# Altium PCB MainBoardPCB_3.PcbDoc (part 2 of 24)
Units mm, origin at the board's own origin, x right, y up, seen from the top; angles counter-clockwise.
Board outline 258.95 x 308.86 mm, 16 copper layers (L1, L2 (GND), L3 (Sign), L4 (GND), L5 (Sign), L6 (PWR/GND), L7(PWR/GND), L8 (Plane_GND), L9 (PWR/GND), L10 (PWR/GND), L11 (PWR/GND), L12 (Sign), L13 (GND), L14 (Sign), L15 (GND), L16), stack 2.502 mm thick; 2402 components, 1749 nets, 8407 pads, 3409 vias.
Unrouted connection lines stored in the file: 4352.

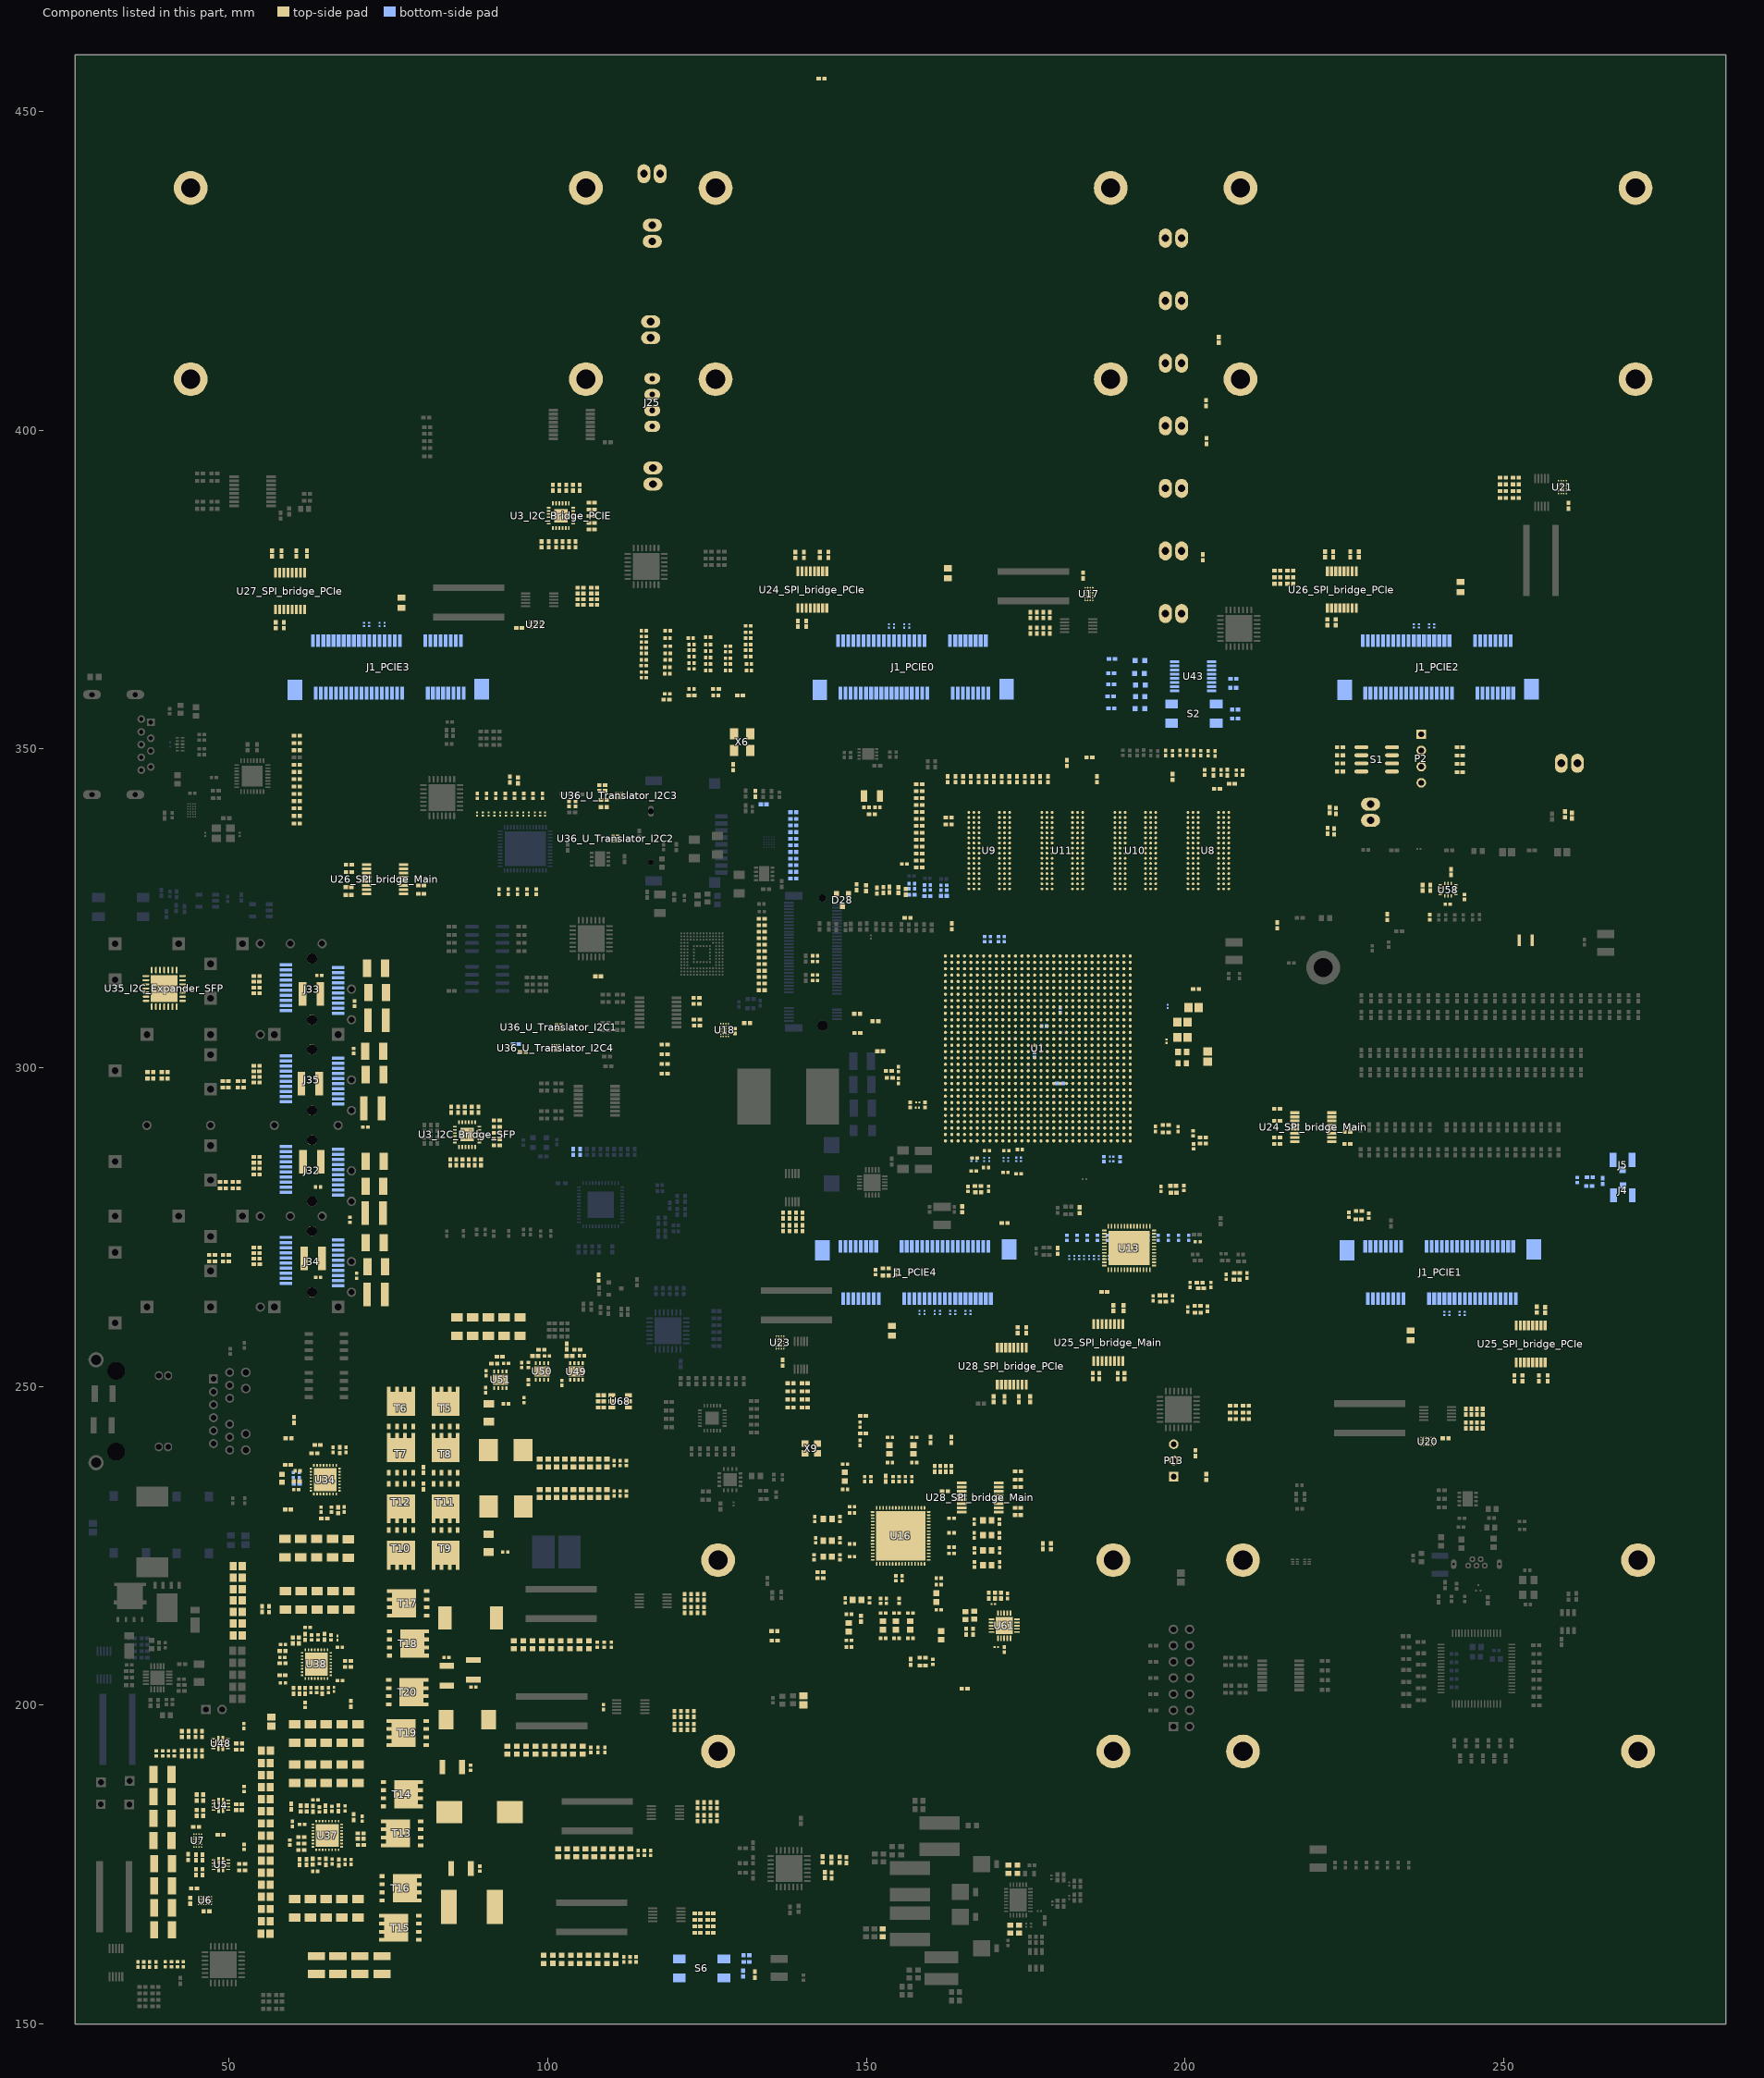
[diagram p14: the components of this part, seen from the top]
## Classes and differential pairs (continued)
net class Single_50: Bank505_MGTRREF0_C_N Bank505_MGTRREF0_C_P Bank505_MGTRREF2_C_N Bank505_MGTRREF2_C_P Bank505_MGTRREF3_C_N Bank505_MGTRREF3_C_P CLK_M_OSC_In CLK_SMA0_C_N CLK_SMA0_C_P LTC6952_0_MATCH_Out0_N LTC6952_0_MATCH_Out0_P LTC6952_0_MATCH_Out1_N LTC6952_0_MATCH_Out1_P LTC6952_0_MATCH_Out2_N LTC6952_0_MATCH_Out2_P LTC6952_0_MATCH_Out3_N LTC6952_0_MATCH_Out3_P LTC6952_0_MATCH_Out4_N LTC6952_0_MATCH_Out4_P LTC6952_0_MATCH_Out5_N LTC6952_0_MATCH_Out5_P LTC6952_0_MATCH_Out6_N LTC6952_0_MATCH_Out6_P LTC6952_0_MATCH_Out7_N LTC6952_0_MATCH_Out7_P LTC6952_0_MATCH_Out8_N LTC6952_0_MATCH_Out8_P LTC6952_0_MATCH_Out9_N LTC6952_0_MATCH_Out9_P LTC6952_0_Out0_N LTC6952_0_Out0_P LTC6952_0_Out1_N LTC6952_0_Out1_P LTC6952_0_Out2_N LTC6952_0_Out2_P LTC6952_0_Out6_N LTC6952_0_Out6_P LTC6952_0_Out7_N LTC6952_0_Out7_P LTC6952_0_Out8_N LTC6952_0_Out8_P LTC6952_0_Out9_N LTC6952_0_Out9_P LTC6952_0_Out10_N LTC6952_0_Out10_P LTC6952_0_REF_N LTC6952_0_REF_P LTC6952_1_C_N LTC6952_1_C_Out10_N LTC6952_1_C_Out10_P LTC6952_1_C_P LTC6952_1_MATCH_Out0_N LTC6952_1_MATCH_Out0_P LTC6952_1_MATCH_Out1_N LTC6952_1_MATCH_Out1_P LTC6952_1_MATCH_Out2_N LTC6952_1_MATCH_Out2_P LTC6952_1_MATCH_Out3_N LTC6952_1_MATCH_Out3_P LTC6952_1_MATCH_Out4_N LTC6952_1_MATCH_Out4_P LTC6952_1_MATCH_Out5_N LTC6952_1_MATCH_Out5_P LTC6952_1_MATCH_Out6_N LTC6952_1_MATCH_Out6_P LTC6952_1_MATCH_Out7_N LTC6952_1_MATCH_Out7_P LTC6952_1_MATCH_Out8_N LTC6952_1_MATCH_Out8_P LTC6952_1_MATCH_Out9_N LTC6952_1_MATCH_Out9_P LTC6952_1_Out0_N LTC6952_1_Out0_P LTC6952_1_Out1_N LTC6952_1_Out1_P LTC6952_1_Out2_N LTC6952_1_Out2_P LTC6952_1_Out4_N LTC6952_1_Out4_P LTC6952_1_Out5_N LTC6952_1_Out5_P LTC6952_1_Out6_N LTC6952_1_Out6_P LTC6952_1_Out7_N LTC6952_1_Out7_P LTC6952_1_Out8_N LTC6952_1_Out8_P LTC6952_1_Out9_N LTC6952_1_Out9_P LTC6952_1_Out10_N LTC6952_1_Out10_P LTC6952_1_REF_MATCH_N LTC6952_1_REF_MATCH_P LTC6952_1_VCO_N LTC6952_1_VCO_P NetC333_1 NetC334_1 NetC335_2 NetC341_1 NetC588_1 NetC588_2 NetR543_1 NVME_C_RX_1_N NVME_C_RX_1_P NVME_C_RX_O_N NVME_C_RX_O_P NVME_C_TX_1_N NVME_C_TX_1_P NVME_C_TX_O_N NVME_C_TX_O_P NVMe_Rx_0_N NVMe_Rx_0_P NVMe_Rx_1_N NVMe_Rx_1_P NVMe_Tx_0_N NVMe_Tx_0_P NVMe_Tx_1_N NVMe_Tx_1_P OSC_500Out Osc_in_Si53323_2_P OSC_Out_DIV_N OSC_Out_DIV_P RefClk_Si53323_P SGMI_C_Rx_N SGMI_C_Rx_P SGMI_C_Tx_N SGMI_C_Tx_P SGMI_CLK_Out_N SGMI_CLK_Out_P SGMI_Rx_N SGMI_Rx_P SGMI_Tx_N SGMI_Tx_P Si53323_1_Q1_N Si53323_1_Q2_LVDS_N Si53323_1_Q2_LVDS_P Si53323_1_Q2_N Si53323_1_Q2_P Si53323_2_CLK1_N Si53323_2_CLK1_P Si53323_2_Q1_N Si53323_2_Q1_P Si53323_2_Q2_LVDS_N Si53323_2_Q2_LVDS_P Si53323_2_Q2_N Si53323_2_Q2_P TD_A_N TD_A_P TD_B_N TD_B_P TD_C_N TD_C_P TD_D_N TD_D_P WR_LMK_CLK_HF1_N WR_LMK_CLK_HF1_P WR_LMK_CLK_HF2_N WR_LMK_CLK_HF2_P WR_LMK_CLK_IN_N WR_LMK_CLK_IN_P WR_LMK_CLK_RC_HF1_N WR_LMK_CLK_RC_HF1_P WR_LMK_CLK_RC_HF2_N WR_LMK_CLK_RC_HF2_P XO_LMK05028_P
net class Bank505_MGTRREFx_C: Bank505_MGTRREF0_C_N Bank505_MGTRREF0_C_P Bank505_MGTRREF2_C_N Bank505_MGTRREF2_C_P Bank505_MGTRREF3_C_N Bank505_MGTRREF3_C_P NetU2_L25 NetU2_L26
net class Bank225_MGTREFx_C: Bank225_MGTREF0_C_N Bank225_MGTREF0_C_P Bank225_MGTREF1_C_N Bank225_MGTREF1_C_P
net class Bank224_MGTREFx_C: Bank224_MGTREF0_C_N Bank224_MGTREF0_C_P Bank224_MGTREF1_C_N Bank224_MGTREF1_C_P
net class Bank223_MGTREFx_C: Bank223_MGTREF0_C_N Bank223_MGTREF0_C_P Bank223_MGTREF1_C_N Bank223_MGTREF1_C_P
component class U_Translator_I2C4: TP60_U_Translator_I2C4 TP61_U_Translator_I2C4 U36_U_Translator_I2C4
differential pair class Diff_100: B223_Rx0 B223_Rx1 B223_Rx2 B223_Rx3 B223_Tx0_to_C B223_Tx0C_to_B B223_Tx1_to_C B223_Tx1C_to_B B223_Tx2_to_C B223_Tx2C_to_B B223_Tx3_to_C B223_Tx3C_to_B B224_Rx0 B224_Rx1 B224_Rx2 B224_Rx3 B224_Tx0_to_C B224_Tx0C_to_B B224_Tx1_to_C B224_Tx1C_to_B B224_Tx2_to_C B224_Tx2C_to_B B224_Tx3_to_C B224_Tx3C_to_B B225_Rx0 B225_Rx1 B225_Rx2 B225_Rx3 B225_Tx0_to_C B225_Tx0C_to_B B225_Tx1_to_C B225_Tx1C_to_B B225_Tx2_to_C B225_Tx2C_to_B B225_Tx3_to_C B225_Tx3C_to_B Bank223_MGTREF0 Bank223_MGTREF0_C Bank223_MGTREF1 Bank223_MGTREF1_C Bank224_MGTREF0 Bank224_MGTREF0_C Bank224_MGTREF1 Bank224_MGTREF1_C Bank225_MGTREF0 Bank225_MGTREF0_C Bank225_MGTREF1 Bank225_MGTREF1_C Bank505_MGTRREF0_C Bank505_MGTRREF2_C Bank505_MGTRREF3_C CLK_100 CLK_Fanout_In CLK_GTR_T1 CLK_GTR_T2 CLK_GTR_T3 CLK_Hi_Rail1 CLK_Hi_Rail1_SysRef CLK_Hi_Rail2 CLK_Hi_Rail2_SysRef CLK_M_OSC_In CLK_NVME_Conn CLK_Q223_T1 CLK_Q224_T1 CLK_Q225_T1 CLK_Q226_T1 CLK_SMA0 CLK_SMA0_C CLK_SMA1 CLK_SMA1_C CLK_SMA2 CLK_SMA2_C Data_2_RX_PCIE0 Data_2_RX_PCIE1 Data_2_RX_PCIE2 Data_2_RX_PCIE3 Data_2_TX_PCIE0 Data_2_TX_PCIE1 Data_2_TX_PCIE2 Data_2_TX_PCIE3 Data_3_RX_PCIE0 Data_3_RX_PCIE1 Data_3_RX_PCIE2 Data_3_RX_PCIE3 Data_3_TX_PCIE0 Data_3_TX_PCIE1 Data_3_TX_PCIE2 Data_3_TX_PCIE3 LTC6952_0_MATCH_Out0 LTC6952_0_MATCH_Out1 LTC6952_0_MATCH_Out2 LTC6952_0_MATCH_Out3 LTC6952_0_MATCH_Out4 LTC6952_0_MATCH_Out5 LTC6952_0_MATCH_Out6 LTC6952_0_MATCH_Out7 LTC6952_0_MATCH_Out8 LTC6952_0_MATCH_Out9 LTC6952_0_Out0 LTC6952_0_Out1 LTC6952_0_Out2 LTC6952_0_Out3 LTC6952_0_Out4 LTC6952_0_Out5 LTC6952_0_Out6 LTC6952_0_Out7 LTC6952_0_Out8 LTC6952_0_Out9 LTC6952_0_Out10 LTC6952_0_REF LTC6952_0_REF_MATCH LTC6952_1_C LTC6952_1_C_Out10 LTC6952_1_MATCH_Out0 LTC6952_1_MATCH_Out1 LTC6952_1_MATCH_Out2 LTC6952_1_MATCH_Out3 LTC6952_1_MATCH_Out4 LTC6952_1_MATCH_Out5 LTC6952_1_MATCH_Out6 LTC6952_1_MATCH_Out7 LTC6952_1_MATCH_Out8 LTC6952_1_MATCH_Out9 LTC6952_1_Out0 LTC6952_1_Out1 LTC6952_1_Out2 LTC6952_1_Out3 LTC6952_1_Out4 LTC6952_1_Out5 LTC6952_1_Out6 LTC6952_1_Out7 LTC6952_1_Out8 LTC6952_1_Out9 LTC6952_1_Out10 LTC6952_1_REF LTC6952_1_REF_MATCH LTC6952_1_VCO LTC6952_2_REF LTC6952_2_REF_SMA LTC6952_3_REF LTC6952_3_REF_SMA NVME_C_RX_1 NVME_C_RX_O NVME_C_TX_1 NVME_C_TX_O NVMe_CLK NVMe_Rx_0 NVMe_Rx_1 NVMe_Tx_0 NVMe_Tx_1 Osc_in_Si53323_2 OSC_Out_DIV PCIE0_CLK PCIE0_Sync PCIE0_SysRef PCIE0_SysRef_FPGA PCIE1_CLK PCIE1_Sync PCIE1_SysRef PCIE1_SysRef_FPGA PCIE2_CLK PCIE2_Sync PCIE2_SysRef PCIE2_SysRef_FPGA PCIE3_CLK PCIE3_Sync PCIE3_SysRef PCIE3_SysRef_FPGA PCIE4_CLK PCIE4_Sync PCIE4_SysRef PCIE4_SysRef_FPGA RefClk_Si53323 SFP0_Rx SFP0_Tx SFP1_Rx SFP1_Tx SFP2_Rx SFP2_Tx SFP3_Rx SFP3_Tx SGMI_C_Rx SGMI_C_Tx SGMI_CLK_C_Out SGMI_CLK_Out SGMI_Rx SGMI_Tx Si53323_1_Q1 Si53323_1_Q2 Si53323_1_Q2_LVDS Si53323_2_CLK1 Si53323_2_Q1 Si53323_2_Q2 Si53323_2_Q2_LVDS SYNC_PCIE0 SYNC_PCIE1 SYNC_PCIE2 SYNC_PCIE3 SYNC_PCIE4 SYSREF_PCIE0 SYSREF_PCIE1 SYSREF_PCIE2 SYSREF_PCIE3 SYSREF_PCIE4 TD_A TD_B TD_C TD_D WR_LMK_CLK_HF1 WR_LMK_CLK_HF2 WR_LMK_CLK_IN WR_LMK_CLK_RC_HF1 WR_LMK_CLK_RC_HF2 WR_LMK_CLK_RC_IN WR_Source_CLK
channel class Translator_I2C: U_Translator_I2C1 U_Translator_I2C2 U_Translator_I2C3
channel class 5V_to_3V3: 5V_to_3V3_for_FTDI U_5V_to_3V32 U_5V_to_3V33
net class SFP_diff: SFP0_Rx_N SFP0_Rx_P SFP0_Tx_N SFP0_Tx_P SFP1_Rx_N SFP1_Rx_P SFP1_Tx_N SFP1_Tx_P SFP2_Rx_N SFP2_Rx_P SFP2_Tx_N SFP2_Tx_P SFP3_Rx_N SFP3_Rx_P SFP3_Tx_N SFP3_Tx_P
net class C_to_Bank225: B225_Rx0_N B225_Rx0_P B225_Rx1_N B225_Rx1_P B225_Rx2_N B225_Rx2_P B225_Rx3_N B225_Rx3_P B225_Tx0C_to_B_N B225_Tx0C_to_B_P B225_Tx1C_to_B_N B225_Tx1C_to_B_P B225_Tx2C_to_B_N B225_Tx2C_to_B_P B225_Tx3C_to_B_N B225_Tx3C_to_B_P
net class C_to_Bank224: B224_Tx0C_to_B_N B224_Tx0C_to_B_P B224_Tx1C_to_B_N B224_Tx1C_to_B_P B224_Tx2C_to_B_N B224_Tx2C_to_B_P B224_Tx3C_to_B_N B224_Tx3C_to_B_P
net class C_to_Bank223: B223_Rx0_N B223_Rx0_P B223_Rx1_N B223_Rx1_P B223_Rx2_N B223_Rx2_P B223_Rx3_N B223_Rx3_P B223_Tx0C_to_B_N B223_Tx0C_to_B_P B223_Tx1C_to_B_N B223_Tx1C_to_B_P B223_Tx2C_to_B_N B223_Tx2C_to_B_P B223_Tx3C_to_B_N B223_Tx3C_to_B_P
component class U_Translator_I2C3: TP60_U_Translator_I2C3 TP61_U_Translator_I2C3 U36_U_Translator_I2C3
component class U_Translator_I2C2: TP60_U_Translator_I2C2 TP61_U_Translator_I2C2 U36_U_Translator_I2C2
component class U_Translator_I2C1: TP60_U_Translator_I2C1 TP61_U_Translator_I2C1 U36_U_Translator_I2C1
component class U_TPS7A88_5V_Dual_3: C572 C573 C574 C575 C576 C577 C578 C579 R436 R437 R438 R439 R440 R441 U61
component class U_LT3042_12V_5V_LNLDO: C580 C581 C582 C583 C584 FB34 R442 R443 R444 R445 U62
component class U_ADP1741_3: C568 C569 C570 C571 FB33 R433 R434 U60
component class U_5V_to_3V33: C563_U_5V_to_3V33 C564_U_5V_to_3V33 C565_U_5V_to_3V33 C566_U_5V_to_3V33 C567_U_5V_to_3V33 R430_U_5V_to_3V33 R431_U_5V_to_3V33 R432_U_5V_to_3V33 U59_U_5V_to_3V33
component class U_5V_to_3V32: C563_U_5V_to_3V32 C564_U_5V_to_3V32 C565_U_5V_to_3V32 C566_U_5V_to_3V32 C567_U_5V_to_3V32 R430_U_5V_to_3V32 R431_U_5V_to_3V32 R432_U_5V_to_3V32 U59_U_5V_to_3V32
component class Ram_Power: C219 C220 C221 C222 C223 C224 C225 C226 C227 C228 C229 C230 C231 C232 C233 C234 C235 C236 C237 C238 C239 C240 C241 C242 C243 C244 C245 C246 C247 C248 C249 C250 C251 C252 C253 C254 C255 C256 C257 C258 C259 C260 C261 C262 C263 C264 C265 C266 C782 C783 C784 C785 C786 C787 C788 C789 R165 R166 R167 R168 R169 R170 R171 R172
component class PS_Config: C531 C532 C533 C534 C535 C536 D5 D6 D7 D8 D9 D10 D11 D12 P2 P3 P4 P5 R346 R347 R348 R349 R350 R351 R352 R353 R354 R355 R356 R357 R358 R359 R360 R361 R367 R368 R369 R370 R371 R372 R373 R374 R375 R716 R717 R718 R719 R720 S1 S2 S3 S4 U43 U44 X5 X6
component class IMU: C561 C562 R429 R600 R601 U58
component class GTR: C525 C526 C527 C528 C529 C530 C649 C651 C653 C677 C715 C716 C717 C718 R69 R70 R126
component class "Bank 225": C291 C292 C293 C294 C295 C296 C297 C298 C299 C300 C301 C302 C819 C820 C821 C822
component class "Bank 224": C279 C280 C281 C282 C283 C284 C285 C286 C287 C288 C289 C290 C686 C687 C688 C689
component class "Bank 223": C49 C50 C267 C268 C269 C270 C271 C272 C273 C274 C275 C276 C277 C278 C477 C557
component class U_Power_Ethernet: C550 C551 C552 C553 C554 C555 C654 C655 C656 C657 R391 R392 R393 R394 R396 R397 R399 R632 R633 R634 U49 U50 U51 U68
component class U_Power_ADP1850_Dual_2: C430 C431 C432 C433 C434 C435 C436 C437 C438 C439 C440 C441 C442 C443 C444 C445 C446 C447 C448 C449 C450 C451 C452 C453 C454 C455 C456 C457 C458 C459 C460 C461 C462 C463 C464 C465 C466 C467 C468 C469 C470 C548 C549 C645 C646 C647 C648 C650 C652 L19 L20 R302 R303 R306 R307 R310 R312 R313 R314 R315 R316 R317 R318 R625 R626 R627 R628 R629 R631 R686 R687 T17 T18 T19 T20 U38
component class U_HI_Curr_ADP1850_3: C389 C390 C391 C392 C393 C394 C395 C396 C397 C398 C399 C400 C401 C402 C403 C404 C405 C406 C407 C408 C409 C410 C411 C412 C413 C414 C415 C416 C417 C418 C419 C420 C421 C422 C423 C424 C425 C426 C427 C428 C429 C637 C638 C639 C640 C641 C642 C643 C644 L11 L12 R285 R287 R288 R289 R290 R292 R293 R294 R295 R296 R297 R298 R299 R300 R619 R620 R621 R622 R623 R624 T13 T14 T15 T16 U37
component class "Zasilanie CLK": C55 C56 C57 C58 C59 C60 C61 C62 C63 C64 C65 C66 C67 C68 C69 C70 C71 C72 C73 C74 C75 C76 C77 C78 C79 C80 C81 C82 C83 C84 C85 C86 C87 C88 C89 C90 C91 C92 C93 C94 C95 C96 C97 C98 C99 C100 C101 C102 C103 C104 C105 C106 C107 C108 C109 C110 C124 C125 C126 C127 C141 C142 C143 C144 C145 C146 C147 C148 C149 C150 C151 C152 C153 C154 C155 C156 C157 C158 C159 C160 C161 C162 C163 C164 C165 C166 C167 C168 C169 C170 C171 C172 C173 C174 C175 C176 C177 C178 C179 C180 C181 C182 C183 C184 C185 C186 C187 C188 C189 C190 C191 C192 C193 C194 C195 C196 C197 C198 C199 C200 C201 C202 C203 C204 C205 C206 FB2 FB3 FB4 FB5 FB6 FB7 FB8 FB9 FB10 FB11 FB12 FB13 FB14 FB15 FB16 FB17 FB18 FB19 FB20 FB21 FB22 FB35 FB36 R738 R739 R740 R741 R742 R743 U16
component class PowerSelector: C4 C5 C6 C7 C8 C9 C10 C11 C12 C13 C14 C15 C16 C17 C18 C19 C20 C21 C22 C23 C24 C25 C26 C27 C28 C29 C30 C31 C32 C33 C34 C35 C312 C313 C314 C766 C767 C768 C769 C770 C771 C772 C773 C774 C775 C776 C777 C778 C779 C780 C781 R11 R12 R13 R15 R17 R18 R19 R20 R21 R23 R25 R26 R27 R28 R29 R30 R630 R677 R678 R679 R680 R681 R682 R683 R684 R685 R1052 R1053 U4 U5 U6 U7 U48
channel class SPI_Muxes: SPI_bridge_Main SPI_bridge_PCIe
channel class I2C_Expander: I2C_Expander4 I2C_Expander5
component class XilinxPower: B1 C627 C628 C629 C630 C631 C632 D28 FB38 FB39 FB40 FB41 FB42 J29 J30 R173 R276 R279 R282 R283 R286 R693 R694 R695 R696
component class "Xilinx Linux": J12 J13 J14 J15 J16 J17 J18 J19 J20 J21 J22 J23 J24 J25 P1 P13 R83 R84 R85 R86 R87 R88 R89 R90 R91 R92 R93 R94 R95 R96 R97 R98 R99 R101 R102 R103 R104 R105 R106 R107 R108 R109 R110 R111 R112 R115 R116 R117 R118 R119 R120 R121 R122 R123 R362 R675 R737 R768 R769 R770 R771 R772 R773 R774 R775 R776 R777 R778 R779 R780 R781 R782 R783 R784 R785 R786 R787 R788 R789 R790 R791 R792 R793 R794 R795 R796 R797 R798 R799 R800 R801 R802 R803 R804 R805 R806 R807 R808 R809 R810 R811 R812 R813 R814 R815 R816 TP21 TP22 TP23 TP24 TP25 TP26 TP27 TP28 TP29 TP30 TP31 TP32 TP33 TP34 TP35 TP36 TP37 TP38 TP39 TP40 TP41 TP42
component class "WR CLK": C588 C589 C590 C591 C592 C690 C728 C729 C730 C793 FB37 R1 R2 R127 R128 R129 R130 R131 R132 R133 R134 R139 R311 R366 R498 R499 R540 R543 R544 R545 R692 R912 R1083 R1084 R1085 R1086 R1087 R1088 S6 X9
component class U_HI_Curr_ADP1850_1: C345 C346 C347 C348 C349 C350 C351 C352 C353 C356 C357 C358 C359 C360 C361 C362 C363 C364 C365 C366 C367 C368 C369 C370 C371 C372 C373 C374 C375 C376 C377 C378 C379 C380 C381 C382 C383 C384 C385 C386 C387 C388 C633 C634 C635 C636 L9 L10 R268 R271 R272 R273 R275 R277 R278 R280 R610 R611 R612 R613 R614 R615 R616 T5 T6 T7 T8 T9 T10 T11 T12 U34
component class SPI_bridge_Main: R231_SPI_bridge_Main R232_SPI_bridge_Main R233_SPI_bridge_Main R234_SPI_bridge_Main R235_SPI_bridge_Main R236_SPI_bridge_Main R237_SPI_bridge_Main R238_SPI_bridge_Main R239_SPI_bridge_Main R240_SPI_bridge_Main R425_SPI_bridge_Main R426_SPI_bridge_Main R602_SPI_bridge_Main R603_SPI_bridge_Main R604_SPI_bridge_Main R605_SPI_bridge_Main R606_SPI_bridge_Main R887_SPI_bridge_Main R888_SPI_bridge_Main R889_SPI_bridge_Main R890_SPI_bridge_Main R891_SPI_bridge_Main R892_SPI_bridge_Main R893_SPI_bridge_Main R894_SPI_bridge_Main R895_SPI_bridge_Main R896_SPI_bridge_Main R897_SPI_bridge_Main R898_SPI_bridge_Main R899_SPI_bridge_Main TP50_SPI_bridge_Main TP51_SPI_bridge_Main TP52_SPI_bridge_Main TP53_SPI_bridge_Main TP54_SPI_bridge_Main TP55_SPI_bridge_Main TP56_SPI_bridge_Main TP57_SPI_bridge_Main TP58_SPI_bridge_Main TP59_SPI_bridge_Main U24_SPI_bridge_Main U25_SPI_bridge_Main U26_SPI_bridge_Main U27_SPI_bridge_Main U28_SPI_bridge_Main
component class SPI_bridge_PCIe: R231_SPI_bridge_PCIe R232_SPI_bridge_PCIe R233_SPI_bridge_PCIe R234_SPI_bridge_PCIe R235_SPI_bridge_PCIe R236_SPI_bridge_PCIe R237_SPI_bridge_PCIe R238_SPI_bridge_PCIe R239_SPI_bridge_PCIe R240_SPI_bridge_PCIe R425_SPI_bridge_PCIe R426_SPI_bridge_PCIe R602_SPI_bridge_PCIe R603_SPI_bridge_PCIe R604_SPI_bridge_PCIe R605_SPI_bridge_PCIe R606_SPI_bridge_PCIe R887_SPI_bridge_PCIe R888_SPI_bridge_PCIe R889_SPI_bridge_PCIe R890_SPI_bridge_PCIe R891_SPI_bridge_PCIe R892_SPI_bridge_PCIe R893_SPI_bridge_PCIe R894_SPI_bridge_PCIe R895_SPI_bridge_PCIe R896_SPI_bridge_PCIe R897_SPI_bridge_PCIe R898_SPI_bridge_PCIe R899_SPI_bridge_PCIe TP50_SPI_bridge_PCIe TP51_SPI_bridge_PCIe TP52_SPI_bridge_PCIe TP53_SPI_bridge_PCIe TP54_SPI_bridge_PCIe TP55_SPI_bridge_PCIe TP56_SPI_bridge_PCIe TP57_SPI_bridge_PCIe TP58_SPI_bridge_PCIe TP59_SPI_bridge_PCIe U24_SPI_bridge_PCIe U25_SPI_bridge_PCIe U26_SPI_bridge_PCIe U27_SPI_bridge_PCIe U28_SPI_bridge_PCIe
component class SFP3: C215 C216 C217 C218 J35 L7 L8 R155 R156 R157 R158 R161 R162 R163 R164
component class SFP2: C211 C212 C213 C214 J34 L5 L6 R145 R146 R147 R148 R151 R152 R153 R154
component class SFP1: C207 C208 C209 C210 J33 L3 L4 R135 R136 R137 R138 R141 R142 R143 R144
component class Ram: C36 R31 R32 R33 R34 R35 R36 R37 R38 R39 R40 R41 R42 R43 R44 R45 R46 R47 R48 R49 R50 R51 R52 R53 R54 R55 R56 R57 R58 R59 R60 R61 R62 R63 R64 R920 U8 U9 U10 U11
component class Power4HighSpeed: R174 R175 R176 R177 R178 R179 R180 R181 R182 R183 R184 R185 R186 R187 R188 R189 R190 R191 R192 R193 R194 R195 R196 R197 R198 R199 R200 R201 R202 R203 R204 R205 R206 R207 R208 R209 R210 R211 R213 R215 R217 R219 R221 R222 R228 U17 U20 U21 U22 U23
component class I2C_Expander_SFP: C311_I2C_Expander_SFP U35_I2C_Expander_SFP
component class Ext_GPIO_Bank1: R516 R517 R518 R519 R520 R521 R524 R525 R526 R527 R528 R529 R697 R698 R699 R700 R701 R702
component class HiCurrent: C331 C332 R14 R16 R22 R24 R266 R267 R269 R304 R388 R389 R390 R561 R562 R563 R564 R565 R566 R567 R568 R569 R570 R571 R572 R573 R574 R575 R576 R577 R578 R579 R580 R581 R582 R583 R584 R585 R586 R587 R588 R589 R590 R591 R592 S5 U18
component class PCIE4: D1_PCIE4 F1_PCIE4 J1_PCIE4 MP1_PCIE4 MP2_PCIE4 MP3_PCIE4 MP4_PCIE4
component class PCIE3: D1_PCIE3 F1_PCIE3 J1_PCIE3 MP1_PCIE3 MP2_PCIE3 MP3_PCIE3 MP4_PCIE3
component class PCIE2: D1_PCIE2 F1_PCIE2 J1_PCIE2 MP1_PCIE2 MP2_PCIE2 MP3_PCIE2 MP4_PCIE2
component class PCIE1: D1_PCIE1 F1_PCIE1 J1_PCIE1 MP1_PCIE1 MP2_PCIE1 MP3_PCIE1 MP4_PCIE1
component class PCIE0: D1_PCIE0 F1_PCIE0 J1_PCIE0 MP1_PCIE0 MP2_PCIE0 MP3_PCIE0 MP4_PCIE0
component class LTC6952_1: C51 C52 C796 C797 C798 C799 C800 C801 C802 C805 C806 C807 C808 C811 C812 C813 C814 C815 C816 C817 C818 J4 J5 J6 J7 R270 R534 R535 R536 R1077 R1080 R1089 R1090 R1091 R1092 R1093 R1094 R1097 R1098 R1100 R1101 R1103 R1104 R1105 R1106 R1107 R1108 R1109 R1110 U13
channel class PCIe: PCIE0 PCIE1 PCIE2 PCIE3 PCIE4
channel class I2C_Bridge: I2C_Bridge_PCIE I2C_Bridge_SFP
component class "Bank 226": U1
component class SFP0: C37 C38 C39 C40 J32 L1 L2 R65 R66 R67 R68 R71 R72 R73 R74
component class I2C_Bridge_SFP: C303_I2C_Bridge_SFP R3_I2C_Bridge_SFP R4_I2C_Bridge_SFP R5_I2C_Bridge_SFP R6_I2C_Bridge_SFP R7_I2C_Bridge_SFP R8_I2C_Bridge_SFP R9_I2C_Bridge_SFP R10_I2C_Bridge_SFP R223_I2C_Bridge_SFP R224_I2C_Bridge_SFP R225_I2C_Bridge_SFP R226_I2C_Bridge_SFP R227_I2C_Bridge_SFP R558_I2C_Bridge_SFP R559_I2C_Bridge_SFP R560_I2C_Bridge_SFP TP1_I2C_Bridge_SFP TP2_I2C_Bridge_SFP TP3_I2C_Bridge_SFP TP4_I2C_Bridge_SFP TP5_I2C_Bridge_SFP TP6_I2C_Bridge_SFP TP7_I2C_Bridge_SFP TP8_I2C_Bridge_SFP TP9_I2C_Bridge_SFP TP10_I2C_Bridge_SFP TP11_I2C_Bridge_SFP TP12_I2C_Bridge_SFP TP13_I2C_Bridge_SFP TP14_I2C_Bridge_SFP TP15_I2C_Bridge_SFP TP16_I2C_Bridge_SFP TP17_I2C_Bridge_SFP TP18_I2C_Bridge_SFP U3_I2C_Bridge_SFP
component class I2C_Bridge_PCIE: C303_I2C_Bridge_PCIE R3_I2C_Bridge_PCIE R4_I2C_Bridge_PCIE R5_I2C_Bridge_PCIE R6_I2C_Bridge_PCIE R7_I2C_Bridge_PCIE R8_I2C_Bridge_PCIE R9_I2C_Bridge_PCIE R10_I2C_Bridge_PCIE R223_I2C_Bridge_PCIE R224_I2C_Bridge_PCIE R225_I2C_Bridge_PCIE R226_I2C_Bridge_PCIE R227_I2C_Bridge_PCIE R558_I2C_Bridge_PCIE R559_I2C_Bridge_PCIE R560_I2C_Bridge_PCIE TP1_I2C_Bridge_PCIE TP2_I2C_Bridge_PCIE TP3_I2C_Bridge_PCIE TP4_I2C_Bridge_PCIE TP5_I2C_Bridge_PCIE TP6_I2C_Bridge_PCIE TP7_I2C_Bridge_PCIE TP8_I2C_Bridge_PCIE TP9_I2C_Bridge_PCIE TP10_I2C_Bridge_PCIE TP11_I2C_Bridge_PCIE TP12_I2C_Bridge_PCIE TP13_I2C_Bridge_PCIE TP14_I2C_Bridge_PCIE TP15_I2C_Bridge_PCIE TP16_I2C_Bridge_PCIE TP17_I2C_Bridge_PCIE TP18_I2C_Bridge_PCIE U3_I2C_Bridge_PCIE
differential pair WR_LMK_CLK_RC_HF2: +WR_LMK_CLK_RC_HF2_P -WR_LMK_CLK_RC_HF2_N
differential pair Bank223_MGTREF0: +Bank223_MGTREF0_P -Bank223_MGTREF0_N
differential pair WR_LMK_CLK_RC_HF1: +WR_LMK_CLK_RC_HF1_P -WR_LMK_CLK_RC_HF1_N
differential pair LTC6952_1_MATCH_Out6: +LTC6952_1_MATCH_Out6_P -LTC6952_1_MATCH_Out6_N
differential pair SGMI_CLK_Out: +SGMI_CLK_Out_P -SGMI_CLK_Out_N
differential pair LTC6952_1_REF_MATCH: +LTC6952_1_REF_MATCH_P -LTC6952_1_REF_MATCH_N
differential pair LTC6952_1_MATCH_Out9: +LTC6952_1_MATCH_Out9_P -LTC6952_1_MATCH_Out9_N
differential pair LTC6952_1_MATCH_Out8: +LTC6952_1_MATCH_Out8_P -LTC6952_1_MATCH_Out8_N
differential pair LTC6952_1_MATCH_Out7: +LTC6952_1_MATCH_Out7_P -LTC6952_1_MATCH_Out7_N
differential pair LTC6952_1_MATCH_Out5: +LTC6952_1_MATCH_Out5_P -LTC6952_1_MATCH_Out5_N
differential pair LTC6952_1_MATCH_Out4: +LTC6952_1_MATCH_Out4_P -LTC6952_1_MATCH_Out4_N
differential pair LTC6952_1_MATCH_Out3: +LTC6952_1_MATCH_Out3_P -LTC6952_1_MATCH_Out3_N
differential pair LTC6952_1_MATCH_Out2: +LTC6952_1_MATCH_Out2_P -LTC6952_1_MATCH_Out2_N
differential pair LTC6952_1_MATCH_Out1: +LTC6952_1_MATCH_Out1_P -LTC6952_1_MATCH_Out1_N
differential pair LTC6952_1_MATCH_Out0: +LTC6952_1_MATCH_Out0_P -LTC6952_1_MATCH_Out0_N
differential pair LTC6952_0_MATCH_Out9: +LTC6952_0_MATCH_Out9_P -LTC6952_0_MATCH_Out9_N
differential pair LTC6952_0_MATCH_Out8: +LTC6952_0_MATCH_Out8_P -LTC6952_0_MATCH_Out8_N
differential pair LTC6952_0_MATCH_Out7: +LTC6952_0_MATCH_Out7_P -LTC6952_0_MATCH_Out7_N
differential pair LTC6952_0_MATCH_Out6: +LTC6952_0_MATCH_Out6_P -LTC6952_0_MATCH_Out6_N
differential pair LTC6952_0_MATCH_Out5: +LTC6952_0_MATCH_Out5_P -LTC6952_0_MATCH_Out5_N
differential pair LTC6952_0_MATCH_Out4: +LTC6952_0_MATCH_Out4_P -LTC6952_0_MATCH_Out4_N
differential pair LTC6952_0_MATCH_Out3: +LTC6952_0_MATCH_Out3_P -LTC6952_0_MATCH_Out3_N
differential pair LTC6952_0_MATCH_Out2: +LTC6952_0_MATCH_Out2_P -LTC6952_0_MATCH_Out2_N
differential pair LTC6952_0_MATCH_Out1: +LTC6952_0_MATCH_Out1_P -LTC6952_0_MATCH_Out1_N
differential pair LTC6952_0_MATCH_Out0: +LTC6952_0_MATCH_Out0_P -LTC6952_0_MATCH_Out0_N
differential pair Bank225_MGTREF1: +Bank225_MGTREF1_P -Bank225_MGTREF1_N
differential pair Bank225_MGTREF0: +Bank225_MGTREF0_P -Bank225_MGTREF0_N
differential pair Bank224_MGTREF1: +Bank224_MGTREF1_P -Bank224_MGTREF1_N
differential pair Bank224_MGTREF0: +Bank224_MGTREF0_P -Bank224_MGTREF0_N
differential pair Bank223_MGTREF1: +Bank223_MGTREF1_P -Bank223_MGTREF1_N
differential pair B225_Tx3_to_C: +B225_Tx3_to_C_P -B225_Tx3_to_C_N
differential pair B225_Tx2_to_C: +B225_Tx2_to_C_P -B225_Tx2_to_C_N
differential pair B225_Tx1_to_C: +B225_Tx1_to_C_P -B225_Tx1_to_C_N
differential pair B225_Tx0_to_C: +B225_Tx0_to_C_P -B225_Tx0_to_C_N
differential pair B225_Rx3: +B225_Rx3_P -B225_Rx3_N
differential pair B225_Rx2: +B225_Rx2_P -B225_Rx2_N
differential pair B225_Rx1: +B225_Rx1_P -B225_Rx1_N
differential pair B225_Rx0: +B225_Rx0_P -B225_Rx0_N
differential pair B224_Tx3_to_C: +B224_Tx3_to_C_P -B224_Tx3_to_C_N
differential pair B224_Tx2_to_C: +B224_Tx2_to_C_P -B224_Tx2_to_C_N
differential pair B224_Tx1_to_C: +B224_Tx1_to_C_P -B224_Tx1_to_C_N
differential pair B224_Tx0_to_C: +B224_Tx0_to_C_P -B224_Tx0_to_C_N
differential pair B224_Rx3: +B224_Rx3_P -B224_Rx3_N
differential pair B224_Rx2: +B224_Rx2_P -B224_Rx2_N
differential pair B224_Rx1: +B224_Rx1_P -B224_Rx1_N
differential pair B224_Rx0: +B224_Rx0_P -B224_Rx0_N
differential pair B223_Tx3_to_C: +B223_Tx3_to_C_P -B223_Tx3_to_C_N
differential pair B223_Tx2_to_C: +B223_Tx2_to_C_P -B223_Tx2_to_C_N
differential pair B223_Tx1_to_C: +B223_Tx1_to_C_P -B223_Tx1_to_C_N
differential pair B223_Tx0_to_C: +B223_Tx0_to_C_P -B223_Tx0_to_C_N
differential pair B223_Rx3: +B223_Rx3_P -B223_Rx3_N
differential pair B223_Rx2: +B223_Rx2_P -B223_Rx2_N
differential pair B223_Rx1: +B223_Rx1_P -B223_Rx1_N
differential pair B223_Rx0: +B223_Rx0_P -B223_Rx0_N
differential pair NVME_C_RX_1: +NVME_C_RX_1_P -NVME_C_RX_1_N
differential pair LTC6952_1_VCO: +LTC6952_1_VCO_P -LTC6952_1_VCO_N
differential pair LTC6952_1_Out10: +LTC6952_1_Out10_P -LTC6952_1_Out10_N
differential pair LTC6952_1_Out9: +LTC6952_1_Out9_P -LTC6952_1_Out9_N
differential pair LTC6952_1_Out8: +LTC6952_1_Out8_P -LTC6952_1_Out8_N
differential pair LTC6952_1_Out7: +LTC6952_1_Out7_P -LTC6952_1_Out7_N
differential pair LTC6952_1_Out6: +LTC6952_1_Out6_P -LTC6952_1_Out6_N
differential pair LTC6952_1_Out5: +LTC6952_1_Out5_P -LTC6952_1_Out5_N
differential pair LTC6952_1_Out4: +LTC6952_1_Out4_P -LTC6952_1_Out4_N
differential pair LTC6952_1_Out2: +LTC6952_1_Out2_P -LTC6952_1_Out2_N
differential pair LTC6952_1_Out1: +LTC6952_1_Out1_P -LTC6952_1_Out1_N
differential pair LTC6952_1_Out0: +LTC6952_1_Out0_P -LTC6952_1_Out0_N
differential pair LTC6952_1_C: +LTC6952_1_C_P -LTC6952_1_C_N
differential pair LTC6952_1_C_Out10: +LTC6952_1_C_Out10_P -LTC6952_1_C_Out10_N
differential pair LTC6952_0_REF: +LTC6952_0_REF_P -LTC6952_0_REF_N
differential pair LTC6952_0_Out10: +LTC6952_0_Out10_P -LTC6952_0_Out10_N
differential pair LTC6952_0_Out9: +LTC6952_0_Out9_P -LTC6952_0_Out9_N
differential pair LTC6952_0_Out8: +LTC6952_0_Out8_P -LTC6952_0_Out8_N
differential pair LTC6952_0_Out7: +LTC6952_0_Out7_P -LTC6952_0_Out7_N
differential pair LTC6952_0_Out6: +LTC6952_0_Out6_P -LTC6952_0_Out6_N
differential pair LTC6952_0_Out2: +LTC6952_0_Out2_P -LTC6952_0_Out2_N
differential pair LTC6952_0_Out1: +LTC6952_0_Out1_P -LTC6952_0_Out1_N
differential pair LTC6952_0_Out0: +LTC6952_0_Out0_P -LTC6952_0_Out0_N
differential pair USB_TX: +USB_TX_P -USB_TX_N
differential pair USB_TX_C: +USB_TX_C_P -USB_TX_C_N
differential pair USB_RX: +USB_RX_P -USB_RX_N
differential pair USB_RX_C: +USB_RX_C_P -USB_RX_C_N
differential pair USB_D: +USB_D_P -USB_D_N
differential pair TD_D: +TD_D_P -TD_D_N
differential pair TD_C: +TD_C_P -TD_C_N
differential pair TD_B: +TD_B_P -TD_B_N
differential pair TD_A: +TD_A_P -TD_A_N
differential pair SGMI_Tx: +SGMI_Tx_P -SGMI_Tx_N
differential pair SGMI_Rx: +SGMI_Rx_P -SGMI_Rx_N
differential pair SGMI_C_Tx: +SGMI_C_Tx_P -SGMI_C_Tx_N
differential pair SGMI_C_Rx: +SGMI_C_Rx_P -SGMI_C_Rx_N
differential pair NVMe_Tx_1: +NVMe_Tx_1_P -NVMe_Tx_1_N
differential pair NVMe_Tx_0: +NVMe_Tx_0_P -NVMe_Tx_0_N
differential pair NVMe_Rx_1: +NVMe_Rx_1_P -NVMe_Rx_1_N
differential pair NVMe_Rx_0: +NVMe_Rx_0_P -NVMe_Rx_0_N
differential pair DDR4_DQS_8: +DDR4_DQS_8_P -DDR4_DQS_8_N
differential pair DDR4_DQS_4: +DDR4_DQS_4_P -DDR4_DQS_4_N
differential pair NVME_C_TX_O: +NVME_C_TX_O_P -NVME_C_TX_O_N
differential pair NVME_C_TX_1: +NVME_C_TX_1_P -NVME_C_TX_1_N
differential pair NVME_C_RX_O: +NVME_C_RX_O_P -NVME_C_RX_O_N
differential pair WR_LMK_CLK_IN: +WR_LMK_CLK_IN_P -WR_LMK_CLK_IN_N
differential pair WR_LMK_CLK_HF2: +WR_LMK_CLK_HF2_P -WR_LMK_CLK_HF2_N
differential pair WR_LMK_CLK_HF1: +WR_LMK_CLK_HF1_P -WR_LMK_CLK_HF1_N
differential pair Si53323_2_Q2_LVDS: +Si53323_2_Q2_LVDS_P -Si53323_2_Q2_LVDS_N
differential pair Si53323_1_Q2_LVDS: +Si53323_1_Q2_LVDS_P -Si53323_1_Q2_LVDS_N
differential pair Si53323_2_CLK1: +Si53323_2_CLK1_P -Si53323_2_CLK1_N
differential pair OSC_Out_DIV: +OSC_Out_DIV_P -OSC_Out_DIV_N
differential pair Osc_in_Si53323_2: +Osc_in_Si53323_2_P -Osc_in_Si53323_2_N
differential pair CLK_SMA0_C: +CLK_SMA0_C_P -CLK_SMA0_C_N
differential pair DDR4_DQS_7: +DDR4_DQS_7_P -DDR4_DQS_7_N
differential pair DDR4_DQS_6: +DDR4_DQS_6_P -DDR4_DQS_6_N
differential pair DDR4_DQS_5: +DDR4_DQS_5_P -DDR4_DQS_5_N
differential pair DDR4_DQS_3: +DDR4_DQS_3_P -DDR4_DQS_3_N
differential pair DDR4_DQS_2: +DDR4_DQS_2_P -DDR4_DQS_2_N
differential pair DDR4_DQS_1: +DDR4_DQS_1_P -DDR4_DQS_1_N
differential pair DDR4_DQS_0: +DDR4_DQS_0_P -DDR4_DQS_0_N
differential pair DDR4_CK: +DDR4_CK_P -DDR4_CK_N
differential pair Si53323_2_Q2: +Si53323_2_Q2_P -Si53323_2_Q2_N
differential pair Si53323_2_Q1: +Si53323_2_Q1_P -Si53323_2_Q1_N
differential pair Si53323_1_Q2: +Si53323_1_Q2_P -Si53323_1_Q2_N
differential pair Si53323_1_Q1: +Si53323_1_Q1_P -Si53323_1_Q1_N
differential pair RefClk_Si53323: +RefClk_Si53323_P -RefClk_Si53323_N
differential pair Bank505_MGTRREF3_C: +Bank505_MGTRREF3_C_P -Bank505_MGTRREF3_C_N
differential pair Bank505_MGTRREF2_C: +Bank505_MGTRREF2_C_P -Bank505_MGTRREF2_C_N
differential pair Bank505_MGTRREF0_C: +Bank505_MGTRREF0_C_P -Bank505_MGTRREF0_C_N
differential pair Bank225_MGTREF1_C: +Bank225_MGTREF1_C_P -Bank225_MGTREF1_C_N
differential pair Bank225_MGTREF0_C: +Bank225_MGTREF0_C_P -Bank225_MGTREF0_C_N
differential pair Bank224_MGTREF1_C: +Bank224_MGTREF1_C_P -Bank224_MGTREF1_C_N
differential pair Bank224_MGTREF0_C: +Bank224_MGTREF0_C_P -Bank224_MGTREF0_C_N
differential pair Bank223_MGTREF1_C: +Bank223_MGTREF1_C_P -Bank223_MGTREF1_C_N
differential pair Bank223_MGTREF0_C: +Bank223_MGTREF0_C_P -Bank223_MGTREF0_C_N
differential pair SFP3_Tx: +SFP3_Tx_P -SFP3_Tx_N
differential pair SFP3_Rx: +SFP3_Rx_P -SFP3_Rx_N
differential pair SFP2_Tx: +SFP2_Tx_P -SFP2_Tx_N
differential pair SFP2_Rx: +SFP2_Rx_P -SFP2_Rx_N
differential pair SFP1_Tx: +SFP1_Tx_P -SFP1_Tx_N
differential pair SFP1_Rx: +SFP1_Rx_P -SFP1_Rx_N
differential pair SFP0_Tx: +SFP0_Tx_P -SFP0_Tx_N
differential pair SFP0_Rx: +SFP0_Rx_P -SFP0_Rx_N
differential pair B225_Tx3C_to_B: +B225_Tx3C_to_B_P -B225_Tx3C_to_B_N
differential pair B225_Tx2C_to_B: +B225_Tx2C_to_B_P -B225_Tx2C_to_B_N
differential pair B225_Tx1C_to_B: +B225_Tx1C_to_B_P -B225_Tx1C_to_B_N
differential pair B225_Tx0C_to_B: +B225_Tx0C_to_B_P -B225_Tx0C_to_B_N
differential pair B224_Tx3C_to_B: +B224_Tx3C_to_B_P -B224_Tx3C_to_B_N
differential pair B224_Tx2C_to_B: +B224_Tx2C_to_B_P -B224_Tx2C_to_B_N
differential pair B224_Tx1C_to_B: +B224_Tx1C_to_B_P -B224_Tx1C_to_B_N
differential pair B224_Tx0C_to_B: +B224_Tx0C_to_B_P -B224_Tx0C_to_B_N
differential pair B223_Tx3C_to_B: +B223_Tx3C_to_B_P -B223_Tx3C_to_B_N
differential pair B223_Tx2C_to_B: +B223_Tx2C_to_B_P -B223_Tx2C_to_B_N
differential pair B223_Tx1C_to_B: +B223_Tx1C_to_B_P -B223_Tx1C_to_B_N
differential pair B223_Tx0C_to_B: +B223_Tx0C_to_B_P -B223_Tx0C_to_B_N

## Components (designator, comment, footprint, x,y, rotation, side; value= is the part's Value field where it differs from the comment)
B1 "TS920E-FL27E" Battery 253.457,320.027 r0 top
BT1 "79523141" 79523141 178.727,122.707 r0 top
C1 "100nF" "CAP 0402/1005 RF" 95.898,253.357 r90 top
C2 "100nF" "CAP 0402/1005 RF" 238.392,323.631 r90 top
C3 "100nF" "CAP 0402/1005 RF" 108.763,199.72 r270 top
C4 "22uF" "CAP 1210/3225 - 1MM" 39.648,164.772 r180 top
C5 "22uF" "CAP 1210/3225 - 1MM" 39.648,168.226 r180 top
C6 "22uF" "CAP 1210/3225 - 1MM" 39.648,175.135 r180 top
C7 "22uF" "CAP 1210/3225 - 1MM" 39.648,171.68 r180 top
C8 "100nF" "CAP 0402/1005 RF" 39.985,159.376 r270 top
C9 "100nF" "CAP 0402/1005 RF" 42.83,159.376 r270 top
C10 "100nF" "CAP 0402/1005 RF" 41.901,159.376 r270 top
C11 "100nF" "CAP 0402/1005 RF" 40.965,159.376 r270 top
C12 "22uF" "CAP 1210/3225 - 1MM" 39.567,178.794 r180 top
C13 "22uF" "CAP 1210/3225 - 1MM" 39.567,185.684 r180 top
C14 "22uF" "CAP 1210/3225 - 1MM" 39.567,189.129 r180 top
C15 "22uF" "CAP 1210/3225 - 1MM" 39.567,182.239 r180 top
C16 "100nF" "CAP 0402/1005 RF" 41.415,192.449 r90 top
C17 "100nF" "CAP 0402/1005 RF" 38.581,192.45 r90 top
C18 "100nF" "CAP 0402/1005 RF" 39.58,192.45 r90 top
C19 "100nF" "CAP 0402/1005 RF" 40.485,192.45 r90 top
C20 "10uF" "CAP 0805/2012 RF" 55.719,164.138 r180 top
C21 "10uF" "CAP 0805/2012 RF" 55.746,169.941 r180 top
C22 "10uF" "CAP 0805/2012 RF" 55.746,168.043 r180 top
C23 "10uF" "CAP 0805/2012 RF" 55.746,175.635 r180 top
C24 "4.7uF" "CAP 0805/2012 RF" 55.746,171.839 r180 top
C25 "4.7uF" "CAP 0805/2012 RF" 55.746,173.737 r180 top
C26 "4.7uF" "CAP 0805/2012 RF" 55.746,177.532 r180 top
C27 "4.7uF" "CAP 0805/2012 RF" 55.746,166.145 r180 top
C28 "10uF" "CAP 0805/2012 RF" 55.758,187.161 r180 top
C29 "10uF" "CAP 0805/2012 RF" 55.758,185.263 r180 top
C30 "10uF" "CAP 0805/2012 RF" 55.758,181.467 r180 top
C31 "10uF" "CAP 0805/2012 RF" 55.758,179.569 r180 top
C32 "4.7uF" "CAP 0805/2012 RF" 55.758,183.365 r180 top
C33 "4.7uF" "CAP 0805/2012 RF" 55.758,189.059 r180 top
C34 "4.7uF" "CAP 0805/2012 RF" 55.758,190.956 r180 top
C35 "4.7uF" "CAP 0805/2012 RF" 55.784,192.899 r180 top
C36 "10nF" "CAP 0402/1005 RF" 155.956,331.965 r180 top
C37 "100nF" "CAP 0402/1005 RF" 63.955,281.318 r0 top
C38 "22uF" "CAP 1210/3225 - 1MM" 72.834,285.318 r0 top
C39 "100nF" "CAP 0402/1005 RF" 68.948,276.161 r90 top
C40 "22uF" "CAP 1210/3225 - 1MM" 72.796,281.422 r0 top
C43 "1uF" "CAP 0402/1005 RF" 103.337,341.393 r90 top
C44 "1uF" "CAP 0402/1005 RF" 104.344,341.386 r90 top
C45 "5.6nF" "CAP 0402/1005 RF" 61.486,539.447 r270 top
C46 "200pF" "CAP 0402/1005 RF" 60.586,539.447 r270 top
C47 "1uF" "CAP 0402/1005 RF" 75.151,493.181 r0 top
C48 "1uF" "CAP 0402/1005 RF" 73.471,493.181 r180 top
C49 "100nF" "CAP 0402/1005 RF" 187.274,285.674 r90 bottom
C50 "100nF" "CAP 0402/1005 RF" 189.814,285.648 r90 bottom
C51 "1uF" "CAP 0402/1005 RF" 74.536,481.457 r270 top
C52 "1uF" "CAP 0402/1005 RF" 73.508,481.47 r90 top
C53 "100nF" "CAP 0402/1005 RF" 54.072,515.607 r0 top
C54 "100nF" "CAP 0402/1005 RF" 201.987,272.694 r0 top
C55 "0.1µF" "CAP 0201/0603 RF" 91.986,580.271 r90 top
C56 "0.1µF" "CAP 0201/0603 RF" 90.081,580.271 r90 top
C57 "0.1µF" "CAP 0201/0603 RF" 88.938,578.62 r270 top
C58 "10µF" "CAP 0402/1005 RF" 90.081,578.626 r270 top
C59 "0.1µF" "CAP 0201/0603 RF" 74.571,559.501 r90 top
C60 "0.1µF" "CAP 0201/0603 RF" 73.682,559.501 r90 top
C61 "0.1µF" "CAP 0201/0603 RF" 70.241,562.818 r90 top
C62 "10µF" "CAP 0402/1005 RF" 68.968,562.688 r90 top
C63 "100nF" "CAP 0402/1005 RF" 152.232,216.378 r270 top
C64 "100nF" "CAP 0402/1005 RF" 161.359,219.934 r0 top
C65 "0.1µF" "CAP 0201/0603 RF" 92.875,580.277 r90 top
C66 "0.1µF" "CAP 0201/0603 RF" 89.192,580.277 r90 top
C67 "100nF" "CAP 0402/1005 RF" 155.622,219.934 r270 top
C68 "10nF" "CAP 0201/0603 RF" 93.383,578.626 r270 top
C69 "10µF" "CAP 0402/1005 RF" 91.986,578.626 r270 top
C70 "100nF" "CAP 0402/1005 RF" 153.122,216.378 r270 top
C71 "0.1µF" "CAP 0201/0603 RF" 70.634,559.513 r0 top
C72 "0.1µF" "CAP 0201/0603 RF" 70.501,560.402 r0 top
C73 "0.1µF" "CAP 0201/0603 RF" 69.228,559.513 r180 top
C74 "10µF" "CAP 0402/1005 RF" 69.618,558.116 r180 top
C75 "100nF" "CAP 0402/1005 RF" 163.373,224.818 r0 top
C76 "100nF" "CAP 0402/1005 RF" 163.373,227.046 r0 top
C77 "100nF" "CAP 0402/1005 RF" 147.752,225.318 r180 top
C78 "10uF" "CAP 0402/1005 RF" 154.622,219.934 r90 top
C79 "10uF" "CAP 0402/1005 RF" 156.122,235.477 r270 top
C80 "10uF" "CAP 0402/1005 RF" 149.717,235.477 r270 top
C81 "100nF" "CAP 0402/1005 RF" 147.752,223.318 r180 top
C82 "100nF" "CAP 0402/1005 RF" 163.373,229.318 r0 top
C83 "100nF" "CAP 0402/1005 RF" 147.752,230.165 r180 top
C84 "0.1µF" "CAP 0201/0603 RF" 68.221,554.814 r90 top
C85 "0.1µF" "CAP 0201/0603 RF" 75.333,559.501 r90 top
C86 "10nF" "CAP 0201/0603 RF" 69.237,554.82 r90 top
C87 "10µF" "CAP 0402/1005 RF" 70.38,554.82 r90 top
C88 "100nF" "CAP 0402/1005 RF" 147.752,231.165 r180 top
C89 "100nF" "CAP 0402/1005 RF" 157.122,235.477 r90 top
C90 "100nF" "CAP 0402/1005 RF" 154.182,235.477 r90 top
C91 "100nF" "CAP 0402/1005 RF" 155.122,235.477 r90 top
C92 "100nF" "CAP 0402/1005 RF" 163.373,223.818 r0 top
C93 "100nF" "CAP 0402/1005 RF" 155.118,216.378 r270 top
C94 "0.1µF" "CAP 0201/0603 RF" 76.095,559.507 r90 top
C95 "0.1µF" "CAP 0201/0603 RF" 72.793,559.507 r90 top
C96 "100nF" "CAP 0402/1005 RF" 150.717,235.477 r90 top
C97 "10nF" "CAP 0201/0603 RF" 71.396,561.663 r90 top
C98 "10µF" "CAP 0402/1005 RF" 72.285,561.663 r90 top
C99 "100nF" "CAP 0402/1005 RF" 146.669,216.447 r90 top
C100 "100nF" "CAP 0402/1005 RF" 170.866,228.801 r90 top
C101 "10uF" "CAP 0402/1005 RF" 150.479,216.456 r90 top
C102 "10uF" "CAP 0402/1005 RF" 166.92,228.801 r90 top
C103 "100nF" "CAP 0402/1005 RF" 161.359,214.983 r180 top
C104 "100nF" "CAP 0402/1005 RF" 141.901,229.208 r90 top
C105 "10uF" "CAP 0402/1005 RF" 161.359,218.929 r180 top
C106 "10uF" "CAP 0402/1005 RF" 145.847,229.208 r90 top
C107 "100nF" "CAP 0402/1005 RF" 156.901,210.527 r180 top
C108 "100nF" "CAP 0402/1005 RF" 146.66,237.81 r0 top
C109 "10uF" "CAP 0402/1005 RF" 156.901,214.473 r180 top
C110 "10uF" "CAP 0402/1005 RF" 146.66,233.864 r0 top
C124 "100nF" "CAP 0402/1005 RF" 152.622,210.527 r180 top
C125 "100nF" "CAP 0402/1005 RF" 157.512,242.032 r180 top
C126 "10uF" "CAP 0402/1005 RF" 152.622,214.473 r180 top
C127 "10uF" "CAP 0402/1005 RF" 157.512,238.086 r180 top
C141 "100nF" "CAP 0402/1005 RF" 170.906,224.281 r270 top
C142 "100nF" "CAP 0402/1005 RF" 153.692,242.032 r0 top
C143 "10uF" "CAP 0402/1005 RF" 166.96,224.281 r270 top
C144 "10uF" "CAP 0402/1005 RF" 153.692,238.086 r0 top
C145 "100nF" "CAP 0402/1005 RF" 170.866,226.656 r90 top
C146 "100nF" "CAP 0402/1005 RF" 170.906,222.084 r270 top
C147 "10uF" "CAP 0402/1005 RF" 166.92,226.656 r90 top
C148 "10uF" "CAP 0402/1005 RF" 166.96,222.084 r270 top
C149 "10nF" "CAP 0201/0603 RF" 92.532,339.814 r90 top
C150 "10nF" "CAP 0201/0603 RF" 96.15,339.814 r90 top
C151 "10nF" "CAP 0201/0603 RF" 91.627,339.814 r90 top
C152 "10nF" "CAP 0201/0603 RF" 94.341,339.814 r90 top
C153 "10nF" "CAP 0201/0603 RF" 89.818,339.814 r90 top
C154 "10nF" "CAP 0201/0603 RF" 95.245,339.814 r90 top
C155 "10nF" "CAP 0201/0603 RF" 90.722,339.814 r90 top
C156 "10nF" "CAP 0201/0603 RF" 93.436,339.814 r90 top
C157 "10nF" "CAP 0201/0603 RF" 88.913,339.814 r90 top
C158 "10nF" "CAP 0201/0603 RF" 98.801,339.826 r90 top
C159 "10nF" "CAP 0201/0603 RF" 97.959,339.814 r90 top
C160 "10nF" "CAP 0201/0603 RF" 99.563,339.826 r90 top
C161 "10nF" "CAP 0201/0603 RF" 97.055,339.814 r90 top
C162 "100nF" "CAP 0402/1005 RF" 142.037,225.876 r270 top
C163 "100nF" "CAP 0402/1005 RF" 154.728,210.527 r180 top
C164 "10uF" "CAP 0402/1005 RF" 145.847,225.876 r90 top
C165 "10uF" "CAP 0402/1005 RF" 154.728,214.473 r180 top
C166 "10nF" "CAP 0201/0603 RF" 181.84,270.266 r90 bottom
C167 "10nF" "CAP 0201/0603 RF" 185.703,270.266 r90 bottom
C168 "10nF" "CAP 0201/0603 RF" 189.565,270.266 r90 bottom
C169 "10nF" "CAP 0201/0603 RF" 182.612,270.266 r90 bottom
C170 "10nF" "CAP 0201/0603 RF" 186.475,270.266 r90 bottom
C171 "10nF" "CAP 0201/0603 RF" 183.385,270.266 r90 bottom
C172 "10nF" "CAP 0201/0603 RF" 187.248,270.266 r90 bottom
C173 "10nF" "CAP 0201/0603 RF" 191.111,270.266 r90 bottom
C174 "10nF" "CAP 0201/0603 RF" 184.93,270.266 r90 bottom
C175 "10nF" "CAP 0201/0603 RF" 188.02,270.266 r90 bottom
C176 "10nF" "CAP 0201/0603 RF" 190.338,270.266 r90 bottom
C177 "10nF" "CAP 0201/0603 RF" 184.157,270.266 r90 bottom
C178 "10nF" "CAP 0201/0603 RF" 188.793,270.266 r90 bottom
C179 "100nF" "CAP 0402/1005 RF" 141.801,223.227 r90 top
C180 "10uF" "CAP 0402/1005 RF" 145.847,223.227 r90 top
C181 "1uF" "CAP 0402/1005 RF" 98.194,327.615 r90 top
C182 "1uF" "CAP 0402/1005 RF" 88.938,342.652 r90 top
C183 "1uF" "CAP 0402/1005 RF" 97.701,342.652 r90 top
C184 "1uF" "CAP 0402/1005 RF" 90.399,342.652 r90 top
C185 "1uF" "CAP 0402/1005 RF" 99.162,342.652 r90 top
C186 "1uF" "CAP 0402/1005 RF" 96.241,342.652 r90 top
C187 "1uF" "CAP 0402/1005 RF" 96.733,327.615 r90 top
C188 "1uF" "CAP 0402/1005 RF" 91.859,342.652 r90 top
C189 "1uF" "CAP 0402/1005 RF" 92.352,327.615 r90 top
C190 "1uF" "CAP 0402/1005 RF" 94.78,342.652 r90 top
C191 "1uF" "CAP 0402/1005 RF" 95.273,327.615 r90 top
C192 "1uF" "CAP 0402/1005 RF" 93.32,342.652 r90 top
C193 "1uF" "CAP 0402/1005 RF" 93.812,327.615 r90 top
C194 "1uF" "CAP 0402/1005 RF" 189.432,273.326 r90 bottom
C195 "1uF" "CAP 0402/1005 RF" 198.986,273.326 r90 bottom
C196 "1uF" "CAP 0402/1005 RF" 195.802,273.326 r90 bottom
C197 "1uF" "CAP 0402/1005 RF" 187.84,273.326 r90 bottom
C198 "1uF" "CAP 0402/1005 RF" 200.579,273.326 r90 bottom
C199 "1uF" "CAP 0402/1005 RF" 194.209,273.326 r90 bottom
C200 "1uF" "CAP 0402/1005 RF" 192.617,273.326 r90 bottom
C201 "1uF" "CAP 0402/1005 RF" 197.394,273.326 r90 bottom
C202 "1uF" "CAP 0402/1005 RF" 191.025,273.326 r90 bottom
C203 "1uF" "CAP 0402/1005 RF" 181.471,273.326 r90 bottom
C204 "1uF" "CAP 0402/1005 RF" 184.655,273.326 r90 bottom
C205 "1uF" "CAP 0402/1005 RF" 183.063,273.326 r90 bottom
C206 "1uF" "CAP 0402/1005 RF" 186.248,273.326 r90 bottom
C207 "100nF" "CAP 0402/1005 RF" 64.16,314.503 r0 top
C208 "22uF" "CAP 1210/3225 - 1MM" 73.063,315.608 r0 top
C209 "100nF" "CAP 0402/1005 RF" 69.679,310.07 r270 top
C210 "22uF" "CAP 1210/3225 - 1MM" 73.254,311.802 r0 top
C211 "100nF" "CAP 0402/1005 RF" 63.983,267.144 r0 top
C212 "22uF" "CAP 1210/3225 - 1MM" 72.863,272.58 r0 top
C213 "100nF" "CAP 0402/1005 RF" 70.015,267.386 r90 top
C214 "22uF" "CAP 1210/3225 - 1MM" 73.101,268.821 r0 top
C215 "100nF" "CAP 0402/1005 RF" 69.532,302.645 r270 top
C216 "22uF" "CAP 1210/3225 - 1MM" 72.771,302.577 r0 top
C217 "100nF" "CAP 0402/1005 RF" 71.387,290.69 r180 top
C218 "22uF" "CAP 1210/3225 - 1MM" 72.822,298.931 r0 top
C219 "100nF" "CAP 0402/1005 RF" 205.639,346.325 r90 top
C220 "100nF" "CAP 0402/1005 RF" 209.035,346.309 r90 top
C221 "100nF" "CAP 0402/1005 RF" 203.083,346.325 r90 top
C222 "100nF" "CAP 0402/1005 RF" 208.036,346.309 r90 top
C223 "4.7uF" "CAP 0402/1005 RF" 118.82,368.554 r0 top
C224 "470nF" "CAP 0402/1005 RF" 122.568,366.395 r0 top
C225 "470nF" "CAP 0402/1005 RF" 115.084,362.077 r0 top
C226 "68nF" "CAP 0402/1005 RF" 125.166,367.538 r0 top
C227 "68nF" "CAP 0402/1005 RF" 115.075,363.982 r0 top
C228 "4.7uF" "CAP 0402/1005 RF" 122.441,367.411 r0 top
C229 "470nF" "CAP 0402/1005 RF" 125.157,366.395 r0 top
C230 "470nF" "CAP 0402/1005 RF" 115.066,363.093 r0 top
C231 "68nF" "CAP 0402/1005 RF" 115.075,368.554 r0 top
C232 "68nF" "CAP 0402/1005 RF" 118.82,366.141 r0 top
C233 "4.7uF" "CAP 0402/1005 RF" 125.166,364.363 r0 top
C234 "470nF" "CAP 0402/1005 RF" 115.075,367.665 r0 top
C235 "470nF" "CAP 0402/1005 RF" 118.82,364.998 r0 top
C236 "68nF" "CAP 0402/1005 RF" 118.811,367.411 r0 top
C237 "68nF" "CAP 0402/1005 RF" 122.559,365.506 r0 top
C238 "4.7uF" "CAP 0402/1005 RF" 125.157,363.347 r0 top
C239 "470nF" "CAP 0402/1005 RF" 115.075,366.776 r0 top
C240 "470nF" "CAP 0402/1005 RF" 118.82,363.982 r0 top
C241 "68nF" "CAP 0402/1005 RF" 122.568,362.585 r0 top
C242 "68nF" "CAP 0402/1005 RF" 122.568,363.474 r0 top
C243 "100nF" "CAP 0402/1005 RF" 122.568,359.418 r0 top
C244 "100nF" "CAP 0402/1005 RF" 125.175,365.379 r180 top
C245 "100nF" "CAP 0402/1005 RF" 118.758,358.656 r0 top
C246 "100nF" "CAP 0402/1005 RF" 122.568,364.49 r180 top
C247 "4.7uF" "CAP 0402/1005 RF" 115.084,361.188 r0 top
C248 "470nF" "CAP 0402/1005 RF" 126.378,358.402 r0 top
C249 "470nF" "CAP 0402/1005 RF" 125.166,362.331 r0 top
C250 "68nF" "CAP 0402/1005 RF" 115.084,365.887 r0 top
C251 "68nF" "CAP 0402/1005 RF" 118.749,362.839 r0 top
C252 "4.7uF" "CAP 0402/1005 RF" 128.274,363.347 r0 top
C253 "470nF" "CAP 0402/1005 RF" 128.274,365.252 r0 top
C254 "470nF" "CAP 0402/1005 RF" 128.283,366.141 r0 top
C255 "68nF" "CAP 0402/1005 RF" 115.075,364.998 r0 top
C256 "68nF" "CAP 0402/1005 RF" 118.758,361.823 r0 top
C257 "4.7uF" "CAP 0402/1005 RF" 128.274,364.236 r0 top
C258 "470nF" "CAP 0402/1005 RF" 131.449,365.506 r0 top
C259 "470nF" "CAP 0402/1005 RF" 131.576,363.347 r0 top
C260 "68nF" "CAP 0402/1005 RF" 131.449,367.411 r0 top
C261 "68nF" "CAP 0402/1005 RF" 131.449,369.316 r0 top
C262 "4.7uF" "CAP 0402/1005 RF" 131.449,364.49 r0 top
C263 "470nF" "CAP 0402/1005 RF" 131.576,362.331 r0 top
C264 "470nF" "CAP 0402/1005 RF" 131.449,366.395 r0 top
C265 "68nF" "CAP 0402/1005 RF" 131.449,368.3 r0 top
C266 "68nF" "CAP 0402/1005 RF" 128.274,362.331 r0 top
C267 "100nF" "CAP 0201/0603 RF" 156.737,369.297 r90 bottom
C268 "100nF" "CAP 0201/0603 RF" 155.937,369.297 r90 bottom
C269 "100nF" "CAP 0201/0603 RF" 154.337,369.297 r90 bottom
C270 "100nF" "CAP 0201/0603 RF" 153.537,369.297 r90 bottom
C271 "100nF" "CAP 0201/0603 RF" 240.69,261.449 r270 bottom
C272 "100nF" "CAP 0201/0603 RF" 241.49,261.449 r270 bottom
C273 "10nF" "CAP 0201/0603 RF" 188.493,286.066 r0 bottom
C274 "100nF" "CAP 0201/0603 RF" 243.09,261.449 r270 bottom
C275 "100nF" "CAP 0201/0603 RF" 243.89,261.449 r270 bottom
C276 "10nF" "CAP 0201/0603 RF" 188.493,285.318 r0 bottom
C277 "10nF" "CAP 0201/0603 RF" 173.533,285.655 r270 bottom
C278 "10nF" "CAP 0201/0603 RF" 174.231,285.655 r270 bottom
C279 "100nF" "CAP 0201/0603 RF" 239.09,369.335 r90 bottom
C280 "100nF" "CAP 0201/0603 RF" 238.29,369.335 r90 bottom
C281 "100nF" "CAP 0201/0603 RF" 236.69,369.335 r90 bottom
C282 "100nF" "CAP 0201/0603 RF" 235.89,369.335 r90 bottom
C283 "100nF" "CAP 0201/0603 RF" 74.385,369.563 r90 bottom
C284 "100nF" "CAP 0201/0603 RF" 73.585,369.563 r90 bottom
C285 "10nF" "CAP 0201/0603 RF" 171.526,285.612 r270 bottom
C286 "100nF" "CAP 0201/0603 RF" 71.985,369.563 r90 bottom
C287 "100nF" "CAP 0201/0603 RF" 71.185,369.563 r90 bottom
C288 "10nF" "CAP 0201/0603 RF" 172.263,285.626 r270 bottom
C289 "10nF" "CAP 0201/0603 RF" 168.491,285.63 r270 bottom
C290 "10nF" "CAP 0201/0603 RF" 169.278,285.63 r270 bottom
C291 "100nF" "CAP 0201/0603 RF" 158.337,261.601 r270 bottom
C292 "100nF" "CAP 0201/0603 RF" 159.137,261.601 r270 bottom
C293 "100nF" "CAP 0201/0603 RF" 160.737,261.601 r270 bottom
C294 "100nF" "CAP 0201/0603 RF" 161.537,261.601 r270 bottom
C295 "100nF" "CAP 0201/0603 RF" 163.137,261.601 r270 bottom
C296 "100nF" "CAP 0201/0603 RF" 163.937,261.601 r270 bottom
C297 "10nF" "CAP 0201/0603 RF" 166.472,285.63 r270 bottom
C298 "100nF" "CAP 0201/0603 RF" 165.537,261.601 r270 bottom
C299 "100nF" "CAP 0201/0603 RF" 166.337,261.601 r270 bottom
C300 "10nF" "CAP 0201/0603 RF" 167.297,285.63 r270 bottom
C301 "10nF" "CAP 0201/0603 RF" 157.981,293.738 r0 top
C302 "10nF" "CAP 0201/0603 RF" 158.075,294.576 r0 top
C303_I2C_Bridge_GPIO "100nF" "CAP 0402/1005 RF" 604.952,286.398 r90 top (schematic designator C303)
C303_I2C_Bridge_PCIE "100nF" "CAP 0402/1005 RF" 363.017,71.514 r90 top (schematic designator C303)
C303_I2C_Bridge_SFP "100nF" "CAP 0402/1005 RF" 360.832,81.026 r90 top (schematic designator C303)
C304 "4.7µF" "CAP 0603/1608 RF" 172.578,164.915 r270 top
C305 "4.7µF" "CAP 0603/1608 RF" 173.703,174.283 r90 top
C306 "4.7µF" "CAP 0603/1608 RF" 173.953,164.914 r270 top
C307 "4.7µF" "CAP 0603/1608 RF" 172.278,174.282 r90 top
C308 "4.7 µF" "CAP 0603/1608 RF" 152.563,164.29 r270 top
C309_U_Pomiar_pradu_napiecia_1 "100nF" "CAP 0402/1005 RF" 360.832,136.677 r90 top (schematic designator C309)
C309_U_Pomiar_pradu_napiecia_2 "100nF" "CAP 0402/1005 RF" 359.74,144.301 r90 top (schematic designator C309)
C309_U_Pomiar_pradu_napiecia_3 "100nF" "CAP 0402/1005 RF" 360.832,149.631 r90 top (schematic designator C309)
C309_U_Pomiar_pradu_napiecia_4 "100nF" "CAP 0402/1005 RF" 362.14,149.441 r90 top (schematic designator C309)
C309_U_Pomiar_pradu_napiecia_5 "100nF" "CAP 0402/1005 RF" 353.047,170.824 r90 top (schematic designator C309)
C309_U_Pomiar_pradu_napiecia_6 "100nF" "CAP 0402/1005 RF" 349.072,150 r270 top (schematic designator C309)
C309_U_Pomiar_pradu_napiecia_PCIe0 "100nF" "CAP 0402/1005 RF" 362.306,177.245 r90 top (schematic designator C309)
C309_U_Pomiar_pradu_napiecia_PCIe1 "100nF" "CAP 0402/1005 RF" 360.832,182.016 r90 top (schematic designator C309)
C309_U_Pomiar_pradu_napiecia_PCIe2 "100nF" "CAP 0402/1005 RF" 361.887,181.94 r90 top (schematic designator C309)
C309_U_Pomiar_pradu_napiecia_PCIe3 "100nF" "CAP 0402/1005 RF" 363.101,196.189 r90 top (schematic designator C309)
C309_U_Pomiar_pradu_napiecia_PCIe4 "100nF" "CAP 0402/1005 RF" 362.915,202.053 r90 top (schematic designator C309)
C310 "100nF" "CAP 0402/1005 RF" 360.832,47.447 r90 top
C311_I2C_Expander_00 "1uF" "CAP 0402/1005 RF" 360.832,91.338 r90 top (schematic designator C311)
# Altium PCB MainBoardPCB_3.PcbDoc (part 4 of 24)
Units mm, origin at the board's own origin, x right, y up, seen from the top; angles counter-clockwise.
Board outline 258.95 x 308.86 mm, 16 copper layers (L1, L2 (GND), L3 (Sign), L4 (GND), L5 (Sign), L6 (PWR/GND), L7(PWR/GND), L8 (Plane_GND), L9 (PWR/GND), L10 (PWR/GND), L11 (PWR/GND), L12 (Sign), L13 (GND), L14 (Sign), L15 (GND), L16), stack 2.502 mm thick; 2402 components, 1749 nets, 8407 pads, 3409 vias.
Unrouted connection lines stored in the file: 4352.

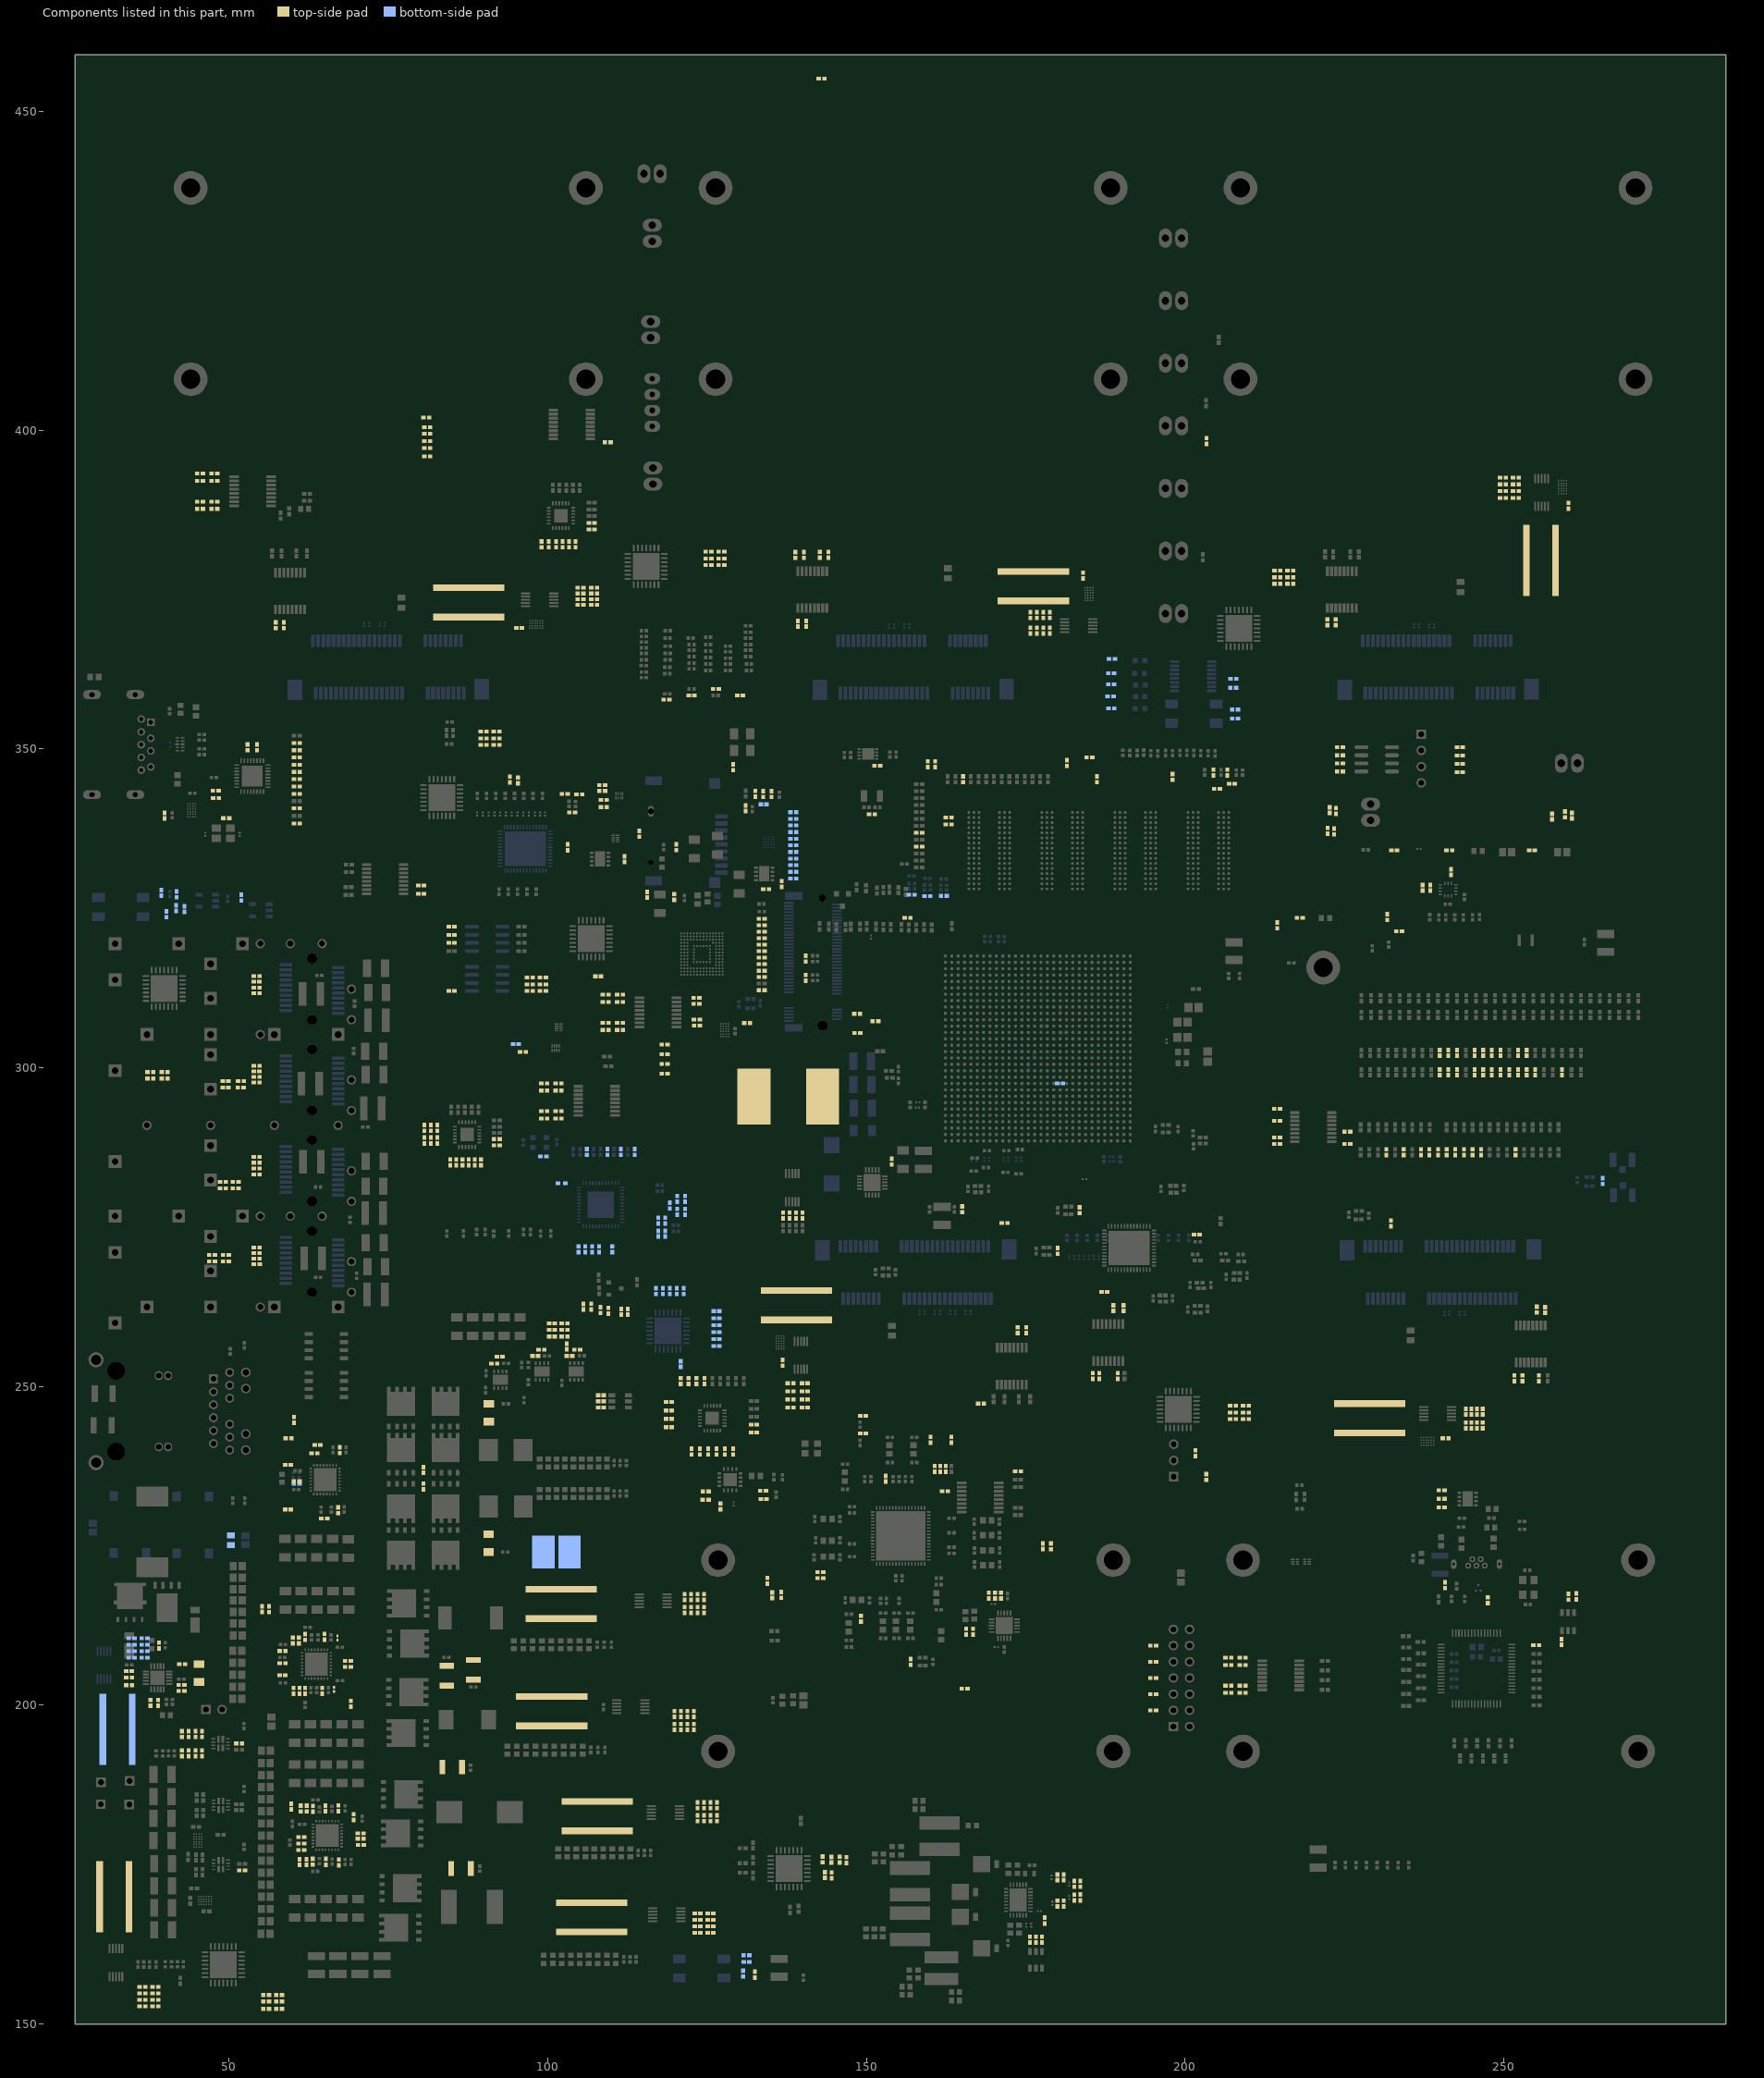
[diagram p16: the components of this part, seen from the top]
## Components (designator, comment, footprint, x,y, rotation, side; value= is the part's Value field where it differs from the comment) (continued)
R55 "39.2R" "RES 0402/1005 RF" 165.186,345.25 r90 top
R56 "499R" "RES 0402/1005 RF" 162.91,338.184 r180 top
R57 "39.2R" "RES 0402/1005 RF" 158.287,336.878 r180 top
R58 "4.7kR" "RES 0402/1005 RF" 162.91,339.242 r180 top
R59 "39.2R" "RES 0402/1005 RF" 158.287,334.7 r180 top
R60 "1kR" "RES 0402/1005 RF" 184.994,348.704 r180 top
R61 "240R" "RES 0402/1005 RF" 198.031,345.611 r90 top
R62 "240R" "RES 0402/1005 RF" 186.195,345.262 r90 top
R63 "240R" "RES 0402/1005 RF" 156.464,323.541 r180 top
R64 "240R" "RES 0402/1005 RF" 181.458,347.789 r90 top
R65 "4.7kR" "RES 0402/1005 RF" 54.329,285.118 r180 top
R66 "4.7kR" "RES 0402/1005 RF" 54.329,286.047 r180 top
R67 "4.7kR" "RES 0402/1005 RF" 54.329,283.247 r180 top
R68 "4.7kR" "RES 0402/1005 RF" 54.329,284.205 r180 top
R69 "100R" "RES 0402/1005 RF" 162.149,326.956 r0 bottom
R70 "100R" "RES 0402/1005 RF" 157.119,327.139 r0 bottom
R71 "0R" "RES 0402/1005 RF" 47.333,270.662 r180 top
R72 "0R" "RES 0402/1005 RF" 47.333,269.646 r180 top
R73 "0R" "RES 0402/1005 RF" 49.495,270.662 r180 top
R74 "0R" "RES 0402/1005 RF" 49.495,269.646 r180 top
R75 "0mR" "RES 0402/1005 RF" 109.41,398.12 r180 top
R76 "150R" "RES 0402/1005 RF" 102.669,342.942 r180 top
R77 "7.5kR" "RES 0402/1005 RF" 61.036,538.05 r180 top
R78 "100R" "RES 0402/1005 RF" 103.826,340.035 r180 top
R79 "150R" "RES 0402/1005 RF" 104.959,342.908 r180 top
R80 "160R" "RES 0402/1005 RF" 65.216,540.131 r0 top
R81 "100R" "RES 0402/1005 RF" 103.124,334.582 r90 top
R82 "100R" "RES 0402/1005 RF" 82.347,512.059 r90 top
R83 "4.7kR" "RES 0402/1005 RF" 108.547,344.313 r0 top
R84 "4.7kR" "RES 0402/1005 RF" 108.801,340.893 r0 top
R85 "4.7kR" "RES 0402/1005 RF" 108.547,343.433 r0 top
R86 "4.7kR" "RES 0402/1005 RF" 108.801,342.036 r0 top
R87 "30R" "RES 0402/1005 RF" 138.537,332.814 r180 bottom
R88 "30R" "RES 0402/1005 RF" 138.537,330.731 r180 bottom
R89 "30R" "RES 0402/1005 RF" 138.537,338.021 r180 bottom
R90 "30R" "RES 0402/1005 RF" 138.537,335.938 r180 bottom
R91 "0R" "RES 0402/1005 RF" 138.537,336.979 r180 bottom
R92 "0R" "RES 0402/1005 RF" 138.537,339.062 r180 bottom
R93 "0R" "RES 0402/1005 RF" 138.537,340.103 r180 bottom
R94 "0R" "RES 0402/1005 RF" 138.537,329.689 r180 bottom
R95 "30R" "RES 0402/1005 RF" 138.537,331.772 r180 bottom
R96 "30R" "RES 0402/1005 RF" 138.537,334.896 r180 bottom
R97 "4.7kR" "RES 0402/1005 RF" 138.537,333.855 r180 bottom
R98 "4.7kR" "RES 0402/1005 RF" 95.009,303.695 r180 bottom
R99 "4.7kR" "RES 0402/1005 RF" 133.579,312.179 r0 top
R101 "30R" "RES 0402/1005 RF" 133.566,322.351 r180 top
R102 "30R" "RES 0402/1005 RF" 133.566,320.319 r180 top
R103 "30R" "RES 0402/1005 RF" 133.566,318.287 r180 top
R104 "30R" "RES 0402/1005 RF" 133.566,316.255 r180 top
R105 "30R" "RES 0402/1005 RF" 133.566,321.335 r180 top
R106 "1kR" "RES 0402/1005 RF" 196.875,72.517 r180 top
R107 "30R" "RES 0402/1005 RF" 133.566,319.303 r180 top
R108 "30R" "RES 0402/1005 RF" 133.566,317.271 r180 top
R109 "1kR" "RES 0402/1005 RF" 142.964,455.193 r0 top
R110 "30R" "RES 0402/1005 RF" 133.566,323.367 r180 top
R111 "30R" "RES 0402/1005 RF" 133.566,315.214 r180 top
R112 "30R" "RES 0402/1005 RF" 133.566,314.223 r180 top
R113 "34.8kR" "RES 0402/1005 RF" 182.642,169.852 r270 top
R114 "10kR" "RES 0402/1005 RF" 183.592,169.86 r90 top
R115 "30R" "RES 0402/1005 RF" 60.642,345.255 r180 top
R116 "30R" "RES 0402/1005 RF" 60.642,342.973 r180 top
R117 "30R" "RES 0402/1005 RF" 60.642,344.114 r180 top
R118 "30R" "RES 0402/1005 RF" 60.642,338.332 r180 top
R119 "30R" "RES 0402/1005 RF" 60.642,346.396 r180 top
R120 "30R" "RES 0402/1005 RF" 60.642,347.538 r180 top
R121 "30R" "RES 0402/1005 RF" 60.642,349.82 r180 top
R122 "30R" "RES 0402/1005 RF" 60.642,350.961 r180 top
R123 "4.7kR" "RES 0402/1005 RF" 107.912,314.35 r0 top
R124 "1kR" "RES 0402/1005 RF" 168.003,247.317 r180 top
R126 "100R" "RES 0402/1005 RF" 159.572,326.943 r180 bottom
R127 "10kR" "RES 0402/1005 RF" 177.707,224.947 r90 top
R128 "10kR" "RES 0402/1005 RF" 142.777,219.934 r180 top
R129 "10kR" "RES 0402/1005 RF" 142.777,220.873 r180 top
R130 "0R" "RES 0402/1005 RF" 160.071,241.651 r270 top
R131 "0R" "RES 0402/1005 RF" 163.313,241.651 r270 top
R132 "0R" "RES 0402/1005 RF" 160.724,237.089 r270 top
R133 "0R" "RES 0402/1005 RF" 161.591,237.089 r270 top
R134 "0R" "RES 0402/1005 RF" 162.474,237.089 r270 top
R135 "4.7kR" "RES 0402/1005 RF" 54.317,313.497 r180 top
R136 "4.7kR" "RES 0402/1005 RF" 54.326,314.403 r180 top
R137 "4.7kR" "RES 0402/1005 RF" 54.329,311.684 r180 top
R138 "4.7kR" "RES 0402/1005 RF" 54.329,312.59 r180 top
R139 "0R" "RES 0402/1005 RF" 178.964,224.917 r270 top
R140 "2.2R" "RES 0402/1005 RF" 34.297,205.384 r180 top
R141 "0R" "RES 0402/1005 RF" 51.019,281.072 r0 top
R142 "0R" "RES 0402/1005 RF" 51.019,282.106 r0 top
R143 "0R" "RES 0402/1005 RF" 49.045,281.09 r0 top
R144 "0R" "RES 0402/1005 RF" 49.045,282.106 r0 top
R145 "4.7kR" "RES 0402/1005 RF" 54.344,270.912 r180 top
R146 "4.7kR" "RES 0402/1005 RF" 54.344,271.797 r180 top
R147 "4.7kR" "RES 0402/1005 RF" 54.348,269.173 r180 top
R148 "4.7kR" "RES 0402/1005 RF" 54.344,270.046 r180 top
R149 "196kR" "RES 0402/1005 RF" 34.323,204.343 r0 top
R150 "22k" "RES 0402/1005 RF" 42.652,206.468 r0 top
R151 "0R" "RES 0402/1005 RF" 51.863,297.915 r0 top
R152 "0R" "RES 0402/1005 RF" 51.816,296.899 r0 top
R153 "0R" "RES 0402/1005 RF" 49.45,297.915 r0 top
R154 "0R" "RES 0402/1005 RF" 49.45,296.899 r0 top
R155 "4.7kR" "RES 0402/1005 RF" 54.317,299.431 r180 top
R156 "4.7kR" "RES 0402/1005 RF" 54.326,300.308 r180 top
R157 "4.7kR" "RES 0402/1005 RF" 54.329,297.677 r180 top
R158 "4.7kR" "RES 0402/1005 RF" 54.329,298.554 r180 top
R159 "10kR" "RES 0402/1005 RF" 34.323,203.149 r0 top
R160 "910R" "RES 0402/1005 RF" 42.528,203.203 r180 top
R161 "0R" "RES 0402/1005 RF" 39.891,299.331 r0 top
R162 "0R" "RES 0402/1005 RF" 39.891,298.315 r0 top
R163 "0R" "RES 0402/1005 RF" 37.652,299.331 r0 top
R164 "0R" "RES 0402/1005 RF" 37.652,298.315 r0 top
R165 "100R" "RES 0402/1005 RF" 207.348,344.531 r0 top
R166 "100R" "RES 0402/1005 RF" 205.004,343.769 r0 top
R167 "100R" "RES 0402/1005 RF" 206.639,346.325 r90 top
R168 "100R" "RES 0402/1005 RF" 204.48,346.325 r90 top
R169 "100R" "RES 0402/1005 RF" 126.378,359.418 r0 top
R170 "100R" "RES 0402/1005 RF" 122.568,358.402 r0 top
R171 "100R" "RES 0402/1005 RF" 130.174,358.402 r0 top
R172 "100R" "RES 0402/1005 RF" 118.631,357.767 r0 top
R173 "500R" "RES 0402/1005 RF" 171.691,275.641 r180 top
R174 "1kR" "RES 0402/1005 RF" 178.788,368.585 r270 top
R175 "1kR" "RES 0402/1005 RF" 177.772,368.585 r270 top
R176 "1kR" "RES 0402/1005 RF" 176.756,368.585 r270 top
R177 "1kR" "RES 0402/1005 RF" 175.74,368.585 r270 top
R178 "1kR" "RES 0402/1005 RF" 178.788,370.998 r90 top
R179 "1kR" "RES 0402/1005 RF" 177.772,370.998 r90 top
R180 "1kR" "RES 0402/1005 RF" 176.756,370.998 r90 top
R181 "1kR" "RES 0402/1005 RF" 175.74,370.998 r90 top
R182 "1.02kR" "RES 0402/1005 RF" 183.978,377.216 r90 top
R183 "1kR" "RES 0402/1005 RF" 244.036,246.049 r90 top
R184 "1kR" "RES 0402/1005 RF" 244.925,246.049 r90 top
R185 "1kR" "RES 0402/1005 RF" 245.814,246.049 r90 top
R186 "1kR" "RES 0402/1005 RF" 246.703,246.049 r90 top
R187 "1kR" "RES 0402/1005 RF" 244.036,243.89 r270 top
R188 "1kR" "RES 0402/1005 RF" 244.925,243.89 r270 top
R189 "1kR" "RES 0402/1005 RF" 245.814,243.89 r270 top
R190 "1kR" "RES 0402/1005 RF" 246.703,243.89 r270 top
R191 "1.02kR" "RES 0402/1005 RF" 240.879,241.88 r0 top
R192 "1kR" "RES 0402/1005 RF" 249.876,389.398 r180 top
R193 "1kR" "RES 0402/1005 RF" 249.876,390.457 r180 top
R194 "1kR" "RES 0402/1005 RF" 249.876,391.515 r180 top
R195 "1kR" "RES 0402/1005 RF" 249.876,392.573 r180 top
R196 "1kR" "RES 0402/1005 RF" 251.908,389.398 r0 top
R197 "1kR" "RES 0402/1005 RF" 251.908,390.457 r0 top
R198 "1kR" "RES 0402/1005 RF" 251.908,391.515 r0 top
R199 "1kR" "RES 0402/1005 RF" 251.908,392.573 r0 top
R200 "1.02kR" "RES 0402/1005 RF" 260.159,388.159 r270 top
R201 "1kR" "RES 0402/1005 RF" 105.131,372.631 r180 top
R202 "1kR" "RES 0402/1005 RF" 105.131,373.52 r180 top
R203 "1kR" "RES 0402/1005 RF" 105.131,374.409 r180 top
R204 "1kR" "RES 0402/1005 RF" 105.131,375.298 r180 top
R205 "1kR" "RES 0402/1005 RF" 107.29,372.631 r0 top
R206 "1kR" "RES 0402/1005 RF" 107.29,373.52 r0 top
R207 "1kR" "RES 0402/1005 RF" 107.29,374.409 r0 top
R208 "1kR" "RES 0402/1005 RF" 107.29,375.298 r0 top
R209 "1.02kR" "RES 0402/1005 RF" 95.503,369.005 r180 top
R210 "1kR" "RES 0402/1005 RF" 140.337,246.697 r0 top
R211 "1kR" "RES 0402/1005 RF" 140.337,247.968 r0 top
R212 "12.5k" "RES 0402/1005 RF" 182.642,171.965 r90 top
R213 "1kR" "RES 0402/1005 RF" 140.337,249.237 r0 top
R214 "10kR" "RES 0402/1005 RF" 183.592,171.965 r270 top
R215 "1kR" "RES 0402/1005 RF" 140.337,250.507 r0 top
R216 "31.2kR" "RES 0402/1005 RF" 179.984,173.015 r270 top
R217 "1kR" "RES 0402/1005 RF" 138.121,246.697 r180 top
R218 "10kR" "RES 0402/1005 RF" 180.95,173.015 r270 top
R219 "1kR" "RES 0402/1005 RF" 138.121,247.968 r180 top
R220 "4.99kR" "RES 0402/1005 RF" 179.984,168.89 r270 top
R221 "1kR" "RES 0402/1005 RF" 138.121,249.237 r180 top
R222 "1kR" "RES 0402/1005 RF" 138.121,250.507 r180 top
R223_I2C_Bridge_GPIO "1kR" "RES 0402/1005 RF" 132.354,244.026 r0 top (schematic designator R223)
R223_I2C_Bridge_PCIE "1kR" "RES 0402/1005 RF" 106.896,385.48 r0 top (schematic designator R223)
R223_I2C_Bridge_SFP "1kR" "RES 0402/1005 RF" 92.004,288.807 r0 top (schematic designator R223)
R224_I2C_Bridge_GPIO "1kR" "RES 0402/1005 RF" 132.354,242.791 r0 top (schematic designator R224)
R224_I2C_Bridge_PCIE "1kR" "RES 0402/1005 RF" 106.896,384.424 r0 top (schematic designator R224)
R224_I2C_Bridge_SFP "1kR" "RES 0402/1005 RF" 92.004,287.833 r0 top (schematic designator R224)
R225_I2C_Bridge_GPIO "1kR" "RES 0402/1005 RF" 129.09,239.794 r270 top (schematic designator R225)
R225_I2C_Bridge_PCIE "1kR" "RES 0402/1005 RF" 104.356,382.099 r270 top (schematic designator R225)
R225_I2C_Bridge_SFP "1kR" "RES 0402/1005 RF" 89.523,285.166 r270 top (schematic designator R225)
R226_I2C_Bridge_GPIO "1kR" "RES 0402/1005 RF" 127.784,239.794 r270 top (schematic designator R226)
R226_I2C_Bridge_PCIE "1kR" "RES 0402/1005 RF" 103.32,382.099 r270 top (schematic designator R226)
R226_I2C_Bridge_SFP "1kR" "RES 0402/1005 RF" 88.558,285.166 r270 top (schematic designator R226)
R227_I2C_Bridge_GPIO "1kR" "RES 0402/1005 RF" 126.479,239.794 r270 top (schematic designator R227)
R227_I2C_Bridge_PCIE "1kR" "RES 0402/1005 RF" 102.32,382.099 r270 top (schematic designator R227)
R227_I2C_Bridge_SFP "1kR" "RES 0402/1005 RF" 87.592,285.166 r270 top (schematic designator R227)
R228 "1.02kR" "RES 0402/1005 RF" 136.881,253.734 r270 top
R229 "1kR" "RES 0402/1005 RF" 36.424,154.826 r180 top
R230 "1kR" "RES 0402/1005 RF" 36.424,155.842 r180 top
R231_SPI_bridge_Main "1kR" "RES 0402/1005 RF" 225.457,289.983 r0 top (schematic designator R231)
R231_SPI_bridge_PCIe "1kR" "RES 0402/1005 RF" 140.532,369.66 r270 top (schematic designator R231)
R232_SPI_bridge_Main "1kR" "RES 0402/1005 RF" 225.457,288.068 r180 top (schematic designator R232)
R232_SPI_bridge_PCIe "1kR" "RES 0402/1005 RF" 139.232,369.66 r90 top (schematic designator R232)
R233_SPI_bridge_Main "1kR" "RES 0402/1005 RF" 188.754,262.311 r90 top (schematic designator R233)
R233_SPI_bridge_PCIe "1kR" "RES 0402/1005 RF" 255.191,262.064 r90 top (schematic designator R233)
R234_SPI_bridge_Main "1kR" "RES 0402/1005 RF" 190.348,262.311 r270 top (schematic designator R234)
R234_SPI_bridge_PCIe "1kR" "RES 0402/1005 RF" 256.491,262.014 r270 top (schematic designator R234)
R235_SPI_bridge_Main "1kR" "RES 0402/1005 RF" 80.13,327.29 r0 top (schematic designator R235)
R235_SPI_bridge_PCIe "1kR" "RES 0402/1005 RF" 222.34,369.89 r270 top (schematic designator R235)
R236_SPI_bridge_Main "1kR" "RES 0402/1005 RF" 80.13,328.59 r0 top (schematic designator R236)
R236_SPI_bridge_PCIe "1kR" "RES 0402/1005 RF" 223.64,369.89 r270 top (schematic designator R236)
R237_SPI_bridge_Main "1kR" "RES 0402/1005 RF" 52.705,494.881 r0 top (schematic designator R237)
R237_SPI_bridge_PCIe "1kR" "RES 0402/1005 RF" 57.328,369.413 r270 top (schematic designator R237)
R238_SPI_bridge_Main "1kR" "RES 0402/1005 RF" 52.712,496.024 r0 top (schematic designator R238)
R238_SPI_bridge_PCIe "1kR" "RES 0402/1005 RF" 58.613,369.413 r270 top (schematic designator R238)
R239_SPI_bridge_Main "1kR" "RES 0402/1005 RF" 173.803,236.703 r180 top (schematic designator R239)
R239_SPI_bridge_PCIe "1kR" "RES 0402/1005 RF" 175.098,258.849 r270 top (schematic designator R239)
R240_SPI_bridge_Main "1kR" "RES 0402/1005 RF" 162.324,233.604 r180 top (schematic designator R240)
R240_SPI_bridge_PCIe "1kR" "RES 0402/1005 RF" 173.746,258.849 r90 top (schematic designator R240)
R241 "1kR" "RES 0402/1005 RF" 119.006,247.554 r180 top
R242 "0mR" "RES 0402/1005 RF" 119.006,246.246 r180 top
R243 "1kR" "RES 0402/1005 RF" 119.006,244.938 r180 top
R244 "0mR" "RES 0402/1005 RF" 119.006,243.63 r180 top
R245 "100R" "RES 0402/1005 RF" 41.478,560.591 r180 top
R246 "120R" "RES 0402/1005 RF" 42.463,566.56 r180 top
R247 "127R" "RES 0402/1005 RF" 42.463,562.75 r180 top
R248 "127R" "RES 0402/1005 RF" 40.362,562.75 r0 top
R249 "120R" "RES 0402/1005 RF" 40.362,566.56 r180 top
R250 "82.5R" "RES 0402/1005 RF" 42.463,563.766 r180 top
R251 "82.5R" "RES 0402/1005 RF" 40.362,563.766 r0 top
R252 "1kR" "RES 0402/1005 RF" 37.795,571.582 r90 top
R253 "1kR" "RES 0402/1005 RF" 37.795,569.578 r270 top
R254 "1kR" "RES 0402/1005 RF" 38.811,571.582 r270 top
R255 "1kR" "RES 0402/1005 RF" 38.811,569.578 r90 top
R256 "120R" "RES 0402/1005 RF" 57.547,525.731 r180 top
R257 "49.9R" "RES 0402/1005 RF" 56.854,517.857 r180 top
R258 "120R" "RES 0402/1005 RF" 55.61,525.731 r180 top
R259 "82.5R" "RES 0402/1005 RF" 55.61,529.541 r0 top
R260 "82.5R" "RES 0402/1005 RF" 57.547,529.541 r180 top
R261 "127R" "RES 0402/1005 RF" 55.61,528.525 r0 top
R262 "127R" "RES 0402/1005 RF" 57.547,528.525 r180 top
R263 "60.4kR" "RES 0402/1005 RF" 53.033,519.508 r0 top
R264 "0mR" "RES 0402/1005 RF" 53.033,522.018 r0 top
R265 "0mR" "RES 0402/1005 RF" 53.033,520.793 r0 top
R266 "84.5kR" "RES 0402/1005 RF" 60.181,244.78 r90 top
R267 "4.7kR" "RES 0402/1005 RF" 11.786,218.63 r0 top
R268 "2R" "RES 0402/1005 RF" 59.242,237.714 r0 top
R269 "1.02kR" "RES 0402/1005 RF" 131.293,307.022 r0 top
R270 "100R" "RES 0402/1005 RF" 265.511,282.219 r270 bottom
R271 "5kR" "RES 0402/1005 RF" 180.397,297.539 r180 bottom
R272 "2R" "RES 0402/1005 RF" 60.606,235.139 r180 top
R273 "12kR" "RES 0402/1005 RF" 63.389,239.52 r180 top
R274 "10kR" "RES 0402/1005 RF" 180.95,168.894 r90 top
R275 "47kR" "RES 0402/1005 RF" 80.488,236.914 r90 top
R276 "4.7kR" "RES 0402/1005 RF" 214.452,322.344 r270 top
R277 "12kR" "RES 0402/1005 RF" 64.94,229.317 r0 top
R278 "12kR" "RES 0402/1005 RF" 63.889,240.855 r0 top
R279 "0mR" "RES 0402/1005 RF" 222.377,337.185 r270 top
R280 "47kR" "RES 0402/1005 RF" 80.488,234.339 r270 top
R281 "1kR" "RES 0402/1005 RF" 124.57,250.869 r90 top
R282 "0mR" "RES 0402/1005 RF" 222.707,340.416 r270 top
R283 "0mR" "RES 0402/1005 RF" 223.698,340.296 r270 top
R284 "18.2k (1MHz)" "RES 0402/1005 RF" 177.98,166.233 r90 top
R285 "2R" "RES 0402/1005 RF" 59.753,184.12 r270 top
R286 "0mR" "RES 0402/1005 RF" 223.368,337.058 r270 top
R287 "49.9kR" "RES 0402/1005 RF" 61.241,183.809 r90 top
R288 "Resistor_1210" RES_1210 85.014,190.309 r180 top value=3.6R
R289 "2R" "RES 0402/1005 RF" 61.331,179.317 r180 top
R290 "10kR" "RES 0402/1005 RF" 62.191,183.809 r270 top
R291 "150R" "RES 0402/1005 RF" 48.828,565.607 r0 top
R292 "Resistance" "RES 0402/1005 RF" 70.661,179.917 r180 top
R293 "0mR" "RES 0402/1005 RF" 61.331,178.317 r0 top
R294 "0mR" "RES 0402/1005 RF" 61.331,177.317 r0 top
R295 "12kR" "RES 0402/1005 RF" 67.169,183.85 r270 top
R296 "12kR" "RES 0402/1005 RF" 67.204,175.367 r90 top
R297 "10kR" "RES 0402/1005 RF" 62.14,175.401 r270 top
R298 "Resistor_1210" RES_1210 86.39,174.414 r180 top value=3.6R
R299 "47kR" "RES 0402/1005 RF" 70.661,179.067 r180 top
R300 "10kR" "RES 0402/1005 RF" 61.068,175.401 r90 top
R301 "150R" "RES 0402/1005 RF" 48.171,570.598 r0 top
R302 "1.4kR" "RES 0201/0603" 66.453,202.488 r90 top
R303 "2R" "RES 0402/1005 RF" 55.203,215.087 r270 top
R304 "1kR" "RES 0402/1005 RF" 136.906,276.829 r90 top
R305 "100R" "RES 0402/1005 RF" 175.639,163.255 r270 top
R306 "Resistor_1210" RES_1210 88.316,205.562 r90 top value=3.6R
R307 "2R" "RES 0402/1005 RF" 58.395,206.596 r0 top
R308 "100R" "RES 0402/1005 RF" 176.589,163.255 r270 top
R309 "100R" "RES 0402/1005 RF" 177.539,163.255 r270 top
R310 "0mR" "RES 0402/1005 RF" 58.395,208.526 r180 top
R311 "100R" "RES 0402/1005 RF" 156.972,206.781 r270 top
R312 "0mR" "RES 0402/1005 RF" 58.376,204.716 r0 top
R313 "12kR" "RES 0402/1005 RF" 64.953,210.754 r270 top
R314 "12kR" "RES 0402/1005 RF" 64.623,202.273 r90 top
R315 "196kR" "RES 0402/1005 RF" 61.041,202.273 r270 top
R316 "Resistor_1210" RES_1210 84.163,204.643 r270 top value=3.6R
R317 "47kR" "RES 0402/1005 RF" 68.656,206.039 r180 top
R318 "27kR" "RES 0402/1005 RF" 60.114,202.273 r90 top
R319 "10kR" "RES 0402/1005 RF" 120.332,279.437 r90 bottom
R320 "10kR" "RES 0402/1005 RF" 120.332,277.401 r270 bottom
R321 "100R" "RES 0402/1005 RF" 119.139,278.384 r90 bottom
R322 "5.76kR" "RES 0402/1005 RF" 117.334,276.022 r90 bottom
R323 "5.76kR" "RES 0402/1005 RF" 117.334,273.977 r270 bottom
R324 "100kR" "RES 0805/2012 RF" 50.292,225.882 r90 bottom
R325 "2.49kR" "RES 0402/1005 RF" 121.539,279.437 r270 bottom
R326 "2.49kR" "RES 0402/1005 RF" 121.539,277.401 r90 bottom
R327 "2.49kR" "RES 0402/1005 RF" 118.427,276.022 r270 bottom
R328 "2.49kR" "RES 0402/1005 RF" 118.427,273.977 r90 bottom
R329 "100R" "RES 0402/1005 RF" 104.826,271.544 r270 bottom
R330 "100R" "RES 0402/1005 RF" 105.908,271.544 r270 bottom
R331 "100R" "RES 0402/1005 RF" 106.991,271.544 r270 bottom
R332 "100R" "RES 0402/1005 RF" 110.122,271.544 r90 bottom
R333 "2.2kR" "RES 0402/1005 RF" 106.145,286.787 r270 bottom
R334 "11kR" "RES 0402/1005" 102.197,281.889 r180 bottom
R335 "1MR" "RES 0402/1005 RF" 99.32,286.117 r180 bottom
R336 "2.2kR" "RES 0402/1005 RF" 113.633,286.787 r270 bottom
R337 "2.2kR" "RES 0402/1005 RF" 109.354,286.787 r270 bottom
R338 "2.2kR" "RES 0402/1005 RF" 111.494,286.787 r270 bottom
R339 "105kR" "RES 0402/1005 RF" 120.155,334.607 r90 top
R340 "10kR" "RES 0402/1005 RF" 112.037,332.737 r90 top
R341 "15kR" "RES 0402/1005 RF" 114.38,336.692 r90 top
R342 "105kR" "RES 0402/1005 RF" 115.595,327.144 r90 top
R343 "10kR" "RES 0402/1005 RF" 134.277,328.019 r180 top
R344 "15kR" "RES 0402/1005 RF" 119.837,326.801 r90 top
R345 "0R" "RES 0402/1005 RF" 136.729,328.835 r90 top
R346 "4.7kR" "RES 0402/1005 RF" 151.4,307.315 r0 top
R347 "4.7kR" "RES 0402/1005 RF" 148.59,305.473 r0 top
R348 "4.7kR" "RES 0402/1005 RF" 148.559,308.47 r0 top
R349 "4.7kR" "RES 0402/1005 RF" 243.109,346.354 r0 top
R350 "4.7kR" "RES 0402/1005 RF" 243.109,347.667 r0 top
R351 "4.7kR" "RES 0402/1005 RF" 243.109,348.979 r0 top
R352 "4.7kR" "RES 0402/1005 RF" 243.109,350.291 r0 top
R353 "4.7kR" "RES 0402/1005 RF" 207.594,360.998 r0 bottom
R354 "4.7kR" "RES 0402/1005 RF" 330.975,290.665 r180 top
R355 "4.7kR" "RES 0402/1005 RF" 327.292,290.779 r0 top
R356 "4.7kR" "RES 0402/1005 RF" 207.841,356.197 r180 bottom
R357 "4.7kR" "RES 0402/1005 RF" 207.543,359.613 r180 bottom
R358 "499R" "RES 0402/1005 RF" 224.315,346.481 r180 top
R359 "499R" "RES 0402/1005 RF" 224.315,347.751 r180 top
R360 "499R" "RES 0402/1005 RF" 224.315,349.021 r180 top
R361 "499R" "RES 0402/1005 RF" 224.315,350.291 r180 top
R362 "30R" "RES 0402/1005 RF" 60.642,340.69 r180 top
R363 "4.7kR" "RES 0402/1005 RF" 134.455,219.537 r90 top
R364 "4.7kR" "RES 0402/1005 RF" 135.232,217.251 r90 top
R365 "4.7kR" "RES 0402/1005 RF" 136.614,217.309 r90 top
R366 "10kR" "RES 0402/1005 RF" 132.499,157.748 r90 top
R367 "4.7kR" "RES 0402/1005 RF" 207.854,354.8 r0 bottom
R368 "261R" "RES 0402/1005 RF" 324.599,282.047 r90 top
R369 "10kR" "RES 0402/1005 RF" 320.523,271.932 r270 top
R370 "10kR" "RES 0402/1005 RF" 321.755,271.958 r270 top
R371 "10kR" "RES 0402/1005 RF" 323.393,282.047 r90 top
R372 "8.06kR" "RES 0402/1005 RF" 316.717,275.45 r180 top
R373 "10kR" "RES 0402/1005 RF" 316.717,276.847 r0 top
R374 "4.7MR" "RES 0402/1005 RF" 150.876,339.763 r0 top
R375 "40.2R" "RES 0402/1005 RF" 129.107,347.154 r270 top
R376 "0R" "RES 0402/1005 RF" 60.643,348.67 r0 top
R377 "0R" "RES 0402/1005 RF" 54.39,350.272 r90 top
R378 "0R" "RES 0402/1005 RF" 52.89,350.272 r90 top
R379 "8.06kR" "RES 0402/1005 RF" 47.962,342.29 r0 top
R380 "4.22kR" "RES 0402/1005 RF" 39.883,339.552 r90 top
R381 "4.7kR" "RES 0402/1005 RF" 135.115,342.94 r90 top
R382 "4.7kR" "RES 0402/1005 RF" 133.833,342.946 r90 top
R383 "10kR" "RES 0402/1005 RF" 131.051,340.703 r90 top
R384 "71.5R" "RES 0402/1005 RF" 48.074,563.918 r0 top
R385 "71.5R" "RES 0402/1005 RF" 52.273,571.128 r0 top
R386 "8.87kR" "RES 0402/1005 RF" 52.273,570.112 r0 top
R387 "5.1kR" "RES 0402/1005 RF" 52.202,568.223 r0 top
R388 "1kR" "RES 0402/1005 RF" 139.979,276.829 r90 top
R389 "1kR" "RES 0402/1005 RF" 138.955,276.829 r90 top
R390 "1kR" "RES 0402/1005 RF" 137.93,276.829 r90 top
R391 "75kR" "RES 0402/1005 RF" 103.42,254.796 r180 top
R392 "100kR" "RES 0402/1005 RF" 102.991,256.279 r270 top
R393 "15kR" "RES 0402/1005 RF" 104.62,255.77 r180 top
R394 "51.1kR" "RES 0402/1005 RF" 98.051,254.796 r180 top
R395 "0mR" "RES 0402/1005 RF" 97.16,549.161 r0 top
R396 "15kR" "RES 0402/1005 RF" 99.012,255.77 r180 top
R397 "21.5kR" "RES 0402/1005 RF" 91.606,253.618 r180 top
R398 "0mR" "RES 0402/1005 RF" 97.356,547.954 r0 top
R399 "15kR" "RES 0402/1005 RF" 92.461,254.68 r180 top
R400 "0mR" "RES 0402/1005 RF" 123.333,250.869 r90 top
R401 "10k" "RES 0402/1005 RF" 84.925,312.045 r180 top
R402 "0R" "RES 0402/1005 RF" 206.789,207.472 r0 top
R403 "0R" "RES 0402/1005 RF" 209.049,207.472 r180 top
R404 "0R" "RES 0402/1005 RF" 206.789,206.333 r0 top
R405 "0R" "RES 0402/1005 RF" 209.049,206.333 r180 top
R406 "0R" "RES 0402/1005 RF" 206.789,203.083 r0 top
R407 "0R" "RES 0402/1005 RF" 209.049,203.083 r180 top
R408 "0R" "RES 0402/1005 RF" 206.789,201.944 r0 top
R409 "0R" "RES 0402/1005 RF" 209.049,201.944 r180 top
R410 "10k" "RES 0402/1005 RF" 84.925,319.589 r180 top
R411 "0R" "RES 0402/1005 RF" 99.448,296.43 r0 top
R412 "0R" "RES 0402/1005 RF" 101.709,296.43 r180 top
R413 "0R" "RES 0402/1005 RF" 99.448,297.569 r0 top
R414 "0R" "RES 0402/1005 RF" 101.709,297.569 r180 top
R415 "0R" "RES 0402/1005 RF" 99.448,293.18 r0 top
R416 "0R" "RES 0402/1005 RF" 101.709,293.18 r180 top
R417 "10k" "RES 0402/1005 RF" 261.417,217.076 r270 top
R418 "0R" "RES 0402/1005 RF" 99.448,292.041 r0 top
R419 "2kR" "RES 0402/1005 RF" 255.115,209.431 r0 top
R420 "10k" "RES 0402/1005 RF" 260.159,217.013 r270 top
R421 "0R" "RES 0402/1005 RF" 101.709,292.041 r180 top
R422 "10k" "RES 0402/1005 RF" 259.093,209.926 r270 top
R423 "12kR" "RES 0402/1005 RF" 247.51,216.472 r270 top
R424 "1kR" "RES 0402/1005 RF" 240.805,218.84 r270 top
R425_SPI_bridge_Main "0mR" "RES 0402/1005 RF" 214.452,293.539 r180 top (schematic designator R425)
R425_SPI_bridge_PCIe "0mR" "RES 0402/1005 RF" 144.057,380.477 r90 top (schematic designator R425)
R426_SPI_bridge_Main "0mR" "RES 0402/1005 RF" 214.452,289.052 r0 top (schematic designator R426)
R426_SPI_bridge_PCIe "0mR" "RES 0402/1005 RF" 140.183,380.427 r270 top (schematic designator R426)
R428 "1kR" "RES 0402/1005 RF" 120.86,250.869 r90 top
R429 "0mR" "RES 0402/1005 RF" 241.757,330.701 r90 top
R430_5V_to_3V3_for_FTDI "105kR" "RES 0402/1005 RF" 240.271,231.026 r180 top (schematic designator R430)
R430_U_5V_to_3V31 "105kR" "RES 0402/1005 RF" 360.267,345.625 r270 top (schematic designator R430)
R430_U_5V_to_3V32 "105kR" "RES 0402/1005 RF" 326.428,325.332 r270 top (schematic designator R430)
R430_U_5V_to_3V33 "105kR" "RES 0402/1005 RF" 332.073,365.531 r0 top (schematic designator R430)
R431_5V_to_3V3_for_FTDI "100kR" "RES 0402/1005 RF" 240.271,233.729 r180 top (schematic designator R431)
R431_U_5V_to_3V31 "100kR" "RES 0402/1005 RF" 357.194,345.625 r90 top (schematic designator R431)
R431_U_5V_to_3V32 "100kR" "RES 0402/1005 RF" 324.904,327.558 r90 top (schematic designator R431)
R431_U_5V_to_3V33 "100kR" "RES 0402/1005 RF" 332.073,363.182 r0 top (schematic designator R431)
R432_5V_to_3V3_for_FTDI "15kR" "RES 0402/1005 RF" 240.271,232.378 r0 top (schematic designator R432)
R432_U_5V_to_3V31 "15kR" "RES 0402/1005 RF" 358.667,345.65 r90 top (schematic designator R432)
R432_U_5V_to_3V32 "15kR" "RES 0402/1005 RF" 330.086,323.042 r180 top (schematic designator R432)
R432_U_5V_to_3V33 "15kR" "RES 0402/1005 RF" 332.073,364.299 r180 top (schematic designator R432)
R433 "56kR" "RES 0402/1005 RF" 345.444,359.939 r0 top
R434 "10kR" "RES 0402/1005 RF" 344.834,358.707 r0 top
R435 "10kR" "RES 0402/1005 RF" 124.785,233.54 r180 top
R436 "3.57kR" "RES 0402/1005 RF" 165.659,211.548 r90 top
R437 "1.15kR" "RES 0402/1005 RF" 165.417,202.603 r0 top
R438 "3.57kR" "RES 0402/1005 RF" 170.181,217.2 r90 top
R439 "1.15kR" "RES 0402/1005 RF" 169.215,217.2 r270 top
R440 "20kR" "RES 0402/1005 RF" 166.736,211.548 r90 top
R441 "20kR" "RES 0402/1005 RF" 171.128,217.2 r90 top
R442 "100kR" "RES 0402/1005 RF" 39.725,505.754 r90 top
R443 "698kR" "RES 0805/2012 RF" 46.507,506.323 r90 top
R444 "49.9kR" "RES 0402/1005 RF" 43.075,503.93 r0 top
R445 "49.9kR" "RES 0402/1005 RF" 45.021,506.096 r270 top
R446 "120R" "RES 0402/1005 RF" 20.436,533.946 r90 top
R447 "120R" "RES 0402/1005 RF" 21.667,533.844 r90 top
R448_U_Pomiar_pradu_napiecia_1 "FCSL110R005FER" FCSL110R005FERCT-ND 31.979,169.964 r0 top (schematic designator R448)
R448_U_Pomiar_pradu_napiecia_2 "FCSL110R005FER" FCSL110R005FERCT-ND 32.487,196.24 r0 bottom (schematic designator R448)
R448_U_Pomiar_pradu_napiecia_3 "FCSL110R005FER" FCSL110R005FERCT-ND 107.759,182.601 r90 top (schematic designator R448)
R448_U_Pomiar_pradu_napiecia_4 "FCSL110R005FER" FCSL110R005FERCT-ND 106.904,166.738 r90 top (schematic designator R448)
R448_U_Pomiar_pradu_napiecia_5 "FCSL110R005FER" FCSL110R005FERCT-ND 102.092,215.887 r90 top (schematic designator R448)
R448_U_Pomiar_pradu_napiecia_6 "FCSL110R005FER" FCSL110R005FERCT-ND 100.635,199.06 r90 top (schematic designator R448)
R448_U_Pomiar_pradu_napiecia_PCIe0 "FCSL110R005FER" FCSL110R005FERCT-ND 176.213,375.539 r90 top (schematic designator R448)
R448_U_Pomiar_pradu_napiecia_PCIe1 "FCSL110R005FER" FCSL110R005FERCT-ND 228.968,245.017 r90 top (schematic designator R448)
R448_U_Pomiar_pradu_napiecia_PCIe2 "FCSL110R005FER" FCSL110R005FERCT-ND 255.841,379.581 r180 top (schematic designator R448)
R448_U_Pomiar_pradu_napiecia_PCIe3 "FCSL110R005FER" FCSL110R005FERCT-ND 87.605,373.012 r270 top (schematic designator R448)
R448_U_Pomiar_pradu_napiecia_PCIe4 "FCSL110R005FER" FCSL110R005FERCT-ND 139.04,262.745 r90 top (schematic designator R448)
R449 "1kR" "RES 0402/1005 RF" 81.09,400.473 r0 top
R450 "0mR" "RES 0402/1005 RF" 81.09,399.457 r0 top
R451 "1kR" "RES 0402/1005 RF" 81.09,395.901 r0 top
R452 "0mR" "RES 0402/1005 RF" 80.963,401.997 r0 top
R453 "1kR" "RES 0402/1005 RF" 81.09,397.229 r0 top
R454 "0mR" "RES 0402/1005 RF" 81.09,398.314 r0 top
R455 "1kR" "RES 0402/1005 RF" 57.848,154.546 r0 top
R456 "0mR" "RES 0402/1005 RF" 55.816,154.546 r180 top
R457 "1kR" "RES 0402/1005 RF" 36.424,153.81 r180 top
R458 "1kR" "RES 0402/1005 RF" 57.848,153.53 r0 top
R459 "1kR" "RES 0402/1005 RF" 36.424,152.794 r180 top
R460 "0mR" "RES 0402/1005 RF" 55.816,153.53 r180 top
R461 "1kR" "RES 0402/1005 RF" 38.456,154.826 r0 top
R462 "1kR" "RES 0402/1005 RF" 57.848,152.387 r0 top
R463 "1kR" "RES 0402/1005 RF" 38.456,155.842 r0 top
R464 "0mR" "RES 0402/1005 RF" 55.816,152.387 r180 top
R465 "1kR" "RES 0402/1005 RF" 38.456,153.81 r0 top
R466 "1kR" "RES 0402/1005 RF" 38.456,152.794 r0 top
R467 "1kR" "RES 0402/1005 RF" 34.716,209.499 r0 bottom
R468 "1kR" "RES 0402/1005 RF" 34.716,210.515 r0 bottom
R469 "1kR" "RES 0402/1005 RF" 80.623,290.569 r90 top
R470 "0mR" "RES 0402/1005 RF" 80.623,288.595 r270 top
R471 "1kR" "RES 0402/1005 RF" 81.639,290.569 r90 top
R472 "0mR" "RES 0402/1005 RF" 81.639,288.595 r270 top
R473 "1kR" "RES 0402/1005 RF" 82.655,290.569 r90 top
R474 "0mR" "RES 0402/1005 RF" 82.655,288.595 r270 top
R475 "1kR" "RES 0402/1005 RF" 102.629,259.923 r0 top
R476 "0mR" "RES 0402/1005 RF" 100.655,259.923 r180 top
R477 "1kR" "RES 0402/1005 RF" 102.629,258.907 r0 top
R478 "0mR" "RES 0402/1005 RF" 100.655,258.907 r180 top
R479 "1kR" "RES 0402/1005 RF" 102.629,257.845 r0 top
R480 "0mR" "RES 0402/1005 RF" 100.655,257.845 r180 top
R481 "0R" "RES 0402/1005 RF" 51.212,497.916 r180 top
R482 "150R" "RES 0402/1005 RF" 46.165,552.036 r180 top
R483 "150R" "RES 0402/1005 RF" 46.165,551.036 r180 top
R484 "71.5R" "RES 0402/1005 RF" 45.715,553.486 r270 top
R485 "71.5R" "RES 0402/1005 RF" 45.715,549.586 r90 top
R486 "8.87kR" "RES 0402/1005 RF" 26.365,581.955 r90 top
R487 "5.1kR" "RES 0402/1005 RF" 33.123,582.03 r180 top
R488 "1kR" "RES 0402/1005 RF" 33.123,583.046 r180 top
R489 "100R" "RES 0402/1005 RF" 32.673,580.558 r90 top
R490 "10kR" "RES 0402/1005 RF" 47.91,343.471 r180 top
R491 "1MR" "RES 0402/1005 RF" 49.561,339.152 r180 top
R492 "1kR" "RES 0402/1005 RF" 97.213,314.142 r180 top
R493 "0mR" "RES 0402/1005 RF" 99.245,314.142 r0 top
R494 "1kR" "RES 0402/1005 RF" 97.213,313.068 r180 top
R495 "0mR" "RES 0402/1005 RF" 99.245,313.068 r0 top
R496 "1kR" "RES 0402/1005 RF" 97.213,312.052 r180 top
R497 "0mR" "RES 0402/1005 RF" 99.245,312.052 r0 top
R498 "0R" "RES 0402/1005 RF" 131.178,160.795 r0 bottom
R499 "1kR" "RES 0402/1005 RF" 131.2,159.719 r180 bottom
R500 "1kR" "RES 0402/1005 RF" 89.947,352.762 r180 top
R501 "0mR" "RES 0402/1005 RF" 91.979,352.762 r0 top
R502 "1kR" "RES 0402/1005 RF" 89.947,350.672 r180 top
R503 "0mR" "RES 0402/1005 RF" 91.979,350.672 r0 top
R504 "1kR" "RES 0402/1005 RF" 89.947,351.688 r180 top
R505 "0mR" "RES 0402/1005 RF" 91.979,351.688 r0 top
R506 "0mR" "RES 0402/1005 RF" 99.645,550.388 r180 top
R507 "0mR" "RES 0402/1005 RF" 257.585,339.404 r90 top
R508 "1kR" "RES 0402/1005 RF" 125.216,380.956 r180 top
R509 "0mR" "RES 0402/1005 RF" 127.248,380.956 r0 top
R510 "1kR" "RES 0402/1005 RF" 125.216,379.882 r180 top
R511 "0mR" "RES 0402/1005 RF" 127.248,379.882 r0 top
R512 "1kR" "RES 0402/1005 RF" 125.216,378.866 r180 top
R513 "0mR" "RES 0402/1005 RF" 127.248,378.866 r0 top
R514 "0mR" "RES 0402/1005 RF" 232.321,275.596 r270 top
R515 "10kR" "RES 0402/1005 RF" 242.686,299.297 r90 top
R516 "0mR" "RES 0402/1005 RF" 214.478,378.015 r180 top
R517 "0mR" "RES 0402/1005 RF" 216.51,378.015 r0 top
R518 "0mR" "RES 0402/1005 RF" 214.478,376.942 r180 top
R519 "0mR" "RES 0402/1005 RF" 216.51,376.942 r0 top
R520 "0mR" "RES 0402/1005 RF" 214.478,375.926 r180 top
R521 "0mR" "RES 0402/1005 RF" 216.51,375.926 r0 top
R522 "10kR" "RES 0402/1005 RF" 245.413,299.297 r90 top
R523 "10kR" "RES 0402/1005 RF" 231.607,286.757 r270 top
R524 "0mR" "RES 0402/1005 RF" 207.525,246.984 r180 top
R525 "0mR" "RES 0402/1005 RF" 209.557,246.984 r0 top
R526 "0mR" "RES 0402/1005 RF" 207.525,245.91 r180 top
R527 "0mR" "RES 0402/1005 RF" 209.557,245.91 r0 top
R528 "0mR" "RES 0402/1005 RF" 207.525,244.894 r180 top
R529 "0mR" "RES 0402/1005 RF" 209.557,244.894 r0 top
R530 "0mR" "RES 0402/1005 RF" 242.686,302.335 r90 top
R531 "10kR" "RES 0402/1005 RF" 239.96,299.297 r90 top
R532 "75R" "RES 0402/1005 RF" 64.503,542.087 r270 top
R533 "30R" "RES 0402/1005 RF" 65.482,542.112 r90 top
R534 "160R" "RES 0402/1005 RF" 183.451,277.647 r90 top
R535 "100R" "RES 0402/1005 RF" 180.01,271.272 r90 top
R536 "100R" "RES 0402/1005 RF" 187.33,264.859 r180 top
R537 "0mR" "RES 0402/1005 RF" 54.021,516.611 r180 top
R539 "0mR" "RES 0402/1005 RF" 201.84,273.837 r0 top
R540 "0R" "RES 0402/1005 RF" 153.012,235.537 r270 top
R541 "100R" "RES 0402/1005 RF" 140.462,314.124 r90 top
R542 "100R" "RES 0402/1005 RF" 140.462,317.125 r90 top
R543 "100R" "RES 0402/1005 RF" 149.472,245.417 r180 top
R544 "1kR" "RES 0402/1005 RF" 149.149,213.584 r90 top
R545 "49.9R" "RES 0402/1005 RF" 149.472,242.623 r180 top
R546 "10kR" "RES 0402/1005 RF" 237.005,286.757 r270 top
R547 "0mR" "RES 0402/1005 RF" 245.413,302.335 r90 top
R548 "10kR" "RES 0402/1005 RF" 241.323,299.297 r90 top
R549 "10kR" "RES 0402/1005 RF" 234.306,286.757 r270 top
R550 "0mR" "RES 0402/1005 RF" 239.96,302.335 r90 top
R551 "10kR" "RES 0402/1005 RF" 246.776,299.297 r90 top
R552 "10kR" "RES 0402/1005 RF" 251.85,286.757 r270 top
R553 "0mR" "RES 0402/1005 RF" 241.323,302.335 r90 top
R554 "10kR" "RES 0402/1005 RF" 248.14,299.297 r90 top
R555 "10kR" "RES 0402/1005 RF" 243.753,286.757 r270 top
R556 "0mR" "RES 0402/1005 RF" 246.776,302.335 r90 top
R557 "10kR" "RES 0402/1005 RF" 249.503,299.297 r90 top
R558_I2C_Bridge_GPIO "1kR" "RES 0402/1005 RF" 125.173,239.794 r270 top (schematic designator R558)
R558_I2C_Bridge_PCIE "1kR" "RES 0402/1005 RF" 101.32,382.099 r270 top (schematic designator R558)
R558_I2C_Bridge_SFP "1kR" "RES 0402/1005 RF" 86.627,285.166 r270 top (schematic designator R558)
R559_I2C_Bridge_GPIO "1kR" "RES 0402/1005 RF" 123.867,239.794 r270 top (schematic designator R559)
R559_I2C_Bridge_PCIE "1kR" "RES 0402/1005 RF" 100.135,382.099 r270 top (schematic designator R559)
R559_I2C_Bridge_SFP "1kR" "RES 0402/1005 RF" 85.662,285.166 r270 top (schematic designator R559)
R560_I2C_Bridge_GPIO "1kR" "RES 0402/1005 RF" 122.562,239.794 r270 top (schematic designator R560)
R560_I2C_Bridge_PCIE "1kR" "RES 0402/1005 RF" 99.022,382.099 r270 top (schematic designator R560)
R560_I2C_Bridge_SFP "1kR" "RES 0402/1005 RF" 84.696,285.166 r270 top (schematic designator R560)
R561 "1kR" "RES 0402/1005 RF" 124.498,184.31 r90 top
R562 "1kR" "RES 0402/1005 RF" 123.482,184.31 r90 top
R563 "1kR" "RES 0402/1005 RF" 125.514,184.31 r90 top
R564 "1kR" "RES 0402/1005 RF" 126.53,184.31 r90 top
R565 "1kR" "RES 0402/1005 RF" 124.498,182.278 r270 top
R566 "1kR" "RES 0402/1005 RF" 123.482,182.278 r270 top
R567 "1kR" "RES 0402/1005 RF" 125.514,182.278 r270 top
R568 "1kR" "RES 0402/1005 RF" 126.53,182.278 r270 top
R569 "1kR" "RES 0402/1005 RF" 125.539,165.349 r0 top
R570 "1kR" "RES 0402/1005 RF" 125.539,164.333 r0 top
R571 "1kR" "RES 0402/1005 RF" 125.539,166.365 r0 top
R572 "1kR" "RES 0402/1005 RF" 125.54,167.381 r0 top
R573 "1kR" "RES 0402/1005 RF" 123.507,165.349 r180 top
R574 "1kR" "RES 0402/1005 RF" 123.508,164.333 r180 top
R575 "1kR" "RES 0402/1005 RF" 123.508,166.365 r180 top
R576 "1kR" "RES 0402/1005 RF" 123.508,167.381 r180 top
R577 "1kR" "RES 0402/1005 RF" 122.504,216.987 r90 top
R578 "1kR" "RES 0402/1005 RF" 121.488,216.987 r90 top
R579 "1kR" "RES 0402/1005 RF" 123.52,216.987 r90 top
R580 "1kR" "RES 0402/1005 RF" 124.536,216.987 r90 top
R581 "1kR" "RES 0402/1005 RF" 122.504,214.955 r270 top
R582 "1kR" "RES 0402/1005 RF" 121.488,214.955 r270 top
R583 "1kR" "RES 0402/1005 RF" 123.52,214.955 r270 top
R584 "1kR" "RES 0402/1005 RF" 124.536,214.955 r270 top
R585 "1kR" "RES 0402/1005 RF" 120.872,196.601 r270 top
R586 "1kR" "RES 0402/1005 RF" 119.856,196.601 r270 top
R587 "1kR" "RES 0402/1005 RF" 121.888,196.601 r270 top
R588 "1kR" "RES 0402/1005 RF" 122.904,196.601 r270 top
R589 "1kR" "RES 0402/1005 RF" 120.872,198.633 r90 top
R590 "1kR" "RES 0402/1005 RF" 119.856,198.633 r90 top
R591 "1kR" "RES 0402/1005 RF" 121.888,198.633 r90 top
R592 "1kR" "RES 0402/1005 RF" 122.904,198.633 r90 top
R593 "1kR" "RES 0402/1005 RF" 34.716,208.483 r0 bottom
R594 "1kR" "RES 0402/1005 RF" 34.716,207.467 r0 bottom
R595 "1kR" "RES 0402/1005 RF" 36.748,209.499 r180 bottom
R596 "1kR" "RES 0402/1005 RF" 36.748,210.515 r180 bottom
R597 "1kR" "RES 0402/1005 RF" 36.748,208.483 r180 bottom
R598 "1kR" "RES 0402/1005 RF" 36.748,207.467 r180 bottom
R599 "1kR" "RES 0402/1005 RF" 122.097,250.869 r90 top
R600 "0mR" "RES 0402/1005 RF" 237.279,328.24 r270 top
R601 "0mR" "RES 0402/1005 RF" 238.465,328.24 r90 top
R602_SPI_bridge_Main "0mR" "RES 0402/1005 RF" 214.452,291.652 r180 top (schematic designator R602)
R602_SPI_bridge_PCIe "0mR" "RES 0402/1005 RF" 142.687,380.477 r90 top (schematic designator R602)
R603_SPI_bridge_Main "0mR" "RES 0402/1005 RF" 214.452,288.068 r0 top (schematic designator R603)
R603_SPI_bridge_PCIe "0mR" "RES 0402/1005 RF" 138.857,380.427 r270 top (schematic designator R603)
R604_SPI_bridge_Main "0mR" "RES 0402/1005 RF" 185.538,251.673 r270 top (schematic designator R604)
R604_SPI_bridge_PCIe "0mR" "RES 0402/1005 RF" 251.666,251.289 r270 top (schematic designator R604)
R605_SPI_bridge_Main "0mR" "RES 0402/1005 RF" 189.416,251.673 r90 top (schematic designator R605)
R605_SPI_bridge_PCIe "0mR" "RES 0402/1005 RF" 255.537,251.289 r90 top (schematic designator R605)
R606_SPI_bridge_Main "0mR" "RES 0402/1005 RF" 186.548,251.673 r270 top (schematic designator R606)
R606_SPI_bridge_PCIe "0mR" "RES 0402/1005 RF" 252.94,251.289 r270 top (schematic designator R606)
R607 "10kR" "RES 0402/1005 RF" 238.355,286.758 r270 top
R608 "10kR" "RES 0402/1005 RF" 60.9,495.624 r90 top
R609 "10kR" "RES 0402/1005 RF" 59.909,495.632 r270 top
R610 "1.33kR" "RES 0402/1005 RF" 67.378,240.02 r90 top
R611 "1.33kR" "RES 0402/1005 RF" 67.113,230.597 r270 top
R612 "270R" "RES 0402/1005 RF" 59.342,241.891 r180 top
R613 "2.4R" "RES 1206/3216" 90.765,245.884 r270 top
R614 "270R" "RES 0402/1005 RF" 59.242,230.712 r180 top
R615 "10kR" "RES 0402/1005 RF" 60.606,234.739 r0 bottom
R616 "2.4R" "RES 1206/3216" 90.717,225.431 r90 top
R617 "PU5931FKMP70R004L" PU5931 137.735,295.465 r0 top
R618 "0mR" "RES 0402/1005 RF" 248.14,302.335 r90 top
R619 "1.91kR" "RES 0402/1005 RF" 69.532,182.474 r90 top
R620 "2kR" "RES 0402/1005 RF" 70.68,178.1 r180 top
R621 "147kR" "RES 0402/1005 RF" 65.137,183.819 r90 top
R622 "340kR" "RES 0402/1005 RF" 65.175,175.443 r270 top
R623 "1.43kR" "RES 0402/1005 RF" 63.12,175.457 r90 top
R624 "15kR" "RES 0402/1005 RF" 63.175,183.76 r270 top
R625 "1.4kR" "RES 0201/0603" 67.001,210.554 r270 top
R626 "200kR" "RES 0402/1005 RF" 59.997,210.161 r90 top
R627 "10.5kR" "RES 0402/1005 RF" 60.944,210.183 r270 top
R628 "750kR" "RES 0402/1005 RF" 69.132,200.233 r270 top
R629 "Resistance" "RES 0402/1005 RF" 68.656,206.964 r180 top
R630 "10kR" "RES 0402/1005 RF" 52.05,174.091 r180 top
R631 "5.9kR" "RES 0402/1005 RF" 61.938,202.273 r90 top
R632 "100kR" "RES 0402/1005 RF" 108.341,246.733 r180 top
R633 "100kR" "RES 0402/1005 RF" 108.341,247.684 r180 top
R634 "100kR" "RES 0402/1005 RF" 108.341,248.634 r180 top
R635 "10k" "RES 0402/1005 RF" 84.925,320.859 r180 top
R636 "0R" "RES 0402/1005 RF" 109.087,311.463 r0 top
R637 "0R" "RES 0402/1005 RF" 111.348,311.463 r180 top
R638 "0R" "RES 0402/1005 RF" 109.087,310.324 r0 top
R639 "0R" "RES 0402/1005 RF" 111.348,310.324 r180 top
R640 "0R" "RES 0402/1005 RF" 109.087,307.074 r0 top
R641 "0R" "RES 0402/1005 RF" 111.348,307.074 r180 top
R642 "0R" "RES 0402/1005 RF" 109.087,305.935 r0 top
R643 "0R" "RES 0402/1005 RF" 111.348,305.935 r180 top
R644 "9.1kR" "RES 0402/1005 RF" 133.797,233.642 r0 top
R645 "13kR" "RES 0402/1005 RF" 133.876,232.346 r180 top
R646 "100kR" "RES 0402/1005 RF" 127.102,231.203 r90 top
R647 "100kR" "RES 0402/1005 RF" 175.374,107.429 r0 top
R648 "2R" "RES 0402/1005 RF" 188.011,108.636 r0 top
R649 "10kR" "RES 0402/1005 RF" 196.266,103.429 r180 top
R650 "100MR" "RES 0402/1005 RF" 162.598,102.248 r0 top
R651 "10kR" "RES 0402/1005 RF" 159.711,90.907 r270 top
R652 "1MR" "RES 0402/1005 RF" 190.551,103.086 r90 top
R653 "20R" "RES 0402/1005 RF" 162.471,85.273 r270 top
R654 "100R" "RES 0402/1005 RF" 197.04,99.06 r180 top
R655 "10kR" "RES 0402/1005 RF" 190.475,99.251 r270 top
R656 "10kR" "RES 0402/1005 RF" 157.594,84.455 r270 top
R657 "100R" "RES 0402/1005 RF" 170.155,82.258 r270 top
R658 "10kR" "RES 0402/1005 RF" 163.957,81.597 r270 top
R659 "10kR" "RES 0402/1005 RF" 253.593,299.297 r90 top
R660 "10kR" "RES 0402/1005 RF" 239.704,286.758 r270 top
R661 "10kR" "RES 0402/1005 RF" 252.23,299.297 r90 top
R662 "10kR" "RES 0402/1005 RF" 245.102,286.758 r270 top
R663 "10kR" "RES 0402/1005 RF" 259.161,299.297 r90 top
R664 "10kR" "RES 0402/1005 RF" 241.054,286.758 r270 top
R665 "0mR" "RES 0402/1005 RF" 39.014,209.378 r270 top
R666 "12mR" "RES 1206/3216" 45.266,205.057 r90 top
R667 "24.9kR" "RES 0402/1005 RF" 42.528,202.265 r180 top
R668 "20kR" "RES 0402/1005 RF" 124.777,232.245 r0 top
R669 "0mR" "RES 0402/1005 RF" 38.887,200.381 r270 top
R670 "0mR" "RES 0402/1005 RF" 37.668,200.388 r270 top
R671 "1.87kR" "RES 0402/1005 RF" 218.007,323.545 r0 top
R672 "1.5kR" "RES 0402/1005 RF" 254.433,334.124 r0 top
R673 "1.87kR" "RES 0402/1005 RF" 241.467,334.124 r0 top
R674 "15kR" "RES 0402/1005 RF" 232.818,334.124 r0 top
R675 "0mR" "RES 0402/1005 RF" 203.34,235.819 r90 top
R676 "20kR" "RES 0402/1005 RF" 233.582,321.424 r0 top
R677 "95.3kR" "RES 0402/1005 RF" 44.716,192.483 r270 top
R678 "95.3kR" "RES 0402/1005 RF" 43.658,192.483 r270 top
R679 "95.3kR" "RES 0402/1005 RF" 45.775,195.483 r90 top
R680 "95.3kR" "RES 0402/1005 RF" 43.658,195.483 r90 top
R681 "24.9kR" "RES 0402/1005 RF" 51.568,194.019 r180 top
R682 "7.5kR" "RES 0402/1005 RF" 45.775,192.483 r90 top
R683 "4.87kR" "RES 0402/1005 RF" 42.6,192.483 r90 top
R684 "7.15kR" "RES 0402/1005 RF" 44.716,195.483 r270 top
R685 "5.9kR" "RES 0402/1005 RF" 42.6,195.483 r270 top
R686 "412kR" "RES 0402/1005 RF" 56.27,215.062 r90 top
R687 "57.6kR" "RES 0402/1005 RF" 61.953,210.719 r270 top
R688 "0mR" "RES 0402/1005 RF" 249.503,302.335 r90 top
R689 "20kR" "RES 0402/1005 RF" 160.795,347.612 r90 top
R690 "100kR" "RES 0402/1005 RF" 159.652,347.612 r90 top
R691 "20kR" "RES 0402/1005 RF" 151.692,347.358 r0 top
R692 "0R" "RES 0402/1005 RF" 130.658,157.905 r90 bottom
R693 "0mR" "RES 0402/1005 RF" 12.006,532.943 r90 top
R694 "1kR" "RES 0402/1005 RF" 231.723,323.635 r90 top
R695 "100R" "RES 0402/1005 RF" 165.024,277.812 r90 top
R696 "0mR" "RES 0402/1005 RF" 132.563,342.99 r90 top
R697 "0mR" "RES 0402/1005 RF" 144.564,173.32 r90 top
R698 "0mR" "RES 0402/1005 RF" 143.497,173.371 r90 top
R699 "0mR" "RES 0402/1005 RF" 146.888,175.727 r90 top
R700 "0mR" "RES 0402/1005 RF" 145.821,175.803 r90 top
R701 "0mR" "RES 0402/1005 RF" 144.513,175.777 r90 top
R702 "0mR" "RES 0402/1005 RF" 143.129,175.828 r90 top
R709 "2.2kR" "RES 0402/1005 RF" 108.074,271.544 r90 bottom
R710 "10kR" "RES 0402/1005 RF" 41.77,327.208 r90 bottom
R711 "0mR" "RES 0402/1005 RF" 43.015,324.904 r270 bottom
R712 "0mR" "RES 0402/1005 RF" 41.681,325.044 r90 bottom
R713 "0mR" "RES 0402/1005 RF" 40.157,324.071 r90 bottom
R714 "2.2kR" "RES 0402/1005 RF" 39.383,327.431 r270 bottom
R715 "10kR" "RES 0402/1005 RF" 51.918,326.699 r90 bottom
R716 "261R" "RES 0402/1005 RF" 188.534,364.122 r180 bottom
R717 "261R" "RES 0402/1005 RF" 188.4,361.874 r180 bottom
R718 "261R" "RES 0402/1005 RF" 188.402,360.134 r180 bottom
R719 "261R" "RES 0402/1005 RF" 188.445,356.362 r180 bottom
R720 "261R" "RES 0402/1005 RF" 188.318,358.254 r180 bottom
R721 "10k" "RES 0402/1005 RF" 84.925,322.129 r180 top
R722 "0R" "RES 0402/1005 RF" 45.441,393.213 r0 top
R723 "0R" "RES 0402/1005 RF" 47.701,393.213 r180 top
R724 "0R" "RES 0402/1005 RF" 45.441,392.074 r0 top
R725 "0R" "RES 0402/1005 RF" 47.701,392.074 r180 top
R726 "0R" "RES 0402/1005 RF" 45.441,388.824 r0 top
R727 "0R" "RES 0402/1005 RF" 47.701,388.824 r180 top
R728 "0R" "RES 0402/1005 RF" 45.441,387.686 r0 top
R729 "0R" "RES 0402/1005 RF" 47.701,387.686 r180 top
R730 "4.7kR" "RES 0402/1005 RF" 195.016,209.369 r180 top
R731 "4.7kR" "RES 0402/1005 RF" 195.016,199.209 r180 top
R732 "4.7kR" "RES 0402/1005 RF" 195.016,201.749 r180 top
R733 "4.7kR" "RES 0402/1005 RF" 195.016,204.289 r180 top
R734 "4.7kR" "RES 0402/1005 RF" 195.016,206.829 r180 top
R735 "10kR" "RES 0402/1005 RF" 254.956,299.297 r90 top
R736 "10kR" "RES 0402/1005 RF" 246.452,286.758 r270 top
R737 "10kR" "RES 0402/1005 RF" 201.651,239.547 r90 top
R738 "1kR" "RES 0402/1005 RF" 340.627,352.9 r90 top
R739 "1kR" "RES 0402/1005 RF" 338.995,352.931 r90 top
R740 "1kR" "RES 0402/1005 RF" 339.014,357.079 r90 top
R741 "1kR" "RES 0402/1005 RF" 340.563,357.244 r90 top
R742 "1kR" "RES 0402/1005 RF" 338.847,349.662 r90 top
R743 "1kR" "RES 0402/1005 RF" 337.4,349.535 r90 top
R744 "0mR" "RES 0402/1005 RF" 253.593,302.335 r90 top
R745 "20kR" "RES 0402/1005 RF" 153.962,285.28 r90 top
R746 "10kR" "RES 0402/1005 RF" 116.954,264.955 r90 bottom
R747 "10kR" "RES 0402/1005 RF" 118.053,264.955 r90 bottom
R748 "10kR" "RES 0402/1005 RF" 119.151,264.955 r90 bottom
R749 "10kR" "RES 0402/1005 RF" 120.25,264.955 r90 bottom
R750 "10kR" "RES 0402/1005 RF" 121.349,264.955 r90 bottom
R751 "10kR" "RES 0402/1005 RF" 126.486,261.823 r0 bottom
R752 "10kR" "RES 0402/1005 RF" 126.486,260.731 r0 bottom
R753 "10kR" "RES 0402/1005 RF" 126.486,259.639 r0 bottom
R754 "10kR" "RES 0402/1005 RF" 126.486,258.547 r0 bottom
R755 "10kR" "RES 0402/1005 RF" 126.486,257.454 r0 bottom
R756 "10kR" "RES 0402/1005 RF" 126.487,256.362 r0 bottom
R757 "10kR" "RES 0402/1005 RF" 120.853,253.53 r270 bottom
R758 "1kR" "RES 0402/1005 RF" 111.531,261.714 r90 top
R759 "0mR" "RES 0402/1005 RF" 112.573,261.722 r90 top
R760 "1kR" "RES 0402/1005 RF" 106.832,262.537 r90 top
R761 "0mR" "RES 0402/1005 RF" 105.57,262.522 r90 top
R762 "1kR" "RES 0402/1005 RF" 109.523,261.878 r90 top
R763 "0mR" "RES 0402/1005 RF" 108.284,261.989 r90 top
R764 "WSHP28184L000FEA" WSHP2818 101.381,224.041 r0 bottom
R765 "10kR" "RES 0402/1005 RF" 250.866,299.297 r90 top
R766 "10kR" "RES 0402/1005 RF" 242.403,286.758 r270 top
R767 "0mR" "RES 0402/1005 RF" 252.23,302.335 r90 top
R768 "0mR" "RES 0402/1005 RF" 118.333,299.102 r0 top
R769 "0mR" "RES 0402/1005 RF" 118.333,300.612 r0 top
R770 "0mR" "RES 0402/1005 RF" 118.333,302.122 r0 top
R771 "0mR" "RES 0402/1005 RF" 118.333,303.632 r0 top
R772 "0mR" "RES 0402/1005 RF" 95.331,345.084 r90 top
R773 "0mR" "RES 0402/1005 RF" 94.055,345.231 r90 top
R774 "0mR" "RES 0402/1005 RF" 260.697,339.555 r90 top
R775 "0mR" "RES 0402/1005 RF" 259.613,339.758 r90 top
R776 "0mR" "RES 0402/1005 RF" 123.35,310.032 r180 top
R777 "0mR" "RES 0402/1005 RF" 123.348,310.985 r0 top
R778 "0mR" "RES 0402/1005 RF" 123.402,306.612 r180 top
R779 "0mR" "RES 0402/1005 RF" 123.399,307.539 r0 top
R780 "0mR" "RES 0402/1005 RF" 203.378,398.335 r90 top
R781 "0mR" "RES 0402/1005 RF" 96.114,302.489 r0 top
R782 "0mR" "RES 0402/1005 RF" 133.883,341.325 r0 bottom
R783 "0mR" "RES 0402/1005 RF" 196.911,75.59 r90 top
R784 "0mR" "RES 0402/1005 RF" 4.957,291.694 r270 top
R785 "0mR" "RES 0402/1005 RF" 6.537,291.694 r270 top
R786 "0mR" "RES 0402/1005 RF" 8.117,291.694 r270 top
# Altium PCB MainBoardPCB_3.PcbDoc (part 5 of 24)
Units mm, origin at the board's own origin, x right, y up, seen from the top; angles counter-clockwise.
Board outline 258.95 x 308.86 mm, 16 copper layers (L1, L2 (GND), L3 (Sign), L4 (GND), L5 (Sign), L6 (PWR/GND), L7(PWR/GND), L8 (Plane_GND), L9 (PWR/GND), L10 (PWR/GND), L11 (PWR/GND), L12 (Sign), L13 (GND), L14 (Sign), L15 (GND), L16), stack 2.502 mm thick; 2402 components, 1749 nets, 8407 pads, 3409 vias.
Unrouted connection lines stored in the file: 4352.

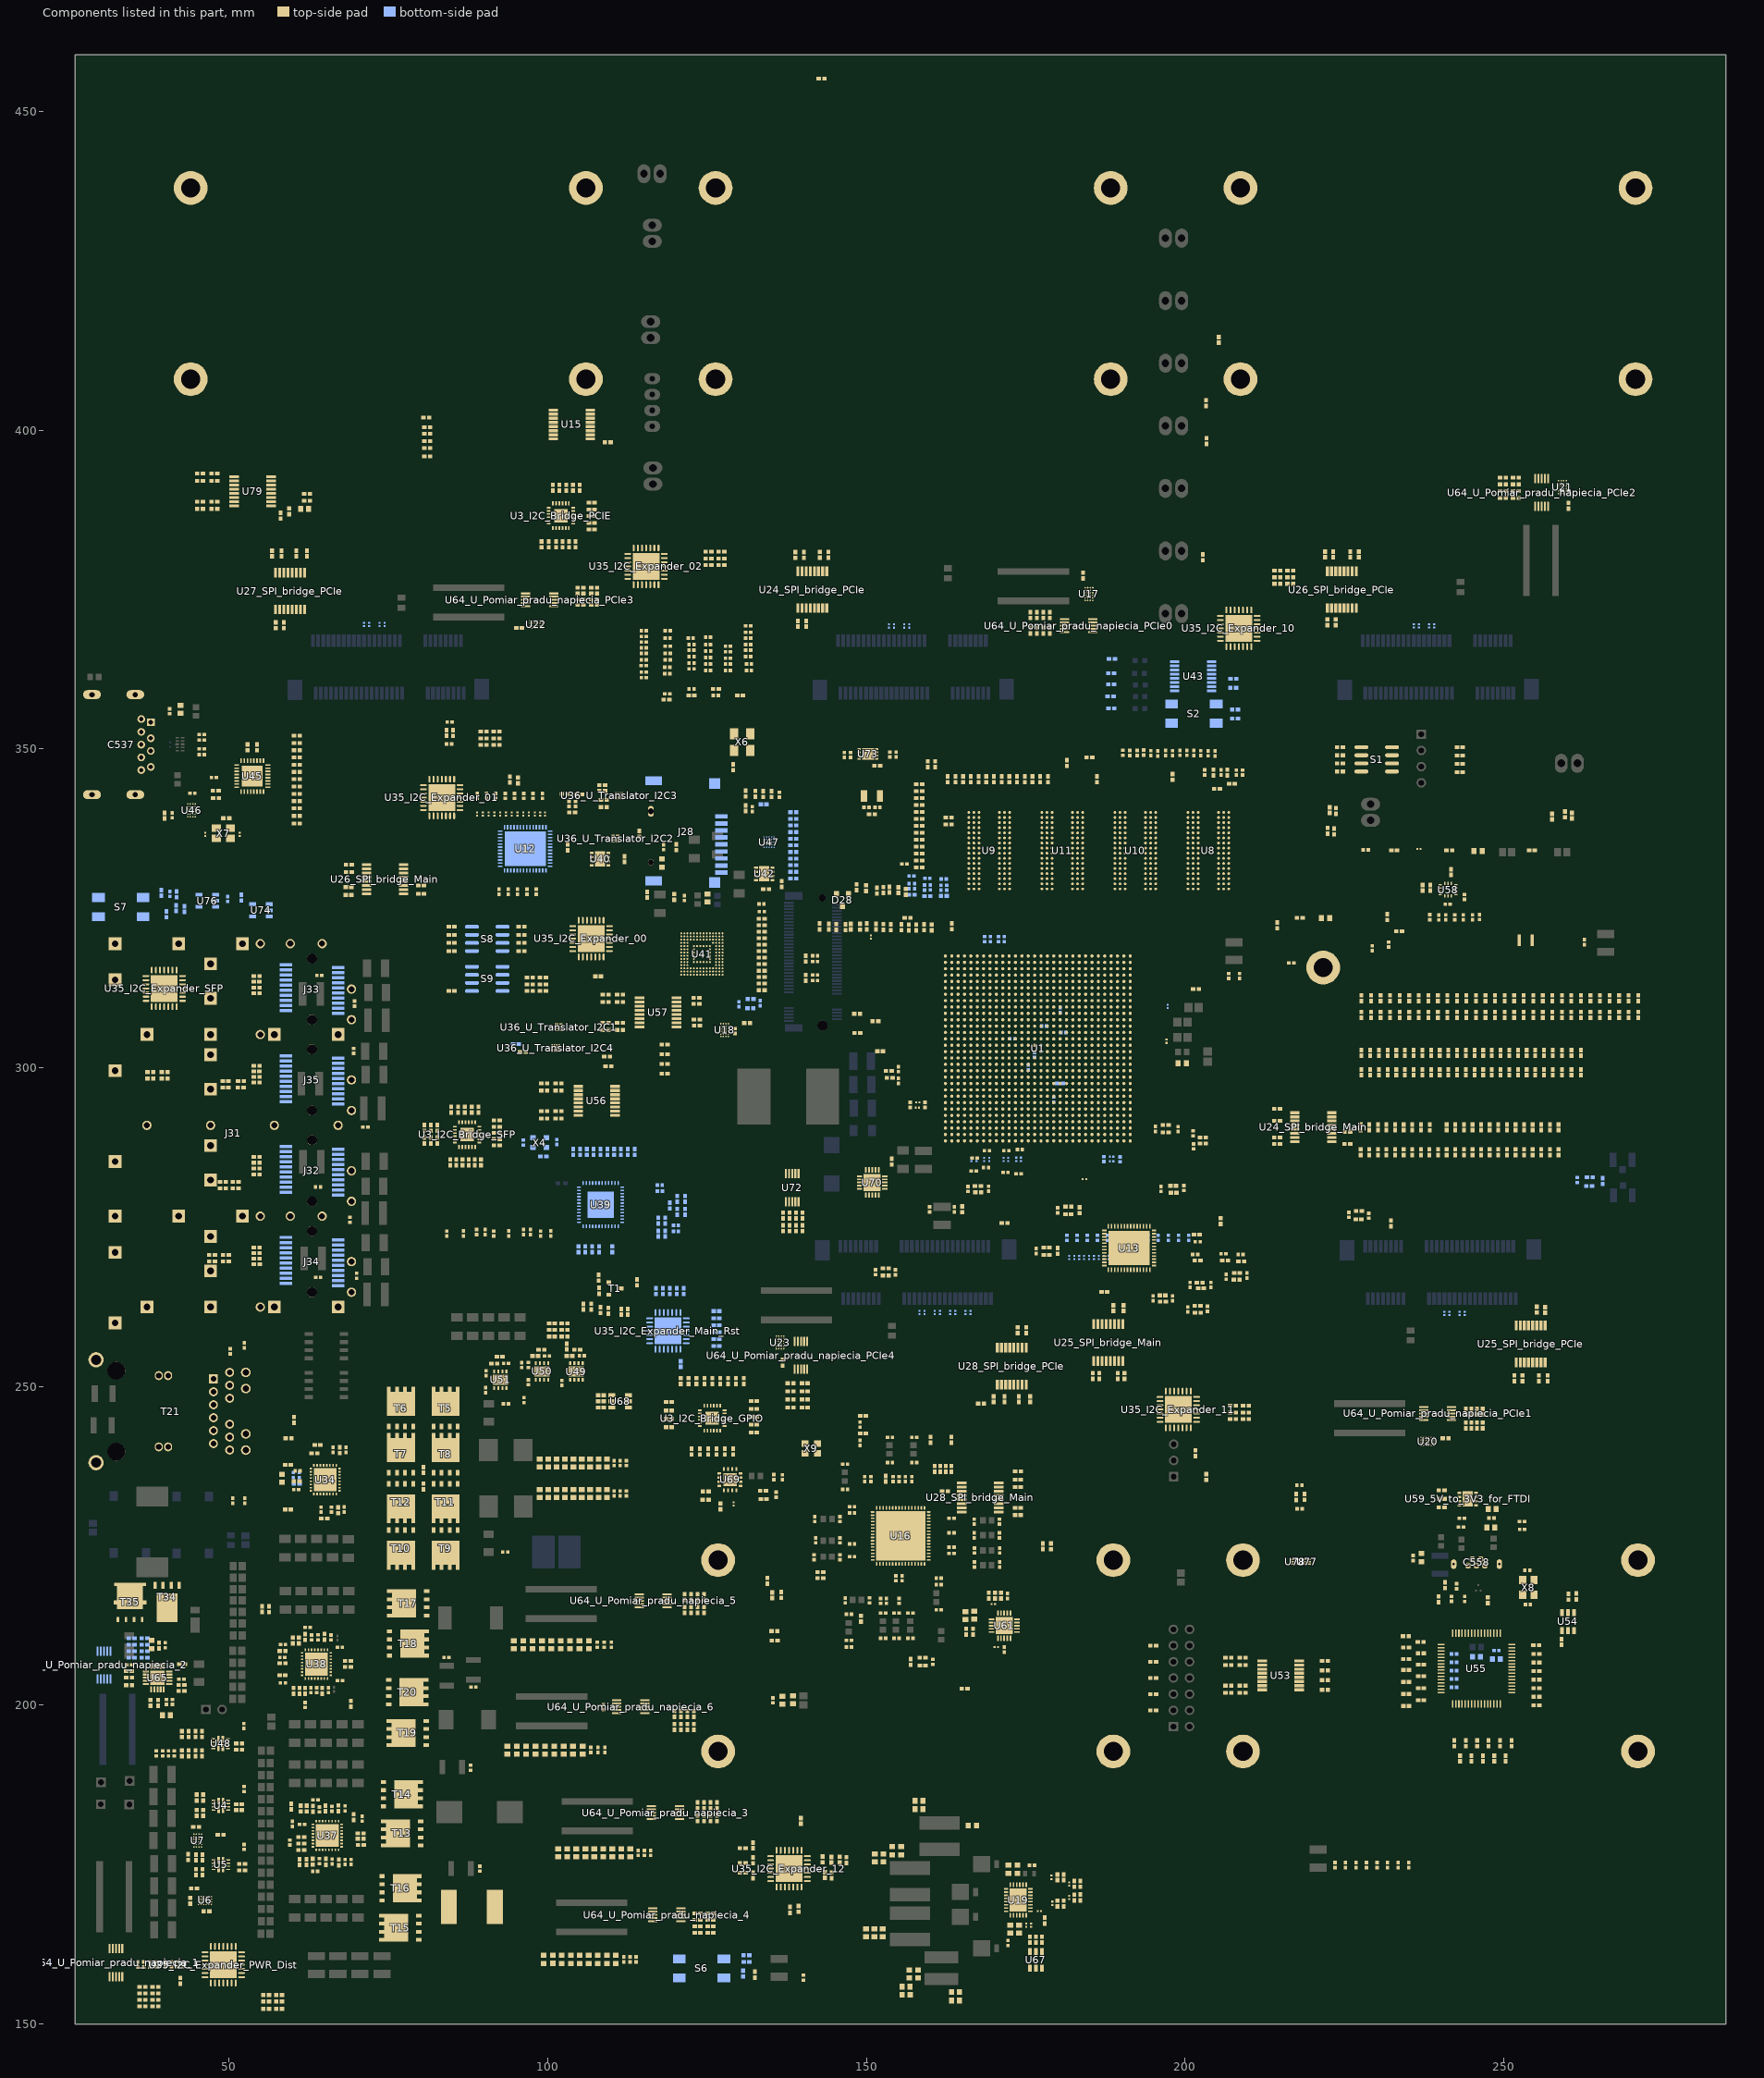
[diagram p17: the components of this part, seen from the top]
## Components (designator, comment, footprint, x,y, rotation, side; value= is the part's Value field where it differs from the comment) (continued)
R787 "0mR" "RES 0402/1005 RF" 9.697,291.694 r270 top
R788 "0mR" "RES 0402/1005 RF" 11.277,291.694 r270 top
R789 "0mR" "RES 0402/1005 RF" 12.856,291.694 r270 top
R790 "0mR" "RES 0402/1005 RF" 17.993,312.153 r90 top
R791 "0mR" "RES 0402/1005 RF" 15.44,311.943 r90 top
R792 "0mR" "RES 0402/1005 RF" 13.129,312.019 r90 top
R793 "0mR" "RES 0402/1005 RF" 10.525,311.79 r90 top
R794 "0mR" "RES 0402/1005 RF" 8.201,312.044 r90 top
R795 "0mR" "RES 0402/1005 RF" 5.559,312.108 r90 top
R796 "0mR" "RES 0402/1005 RF" 203.302,404.261 r270 top
R797 "0mR" "RES 0402/1005 RF" 133.566,313.233 r0 top
R798 "0mR" "RES 0402/1005 RF" 15.537,532.313 r90 top
R799 "0mR" "RES 0402/1005 RF" 17.137,532.359 r90 top
R800 "0mR" "RES 0402/1005 RF" 60.642,339.522 r0 top
R801 "0mR" "RES 0402/1005 RF" 60.643,341.831 r0 top
R802 "0mR" "RES 0402/1005 RF" 60.643,352.103 r0 top
R803 "0mR" "RES 0402/1005 RF" 163.41,322.187 r270 top
R804 "0mR" "RES 0402/1005 RF" 152.166,302.603 r0 top
R805 "0mR" "RES 0402/1005 RF" 205.296,414.185 r270 top
R806 "0mR" "RES 0402/1005 RF" 155.033,327.873 r270 top
R807 "0mR" "RES 0402/1005 RF" 156.189,327.594 r270 top
R808 "0mR" "RES 0402/1005 RF" 152.659,327.889 r90 top
R809 "0mR" "RES 0402/1005 RF" 153.599,327.939 r90 top
R810 "0mR" "RES 0402/1005 RF" 151.63,327.787 r90 top
R811 "0mR" "RES 0402/1005 RF" 108.006,267.081 r90 top
R812 "0mR" "RES 0402/1005 RF" 202.781,380.078 r270 top
R813 "0mR" "RES 0402/1005 RF" 149.953,328.173 r90 top
R814 "0mR" "RES 0402/1005 RF" 148.442,328.339 r90 top
R815 "0mR" "RES 0402/1005 RF" 104.005,286.787 r90 bottom
R816 "0mR" "RES 0402/1005 RF" 105.075,286.787 r90 bottom
R817 "10kR" "RES 0402/1005 RF" 256.32,299.297 r90 top
R818 "10kR" "RES 0402/1005 RF" 247.801,286.758 r270 top
R819 "0mR" "RES 0402/1005 RF" 259.161,302.335 r90 top
R820 "10kR" "RES 0402/1005 RF" 257.683,299.297 r90 top
R821 "10kR" "RES 0402/1005 RF" 249.151,286.758 r270 top
R822 "0mR" "RES 0402/1005 RF" 254.956,302.335 r90 top
R823 "10kR" "RES 0402/1005 RF" 228.908,286.758 r90 top
R824 "10kR" "RES 0402/1005 RF" 255.898,286.758 r270 top
R825 "100kR" "RES 0402/1005 RF" 138.027,167.899 r90 top
R826 "10kR" "RES 0402/1005 RF" 139.36,168.061 r90 top
R827 "10kR" "RES 0402/1005 RF" 139.713,181.871 r270 top
R828 "100kR" "RES 0402/1005 RF" 42.342,156.794 r90 top
R835 "10kR" "RES 0402/1005 RF" 130.607,173.721 r0 top
R836 "10kR" "RES 0402/1005 RF" 130.607,175.221 r0 top
R837 "20kR" "RES 0402/1005 RF" 132.195,173.321 r270 top
R838 "10kR" "RES 0402/1005 RF" 130.607,177.571 r0 top
R839 "20kR" "RES 0402/1005 RF" 132.195,175.671 r90 top
R840 "20kR" "RES 0402/1005 RF" 132.195,178.021 r90 top
R847 "10kR" "RES 0402/1005 RF" 262.116,299.297 r90 top
R848 "10kR" "RES 0402/1005 RF" 253.199,286.758 r270 top
R849 "10kR" "RES 0402/1005 RF" 227.559,286.758 r90 top
R850 "10kR" "RES 0402/1005 RF" 254.549,286.758 r270 top
R851 "0mR" "RES 0402/1005 RF" 250.866,302.335 r90 top
R852 "10kR" "RES 0402/1005 RF" 260.639,299.297 r90 top
R853 "10kR" "RES 0402/1005 RF" 250.5,286.758 r270 top
R854 "0mR" "RES 0402/1005 RF" 256.32,302.335 r90 top
R855 "10kR" "RES 0402/1005 RF" 230.258,286.758 r90 top
R856 "10kR" "RES 0402/1005 RF" 257.248,286.758 r270 top
R857 "0mR" "RES 0402/1005 RF" 257.683,302.335 r90 top
R858 "10kR" "RES 0402/1005 RF" 232.957,286.758 r90 top
R859 "10kR" "RES 0402/1005 RF" 258.597,286.758 r270 top
R860 "0mR" "RES 0402/1005 RF" 228.908,290.66 r90 top
R861 "10kR" "RES 0402/1005 RF" 235.656,286.758 r270 top
R862 "0mR" "RES 0402/1005 RF" 262.116,302.335 r90 top
R863 "0mR" "RES 0402/1005 RF" 227.559,290.66 r90 top
R864 "0mR" "RES 0402/1005 RF" 260.639,302.335 r90 top
R865 "0mR" "RES 0402/1005 RF" 230.258,290.66 r90 top
R866 "0mR" "RES 0402/1005 RF" 232.957,290.66 r90 top
R867 "0mR" "RES 0402/1005 RF" 235.656,290.66 r90 top
R868 "0mR" "RES 0402/1005 RF" 231.607,290.66 r90 top
R869 "0mR" "RES 0402/1005 RF" 237.005,290.66 r90 top
R870 "0mR" "RES 0402/1005 RF" 234.306,290.66 r90 top
R871 "0mR" "RES 0402/1005 RF" 251.85,290.66 r90 top
R872 "0mR" "RES 0402/1005 RF" 243.753,290.66 r90 top
R873 "0mR" "RES 0402/1005 RF" 238.379,290.652 r90 top
R874 "0mR" "RES 0402/1005 RF" 205.575,275.966 r90 top
R875 "0mR" "RES 0402/1005 RF" 245.102,290.66 r90 top
R876 "0mR" "RES 0402/1005 RF" 241.054,290.66 r90 top
R877 "0mR" "RES 0402/1005 RF" 246.452,290.66 r90 top
R878 "0mR" "RES 0402/1005 RF" 242.403,290.66 r90 top
R879 "0mR" "RES 0402/1005 RF" 247.801,290.66 r90 top
R880 "0mR" "RES 0402/1005 RF" 249.151,290.66 r90 top
R881 "0mR" "RES 0402/1005 RF" 255.898,290.66 r90 top
R882 "0mR" "RES 0402/1005 RF" 253.199,290.66 r90 top
R883 "0mR" "RES 0402/1005 RF" 254.549,290.66 r90 top
R884 "0mR" "RES 0402/1005 RF" 250.5,290.66 r90 top
R885 "0mR" "RES 0402/1005 RF" 257.248,290.66 r90 top
R886 "0mR" "RES 0402/1005 RF" 258.597,290.66 r90 top
R887_SPI_bridge_Main "0mR" "RES 0402/1005 RF" 190.488,251.673 r90 top (schematic designator R887)
R887_SPI_bridge_PCIe "0mR" "RES 0402/1005 RF" 256.891,251.289 r90 top (schematic designator R887)
R888_SPI_bridge_Main "0mR" "RES 0402/1005 RF" 68.804,331.84 r180 top (schematic designator R888)
R888_SPI_bridge_PCIe "0mR" "RES 0402/1005 RF" 227.265,380.53 r90 top (schematic designator R888)
R889_SPI_bridge_Main "0mR" "RES 0402/1005 RF" 68.754,328.34 r0 top (schematic designator R889)
R889_SPI_bridge_PCIe "0mR" "RES 0402/1005 RF" 223.24,380.53 r270 top (schematic designator R889)
R890_SPI_bridge_Main "0mR" "RES 0402/1005 RF" 68.804,330.703 r180 top (schematic designator R890)
R890_SPI_bridge_PCIe "0mR" "RES 0402/1005 RF" 225.92,380.53 r90 top (schematic designator R890)
R891_SPI_bridge_Main "0mR" "RES 0402/1005 RF" 68.754,327.115 r0 top (schematic designator R891)
R891_SPI_bridge_PCIe "0mR" "RES 0402/1005 RF" 221.965,380.53 r270 top (schematic designator R891)
R892_SPI_bridge_Main "0mR" "RES 0402/1005 RF" 48.146,483.979 r270 top (schematic designator R892)
R892_SPI_bridge_PCIe "0mR" "RES 0402/1005 RF" 62.238,380.682 r90 top (schematic designator R892)
R893_SPI_bridge_Main "0mR" "RES 0402/1005 RF" 52.534,483.929 r90 top (schematic designator R893)
R893_SPI_bridge_PCIe "0mR" "RES 0402/1005 RF" 58.229,380.683 r270 top (schematic designator R893)
R894_SPI_bridge_Main "0mR" "RES 0402/1005 RF" 49.284,483.979 r270 top (schematic designator R894)
R894_SPI_bridge_PCIe "0mR" "RES 0402/1005 RF" 60.563,380.683 r90 top (schematic designator R894)
R895_SPI_bridge_Main "0mR" "RES 0402/1005 RF" 53.673,483.979 r90 top (schematic designator R895)
R895_SPI_bridge_PCIe "0mR" "RES 0402/1005 RF" 56.733,380.682 r270 top (schematic designator R895)
R896_SPI_bridge_Main "0mR" "RES 0402/1005 RF" 173.78,229.85 r0 top (schematic designator R896)
R896_SPI_bridge_PCIe "0mR" "RES 0402/1005 RF" 169.964,248.006 r270 top (schematic designator R896)
R897_SPI_bridge_Main "0mR" "RES 0402/1005 RF" 173.78,234.238 r180 top (schematic designator R897)
R897_SPI_bridge_PCIe "0mR" "RES 0402/1005 RF" 173.938,248.006 r90 top (schematic designator R897)
R898_SPI_bridge_Main "0mR" "RES 0402/1005 RF" 173.78,230.988 r0 top (schematic designator R898)
R898_SPI_bridge_PCIe "0mR" "RES 0402/1005 RF" 171.673,248.006 r270 top (schematic designator R898)
R899_SPI_bridge_Main "0mR" "RES 0402/1005 RF" 173.78,235.377 r180 top (schematic designator R899)
R899_SPI_bridge_PCIe "0mR" "RES 0402/1005 RF" 175.706,248.006 r90 top (schematic designator R899)
R900 "0mR" "RES 0402/1005 RF" 64.41,534.619 r180 top
R901 "0mR" "RES 0402/1005 RF" 147.558,322.143 r270 top
R902 "0mR" "RES 0402/1005 RF" 142.681,322.181 r270 top
R903 "0mR" "RES 0402/1005 RF" 150.047,322.181 r270 top
R904 "0mR" "RES 0402/1005 RF" 145.274,322.087 r270 top
R905 "0mR" "RES 0402/1005 RF" 152.652,322.087 r270 top
R906 "0mR" "RES 0402/1005 RF" 148.995,322.11 r270 top
R907 "0mR" "RES 0402/1005 RF" 144.118,322.148 r270 top
R908 "0mR" "RES 0402/1005 RF" 151.484,322.148 r270 top
R909 "0mR" "RES 0402/1005 RF" 146.71,322.054 r270 top
R910 "0mR" "RES 0402/1005 RF" 153.822,322.054 r270 top
R911 "0mR" "RES 0402/1005 RF" 131.039,343.002 r270 top
R912 "0R" "RES 0402/1005 RF" 163.356,237.089 r270 top
R913 "0mR" "RES 0402/1005 RF" 155.51,322.041 r270 top
R914 "0mR" "RES 0402/1005 RF" 159.053,322.054 r270 top
R915 "0mR" "RES 0402/1005 RF" 156.666,322.028 r270 top
R916 "0mR" "RES 0402/1005 RF" 157.834,322.028 r270 top
R917 "0mR" "RES 0402/1005 RF" 160.249,322.016 r270 top
R918 "0mR" "RES 0402/1005 RF" 109.537,300.253 r180 top
R919 "0mR" "RES 0402/1005 RF" 109.306,301.777 r180 top
R920 "240R" "RES 0402/1005 RF" 201.71,312.356 r0 top
R921 "10kR" "RES 0402/1005 RF" 229.053,299.297 r90 top
R922 "10kR" "RES 0402/1005 RF" 256.128,308.301 r270 top
R923 "10kR" "RES 0402/1005 RF" 238.596,299.297 r90 top
R924 "10kR" "RES 0402/1005 RF" 257.625,308.301 r270 top
R925 "10kR" "RES 0402/1005 RF" 263.613,308.301 r90 top
R926 "10kR" "RES 0402/1005 RF" 253.134,308.301 r270 top
R927 "10kR" "RES 0402/1005 RF" 237.233,299.297 r90 top
R928 "10kR" "RES 0402/1005 RF" 254.631,308.301 r270 top
R929 "10kR" "RES 0402/1005 RF" 266.607,308.301 r90 top
R930 "10kR" "RES 0402/1005 RF" 251.637,308.301 r270 top
R931 "10kR" "RES 0402/1005 RF" 265.11,308.301 r90 top
R932 "10kR" "RES 0402/1005 RF" 250.14,308.301 r270 top
R933 "10kR" "RES 0402/1005 RF" 271.098,308.301 r90 top
R934 "10kR" "RES 0402/1005 RF" 227.686,308.301 r270 top
R935 "10kR" "RES 0402/1005 RF" 268.104,308.301 r90 top
R936 "10kR" "RES 0402/1005 RF" 229.183,308.301 r270 top
R937 "10kR" "RES 0402/1005 RF" 269.601,308.301 r90 top
R938 "10kR" "RES 0402/1005 RF" 227.69,299.297 r270 top
R939 "10kR" "RES 0402/1005 RF" 262.116,308.301 r90 top
R940 "10kR" "RES 0402/1005 RF" 241.159,308.301 r270 top
R941 "10kR" "RES 0402/1005 RF" 260.619,308.301 r90 top
R942 "10kR" "RES 0402/1005 RF" 245.649,308.301 r270 top
R943 "10kR" "RES 0402/1005 RF" 259.122,308.301 r90 top
R944 "10kR" "RES 0402/1005 RF" 238.165,308.301 r270 top
R945 "10kR" "RES 0402/1005 RF" 234.506,299.297 r90 top
R946 "10kR" "RES 0402/1005 RF" 235.171,308.301 r270 top
R947 "10kR" "RES 0402/1005 RF" 235.87,299.297 r90 top
R948 "10kR" "RES 0402/1005 RF" 236.668,308.301 r270 top
R949 "10kR" "RES 0402/1005 RF" 233.143,299.297 r90 top
R950 "10kR" "RES 0402/1005 RF" 239.662,308.301 r270 top
R951 "10kR" "RES 0402/1005 RF" 244.05,299.297 r90 top
R952 "10kR" "RES 0402/1005 RF" 233.674,308.301 r270 top
R953 "10kR" "RES 0402/1005 RF" 230.416,299.297 r90 top
R954 "10kR" "RES 0402/1005 RF" 230.68,308.301 r270 top
R955 "10kR" "RES 0402/1005 RF" 231.78,299.297 r90 top
R956 "10kR" "RES 0402/1005 RF" 232.177,308.301 r270 top
R957 "10kR" "RES 0402/1005 RF" 244.153,308.301 r90 top
R958 "10kR" "RES 0402/1005 RF" 247.146,308.301 r270 top
R959 "10kR" "RES 0402/1005 RF" 242.656,308.301 r90 top
R960 "10kR" "RES 0402/1005 RF" 248.643,308.301 r270 top
R961 "0mR" "RES 0402/1005 RF" 229.053,302.335 r90 top
R962 "0mR" "RES 0402/1005 RF" 238.596,302.335 r90 top
R963 "0mR" "RES 0402/1005 RF" 263.613,310.913 r90 top
R964 "0mR" "RES 0402/1005 RF" 237.233,302.335 r90 top
R965 "0mR" "RES 0402/1005 RF" 266.607,310.913 r90 top
R966 "0mR" "RES 0402/1005 RF" 265.11,310.913 r90 top
R967 "0mR" "RES 0402/1005 RF" 271.098,310.913 r90 top
R968 "0mR" "RES 0402/1005 RF" 268.104,310.913 r90 top
R969 "0mR" "RES 0402/1005 RF" 269.601,310.913 r90 top
R970 "0mR" "RES 0402/1005 RF" 262.116,310.913 r90 top
R971 "0mR" "RES 0402/1005 RF" 260.619,310.913 r90 top
R972 "0mR" "RES 0402/1005 RF" 259.122,310.913 r90 top
R973 "0mR" "RES 0402/1005 RF" 234.506,302.335 r90 top
R974 "0mR" "RES 0402/1005 RF" 235.87,302.335 r90 top
R975 "0mR" "RES 0402/1005 RF" 233.143,302.335 r90 top
R976 "0mR" "RES 0402/1005 RF" 244.05,302.335 r90 top
R977 "0mR" "RES 0402/1005 RF" 230.416,302.335 r90 top
R978 "0mR" "RES 0402/1005 RF" 231.78,302.335 r90 top
R979 "0mR" "RES 0402/1005 RF" 244.152,310.913 r90 top
R980 "0mR" "RES 0402/1005 RF" 242.655,310.913 r90 top
R981 "0mR" "RES 0402/1005 RF" 256.128,310.913 r90 top
R982 "0mR" "RES 0402/1005 RF" 257.625,310.913 r90 top
R983 "0mR" "RES 0402/1005 RF" 253.134,310.913 r90 top
R984 "0mR" "RES 0402/1005 RF" 254.631,310.913 r90 top
R985 "0mR" "RES 0402/1005 RF" 251.637,310.913 r90 top
R986 "0mR" "RES 0402/1005 RF" 250.14,310.913 r90 top
R987 "0mR" "RES 0402/1005 RF" 227.686,310.913 r90 top
R988 "0mR" "RES 0402/1005 RF" 229.183,310.913 r90 top
R989 "0mR" "RES 0402/1005 RF" 227.69,302.335 r90 top
R990 "0mR" "RES 0402/1005 RF" 241.158,310.913 r90 top
R991 "0mR" "RES 0402/1005 RF" 245.649,310.913 r90 top
R992 "0mR" "RES 0402/1005 RF" 238.164,310.913 r90 top
R993 "0mR" "RES 0402/1005 RF" 235.17,310.913 r90 top
R994 "0mR" "RES 0402/1005 RF" 236.667,310.913 r90 top
R995 "0mR" "RES 0402/1005 RF" 239.661,310.913 r90 top
R996 "0mR" "RES 0402/1005 RF" 233.674,310.913 r90 top
R997 "0mR" "RES 0402/1005 RF" 230.68,310.913 r90 top
R998 "0mR" "RES 0402/1005 RF" 232.177,310.913 r90 top
R999 "0mR" "RES 0402/1005 RF" 247.146,310.913 r90 top
R1000 "0mR" "RES 0402/1005 RF" 248.643,310.913 r90 top
R1001 "0R" "RES 0402/1005 RF" 84.925,318.319 r0 top
R1002 "10kR" "RES 0402/1005 RF" 113.987,266.344 r90 top
R1003 "10kR" "RES 0402/1005 RF" 108.056,265.024 r90 top
R1004 "0R" "RES 0402/1005 RF" 237.021,202.666 r180 top
R1005 "0R" "RES 0402/1005 RF" 234.71,201.769 r180 top
R1006 "0R" "RES 0402/1005 RF" 237.021,200.787 r180 top
R1007 "0R" "RES 0402/1005 RF" 234.71,199.885 r180 top
R1008 "0R" "RES 0402/1005 RF" 242.252,194.037 r270 top
R1009 "0R" "RES 0402/1005 RF" 243.154,191.651 r270 top
R1010 "0R" "RES 0402/1005 RF" 245.839,194.037 r270 top
R1011 "0R" "RES 0402/1005 RF" 246.729,191.651 r270 top
R1012 "0R" "RES 0402/1005 RF" 247.632,194.037 r270 top
R1013 "0R" "RES 0402/1005 RF" 248.517,191.651 r270 top
R1014 "0R" "RES 0402/1005 RF" 249.425,194.037 r270 top
R1015 "0R" "RES 0402/1005 RF" 250.304,191.651 r270 top
R1016 "0R" "RES 0402/1005 RF" 255.143,201.329 r0 top
R1017 "0R" "RES 0402/1005 RF" 255.143,202.671 r0 top
R1018 "0R" "RES 0402/1005 RF" 255.143,204.013 r0 top
R1019 "0R" "RES 0402/1005 RF" 255.143,205.355 r0 top
R1020 "0R" "RES 0402/1005 RF" 255.143,206.697 r0 top
R1021 "0R" "RES 0402/1005 RF" 255.143,208.039 r0 top
R1022 "0R" "RES 0402/1005 RF" 59.416,387.29 r270 top
R1023 "0R" "RES 0402/1005 RF" 62.236,390.03 r0 top
R1024 "0R" "RES 0402/1005 RF" 58.095,386.605 r270 top
R1025 "0R" "RES 0402/1005 RF" 62.248,388.963 r0 top
R1026 "0R" "RES 0402/1005 RF" 221.963,206.983 r0 top
R1027 "0R" "RES 0402/1005 RF" 221.963,205.466 r0 top
R1028 "0R" "RES 0402/1005 RF" 221.963,203.95 r0 top
R1029 "0R" "RES 0402/1005 RF" 221.963,202.433 r0 top
R1030 "0R" "RES 0402/1005 RF" 239.789,216.631 r90 top
R1031 "0R" "RES 0402/1005 RF" 234.647,210.844 r180 top
R1032 "0R" "RES 0402/1005 RF" 236.983,209.955 r180 top
R1033 "0R" "RES 0402/1005 RF" 234.672,209.066 r180 top
R1034 "0R" "RES 0402/1005 RF" 237.009,208.152 r180 top
R1035 "0R" "RES 0402/1005 RF" 234.685,207.263 r180 top
R1036 "0R" "RES 0402/1005 RF" 237.021,206.387 r180 top
R1037 "0R" "RES 0402/1005 RF" 234.71,205.536 r180 top
R1038 "0R" "RES 0402/1005 RF" 237.021,204.545 r180 top
R1039 "0R" "RES 0402/1005 RF" 234.71,203.652 r180 top
R1040 "0R" "RES 0402/1005 RF" 112.563,286.787 r270 bottom
R1041 "0R" "RES 0402/1005 RF" 110.424,286.787 r270 bottom
R1042 "0R" "RES 0402/1005 RF" 107.214,286.787 r270 bottom
R1043 "0R" "RES 0402/1005 RF" 108.284,286.787 r270 bottom
R1044 "0R" "RES 0402/1005 RF" 244.046,194.037 r270 top
R1045 "0R" "RES 0402/1005 RF" 244.942,191.651 r270 top
R1046 "0R" "RES 0402/1005 RF" 251.219,194.037 r270 top
R1047 "0R" "RES 0402/1005 RF" 255.143,199.987 r0 top
R1048 "1kR" "RES 0402/1005 RF" 95.891,318.319 r180 top
R1049 "1kR" "RES 0402/1005 RF" 95.89,319.589 r180 top
R1050 "1kR" "RES 0402/1005 RF" 95.891,320.859 r180 top
R1051 "1kR" "RES 0402/1005 RF" 95.891,322.129 r180 top
R1052 "1kR" "RES 0402/1005 RF" 44.495,171.26 r180 top
R1053 "1kR" "RES 0402/1005 RF" 48.666,179.68 r0 top
R1054 "0mR" "RES 0402/1005 RF" 208.826,269.653 r0 top
R1055 "0mR" "RES 0402/1005 RF" 206.299,269.78 r0 top
R1056 "0mR" "RES 0402/1005 RF" 201.968,269.78 r0 top
R1057 "0mR" "RES 0402/1005 RF" 85.119,352.51 r270 top
R1058 "0mR" "RES 0402/1005 RF" 84.125,352.539 r270 top
R1067 "0mR" "RES 0402/1005 RF" 131.818,310.782 r0 bottom
R1068 "0mR" "RES 0402/1005 RF" 131.798,309.334 r0 bottom
R1069 "0mR" "RES 0402/1005 RF" 218.719,232.684 r90 top
R1070 "0mR" "RES 0402/1005 RF" 217.437,232.671 r90 top
R1071 "0mR" "RES 0402/1005 RF" 181.699,278.232 r180 top
R1072 "0mR" "RES 0402/1005 RF" 181.678,277.038 r180 top
R1073 "0mR" "RES 0402/1005 RF" 178.27,271.831 r180 top
R1074 "0mR" "RES 0402/1005 RF" 178.27,270.65 r180 top
R1077 "0mR" "RES 0402/1005 RF" 263.409,281.432 r180 bottom
R1080 "0mR" "RES 0402/1005 RF" 263.512,282.842 r180 bottom
R1083 "0mR" "RES 0402/1005 RF" 158.826,206.235 r180 top
R1084 "0mR" "RES 0402/1005 RF" 158.819,207.467 r180 top
R1085 "0mR" "RES 0402/1005 RF" 202.802,288.148 r0 top
R1086 "0mR" "RES 0402/1005 RF" 202.802,289.069 r0 top
R1087 "0mR" "RES 0402/1005 RF" 153.525,299.515 r180 top
R1088 "0mR" "RES 0402/1005 RF" 153.658,298.448 r180 top
R1089 "0mR" "RES 0402/1005 RF" 198.222,280.391 r180 top
R1090 "0mR" "RES 0402/1005 RF" 198.145,281.495 r180 top
R1091 "0mR" "RES 0402/1005 RF" 153.052,267.424 r0 top
R1092 "0mR" "RES 0402/1005 RF" 153.052,268.554 r0 top
R1093 "0mR" "RES 0402/1005 RF" 227.292,277.52 r180 top
R1094 "0mR" "RES 0402/1005 RF" 227.236,276.225 r180 top
R1097 "0mR" "RES 0402/1005 RF" 167.564,280.477 r0 top
R1098 "0mR" "RES 0402/1005 RF" 167.5,281.432 r0 top
R1100 "0mR" "RES 0402/1005 RF" 196.956,289.852 r0 top
R1101 "0mR" "RES 0402/1005 RF" 196.956,291.046 r0 top
R1103 "0mR" "RES 0402/1005 RF" 208.152,267.841 r180 top
R1104 "0mR" "RES 0402/1005 RF" 208.095,266.763 r180 top
R1105 "0mR" "RES 0402/1005 RF" 202.311,266.315 r180 top
R1106 "0mR" "RES 0402/1005 RF" 202.494,265.401 r180 top
R1107 "0mR" "RES 0402/1005 RF" 196.481,264.292 r180 top
R1108 "0mR" "RES 0402/1005 RF" 196.519,263.332 r180 top
R1109 "0mR" "RES 0402/1005 RF" 201.972,262.654 r180 top
R1110 "0mR" "RES 0402/1005 RF" 202.022,261.599 r180 top
S1 "SWITCH SLIDE DIP SPST 25MA 24V" SO8_N 230.073,348.386 r180 top
S2 "430181038816" 430181038816 201.397,355.562 r0 bottom
S3 "430181038816" 430181038816 335.205,272.134 r180 bottom
S4 "430181038816" 430181038816 335.205,277.912 r180 bottom
S5 "SWITCH SLIDE DIP SPST 25MA 24V" SO8_N 13.818,222.39 r0 top
S6 "430181038816" 430181038816 124.142,158.737 r180 bottom
S7 "430181038816" 430181038816 33.02,325.209 r0 bottom
S8 "SWITCH SLIDE DIP SPST 25MA 24V" SO8_N 90.513,320.224 r0 bottom
S9 "SWITCH SLIDE DIP SPST 25MA 24V" SO8_N 90.513,313.95 r0 bottom
T1 "SI2342DS-T1-GE3" SI2342DS-T1-GE3 110.546,265.379 r0 top
T5 "BSC080N03LSG" BSC080N03LS 83.977,246.623 r90 top
T6 "BSC080N03LSG" BSC080N03LS 76.977,246.623 r90 top locked
T7 "BSC030N03LS-G" BSC030N03LS 76.977,239.389 r90 top
T8 "BSC030N03LS-G" BSC030N03LS 83.977,239.389 r90 top
T9 "BSC080N03LSG" BSC080N03LS 83.977,224.601 r270 top
T10 "BSC080N03LSG" BSC080N03LS 76.983,224.601 r270 top
T11 "BSC030N03LS-G" BSC030N03LS 83.977,231.864 r270 top
T12 "BSC030N03LS-G" BSC030N03LS 76.977,231.864 r270 top
T13 "BSC080N03LSG" BSC080N03LS 77.142,179.908 r180 top
T14 "BSC030N03LS-G" BSC030N03LS 77.114,186.055 r0 top
T15 "BSC080N03LSG" BSC080N03LS 76.889,165.106 r180 top
T16 "BSC030N03LS-G" BSC030N03LS 76.91,171.285 r0 top
T17 "BSC080N03LSG" BSC080N03LS 78.098,215.984 r180 top
T18 "BSC030N03LS-G" BSC030N03LS 78.073,209.702 r0 top
T19 "BSC080N03LSG" BSC080N03LS 78.029,195.651 r180 top
T20 "BSC030N03LS-G" BSC030N03LS 77.974,202.057 r0 top
T21 "7499511440" 7499511440 37.922,246.126 r90 bottom
T22 "IRLML6401TRPBF" IRLML6401PbF 162.357,99.555 r0 top
T23 "IRLML6401TRPBF" IRLML6401PbF 166.433,99.632 r0 top
T24 "SI2342DS-T1-GE3" SI2342DS-T1-GE3 166.624,95.402 r0 top
T25 "SI2342DS-T1-GE3" SI2342DS-T1-GE3 193.269,107.886 r0 top
T26 "SI2342DS-T1-GE3" SI2342DS-T1-GE3 193.18,103.657 r0 top
T27 "IRLML6401TRPBF" IRLML6401PbF 162.243,90.64 r0 top
T28 "SI2342DS-T1-GE3" SI2342DS-T1-GE3 166.319,91.034 r0 top
T29 "SI2342DS-T1-GE3" SI2342DS-T1-GE3 193.269,99.022 r0 top
T30 "IRLML6401TRPBF" IRLML6401PbF 159.982,84.353 r0 top
T31 "SI2342DS-T1-GE3" SI2342DS-T1-GE3 166.814,81.623 r0 top
T34 "RJK0651DPB-00#J5" RJK0651DPB 40.282,216.141 r270 top
T35 "SIJ482DP-T1-GE3" SiJ482DP 34.455,216.175 r90 top
T36 "SI2342DS-T1-GE3" SI2342DS-T1-GE3 64.933,532.114 r0 top
TP1_I2C_Bridge_GPIO "TestPoint" TestPoint 875.03,180.556 r90 top (schematic designator TP1)
TP1_I2C_Bridge_PCIE "TestPoint" TestPoint 875.03,190.792 r90 top (schematic designator TP1)
TP1_I2C_Bridge_SFP "TestPoint" TestPoint 853.44,201.028 r90 top (schematic designator TP1)
TP2_I2C_Bridge_GPIO "TestPoint" TestPoint 845.566,180.556 r90 top (schematic designator TP2)
TP2_I2C_Bridge_PCIE "TestPoint" TestPoint 845.566,190.792 r90 top (schematic designator TP2)
TP2_I2C_Bridge_SFP "TestPoint" TestPoint 825.259,201.028 r90 top (schematic designator TP2)
TP3_I2C_Bridge_GPIO "TestPoint" TestPoint 816.115,180.556 r90 top (schematic designator TP3)
TP3_I2C_Bridge_PCIE "TestPoint" TestPoint 816.115,190.792 r90 top (schematic designator TP3)
TP3_I2C_Bridge_SFP "TestPoint" TestPoint 797.065,201.028 r90 top (schematic designator TP3)
TP4_I2C_Bridge_GPIO "TestPoint" TestPoint 786.651,180.556 r90 top (schematic designator TP4)
TP4_I2C_Bridge_PCIE "TestPoint" TestPoint 786.651,190.792 r90 top (schematic designator TP4)
TP4_I2C_Bridge_SFP "TestPoint" TestPoint 768.883,201.028 r90 top (schematic designator TP4)
TP5_I2C_Bridge_GPIO "TestPoint" TestPoint 757.199,180.556 r90 top (schematic designator TP5)
TP5_I2C_Bridge_PCIE "TestPoint" TestPoint 757.199,190.792 r90 top (schematic designator TP5)
TP5_I2C_Bridge_SFP "TestPoint" TestPoint 740.689,201.028 r90 top (schematic designator TP5)
TP6_I2C_Bridge_GPIO "TestPoint" TestPoint 727.748,180.556 r90 top (schematic designator TP6)
TP6_I2C_Bridge_PCIE "TestPoint" TestPoint 727.748,190.792 r90 top (schematic designator TP6)
TP6_I2C_Bridge_SFP "TestPoint" TestPoint 712.508,201.028 r90 top (schematic designator TP6)
TP7_I2C_Bridge_GPIO "TestPoint" TestPoint 516.725,180.556 r90 top (schematic designator TP7)
TP7_I2C_Bridge_PCIE "TestPoint" TestPoint 516.725,190.792 r90 top (schematic designator TP7)
TP7_I2C_Bridge_SFP "TestPoint" TestPoint 510.375,201.028 r90 top (schematic designator TP7)
TP8_I2C_Bridge_GPIO "TestPoint" TestPoint 698.284,180.556 r90 top (schematic designator TP8)
TP8_I2C_Bridge_PCIE "TestPoint" TestPoint 698.284,190.792 r90 top (schematic designator TP8)
TP8_I2C_Bridge_SFP "TestPoint" TestPoint 684.327,201.028 r90 top (schematic designator TP8)
TP9_I2C_Bridge_GPIO "TestPoint" TestPoint 668.833,180.556 r90 top (schematic designator TP9)
TP9_I2C_Bridge_PCIE "TestPoint" TestPoint 668.833,190.792 r90 top (schematic designator TP9)
TP9_I2C_Bridge_SFP "TestPoint" TestPoint 656.133,201.028 r90 top (schematic designator TP9)
TP10_I2C_Bridge_GPIO "TestPoint" TestPoint 638.111,180.556 r90 top (schematic designator TP10)
TP10_I2C_Bridge_PCIE "TestPoint" TestPoint 638.111,190.792 r90 top (schematic designator TP10)
TP10_I2C_Bridge_SFP "TestPoint" TestPoint 626.682,201.028 r90 top (schematic designator TP10)
TP11_I2C_Bridge_GPIO "TestPoint" TestPoint 607.631,180.556 r90 top (schematic designator TP11)
TP11_I2C_Bridge_PCIE "TestPoint" TestPoint 607.631,190.792 r90 top (schematic designator TP11)
TP11_I2C_Bridge_SFP "TestPoint" TestPoint 597.484,201.028 r90 top (schematic designator TP11)
TP12_I2C_Bridge_GPIO "TestPoint" TestPoint 576.91,180.556 r90 top (schematic designator TP12)
TP12_I2C_Bridge_PCIE "TestPoint" TestPoint 576.91,190.792 r90 top (schematic designator TP12)
TP12_I2C_Bridge_SFP "TestPoint" TestPoint 568.02,201.028 r90 top (schematic designator TP12)
TP13_I2C_Bridge_GPIO "TestPoint" TestPoint 546.189,180.556 r90 top (schematic designator TP13)
TP13_I2C_Bridge_PCIE "TestPoint" TestPoint 546.189,190.792 r90 top (schematic designator TP13)
TP13_I2C_Bridge_SFP "TestPoint" TestPoint 538.569,201.028 r90 top (schematic designator TP13)
TP14_I2C_Bridge_GPIO "TestPoint" TestPoint 486.004,180.556 r90 top (schematic designator TP14)
TP14_I2C_Bridge_PCIE "TestPoint" TestPoint 486.004,190.792 r90 top (schematic designator TP14)
TP14_I2C_Bridge_SFP "TestPoint" TestPoint 480.924,201.028 r90 top (schematic designator TP14)
TP15_I2C_Bridge_GPIO "TestPoint" TestPoint 458.445,183.172 r90 top (schematic designator TP15)
TP15_I2C_Bridge_PCIE "TestPoint" TestPoint 455.282,190.792 r90 top (schematic designator TP15)
TP15_I2C_Bridge_SFP "TestPoint" TestPoint 471.614,197.193 r90 top (schematic designator TP15)
TP16_I2C_Bridge_GPIO "TestPoint" TestPoint 424.548,180.556 r90 top (schematic designator TP16)
TP16_I2C_Bridge_PCIE "TestPoint" TestPoint 424.548,190.792 r90 top (schematic designator TP16)
TP16_I2C_Bridge_SFP "TestPoint" TestPoint 422.008,201.028 r90 top (schematic designator TP16)
TP17_I2C_Bridge_GPIO "TestPoint" TestPoint 396.837,182.689 r90 top (schematic designator TP17)
TP17_I2C_Bridge_PCIE "TestPoint" TestPoint 393.827,190.792 r90 top (schematic designator TP17)
TP17_I2C_Bridge_SFP "TestPoint" TestPoint 392.557,201.028 r90 top (schematic designator TP17)
TP18_I2C_Bridge_GPIO "TestPoint" TestPoint 412.026,189.916 r90 top (schematic designator TP18)
TP18_I2C_Bridge_PCIE "TestPoint" TestPoint 363.106,190.792 r90 top (schematic designator TP18)
TP18_I2C_Bridge_SFP "TestPoint" TestPoint 372.58,198.709 r90 top (schematic designator TP18)
TP19 "TestPoint" TestPoint 419.456,150.368 r0 top
TP20 "TestPoint" TestPoint 425.945,150.05 r0 top
TP21 "TestPoint" TestPoint 517.385,171.336 r0 top
TP22 "TestPoint" TestPoint 510.019,171.336 r0 top
TP23 "TestPoint" TestPoint 502.653,171.336 r0 top
TP24 "TestPoint" TestPoint 495.287,171.336 r0 top
TP25 "TestPoint" TestPoint 487.921,171.336 r0 top
TP26 "TestPoint" TestPoint 480.555,171.336 r0 top
TP27 "TestPoint" TestPoint 458.47,171.336 r0 top
TP28 "TestPoint" TestPoint 473.202,171.336 r0 top
TP29 "TestPoint" TestPoint 451.104,171.336 r0 top
TP30 "TestPoint" TestPoint 465.836,171.336 r0 top
TP31 "TestPoint" TestPoint 436.816,171.336 r0 top
TP32 "TestPoint" TestPoint 443.738,171.336 r0 top
TP33 "TestPoint" TestPoint 429.45,171.336 r0 top
TP34 "TestPoint" TestPoint 422.084,171.336 r0 top
TP35 "TestPoint" TestPoint 414.719,171.336 r0 top
TP36 "TestPoint" TestPoint 407.352,171.336 r0 top
TP37 "TestPoint" TestPoint 399.986,171.336 r0 top
TP38 "TestPoint" TestPoint 392.633,171.336 r0 top
TP39 "TestPoint" TestPoint 385.267,171.336 r0 top
TP40 "TestPoint" TestPoint 377.901,171.336 r0 top
TP41 "TestPoint" TestPoint 370.967,171.336 r0 top
TP42 "TestPoint" TestPoint 363.601,171.336 r0 top
TP43 "TestPoint" TestPoint 408.8,144.805 r0 top
TP44 "TestPoint" TestPoint 432.41,144.308 r0 top
TP45 "TestPoint" TestPoint 436.27,149.708 r0 top
TP46 "TestPoint" TestPoint 426.39,144.335 r0 top
TP47 "TestPoint" TestPoint 406.07,150.482 r0 top
TP48 "TestPoint" TestPoint 420.332,144.31 r0 top
TP49 "TestPoint" TestPoint 412.902,150.025 r0 top
TP50_SPI_bridge_Main "TestPoint" TestPoint 291.122,487.426 r0 top (schematic designator TP50)
TP50_SPI_bridge_PCIe "TestPoint" TestPoint 641.668,211.264 r90 top (schematic designator TP50)
TP51_SPI_bridge_Main "TestPoint" TestPoint 286.55,477.545 r0 top (schematic designator TP51)
TP51_SPI_bridge_PCIe "TestPoint" TestPoint 610.933,211.264 r90 top (schematic designator TP51)
TP52_SPI_bridge_Main "TestPoint" TestPoint 292.138,481.889 r0 top (schematic designator TP52)
TP52_SPI_bridge_PCIe "TestPoint" TestPoint 579.958,211.264 r90 top (schematic designator TP52)
TP53_SPI_bridge_Main "TestPoint" TestPoint 282.651,489.623 r0 top (schematic designator TP53)
TP53_SPI_bridge_PCIe "TestPoint" TestPoint 548.983,211.264 r90 top (schematic designator TP53)
TP54_SPI_bridge_Main "TestPoint" TestPoint 290.271,494.982 r0 top (schematic designator TP54)
TP54_SPI_bridge_PCIe "TestPoint" TestPoint 517.995,211.264 r90 top (schematic designator TP54)
TP55_SPI_bridge_Main "TestPoint" TestPoint 301.447,496.564 r0 top (schematic designator TP55)
TP55_SPI_bridge_PCIe "TestPoint" TestPoint 487.02,211.264 r90 top (schematic designator TP55)
TP56_SPI_bridge_Main "TestPoint" TestPoint 299.022,490.918 r0 top (schematic designator TP56)
TP56_SPI_bridge_PCIe "TestPoint" TestPoint 456.044,211.264 r90 top (schematic designator TP56)
TP57_SPI_bridge_Main "TestPoint" TestPoint 307.416,496.786 r0 top (schematic designator TP57)
TP57_SPI_bridge_PCIe "TestPoint" TestPoint 425.056,211.264 r90 top (schematic designator TP57)
TP58_SPI_bridge_Main "TestPoint" TestPoint 183.111,230.588 r0 top (schematic designator TP58)
TP58_SPI_bridge_PCIe "TestPoint" TestPoint 394.081,211.264 r90 top (schematic designator TP58)
TP59_SPI_bridge_Main "TestPoint" TestPoint 183.121,235.319 r0 top (schematic designator TP59)
TP59_SPI_bridge_PCIe "TestPoint" TestPoint 415.887,238.595 r90 top (schematic designator TP59)
TP60_U_Translator_I2C1 "TestPoint" TestPoint 304.775,485.33 r0 top (schematic designator TP60)
TP60_U_Translator_I2C2 "TestPoint" TestPoint 396.875,221.501 r90 top (schematic designator TP60)
TP60_U_Translator_I2C3 "TestPoint" TestPoint 313.512,496.341 r0 top (schematic designator TP60)
TP60_U_Translator_I2C4 "TestPoint" TestPoint 310.299,484.721 r0 top (schematic designator TP60)
TP61_U_Translator_I2C1 "TestPoint" TestPoint 282.88,494.703 r0 top (schematic designator TP61)
TP61_U_Translator_I2C2 "TestPoint" TestPoint 414.325,225.006 r90 top (schematic designator TP61)
TP61_U_Translator_I2C3 "TestPoint" TestPoint 291.516,475.577 r0 top (schematic designator TP61)
TP61_U_Translator_I2C4 "TestPoint" TestPoint 282.943,484.886 r0 top (schematic designator TP61)
U1 "FBVB900" "FBVB900 XX" 176.897,303.039 r90 top locked
U3_I2C_Bridge_GPIO "TCA9548" TCA9548 125.813,245.039 r90 top (schematic designator U3)
U3_I2C_Bridge_PCIE "TCA9548" TCA9548 102.07,386.613 r90 top (schematic designator U3)
U3_I2C_Bridge_SFP "TCA9548" TCA9548 87.351,289.514 r90 top (schematic designator U3)
U4 "TPS2121RUXT" TPS212x 48.71,184.321 r270 top
U5 "TPS2121RUXT" TPS212x 48.71,175 r270 top
U6 "FPF2895CUCX" FPF2895C-D 46.21,169.389 r90 top
U7 "FPF2895CUCX" FPF2895C-D 45.075,178.775 r0 top
U8 "MT40A512M16JY" MT40A512M16JY 203.657,334.06 r180 top locked
U9 "MT40A512M16JY" MT40A512M16JY 169.276,334.06 r180 top locked
U10 "MT40A512M16JY" MT40A512M16JY 192.197,334.06 r180 top locked
U11 "MT40A512M16JY" MT40A512M16JY 180.736,334.06 r180 top locked
U12 "LTC6952" LTC6952 96.456,334.353 r270 bottom
U13 "LTC6952" LTC6952 191.223,271.731 r90 top
U15 "SN74AXC4T774PWR" SN74AXC4T774PWR 103.772,400.914 r0 top
U16 "LMK05028" LMK05028 155.372,226.568 r90 top
U17 "FPF2895CUCX" FPF2895C-D 184.921,374.31 r0 top
U18 "FPF2895CUCX" FPF2895C-D 127.753,305.908 r180 top
U19 "LT3504EUFD#PBF" LT3504 173.828,169.45 r0 top
U20 "FPF2895CUCX" FPF2895C-D 238.039,241.407 r270 top
U21 "FPF2895CUCX" FPF2895C-D 259.217,391.084 r180 top
U22 "FPF2895CUCX" FPF2895C-D 98.185,369.548 r90 top
U23 "FPF2895CUCX" FPF2895C-D 136.446,256.924 r180 top
U24_SPI_bridge_Main "SN74AXC4T774PWR" SN74AXC4T774PWR 220.132,290.677 r0 top (schematic designator U24)
U24_SPI_bridge_PCIe "SN74AXC4T774PWR" SN74AXC4T774PWR 141.507,375.007 r270 top (schematic designator U24)
U25_SPI_bridge_Main "SN74AXC4T774PWR" SN74AXC4T774PWR 187.973,256.921 r90 top (schematic designator U25)
U25_SPI_bridge_PCIe "SN74AXC4T774PWR" SN74AXC4T774PWR 254.216,256.667 r90 top (schematic designator U25)
U26_SPI_bridge_Main "SN74AXC4T774PWR" SN74AXC4T774PWR 74.47,329.565 r0 top (schematic designator U26)
U26_SPI_bridge_PCIe "SN74AXC4T774PWR" SN74AXC4T774PWR 224.615,375.007 r270 top (schematic designator U26)
U27_SPI_bridge_Main "SN74AXC4T774PWR" SN74AXC4T774PWR 50.909,489.953 r90 top (schematic designator U27)
U27_SPI_bridge_PCIe "SN74AXC4T774PWR" SN74AXC4T774PWR 59.588,374.79 r270 top (schematic designator U27)
U28_SPI_bridge_Main "SN74AXC4T774PWR" SN74AXC4T774PWR 167.869,232.613 r180 top (schematic designator U28)
U28_SPI_bridge_PCIe "SN74AXC4T774PWR" SN74AXC4T774PWR 172.823,253.178 r90 top (schematic designator U28)
U30 "DAC1220" DAC1220 60.722,490.044 r90 top
U31 "SI53323-B-GM" SI53323-B-GM 41.835,570.628 r270 top
U32 "SI53323-B-GM" SI53323-B-GM 56.404,533.692 r0 top
U33 "CDCM1802RGTT" CDCM1802RGTT 56.535,520.908 r90 top
U34 "ADP1850ACPZ-R7" ADP1850 65.072,235.389 r0 top
U35_I2C_Expander_00 "MCP23017-E/ML" QFN-ML28_N 106.802,320.263 r90 top (schematic designator U35)
U35_I2C_Expander_01 "MCP23017-E/ML" QFN-ML28_N 83.369,342.397 r90 top (schematic designator U35)
U35_I2C_Expander_02 "MCP23017-E/ML" QFN-ML28_N 115.43,378.657 r90 top (schematic designator U35)
U35_I2C_Expander_10 "MCP23017-E/ML" QFN-ML28_N 208.43,368.94 r90 top (schematic designator U35)
U35_I2C_Expander_11 "MCP23017-E/ML" QFN-ML28_N 198.939,246.41 r90 top (schematic designator U35)
U35_I2C_Expander_12 "MCP23017-E/ML" QFN-ML28_N 137.858,174.371 r90 top (schematic designator U35)
U35_I2C_Expander_Main_Rst "MCP23017-E/ML" QFN-ML28_N 118.865,258.742 r90 bottom (schematic designator U35)
U35_I2C_Expander_PWR_CLK "MCP23017-E/ML" QFN-ML28_N 328.528,343.956 r90 top (schematic designator U35)
U35_I2C_Expander_PWR_Dist "MCP23017-E/ML" QFN-ML28_N 49.093,159.303 r0 top (schematic designator U35)
U35_I2C_Expander_SFP "MCP23017-E/ML" QFN-ML28_N 39.827,312.453 r90 top (schematic designator U35)
U36_U_Translator_I2C1 "PCA9306" PCA9306 101.719,306.347 r0 top (schematic designator U36)
U36_U_Translator_I2C2 "PCA9306" PCA9306 110.627,335.941 r0 top (schematic designator U36)
U36_U_Translator_I2C3 "PCA9306" PCA9306 111.214,342.671 r90 top (schematic designator U36)
U36_U_Translator_I2C4 "PCA9306" PCA9306 101.236,303.098 r90 top (schematic designator U36)
U37 "ADP1850ACPZ-R7" ADP1850 65.425,179.567 r0 top
U38 "ADP1850ACPZ-R7" ADP1850 63.703,206.464 r0 top
U39 "DP83867ERGZT" DP83867E 108.299,278.525 r0 bottom
U40 "MCP1727T-ADJE/MF" MCP1727T-ADJE/MF 108.212,332.746 r0 top
U41 "MTFC8GAKAJCN-4MITTR" "MTFC8GAKAJCN-4M IT TR" 124.188,317.841 r270 top locked
U42 "MCP1727T-ADJE/MF" MCP1727T-ADJE/MF 133.976,330.435 r0 top
U43 "SN74AXC4T774PWR" SN74AXC4T774PWR 201.27,361.404 r180 bottom
U44 "MAX16025TE+T" MAX16025TE+T 321.428,277.285 r0 top
U45 "USB3320C-EZK-TR" USB3320 53.64,345.752 r180 top
U46 "FPF2895CUCX" FPF2895C-D 44.117,340.382 r0 top
U47 "IP4856CX25/CZ" IP4856CX25/C 134.729,335.404 r180 bottom locked
U48 "TPS2121RUXT" TPS212x 48.677,193.983 r270 top
U49 "MCP1727T-ADJE/MF" MCP1727T-ADJE/MF 104.495,252.348 r90 top
U50 "MCP1727T-ADJE/MF" MCP1727T-ADJE/MF 99.101,252.371 r90 top
U51 "MCP1727T-ADJE/MF" MCP1727T-ADJE/MF 92.569,251.063 r90 top
U53 "SN74AXC4T774PWR" SN74AXC4T774PWR 215.024,204.708 r0 top
U54 "93LC56BT-I/OT" 93LC56BT 260.071,213.139 r90 top
U55 "FT4232HL-REEL" FT4232HL 245.72,205.766 r270 top
U56 "SN74AXC4T774PWR" SN74AXC4T774PWR 107.683,294.805 r0 top
U57 "SN74AXC4T774PWR" SN74AXC4T774PWR 117.323,308.699 r0 top
U58 "ISM330DHCXTR" ISM330DHCXL 241.257,327.94 r0 top
U59_5V_to_3V3_for_FTDI "MCP1727T-ADJE/MF" MCP1727T-ADJE/MF 244.361,232.359 r180 top (schematic designator U59)
U59_U_5V_to_3V31 "MCP1727T-ADJE/MF" MCP1727T-ADJE/MF 353.828,345.992 r0 top (schematic designator U59)
U59_U_5V_to_3V32 "MCP1727T-ADJE/MF" MCP1727T-ADJE/MF 329.908,326.23 r180 top (schematic designator U59)
U59_U_5V_to_3V33 "MCP1727T-ADJE/MF" MCP1727T-ADJE/MF 328.739,364.249 r0 top (schematic designator U59)
U60 "ADP1741ACPZ-R7" ADP1752_1753/ADP1740_1741 340.769,361.999 r0 top
U61 "TPS7A8801RTJT" TPS7A88 171.628,212.498 r180 top
U62 "LT3042EDD#PBF" LT3042 42.38,506.176 r0 top
U63 "MAX3051EKA+T" "MAX3051EKA+T SOT23" 19.766,528.676 r0 top
U64_U_Pomiar_pradu_napiecia_1 "INA226AIDGSR" INA226 32.245,159.614 r90 top (schematic designator U64)
U64_U_Pomiar_pradu_napiecia_2 "INA226AIDGSR" INA226 30.366,206.311 r270 bottom (schematic designator U64)
U64_U_Pomiar_pradu_napiecia_3 "INA226AIDGSR" INA226 118.478,183.159 r180 top (schematic designator U64)
U64_U_Pomiar_pradu_napiecia_4 "INA226AIDGSR" INA226 118.681,167.127 r180 top (schematic designator U64)
U64_U_Pomiar_pradu_napiecia_5 "INA226AIDGSR" INA226 116.548,216.393 r180 top (schematic designator U64)
U64_U_Pomiar_pradu_napiecia_6 "INA226AIDGSR" INA226 113.005,199.771 r180 top (schematic designator U64)
U64_U_Pomiar_pradu_napiecia_PCIe0 "INA226AIDGSR" INA226 183.319,369.361 r0 top (schematic designator U64)
U64_U_Pomiar_pradu_napiecia_PCIe1 "INA226AIDGSR" INA226 239.636,245.779 r180 top (schematic designator U64)
U64_U_Pomiar_pradu_napiecia_PCIe2 "INA226AIDGSR" INA226 255.968,390.249 r270 top (schematic designator U64)
U64_U_Pomiar_pradu_napiecia_PCIe3 "INA226AIDGSR" INA226 98.74,373.401 r180 top (schematic designator U64)
U64_U_Pomiar_pradu_napiecia_PCIe4 "INA226AIDGSR" INA226 139.725,254.894 r90 top (schematic designator U64)
U65 "MAX17557ATP+" MAX17557 38.76,204.318 r90 top
U67 "LM3880MFE-1AF/NOPB" LM3880-Q1 176.589,160.085 r90 top
U68 "LM3880MFE-1AF/NOPB" LM3880-Q1 111.364,247.684 r180 top
U69 "ADP1741ACPZ-R7" ADP1752_1753/ADP1740_1741 128.605,235.393 r0 top
U70 "TPS7A8801RTJT" TPS7A88 150.914,282.003 r0 top
U71 "UA78M08CDCYR" UA78M 60.935,563.275 r0 top
U72 "INA226AIDGSR" INA226 138.353,281.203 r90 top
U73 "ST1L08SPUR" ST1L08 150.244,349.234 r0 top
U74 "SN74LVC1G08DBVR" SN74LVC1G08DBVR 55.004,324.701 r180 bottom
U75 "ESDCAN02-2BWY" ESDCAN02-2BWY 25.287,528.904 r0 top
U76 "SN74LVC1G08DBVR" SN74LVC1G08DBVR 46.609,326.2 r180 bottom
U77 "NC7WZ07FHX" NC7WZ07FHX 219.126,222.529 r180 top
U78 "NC7WZ07FHX" NC7WZ07FHX 217.246,222.529 r0 top
U79 "SN74AXC4T774PWR" SN74AXC4T774PWR 53.676,390.449 r0 top
X1 "OSC CRO 2000-2000 MHZ SMD .5X.5" CVCO55CW 47.514,542.241 r0 top
X2 "OSC VCO 490-540MHZ SMD .5X.5\"" CVCO55CW 61.992,500.458 r90 top
X3 "2.4576MHz" Crystal 62.046,481.281 r180 top
X4 "FA-23825.0000MB-C3" FA-23825.0000MB-C3 98.72,288.26 r270 bottom
X5 "32.768kHz" FC-135R/FC-135 150.876,342.646 r0 top
X6 "510CCA50M0000BAG" Si510 130.504,351.091 r270 top
X7 "TSX-322524.0000MF15X-AC6" "TSX-3225 24.0000MF15X-AC6" 49.111,336.779 r180 top
X8 "ECS-120-8-33-RWY-TR" ECS-120-8-33-RWY-TR 253.877,218.491 r90 top
X9 "SIT1602BI-12-33E-48.000000G" SiT1602B 141.351,240.297 r0 top

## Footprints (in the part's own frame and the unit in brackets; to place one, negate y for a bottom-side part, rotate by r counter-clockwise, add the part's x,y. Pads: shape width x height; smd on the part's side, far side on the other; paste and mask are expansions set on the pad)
93LC56BT [mm] "SOT-23-6, 6-Leads, Body 2,90x1,55mm, Pitch 0,95mm, IPC High Density"
  rect 1.1x0.6 smd: 1(-1.4,0.95) 2(-1.4,0) 3(-1.4,-0.95) 4(1.4,-0.95) 5(1.4,0) 6(1.4,0.95)
  silkscreen extent -1.52,-1.55 0.5,1.92, body extent -1.35,-1.55 1.35,1.55, height 1.45
2007132 [mm] "SFP Connector"
  rect 2x2 hole 1.05: SH1(-2.5,-5) SH1(0,0) SH2(8.575,-5) SH3(14.25,-5) SH4(0,10) SH5(5.675,10) SH6(11.075,10) SH7(14.25,15) SH8(0,20) SH9(0,30) SH10(14.25,5) SH13(19.925,10) SH14(25.325,10) SH17(22.825,-5) SH20(34.175,10) SH21(39.575,10) SH22(42.75,10) SH23(42.75,0) SH24(37.075,-5) SH25(42.75,20) SH26(42.75,30) SH29(57,15) SH30(57,5) SH31(57,-5) SH32(48.425,10) SH33(53.825,10) SH34(51.325,-5)
  round 1.458 hole 0.95: SH11(14.25,22.5) SH12(14.25,27.5) SH15(28.5,10) SH16(28.5,0) SH18(28.5,20) SH19(28.5,30) SH27(57,27.5) SH28(57,22.5) SH35(0,17.8) SH36(2.325,32.1) SH37(7.125,32.1) SH38(14.25,17.8) SH39(16.575,32.1) SH40(21.375,32.1) SH41(30.825,32.1) SH42(35.625,32.1) SH43(45.075,32.1) SH44(49.875,32.1) SH45(42.75,17.8) SH46(57,17.8)
  silkscreen extent 0,-9.5 57.25,32.57, body extent -0.97,-16.49 58.08,32.49, height 10.62
79523141 [mm] "Battery Holder, Battery Type: 2016,2020,2025,2032"
  rect 5.2x5.2 smd: 1(-12.95,0) 1(12.95,0)
  rect 4x4 smd: 2(0,0)
  silkscreen extent -10.55,-10.5 10.55,9.3, body extent -15.25,-10.5 15.25,9.3, height 4
1703820001 [mm] "20 Position zSFP+ Receptacle Connector Solder Surface Mount, Right Angle"
  rect 0.5x2 smd: 1(1.4,-4.1) 2(2.2,-4.1) 3(3,-4.1) 4(3.8,-4.1) 5(4.6,-4.1) 6(5.4,-4.1) 7(6.2,-4.1) 8(7,-4.1) 9(7.8,-4.1) 10(8.6,-4.1) 11(8.2,4.1) 12(7.4,4.1) 13(6.6,4.1) 14(5.8,4.1) 15(5,4.1) 16(4.2,4.1) 17(3.4,4.1) 18(2.6,4.1) 19(1.8,4.1) 20(1,4.1)
  round 1.55 hole 1.55: ""(0,0)
  round 1.55 hole 1.55 unplated: ""(9.6,0)
  silkscreen extent -1.33,-8.3 10.92,6.2, body extent -0.69,-4.41 10.31,4.26, height 5.17
7499511440 [mm] "LAN Transformer, body 33.02x17mm"
  rect 1.4x1.4 hole 0.89: 1(5.075,9.63)
  round 1.4 hole 0.89: 2(3.045,9.63) 3(1.015,9.63) 4(-1.015,9.63) 5(-3.045,9.63) 6(-5.075,9.63) 7(6.09,12.17) 8(4.06,12.17) 9(2.03,12.17) 10(-2.03,12.17) 11(-4.06,12.17) 12(-6.09,12.17)
  oval 1.4x1.25 hole 0.89: 13(5.59,2.51) 14(-5.59,2.51) 15(5.59,1.05) 16(-5.59,1.05)
  round 1.52 hole 1.02: 17(6.095,14.71) 18(3.555,14.71) 19(-3.555,14.71) 20(-6.095,14.71)
  round 2.8 hole 2.8 unplated: MH1(-6.35,-5.61) MH2(6.35,-5.61)
  round 2.4 hole 1.57: S1(-8.065,-8.79) S2(8.065,-8.79)
  silkscreen extent -10.72,-16.51 10.72,16.51, body extent -10.8,-16.51 10.8,16.51, height 16.21
9774025243 [mm] "SMT Steel Spacer with internal Thread M2, height 2.5mm"
  round 5.3 / inner round 0 / far side round 0 hole 3 unplated: 1(0,0)
  body extent -2.17,-2.17 2.18,2.17, height 2.5
9774045243 [mm] "SMT Steel Spacer with internal Thread M2, height 4.5mm"
  round 5.3 / inner round 0 / far side round 0 hole 3 unplated: 1(0,0)
  body extent -2.17,-2.17 2.18,2.17, height 4.5
430181038816 [mm] "Tact Switch, SMD, body 4.5x4.5mm"
  rect 2x1.4 smd: 1(-3.5,1.5) 2(3.5,1.5) 3(-3.5,-1.5) 4(3.5,-1.5)
  silkscreen extent -2.25,-2.25 2.25,2.25, body extent -3.75,-2.25 3.75,2.25, height 3.8
614105150721 [mm] "WR-COM_USB_Micro Type B_Vertical_THT Micro Type B Vertical THT"
  round 0.94 hole 0.44: 1(-1.3,0) 2(-0.65,-1) 3(0,0) 4(0.65,-1) 5(1.3,0)
  oval 0.85x1.5 hole 0.35 slot 1 at 90 deg: Z1(-3.575,-0.22) Z2(3.575,-0.22)
  silkscreen extent -3.7,-1.3 3.7,1.05, body extent -3.99,-1.57 4.01,1.33, height 5.62
692121130100 [mm] "Receptacle TH Reverse Offset 0.14mm"
  rect 1.2x1.2 hole 0.7: 1(-4.35,2.43)
  round 1.2 hole 0.7: 2(-6.85,2.43) 3(-8.85,2.43) 4(-11.35,2.43) 5(-11.85,0.93) 6(-9.85,0.93) 7(-7.85,0.93) 8(-5.85,0.93) 9(-3.85,0.93)
  oval 1.4x2.8 hole 0.8 slot 2.3 at 90 deg: Z1(-15.7,-6.8) Z1(-15.7,0) Z1(0,-6.8) Z1(0,0)
  Keep-Out Layer board cut-out: -14.6,-0.2 -1.1,-0.2 -1.1,-12.15 -14.6,-12.15
  Mechanical 1 keep-out lines w0.127: -14.6,-12.15 -14.6,-0.2 -1.1,-0.2 -1.1,-12.15 -14.6,-12.15
  silkscreen extent -15.16,-12.15 -0.53,3.72, body extent -15.85,-12.15 0.15,3.72, height 3.71
693071020811 [mm] "Micro SD Card Connector Push & Push - with Card Detection - 8 Pins"
  rect 0.7x1.9 smd: 1(2.25,7.75) 2(1.15,7.75) 3(0.05,7.75) 4(-1.05,7.75) 5(-2.15,7.75) 6(-3.25,7.75) 7(-4.35,7.75) 8(-5.45,7.75) 9(-6.55,7.75)
  rect 1.7x1.8 smd: 10(-8.1,6.7) 11(7.4,6.7)
  rect 1.4x2.6 smd: 12(-7.85,-2.9) 13(7.85,-2.9)
  round 0.9 hole 0.9 unplated: MH1(-4.95,-3.3)
  oval 1.7x0.9 hole 0.9 slot 1.7 at 0 deg unplated: MH2(3.05,-3.3)
  silkscreen extent -7.35,-7.25 7.35,7.25, body extent -8.2,-7.3 8.2,7.73, height 1.85
744373560068 [mm] "Precision Wire Wound Inductor, 2-Leads, Body 9,70x8,50mm, IPC High Density"
  rect 2.52x5.33 smd: 1(-3.62,0) 2(3.62,0)
  silkscreen extent -5.1,-4.25 5.1,4.25, body extent -4.95,-4.25 4.95,4.25, height 3.1
ADP1752_1753/ADP1740_1741 [mm] "16-Lead Lead Frame Chip Scale Package [LFCSP_WQ]  4 mm × 4 mm Body, Very Very Thin Quad  (CP-16-23)"
  rect 0.6x0.3 smd: 1(-1.675,0.975) 2(-1.675,0.325) 3(-1.675,-0.325) 4(-1.675,-0.975) 9(1.675,-0.975) 10(1.675,-0.325) 11(1.675,0.325) 12(1.675,0.975)
  rect 0.3x0.6 smd: 5(-0.975,-1.675) 6(-0.325,-1.675) 7(0.325,-1.675) 8(0.975,-1.675) 13(0.975,1.675) 14(0.325,1.675) 15(-0.325,1.675) 16(-0.975,1.675)
  rect 2.1x2.1 smd: 17(0,0)
  silkscreen extent -2.82,-2.05 2.05,2.05, body extent -2.05,-2.05 2.05,2.05, height 0.8
ADP1850 [mm] "32-Lead Lead Frame Chip Scale Package [LFCSP] 5 mm × 5 mm Body and 0.75 mm Package Height (CP-32-12)"
  rect 0.4x0.25 smd: 1(-2.25,1.75) 2(-2.25,1.25) 3(-2.25,0.75) 4(-2.25,0.25) 5(-2.25,-0.25) 6(-2.25,-0.75) 7(-2.25,-1.25) 8(-2.25,-1.75) 17(2.25,-1.75) 18(2.25,-1.25) 19(2.25,-0.75) 20(2.25,-0.25) 21(2.25,0.25) 22(2.25,0.75) 23(2.25,1.25) 24(2.25,1.75)
  rect 0.25x0.4 smd: 9(-1.75,-2.25) 10(-1.25,-2.25) 11(-0.75,-2.25) 12(-0.25,-2.25) 13(0.25,-2.25) 14(0.75,-2.25) 15(1.25,-2.25) 16(1.75,-2.25) 25(1.75,2.25) 26(1.25,2.25) 27(0.75,2.25) 28(0.25,2.25) 29(-0.25,2.25) 30(-0.75,2.25) 31(-1.25,2.25) 32(-1.75,2.25)
  rect 3.6x3.6 smd paste-3: 33(0,0)
  silkscreen extent -3.27,-2.5 2.5,2.5, body extent -2.5,-2.5 2.5,2.5, height 0.8
BAS40-04-TP [mm] "SOT23, 3-Leads, Body 2,92x2,37mm, Pitch 0,90mm, IPC High Density"
  rect 0.9x0.8 smd: 1(-1,0.95) 2(-1,-0.95) 3(1,0)
  silkscreen extent -1.12,-1.5 0.7,1.98, body extent -1.32,-1.52 1.32,1.52, height 1.12
BAT54T1G [mm] "SOD-123  CASE 425-04"
  rect 0.91x1.22 smd: 1(-1.635,0) 2(1.635,0)
  silkscreen extent -2.04,0.86 -1.94,0.96, body extent -1.86,-0.9 1.86,0.9, height 1.35
Battery [mm]
  rect 0.5x1.8 smd: 1(1,0) 2(-1,0)
  Keep-Out Layer circle w0.254: c0,6.858 r4.906
  silkscreen extent -4.86,-2.5 4.91,11.73
BSC030N03LS [mm] "PG-TDSON-8-1"
  rect 0.85x0.6 smd: 1(-2.9,1.905) 2(-2.9,0.635) 3(-2.9,-0.635) 4(-2.9,-1.905)
  rect 0.8x0.6 smd: 5(2.925,-1.905) 6(2.925,-0.635) 7(2.925,0.635) 8(2.925,1.905)
  rect 3.762x4.41 smd paste-2: 8(0.662,0)
  silkscreen extent -3.77,-2.9 3.32,2.94, body extent -3.32,-2.75 3.32,2.75, height 1.1
BSC080N03LS [mm] "PG-TDSON-8-5"
  rect 0.85x0.6 smd: 1(-2.9,1.905) 2(-2.9,0.635) 3(-2.9,-0.635) 4(-2.9,-1.905)
  rect 0.8x0.6 smd: 5(2.925,-1.905) 6(2.925,-0.635) 7(2.925,0.635) 8(2.925,1.905)
  rect 3.762x4.41 smd paste-2: 8(0.662,0)
  silkscreen extent -3.77,-2.9 3.32,2.94, body extent -3.32,-2.75 3.32,2.75, height 1.1
"CAP 0201/0603 RF" [mm] "Chip Capacitor, 2-Leads, Body 0.60x0.30mm, IPC High Density"
  rect 0.3x0.32 smd: 1(-0.26,0) 2(0.26,0)
  silkscreen extent -0.57,-0.33 0.58,0.33, body extent -0.3,-0.15 0.3,0.15, height 0.3
"CAP 0402/1005 RF" [mm] "Chip Capacitor, 2-Leads, Body 1.02x0.51mm, IPC High Density"
  rect 0.55x0.54 smd: 1(-0.39,0) 2(0.39,0)
  silkscreen extent -0.88,-0.45 0.88,0.45, body extent -0.5,-0.26 0.5,0.26, height 0.52
"CAP 0603/1608 RF" [mm] "Chip Capacitor, 2-Leads, Body 1.60x0.80mm, IPC High Density"
  rect 0.8x0.9 smd: 1(-0.625,0) 2(0.625,0)
  silkscreen extent -1.2,-0.62 1.2,0.62, body extent -0.8,-0.41 0.8,0.41, height 0.82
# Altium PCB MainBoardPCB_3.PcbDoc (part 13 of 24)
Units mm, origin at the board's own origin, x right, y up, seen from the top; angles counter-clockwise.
Board outline 258.95 x 308.86 mm, 16 copper layers (L1, L2 (GND), L3 (Sign), L4 (GND), L5 (Sign), L6 (PWR/GND), L7(PWR/GND), L8 (Plane_GND), L9 (PWR/GND), L10 (PWR/GND), L11 (PWR/GND), L12 (Sign), L13 (GND), L14 (Sign), L15 (GND), L16), stack 2.502 mm thick; 2402 components, 1749 nets, 8407 pads, 3409 vias.
Unrouted connection lines stored in the file: 4352.

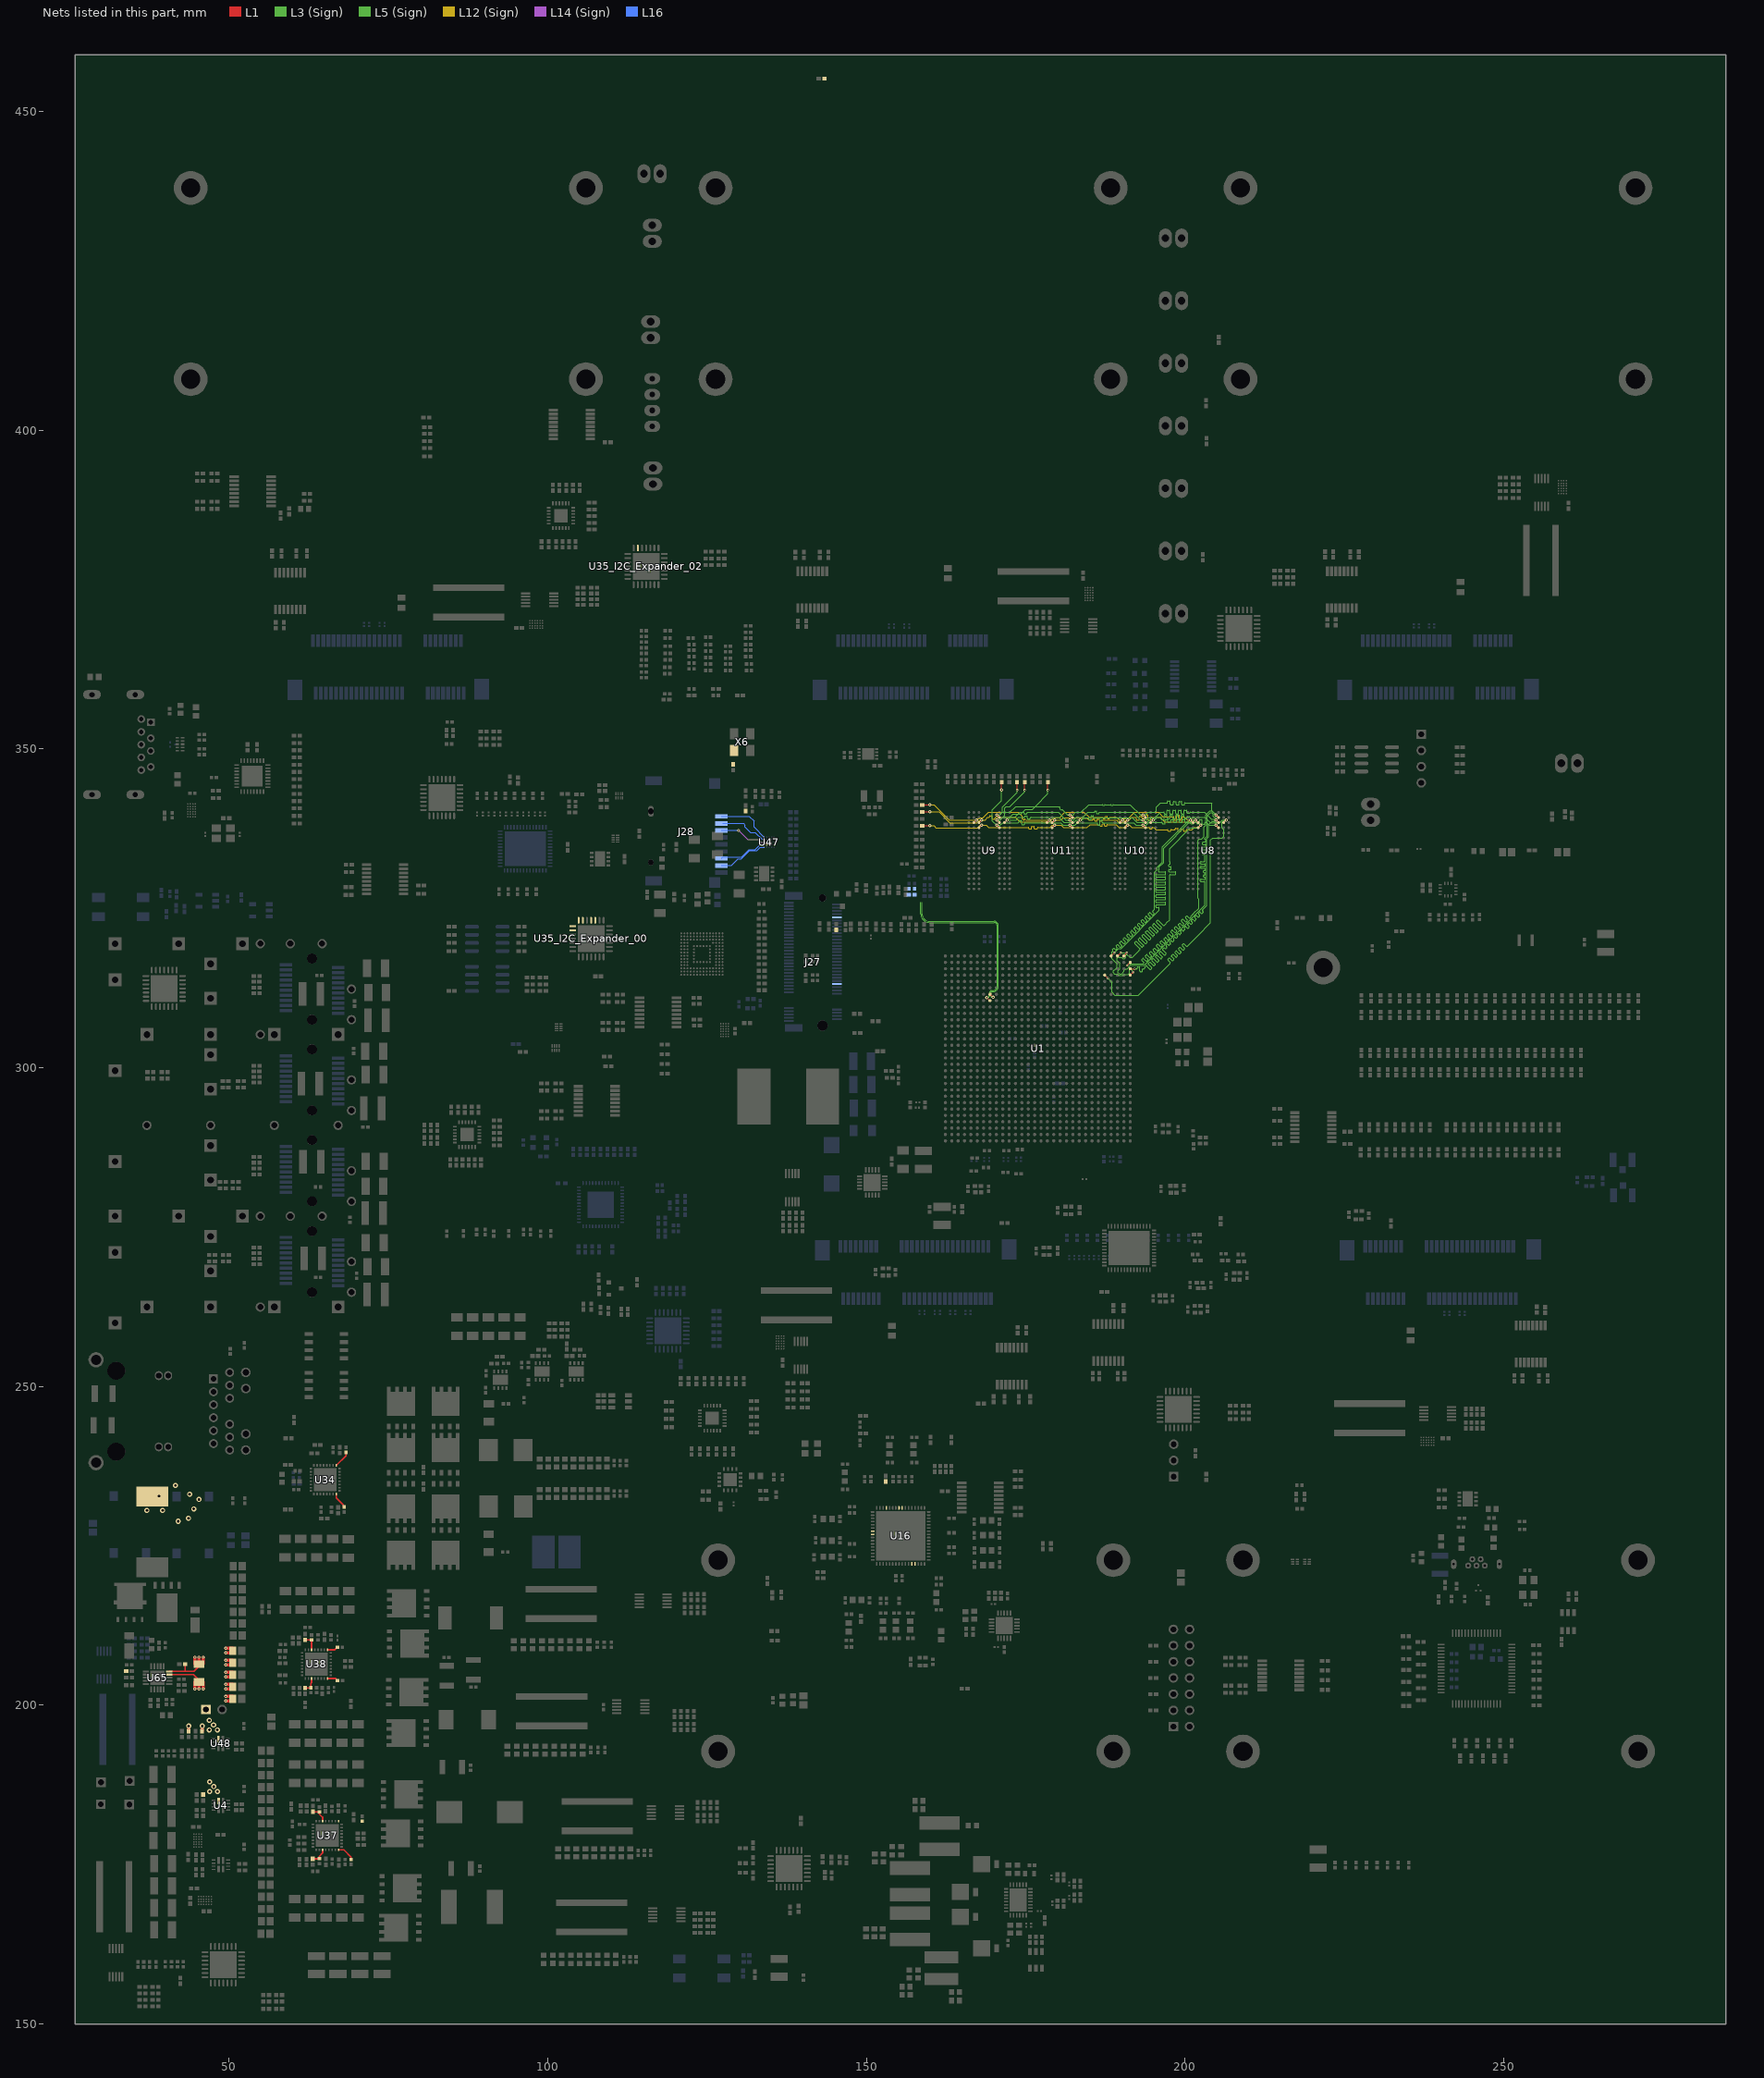
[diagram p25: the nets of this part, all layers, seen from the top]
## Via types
v1: diameter 0.5, hole 0.2, L1 to L16, tented both sides, 1267 vias
v2: diameter 0.5/0.35/0.35/0.35/0.35/0.35/0.35/0.35/0.35/0.35/0.35/0.35/0.35/0.35/0.35/0.5 (per signal layer), hole 0.15, L1 to L16, tented both sides, 463 vias
v3: diameter 0.5, hole 0.2, L1 to L16, 446 vias
v4: diameter 0.35/0/0.35 (per signal layer), hole 0.127, L1 to L3 (Sign), tented both sides, 347 vias
v5: diameter 0.5/0.35/0.35/0.35/0.35/0.35/0.35/0.35/0.35/0.35/0.35/0.35/0.35/0.35/0.35/0.5 (per signal layer), hole 0.2, L1 to L16, tented both sides, 244 vias
v6: diameter 0.8, hole 0.4, L1 to L16, tented both sides, 168 vias
v7: diameter 2.54, hole 1.02, L1 to L16, 113 vias
v8: diameter 1.4, hole 0.5, L1 to L16, tented both sides, 80 vias
v9: diameter 0.5/0/0.5 (per signal layer), hole 0.2, L14 (Sign) to L16, tented both sides, 62 vias
v10: diameter 0.35/0/0.35 (per signal layer), hole 0.127, L1 to L3 (Sign), 38 vias
v11: diameter 0.35, hole 0.127, L1 to L2 (GND), tented both sides, 36 vias
v12: diameter 0.4, hole 0.2, L1 to L16, 16 vias
v13: diameter 0.25, hole 0.2, L1 to L16, 16 vias
v14: diameter 0.35, hole 0.127, L1 to L16, tented both sides, 16 vias
v15: diameter 0.3, hole 0.2, L1 to L16, 15 vias
v16: diameter 0.45, hole 0.15, L1 to L16, 12 vias
v17: diameter 0.5/0.35/0.35/0.35/0.35/0.35/0.35/0.35/0.35/0.35/0.35/0.35/0.35/0.35/0.35/0.45 (per signal layer), hole 0.15, L1 to L16, tented both sides, 10 vias
v18: diameter 0.2/0/0.2 (per signal layer), hole 0.1, L1 to L3 (Sign), tented both sides, 9 vias
v19: diameter 0.4, hole 0.1, L1 to L16, 7 vias
v20: diameter 0.5, hole 0.2, L3 (Sign) to L6 (PWR/GND), tented both sides, 6 vias
v21: diameter 1.15, hole 1.15, L1 to L16, 5 vias
v22: diameter 1.65, hole 1.65, L1 to L16, 5 vias
v23: diameter 0.35/0/0.35 (per signal layer), hole 0.127, L14 (Sign) to L16, tented both sides, 5 vias
v24: diameter 0.5, hole 0.2, L11 (PWR/GND) to L14 (Sign), tented both sides, 4 vias
v25: diameter 0.2, hole 0.1, L1 to L16, 4 vias
v26: diameter 0.35, hole 0.127, L1 to L2 (GND), 2 vias
v27: diameter 0.4, hole 0.15, L1 to L16, 2 vias
v28: diameter 0.4, hole 0.2, L1 to L16, tented both sides, 2 vias
v29: diameter 0.5/0.35/0.35/0.35/0.35/0.35/0.35/0.35/0.35/0.35/0.35/0.35/0.35/0.35/0.35/0.5 (per signal layer), hole 0.15, L1 to L16, 2 vias
v30: diameter 0.35, hole 0.127, L3 (Sign) to L6 (PWR/GND), tented both sides, 2 vias
v31: diameter 0.5/0.35/0.35/0.35/0.35/0.35/0.35/0.35/0.35/0.35/0.35/0.35/0.35/0.35/0.35/0.5 (per signal layer), hole 0.2, L1 to L16, 1 vias
v32: diameter 0.35/0.35/0.35 (per signal layer), hole 0.127, L1 to L3 (Sign), tented both sides, 1 vias
v33: diameter 0.45/0/0.45 (per signal layer), hole 0.15, L1 to L3 (Sign), tented both sides, 1 vias
v34: diameter 0.45/0/0.45 (per signal layer), hole 0.2, L14 (Sign) to L16, tented both sides, 1 vias
v35: diameter 0.35, hole 0.127, L2 (GND) to L3 (Sign), 1 vias

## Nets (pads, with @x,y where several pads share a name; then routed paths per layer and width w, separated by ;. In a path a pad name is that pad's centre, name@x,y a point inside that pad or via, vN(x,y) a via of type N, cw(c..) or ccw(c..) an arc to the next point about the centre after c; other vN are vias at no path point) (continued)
Bank505_MGTRREF3_C_N: C530.2 R70.2 U1.H24 | length 27.8
  L1 w0.116: U1.H24@169.397,311.539 v5(169.884,311.052)
  L5 (Sign) w0.073: 158.737,325.971 158.737,324.142 ccw(c159.897,324.142) 159.897,322.983 170.02,322.983 cw(c170.02,322.293) 170.71,322.293 170.71,318.539 170.71,312.788 cw(c169.847,312.788) 169.847,311.925 169.736,311.925 ccw(c169.736,311.686) 169.497,311.686 169.497,311.328 ccw(c169.773,311.328) 169.773,311.052 v5(169.884,311.052)
Bank505_MGTRREF3_C_P: C529.2 R70.1 U1.H23 | length 27.8
  L1 w0.116: v5(168.909,311.027) U1.H23@169.397,310.539
  L5 (Sign) w0.073: 158.538,325.971 158.538,324.142 ccw(c159.897,324.142) 159.897,322.783 170.02,322.783 cw(c170.02,322.293) 170.51,322.293 170.51,318.539 170.51,312.788 cw(c169.847,312.788) 169.847,312.125 169.736,312.125 ccw(c169.736,311.686) 169.297,311.686 169.297,311.328 cw(c168.996,311.328) 168.996,311.027 v5(168.909,311.027)
Battery_PWR: P11.1 R679.2 R680.2 U48.2 | length 1.6
  L1 w0.5: R680.2@43.658,195.933 v6(43.658,196.747) ; R679.2@45.775,195.933 v6(45.775,196.747)
  other v6: 46.906,196.145 48.155,196.145 47.566,196.91 46.907,197.647
  other v12: 48.327,194.383
BST1: C346.1 U34.25 | length 2.7
  L1 w0.254: U34.25@66.822,237.639 66.822,237.71 66.824,237.712 66.895,237.712 68.336,239.154 C346.1@68.336,239.69
BST1_1: C390.1 U37.25
BST1_2: C431.1 U38.25 | length 1.7
  L1 w0.254: U38.25@65.453,208.714 66.596,208.714 66.996,209.114 C431.1@67.001,209.114
BST2: C350.1 U34.16 | length 2.6
  L1 w0.254: U34.16@66.822,233.139 66.822,232.556 67.929,231.449 67.929,231.245 C350.1@68.072,231.102
BST2_1: C394.1 U37.16 | length 2.8
  L1 w0.254: U37.16@67.175,177.317 68.028,177.317 69.151,176.194 C394.1@69.151,175.817
BST2_2: C435.1 U38.16 | length 1.7
  L1 w0.254: U38.16@65.453,204.214 66.661,204.214 67.011,203.864 C435.1@67.016,203.864
CAN0_H: P6.2 R446.2 R447.2 U63.7 U75.2
CAN0_L: P6.1 R446.1 R447.1 U63.6 U75.1
CAN1_RxD: R798.1 U63.1
CAN1_TxD: R799.1 U63.4
Charge_CAP: R658.2 U35_I2C_Expander_02.20
CLK_M_OSC_In: C53.2 R257.2 R537.1 U33.2
CLK_SMA0_C_N: C48.2 J2.1
CLK_SMA0_C_P: C47.2 J3.1
CLKREF_R: R375.1 X6.3
CLKREQ: J27.52
CMD_SD: J28.3 U47.D4 | length 8
  L14 (Sign) w0.098: v34(129.927,337.233) 131.355,335.804 133.045,335.804 133.445,335.404 133.929,335.404 v23(134.329,335.004)
  L16 w0.098: J28.3@127.237,337.232 v34(129.927,337.233)
COMP1_1: C642.2 R624.2 U37.30 | length 2.7
  L1 w0.254: R624.2@63.175,183.31 63.195,183.29 64.155,183.29 C642.2@64.175,183.27 64.175,182.936 64.675,182.436 U37.30@64.675,181.817
COMP1_2: C548.2 R687.2 U38.30 | length 2.5
  L1 w0.254: R687.2@61.953,210.269 61.963,210.259 62.943,210.259 C548.2@62.953,210.249 U38.30@62.953,208.714
COMP2_1: C641.2 R623.2 U37.11 | length 2.6
  L1 w0.254: R623.2@63.12,175.907 63.14,175.927 64.155,175.927 C641.2@64.175,175.947 64.175,176.323 64.675,176.823 U37.11@64.675,177.317
COMP2_2: C650.2 R631.2 U38.11 | length 2.4
  L1 w0.254: R631.2@61.938,202.723 62.788,202.723 C650.2@62.828,202.764 62.828,203.439 62.953,203.564 U38.11@62.953,204.214
CSN: C694.2 C695.2 C696.2 C697.2 C698.2 C699.2 C700.2 R17.2 R140.2 R150.2 R666.2 U4.2 U65.10 | length 20.6
  L1 w0.254: U65.10@40.6,205.318 43.104,205.318 ; R150.2@43.102,206.468 43.102,205.319 43.104,205.318 ; R666.2@45.266,206.456 45.266,206.112 44.472,205.318 43.104,205.318
  L1 w0.5: R666.2@44.621,206.456 v1(44.621,207.543) ; R666.2@45.266,206.456 v1(45.266,207.543) ; R666.2@45.904,206.456 v1(45.904,207.543) ; v1(49.507,200.659) C699.2@50.594,200.659 ; v1(49.507,201.383) C699.2@50.593,201.383 ; v1(49.507,202.549) C696.2@50.594,202.549 ; v1(49.507,203.273) C696.2@50.593,203.273 ; v1(49.507,204.44) C697.2@50.594,204.44 ; v1(49.507,205.164) C697.2@50.594,205.164 ; v1(49.507,206.33) C695.2@50.594,206.33 ; v1(49.507,207.054) C695.2@50.593,207.054 ; v1(49.507,208.221) C698.2@50.594,208.221 ; v1(49.507,208.944) C698.2@50.594,208.944
  other v6: 46.939,186.483 48.188,186.483 47.599,187.248 46.94,187.985
  other v12: 48.36,184.721
CSP: L22.2 R666.1 U65.9 | length 8.6
  L1 w0.254: U65.9@40.6,204.818 44.43,204.818 45.266,203.981 R666.1@45.266,203.657
  L1 w0.5: v1(44.629,202.57) R666.1@44.629,203.657 ; v1(45.266,202.57) R666.1@45.266,203.657 ; v1(45.912,202.57) R666.1@45.912,203.657
  other v6: 42.02,228.866 43.644,229.333 37.109,230.581 39.58,230.581 44.463,230.811 45.281,232.29 39.025,232.804 43.802,233.108 41.58,234.493
CSU: P1.2 R649.1 R783.1
CSU_Neg: P1.3 R109.2
CSU_Pos: P1.1 R106.2
D_05028_G0: R540.2 R904.2 U16.45
D_05028_G3: U16.40 U35_I2C_Expander_00.20
D_05028_G4: U16.41 U35_I2C_Expander_00.21
D_05028_G5: U16.12 U35_I2C_Expander_00.22
D_05028_G6: U16.13 U35_I2C_Expander_00.23
D_05028_S0: U16.55 U35_I2C_Expander_00.18
D_05028_S1: U16.56 U35_I2C_Expander_00.17
DAC1220_Vref: C320.2 R608.1 R609.2 U30.12
DAC_OUT: C321.2 U30.11 X2.2
DAC_SPI_CLK: U27_SPI_bridge_Main.14 U30.16
DAC_SPI_MOSI: R481.1 U27_SPI_bridge_Main.12 U30.15
DAS/DSS#: J27.10
DATA0_SD: J28.7 U47.D5 | length 7.6
  L16 w0.098: J28.7@127.237,332.832 127.468,333.064 130.429,333.064 131.61,334.244 132.563,334.244 133.324,335.004 U47.D5@133.927,335.004
DATA1_SD: J28.8 U47.E5 | length 7.9
  L16 w0.098: J28.8@127.237,331.732 128.871,331.732 129.876,332.737 130.384,332.737 131.692,334.046 132.797,334.046 133.356,334.604 U47.E5@133.927,334.604
DATA2_SD: J28.1 U47.A5 | length 8.6
  L16 w0.098: J28.1@127.237,339.432 131.629,339.432 132.374,338.687 132.374,337.757 U47.A5@133.927,336.204
DATA3_SD: J28.2 R383.1 U47.B5 | length 7.7
  L16 w0.098: J28.2@127.452,338.336 130.729,338.336 130.975,338.09 130.975,337.798 131.844,336.928 132.556,336.928 133.68,335.804 U47.B5@133.927,335.804
DDR4_A0: R31.1 U1.AH30 U8.P3 U9.P3 U10.P3 U11.P3 | length 101.4
  L1 w0.116: v2(170.472,338.864) U9.P3@170.876,338.46 ; v2(181.933,338.864) U11.P3@182.336,338.46 ; U1.AH30@189.397,317.539 v4(189.884,318.027) ; v2(193.393,338.864) U10.P3@193.797,338.46 ; v17(204.853,338.864) U8.P3@205.257,338.46
  L1 w0.155: v4(174.855,343.555) R31.1@174.855,344.8
  L5 (Sign) w0.092: v2(170.472,338.864) 171.003,338.864 171.42,339.28 173.296,339.28 174.076,340.06 174.498,340.06 174.632,340.06 cw(c174.632,339.971) 174.722,339.971 174.722,339.917 ccw(c174.811,339.917) 174.811,339.828 175.08,339.828 ccw(c175.08,339.917) 175.17,339.917 175.17,339.971 cw(c175.259,339.971) 175.259,340.06 176.111,340.06 180.091,340.06 181.287,338.864 v2(181.933,338.864) 182.528,338.864 182.944,339.28 183.962,339.28 184.742,340.06 185.649,340.06 185.752,340.06 ccw(c185.752,340.13) 185.822,340.13 185.822,340.205 cw(c185.891,340.205) 185.891,340.274 186.099,340.274 cw(c186.099,340.205) 186.168,340.205 186.168,340.06 186.168,339.916 ccw(c186.237,339.916) 186.237,339.847 186.445,339.847 ccw(c186.445,339.916) 186.514,339.916 186.514,339.991 cw(c186.583,339.991) 186.583,340.06 186.944,340.06 191.829,340.06 193.025,338.864 v2(193.393,338.864) 193.902,338.864 194.281,339.242 195.294,339.242 196.17,340.119 196.647,340.119 cw(c196.647,340.029) 196.736,340.029 196.736,339.923 ccw(c196.826,339.923) 196.826,339.833 197.094,339.833 ccw(c197.094,339.923) 197.184,339.923 197.184,340.119 197.184,340.314 cw(c197.273,340.314) 197.273,340.404 197.542,340.404 cw(c197.542,340.314) 197.632,340.314 197.632,340.119 197.632,339.923 ccw(c197.721,339.923) 197.721,339.833 197.99,339.833 ccw(c197.99,339.923) 198.08,339.923 198.08,340.119 198.08,340.314 cw(c198.169,340.314) 198.169,340.404 198.438,340.404 cw(c198.438,340.314) 198.527,340.314 198.527,340.119 198.527,339.923 ccw(c198.617,339.923) 198.617,339.833 198.886,339.833 ccw(c198.886,339.923) 198.975,339.923 198.975,340.119 198.975,340.314 cw(c199.065,340.314) 199.065,340.404 199.333,340.404 cw(c199.333,340.314) 199.423,340.314 199.423,340.119 199.423,339.923 ccw(c199.512,339.923) 199.512,339.833 199.781,339.833 ccw(c199.781,339.923) 199.871,339.923 199.871,340.119 199.871,340.314 cw(c199.96,340.314) 199.96,340.404 200.229,340.404 cw(c200.229,340.314) 200.319,340.314 200.319,340.119 200.319,340.034 ccw(c200.408,340.034) 200.408,339.945 200.677,339.945 ccw(c200.677,340.034) 200.766,340.034 cw(c200.851,340.034) 200.851,340.119 200.99,340.119 203.022,340.119 204.102,339.039 204.678,339.039 v17(204.853,338.864)
  L3 (Sign) w0.092: v2(170.472,338.864) 171.003,338.864 171.739,339.6 171.739,340.77 171.922,340.953 172.538,340.953 172.671,341.085 ; v4(189.884,318.027) 190.395,318.027 190.64,317.782 190.64,317.763 190.692,317.71 ; 190.692,317.709 190.74,317.661 190.74,317.349 190.517,317.125 190.303,317.125 190.081,317.348 189.55,317.348 189.36,317.158 189.36,316.828 189.738,316.449 189.738,315.504 189.479,315.245 189.479,314.952 189.674,314.757 189.7,314.757 189.751,314.706 190.024,314.706 190.452,315.134 190.452,315.263 190.728,315.539 190.896,315.539 191.437,316.081 193.641,316.081 203.086,325.526 203.086,328.902 203.086,329.13 ccw(c202.999,329.13) 202.999,329.217 202.511,329.217 cw(c202.511,329.303) 202.424,329.303 202.424,329.476 cw(c202.511,329.476) 202.511,329.563 203.086,329.563 203.093,329.563 ccw(c203.093,329.649) 203.179,329.649 203.179,329.822 ccw(c203.093,329.822) 203.093,329.909 203.086,329.909 202.981,329.909 cw(c202.981,329.996) 202.894,329.996 202.894,330.169 cw(c202.981,330.169) 202.981,330.255 203.086,330.255 203.093,330.255 ccw(c203.093,330.342) 203.179,330.342 203.179,330.515 ccw(c203.093,330.515) 203.093,330.601 203.086,330.601 202.994,330.601 cw(c202.994,330.688) 202.907,330.688 202.907,330.861 cw(c202.994,330.861) 202.994,330.948 203.086,330.948 203.093,330.948 ccw(c203.093,331.034) 203.179,331.034 203.179,331.207 ccw(c203.093,331.207) 203.093,331.294 203.086,331.294 202.511,331.294 cw(c202.511,331.38) 202.424,331.38 202.424,331.553 cw(c202.511,331.553) 202.511,331.64 203.086,331.64 203.093,331.64 ccw(c203.093,331.727) 203.179,331.727 203.179,331.9 ccw(c203.093,331.9) 203.093,331.986 203.086,331.986 202.511,331.986 cw(c202.511,332.073) 202.424,332.073 202.424,332.246 cw(c202.511,332.246) 202.511,332.332 202.999,332.332 ccw(c202.999,332.419) 203.086,332.419 203.086,332.506 203.128,332.548 203.128,332.856 203.122,332.862 203.122,333.257 203.122,333.337 ccw(c203.023,333.337) 203.023,333.436 202.839,333.436 cw(c202.839,333.536) 202.74,333.536 202.74,333.734 cw(c202.839,333.734) 202.839,333.833 203.122,333.833 203.143,333.833 ccw(c203.143,333.933) 203.242,333.933 203.242,334.131 ccw(c203.143,334.131) 203.143,334.23 203.122,334.23 202.844,334.23 cw(c202.844,334.33) 202.744,334.33 202.744,334.528 cw(c202.844,334.528) 202.844,334.627 203.122,334.627 203.143,334.627 ccw(c203.143,334.727) 203.242,334.727 203.242,334.925 ccw(c203.143,334.925) 203.143,335.024 203.122,335.024 202.844,335.024 cw(c202.844,335.124) 202.745,335.124 202.745,335.322 cw(c202.844,335.322) 202.844,335.421 203.122,335.421 203.143,335.421 ccw(c203.143,335.521) 203.242,335.521 203.242,335.719 ccw(c203.143,335.719) 203.143,335.818 cw(c203.143,335.839) 203.122,335.839 203.122,336.017 203.456,336.351 203.456,339.499 203.949,339.992 204.174,339.992 204.432,339.734 204.432,339.407 204.559,339.28 204.768,339.28 204.853,339.195 v17(204.853,338.864)
  L3 (Sign) w0.151: 172.671,341.085 174.855,343.27 v4(174.855,343.555)
DDR4_A1: R33.1 U1.AG30 U8.P4 U9.P4 U10.P4 U11.P4 | length 100.3
  L1 w0.116: U9.P4@167.676,338.46 168.072,338.857 v2(168.075,338.857) ; U11.P4@179.136,338.46 179.533,338.857 v2(179.535,338.857) ; U1.AG30@188.397,317.539 v4(188.884,318.027) ; U10.P4@190.597,338.46 190.993,338.857 v2(190.995,338.857) v2@190.954,338.815 ; v17(201.646,338.856) U8.P4@202.049,338.453
  L1 w0.155: R33.1@158.737,340.144 v1(159.982,340.144)
  L12 (Sign) w0.092: 165.251,338.46 166.723,338.46 167.356,338.46 167.711,338.815 168.033,338.815 v2(168.075,338.857) ; v2@168.072,338.857 v2(168.075,338.857) ; v2@179.533,338.857 v2(179.535,338.857) ; v17(201.646,338.856) 201.379,338.856 201.058,338.536 196.832,338.536 196.108,339.26 194.843,339.26 194.709,339.26 ccw(c194.709,339.171) 194.62,339.171 194.62,338.947 cw(c194.53,338.947) 194.53,338.858 194.261,338.858 cw(c194.261,338.947) 194.172,338.947 194.172,339.26 194.172,339.573 ccw(c194.082,339.573) 194.082,339.663 193.813,339.663 ccw(c193.813,339.573) 193.724,339.573 193.724,339.26 193.724,339.241 cw(c193.634,339.241) 193.634,339.152 193.366,339.152 cw(c193.366,339.241) 193.276,339.241 193.276,339.26 193.276,339.349 ccw(c193.187,339.349) 193.187,339.439 192.918,339.439 ccw(c192.918,339.349) 192.828,339.349 192.828,339.26 192.828,338.947 cw(c192.739,338.947) 192.739,338.858 192.47,338.858 cw(c192.47,338.947) 192.381,338.947 192.381,339.171 ccw(c192.291,339.171) 192.291,339.26 191.795,339.26 191.636,339.26 191.232,338.857 v2(190.995,338.857) 190.954,338.815 190.632,338.815 190.335,338.518 189.586,338.518 189.24,338.864 187.088,338.864 186.984,338.864 ccw(c186.984,338.795) 186.914,338.795 186.914,338.77 cw(c186.845,338.77) 186.845,338.701 186.637,338.701 cw(c186.637,338.77) 186.568,338.77 186.568,338.864 186.568,338.97 ccw(c186.499,338.97) 186.499,339.04 186.291,339.04 ccw(c186.291,338.97) 186.222,338.97 186.222,338.864 186.222,338.77 cw(c186.153,338.77) 186.153,338.701 185.945,338.701 cw(c185.945,338.77) 185.876,338.77 185.876,338.864 185.876,338.97 ccw(c185.807,338.97) 185.807,339.04 185.599,339.04 ccw(c185.599,338.97) 185.53,338.97 185.53,338.933 cw(c185.46,338.933) 185.46,338.864 185.204,338.864 184.935,338.864 184.633,339.166 183.804,339.166 183.715,339.255 180.886,339.255 180.488,338.857 v2(179.535,338.857) ; v2(168.075,338.857) 168.651,338.857 169.055,339.26 169.189,339.26 ccw(c169.189,339.35) 169.279,339.35 169.279,339.404 cw(c169.368,339.404) 169.368,339.493 169.637,339.493 cw(c169.637,339.404) 169.727,339.404 169.727,339.26 169.727,339.117 ccw(c169.816,339.117) 169.816,339.027 170.085,339.027 ccw(c170.085,339.117) 170.175,339.117 170.175,339.171 cw(c170.264,339.171) 170.264,339.26 170.472,339.26 173.402,339.26 174.126,338.536 179.214,338.536 v2(179.535,338.857)
  L12 (Sign) w0.151: v1(159.982,340.144) 161.387,340.144 163.071,338.46 165.251,338.46
  L3 (Sign) w0.092: v4(188.884,318.027) 189.551,318.694 189.968,318.694 195.968,324.694 195.968,324.965 195.968,325.064 ccw(c195.869,325.064) 195.869,325.164 195.517,325.164 cw(c195.517,325.263) 195.418,325.263 195.418,325.461 cw(c195.517,325.461) 195.517,325.561 195.968,325.561 196.862,325.561 ccw(c196.862,325.66) 196.961,325.66 196.961,325.858 ccw(c196.862,325.858) 196.862,325.958 195.968,325.958 195.517,325.958 cw(c195.517,326.057) 195.418,326.057 195.418,326.255 cw(c195.517,326.255) 195.517,326.355 195.968,326.355 196.874,326.355 ccw(c196.874,326.454) 196.974,326.454 196.974,326.652 ccw(c196.874,326.652) 196.874,326.752 195.968,326.752 195.517,326.752 cw(c195.517,326.851) 195.418,326.851 195.418,327.049 cw(c195.517,327.049) 195.517,327.149 195.968,327.149 196.874,327.149 ccw(c196.874,327.248) 196.974,327.248 196.974,327.446 ccw(c196.874,327.446) 196.874,327.546 195.968,327.546 195.517,327.546 cw(c195.517,327.645) 195.418,327.645 195.418,327.843 cw(c195.517,327.843) 195.517,327.943 195.968,327.943 196.874,327.943 ccw(c196.874,328.042) 196.974,328.042 196.974,328.24 ccw(c196.874,328.24) 196.874,328.34 195.968,328.34 195.517,328.34 cw(c195.517,328.439) 195.418,328.439 195.418,328.637 cw(c195.517,328.637) 195.517,328.737 195.968,328.737 196.874,328.737 ccw(c196.874,328.836) 196.974,328.836 196.974,329.034 ccw(c196.874,329.034) 196.874,329.134 195.968,329.134 195.517,329.134 cw(c195.517,329.233) 195.418,329.233 195.418,329.431 cw(c195.517,329.431) 195.517,329.531 195.968,329.531 196.874,329.531 ccw(c196.874,329.63) 196.974,329.63 196.974,329.828 ccw(c196.874,329.828) 196.874,329.928 195.968,329.928 195.517,329.928 cw(c195.517,330.027) 195.418,330.027 195.418,330.225 cw(c195.517,330.225) 195.517,330.325 195.968,330.325 196.874,330.325 ccw(c196.874,330.424) 196.974,330.424 196.974,330.622 ccw(c196.874,330.622) 196.874,330.722 195.968,330.722 195.933,330.722 cw(c195.933,330.821) 195.833,330.821 195.833,331.019 cw(c195.933,331.019) 195.933,331.119 195.918,331.119 ccw(c195.918,331.169) 195.968,331.169 195.968,331.241 195.968,331.549 196.63,332.21 196.63,334.457 200.602,338.43 200.947,338.43 201.088,338.571 201.093,338.571 201.379,338.856 v17(201.646,338.856)
DDR4_A2: R35.1 U1.AK29 U8.R3 U9.R3 U10.R3 U11.R3 | length 99
  L1 w0.116: v2(170.472,339.664) U9.R3@170.876,339.26 ; v2(181.933,339.664) U11.R3@182.336,339.26 ; v4(190.909,316.052) U1.AK29@191.397,316.539 ; v2(193.393,339.664) U10.R3@193.797,339.26 ; v17(204.853,339.664) U8.R3@205.257,339.26
  L1 w0.155: v4(173.646,343.555) R35.1@173.646,344.8
  L5 (Sign) w0.092: v2(170.472,339.664) 170.901,339.664 171.305,340.068 172.536,340.068 173.449,340.981 180.235,340.981 180.335,340.881 cw(c180.276,340.822) 180.335,340.764 ccw(c180.398,340.701) 180.335,340.637 180.525,340.447 ccw(c180.588,340.511) 180.651,340.447 cw(c180.71,340.389) 180.768,340.447 181.326,339.89 181.552,339.664 v2(181.933,339.664) 182.433,339.664 182.837,340.068 183.672,340.068 184.891,341.287 186.792,341.287 186.987,341.287 cw(c186.987,341.218) 187.056,341.218 187.056,341.216 ccw(c187.125,341.216) 187.125,341.147 187.333,341.147 ccw(c187.333,341.216) 187.402,341.216 187.402,341.218 cw(c187.471,341.218) 187.471,341.287 187.748,341.287 187.922,341.287 188.299,341.287 cw(c188.299,341.218) 188.368,341.218 188.368,341.216 ccw(c188.437,341.216) 188.437,341.147 188.645,341.147 ccw(c188.645,341.216) 188.714,341.216 188.714,341.218 cw(c188.783,341.218) 188.783,341.287 188.887,341.287 191.389,341.287 193.012,339.664 v2(193.393,339.664) 193.822,339.664 194.226,340.068 195.277,340.068 195.516,340.307 195.516,340.906 196.164,341.554 196.913,341.554 197.164,341.554 ccw(c197.164,341.643) 197.254,341.643 197.254,341.758 cw(c197.344,341.758) 197.344,341.848 197.612,341.848 cw(c197.612,341.758) 197.702,341.758 197.702,341.554 197.702,341.349 ccw(c197.791,341.349) 197.791,341.26 198.06,341.26 ccw(c198.06,341.349) 198.15,341.349 198.15,341.554 198.15,341.658 cw(c198.239,341.658) 198.239,341.748 198.508,341.748 cw(c198.508,341.658) 198.597,341.658 198.597,341.554 198.597,341.349 ccw(c198.687,341.349) 198.687,341.26 198.956,341.26 ccw(c198.956,341.349) 199.045,341.349 199.045,341.554 199.045,341.658 cw(c199.135,341.658) 199.135,341.748 199.403,341.748 cw(c199.403,341.658) 199.493,341.658 199.493,341.554 199.493,341.349 ccw(c199.583,341.349) 199.583,341.26 199.851,341.26 ccw(c199.851,341.349) 199.941,341.349 199.941,341.464 cw(c200.03,341.464) 200.03,341.554 200.165,341.554 204.127,341.554 204.23,341.451 204.23,340.289 204.853,339.666 v17(204.853,339.664)
  L3 (Sign) w0.092: v2(170.472,339.664) 170.901,339.664 171.317,340.079 171.317,340.881 171.456,341.02 171.471,341.02 171.536,341.085 ; v4(190.909,316.052) 191.179,316.322 193.462,316.322 193.533,316.392 ccw(c193.462,316.462) 193.533,316.532 193.212,316.853 cw(c193.282,316.924) 193.212,316.994 193.352,317.134 cw(c193.422,317.064) 193.492,317.134 193.884,316.743 ccw(c193.954,316.813) 194.024,316.743 194.164,316.883 ccw(c194.094,316.953) 194.164,317.024 193.773,317.415 cw(c193.843,317.485) 193.773,317.555 193.913,317.696 cw(c193.984,317.625) 194.054,317.696 194.445,317.304 ccw(c194.515,317.374) 194.585,317.304 194.726,317.445 ccw(c194.656,317.515) 194.726,317.585 194.416,317.895 cw(c194.486,317.965) 194.416,318.035 194.556,318.175 cw(c194.627,318.105) 194.697,318.175 195.006,317.866 ccw(c195.077,317.936) 195.147,317.866 195.287,318.006 ccw(c195.217,318.076) 195.287,318.146 195.021,318.412 cw(c195.092,318.482) 195.021,318.553 195.162,318.693 cw(c195.232,318.623) 195.302,318.693 195.568,318.427 ccw(c195.638,318.497) 195.708,318.427 195.849,318.568 ccw(c195.778,318.638) 195.849,318.708 195.508,319.048 cw(c195.579,319.118) 195.508,319.188 195.649,319.329 cw(c195.719,319.259) 195.789,319.329 196.129,318.989 ccw(c196.199,319.059) 196.27,318.989 196.41,319.129 ccw(c196.34,319.199) 196.41,319.269 196.093,319.586 cw(c196.163,319.657) 196.093,319.727 196.233,319.867 cw(c196.304,319.797) 196.374,319.867 196.691,319.55 ccw(c196.761,319.62) 196.831,319.55 196.971,319.69 ccw(c196.901,319.761) 196.971,319.831 196.707,320.095 cw(c196.778,320.165) 196.707,320.235 196.848,320.376 cw(c196.918,320.305) 196.988,320.376 197.252,320.112 ccw(c197.322,320.182) 197.393,320.112 197.533,320.252 ccw(c197.463,320.322) 197.533,320.392 197.269,320.656 cw(c197.34,320.726) 197.269,320.796 197.41,320.936 cw(c197.48,320.866) 197.55,320.936 197.814,320.673 ccw(c197.884,320.743) 197.954,320.673 198.094,320.813 ccw(c198.024,320.884) 198.094,320.954 197.769,321.279 cw(c197.839,321.349) 197.769,321.419 197.909,321.56 cw(c197.98,321.489) 198.05,321.56 198.375,321.234 ccw(c198.445,321.305) 198.515,321.234 198.656,321.375 ccw(c198.586,321.445) 198.656,321.515 198.358,321.813 cw(c198.428,321.883) 198.358,321.953 198.499,322.093 cw(c198.569,322.023) 198.639,322.093 198.937,321.796 ccw(c199.007,321.866) 199.077,321.796 199.217,321.936 ccw(c199.147,322.006) 199.217,322.077 198.955,322.338 cw(c199.026,322.409) 198.955,322.479 199.096,322.619 cw(c199.166,322.549) 199.236,322.619 199.498,322.357 ccw(c199.568,322.427) 199.638,322.357 199.779,322.498 ccw(c199.708,322.568) 199.779,322.638 199.444,322.973 cw(c199.514,323.043) 199.444,323.113 199.584,323.253 cw(c199.654,323.183) 199.725,323.253 200.059,322.919 ccw(c200.13,322.989) 200.2,322.919 200.34,323.059 ccw(c200.27,323.129) 200.34,323.199 200.079,323.46 cw(c200.15,323.53) 200.079,323.6 200.22,323.741 cw(c200.29,323.671) 200.36,323.741 200.621,323.48 ccw(c200.691,323.55) 200.761,323.48 200.902,323.621 ccw(c200.831,323.691) 200.902,323.761 201.068,323.928 201.077,323.928 201.147,323.998 201.154,323.991 201.215,324.052 201.215,324.074 201.247,324.106 201.269,324.106 201.33,324.167 201.323,324.174 201.393,324.244 201.393,324.253 202.135,324.994 202.135,326.499 202.057,326.576 202.057,335.669 202.253,335.864 202.578,335.864 202.969,336.255 202.969,337.779 203.249,338.06 203.249,339.66 203.898,340.309 204.208,340.309 v17(204.853,339.664)
  L3 (Sign) w0.151: 171.536,341.085 173.63,343.18 173.63,343.539 v4(173.646,343.555)
DDR4_A3: R37.1 U1.AJ30 U8.N4 U9.N4 U10.N4 U11.N4 | length 99.3
  L1 w0.116: U9.N4@167.676,337.66 168.072,338.057 v2(168.075,338.057) ; U11.N4@179.136,337.66 179.533,338.057 v2(179.535,338.057) ; U1.AJ30@190.397,317.539 v4(190.884,318.027) ; U10.N4@190.597,337.66 190.993,338.057 v2(190.995,338.057) ; U8.N4@202.057,337.66 202.453,338.057 v2(202.456,338.057)
  L1 w0.155: R37.1@158.737,337.967 v1(159.982,337.967)
  L12 (Sign) w0.092: 165.251,337.661 166.76,337.661 167.508,337.661 167.896,338.049 v2(168.075,338.057) ; v2@168.075,338.049 168.821,338.049 169.171,337.698 173.927,337.698 175.389,337.698 cw(c175.389,337.609) 175.479,337.609 175.479,337.545 ccw(c175.568,337.545) 175.568,337.456 175.837,337.456 ccw(c175.837,337.545) 175.927,337.545 175.927,337.698 175.927,337.773 cw(c176.016,337.773) 176.016,337.863 176.285,337.863 cw(c176.285,337.773) 176.374,337.773 176.374,337.698 176.374,337.545 ccw(c176.464,337.545) 176.464,337.456 176.733,337.456 ccw(c176.733,337.545) 176.822,337.545 176.822,337.609 cw(c176.912,337.609) 176.912,337.698 177.046,337.698 177.931,337.698 177.934,337.695 178.053,337.695 178.053,337.698 178.201,337.698 178.201,337.695 178.32,337.695 178.323,337.698 178.831,337.698 179.189,338.057 v2@179.533,338.057 ; v2(179.535,338.057) 180.56,338.057 180.95,337.668 184.651,337.668 185.134,338.15 186.39,338.15 186.616,338.15 cw(c186.616,338.081) 186.685,338.081 186.685,337.958 ccw(c186.754,337.958) 186.754,337.889 186.962,337.889 ccw(c186.962,337.958) 187.031,337.958 187.031,338.15 187.031,338.183 cw(c187.1,338.183) 187.1,338.252 187.308,338.252 cw(c187.308,338.183) 187.377,338.183 187.377,338.15 187.377,337.958 ccw(c187.446,337.958) 187.446,337.889 187.654,337.889 ccw(c187.654,337.958) 187.723,337.958 187.723,338.081 cw(c187.793,338.081) 187.793,338.15 187.897,338.15 189.219,338.15 189.633,337.736 190.504,337.736 190.817,338.049 191.312,338.049 191.662,337.698 193.827,337.698 194.311,337.698 cw(c194.311,337.609) 194.4,337.609 ; 194.4,337.608 ccw(c194.49,337.608) 194.49,337.519 194.759,337.519 ccw(c194.759,337.608) 194.848,337.608 ; 194.848,337.609 cw(c194.938,337.609) 194.938,337.698 195.072,337.698 195.123,337.698 195.458,337.363 196.532,337.363 197.232,337.363 cw(c197.232,337.273) 197.321,337.273 197.321,337.214 ccw(c197.411,337.214) 197.411,337.125 197.68,337.125 ccw(c197.68,337.214) 197.769,337.214 197.769,337.273 cw(c197.859,337.273) 197.859,337.363 197.993,337.363 198.352,337.363 ccw(c198.352,337.452) 198.442,337.452 198.442,337.5 cw(c198.531,337.5) 198.531,337.59 198.8,337.59 cw(c198.8,337.5) 198.89,337.5 198.89,337.363 198.89,337.214 ccw(c198.979,337.214) 198.979,337.125 199.248,337.125 ccw(c199.248,337.214) 199.337,337.214 199.337,337.363 cw(c199.427,337.363) 199.427,337.452 199.696,337.452 cw(c199.696,337.363) 199.785,337.363 199.785,337.214 ccw(c199.875,337.214) 199.875,337.125 200.143,337.125 ccw(c200.143,337.214) 200.233,337.214 200.233,337.273 cw(c200.322,337.273) 200.322,337.363 200.457,337.363 201.112,337.363 201.447,337.698 202.097,337.698 v2(202.456,338.057)
  L12 (Sign) w0.151: v1(159.982,337.967) 160.623,337.967 160.928,337.661 165.251,337.661
  L3 (Sign) w0.092: v4(190.884,318.027) 190.884,317.789 191.329,317.344 191.726,317.344 191.867,317.484 192.147,317.765 192.428,318.046 192.709,318.327 192.919,318.537 ccw(c192.849,318.607) 192.919,318.677 192.123,319.474 cw(c192.193,319.544) 192.123,319.614 192.263,319.755 cw(c192.333,319.684) 192.403,319.755 193.2,318.958 ccw(c193.27,319.028) 193.34,318.958 193.481,319.099 ccw(c193.411,319.169) 193.481,319.239 192.684,320.035 cw(c192.754,320.106) 192.684,320.176 192.825,320.316 cw(c192.895,320.246) 192.965,320.316 193.761,319.52 ccw(c193.832,319.59) 193.902,319.52 194.042,319.66 ccw(c193.972,319.73) 194.042,319.8 193.246,320.597 cw(c193.316,320.667) 193.246,320.737 193.386,320.878 cw(c193.456,320.807) 193.526,320.878 194.323,320.081 ccw(c194.393,320.151) 194.463,320.081 194.604,320.221 ccw(c194.533,320.292) 194.604,320.362 193.807,321.158 cw(c193.877,321.228) 193.807,321.299 193.947,321.439 cw(c194.018,321.369) 194.088,321.439 194.884,320.642 ccw(c194.954,320.713) 195.025,320.642 195.165,320.783 ccw(c195.095,320.853) 195.165,320.923 194.368,321.72 cw(c194.439,321.79) 194.368,321.86 194.509,322 cw(c194.579,321.93) 194.649,322 195.446,321.204 ccw(c195.516,321.274) 195.586,321.204 195.726,321.344 ccw(c195.656,321.414) 195.726,321.485 194.93,322.281 cw(c195,322.351) 194.93,322.422 195.07,322.562 cw(c195.14,322.492) 195.211,322.562 196.007,321.765 ccw(c196.077,321.836) 196.148,321.765 196.288,321.906 ccw(c196.218,321.976) 196.288,322.046 195.491,322.843 cw(c195.562,322.913) 195.491,322.983 195.632,323.123 cw(c195.702,323.053) 195.772,323.123 196.569,322.327 ccw(c196.639,322.397) 196.709,322.327 196.92,322.537 197.2,322.818 197.574,323.192 197.574,329.171 197.574,330.229 cw(c197.673,330.229) 197.673,330.328 198.456,330.328 ccw(c198.456,330.427) 198.555,330.427 198.555,330.626 ccw(c198.456,330.626) 198.456,330.725 197.574,330.725 cw(c197.574,330.824) 197.475,330.824 197.475,331.023 cw(c197.574,331.023) 197.574,331.122 197.75,331.122 ccw(c197.75,331.221) 197.849,331.221 197.849,331.42 ccw(c197.75,331.42) 197.75,331.519 197.574,331.519 cw(c197.574,331.618) 197.475,331.618 197.475,331.817 cw(c197.574,331.817) 197.574,331.916 ccw(c197.574,332.015) 197.673,332.015 197.673,332.214 ccw(c197.574,332.214) 197.574,332.313 197.574,332.511 197.574,334.379 200.822,337.627 202.026,337.627 v2(202.456,338.057)
DDR4_A4: R39.1 U1.AK28 U8.N3 U9.N3 U10.N3 U11.N3 | length 98.4
  L1 w0.116: v2(170.472,338.064) U9.N3@170.876,337.66 ; v31(181.933,338.064) U11.N3@182.336,337.66 ; U1.AK28@191.397,315.539 v4(192.086,315.539) ; v2(193.393,338.064) U10.N3@193.797,337.66 ; v17(204.853,338.064) U8.N3@205.257,337.66
  L1 w0.155: v1(171.229,343.555) R39.1@171.229,344.8
  L5 (Sign) w0.092: 170.437,341.085 169.784,340.433 169.784,338.752 v2(170.472,338.064) 171.003,338.064 171.4,338.46 173.698,338.46 173.832,338.46 ccw(c173.832,338.55) 173.922,338.55 173.922,338.672 cw(c174.011,338.672) 174.011,338.762 174.28,338.762 cw(c174.28,338.672) 174.37,338.672 174.37,338.46 174.37,338.249 ccw(c174.459,338.249) 174.459,338.159 174.728,338.159 ccw(c174.728,338.249) 174.817,338.249 174.817,338.371 cw(c174.907,338.371) 174.907,338.46 175.997,338.46 180.482,338.46 180.878,338.064 v31(181.933,338.064) 182.713,338.064 183.109,338.46 185.801,338.46 185.974,338.46 186.251,338.46 cw(c186.251,338.391) 186.32,338.391 186.32,338.15 ccw(c186.39,338.15) 186.39,338.081 186.597,338.081 ccw(c186.597,338.15) 186.666,338.15 186.666,338.46 186.666,338.77 cw(c186.736,338.77) 186.736,338.84 186.943,338.84 cw(c186.943,338.77) 187.013,338.77 187.013,338.53 ccw(c187.082,338.53) 187.082,338.46 187.82,338.46 191.942,338.46 192.339,338.064 v2(193.393,338.064) 193.924,338.064 194.366,338.506 194.564,338.506 196.327,338.506 cw(c196.327,338.416) 196.417,338.416 196.417,338.348 ccw(c196.506,338.348) 196.506,338.258 196.775,338.258 ccw(c196.775,338.348) 196.864,338.348 196.864,338.506 196.864,338.82 cw(c196.954,338.82) 196.954,338.91 197.223,338.91 cw(c197.223,338.82) 197.312,338.82 197.312,338.595 ccw(c197.402,338.595) 197.402,338.506 197.67,338.506 ccw(c197.67,338.595) 197.76,338.595 197.76,338.82 cw(c197.849,338.82) 197.849,338.91 198.118,338.91 cw(c198.118,338.82) 198.208,338.82 198.208,338.595 ccw(c198.297,338.595) 198.297,338.506 198.566,338.506 ccw(c198.566,338.595) 198.656,338.595 198.656,338.82 cw(c198.745,338.82) 198.745,338.91 199.014,338.91 cw(c199.014,338.82) 199.103,338.82 199.103,338.595 ccw(c199.193,338.595) 199.193,338.506 199.462,338.506 ccw(c199.462,338.595) 199.551,338.595 199.551,338.82 cw(c199.641,338.82) 199.641,338.91 199.909,338.91 cw(c199.909,338.82) 199.999,338.82 199.999,338.595 ccw(c200.088,338.595) 200.088,338.506 200.447,338.506 200.805,338.506 cw(c200.805,338.416) 200.895,338.416 200.895,338.348 ccw(c200.984,338.348) 200.984,338.258 201.253,338.258 ccw(c201.253,338.348) 201.342,338.348 201.342,338.416 cw(c201.432,338.416) 201.432,338.506 201.701,338.506 cw(c201.701,338.416) 201.79,338.416 201.79,338.403 ccw(c201.88,338.403) 201.88,338.314 202.148,338.314 ccw(c202.148,338.403) 202.238,338.403 202.238,338.506 202.238,338.82 cw(c202.327,338.82) 202.327,338.91 202.596,338.91 cw(c202.596,338.82) 202.686,338.82 202.686,338.506 202.686,338.317 ccw(c202.775,338.317) 202.775,338.227 203.044,338.227 ccw(c203.044,338.317) 203.134,338.317 203.134,338.416 cw(c203.223,338.416) 203.223,338.506 203.357,338.506 203.799,338.064 v17(204.853,338.064)
  L5 (Sign) w0.151: 170.437,341.085 171.229,341.878 v1(171.229,343.555)
  L3 (Sign) w0.092: v4(192.086,315.539) 192.317,315.539 192.416,315.539 ccw(c192.416,315.639) 192.515,315.639 192.515,315.688 cw(c192.615,315.688) 192.615,315.787 192.813,315.787 cw(c192.813,315.688) 192.912,315.688 192.912,315.539 192.912,315.189 ccw(c193.012,315.189) 193.012,315.089 193.21,315.089 ccw(c193.21,315.189) 193.309,315.189 193.309,315.44 cw(c193.409,315.44) 193.409,315.539 193.543,315.539 193.684,315.68 ; 193.683,315.68 cw(c193.753,315.75) 193.683,315.821 193.823,315.961 cw(c193.894,315.891) 193.964,315.961 ; 193.964,315.961 194.466,315.459 ccw(c194.536,315.529) 194.606,315.459 194.746,315.6 ccw(c194.676,315.67) 194.746,315.74 194.245,316.241 cw(c194.312,316.309) 194.245,316.376 194.391,316.522 cw(c194.458,316.454) 194.526,316.522 195.027,316.021 ccw(c195.097,316.091) 195.167,316.021 195.308,316.161 ccw(c195.238,316.231) 195.308,316.301 194.806,316.803 cw(c194.874,316.87) 194.806,316.938 194.952,317.083 cw(c195.02,317.016) 195.087,317.083 195.588,316.582 ccw(c195.659,316.652) 195.729,316.582 195.869,316.722 ccw(c195.799,316.793) 195.869,316.863 195.368,317.364 cw(c195.435,317.432) 195.368,317.499 195.514,317.645 cw(c195.581,317.577) 195.649,317.645 196.15,317.144 ccw(c196.22,317.214) 196.29,317.144 196.431,317.284 ccw(c196.36,317.354) 196.431,317.424 195.929,317.926 cw(c195.997,317.993) 195.929,318.06 196.075,318.206 cw(c196.143,318.139) 196.21,318.206 196.711,317.705 ccw(c196.782,317.775) 196.852,317.705 196.992,317.845 ccw(c196.922,317.916) 196.992,317.986 196.491,318.487 cw(c196.558,318.554) 196.491,318.622 196.637,318.768 cw(c196.704,318.7) 196.772,318.768 196.848,318.691 ccw(c196.919,318.761) 196.989,318.691 197.129,318.831 ccw(c197.059,318.901) 197.129,318.971 197.052,319.048 cw(c197.12,319.116) 197.052,319.183 197.198,319.329 cw(c197.265,319.262) 197.333,319.329 197.41,319.252 ccw(c197.48,319.322) 197.55,319.252 197.691,319.393 ccw(c197.62,319.463) 197.691,319.533 197.614,319.61 cw(c197.681,319.677) 197.614,319.745 197.759,319.891 cw(c197.827,319.823) 197.894,319.891 197.971,319.814 ccw(c198.042,319.884) 198.112,319.814 198.252,319.954 ccw(c198.182,320.024) 198.252,320.094 198.175,320.171 cw(c198.243,320.239) 198.175,320.306 198.321,320.452 cw(c198.388,320.385) 198.456,320.452 198.533,320.375 ccw(c198.603,320.445) 198.673,320.375 198.814,320.515 ccw(c198.743,320.586) 198.814,320.656 198.737,320.733 cw(c198.804,320.8) 198.737,320.868 198.882,321.013 cw(c198.95,320.946) 199.017,321.013 199.094,320.937 ccw(c199.164,321.007) 199.235,320.937 199.375,321.077 ccw(c199.305,321.147) 199.375,321.217 199.298,321.294 cw(c199.365,321.362) 199.298,321.429 199.444,321.575 cw(c199.511,321.507) 199.579,321.575 199.656,321.498 ccw(c199.726,321.568) 199.796,321.498 199.936,321.638 ccw(c199.866,321.709) 199.936,321.779 199.859,321.856 cw(c199.927,321.923) 199.859,321.991 200.005,322.136 cw(c200.073,322.069) 200.14,322.136 200.354,321.923 ccw(c200.424,321.993) 200.494,321.923 200.635,322.063 ccw(c200.564,322.133) 200.635,322.203 200.421,322.417 cw(c200.488,322.485) 200.421,322.552 200.567,322.698 cw(c200.634,322.63) 200.702,322.698 200.867,322.532 ccw(c200.938,322.602) 201.008,322.532 201.148,322.672 ccw(c201.078,322.743) 201.148,322.813 200.982,322.979 cw(c201.05,323.046) 200.982,323.113 201.128,323.259 cw(c201.196,323.192) 201.263,323.259 201.429,323.094 ccw(c201.499,323.164) 201.569,323.094 201.71,323.234 ccw(c201.639,323.304) 201.71,323.374 201.544,323.54 cw(c201.611,323.607) 201.544,323.675 201.69,323.821 cw(c201.757,323.753) 201.824,323.821 201.99,323.655 ccw(c202.06,323.725) 202.131,323.655 202.271,323.795 ccw(c202.201,323.865) 202.271,323.936 202.105,324.101 cw(c202.173,324.169) 202.105,324.236 202.251,324.382 cw(c202.318,324.315) 202.386,324.382 202.552,324.216 ccw(c202.622,324.287) 202.692,324.216 202.832,324.357 ccw(c202.762,324.427) 202.832,324.497 202.737,324.593 cw(c202.807,324.663) 202.737,324.733 202.927,324.923 203.434,325.43 203.434,335.975 203.707,336.248 203.707,338.149 203.987,338.43 204.642,338.43 204.853,338.218 v17(204.853,338.064)
DDR4_A5: R41.1 U1.AK27 U8.P5 U9.P5 U10.P5 U11.P5 | length 98
  L1 w0.116: U9.P5@166.876,338.46 167.272,338.857 v2(167.275,338.857) ; U11.P5@178.336,338.46 178.733,338.857 v2(178.735,338.857) ; U10.P5@189.797,338.46 190.193,338.857 v2(190.196,338.857) ; U1.AK27@191.397,314.539 v4(191.884,315.027) ; v2(200.853,338.864) U8.P5@201.257,338.46
  L1 w0.155: R41.1@158.737,341.233 v1(159.982,341.233)
  L12 (Sign) w0.092: 165.251,338.857 166.751,338.857 v2(167.275,338.857) 167.465,339.047 167.688,339.047 167.842,339.201 168.3,339.201 169.159,340.06 173.807,340.06 174.282,339.585 174.472,339.395 cw(c174.409,339.332) 174.472,339.269 174.437,339.233 ccw(c174.5,339.17) 174.437,339.106 174.627,338.916 ccw(c174.69,338.98) 174.753,338.916 174.789,338.952 cw(c174.852,338.889) 174.915,338.952 175.01,338.857 v2(178.735,338.857) 179.053,338.857 179.451,339.255 180.302,339.255 181.127,340.081 184.125,340.081 184.945,339.26 186.576,339.26 187.06,339.26 cw(c187.06,339.191) 187.129,339.191 187.129,339.18 ccw(c187.199,339.18) 187.199,339.111 187.406,339.111 ccw(c187.406,339.18) 187.476,339.18 187.476,339.26 187.476,339.337 cw(c187.545,339.337) 187.545,339.407 187.752,339.407 cw(c187.752,339.337) 187.822,339.337 187.822,339.26 187.822,339.18 ccw(c187.891,339.18) 187.891,339.111 188.099,339.111 ccw(c188.099,339.18) 188.168,339.18 188.168,339.191 cw(c188.237,339.191) 188.237,339.26 188.341,339.26 189.268,339.26 189.672,338.857 v2(190.196,338.857) 190.385,339.047 190.609,339.047 190.763,339.201 191.22,339.201 192.08,340.06 195.846,340.06 196.524,339.382 197.193,339.382 198.16,339.382 cw(c198.16,339.293) 198.25,339.293 198.25,338.968 ccw(c198.339,338.968) 198.339,338.878 198.608,338.878 ccw(c198.608,338.968) 198.697,338.968 198.697,339.382 198.697,339.496 cw(c198.787,339.496) 198.787,339.586 199.056,339.586 cw(c199.056,339.496) 199.145,339.496 199.145,339.382 199.145,338.968 ccw(c199.235,338.968) 199.235,338.878 199.504,338.878 ccw(c199.504,338.968) 199.593,338.968 199.593,339.293 cw(c199.683,339.293) 199.683,339.382 199.817,339.382 200.342,338.857 v2@200.861,338.857
  L12 (Sign) w0.151: v1(159.982,341.233) 160.607,341.233 161.446,340.395 161.491,340.395 163.029,338.857 165.251,338.857
  L3 (Sign) w0.092: 189.328,315.928 189.328,316.31 188.563,317.074 188.563,318.187 188.633,318.257 ccw(c188.563,318.327) 188.633,318.398 188.63,318.401 cw(c188.701,318.471) 188.63,318.541 188.771,318.681 cw(c188.841,318.611) 188.911,318.681 188.984,318.608 189.016,318.576 ccw(c189.087,318.646) 189.157,318.576 189.297,318.717 ccw(c189.227,318.787) 189.297,318.857 189.265,318.889 189.192,318.962 cw(c189.262,319.032) 189.192,319.103 189.332,319.243 cw(c189.402,319.173) 189.473,319.243 189.546,319.17 189.786,318.929 ccw(c189.856,319) 189.926,318.929 190.067,319.07 ccw(c189.997,319.14) 190.067,319.21 189.827,319.45 189.753,319.524 cw(c189.823,319.594) 189.753,319.664 189.894,319.804 cw(c189.964,319.734) 190.034,319.804 190.107,319.731 190.347,319.491 ccw(c190.418,319.561) 190.488,319.491 190.628,319.631 ccw(c190.558,319.701) 190.628,319.772 190.388,320.012 190.315,320.085 cw(c190.385,320.155) 190.315,320.225 190.455,320.366 cw(c190.525,320.296) 190.595,320.366 190.669,320.293 190.909,320.052 ccw(c190.979,320.123) 191.049,320.052 191.19,320.193 ccw(c191.119,320.263) 191.19,320.333 190.949,320.573 190.876,320.647 cw(c190.946,320.717) 190.876,320.787 191.016,320.927 cw(c191.087,320.857) 191.157,320.927 191.23,320.854 191.47,320.614 ccw(c191.54,320.684) 191.611,320.614 191.751,320.754 ccw(c191.681,320.824) 191.751,320.895 191.511,321.135 191.438,321.208 cw(c191.508,321.278) 191.438,321.348 191.578,321.489 cw(c191.648,321.419) 191.718,321.489 191.792,321.415 192.032,321.175 ccw(c192.102,321.245) 192.172,321.175 192.312,321.316 ccw(c192.242,321.386) 192.312,321.456 192.072,321.696 191.999,321.769 cw(c192.069,321.84) 191.999,321.91 192.139,322.05 cw(c192.21,321.98) 192.28,322.05 192.353,321.977 192.593,321.737 ccw(c192.663,321.807) 192.734,321.737 192.874,321.877 ccw(c192.804,321.947) 192.874,322.017 192.634,322.258 192.56,322.331 cw(c192.631,322.401) 192.56,322.471 192.701,322.612 cw(c192.771,322.541) 192.841,322.612 192.914,322.538 193.155,322.298 ccw(c193.225,322.368) 193.295,322.298 193.435,322.439 ccw(c193.365,322.509) 193.435,322.579 193.195,322.819 193.122,322.892 cw(c193.192,322.962) 193.122,323.033 193.262,323.173 cw(c193.332,323.103) 193.403,323.173 193.476,323.1 193.716,322.86 ccw(c193.786,322.93) 193.856,322.86 193.997,323 ccw(c193.927,323.07) 193.997,323.14 193.757,323.38 193.683,323.454 cw(c193.754,323.524) 193.683,323.594 193.824,323.734 cw(c193.894,323.664) 193.964,323.734 194.037,323.661 194.278,323.421 ccw(c194.348,323.491) 194.418,323.421 194.558,323.561 ccw(c194.488,323.632) 194.558,323.702 194.318,323.942 194.245,324.015 cw(c194.315,324.085) 194.245,324.156 194.385,324.296 cw(c194.455,324.226) 194.526,324.296 194.599,324.223 194.839,323.982 ccw(c194.909,324.053) 194.979,323.982 195.12,324.123 ccw(c195.049,324.193) 195.12,324.263 194.95,324.433 cw(c195.02,324.503) 194.95,324.574 195.212,324.836 195.212,330.648 195.631,331.067 195.631,331.483 196.438,332.29 196.438,334.652 200.643,338.857 200.861,338.857 v2(200.853,338.864) ; 189.332,315.928 189.332,315.746 188.956,315.37 188.907,315.37 188.718,315.182 188.718,314.916 188.907,314.728 189.391,314.728 189.605,314.514 190.167,314.514 190.322,314.668 191.091,314.668 191.271,314.847 191.271,315.413 191.419,315.562 191.671,315.562 191.711,315.522 191.711,315.2 v4(191.884,315.027)
DDR4_A6: R43.1 U1.AF27 U8.P2 U9.P2 U10.P2 U11.P2 | length 102.8
  L1 w0.116: U9.P2@171.676,338.46 v2(172.079,338.864) ; U11.P2@183.136,338.46 v2(183.54,338.864) ; U1.AF27@187.397,314.539 v4(187.884,314.052) ; U10.P2@194.597,338.46 v2(195,338.864) ; U8.P2@206.057,338.46 v2(206.461,338.864)
  L1 w0.155: v4(178.481,343.555) R43.1@178.481,344.799
  L5 (Sign) w0.092: v2(172.079,338.864) 173.515,338.864 173.911,339.26 174.6,339.26 174.734,339.26 ccw(c174.734,339.35) 174.823,339.35 174.823,339.393 cw(c174.913,339.393) 174.913,339.482 175.182,339.482 cw(c175.182,339.393) 175.271,339.393 175.271,339.26 175.271,339.128 ccw(c175.361,339.128) 175.361,339.039 175.63,339.039 ccw(c175.63,339.128) 175.719,339.128 175.719,339.171 cw(c175.809,339.171) 175.809,339.26 176.187,339.26 180.228,339.26 181.008,338.48 182.583,338.48 182.966,338.864 v2(183.54,338.864) 183.839,338.864 184.217,339.242 184.404,339.242 184.577,339.242 184.854,339.242 cw(c184.854,339.173) 184.923,339.173 184.923,339.008 ccw(c184.993,339.008) 184.993,338.939 185.2,338.939 ccw(c185.2,339.008) 185.269,339.008 185.269,339.242 185.269,339.477 cw(c185.339,339.477) 185.339,339.546 185.546,339.546 cw(c185.546,339.477) 185.616,339.477 185.616,339.312 ccw(c185.685,339.312) 185.685,339.242 186.195,339.242 191.707,339.242 192.469,338.48 194.043,338.48 194.427,338.864 v2(195,338.864) 195.227,338.864 195.623,339.26 195.77,339.26 196.189,339.26 cw(c196.189,339.171) 196.279,339.171 196.279,339.017 ccw(c196.369,339.017) 196.369,338.927 196.637,338.927 ccw(c196.637,339.017) 196.727,339.017 196.727,339.26 196.727,339.523 cw(c196.816,339.523) 196.816,339.613 197.085,339.613 cw(c197.085,339.523) 197.175,339.523 197.175,339.26 197.175,339.192 ccw(c197.264,339.192) 197.264,339.103 197.533,339.103 ccw(c197.533,339.192) 197.622,339.192 197.622,339.26 197.622,339.523 cw(c197.712,339.523) 197.712,339.613 197.981,339.613 cw(c197.981,339.523) 198.07,339.523 198.07,339.26 198.07,339.192 ccw(c198.16,339.192) 198.16,339.103 198.428,339.103 ccw(c198.428,339.192) 198.518,339.192 198.518,339.26 198.518,339.523 cw(c198.608,339.523) 198.608,339.613 198.876,339.613 cw(c198.876,339.523) 198.966,339.523 198.966,339.26 198.966,339.192 ccw(c199.055,339.192) 199.055,339.103 199.324,339.103 ccw(c199.324,339.192) 199.414,339.192 199.414,339.26 199.414,339.523 cw(c199.503,339.523) 199.503,339.613 199.772,339.613 cw(c199.772,339.523) 199.861,339.523 199.861,339.26 199.861,339.192 ccw(c199.951,339.192) 199.951,339.103 200.22,339.103 ccw(c200.22,339.192) 200.309,339.192 200.309,339.26 200.309,339.295 cw(c200.399,339.295) 200.399,339.385 200.667,339.385 cw(c200.667,339.295) 200.757,339.295 200.757,339.26 ccw(c200.833,339.26) 200.833,339.185 201.129,339.185 ccw(c201.129,339.26) 201.205,339.26 201.429,339.26 203.149,339.26 203.944,338.465 204.078,338.465 ccw(c204.078,338.555) 204.168,338.555 204.168,338.578 cw(c204.257,338.578) 204.257,338.668 204.526,338.668 cw(c204.526,338.578) 204.616,338.578 204.616,338.555 ccw(c204.705,338.555) 204.705,338.465 204.98,338.465 205.489,338.465 205.887,338.864 v2(206.461,338.864)
  L3 (Sign) w0.092: v2(172.079,338.864) 173.022,339.807 174.25,339.807 174.969,340.525 176.05,340.525 176.611,341.085 ; v4(187.884,314.052) 187.884,314.03 188.511,313.403 188.511,311.882 188.986,311.406 192.691,311.406 197.601,316.317 197.671,316.387 ccw(c197.601,316.457) 197.671,316.527 197.317,316.882 cw(c197.387,316.953) 197.317,317.023 197.457,317.163 cw(c197.527,317.093) 197.597,317.163 197.952,316.808 ccw(c198.022,316.878) 198.093,316.808 198.233,316.949 ccw(c198.163,317.019) 198.233,317.089 197.878,317.444 cw(c197.948,317.514) 197.878,317.584 198.018,317.725 cw(c198.088,317.654) 198.159,317.725 198.514,317.37 ccw(c198.584,317.44) 198.654,317.37 198.794,317.51 ccw(c198.724,317.58) 198.794,317.65 198.439,318.005 cw(c198.51,318.076) 198.439,318.146 198.58,318.286 cw(c198.65,318.216) 198.72,318.286 199.075,317.931 ccw(c199.145,318.001) 199.215,317.931 199.356,318.071 ccw(c199.286,318.142) 199.356,318.212 199.001,318.567 cw(c199.071,318.637) 199.001,318.707 199.141,318.847 cw(c199.211,318.777) 199.282,318.847 199.636,318.493 ccw(c199.707,318.563) 199.777,318.493 199.917,318.633 ccw(c199.847,318.703) 199.917,318.773 199.562,319.129 cw(c199.632,319.199) 199.562,319.269 199.702,319.409 cw(c199.772,319.339) 199.843,319.409 200.198,319.054 ccw(c200.268,319.124) 200.338,319.054 200.549,319.265 202.023,320.738 204.01,322.725 204.01,335.707 204.363,336.06 205.816,336.06 206.088,336.332 206.088,337.358 205.791,337.655 205.791,338.496 206.148,338.853 206.449,338.853 v2(206.461,338.864)
  L3 (Sign) w0.151: 176.611,341.085 178.486,342.961 178.486,343.55 v4(178.481,343.555)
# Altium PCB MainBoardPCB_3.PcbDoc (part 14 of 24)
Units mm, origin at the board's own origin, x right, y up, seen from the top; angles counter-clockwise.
Board outline 258.95 x 308.86 mm, 16 copper layers (L1, L2 (GND), L3 (Sign), L4 (GND), L5 (Sign), L6 (PWR/GND), L7(PWR/GND), L8 (Plane_GND), L9 (PWR/GND), L10 (PWR/GND), L11 (PWR/GND), L12 (Sign), L13 (GND), L14 (Sign), L15 (GND), L16), stack 2.502 mm thick; 2402 components, 1749 nets, 8407 pads, 3409 vias.
Unrouted connection lines stored in the file: 4352.

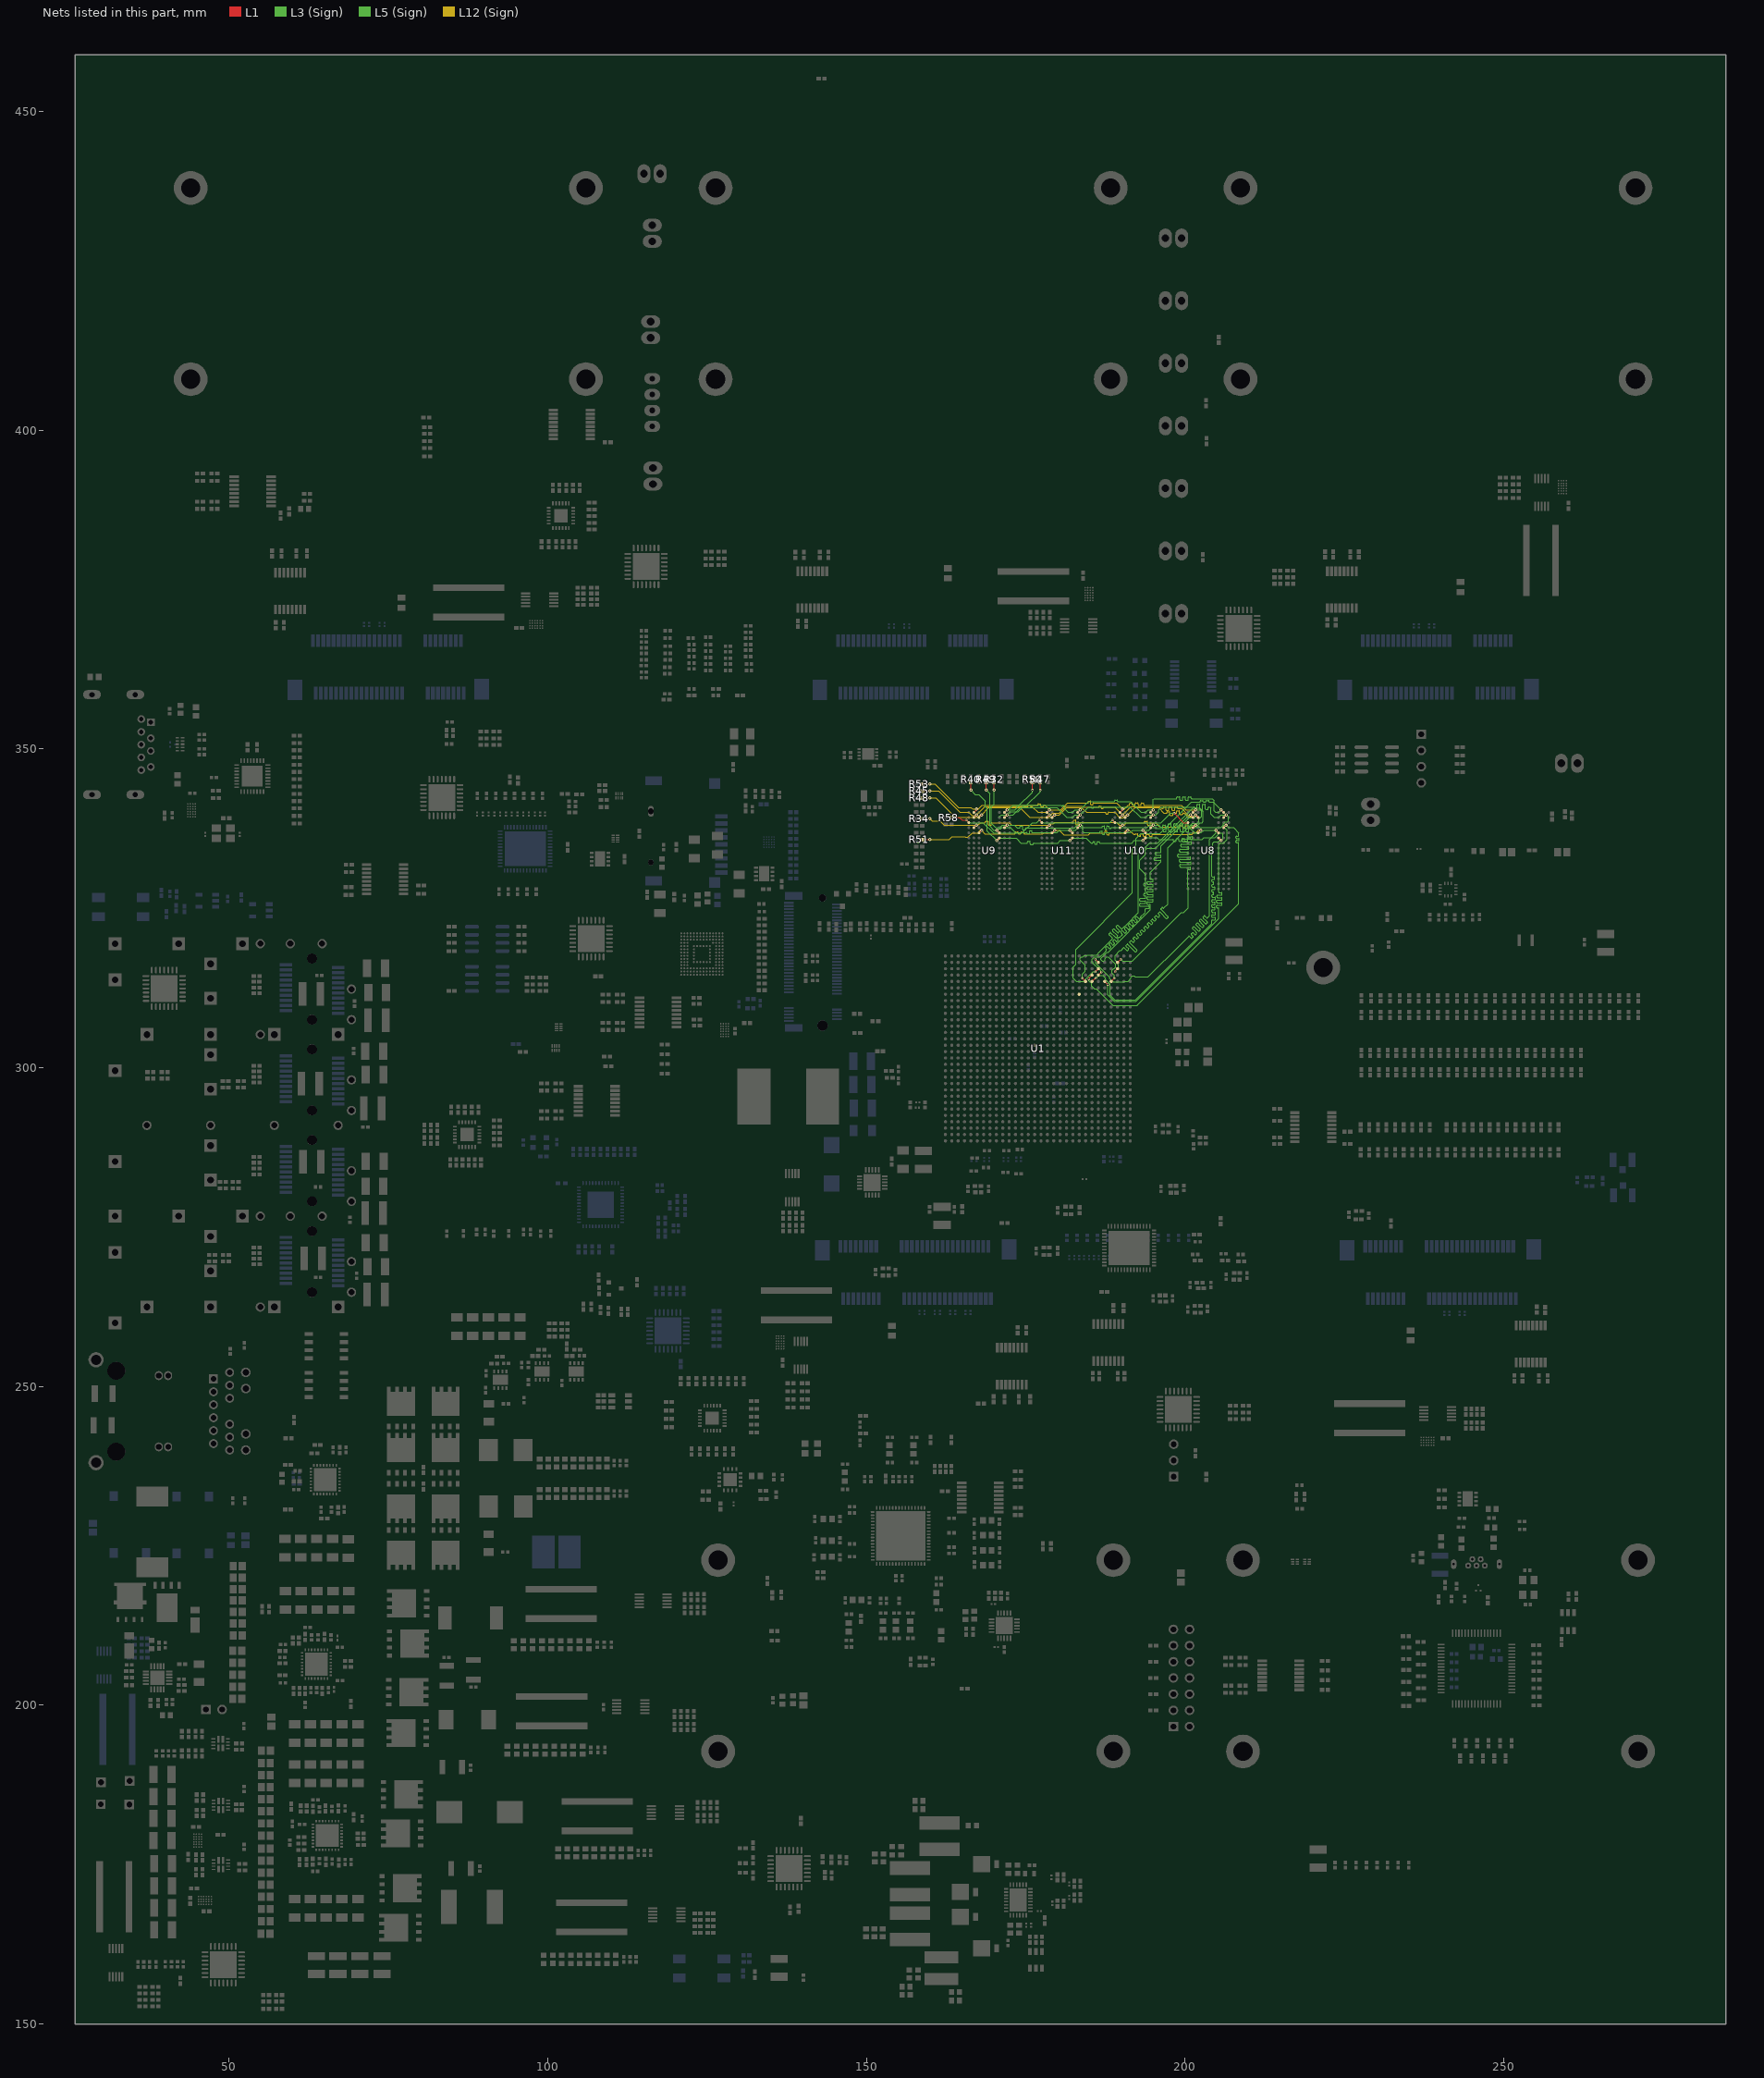
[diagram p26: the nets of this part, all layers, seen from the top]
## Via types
v1: diameter 0.5, hole 0.2, L1 to L16, tented both sides, 1267 vias
v2: diameter 0.5/0.35/0.35/0.35/0.35/0.35/0.35/0.35/0.35/0.35/0.35/0.35/0.35/0.35/0.35/0.5 (per signal layer), hole 0.15, L1 to L16, tented both sides, 463 vias
v3: diameter 0.5, hole 0.2, L1 to L16, 446 vias
v4: diameter 0.35/0/0.35 (per signal layer), hole 0.127, L1 to L3 (Sign), tented both sides, 347 vias
v5: diameter 0.5/0.35/0.35/0.35/0.35/0.35/0.35/0.35/0.35/0.35/0.35/0.35/0.35/0.35/0.35/0.5 (per signal layer), hole 0.2, L1 to L16, tented both sides, 244 vias
v6: diameter 0.8, hole 0.4, L1 to L16, tented both sides, 168 vias
v7: diameter 2.54, hole 1.02, L1 to L16, 113 vias
v8: diameter 1.4, hole 0.5, L1 to L16, tented both sides, 80 vias
v9: diameter 0.5/0/0.5 (per signal layer), hole 0.2, L14 (Sign) to L16, tented both sides, 62 vias
v10: diameter 0.35/0/0.35 (per signal layer), hole 0.127, L1 to L3 (Sign), 38 vias
v11: diameter 0.35, hole 0.127, L1 to L2 (GND), tented both sides, 36 vias
v12: diameter 0.4, hole 0.2, L1 to L16, 16 vias
v13: diameter 0.25, hole 0.2, L1 to L16, 16 vias
v14: diameter 0.35, hole 0.127, L1 to L16, tented both sides, 16 vias
v15: diameter 0.3, hole 0.2, L1 to L16, 15 vias
v16: diameter 0.45, hole 0.15, L1 to L16, 12 vias
v17: diameter 0.5/0.35/0.35/0.35/0.35/0.35/0.35/0.35/0.35/0.35/0.35/0.35/0.35/0.35/0.35/0.45 (per signal layer), hole 0.15, L1 to L16, tented both sides, 10 vias
v18: diameter 0.2/0/0.2 (per signal layer), hole 0.1, L1 to L3 (Sign), tented both sides, 9 vias
v19: diameter 0.4, hole 0.1, L1 to L16, 7 vias
v20: diameter 0.5, hole 0.2, L3 (Sign) to L6 (PWR/GND), tented both sides, 6 vias
v21: diameter 1.15, hole 1.15, L1 to L16, 5 vias
v22: diameter 1.65, hole 1.65, L1 to L16, 5 vias
v23: diameter 0.35/0/0.35 (per signal layer), hole 0.127, L14 (Sign) to L16, tented both sides, 5 vias
v24: diameter 0.5, hole 0.2, L11 (PWR/GND) to L14 (Sign), tented both sides, 4 vias
v25: diameter 0.2, hole 0.1, L1 to L16, 4 vias
v26: diameter 0.35, hole 0.127, L1 to L2 (GND), 2 vias
v27: diameter 0.4, hole 0.15, L1 to L16, 2 vias
v28: diameter 0.4, hole 0.2, L1 to L16, tented both sides, 2 vias
v29: diameter 0.5/0.35/0.35/0.35/0.35/0.35/0.35/0.35/0.35/0.35/0.35/0.35/0.35/0.35/0.35/0.5 (per signal layer), hole 0.15, L1 to L16, 2 vias
v30: diameter 0.35, hole 0.127, L3 (Sign) to L6 (PWR/GND), tented both sides, 2 vias
v31: diameter 0.5/0.35/0.35/0.35/0.35/0.35/0.35/0.35/0.35/0.35/0.35/0.35/0.35/0.35/0.35/0.5 (per signal layer), hole 0.2, L1 to L16, 1 vias
v32: diameter 0.35/0.35/0.35 (per signal layer), hole 0.127, L1 to L3 (Sign), tented both sides, 1 vias
v33: diameter 0.45/0/0.45 (per signal layer), hole 0.15, L1 to L3 (Sign), tented both sides, 1 vias
v34: diameter 0.45/0/0.45 (per signal layer), hole 0.2, L14 (Sign) to L16, tented both sides, 1 vias
v35: diameter 0.35, hole 0.127, L2 (GND) to L3 (Sign), 1 vias

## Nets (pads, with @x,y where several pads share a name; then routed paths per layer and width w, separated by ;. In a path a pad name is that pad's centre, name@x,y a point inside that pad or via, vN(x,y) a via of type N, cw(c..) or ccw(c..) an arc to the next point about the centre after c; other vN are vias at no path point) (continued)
DDR4_A7: R45.1 U1.AE27 U8.R5 U9.R5 U10.R5 U11.R5 | length 100.7
  L1 w0.116: U9.R5@166.876,339.26 v2(167.279,339.664) ; U11.R5@178.336,339.26 178.733,339.657 v2(178.735,339.657) ; U1.AE27@186.397,314.539 v4(186.884,315.027) v4@186.884,315.052 ; U10.R5@189.797,339.26 190.193,339.657 v2(190.195,339.657) ; v2(200.853,339.664) U8.R5@201.257,339.26
  L1 w0.155: R45.1@158.737,343.411 v1(159.982,343.411)
  L12 (Sign) w0.092: 165.251,340.06 166.076,340.06 166.576,339.56 167.178,339.56 168.598,340.981 174.981,340.981 175.248,340.981 cw(c175.248,340.891) 175.338,340.891 ccw(c175.427,340.891) 175.427,340.802 175.696,340.802 ccw(c175.696,340.891) 175.785,340.891 cw(c175.875,340.891) 175.875,340.981 176.009,340.981 176.93,340.06 178.332,340.06 v2(178.735,339.657) 178.926,339.657 179.248,339.979 180.276,339.979 181.331,341.033 183.851,341.033 184.027,340.858 186.118,340.858 186.416,340.858 ccw(c186.416,340.927) 186.485,340.927 186.485,340.965 cw(c186.554,340.965) 186.554,341.034 186.762,341.034 cw(c186.762,340.965) 186.831,340.965 186.831,340.858 186.831,340.751 ccw(c186.9,340.751) 186.9,340.682 187.108,340.682 ccw(c187.108,340.751) 187.177,340.751 187.177,340.789 cw(c187.247,340.789) 187.247,340.858 187.35,340.858 188.995,340.858 v2(190.195,339.657) ; v2@190.098,339.56 v2(190.195,339.657) ; v2@200.853,339.657 200.449,339.657 199.466,340.639 199.314,340.639 198.92,340.639 cw(c198.92,340.729) 198.83,340.729 198.83,340.798 ccw(c198.741,340.798) 198.741,340.887 198.472,340.887 ccw(c198.472,340.798) 198.382,340.798 198.382,340.639 198.382,340.481 cw(c198.293,340.481) 198.293,340.392 198.024,340.392 cw(c198.024,340.481) 197.935,340.481 197.935,340.639 197.935,340.798 ccw(c197.845,340.798) 197.845,340.887 197.576,340.887 ccw(c197.576,340.798) 197.487,340.798 197.487,340.639 197.487,340.481 cw(c197.397,340.481) 197.397,340.392 197.129,340.392 cw(c197.129,340.481) 197.039,340.481 197.039,340.639 197.039,340.798 ccw(c196.95,340.798) 196.95,340.887 196.681,340.887 ccw(c196.681,340.798) 196.591,340.798 196.591,340.729 cw(c196.502,340.729) 196.502,340.639 196.367,340.639 196.026,340.981 191.519,340.981 v2(190.195,339.657)
  L12 (Sign) w0.151: v1(159.982,343.411) 161.325,343.411 164.676,340.06 165.251,340.06
  L3 (Sign) w0.092: v4(186.884,315.027) 186.884,315.074 186.615,315.344 185.419,316.539 185.419,317.004 185.788,317.373 186.627,317.373 187.413,318.148 187.554,318.287 187.598,318.331 187.669,318.4 ccw(c187.599,318.471) 187.67,318.541 187.526,318.687 cw(c187.596,318.757) 187.527,318.828 187.668,318.967 cw(c187.738,318.896) 187.808,318.966 188.023,318.749 188.068,318.703 ccw(c188.139,318.772) 188.208,318.702 188.35,318.841 ccw(c188.28,318.912) 188.351,318.981 188.305,319.028 188.083,319.253 cw(c188.154,319.323) 188.084,319.394 188.225,319.533 cw(c188.295,319.462) 188.366,319.532 188.588,319.306 188.629,319.264 ccw(c188.7,319.334) 188.77,319.263 188.911,319.403 ccw(c188.841,319.473) 188.912,319.543 188.871,319.585 188.676,319.782 cw(c188.747,319.852) 188.677,319.922 188.819,320.062 cw(c188.888,319.991) 188.959,320.061 189.153,319.864 189.191,319.826 ccw(c189.262,319.895) 189.331,319.825 189.473,319.964 ccw(c189.403,320.035) 189.474,320.104 189.436,320.142 189.428,320.15 cw(c189.499,320.22) 189.429,320.291 189.571,320.43 cw(c189.64,320.359) 189.711,320.429 ; 189.711,320.429 189.695,320.445 ccw(c189.719,320.469) 189.743,320.445 190.002,320.7 190.066,320.764 190.137,320.834 ccw(c190.067,320.904) 190.138,320.974 189.949,321.166 cw(c190.02,321.235) 189.95,321.306 190.092,321.445 cw(c190.161,321.375) 190.232,321.444 190.491,321.182 190.519,321.153 ccw(c190.589,321.223) 190.659,321.152 190.8,321.292 ccw(c190.731,321.362) 190.801,321.432 190.773,321.461 190.506,321.731 cw(c190.577,321.801) 190.507,321.872 190.649,322.011 cw(c190.718,321.94) 190.789,322.01 191.056,321.739 191.08,321.715 ccw(c191.151,321.785) 191.22,321.714 191.362,321.853 ccw(c191.292,321.924) 191.363,321.994 191.339,322.018 191.072,322.289 cw(c191.142,322.359) 191.073,322.429 191.214,322.569 cw(c191.284,322.498) 191.354,322.568 191.621,322.297 191.642,322.276 ccw(c191.712,322.346) 191.782,322.275 191.923,322.415 ccw(c191.854,322.485) 191.924,322.555 191.904,322.575 191.633,322.85 cw(c191.704,322.92) 191.634,322.991 191.775,323.13 cw(c191.845,323.059) 191.916,323.129 192.187,322.854 192.203,322.838 ccw(c192.274,322.907) 192.343,322.837 192.485,322.976 ccw(c192.415,323.047) 192.486,323.117 192.47,323.133 192.195,323.412 cw(c192.265,323.481) 192.196,323.552 192.337,323.692 cw(c192.407,323.621) 192.477,323.691 192.752,323.412 192.764,323.399 ccw(c192.835,323.469) 192.905,323.398 193.046,323.538 ccw(c192.976,323.608) 193.047,323.678 ; 193.047,323.678 193.063,323.662 cw(c193.092,323.69) 193.064,323.718 193.661,324.307 193.764,324.409 ; 193.764,324.508 193.764,324.409 ; v2(200.853,339.664) 200.804,339.615 200.541,339.615 195.387,334.46 194.068,334.46 193.764,334.156 193.764,333.439 192.865,332.54 192.865,331.238 193.764,330.34 193.764,330.141 cw(c193.764,330.083) 193.822,330.083 193.822,329.802 cw(c193.764,329.802) 193.764,329.744 193.764,329.347 cw(c193.764,329.291) 193.82,329.291 193.82,329.006 cw(c193.764,329.006) 193.764,328.95 193.63,328.95 ccw(c193.63,328.851) 193.531,328.851 193.531,328.652 ccw(c193.63,328.652) 193.63,328.553 193.764,328.553 cw(c193.764,328.497) 193.82,328.497 193.82,328.212 cw(c193.764,328.212) 193.764,328.156 193.764,327.759 cw(c193.764,327.703) 193.82,327.703 193.82,327.418 cw(c193.764,327.418) 193.764,327.362 193.65,327.362 ccw(c193.65,327.263) 193.55,327.263 193.55,327.064 ccw(c193.65,327.064) 193.65,326.965 193.764,326.965 cw(c193.764,326.909) 193.82,326.909 193.82,326.624 cw(c193.764,326.624) 193.764,326.568 192.965,326.568 ccw(c192.965,326.469) 192.865,326.469 192.865,326.27 ccw(c192.965,326.27) 192.965,326.171 193.764,326.171 cw(c193.764,326.115) 193.82,326.115 193.82,325.83 cw(c193.764,325.83) 193.764,325.774 192.965,325.774 ccw(c192.965,325.675) 192.865,325.675 192.865,325.476 ccw(c192.965,325.476) 192.965,325.377 193.764,325.377 194.28,325.377 cw(c194.28,325.278) 194.379,325.278 194.379,325.079 cw(c194.28,325.079) 194.28,324.98 193.863,324.98 ccw(c193.863,324.881) 193.764,324.881 193.764,324.583 193.764,324.409
DDR4_A8: R47.1 U1.AF26 U8.R2 U9.R2 U10.R2 U11.R2 | length 102.5
  L1 w0.116: U9.R2@171.676,339.26 v2(172.079,339.664) ; U11.R2@183.136,339.26 v2(183.54,339.664) ; U1.AF26@187.397,313.539 v4(187.884,313.052) ; U10.R2@194.597,339.26 v2(195,339.664) ; U8.R2@206.057,339.26 v2(206.461,339.664)
  L1 w0.155: v4(177.272,343.555) R47.1@177.272,344.8
  L5 (Sign) w0.092: 170.852,339.343 171.173,339.664 v2(172.079,339.664) 173.045,339.664 174.17,340.789 179.911,340.789 180.239,340.462 181.44,339.26 182.336,339.26 182.74,339.664 v2(183.54,339.664) 184.803,340.927 184.976,340.927 185.253,340.927 cw(c185.253,340.858) 185.322,340.858 185.322,340.794 ccw(c185.391,340.794) 185.391,340.725 185.599,340.725 ccw(c185.599,340.794) 185.668,340.794 185.668,340.858 cw(c185.737,340.858) 185.737,340.927 186.118,340.927 191.377,340.927 193.044,339.26 193.797,339.26 194.2,339.664 v2(195,339.664) 195.408,339.664 195.846,340.102 195.846,340.481 196.292,340.927 200.774,340.927 200.965,340.927 201.355,340.927 cw(c201.355,340.867) 201.415,340.867 201.415,340.875 ; 201.415,340.875 ccw(c201.504,340.875) 201.504,340.786 201.773,340.786 ccw(c201.773,340.875) 201.862,340.875 201.862,340.927 201.862,341.236 cw(c201.952,341.236) 201.952,341.326 202.221,341.326 cw(c202.221,341.236) 202.31,341.236 202.31,340.927 202.31,340.618 ccw(c202.4,340.618) 202.4,340.528 202.669,340.528 ccw(c202.669,340.618) 202.758,340.618 202.758,340.927 202.758,341.236 cw(c202.848,341.236) 202.848,341.326 203.116,341.326 cw(c203.116,341.236) 203.206,341.236 203.206,340.927 203.206,340.618 ccw(c203.295,340.618) 203.295,340.528 203.564,340.528 ccw(c203.564,340.618) 203.654,340.618 203.654,340.837 cw(c203.743,340.837) 203.743,340.927 203.878,340.927 204.038,340.766 204.038,339.801 204.579,339.26 205.257,339.26 205.661,339.664 v2(206.461,339.664)
  L3 (Sign) w0.092: v2(172.079,339.664) 172.613,340.198 173.831,340.198 174.719,341.085 ; v4(187.884,313.052) 187.884,311.416 188.879,310.422 192.299,310.422 205.282,323.405 205.282,324.904 205.282,325.003 ccw(c205.183,325.003) 205.183,325.103 205.032,325.103 cw(c205.032,325.202) 204.932,325.202 204.932,325.4 cw(c205.032,325.4) 205.032,325.5 205.282,325.5 205.732,325.5 ccw(c205.732,325.599) 205.832,325.599 205.832,325.797 ccw(c205.732,325.797) 205.732,325.897 205.282,325.897 205.032,325.897 cw(c205.032,325.996) 204.932,325.996 204.932,326.194 cw(c205.032,326.194) 205.032,326.294 205.282,326.294 205.732,326.294 ccw(c205.732,326.393) 205.832,326.393 205.832,326.591 ccw(c205.732,326.591) 205.732,326.691 205.282,326.691 205.106,326.691 cw(c205.106,326.79) 205.007,326.79 205.007,326.988 cw(c205.106,326.988) 205.106,327.088 205.282,327.088 205.732,327.088 ccw(c205.732,327.187) 205.832,327.187 205.832,327.385 ccw(c205.732,327.385) 205.732,327.485 205.382,327.485 cw(c205.382,327.584) 205.282,327.584 205.282,328.324 205.282,334.975 205.524,335.216 206.013,335.216 206.628,335.831 206.628,337.288 206.042,337.873 206.042,338.3 206.286,338.544 206.327,338.544 206.328,338.543 206.593,338.543 206.594,338.544 206.604,338.544 206.781,338.722 206.781,338.731 206.782,338.997 206.781,339.343 v2(206.461,339.664)
  L3 (Sign) w0.151: 174.719,341.085 175.049,341.085 177.272,343.308 v4(177.272,343.555)
DDR4_A9: R48.1 U1.AG26 U8.R4 U9.R4 U10.R4 U11.R4 | length 100.8
  L1 w0.116: U9.R4@167.676,339.26 v2(168.079,339.664) ; U11.R4@179.136,339.26 179.533,339.657 v2(179.535,339.657) ; U1.AG26@188.397,313.539 v4(188.884,314.027) ; U10.R4@190.597,339.26 190.993,339.657 v3(190.995,339.657) ; v3(201.653,339.664) U8.R4@202.057,339.26
  L1 w0.155: R48.1@158.737,342.322 v1(159.982,342.322)
  L12 (Sign) w0.092: 165.251,339.26 167.443,339.26 167.847,339.664 v2(168.079,339.664) 169.204,340.789 174.119,340.789 175.648,339.26 179.139,339.26 v2(179.535,339.657) 180.231,339.657 181.416,340.841 183.771,340.841 184.551,340.06 186.099,340.06 187.511,340.06 cw(c187.511,339.991) 187.58,339.991 187.58,339.901 ccw(c187.65,339.901) 187.65,339.831 187.857,339.831 ccw(c187.857,339.901) 187.927,339.901 187.927,339.991 cw(c187.996,339.991) 187.996,340.06 188.1,340.06 188.981,340.06 189.802,339.239 190.306,339.239 190.724,339.657 v3(190.995,339.657) 192.127,340.789 195.824,340.789 196.685,339.928 196.736,339.928 197.089,339.928 ccw(c197.089,340.018) 197.178,340.018 197.178,340.099 cw(c197.268,340.099) 197.268,340.189 197.537,340.189 cw(c197.537,340.099) 197.626,340.099 197.626,339.928 197.626,339.674 ccw(c197.716,339.674) 197.716,339.585 197.984,339.585 ccw(c197.984,339.674) 198.074,339.674 198.074,339.839 cw(c198.163,339.839) 198.163,339.928 198.298,339.928 198.611,339.928 ccw(c198.611,340.018) 198.7,340.018 198.7,340.234 cw(c198.79,340.234) 198.79,340.324 199.059,340.324 cw(c199.059,340.234) 199.148,340.234 199.148,339.928 199.148,339.83 ccw(c199.238,339.83) 199.238,339.741 199.506,339.741 ccw(c199.506,339.83) 199.596,339.83 199.596,339.839 cw(c199.686,339.839) 199.686,339.928 199.82,339.928 200.412,339.336 201.325,339.336 v3(201.653,339.664)
  L12 (Sign) w0.151: v1(159.982,342.322) 160.864,342.322 163.926,339.26 165.251,339.26
  L3 (Sign) w0.092: v4(188.884,314.027) 188.884,314.479 188.527,314.836 188.527,315.261 188.827,315.562 188.876,315.562 189.128,315.814 189.128,315.952 189.132,315.955 189.132,316.221 188.944,316.409 188.939,316.409 188.266,317.082 188.266,317.118 188.034,317.35 187.998,317.35 187.973,317.375 187.657,317.375 187.413,317.13 187.413,316.905 187.22,316.713 186.991,316.713 186.76,316.944 186.76,317.167 187.715,318.122 187.935,318.122 194.571,324.759 194.571,325.552 ccw(c194.498,325.552) 194.498,325.625 194.15,325.625 cw(c194.15,325.724) 194.051,325.724 194.051,325.923 cw(c194.15,325.923) 194.15,326.022 194.571,326.022 194.882,326.022 ccw(c194.882,326.121) 194.981,326.121 194.981,326.32 ccw(c194.882,326.32) 194.882,326.419 194.571,326.419 194.15,326.419 cw(c194.15,326.518) 194.051,326.518 194.051,326.717 cw(c194.15,326.717) 194.15,326.816 194.571,326.816 194.882,326.816 ccw(c194.882,326.915) 194.981,326.915 194.981,327.114 ccw(c194.882,327.114) 194.882,327.213 194.571,327.213 194.15,327.213 cw(c194.15,327.312) 194.051,327.312 194.051,327.511 cw(c194.15,327.511) 194.15,327.61 194.571,327.61 194.882,327.61 ccw(c194.882,327.709) 194.981,327.709 194.981,327.908 ccw(c194.882,327.908) 194.882,328.007 194.571,328.007 194.15,328.007 cw(c194.15,328.106) 194.051,328.106 194.051,328.305 cw(c194.15,328.305) 194.15,328.404 194.571,328.404 194.882,328.404 ccw(c194.882,328.503) 194.981,328.503 194.981,328.702 ccw(c194.882,328.702) 194.882,328.801 194.571,328.801 194.15,328.801 cw(c194.15,328.9) 194.051,328.9 194.051,329.099 cw(c194.15,329.099) 194.15,329.198 194.571,329.198 194.882,329.198 ccw(c194.882,329.297) 194.981,329.297 194.981,329.496 ccw(c194.882,329.496) 194.882,329.595 194.67,329.595 cw(c194.67,329.694) 194.571,329.694 194.571,329.794 194.571,330.695 196.222,332.346 196.222,332.376 196.222,332.475 ccw(c196.122,332.475) 196.122,332.574 195.26,332.574 cw(c195.26,332.674) 195.161,332.674 195.161,332.872 cw(c195.26,332.872) 195.26,332.971 196.122,332.971 ccw(c196.122,333.071) 196.222,333.071 196.222,333.269 ccw(c196.122,333.269) 196.122,333.368 195.424,333.368 cw(c195.424,333.468) 195.325,333.468 195.325,333.666 cw(c195.424,333.666) 195.424,333.765 196.122,333.765 ccw(c196.122,333.865) 196.222,333.865 196.222,334.162 196.222,334.796 200.681,339.255 201.536,339.255 201.653,339.372 v3(201.653,339.664)
DDR4_A10: R49.1 U1.AE29 U8.M3 U9.M3 U10.M3 U11.M3 | length 101.4
  L1 w0.116: v2(170.472,337.264) U9.M3@170.876,336.86 ; v2(181.933,337.264) U11.M3@182.336,336.86 ; v4(185.91,317.027) U1.AE29@186.397,316.539 ; v2(193.393,337.264) U10.M3@193.797,336.86 ; v17(204.853,337.264) U8.M3@205.257,336.86
  L1 w0.155: v1(168.812,343.555) R49.1@168.812,344.799
  L5 (Sign) w0.092: 169.377,341.085 169.377,337.887 170.001,337.264 v2(170.472,337.264) 170.709,337.501 171.075,337.501 171.242,337.668 172.6,337.668 173.4,336.868 175.006,336.868 175.145,336.868 cw(c175.145,336.808) 175.204,336.808 ccw(c175.264,336.808) 175.264,336.748 175.542,336.748 ccw(c175.542,336.808) 175.601,336.808 175.601,336.868 175.601,337.113 cw(c175.661,337.113) 175.661,337.173 175.939,337.173 cw(c175.939,337.113) 175.998,337.113 175.998,336.927 ccw(c176.058,336.927) 176.058,336.868 176.479,336.868 179.929,336.868 180.325,337.264 v2(181.933,337.264) 182.776,337.264 183.18,337.668 183.711,337.668 183.937,337.442 183.937,337.051 184.121,336.868 185.89,336.868 186.606,336.868 ccw(c186.606,336.937) 186.675,336.937 186.675,337.037 cw(c186.745,337.037) 186.745,337.106 186.952,337.106 cw(c186.952,337.037) 187.022,337.037 187.022,336.868 187.022,336.698 ccw(c187.091,336.698) 187.091,336.629 187.299,336.629 ccw(c187.299,336.698) 187.368,336.698 187.368,336.798 cw(c187.437,336.798) 187.437,336.868 187.541,336.868 191.389,336.868 191.785,337.264 v2(193.393,337.264) 193.4,337.257 194.34,337.257 194.773,337.689 195.368,337.689 195.512,337.545 196.088,337.545 196.477,337.545 cw(c196.477,337.456) 196.566,337.456 196.566,337.105 ccw(c196.656,337.105) 196.656,337.016 196.925,337.016 ccw(c196.925,337.105) 197.014,337.105 197.014,337.456 cw(c197.104,337.456) 197.104,337.545 197.372,337.545 cw(c197.372,337.456) 197.462,337.456 197.462,337.105 ccw(c197.551,337.105) 197.551,337.016 197.82,337.016 ccw(c197.82,337.105) 197.91,337.105 197.91,337.456 cw(c197.999,337.456) 197.999,337.545 198.268,337.545 cw(c198.268,337.456) 198.357,337.456 198.357,337.105 ccw(c198.447,337.105) 198.447,337.016 198.716,337.016 ccw(c198.716,337.105) 198.805,337.105 198.805,337.456 cw(c198.895,337.456) 198.895,337.545 199.164,337.545 cw(c199.164,337.456) 199.253,337.456 199.253,337.119 ccw(c199.343,337.119) 199.343,337.03 199.611,337.03 ccw(c199.611,337.119) 199.701,337.119 199.701,337.456 cw(c199.79,337.456) 199.79,337.545 200.059,337.545 cw(c200.059,337.456) 200.149,337.456 200.149,337.105 ccw(c200.238,337.105) 200.238,337.016 200.507,337.016 ccw(c200.507,337.105) 200.596,337.105 200.596,337.456 cw(c200.686,337.456) 200.686,337.545 200.82,337.545 201.498,336.868 202.54,336.868 202.936,337.264 v17(204.853,337.264)
  L5 (Sign) w0.151: v1(168.812,343.555) 169.377,342.989 169.377,341.085
  L3 (Sign) w0.092: v4(185.91,317.027) 185.995,316.941 185.995,316.395 188.205,314.185 188.205,313.98 188.747,313.439 190.312,313.439 190.454,313.581 191.069,313.581 191.513,314.025 191.513,314.18 191.731,314.398 192.038,314.398 192.187,314.249 194.226,314.249 199.39,319.413 199.39,319.418 200.219,320.247 200.36,320.387 200.57,320.598 cw(c200.64,320.528) 200.711,320.598 200.966,320.342 ccw(c201.036,320.413) 201.106,320.342 201.247,320.483 ccw(c201.176,320.553) 201.247,320.623 200.991,320.879 cw(c201.061,320.949) 200.991,321.019 201.132,321.159 cw(c201.202,321.089) 201.272,321.159 201.527,320.904 ccw(c201.598,320.974) 201.668,320.904 201.808,321.044 ccw(c201.738,321.114) 201.808,321.185 201.482,321.51 201.157,321.836 cw(c201.227,321.906) 201.157,321.976 201.297,322.117 cw(c201.367,322.046) 201.438,322.117 201.763,321.791 202.089,321.465 ccw(c202.159,321.535) 202.229,321.465 202.37,321.606 ccw(c202.299,321.676) 202.37,321.746 202.044,322.072 201.718,322.397 cw(c201.789,322.467) 201.718,322.538 201.859,322.678 cw(c201.929,322.608) 201.999,322.678 202.325,322.352 202.65,322.027 ccw(c202.72,322.097) 202.791,322.027 202.931,322.167 ccw(c202.861,322.237) 202.931,322.307 202.605,322.633 202.28,322.959 cw(c202.35,323.029) 202.28,323.099 202.42,323.239 cw(c202.49,323.169) 202.56,323.239 202.886,322.914 203.212,322.588 ccw(c203.282,322.658) 203.352,322.588 203.492,322.729 ccw(c203.422,322.799) 203.492,322.869 203.167,323.195 202.841,323.52 cw(c202.911,323.59) 202.841,323.66 202.982,323.801 cw(c203.052,323.731) 203.122,323.801 203.377,323.545 ccw(c203.448,323.616) 203.518,323.545 203.818,323.846 203.818,335.786 204.853,336.822 v17(204.853,337.264)
DDR4_A11: R50.1 U1.AE28 U8.T2 U9.T2 U10.T2 U11.T2 | length 99.6
  L1 w0.116: U9.T2@171.676,340.06 v2(172.079,340.464) ; U11.T2@183.136,340.06 v2(183.54,340.464) ; v4(185.91,315.052) U1.AE28@186.397,315.539 ; U10.T2@194.597,340.06 v2(195,340.464) ; v2(205.653,340.464) U8.T2@206.057,340.06
  L1 w0.155: v4(176.063,343.555) R50.1@176.063,344.8
  L5 (Sign) w0.092: v2(172.079,340.464) 172.3,340.464 173.009,341.173 180.538,341.173 180.633,341.078 ccw(c180.696,341.141) 180.76,341.078 180.824,341.142 cw(c180.888,341.079) 180.951,341.142 181.141,340.952 cw(c181.078,340.889) 181.141,340.826 181.076,340.761 ccw(c181.14,340.698) 181.076,340.635 181.29,340.421 181.643,340.068 182.344,340.068 182.74,340.464 v2(183.54,340.464) 183.774,340.698 184.845,341.77 188.773,341.77 188.862,341.77 ccw(c188.862,341.859) 188.952,341.859 188.952,341.885 cw(c189.042,341.885) 189.042,341.975 189.31,341.975 cw(c189.31,341.885) 189.4,341.885 189.4,341.859 ccw(c189.489,341.859) 189.489,341.77 189.624,341.77 191.402,341.77 193.103,340.068 193.804,340.068 194.2,340.464 v2(195,340.464) 195,342.104 195.123,342.227 198.501,342.227 198.635,342.227 ccw(c198.635,342.316) 198.725,342.316 198.725,342.417 cw(c198.814,342.417) 198.814,342.507 199.083,342.507 cw(c199.083,342.417) 199.173,342.417 199.173,342.227 199.173,342.054 ccw(c199.262,342.054) 199.262,341.964 199.531,341.964 ccw(c199.531,342.054) 199.62,342.054 199.62,342.227 199.62,342.417 cw(c199.71,342.417) 199.71,342.507 199.979,342.507 cw(c199.979,342.417) 200.068,342.417 200.068,342.227 200.068,342.037 ccw(c200.158,342.037) 200.158,341.947 200.427,341.947 ccw(c200.427,342.037) 200.516,342.037 200.516,342.227 200.516,342.417 cw(c200.606,342.417) 200.606,342.507 200.874,342.507 cw(c200.874,342.417) 200.964,342.417 200.964,342.316 ccw(c201.053,342.316) 201.053,342.227 201.231,342.227 204.239,342.227 204.532,341.933 204.532,340.331 204.796,340.068 205.265,340.068 v2(205.653,340.464)
  L3 (Sign) w0.092: v2@172.162,340.547 v2(172.079,340.464) 173.284,340.464 173.905,341.085 ; v4@185.847,314.99 v4(185.91,315.052) 185.561,315.052 184.049,313.539 182.943,313.539 182.423,314.06 182.423,315.761 182.867,316.206 182.867,318.567 191.745,327.444 191.745,334.372 192.317,334.944 192.317,335.956 193.127,336.766 196.05,336.766 200.99,341.706 201.473,341.706 202.307,341.706 ccw(c202.307,341.796) 202.396,341.796 202.396,341.854 cw(c202.486,341.854) 202.486,341.944 202.754,341.944 cw(c202.754,341.854) 202.844,341.854 202.844,341.796 ccw(c202.933,341.796) 202.933,341.706 203.202,341.706 ccw(c203.202,341.796) 203.292,341.796 203.292,341.854 cw(c203.381,341.854) 203.381,341.944 203.65,341.944 cw(c203.65,341.854) 203.739,341.854 203.739,341.796 ccw(c203.829,341.796) 203.829,341.706 204.187,341.706 204.411,341.706 v2(205.653,340.464)
  L3 (Sign) w0.151: 173.905,341.085 176.054,343.234 176.054,343.546 v4(176.063,343.555)
DDR4_A12: R51.1 U1.AH29 U8.M4 U9.M4 U10.M4 U11.M4 | length 100.2
  L1 w0.116: U9.M4@167.676,336.86 168.072,337.257 v2(168.075,337.257) ; U11.M4@179.136,336.86 179.533,337.257 v2(179.535,337.257) ; U1.AH29@189.397,316.539 v4(189.884,317.027) ; U10.M4@190.597,336.86 190.993,337.257 v2(190.995,337.257) ; U8.M4@202.057,336.86 202.453,337.257 v2(202.456,337.257) v2@202.41,337.303
  L1 w0.155: R51.1@158.737,335.789 v1(159.982,335.789)
  L12 (Sign) w0.092: 165.251,336.237 165.445,336.237 165.539,336.143 165.892,336.143 166.604,336.855 167.465,336.855 167.867,337.257 v2(168.075,337.257) 168.075,337.251 168.611,336.715 173.117,336.715 173.251,336.715 ccw(c173.251,336.805) 173.34,336.805 173.34,336.915 cw(c173.43,336.915) 173.43,337.004 173.699,337.004 cw(c173.699,336.915) 173.788,336.915 173.788,336.805 ccw(c173.878,336.805) 173.878,336.715 174.146,336.715 ccw(c174.146,336.805) 174.236,336.805 174.236,336.915 cw(c174.326,336.915) 174.326,337.004 174.594,337.004 cw(c174.594,336.915) 174.684,336.915 174.684,336.805 ccw(c174.773,336.805) 174.773,336.715 175.743,336.715 177.622,336.715 177.768,336.86 179.109,336.86 179.505,337.257 v2(179.535,337.257) 180.267,337.257 180.961,336.563 184.861,336.563 185.159,336.86 186.83,336.86 187.355,336.86 ccw(c187.355,336.93) 187.425,336.93 187.425,337.109 cw(c187.494,337.109) 187.494,337.178 187.702,337.178 cw(c187.702,337.109) 187.771,337.109 187.771,336.86 187.771,336.612 ccw(c187.84,336.612) 187.84,336.543 188.048,336.543 ccw(c188.048,336.612) 188.117,336.612 188.117,336.791 cw(c188.186,336.791) 188.186,336.86 188.29,336.86 190.391,336.86 190.788,337.257 v2(190.995,337.257) 191.254,337.257 191.915,336.596 192.109,336.596 ccw(c192.109,336.626) 192.139,336.626 cw(c192.228,336.626) 192.228,336.715 192.497,336.715 cw(c192.497,336.626) 192.587,336.626 192.587,336.596 192.587,336.388 ccw(c192.676,336.388) 192.676,336.299 192.945,336.299 ccw(c192.945,336.388) 193.034,336.388 193.034,336.596 193.034,336.617 cw(c193.124,336.617) 193.124,336.707 193.393,336.707 cw(c193.393,336.617) 193.482,336.617 193.482,336.596 193.482,336.388 ccw(c193.572,336.388) 193.572,336.299 193.841,336.299 ccw(c193.841,336.388) 193.93,336.388 193.93,336.506 cw(c194.02,336.506) 194.02,336.596 194.288,336.596 cw(c194.288,336.506) 194.378,336.506 194.378,336.388 ccw(c194.467,336.388) 194.467,336.299 194.736,336.299 ccw(c194.736,336.388) 194.826,336.388 194.826,336.506 cw(c194.915,336.506) 194.915,336.596 195.123,336.596 201.075,336.596 201.394,336.915 201.768,336.915 202.155,337.303 202.41,337.303 v2(202.456,337.257)
  L12 (Sign) w0.151: v1(159.982,335.789) 163,335.789 163.448,336.237 165.251,336.237
  L3 (Sign) w0.092: v4(189.884,317.027) 190.205,316.706 191.727,316.706 199.386,324.364 199.765,324.364 200.51,325.11 200.51,328.276 200.406,328.38 200.406,330.432 200.406,331.001 cw(c200.505,331.001) 200.505,331.1 200.776,331.1 ccw(c200.776,331.199) 200.875,331.199 200.875,331.398 ccw(c200.776,331.398) 200.776,331.497 200.406,331.497 199.28,331.497 cw(c199.28,331.596) 199.181,331.596 199.181,331.795 cw(c199.28,331.795) 199.28,331.894 200.406,331.894 200.851,331.894 ccw(c200.851,331.993) 200.95,331.993 200.95,332.192 ccw(c200.851,332.192) 200.851,332.291 200.406,332.291 199.23,332.291 cw(c199.23,332.39) 199.13,332.39 199.13,332.589 cw(c199.23,332.589) 199.23,332.688 200.406,332.688 200.773,332.688 ccw(c200.773,332.787) 200.872,332.787 200.872,332.986 ccw(c200.773,332.986) 200.773,333.085 200.406,333.085 198.963,333.085 cw(c198.963,333.184) 198.864,333.184 198.864,333.383 cw(c198.963,333.383) 198.963,333.482 200.406,333.482 200.437,333.482 ccw(c200.437,333.581) 200.536,333.581 200.536,333.78 ccw(c200.437,333.78) 200.437,333.879 200.406,333.879 199.227,333.879 cw(c199.227,333.978) 199.128,333.978 199.128,334.177 cw(c199.227,334.177) 199.227,334.276 200.406,334.276 200.459,334.276 ccw(c200.459,334.375) 200.558,334.375 200.558,334.574 ccw(c200.459,334.574) 200.459,334.673 200.406,334.673 199.434,334.673 cw(c199.434,334.772) 199.334,334.772 199.334,334.971 cw(c199.434,334.971) 199.434,335.07 200.406,335.07 200.927,335.07 ccw(c200.927,335.169) 201.026,335.169 201.026,335.368 ccw(c200.927,335.368) 200.927,335.467 200.406,335.467 199.685,335.467 cw(c199.685,335.566) 199.586,335.566 199.586,335.765 cw(c199.685,335.765) 199.685,335.864 200.406,335.864 201.051,335.864 ccw(c201.051,335.963) 201.15,335.963 201.15,336.162 ccw(c201.051,336.162) 201.051,336.261 200.505,336.261 cw(c200.505,336.36) 200.406,336.36 200.406,336.459 200.807,336.86 202.059,336.86 v2(202.456,337.257)
DDR4_A13: R53.1 U1.AH28 U8.T5 U9.T5 U10.T5 U11.T5 | length 100.7
  L1 w0.116: U9.T5@166.876,340.06 167.274,340.459 v29(167.274,340.589) ; U11.T5@178.336,340.06 178.733,340.457 v2(178.735,340.457) ; v4(189.04,315.049) 189.04,315.182 U1.AH28@189.397,315.539 ; U10.T5@189.797,340.06 190.195,340.459 v2(190.195,340.589) ; U8.T5@201.257,340.06 201.653,340.457 v2(201.656,340.457)
  L1 w0.155: R53.1@158.737,344.5 v1(159.982,344.5)
  L12 (Sign) w0.092: 165.251,340.851 166.416,340.851 166.678,340.589 v29(167.274,340.589) 167.571,340.589 168.155,341.173 176.774,341.173 176.81,341.173 ccw(c176.81,341.262) 176.9,341.262 176.9,341.299 cw(c176.989,341.299) 176.989,341.389 177.258,341.389 cw(c177.258,341.299) 177.347,341.299 177.347,341.173 177.347,341.046 ccw(c177.437,341.046) 177.437,340.957 177.706,340.957 ccw(c177.706,341.046) 177.795,341.046 177.795,341.083 cw(c177.885,341.083) 177.885,341.173 178.019,341.173 v2(178.735,340.457) 180.475,340.457 181.559,341.541 184.15,341.541 184.793,341.541 ccw(c184.793,341.61) 184.862,341.61 184.862,341.755 cw(c184.931,341.755) 184.931,341.824 185.139,341.824 cw(c185.139,341.755) 185.208,341.755 185.208,341.541 185.208,341.327 ccw(c185.277,341.327) 185.277,341.258 185.485,341.258 ccw(c185.485,341.327) 185.554,341.327 185.554,341.472 cw(c185.624,341.472) 185.624,341.541 185.727,341.541 189.243,341.541 v2(190.195,340.589) 190.492,340.589 191.076,341.173 191.211,341.173 ccw(c191.211,341.262) 191.3,341.262 191.3,341.434 cw(c191.39,341.434) 191.39,341.523 191.658,341.523 cw(c191.658,341.434) 191.748,341.434 191.748,341.262 ccw(c191.838,341.262) 191.838,341.173 192.106,341.173 ccw(c192.106,341.262) 192.196,341.262 192.196,341.434 cw(c192.285,341.434) 192.285,341.523 192.554,341.523 cw(c192.554,341.434) 192.644,341.434 192.644,341.262 ccw(c192.733,341.262) 192.733,341.173 193.002,341.173 ccw(c193.002,341.262) 193.091,341.262 193.091,341.434 cw(c193.181,341.434) 193.181,341.523 193.45,341.523 cw(c193.45,341.434) 193.539,341.434 193.539,341.262 ccw(c193.629,341.262) 193.629,341.173 194.164,341.173 199.436,341.173 200.152,340.457 v2(201.656,340.457)
  L12 (Sign) w0.151: v1(159.982,344.5) 160.782,344.5 164.431,340.851 165.251,340.851
  L3 (Sign) w0.092: v4(189.04,315.049) 189.04,315.182 189.546,315.688 189.546,316.37 189.04,316.876 189.04,317.636 189.793,318.389 190.017,318.389 190.158,318.529 cw(c190.199,318.571) 190.158,318.612 190.355,318.81 cw(c190.397,318.769) 190.438,318.81 190.855,318.394 ccw(c190.925,318.464) 190.995,318.394 191.136,318.534 ccw(c191.065,318.604) 191.136,318.674 190.719,319.091 cw(c190.761,319.132) 190.719,319.174 190.917,319.372 cw(c190.958,319.33) 191,319.372 192.149,318.222 ccw(c192.22,318.292) 192.29,318.222 192.43,318.362 ccw(c192.36,318.433) 192.43,318.503 191.281,319.652 cw(c191.322,319.694) 191.281,319.735 191.478,319.933 cw(c191.52,319.891) 191.561,319.933 191.795,319.699 ccw(c191.866,319.769) 191.936,319.699 192.076,319.839 ccw(c192.006,319.909) 192.076,319.98 191.842,320.214 cw(c191.884,320.255) 191.842,320.297 192.04,320.494 cw(c192.081,320.453) 192.123,320.494 192.357,320.26 ccw(c192.427,320.33) 192.497,320.26 192.638,320.401 ccw(c192.567,320.471) 192.638,320.541 192.404,320.775 cw(c192.445,320.817) 192.404,320.858 192.601,321.056 cw(c192.643,321.014) 192.684,321.056 192.918,320.822 ccw(c192.989,320.892) 193.059,320.822 193.199,320.962 ccw(c193.129,321.032) 193.199,321.102 192.965,321.337 cw(c193.007,321.378) 192.965,321.42 193.163,321.617 cw(c193.204,321.576) 193.246,321.617 193.48,321.383 ccw(c193.55,321.453) 193.62,321.383 193.761,321.524 ccw(c193.69,321.594) 193.761,321.664 193.526,321.898 cw(c193.568,321.94) 193.526,321.981 193.724,322.179 cw(c193.766,322.137) 193.807,322.179 194.041,321.945 ccw(c194.111,322.015) 194.182,321.945 194.322,322.085 ccw(c194.252,322.155) 194.322,322.225 194.088,322.459 cw(c194.129,322.501) 194.088,322.543 194.285,322.74 cw(c194.327,322.699) 194.369,322.74 194.603,322.506 ccw(c194.673,322.576) 194.743,322.506 194.883,322.646 ccw(c194.813,322.717) 194.883,322.787 194.649,323.021 cw(c194.691,323.062) 194.649,323.104 194.847,323.302 cw(c194.888,323.26) 194.93,323.302 195.164,323.068 ccw(c195.234,323.138) 195.304,323.068 195.445,323.208 ccw(c195.375,323.278) 195.445,323.348 195.211,323.582 cw(c195.252,323.624) 195.211,323.665 195.408,323.863 cw(c195.45,323.821) 195.491,323.863 195.726,323.629 ccw(c195.796,323.699) 195.866,323.629 196.006,323.769 ccw(c195.936,323.84) 196.006,323.91 195.772,324.144 cw(c195.814,324.185) 195.772,324.227 195.97,324.424 cw(c196.011,324.383) 196.053,324.425 197.051,323.427 ccw(c197.121,323.497) 197.191,323.427 197.331,323.567 ccw(c197.261,323.637) 197.331,323.708 196.334,324.705 196.211,324.828 cw(c196.281,324.898) 196.211,324.968 196.351,325.109 cw(c196.421,325.039) 196.492,325.109 196.544,325.056 ccw(c196.614,325.126) 196.685,325.056 196.759,325.131 197.28,325.652 197.28,334.491 201.168,338.379 201.975,338.379 202.135,338.538 202.135,338.99 202.323,339.178 ; v2(201.656,340.457) 202.379,340.457 202.616,340.22 202.616,339.47 202.323,339.178
DDR4_ACT_N: R40.1 U1.AD26 U8.L3 U9.L3 U10.L3 U11.L3 | length 104
  L1 w0.116: v2(170.472,335.657) U9.L3@170.876,336.06 ; v2(181.933,335.657) U11.L3@182.336,336.06 ; U1.AD26@185.397,313.539 185.89,314.033 v4(186.017,314.033) ; v2(193.393,335.657) U10.L3@193.797,336.06 ; U8.L3@205.257,336.06 v17(205.661,335.657)
  L1 w0.155: v1(166.395,343.555) R40.1@166.395,344.799
  L5 (Sign) w0.092: 168.694,341.085 168.694,340.953 168.985,340.662 168.985,337.144 v2(170.472,335.657) 170.824,336.008 173.503,336.008 174.251,335.26 175.057,335.26 175.191,335.26 ccw(c175.191,335.35) 175.281,335.35 175.281,335.407 cw(c175.37,335.407) 175.37,335.497 175.639,335.497 cw(c175.639,335.407) 175.728,335.407 175.728,335.26 175.728,335.13 ccw(c175.818,335.13) 175.818,335.04 176.087,335.04 ccw(c176.087,335.13) 176.176,335.13 176.176,335.171 cw(c176.266,335.171) 176.266,335.26 176.657,335.26 180.028,335.26 180.425,335.657 v2(181.933,335.657) 182.336,336.06 184.472,336.06 185.265,335.267 185.356,335.267 185.46,335.267 ccw(c185.46,335.337) 185.53,335.337 185.53,335.406 cw(c185.599,335.406) 185.599,335.475 185.807,335.475 cw(c185.807,335.406) 185.876,335.406 185.876,335.267 185.876,335.129 ccw(c185.945,335.129) 185.945,335.059 186.153,335.059 ccw(c186.153,335.129) 186.222,335.129 186.222,335.267 186.222,335.406 cw(c186.291,335.406) 186.291,335.475 186.499,335.475 cw(c186.499,335.406) 186.568,335.406 186.568,335.337 ccw(c186.637,335.337) 186.637,335.267 186.715,335.267 191.656,335.267 192.045,335.657 v2(193.393,335.657) 193.816,336.08 195.631,336.08 195.885,335.826 197.417,335.826 198.076,335.826 cw(c198.076,335.737) 198.165,335.737 198.165,335.628 ccw(c198.255,335.628) 198.255,335.539 198.523,335.539 ccw(c198.523,335.628) 198.613,335.628 198.613,335.826 198.613,335.844 cw(c198.702,335.844) 198.702,335.933 198.971,335.933 cw(c198.971,335.844) 199.061,335.844 199.061,335.826 199.061,335.628 ccw(c199.15,335.628) 199.15,335.539 199.419,335.539 ccw(c199.419,335.628) 199.509,335.628 199.509,335.826 199.509,335.844 cw(c199.598,335.844) 199.598,335.933 199.867,335.933 cw(c199.867,335.844) 199.956,335.844 199.956,335.826 199.956,335.628 ccw(c200.046,335.628) 200.046,335.539 200.315,335.539 ccw(c200.315,335.628) 200.404,335.628 200.404,335.826 200.404,336.024 cw(c200.494,336.024) 200.494,336.113 200.762,336.113 cw(c200.762,336.024) 200.852,336.024 200.852,335.916 ccw(c200.941,335.916) 200.941,335.826 201.3,335.826 201.524,335.826 202.667,335.826 202.971,336.131 204.711,336.131 205.41,336.829 205.765,336.829 205.974,336.62 205.974,335.978 205.661,335.664 v17(205.661,335.657)
  L5 (Sign) w0.151: v1(166.395,343.555) 167.071,342.879 167.648,342.879 168.694,341.833 168.694,341.085
  L3 (Sign) w0.092: v4(186.017,314.033) 186.498,314.514 187.085,314.514 187.528,314.071 187.528,313.862 188.205,313.185 188.205,313.181 188.227,313.16 188.227,311.353 188.962,310.618 192.216,310.618 204.202,322.604 204.202,322.802 204.202,323.1 cw(c204.301,323.1) 204.301,323.199 204.674,323.199 ccw(c204.674,323.299) 204.774,323.299 204.774,323.497 ccw(c204.674,323.497) 204.674,323.596 204.301,323.596 cw(c204.301,323.696) 204.202,323.696 204.202,323.894 cw(c204.301,323.894) 204.301,323.993 204.674,323.993 ccw(c204.674,324.093) 204.774,324.093 204.774,324.291 ccw(c204.674,324.291) 204.674,324.39 204.301,324.39 cw(c204.301,324.49) 204.202,324.49 204.202,324.688 cw(c204.301,324.688) 204.301,324.787 204.6,324.787 ccw(c204.6,324.887) 204.699,324.887 204.699,325.085 ccw(c204.6,325.085) 204.6,325.184 204.301,325.184 cw(c204.301,325.284) 204.202,325.284 204.202,325.482 cw(c204.301,325.482) 204.301,325.581 204.6,325.581 ccw(c204.6,325.681) 204.699,325.681 204.699,325.879 ccw(c204.6,325.879) 204.6,325.978 204.301,325.978 cw(c204.301,326.078) 204.202,326.078 204.202,326.276 cw(c204.301,326.276) 204.301,326.375 204.674,326.375 ; 204.674,326.375 ccw(c204.674,326.475) 204.774,326.475 204.774,326.673 ccw(c204.674,326.673) 204.674,326.772 204.301,326.772 cw(c204.301,326.872) 204.202,326.872 204.202,327.07 cw(c204.301,327.07) 204.301,327.169 204.386,327.169 ccw(c204.386,327.269) 204.486,327.269 204.486,327.467 ccw(c204.386,327.467) 204.386,327.566 204.301,327.566 cw(c204.301,327.666) 204.202,327.666 204.202,327.864 cw(c204.301,327.864) 204.301,327.963 204.579,327.963 ccw(c204.579,328.063) 204.678,328.063 204.678,328.261 ccw(c204.579,328.261) 204.579,328.36 204.301,328.36 cw(c204.301,328.46) 204.202,328.46 204.202,328.658 cw(c204.301,328.658) 204.301,328.757 204.392,328.757 ccw(c204.392,328.857) 204.491,328.857 204.491,329.055 ccw(c204.392,329.055) 204.392,329.154 204.301,329.154 cw(c204.301,329.254) 204.202,329.254 204.202,329.452 cw(c204.301,329.452) 204.301,329.551 204.56,329.551 ccw(c204.56,329.651) 204.659,329.651 204.659,329.849 ccw(c204.56,329.849) 204.56,329.948 204.301,329.948 cw(c204.301,330.048) 204.202,330.048 204.202,332.168 204.202,334.623 204.349,334.771 204.349,335.21 204.584,335.445 205.207,335.445 205.418,335.657 v17(205.661,335.657)
DDR4_ALERT_N: R58.1 U1.AB24 U8.P6 U9.P6 U10.P6 U11.P6 | length 42.4
  L1 w0.112: 165.251,338.856 v4(165.665,338.856) ; U9.P6@166.061,338.46 U9.P6@166.076,338.46
  L1 w0.116: v4(165.665,338.856) U9.P6@166.061,338.46 ; v4@177.125,338.856 U11.P6@177.529,338.453 ; v4(188.586,338.856) U10.P6@188.989,338.453 ; v4(198.298,339.928) 199.766,338.46 U8.P6@200.457,338.46
  L1 w0.155: R58.1@163.36,339.242 164.63,339.242 165.016,338.856 165.251,338.856
  L3 (Sign) w0.092: v4(165.665,338.856) 166.061,338.46 168.322,338.46 169.953,336.829 174.409,336.829 176.04,338.46 176.721,338.46
  L3 (Sign) w0.116: 176.721,338.46 v4(177.117,338.857) 177.514,338.46 188.189,338.46 v4(188.586,338.856) 188.982,338.46 196.259,338.46 197.727,339.928 v4(198.298,339.928)
DDR4_BA0: R32.1 U1.AD27 U8.N2 U9.N2 U10.N2 U11.N2 | length 102.4
  L1 w0.116: U9.N2@171.676,337.66 v2(172.079,338.064) ; U11.N2@183.136,337.66 v2(183.54,338.064) ; v4(184.912,313.919) 184.912,314.054 U1.AD27@185.397,314.539 ; U10.N2@194.597,337.66 v2(195,338.064) ; U8.N2@206.057,337.66 v17(206.439,338.042)
  L1 w0.155: v1(170.02,343.555) R32.1@170.02,344.799
  L5 (Sign) w0.092: 169.765,341.085 169.569,340.89 169.569,338.367 170.243,337.693 170.626,337.693 170.996,337.693 171.367,338.064 v2(172.079,338.064) 173.24,338.064 173.687,337.617 173.876,337.617 174.01,337.617 ccw(c174.01,337.706) 174.1,337.706 174.1,337.818 cw(c174.189,337.818) 174.189,337.907 174.458,337.907 cw(c174.458,337.818) 174.547,337.818 174.547,337.617 174.547,337.416 ccw(c174.637,337.416) 174.637,337.326 174.906,337.326 ccw(c174.906,337.416) 174.995,337.416 174.995,337.527 cw(c175.085,337.527) 175.085,337.617 175.927,337.617 182.674,337.617 183.122,338.064 v2(183.54,338.064) 183.822,338.064 183.909,337.977 183.909,337.857 184.098,337.668 186.347,337.668 186.968,337.668 ccw(c186.968,337.737) 187.037,337.737 187.037,337.823 cw(c187.106,337.823) 187.106,337.892 187.314,337.892 cw(c187.314,337.823) 187.383,337.823 187.383,337.668 187.383,337.512 ccw(c187.453,337.512) 187.453,337.443 187.66,337.443 ccw(c187.66,337.512) 187.73,337.512 187.73,337.668 187.73,337.823 cw(c187.799,337.823) 187.799,337.892 188.006,337.892 cw(c188.006,337.823) 188.076,337.823 188.076,337.668 188.076,337.633 ccw(c188.145,337.633) 188.145,337.563 188.353,337.563 ccw(c188.353,337.633) 188.422,337.633 cw(c188.457,337.633) 188.457,337.668 188.595,337.668 194.056,337.668 194.452,338.064 v2(195,338.064) 195.313,338.064 195.952,338.064 cw(c195.952,337.974) 196.041,337.974 196.041,337.85 ccw(c196.131,337.85) 196.131,337.761 196.399,337.761 ccw(c196.399,337.85) 196.489,337.85 196.489,337.974 cw(c196.578,337.974) 196.578,338.064 196.847,338.064 cw(c196.847,337.974) 196.937,337.974 196.937,337.85 ccw(c197.026,337.85) 197.026,337.761 197.295,337.761 ccw(c197.295,337.85) 197.384,337.85 197.384,338.064 197.384,338.223 cw(c197.474,338.223) 197.474,338.312 197.743,338.312 cw(c197.743,338.223) 197.832,338.223 197.832,338.064 197.832,337.85 ccw(c197.922,337.85) 197.922,337.761 198.191,337.761 ccw(c198.191,337.85) 198.28,337.85 198.28,338.064 198.28,338.223 cw(c198.37,338.223) 198.37,338.312 198.638,338.312 cw(c198.638,338.223) 198.728,338.223 198.728,338.064 198.728,337.85 ccw(c198.817,337.85) 198.817,337.761 199.086,337.761 ccw(c199.086,337.85) 199.176,337.85 199.176,338.064 199.176,338.223 cw(c199.265,338.223) 199.265,338.312 199.534,338.312 cw(c199.534,338.223) 199.623,338.223 199.623,338.064 199.623,337.85 ccw(c199.713,337.85) 199.713,337.761 199.982,337.761 ccw(c199.982,337.85) 200.071,337.85 200.071,338.064 200.071,338.223 cw(c200.161,338.223) 200.161,338.312 200.43,338.312 cw(c200.43,338.223) 200.519,338.223 200.519,338.064 200.519,337.85 ccw(c200.609,337.85) 200.609,337.761 200.877,337.761 ccw(c200.877,337.85) 200.967,337.85 200.967,337.974 cw(c201.056,337.974) 201.056,338.064 201.191,338.064 201.587,337.668 201.752,337.668 ccw(c201.752,337.727) 201.811,337.727 cw(c201.9,337.727) 201.9,337.817 202.169,337.817 cw(c202.169,337.727) 202.258,337.727 ccw(c202.318,337.727) 202.318,337.668 202.654,337.668 205.646,337.668 206.02,338.042 v17(206.439,338.042)
  L5 (Sign) w0.151: 169.765,341.085 170.02,341.341 v1(170.02,343.555)
  L3 (Sign) w0.092: v4(184.912,313.919) 184.912,313.655 185.312,313.255 185.312,312.828 185.749,312.391 185.756,312.398 186.088,312.398 188.679,309.807 192.491,309.807 192.53,309.846 192.538,309.846 208.407,325.715 208.407,334.442 208.407,335.21 ccw(c208.32,335.21) 208.32,335.297 208.095,335.297 cw(c208.095,335.383) 208.008,335.383 208.008,335.557 cw(c208.095,335.557) 208.095,335.643 208.407,335.643 ccw(c208.407,335.708) 208.472,335.708 208.472,335.925 ccw(c208.407,335.925) 208.407,335.989 208.095,335.989 cw(c208.095,336.076) 208.008,336.076 208.008,336.249 cw(c208.095,336.249) 208.095,336.336 208.32,336.336 ccw(c208.32,336.422) 208.407,336.422 208.407,336.682 208.407,336.855 207.582,337.68 206.8,337.68 v17(206.439,338.042)
DDR4_BA1: R34.1 U1.AC26 U8.N5 U9.N5 U10.N5 U11.N5 | length 99
  L1 w0.116: U9.N5@166.876,337.66 167.272,338.057 v29(167.275,338.057) ; U11.N5@178.336,337.66 178.733,338.057 v2(178.735,338.057) ; v4(183.91,314.027) U1.AC26@184.397,313.539 ; U10.N5@189.797,337.66 190.193,338.057 v2(190.195,338.057) ; U8.N5@201.257,337.66 201.653,338.057 v2(201.656,338.057)
  L1 w0.155: R34.1@158.737,339.055 v1(159.982,339.056)
  L12 (Sign) w0.092: 165.251,338.057 166.745,338.057 v29(167.275,338.057) 167.511,338.057 167.915,338.46 168.465,338.46 168.6,338.46 ccw(c168.6,338.55) 168.689,338.55 168.689,338.564 cw(c168.779,338.564) 168.779,338.654 169.048,338.654 cw(c169.048,338.564) 169.137,338.564 169.137,338.46 169.137,338.144 ccw(c169.227,338.144) 169.227,338.054 169.495,338.054 ccw(c169.495,338.144) 169.585,338.144 169.585,338.371 cw(c169.675,338.371) 169.675,338.46 170.345,338.46 172.412,338.46 172.816,338.057 v2(178.735,338.057) 178.981,338.303 179.327,338.303 179.402,338.378 179.413,338.378 179.515,338.48 181.75,338.48 182.479,338.48 ccw(c182.479,338.55) 182.548,338.55 182.548,338.785 cw(c182.617,338.785) 182.617,338.854 182.825,338.854 cw(c182.825,338.785) 182.894,338.785 182.894,338.48 182.894,338.176 ccw(c182.963,338.176) 182.963,338.107 183.171,338.107 ccw(c183.171,338.176) 183.24,338.176 183.24,338.411 cw(c183.31,338.411) 183.31,338.48 183.413,338.48 189.243,338.48 189.666,338.057 v2(190.195,338.057) 190.458,338.057 190.805,338.404 191.783,338.404 193.558,338.404 ccw(c193.558,338.494) 193.648,338.494 193.648,338.57 cw(c193.737,338.57) 193.737,338.659 194.006,338.659 cw(c194.006,338.57) 194.096,338.57 194.096,338.404 194.096,338.145 ccw(c194.185,338.145) 194.185,338.055 194.454,338.055 ccw(c194.454,338.145) 194.543,338.145 194.543,338.315 cw(c194.633,338.315) 194.633,338.404 194.767,338.404 195.389,338.404 195.986,337.807 198.869,337.807 199.09,337.807 ccw(c199.09,337.87) 199.153,337.87 cw(c199.242,337.87) 199.242,337.96 199.511,337.96 cw(c199.511,337.87) 199.601,337.87 199.601,337.807 199.601,337.744 ccw(c199.69,337.744) 199.69,337.655 199.959,337.655 ccw(c199.959,337.744) 200.049,337.744 200.049,337.807 200.049,337.87 cw(c200.138,337.87) 200.138,337.96 200.407,337.96 cw(c200.407,337.87) 200.496,337.87 200.496,337.807 200.496,337.744 ccw(c200.586,337.744) 200.586,337.655 200.855,337.655 ccw(c200.855,337.744) 200.944,337.744 cw(c201.007,337.744) 201.007,337.807 201.168,337.807 201.418,338.057 v2(201.656,338.057)
  L12 (Sign) w0.151: v1(159.982,339.056) 160.336,338.702 161.577,338.702 162.221,338.057 165.251,338.057
  L3 (Sign) w0.092: v4(183.91,314.027) 183.91,314.68 184.362,315.132 184.362,316.073 183.563,316.872 183.563,317.185 183.751,317.373 183.934,317.373 184.164,317.603 184.62,317.603 184.723,317.707 185.751,317.707 ; 185.751,317.706 186.114,317.706 186.535,318.126 188.044,319.659 188.084,319.7 188.536,320.159 188.606,320.23 ccw(c188.535,320.299) 188.605,320.37 188.073,320.894 cw(c188.143,320.964) 188.072,321.034 188.211,321.175 cw(c188.282,321.106) 188.352,321.176 188.954,320.583 189.115,320.425 ccw(c189.185,320.496) 189.255,320.426 189.395,320.567 ccw(c189.324,320.637) 189.393,320.708 189.232,320.866 188.634,321.455 cw(c188.704,321.526) 188.633,321.595 188.773,321.737 cw(c188.843,321.667) 188.913,321.738 189.44,321.219 ccw(c189.51,321.29) 189.581,321.22 189.72,321.361 ccw(c189.649,321.431) 189.719,321.502 189.196,322.017 cw(c189.266,322.087) 189.195,322.157 189.334,322.298 cw(c189.405,322.229) 189.474,322.299 189.997,321.785 ccw(c190.067,321.855) 190.138,321.786 190.346,321.998 190.907,322.567 192.661,324.322 192.661,333.733 193.022,334.093 193.022,334.211 193.239,334.428 193.264,334.428 193.264,334.453 193.633,334.453 194.441,335.26 195.71,335.26 201.227,340.778 202.345,340.778 202.857,340.266 202.857,338.633 202.667,338.442 202.383,338.442 201.998,338.057 v2(201.656,338.057)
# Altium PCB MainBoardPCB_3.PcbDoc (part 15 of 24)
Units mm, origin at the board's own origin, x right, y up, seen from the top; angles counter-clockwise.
Board outline 258.95 x 308.86 mm, 16 copper layers (L1, L2 (GND), L3 (Sign), L4 (GND), L5 (Sign), L6 (PWR/GND), L7(PWR/GND), L8 (Plane_GND), L9 (PWR/GND), L10 (PWR/GND), L11 (PWR/GND), L12 (Sign), L13 (GND), L14 (Sign), L15 (GND), L16), stack 2.502 mm thick; 2402 components, 1749 nets, 8407 pads, 3409 vias.
Unrouted connection lines stored in the file: 4352.

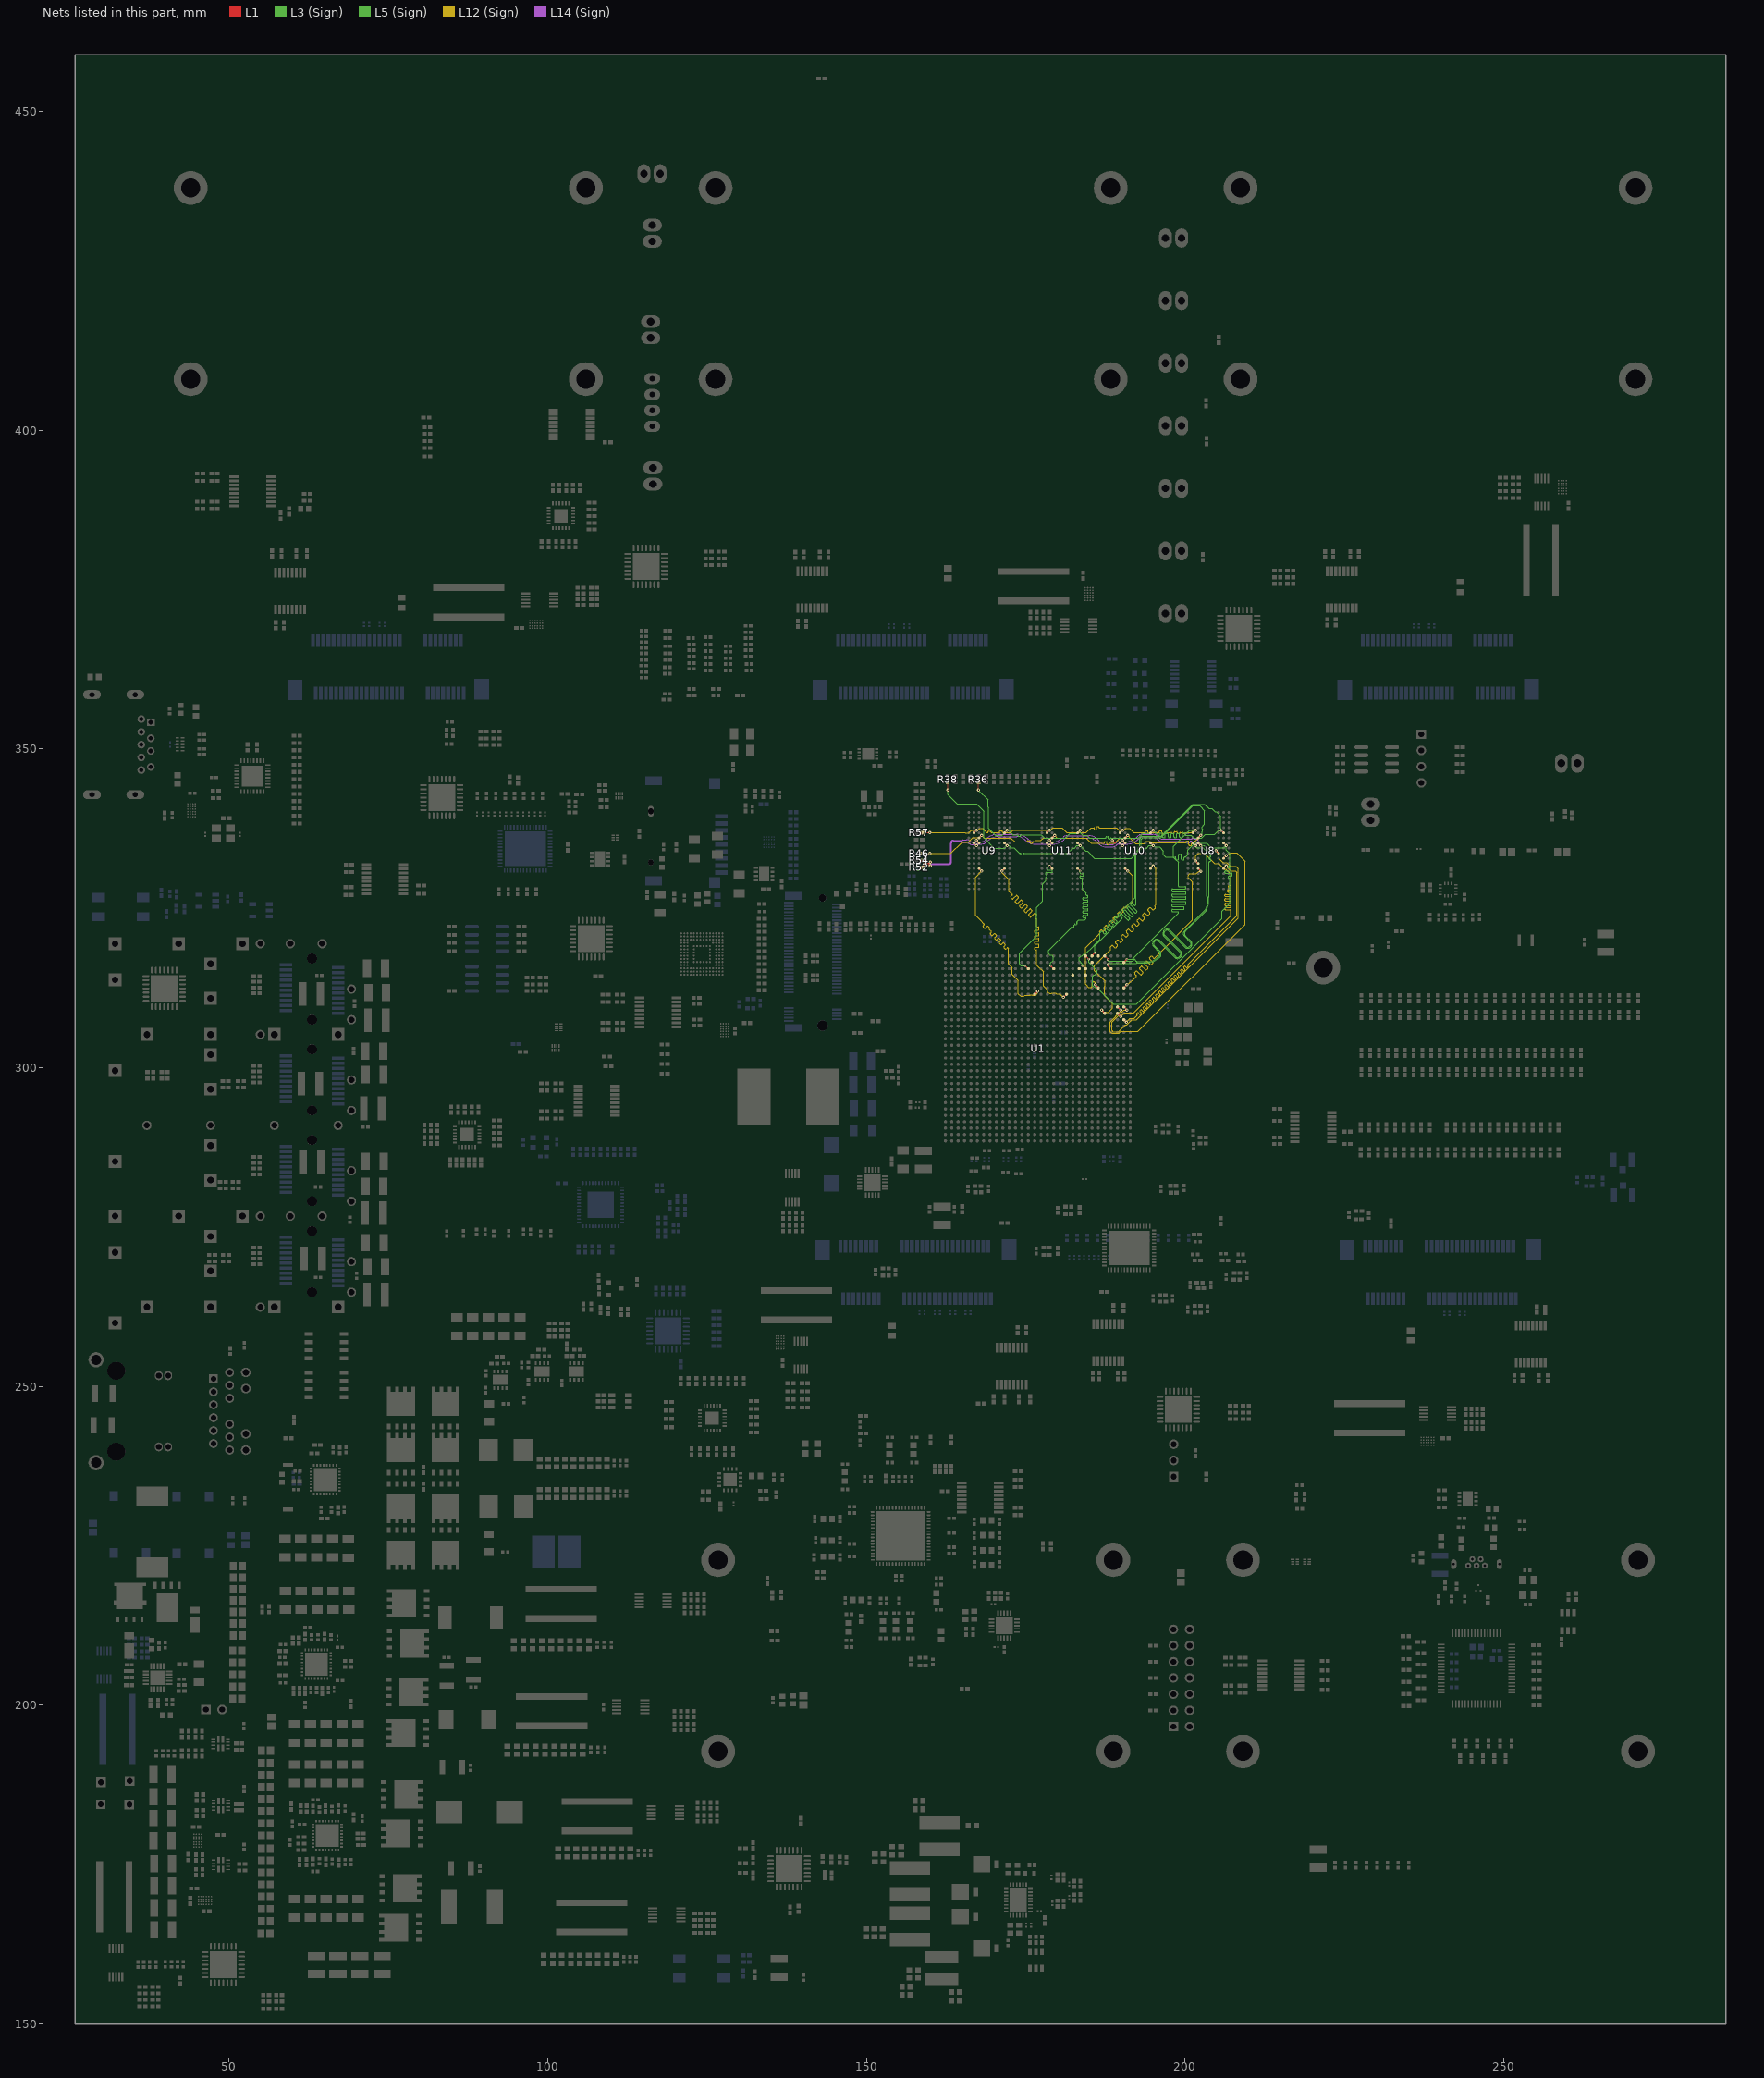
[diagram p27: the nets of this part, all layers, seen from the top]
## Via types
v1: diameter 0.5, hole 0.2, L1 to L16, tented both sides, 1267 vias
v2: diameter 0.5/0.35/0.35/0.35/0.35/0.35/0.35/0.35/0.35/0.35/0.35/0.35/0.35/0.35/0.35/0.5 (per signal layer), hole 0.15, L1 to L16, tented both sides, 463 vias
v3: diameter 0.5, hole 0.2, L1 to L16, 446 vias
v4: diameter 0.35/0/0.35 (per signal layer), hole 0.127, L1 to L3 (Sign), tented both sides, 347 vias
v5: diameter 0.5/0.35/0.35/0.35/0.35/0.35/0.35/0.35/0.35/0.35/0.35/0.35/0.35/0.35/0.35/0.5 (per signal layer), hole 0.2, L1 to L16, tented both sides, 244 vias
v6: diameter 0.8, hole 0.4, L1 to L16, tented both sides, 168 vias
v7: diameter 2.54, hole 1.02, L1 to L16, 113 vias
v8: diameter 1.4, hole 0.5, L1 to L16, tented both sides, 80 vias
v9: diameter 0.5/0/0.5 (per signal layer), hole 0.2, L14 (Sign) to L16, tented both sides, 62 vias
v10: diameter 0.35/0/0.35 (per signal layer), hole 0.127, L1 to L3 (Sign), 38 vias
v11: diameter 0.35, hole 0.127, L1 to L2 (GND), tented both sides, 36 vias
v12: diameter 0.4, hole 0.2, L1 to L16, 16 vias
v13: diameter 0.25, hole 0.2, L1 to L16, 16 vias
v14: diameter 0.35, hole 0.127, L1 to L16, tented both sides, 16 vias
v15: diameter 0.3, hole 0.2, L1 to L16, 15 vias
v16: diameter 0.45, hole 0.15, L1 to L16, 12 vias
v17: diameter 0.5/0.35/0.35/0.35/0.35/0.35/0.35/0.35/0.35/0.35/0.35/0.35/0.35/0.35/0.35/0.45 (per signal layer), hole 0.15, L1 to L16, tented both sides, 10 vias
v18: diameter 0.2/0/0.2 (per signal layer), hole 0.1, L1 to L3 (Sign), tented both sides, 9 vias
v19: diameter 0.4, hole 0.1, L1 to L16, 7 vias
v20: diameter 0.5, hole 0.2, L3 (Sign) to L6 (PWR/GND), tented both sides, 6 vias
v21: diameter 1.15, hole 1.15, L1 to L16, 5 vias
v22: diameter 1.65, hole 1.65, L1 to L16, 5 vias
v23: diameter 0.35/0/0.35 (per signal layer), hole 0.127, L14 (Sign) to L16, tented both sides, 5 vias
v24: diameter 0.5, hole 0.2, L11 (PWR/GND) to L14 (Sign), tented both sides, 4 vias
v25: diameter 0.2, hole 0.1, L1 to L16, 4 vias
v26: diameter 0.35, hole 0.127, L1 to L2 (GND), 2 vias
v27: diameter 0.4, hole 0.15, L1 to L16, 2 vias
v28: diameter 0.4, hole 0.2, L1 to L16, tented both sides, 2 vias
v29: diameter 0.5/0.35/0.35/0.35/0.35/0.35/0.35/0.35/0.35/0.35/0.35/0.35/0.35/0.35/0.35/0.5 (per signal layer), hole 0.15, L1 to L16, 2 vias
v30: diameter 0.35, hole 0.127, L3 (Sign) to L6 (PWR/GND), tented both sides, 2 vias
v31: diameter 0.5/0.35/0.35/0.35/0.35/0.35/0.35/0.35/0.35/0.35/0.35/0.35/0.35/0.35/0.35/0.5 (per signal layer), hole 0.2, L1 to L16, 1 vias
v32: diameter 0.35/0.35/0.35 (per signal layer), hole 0.127, L1 to L3 (Sign), tented both sides, 1 vias
v33: diameter 0.45/0/0.45 (per signal layer), hole 0.15, L1 to L3 (Sign), tented both sides, 1 vias
v34: diameter 0.45/0/0.45 (per signal layer), hole 0.2, L14 (Sign) to L16, tented both sides, 1 vias
v35: diameter 0.35, hole 0.127, L2 (GND) to L3 (Sign), 1 vias

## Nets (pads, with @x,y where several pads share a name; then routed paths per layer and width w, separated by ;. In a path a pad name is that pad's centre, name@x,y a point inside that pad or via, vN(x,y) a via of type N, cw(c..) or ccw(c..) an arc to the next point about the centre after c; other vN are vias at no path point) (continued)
DDR4_BG0: R36.1 U1.AC28 U8.M2 U9.M2 U10.M2 U11.M2 | length 104.5
  L1 w0.116: U9.M2@171.676,336.86 v2(172.079,337.264) ; U11.M2@183.136,336.86 v2(183.54,337.264) ; v4(183.909,316.027) U1.AC28@184.397,315.539 ; U10.M2@194.597,336.86 v2(195,337.264) ; v17(205.684,337.233) U8.M2@206.057,336.86 U8.M2@206.088,336.829
  L1 w0.155: v1(167.603,343.555) R36.1@167.603,344.8
  L5 (Sign) w0.092: 169.102,341.085 169.102,340.891 169.177,340.816 169.177,337.543 170.231,336.488 171.303,336.488 v2(172.079,337.264) 172.324,337.264 173.043,336.545 173.609,336.545 173.708,336.545 cw(c173.708,336.445) 173.807,336.445 173.807,336.406 ccw(c173.907,336.406) 173.907,336.307 174.105,336.307 ccw(c174.105,336.406) 174.204,336.406 174.204,336.445 cw(c174.304,336.445) 174.304,336.545 175.12,336.545 177.437,336.545 177.921,336.06 181.217,336.06 181.292,336.136 181.922,336.766 183.042,336.766 v2(183.54,337.264) 183.54,336.919 183.998,336.461 184.595,336.461 184.996,336.06 186.741,336.06 187.533,336.06 ccw(c187.533,336.13) 187.603,336.13 187.603,336.176 cw(c187.672,336.176) 187.672,336.245 187.879,336.245 cw(c187.879,336.176) 187.949,336.176 187.949,336.06 187.949,335.991 ccw(c188.018,335.991) 188.018,335.922 188.226,335.922 ccw(c188.226,335.991) 188.295,335.991 cw(c188.364,335.991) 188.364,336.06 188.468,336.06 192.677,336.06 193.383,336.766 194.502,336.766 v2(195,337.264) 195.79,336.474 195.925,336.474 ccw(c195.925,336.563) 196.014,336.563 196.014,336.726 cw(c196.104,336.726) 196.104,336.816 196.373,336.816 cw(c196.373,336.726) 196.462,336.726 196.462,336.474 196.462,336.221 ccw(c196.552,336.221) 196.552,336.131 196.82,336.131 ccw(c196.82,336.221) 196.91,336.221 196.91,336.474 196.91,336.65 cw(c197,336.65) 197,336.739 197.268,336.739 cw(c197.268,336.65) 197.358,336.65 197.358,336.474 197.358,336.221 ccw(c197.447,336.221) 197.447,336.131 197.716,336.131 ccw(c197.716,336.221) 197.806,336.221 197.806,336.474 197.806,336.65 cw(c197.895,336.65) 197.895,336.739 198.164,336.739 cw(c198.164,336.65) 198.253,336.65 198.253,336.474 198.253,336.221 ccw(c198.343,336.221) 198.343,336.131 198.612,336.131 ccw(c198.612,336.221) 198.701,336.221 198.701,336.474 198.701,336.65 cw(c198.791,336.65) 198.791,336.739 199.059,336.739 cw(c199.059,336.65) 199.149,336.65 199.149,336.474 199.149,336.221 ccw(c199.239,336.221) 199.239,336.131 199.507,336.131 ccw(c199.507,336.221) 199.597,336.221 199.597,336.474 199.597,336.726 cw(c199.686,336.726) 199.686,336.816 199.955,336.816 cw(c199.955,336.726) 200.045,336.726 200.045,336.563 ccw(c200.134,336.563) 200.134,336.474 200.952,336.474 200.965,336.474 201.378,336.061 202.045,336.061 202.619,336.061 203.161,336.602 204.649,336.602 205.28,337.233 v17(205.684,337.233)
  L5 (Sign) w0.151: v1(167.603,343.555) 167.603,343.534 169.102,342.035 169.102,341.085
  L3 (Sign) w0.092: v4(183.909,316.027) 183.909,316.254 183.371,316.792 183.371,317.264 183.672,317.565 183.854,317.565 184.084,317.795 184.327,317.795 185.692,319.16 185.692,319.238 186.638,320.183 186.638,321.172 186.846,321.38 cw(c186.916,321.309) 186.986,321.38 187.332,321.033 ccw(c187.403,321.103) 187.473,321.033 187.613,321.173 ccw(c187.543,321.244) 187.613,321.314 187.267,321.66 cw(c187.337,321.731) 187.267,321.801 187.407,321.941 cw(c187.477,321.871) 187.547,321.941 187.894,321.595 ccw(c187.964,321.665) 188.034,321.595 188.175,321.735 ccw(c188.104,321.805) 188.175,321.875 187.828,322.222 cw(c187.898,322.292) 187.828,322.362 ; 187.828,322.362 187.968,322.503 cw(c188.039,322.432) 188.109,322.503 188.455,322.156 ccw(c188.526,322.226) 188.596,322.156 188.736,322.296 ccw(c188.666,322.367) 188.736,322.437 188.389,322.783 cw(c188.46,322.853) 188.389,322.924 188.53,323.064 cw(c188.6,322.994) 188.67,323.064 189.017,322.717 ccw(c189.087,322.788) 189.157,322.717 189.298,322.858 ccw(c189.227,322.928) 189.298,322.998 188.951,323.345 cw(c189.021,323.415) 188.951,323.485 189.091,323.625 cw(c189.161,323.555) 189.232,323.625 189.277,323.58 ccw(c189.347,323.651) 189.417,323.58 189.557,323.721 ccw(c189.487,323.791) 189.557,323.861 189.512,323.906 cw(c189.583,323.976) 189.512,324.047 189.583,324.117 192.129,326.663 192.129,333.743 192.638,334.252 192.638,334.484 192.862,334.708 192.862,335.892 193.266,336.296 196.202,336.296 201.206,341.3 203.073,341.3 203.733,340.639 204.224,340.639 204.72,340.143 204.903,340.143 205.58,339.466 205.58,337.579 205.621,337.538 205.621,337.296 v17(205.684,337.233)
DDR4_BG1: U1.AC27
DDR4_CAS: R57.1 U1.AJ29 U8.M5 U9.M5 U10.M5 U11.M5 | length 98.2
  L1 w0.116: U9.M5@166.876,336.86 167.272,337.257 v2(167.275,337.257) ; U11.M5@178.336,336.86 178.733,337.257 v2(178.735,337.257) ; U10.M5@189.797,336.86 190.193,337.257 v2(190.195,337.257) ; U1.AJ29@190.397,316.539 v4(190.884,317.027) ; U8.M5@201.257,336.86 201.259,336.86 v2(201.656,337.257)
  L1 w0.155: R57.1@158.737,336.878 v1(159.982,336.878)
  L12 (Sign) w0.092: 165.251,336.878 165.496,336.878 165.519,336.855 166.07,336.855 166.472,337.257 166.72,337.257 v2(167.275,337.257) 167.486,337.257 167.807,337.578 168.208,337.578 168.878,336.907 169.013,336.907 ccw(c169.013,336.997) 169.102,336.997 169.102,337.062 cw(c169.192,337.062) 169.192,337.152 169.46,337.152 cw(c169.46,337.062) 169.55,337.062 169.55,336.997 ccw(c169.64,336.997) 169.64,336.907 169.672,336.907 170.688,336.907 170.822,336.907 ccw(c170.822,336.997) 170.912,336.997 170.912,337.1 cw(c171.001,337.1) 171.001,337.189 171.27,337.189 cw(c171.27,337.1) 171.36,337.1 171.36,336.997 ccw(c171.449,336.997) 171.449,336.907 171.952,336.907 172.661,336.907 173.01,337.257 v2(178.735,337.257) 178.911,337.257 179.248,337.593 180.711,337.593 181.424,336.88 184.497,336.88 185.277,337.66 185.45,337.66 185.727,337.66 cw(c185.727,337.591) 185.797,337.591 185.797,337.419 ccw(c185.866,337.419) 185.866,337.35 186.074,337.35 ccw(c186.074,337.419) 186.143,337.419 186.143,337.66 186.143,337.741 cw(c186.212,337.741) 186.212,337.81 186.42,337.81 cw(c186.42,337.741) 186.489,337.741 186.489,337.73 ccw(c186.558,337.73) 186.558,337.66 186.665,337.66 189.237,337.66 189.641,337.257 v2(190.195,337.257) 190.407,337.257 190.728,337.578 190.862,337.578 191.128,337.578 191.275,337.578 191.946,336.907 193.52,336.907 193.654,336.907 ccw(c193.654,336.997) 193.744,336.997 193.744,337.087 cw(c193.833,337.087) 193.833,337.177 194.102,337.177 cw(c194.102,337.087) 194.192,337.087 194.192,336.907 ccw(c194.281,336.907) 194.281,336.818 194.55,336.818 ccw(c194.55,336.907) 194.639,336.907 194.639,336.877 cw(c194.669,336.877) 194.669,336.907 195,336.907 195.047,336.907 195.631,336.907 195.844,336.907 ccw(c195.844,336.997) 195.934,336.997 195.934,337.081 cw(c196.023,337.081) 196.023,337.171 196.292,337.171 cw(c196.292,337.081) 196.382,337.081 196.382,336.907 196.382,336.877 ccw(c196.471,336.877) 196.471,336.787 196.74,336.787 ccw(c196.74,336.877) 196.829,336.877 cw(c196.859,336.877) 196.859,336.907 197.053,336.907 197.432,336.907 197.85,336.907 cw(c197.85,336.877) 197.88,336.877 ccw(c197.969,336.877) 197.969,336.787 198.238,336.787 ccw(c198.238,336.877) 198.327,336.877 198.327,336.907 198.327,336.987 cw(c198.417,336.987) 198.417,337.077 198.686,337.077 cw(c198.686,336.987) 198.775,336.987 198.775,336.907 198.775,336.877 ccw(c198.865,336.877) 198.865,336.787 199.133,336.787 ccw(c199.133,336.877) 199.223,336.877 cw(c199.253,336.877) 199.253,336.907 199.641,336.907 cw(c199.641,336.877) 199.671,336.877 ccw(c199.76,336.877) 199.76,336.787 200.029,336.787 ccw(c200.029,336.877) 200.119,336.877 cw(c200.149,336.877) 200.149,336.907 200.343,336.907 200.979,336.907 201.329,337.257 v2(201.656,337.257)
  L12 (Sign) w0.151: v1(159.982,336.878) 165.251,336.878
  L3 (Sign) w0.092: v4(190.884,317.027) 191.737,317.027 191.8,317.09 198.886,324.176 198.984,324.273 198.984,324.372 ccw(c198.884,324.372) 198.884,324.471 198.047,324.471 cw(c198.047,324.571) 197.947,324.571 197.947,324.769 cw(c198.047,324.769) 198.047,324.868 198.984,324.868 199.775,324.868 ccw(c199.775,324.968) 199.874,324.968 199.874,325.166 ccw(c199.775,325.166) 199.775,325.265 198.984,325.265 198.047,325.265 cw(c198.047,325.365) 197.947,325.365 197.947,325.563 cw(c198.047,325.563) 198.047,325.662 198.984,325.662 200.037,325.662 ccw(c200.037,325.762) 200.136,325.762 200.136,325.96 ccw(c200.037,325.96) 200.037,326.059 198.984,326.059 198.047,326.059 cw(c198.047,326.159) 197.947,326.159 197.947,326.357 cw(c198.047,326.357) 198.047,326.456 198.984,326.456 200.037,326.456 ccw(c200.037,326.556) 200.136,326.556 200.136,326.754 ccw(c200.037,326.754) 200.037,326.853 198.984,326.853 198.047,326.853 cw(c198.047,326.953) 197.947,326.953 197.947,327.151 cw(c198.047,327.151) 198.047,327.25 198.984,327.25 200.037,327.25 ccw(c200.037,327.35) 200.136,327.35 200.136,327.548 ccw(c200.037,327.548) 200.037,327.647 198.984,327.647 198.047,327.647 cw(c198.047,327.747) 197.947,327.747 197.947,327.945 cw(c198.047,327.945) 198.047,328.044 198.984,328.044 200.01,328.044 ccw(c200.01,328.144) 200.109,328.144 200.109,328.342 ccw(c200.01,328.342) 200.01,328.441 199.015,328.441 cw(c199.015,328.473) 198.984,328.473 198.947,328.509 198.947,332.226 198.477,332.696 198.477,332.709 198.216,332.97 198.207,332.97 198.207,334.741 200.724,337.257 v2(201.656,337.257)
DDR4_CK0: U1.AE30
DDR4_CK1: U1.AF28
DDR4_CK_N: R52.1 U1.AF30 U8.K5 U9.K5 U10.K5 U11.K5 | length 101.2
  L1 w0.1: R52.1@158.737,331.433 ccw(c158.617,331.554) 158.787,331.554 cw(c159.103,331.554) 159.103,331.87 159.828,331.87 cw(c159.828,331.677) v1(160.02,331.677) ; U1.AF30@187.397,317.539 187.87,317.066 v28(187.87,316.954) ; U8.K5@201.257,335.26 v2@201.653,334.864
  L1 w0.116: U9.K5@166.876,335.26 v2(167.279,334.857) ; U11.K5@178.336,335.26 v2(178.74,334.857) ; U10.K5@189.797,335.26 v2(190.2,334.857) ; v2(201.653,334.862) v2@201.653,334.864
  L5 (Sign) w0.1: v28(187.87,316.954) ccw(c188.076,316.954) 188.076,316.748 191.719,316.748 191.771,316.748 ccw(c191.771,316.842) 191.866,316.842 cw(c192.025,316.842) 192.025,317.002 192.06,317.002 cw(c192.06,316.842) 192.22,316.842 ccw(c192.314,316.842) 192.314,316.748 192.397,316.748 ccw(c192.491,316.748) 192.491,316.654 194.024,316.654 ccw(c194.024,319.194) 195.82,317.397 195.957,317.534 ccw(c195.656,317.835) 196.081,317.835 ccw(c195.656,317.835) 195.957,318.135 195.051,319.041 cw(c195.475,319.464) 195.051,319.888 195.132,319.968 cw(c195.555,319.545) 195.979,319.968 198.514,317.433 ccw(c198.815,317.733) 199.115,317.433 199.196,317.513 ccw(c198.895,317.814) 199.32,317.814 ccw(c198.895,317.814) 199.196,318.114 196.66,320.65 cw(c197.084,321.073) 196.66,321.497 196.741,321.577 cw(c197.164,321.154) 197.588,321.577 200.123,319.042 ccw(c200.424,319.343) 200.724,319.042 200.805,319.122 ccw(c200.504,319.423) 200.929,319.423 ccw(c200.504,319.423) 200.805,319.723 199.899,320.629 cw(c200.323,321.053) 199.899,321.476 202.984,324.561 ccw(c201.696,325.849) 203.517,325.849 203.517,326.785 cw(c203.517,326.88) 203.423,326.88 203.423,333.541 ccw(c202.526,333.541) 203.161,334.175 202.938,334.398 ccw(c202.755,334.215) 202.755,334.473 202.042,334.473 cw(c202.042,334.862) v2(201.653,334.862)
  L14 (Sign) w0.1: v1(160.02,331.677) 160.02,331.877 160.42,331.877 160.42,331.89 162.939,331.89 ccw(c162.939,332.325) 163.373,332.325 163.373,335.242 cw(c163.639,335.242) 163.639,335.508 165.001,335.508 ccw(c165.095,335.508) 165.095,335.414 165.705,335.414 cw(c165.705,334.89) 166.076,335.26 166.078,335.259 ccw(c166.599,335.78) 166.599,335.043 167.165,335.043 cw(c167.165,334.928) 167.279,334.928 v2(167.279,334.857) cw(c167.502,334.857) 167.502,335.079 167.918,335.079 ccw(c167.918,336.552) 168.959,335.511 169.026,335.578 cw(c170.687,333.917) 170.687,336.265 173.561,336.265 cw(c173.561,334.243) 174.991,335.673 ; 174.992,335.672 ccw(c176.424,337.105) 176.424,335.079 178.517,335.079 cw(c178.517,334.857) v2(178.74,334.857) cw(c178.966,334.857) 178.966,335.083 179.306,335.083 ccw(c179.306,337.44) 180.972,335.773 181.068,335.869 cw(c181.47,335.466) 181.47,336.035 184.593,336.035 184.594,336.037 184.767,336.037 cw(c184.767,334.213) 186.057,335.503 186.427,335.132 ccw(c187.589,336.294) 187.589,334.651 188.563,334.651 ccw(c188.563,335.494) 189.159,334.898 189.16,334.899 cw(c189.595,334.464) 189.595,335.079 189.978,335.079 cw(c189.978,334.857) v2(190.2,334.857) 190.2,334.92 cw(c190.36,334.92) 190.36,335.08 190.721,335.08 ccw(c190.721,337.822) 192.66,335.883 192.857,336.08 cw(c193.256,335.682) 193.256,336.245 194.894,336.245 cw(c194.894,335.261) 195.59,335.957 195.743,335.804 ccw(c196.487,336.547) 196.487,335.496 199.822,335.496 199.84,335.496 cw(c199.84,335.41) 199.926,335.41 ccw(c200.062,335.41) 200.062,335.274 200.092,335.274 ccw(c200.092,335.41) 200.229,335.41 cw(c200.314,335.41) 200.314,335.496 200.381,335.496 cw(c200.381,335.418) 200.459,335.418 200.459,335.41 ccw(c200.595,335.41) 200.595,335.274 200.626,335.274 ccw(c200.626,335.41) 200.762,335.41 cw(c200.848,335.41) 200.848,335.496 200.914,335.496 200.964,335.496 cw(c200.964,335.36) 201.1,335.36 ccw(c201.236,335.36) 201.236,335.223 201.267,335.223 ccw(c201.267,335.36) 201.403,335.36 cw(c201.539,335.36) 201.539,335.496 201.555,335.496 cw(c201.555,335.178) 201.872,335.178 201.872,335.08 cw(c201.653,335.08) v2(201.653,334.862)
DDR4_CK_P: R54.1 U1.AG28 U8.K4 U9.K4 U10.K4 U11.K4 | length 101.5
  L1 w0.1: R54.1@158.737,332.522 cw(c158.617,332.401) 158.787,332.401 ccw(c159.103,332.401) 159.103,332.085 159.828,332.085 ccw(c159.828,332.277) v1(160.02,332.277) ; v28(187.897,316.179) 187.897,316.04 U1.AG28@188.397,315.539 ; U8.K4@202.057,335.26 v2@202.453,334.864
  L1 w0.116: v2(167.272,335.664) U9.K4@167.676,335.26 ; v2(178.733,335.664) U11.K4@179.136,335.26 ; v2(190.193,335.664) U10.K4@190.597,335.26 ; v2(202.453,334.862) v2@202.453,334.864
  L5 (Sign) w0.1: v28(187.897,316.179) cw(c188.103,316.179) 188.103,316.385 192.397,316.385 cw(c192.491,316.385) 192.491,316.48 194.025,316.48 ccw(c194.025,319.192) 195.943,317.274 196.08,317.411 ccw(c195.656,317.835) 196.255,317.835 ccw(c195.656,317.835) 196.08,318.258 195.174,319.164 cw(c195.475,319.464) 195.174,319.765 195.255,319.845 cw(c195.555,319.545) 195.856,319.845 198.391,317.31 ccw(c198.815,317.733) 199.238,317.31 199.319,317.39 ccw(c198.895,317.814) 199.494,317.814 ccw(c198.895,317.814) 199.319,318.237 196.783,320.773 cw(c197.084,321.073) 196.783,321.374 196.864,321.454 cw(c197.164,321.154) 197.465,321.454 200,318.919 ccw(c200.424,319.343) 200.847,318.919 200.928,318.999 ccw(c200.504,319.423) 201.103,319.423 ccw(c200.504,319.423) 200.928,319.847 200.022,320.752 cw(c200.323,321.053) 200.022,321.353 203.108,324.439 ccw(c201.698,325.848) 203.691,325.848 203.691,326.785 ccw(c203.691,326.88) 203.786,326.88 203.786,332.194 203.786,332.266 cw(c203.88,332.266) 203.88,332.361 ccw(c203.88,332.52) 204.04,332.52 204.04,332.556 ccw(c203.88,332.556) 203.88,332.715 cw(c203.88,332.81) 203.786,332.81 203.786,332.892 203.786,332.917 cw(c203.88,332.917) 203.88,333.011 ccw(c203.88,333.171) 204.04,333.171 204.04,333.206 ccw(c203.88,333.206) 203.88,333.365 cw(c203.88,333.46) 203.786,333.46 203.786,333.542 ccw(c202.53,333.542) 203.418,334.43 203.193,334.655 ccw(c202.757,334.22) 202.757,334.835 202.48,334.835 cw(c202.48,334.862) v2(202.453,334.862)
  L14 (Sign) w0.1: v1(160.02,332.277) 160.02,332.077 160.42,332.077 160.42,332.064 162.939,332.064 ccw(c162.939,332.325) 163.199,332.325 163.199,335.242 cw(c163.639,335.242) 163.639,335.682 165.001,335.682 cw(c165.095,335.682) 165.095,335.776 165.708,335.776 cw(c165.708,334.898) 166.33,335.519 166.332,335.517 ccw(c166.601,335.786) 166.601,335.405 167.165,335.405 ccw(c167.165,335.512) 167.272,335.512 v2(167.272,335.664) ccw(c167.495,335.664) 167.495,335.441 167.917,335.441 ccw(c167.917,336.555) 168.704,335.768 168.771,335.835 cw(c170.686,333.92) 170.686,336.628 173.564,336.628 cw(c173.564,334.249) 175.245,335.931 175.247,335.929 ccw(c176.424,337.106) 176.424,335.441 178.51,335.441 ccw(c178.51,335.664) v2(178.733,335.664) ccw(c178.951,335.664) 178.951,335.445 179.302,335.445 ccw(c179.302,337.449) 180.719,336.032 180.813,336.126 cw(c181.468,335.472) 181.468,336.398 184.231,336.398 184.232,336.399 184.917,336.399 cw(c184.917,334.575) 186.207,335.865 186.681,335.39 ccw(c187.592,336.301) 187.592,335.013 188.561,335.013 ccw(c188.561,335.497) 188.904,335.155 188.905,335.156 cw(c189.594,334.467) 189.594,335.441 189.971,335.441 ccw(c189.971,335.664) v2(190.193,335.664) 190.193,335.609 ccw(c190.36,335.609) 190.36,335.442 190.655,335.442 ccw(c190.655,337.982) 192.451,336.186 192.602,336.337 cw(c193.254,335.685) 193.254,336.607 194.896,336.607 cw(c194.896,335.266) 195.845,336.214 195.999,336.06 ccw(c196.487,336.549) 196.487,335.858 200.952,335.858 201.014,335.858 ccw(c201.014,335.944) 201.1,335.944 cw(c201.236,335.944) 201.236,336.08 201.267,336.08 cw(c201.267,335.944) 201.403,335.944 ccw(c201.489,335.944) 201.489,335.858 201.555,335.858 cw(c201.555,335.178) 202.235,335.178 202.235,335.08 ; 202.235,335.028 202.235,335.08 ; v2(202.453,334.862) cw(c202.453,335.08) 202.235,335.08
DDR4_CKE0: R38.1 U1.AC30 U8.K2 U9.K2 U10.K2 U11.K2 | length 110.3
  L1 w0.116: U9.K2@171.676,335.26 v2(172.079,334.857) ; U11.K2@183.136,335.26 v2(183.54,334.857) ; U1.AC30@184.397,317.539 v4(184.884,317.052) ; U10.K2@194.597,335.26 v2(195,334.857) ; U8.K2@206.057,335.26 v17(206.461,334.857)
  L1 w0.155: v1(162.769,343.555) R38.1@162.769,344.8
  L5 (Sign) w0.092: 167.571,341.085 168.41,340.246 168.41,336.122 170.071,334.46 171.683,334.46 v2(172.079,334.857) 172.333,334.857 172.675,334.515 173.142,334.515 173.997,333.66 174.131,333.66 cw(c174.131,333.571) 174.221,333.571 174.221,333.511 ccw(c174.31,333.511) 174.31,333.422 174.579,333.422 ccw(c174.579,333.511) 174.668,333.511 174.668,333.571 cw(c174.758,333.571) 174.758,333.66 175.73,333.66 181.536,333.66 182.336,334.46 182.629,334.46 183.025,334.857 v2(183.54,334.857) 184.385,334.012 184.654,334.012 185.805,332.86 191.573,332.86 193.173,334.46 193.955,334.46 194.352,334.857 v2(195,334.857) 195.07,334.857 195.249,334.677 195.971,334.677 196.613,334.035 196.613,333.411 196.954,333.07 198.216,333.07 198.444,333.07 cw(c198.444,332.981) 198.534,332.981 198.534,332.734 ccw(c198.623,332.734) 198.623,332.644 198.892,332.644 ccw(c198.892,332.734) 198.982,332.734 198.982,333.07 198.982,333.407 cw(c199.071,333.407) 199.071,333.496 199.34,333.496 cw(c199.34,333.407) 199.43,333.407 199.43,333.07 199.43,332.734 ccw(c199.519,332.734) 199.519,332.644 199.788,332.644 ccw(c199.788,332.734) 199.877,332.734 199.877,332.981 cw(c199.967,332.981) 199.967,333.07 200.101,333.07 200.416,333.385 200.416,334.158 201.508,335.25 203.375,335.25 204.146,334.48 206.084,334.48 v17(206.461,334.857)
  L5 (Sign) w0.151: v1(162.769,343.555) 162.769,342.831 164.224,341.376 167.28,341.376 167.571,341.085
  L3 (Sign) w0.092: v4(184.884,317.052) 184.884,316.531 186.231,315.185 186.231,314.919 185.857,314.546 185.678,314.546 185.504,314.372 185.504,312.908 185.822,312.59 186.168,312.59 188.759,309.999 192.411,309.999 192.45,310.038 192.458,310.038 205.797,323.376 205.797,324.587 207.05,325.839 207.05,329.514 207.05,329.613 ccw(c206.95,329.613) 206.95,329.713 206.939,329.713 cw(c206.939,329.812) 206.84,329.812 206.84,330.01 cw(c206.939,330.01) 206.939,330.11 207.05,330.11 207.306,330.11 ccw(c207.306,330.209) 207.405,330.209 207.405,330.407 ccw(c207.306,330.407) 207.306,330.507 207.05,330.507 206.358,330.507 cw(c206.358,330.606) 206.259,330.606 206.259,330.804 cw(c206.358,330.804) 206.358,330.904 207.05,330.904 207.166,330.904 ccw(c207.166,331.003) 207.265,331.003 207.265,331.201 ccw(c207.166,331.201) 207.166,331.301 207.05,331.301 206.938,331.301 cw(c206.938,331.4) 206.839,331.4 206.839,331.598 cw(c206.938,331.598) 206.938,331.698 206.95,331.698 ccw(c206.95,331.797) 207.05,331.797 207.05,333.438 207.05,333.539 206.461,334.128 v17(206.461,334.857)
DDR4_CKE1: U1.AB28
DDR4_CS_B: R46.1 U1.AD30 U8.L4 U9.L4 U10.L4 U11.L4 | length 101.1
  L1 w0.116: U9.L4@167.676,336.06 168.072,336.457 v2(168.075,336.457) ; U11.L4@179.136,336.06 179.533,336.457 v2(179.535,336.457) ; U1.AD30@185.397,317.539 v4(185.884,318.027) ; U10.L4@190.597,336.06 190.993,336.457 v2(190.995,336.457) ; U8.L4@202.057,336.06 202.453,336.457 v3(202.456,336.457)
  L1 w0.155: R46.1@158.737,333.611 v1(159.982,333.611)
  L1 w0.25: v2(188.593,335.664) 188.997,335.26
  L12 (Sign) w0.092: 165.251,335.39 166.001,335.39 166.728,336.118 167.736,336.118 v2(168.075,336.457) 168.471,336.06 172.682,336.06 173.297,335.445 174.206,335.445 175.143,335.445 ccw(c175.143,335.535) 175.233,335.535 ; 175.233,335.524 cw(c175.322,335.524) 175.322,335.613 175.591,335.613 cw(c175.591,335.524) 175.681,335.524 175.681,335.445 175.681,335.356 ccw(c175.77,335.356) 175.77,335.266 176.039,335.266 ccw(c176.039,335.356) 176.128,335.356 cw(c176.218,335.356) 176.218,335.445 176.352,335.445 176.564,335.657 177.394,335.657 177.797,336.06 179.139,336.06 v2(179.535,336.457) 179.932,336.06 184.472,336.06 185.272,335.26 186.919,335.26 187.33,335.26 ccw(c187.33,335.33) 187.399,335.33 187.399,335.405 cw(c187.469,335.405) 187.469,335.474 187.676,335.474 cw(c187.676,335.405) 187.746,335.405 187.746,335.26 187.746,335.116 ccw(c187.815,335.116) 187.815,335.047 188.022,335.047 ccw(c188.022,335.116) 188.092,335.116 188.092,335.191 cw(c188.161,335.191) 188.161,335.26 188.265,335.26 188.997,335.26 189.797,336.06 190.599,336.06 v2(190.995,336.457) 191.461,335.991 192.261,335.191 193.599,335.191 193.904,335.496 194.475,335.496 194.691,335.28 198.999,335.28 199.014,335.28 199.238,335.28 200.048,335.28 ccw(c200.048,335.37) 200.138,335.37 200.138,335.467 cw(c200.227,335.467) 200.227,335.556 200.496,335.556 cw(c200.496,335.467) 200.585,335.467 200.585,335.28 200.585,334.989 ccw(c200.675,334.989) 200.675,334.9 200.944,334.9 ccw(c200.944,334.989) 201.033,334.989 201.033,335.19 cw(c201.123,335.19) 201.123,335.28 201.257,335.28 201.279,335.28 201.99,335.991 v3(202.456,336.457)
  L12 (Sign) w0.151: v1(159.982,333.611) 163.225,333.611 165.005,335.39 165.251,335.39
  L3 (Sign) w0.092: v4(185.884,318.027) 185.884,319.158 190.043,323.317 190.113,323.387 ccw(c190.043,323.457) 190.113,323.527 189.79,323.85 cw(c189.861,323.92) 189.79,323.99 189.931,324.13 cw(c190.001,324.06) 190.071,324.13 190.464,323.738 191.033,323.168 ccw(c191.103,323.239) 191.173,323.168 191.314,323.309 ccw(c191.244,323.379) 191.314,323.449 190.745,324.018 190.352,324.411 cw(c190.422,324.481) 190.352,324.551 190.492,324.692 cw(c190.562,324.622) 190.633,324.692 191.025,324.299 191.595,323.73 ccw(c191.665,323.8) 191.735,323.73 191.875,323.87 ccw(c191.805,323.94) 191.875,324.011 191.306,324.58 190.913,324.973 cw(c190.983,325.043) 190.913,325.113 191.054,325.253 cw(c191.124,325.183) 191.194,325.253 191.587,324.861 192.14,324.307 ccw(c192.21,324.377) 192.281,324.307 192.421,324.447 ccw(c192.351,324.518) 192.421,324.588 191.867,325.141 191.475,325.534 cw(c191.545,325.604) 191.475,325.674 191.615,325.815 cw(c191.685,325.745) 191.755,325.815 192.099,325.471 ccw(c192.148,325.52) 192.197,325.471 192.321,325.594 192.321,333.664 192.83,334.173 192.83,334.29 193.072,334.532 193.072,335.79 193.084,335.802 193.084,335.813 193.247,335.976 193.258,335.976 193.26,335.978 193.262,335.978 193.365,336.08 196.258,336.08 201.263,341.085 202.309,341.085 203.057,340.338 203.057,338.206 202.818,337.966 202.818,337.9 202.703,337.785 202.703,337.464 202.777,337.39 202.777,337.124 202.703,337.05 202.703,336.704 v3(202.456,336.457)
DDR4_CS_N1: U1.AD29
DDR4_DM0: U1.AJ20 U8.E2 | length 46.3
  L1 w0.116: U1.AJ20@190.397,307.539 v2(190.8,307.136) ; U8.E2@206.057,331.26 v2(206.461,331.664)
  L12 (Sign) w0.092: v2(190.8,307.136) 191.396,307.731 191.751,307.731 192.017,307.731 192.401,308.115 192.462,308.176 ccw(c192.401,308.237) 192.462,308.298 192.426,308.334 cw(c192.487,308.396) 192.426,308.457 192.549,308.579 cw(c192.61,308.518) 192.671,308.579 192.768,308.482 192.866,308.384 ccw(c192.928,308.445) 192.989,308.384 193.111,308.506 ccw(c193.05,308.567) 193.111,308.629 193.013,308.727 192.916,308.824 cw(c192.977,308.885) 192.916,308.946 193.038,309.069 cw(c193.099,309.008) 193.161,309.069 193.258,308.971 193.356,308.873 ccw(c193.417,308.935) 193.478,308.873 193.601,308.996 ccw(c193.54,309.057) 193.601,309.118 193.503,309.216 193.405,309.314 cw(c193.467,309.375) 193.405,309.436 193.528,309.558 cw(c193.589,309.497) 193.65,309.558 193.747,309.461 193.846,309.363 ccw(c193.907,309.424) 193.968,309.363 194.09,309.485 ccw(c194.029,309.547) 194.09,309.608 193.992,309.706 193.895,309.803 cw(c193.956,309.864) 193.895,309.926 194.017,310.048 cw(c194.079,309.987) 194.14,310.048 194.237,309.951 194.335,309.853 ccw(c194.396,309.914) 194.458,309.853 194.58,309.975 ccw(c194.519,310.036) 194.58,310.097 194.482,310.195 194.385,310.293 cw(c194.446,310.354) 194.385,310.415 194.507,310.538 cw(c194.568,310.476) 194.629,310.538 194.727,310.44 194.825,310.342 ccw(c194.886,310.403) 194.947,310.342 195.07,310.465 ccw(c195.008,310.526) 195.07,310.587 194.971,310.685 194.874,310.782 cw(c194.935,310.844) 194.874,310.905 194.997,311.027 cw(c195.058,310.966) 195.119,311.027 195.216,310.93 195.314,310.832 ccw(c195.376,310.893) 195.437,310.832 195.559,310.954 ccw(c195.498,311.015) 195.559,311.077 195.461,311.175 195.364,311.272 cw(c195.425,311.333) 195.364,311.394 195.486,311.517 cw(c195.547,311.456) 195.609,311.517 195.706,311.419 195.804,311.321 ccw(c195.865,311.383) 195.926,311.321 196.049,311.444 ccw(c195.988,311.505) 196.049,311.566 195.951,311.664 195.853,311.762 cw(c195.915,311.823) 195.853,311.884 195.976,312.006 cw(c196.037,311.945) 196.098,312.006 196.195,311.909 196.294,311.811 ccw(c196.355,311.872) 196.416,311.811 196.538,311.933 ccw(c196.477,311.995) 196.538,312.056 196.44,312.154 196.343,312.251 cw(c196.404,312.312) 196.343,312.374 196.465,312.496 cw(c196.527,312.435) 196.588,312.496 196.685,312.399 196.783,312.301 ccw(c196.844,312.362) 196.906,312.301 197.028,312.423 ccw(c196.967,312.484) 197.028,312.545 196.93,312.643 196.833,312.741 cw(c196.894,312.802) 196.833,312.863 196.955,312.986 cw(c197.016,312.924) 197.077,312.986 197.175,312.888 197.273,312.79 ccw(c197.334,312.851) 197.395,312.79 197.518,312.913 ccw(c197.456,312.974) 197.518,313.035 197.419,313.133 197.322,313.23 cw(c197.383,313.292) 197.322,313.353 197.445,313.475 cw(c197.506,313.414) 197.567,313.475 197.664,313.378 197.762,313.28 ccw(c197.824,313.341) 197.885,313.28 198.007,313.402 ccw(c197.946,313.463) 198.007,313.525 197.909,313.623 197.812,313.72 cw(c197.873,313.781) 197.812,313.842 197.934,313.965 cw(c197.995,313.904) 198.057,313.965 198.154,313.867 198.252,313.769 ccw(c198.313,313.831) 198.374,313.769 198.497,313.892 ccw(c198.436,313.953) 198.497,314.014 198.399,314.112 198.301,314.21 cw(c198.363,314.271) 198.301,314.332 198.424,314.454 cw(c198.485,314.393) 198.546,314.454 198.643,314.357 198.742,314.259 ccw(c198.803,314.32) 198.864,314.259 198.986,314.381 ccw(c198.925,314.443) 198.986,314.504 198.888,314.602 198.791,314.699 cw(c198.852,314.76) 198.791,314.822 198.913,314.944 cw(c198.975,314.883) 199.036,314.944 199.133,314.847 199.231,314.749 ccw(c199.292,314.81) 199.354,314.749 199.476,314.871 ccw(c199.415,314.932) 199.476,314.993 199.378,315.091 199.281,315.189 cw(c199.342,315.25) 199.281,315.311 199.403,315.434 cw(c199.464,315.372) 199.525,315.434 199.623,315.336 199.721,315.238 ccw(c199.782,315.299) 199.843,315.238 199.966,315.361 ccw(c199.904,315.422) 199.966,315.483 199.867,315.581 199.77,315.678 cw(c199.831,315.74) 199.77,315.801 199.893,315.923 cw(c199.954,315.862) 200.015,315.923 200.112,315.826 200.21,315.728 ccw(c200.272,315.789) 200.333,315.728 200.455,315.85 ccw(c200.394,315.911) 200.455,315.973 200.418,316.009 cw(c200.479,316.071) 200.418,316.132 204.906,320.62 208.152,323.865 208.152,330.633 207.912,330.873 207.191,330.873 206.461,331.604 v2(206.461,331.664)
DDR4_DM1: U1.AJ25 U8.E4 | length 31.4
  L1 w0.116: U1.AJ25@190.397,312.539 v5(190.884,313.027) ; U8.E4@202.07,331.241 v2(202.473,330.838)
  L12 (Sign) w0.092: v5(190.884,313.027) 191.031,313.027 192.22,314.216 192.336,314.333 ccw(c192.259,314.41) 192.336,314.488 192.089,314.735 cw(c192.167,314.813) 192.089,314.89 192.322,315.123 cw(c192.4,315.046) 192.478,315.123 192.803,314.799 192.999,314.603 ccw(c193.076,314.68) 193.154,314.603 193.387,314.836 ccw(c193.309,314.913) 193.387,314.991 193.191,315.187 192.866,315.512 cw(c192.944,315.59) 192.866,315.667 193.099,315.9 cw(c193.177,315.823) 193.255,315.9 193.579,315.576 193.776,315.38 ccw(c193.853,315.457) 193.931,315.38 194.164,315.613 ccw(c194.086,315.69) 194.164,315.768 193.968,315.964 193.643,316.289 cw(c193.721,316.367) 193.643,316.444 193.876,316.677 cw(c193.954,316.6) 194.032,316.677 194.356,316.353 194.553,316.156 ccw(c194.63,316.234) 194.708,316.156 194.941,316.39 ccw(c194.863,316.467) 194.941,316.545 194.745,316.741 194.42,317.066 cw(c194.498,317.143) 194.42,317.221 194.653,317.454 cw(c194.731,317.377) 194.809,317.454 195.056,317.207 ccw(c195.133,317.285) 195.211,317.207 196.361,318.357 201.178,323.174 201.178,329.123 200.5,329.802 200.5,330.193 200.738,330.432 201.757,330.432 202.16,330.835 202.471,330.835 v2(202.473,330.838)
DDR4_DM2: U1.AF21 U10.E2 | length 39.6
  L1 w0.116: v5(186.909,309.027) U1.AF21@187.397,308.539 ; U10.E2@194.597,331.26 v2(195,331.664)
  L12 (Sign) w0.092: v5(186.909,309.027) 187.261,308.675 187.96,308.675 188.016,308.731 188.017,308.731 188.205,308.919 188.205,308.921 188.62,309.335 188.62,310.067 188.122,310.565 188.092,310.565 187.357,311.3 187.357,312.749 187.422,312.814 187.422,313.589 185.814,315.198 185.814,316.001 187.966,318.154 188.281,318.468 ccw(c188.175,318.575) 188.281,318.681 188.256,318.706 cw(c188.362,318.812) 188.256,318.918 188.468,319.13 cw(c188.574,319.024) 188.68,319.13 188.811,318.999 188.942,318.868 ccw(c189.049,318.974) 189.155,318.868 189.367,319.08 ccw(c189.261,319.186) 189.367,319.292 189.236,319.423 189.104,319.555 cw(c189.21,319.661) 189.104,319.767 189.317,319.979 cw(c189.423,319.873) 189.529,319.979 189.66,319.848 189.791,319.716 ccw(c189.897,319.823) 190.003,319.716 190.216,319.929 ccw(c190.11,320.035) 190.216,320.141 190.084,320.272 189.953,320.403 cw(c190.059,320.509) 189.953,320.616 190.165,320.828 cw(c190.271,320.722) 190.378,320.828 190.509,320.697 190.64,320.565 ccw(c190.746,320.671) 190.852,320.565 191.064,320.777 ccw(c190.958,320.884) 191.064,320.99 190.933,321.121 190.802,321.252 cw(c190.908,321.358) 190.802,321.464 191.014,321.677 cw(c191.12,321.57) 191.226,321.677 191.358,321.545 191.489,321.414 ccw(c191.595,321.52) 191.701,321.414 191.913,321.626 ccw(c191.807,321.732) 191.913,321.839 191.782,321.97 191.651,322.101 cw(c191.757,322.207) 191.651,322.313 191.863,322.525 cw(c191.969,322.419) 192.075,322.525 192.206,322.394 192.338,322.263 ccw(c192.444,322.369) 192.55,322.263 192.762,322.475 ccw(c192.656,322.581) 192.762,322.687 192.631,322.819 192.5,322.95 cw(c192.606,323.056) 192.5,323.162 192.712,323.374 cw(c192.818,323.268) 192.924,323.374 193.055,323.243 193.187,323.112 ccw(c193.293,323.218) 193.399,323.112 193.611,323.324 ccw(c193.505,323.43) 193.611,323.536 193.48,323.667 193.348,323.799 cw(c193.455,323.905) 193.348,324.011 193.561,324.223 cw(c193.667,324.117) 193.773,324.223 193.904,324.092 194.035,323.961 ccw(c194.141,324.067) 194.248,323.961 194.46,324.173 ccw(c194.354,324.279) 194.46,324.385 194.328,324.516 194.197,324.647 cw(c194.303,324.754) 194.197,324.86 194.409,325.072 cw(c194.516,324.966) 194.622,325.072 194.753,324.941 194.884,324.809 ccw(c194.99,324.915) 195.096,324.809 195.309,325.022 ccw(c195.202,325.128) 195.309,325.234 195.283,325.259 cw(c195.39,325.365) 195.283,325.471 195.389,325.577 195.389,331.275 v2(195,331.664)
DDR4_DM3: U1.AE25 U10.E4 | length 29
  L1 w0.116: v5(185.909,313.027) U1.AE25@186.397,312.539 ; U10.E4@190.597,331.26 v2(191,330.857)
  L12 (Sign) w0.092: v5(185.909,313.027) 185.909,313.251 ccw(c185.712,313.251) 185.712,313.449 185.603,313.449 ccw(c185.603,313.278) 185.433,313.278 185.433,312.793 cw(c185.255,312.793) 185.255,312.615 184.868,312.615 184.396,313.086 184.396,318.867 186.505,320.975 186.611,321.081 ccw(c186.54,321.152) 186.611,321.222 186.608,321.225 cw(c186.678,321.295) 186.608,321.366 186.819,321.577 cw(c186.89,321.507) 186.96,321.577 187.034,321.504 187.107,321.431 ccw(c187.177,321.502) 187.248,321.431 187.459,321.643 ccw(c187.389,321.713) 187.459,321.784 187.386,321.857 187.313,321.93 cw(c187.384,322) 187.313,322.071 187.525,322.283 cw(c187.595,322.212) 187.666,322.283 187.739,322.209 187.812,322.136 ccw(c187.882,322.207) 187.953,322.136 188.165,322.348 ccw(c188.094,322.418) 188.165,322.489 188.091,322.562 188.018,322.635 cw(c188.089,322.706) 188.018,322.776 188.23,322.988 cw(c188.3,322.917) 188.371,322.988 188.444,322.914 188.517,322.841 ccw(c188.588,322.912) 188.658,322.841 188.87,323.053 ccw(c188.799,323.123) 188.87,323.194 188.796,323.267 188.723,323.34 cw(c188.794,323.411) 188.723,323.481 188.935,323.693 cw(c189.005,323.622) 189.076,323.693 189.149,323.62 189.222,323.546 ccw(c189.293,323.617) 189.363,323.546 189.575,323.758 ccw(c189.504,323.829) 189.575,323.899 189.502,323.972 189.428,324.045 cw(c189.499,324.116) 189.428,324.186 189.64,324.398 cw(c189.71,324.327) 189.781,324.398 189.854,324.325 189.927,324.252 ccw(c189.998,324.322) 190.068,324.252 190.28,324.463 ccw(c190.209,324.534) 190.28,324.604 190.207,324.677 190.134,324.75 cw(c190.204,324.821) 190.134,324.891 190.345,325.103 cw(c190.416,325.033) 190.486,325.103 190.489,325.1 ccw(c190.559,325.171) 190.63,325.1 191.253,325.723 191.358,325.829 191.476,325.829 191.771,326.125 ; v2(191,330.857) 191.771,330.085 191.771,326.125 ; 191.771,326.432 191.771,326.125
DDR4_DM4: U1.Y24 U9.E2 | length 39.1
  L1 w0.116: v2(171.272,330.857) U9.E2@171.676,331.26 ; v1(180.909,311.052) U1.Y24@181.397,311.539
  L12 (Sign) w0.092: v2(171.272,330.857) 171.272,330.591 172.37,329.493 172.37,327.634 172.547,327.458 cw(c172.586,327.419) 172.625,327.458 172.899,327.183 cw(c172.86,327.144) 172.899,327.105 172.646,326.852 ccw(c172.717,326.782) 172.646,326.711 172.858,326.5 ccw(c172.929,326.57) 172.999,326.5 173.252,326.752 173.489,326.99 cw(c173.56,326.919) 173.63,326.99 173.842,326.778 cw(c173.771,326.708) 173.842,326.637 173.604,326.4 173.352,326.147 ccw(c173.422,326.077) 173.352,326.006 173.563,325.794 ccw(c173.634,325.865) 173.704,325.794 173.957,326.047 174.21,326.3 cw(c174.28,326.23) 174.351,326.3 174.562,326.089 cw(c174.492,326.018) 174.562,325.947 174.309,325.695 174.057,325.442 ccw(c174.127,325.371) 174.057,325.301 174.268,325.089 ccw(c174.339,325.16) 174.409,325.089 174.662,325.342 174.915,325.595 cw(c174.985,325.524) 175.056,325.595 175.267,325.383 cw(c175.197,325.313) 175.267,325.242 175.015,324.99 174.762,324.737 ccw(c174.832,324.666) 174.762,324.596 174.973,324.384 ccw(c175.044,324.455) 175.114,324.384 175.367,324.637 175.62,324.89 cw(c175.69,324.819) 175.761,324.89 175.973,324.678 cw(c175.902,324.608) 175.973,324.537 175.72,324.284 175.467,324.032 ccw(c175.537,323.961) 175.467,323.891 175.678,323.679 ccw(c175.749,323.75) 175.82,323.679 176.072,323.932 176.325,324.185 cw(c176.396,324.114) 176.466,324.185 176.678,323.973 cw(c176.607,323.903) 176.678,323.832 176.495,323.65 ccw(c176.566,323.579) 176.495,323.509 176.662,323.342 176.746,323.258 176.746,322.999 176.746,322.165 ccw(c176.835,322.165) 176.835,322.075 176.998,322.075 cw(c176.998,321.986) 177.088,321.986 177.088,321.717 cw(c176.998,321.717) 176.998,321.627 176.746,321.627 176.492,321.627 ccw(c176.492,321.538) 176.402,321.538 176.402,321.269 ccw(c176.492,321.269) 176.492,321.18 176.746,321.18 176.998,321.18 cw(c176.998,321.09) 177.088,321.09 177.088,320.821 cw(c176.998,320.821) 176.998,320.732 176.746,320.732 176.492,320.732 ccw(c176.492,320.642) 176.402,320.642 176.402,320.373 ccw(c176.492,320.373) 176.492,320.284 176.746,320.284 176.998,320.284 cw(c176.998,320.194) 177.088,320.194 177.088,319.926 cw(c176.998,319.926) 176.998,319.836 176.746,319.836 176.492,319.836 ccw(c176.492,319.747) 176.402,319.747 176.402,319.478 ccw(c176.492,319.478) 176.492,319.388 176.746,319.388 176.998,319.388 cw(c176.998,319.299) 177.088,319.299 177.088,319.03 cw(c176.998,319.03) 176.998,318.941 176.746,318.941 176.492,318.941 ccw(c176.492,318.851) 176.402,318.851 176.402,318.582 ccw(c176.492,318.582) 176.492,318.493 176.656,318.493 cw(c176.656,318.403) 176.746,318.403 176.746,318.269 176.746,316.114 177.786,315.074 177.786,312.854 178.488,312.151 178.488,311.863 178.72,311.631 179.048,311.631 179.124,311.706 179.695,311.706 179.812,311.589 180.325,311.589 180.862,311.052 v1(180.909,311.052)
DDR4_DM5: U1.R24 U9.E4 | length 31.7
  L1 w0.116: U9.E4@167.676,331.26 v2(168.079,330.857) ; U1.R24@176.397,311.539 v1(176.884,312.027)
  L12 (Sign) w0.092: v2(168.079,330.857) 167.118,329.895 167.118,323.904 167.781,323.241 168.448,322.574 cw(c168.36,322.486) 168.448,322.397 168.317,322.266 ccw(c168.405,322.178) 168.317,322.089 168.493,321.913 ccw(c168.581,322.001) 168.669,321.913 168.889,322.133 168.916,322.16 cw(c169.004,322.072) 169.092,322.16 169.269,321.983 cw(c169.18,321.895) 169.269,321.807 ; 169.269,321.807 ccw(c169.295,321.78) 169.269,321.754 169.418,321.604 169.58,321.442 cw(c169.492,321.354) 169.58,321.266 169.448,321.134 ccw(c169.536,321.046) 169.448,320.958 169.624,320.782 ccw(c169.713,320.87) 169.801,320.782 170.021,321.002 cw(c170.093,320.929) 170.165,321.002 170.373,320.793 cw(c170.301,320.721) 170.373,320.649 170.153,320.429 ccw(c170.241,320.341) 170.153,320.253 170.33,320.077 ccw(c170.418,320.165) 170.506,320.077 170.726,320.296 cw(c170.798,320.224) 170.87,320.296 171.078,320.088 cw(c171.006,320.016) 171.078,319.944 170.858,319.724 ccw(c170.947,319.636) 170.858,319.548 171.035,319.372 ccw(c171.123,319.46) 171.211,319.372 171.431,319.591 cw(c171.503,319.519) 171.575,319.591 171.783,319.383 cw(c171.711,319.311) 171.783,319.239 171.564,319.019 ccw(c171.652,318.931) 171.564,318.843 171.74,318.666 ccw(c171.828,318.755) 171.916,318.666 172.048,318.798 cw(c172.136,318.71) 172.224,318.798 172.312,318.71 172.312,316.282 172.885,315.709 172.885,314.617 173.841,313.662 173.841,311.589 174.229,311.201 174.701,311.201 174.892,311.391 175.689,311.391 175.72,311.423 176.048,311.423 176.08,311.391 176.545,311.391 176.884,311.73 v1(176.884,312.027)
DDR4_DM6: U1.V28 U11.E2 | length 28.8
  L1 w0.116: v4(178.91,316.027) U1.V28@179.397,315.539 ; U11.E2@183.136,331.26 183.533,330.864 v4(183.533,330.862)
  L3 (Sign) w0.092: v4(178.91,316.027) 178.91,316.425 179.324,316.84 179.324,317.462 179.08,317.706 178.751,317.706 178.563,317.894 178.563,318.416 182.062,321.915 182.149,322.001 cw(c182.21,321.94) 182.271,322.001 182.303,321.97 ccw(c182.364,322.031) 182.425,321.97 182.548,322.092 ccw(c182.487,322.153) 182.548,322.215 182.516,322.246 cw(c182.577,322.307) 182.516,322.369 182.639,322.491 cw(c182.7,322.43) 182.761,322.491 182.793,322.459 ccw(c182.854,322.521) 182.915,322.459 183.037,322.582 ccw(c182.976,322.643) 183.037,322.704 183.006,322.736 cw(c183.067,322.797) 183.006,322.858 183.189,323.042 183.312,323.164 184.273,323.164 184.507,323.398 184.507,323.484 ccw(c184.42,323.484) 184.42,323.571 184.06,323.571 cw(c184.06,323.658) 183.973,323.658 183.973,323.831 cw(c184.06,323.831) 184.06,323.917 184.507,323.917 184.66,323.917 ccw(c184.66,324.004) 184.746,324.004 184.746,324.177 ccw(c184.66,324.177) 184.66,324.263 184.507,324.263 184.06,324.263 cw(c184.06,324.35) 183.973,324.35 183.973,324.523 cw(c184.06,324.523) 184.06,324.61 184.507,324.61 184.66,324.61 ccw(c184.66,324.696) 184.746,324.696 184.746,324.869 ccw(c184.66,324.869) 184.66,324.956 184.507,324.956 184.06,324.956 cw(c184.06,325.042) 183.973,325.042 183.973,325.215 cw(c184.06,325.215) 184.06,325.302 184.507,325.302 184.66,325.302 ccw(c184.66,325.389) 184.746,325.389 184.746,325.562 ccw(c184.66,325.562) 184.66,325.648 184.507,325.648 184.06,325.648 cw(c184.06,325.735) 183.973,325.735 183.973,325.908 cw(c184.06,325.908) 184.06,325.994 184.507,325.994 184.66,325.994 ccw(c184.66,326.081) 184.746,326.081 184.746,326.254 ccw(c184.66,326.254) 184.66,326.341 184.507,326.341 184.06,326.341 cw(c184.06,326.427) 183.973,326.427 183.973,326.6 cw(c184.06,326.6) 184.06,326.687 184.507,326.687 184.66,326.687 ccw(c184.66,326.773) 184.746,326.773 184.746,326.946 ccw(c184.66,326.946) 184.66,327.033 184.593,327.033 cw(c184.593,327.12) 184.507,327.12 184.507,327.381 184.507,327.411 183.909,328.009 183.909,329.603 ccw(c183.777,329.603) 183.777,329.735 183.642,329.735 cw(c183.642,329.862) 183.515,329.862 183.515,329.991 cw(c183.623,329.991) 183.623,330.098 183.972,330.098 ccw(c183.972,330.247) 184.121,330.247 184.121,330.276 ccw(c183.962,330.276) 183.962,330.436 183.693,330.436 cw(c183.693,330.596) 183.533,330.596 v4(183.533,330.862)
DDR4_DM7: U1.P28 U11.E4 | length 21.5
  L1 w0.116: v4(174.91,316.027) U1.P28@175.397,315.539 ; v4(178.74,331.659) 178.74,331.657 U11.E4@179.136,331.26
  L3 (Sign) w0.092: v4(174.91,316.027) 174.249,316.027 174.001,316.274 174.001,317.963 176.682,320.645 176.682,325.153 177.662,326.133 177.662,328.85 178.192,329.38 178.192,329.857 178.384,330.05 178.384,330.169 ccw(c178.305,330.169) 178.305,330.248 178.248,330.248 cw(c178.248,330.328) 178.169,330.328 178.169,330.566 cw(c178.248,330.566) 178.248,330.645 178.384,330.645 179.123,330.645 ccw(c179.123,330.725) 179.203,330.725 179.203,330.963 ccw(c179.123,330.963) 179.123,331.042 178.464,331.042 cw(c178.464,331.122) 178.384,331.122 178.384,331.304 v4(178.74,331.659)
DDR4_DM8: U1.AA27
DDR4_DQ0: U1.AH22 U8.G2 | length 47.3
  L1 w0.116: U1.AH22@189.397,309.539 v5(189.884,309.052) ; U8.G2@206.057,332.86 v2(206.461,333.264)
  L12 (Sign) w0.092: v5(189.884,309.052) 189.884,308.898 189.128,308.142 189.128,308.056 188.314,307.242 188.265,307.242 188.265,305.671 188.539,305.397 189.635,305.397 189.947,305.709 192.629,305.709 209.396,322.477 209.396,332.421 208.083,333.734 207.084,333.734 206.614,333.264 v2(206.461,333.264)
DDR4_DQ1: U1.AH21 U8.F4 | length 47.3
  L1 w0.116: U1.AH21@189.397,308.539 v5(189.884,308.052) ; v2(201.653,332.464) U8.F4@202.057,332.06
  L12 (Sign) w0.092: v5(189.884,308.052) 190.468,308.635 191.96,308.635 207.166,323.84 207.166,323.875 207.166,324.438 207.166,324.697 ccw(c207.079,324.697) 207.079,324.784 206.353,324.784 cw(c206.353,324.871) 206.266,324.871 206.266,325.044 cw(c206.353,325.044) 206.353,325.13 207.079,325.13 ccw(c207.079,325.217) 207.166,325.217 207.166,325.39 ccw(c207.079,325.39) 207.079,325.476 206.353,325.476 cw(c206.353,325.563) 206.266,325.563 206.266,325.736 cw(c206.353,325.736) 206.353,325.823 207.079,325.823 ccw(c207.079,325.909) 207.166,325.909 207.166,326.082 ccw(c207.079,326.082) 207.079,326.169 206.353,326.169 cw(c206.353,326.255) 206.266,326.255 206.266,326.428 cw(c206.353,326.428) 206.353,326.515 207.079,326.515 ccw(c207.079,326.602) 207.166,326.602 207.166,326.775 ccw(c207.079,326.775) 207.079,326.861 206.353,326.861 cw(c206.353,326.948) 206.266,326.948 206.266,327.121 cw(c206.353,327.121) 206.353,327.207 207.079,327.207 ccw(c207.079,327.294) 207.166,327.294 207.166,327.467 ccw(c207.079,327.467) 207.079,327.554 206.782,327.554 cw(c206.782,327.64) 206.696,327.64 206.696,327.813 cw(c206.782,327.813) 206.782,327.9 207.079,327.9 ccw(c207.079,327.986) 207.166,327.986 207.166,328.159 ccw(c207.079,328.159) 207.079,328.246 206.921,328.246 cw(c206.921,328.333) 206.835,328.333 206.835,328.506 cw(c206.921,328.506) 206.921,328.592 207.079,328.592 ccw(c207.079,328.679) 207.166,328.679 207.166,328.765 207.166,330.356 206.371,331.151 206.188,331.151 205.325,332.014 204.659,332.014 203.019,333.654 202.129,333.654 201.653,333.179 v2(201.653,332.464)
DDR4_DQ2: U1.AJ22 U8.H3 | length 45.9
  L1 w0.116: U1.AJ22@190.397,309.539 v5(190.884,309.052) ; v2(204.853,334.064) U8.H3@205.257,333.66
  L12 (Sign) w0.092: v5(190.884,309.052) 190.396,309.052 188.506,307.162 188.506,305.829 188.659,305.676 189.585,305.676 190.664,306.756 190.874,306.756 191.636,307.518 192.399,307.518 208.343,323.463 208.343,331.254 207.982,331.615 207.132,331.615 206.549,332.198 205.912,332.198 205.366,332.744 205.366,333.551 v2(204.853,334.064)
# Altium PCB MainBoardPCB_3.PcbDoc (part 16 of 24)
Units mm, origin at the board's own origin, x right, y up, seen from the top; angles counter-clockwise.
Board outline 258.95 x 308.86 mm, 16 copper layers (L1, L2 (GND), L3 (Sign), L4 (GND), L5 (Sign), L6 (PWR/GND), L7(PWR/GND), L8 (Plane_GND), L9 (PWR/GND), L10 (PWR/GND), L11 (PWR/GND), L12 (Sign), L13 (GND), L14 (Sign), L15 (GND), L16), stack 2.502 mm thick; 2402 components, 1749 nets, 8407 pads, 3409 vias.
Unrouted connection lines stored in the file: 4352.

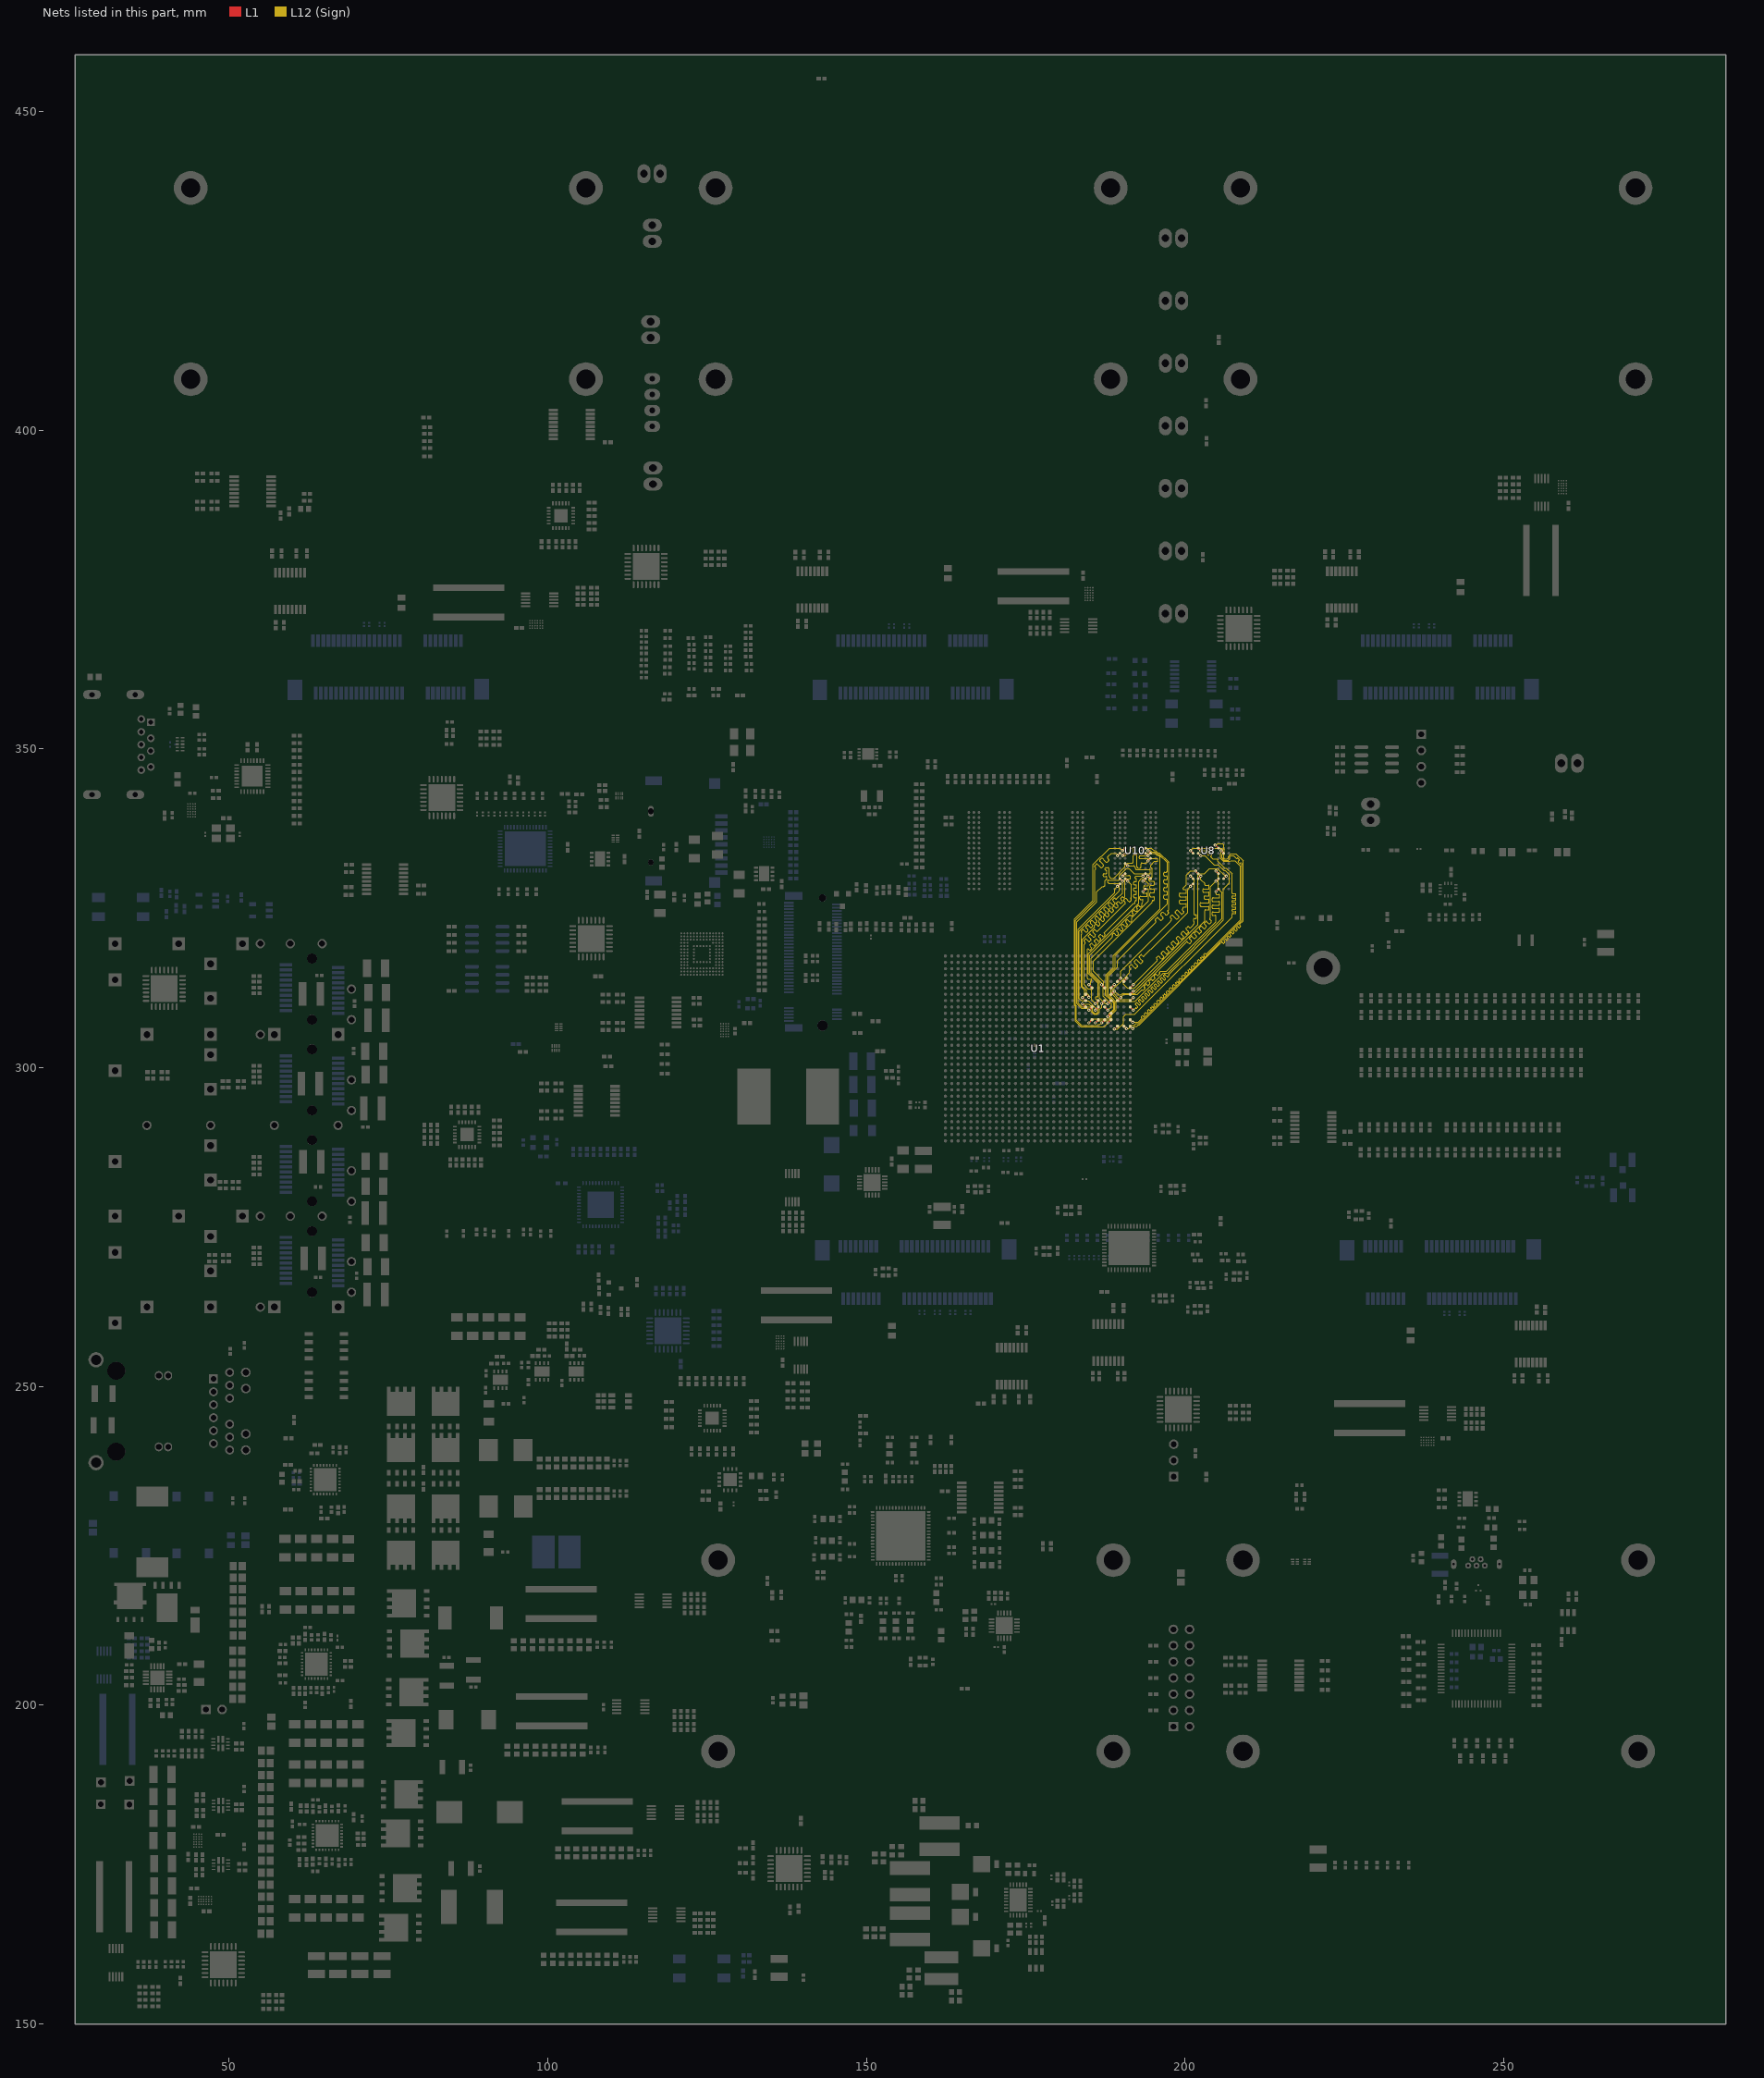
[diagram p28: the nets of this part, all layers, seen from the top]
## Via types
v1: diameter 0.5, hole 0.2, L1 to L16, tented both sides, 1267 vias
v2: diameter 0.5/0.35/0.35/0.35/0.35/0.35/0.35/0.35/0.35/0.35/0.35/0.35/0.35/0.35/0.35/0.5 (per signal layer), hole 0.15, L1 to L16, tented both sides, 463 vias
v3: diameter 0.5, hole 0.2, L1 to L16, 446 vias
v4: diameter 0.35/0/0.35 (per signal layer), hole 0.127, L1 to L3 (Sign), tented both sides, 347 vias
v5: diameter 0.5/0.35/0.35/0.35/0.35/0.35/0.35/0.35/0.35/0.35/0.35/0.35/0.35/0.35/0.35/0.5 (per signal layer), hole 0.2, L1 to L16, tented both sides, 244 vias
v6: diameter 0.8, hole 0.4, L1 to L16, tented both sides, 168 vias
v7: diameter 2.54, hole 1.02, L1 to L16, 113 vias
v8: diameter 1.4, hole 0.5, L1 to L16, tented both sides, 80 vias
v9: diameter 0.5/0/0.5 (per signal layer), hole 0.2, L14 (Sign) to L16, tented both sides, 62 vias
v10: diameter 0.35/0/0.35 (per signal layer), hole 0.127, L1 to L3 (Sign), 38 vias
v11: diameter 0.35, hole 0.127, L1 to L2 (GND), tented both sides, 36 vias
v12: diameter 0.4, hole 0.2, L1 to L16, 16 vias
v13: diameter 0.25, hole 0.2, L1 to L16, 16 vias
v14: diameter 0.35, hole 0.127, L1 to L16, tented both sides, 16 vias
v15: diameter 0.3, hole 0.2, L1 to L16, 15 vias
v16: diameter 0.45, hole 0.15, L1 to L16, 12 vias
v17: diameter 0.5/0.35/0.35/0.35/0.35/0.35/0.35/0.35/0.35/0.35/0.35/0.35/0.35/0.35/0.35/0.45 (per signal layer), hole 0.15, L1 to L16, tented both sides, 10 vias
v18: diameter 0.2/0/0.2 (per signal layer), hole 0.1, L1 to L3 (Sign), tented both sides, 9 vias
v19: diameter 0.4, hole 0.1, L1 to L16, 7 vias
v20: diameter 0.5, hole 0.2, L3 (Sign) to L6 (PWR/GND), tented both sides, 6 vias
v21: diameter 1.15, hole 1.15, L1 to L16, 5 vias
v22: diameter 1.65, hole 1.65, L1 to L16, 5 vias
v23: diameter 0.35/0/0.35 (per signal layer), hole 0.127, L14 (Sign) to L16, tented both sides, 5 vias
v24: diameter 0.5, hole 0.2, L11 (PWR/GND) to L14 (Sign), tented both sides, 4 vias
v25: diameter 0.2, hole 0.1, L1 to L16, 4 vias
v26: diameter 0.35, hole 0.127, L1 to L2 (GND), 2 vias
v27: diameter 0.4, hole 0.15, L1 to L16, 2 vias
v28: diameter 0.4, hole 0.2, L1 to L16, tented both sides, 2 vias
v29: diameter 0.5/0.35/0.35/0.35/0.35/0.35/0.35/0.35/0.35/0.35/0.35/0.35/0.35/0.35/0.35/0.5 (per signal layer), hole 0.15, L1 to L16, 2 vias
v30: diameter 0.35, hole 0.127, L3 (Sign) to L6 (PWR/GND), tented both sides, 2 vias
v31: diameter 0.5/0.35/0.35/0.35/0.35/0.35/0.35/0.35/0.35/0.35/0.35/0.35/0.35/0.35/0.35/0.5 (per signal layer), hole 0.2, L1 to L16, 1 vias
v32: diameter 0.35/0.35/0.35 (per signal layer), hole 0.127, L1 to L3 (Sign), tented both sides, 1 vias
v33: diameter 0.45/0/0.45 (per signal layer), hole 0.15, L1 to L3 (Sign), tented both sides, 1 vias
v34: diameter 0.45/0/0.45 (per signal layer), hole 0.2, L14 (Sign) to L16, tented both sides, 1 vias
v35: diameter 0.35, hole 0.127, L2 (GND) to L3 (Sign), 1 vias

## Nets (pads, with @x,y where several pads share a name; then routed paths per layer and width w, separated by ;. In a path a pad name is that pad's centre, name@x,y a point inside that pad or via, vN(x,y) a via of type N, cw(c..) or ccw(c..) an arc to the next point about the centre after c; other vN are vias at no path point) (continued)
DDR4_DQ3: U1.AK22 U8.H4 | length 45.5
  L1 w0.116: U1.AK22@191.397,309.539 v5(191.884,309.052) ; U8.H4@202.06,333.66 U8.H4@202.057,333.66 v2(202.461,333.257)
  L12 (Sign) w0.092: v5(191.884,309.052) 192.007,309.174 192.202,309.37 cw(c192.252,309.32) 192.301,309.37 ccw(c192.362,309.431) 192.423,309.37 192.546,309.492 ccw(c192.485,309.553) 192.546,309.615 192.496,309.664 192.22,309.94 cw(c192.282,310.001) 192.22,310.062 192.343,310.185 cw(c192.404,310.124) 192.465,310.185 192.741,309.909 192.778,309.872 ccw(c192.839,309.933) 192.9,309.872 193.023,309.994 ccw(c192.962,310.055) 193.023,310.117 192.986,310.154 192.71,310.43 cw(c192.771,310.491) 192.71,310.552 192.832,310.674 cw(c192.894,310.613) 192.955,310.674 193.231,310.398 193.268,310.361 ccw(c193.329,310.423) 193.39,310.361 193.512,310.484 ; 193.512,310.484 ccw(c193.451,310.545) 193.512,310.606 193.476,310.643 193.2,310.919 cw(c193.261,310.98) 193.2,311.042 193.322,311.164 cw(c193.383,311.103) 193.444,311.164 193.72,310.888 193.757,310.851 ccw(c193.818,310.912) 193.88,310.851 194.002,310.973 ccw(c193.941,311.035) 194.002,311.096 193.965,311.133 193.689,311.409 cw(c193.75,311.47) 193.689,311.531 193.812,311.654 cw(c193.873,311.592) 193.934,311.654 194.21,311.378 194.247,311.341 ccw(c194.308,311.402) 194.369,311.341 194.492,311.463 ccw(c194.43,311.524) 194.492,311.585 194.455,311.622 194.179,311.898 cw(c194.24,311.96) 194.179,312.021 194.301,312.143 cw(c194.362,312.082) 194.424,312.143 194.7,311.867 194.736,311.83 ccw(c194.798,311.891) 194.859,311.83 194.981,311.953 ccw(c194.92,312.014) 194.981,312.075 194.944,312.112 194.668,312.388 cw(c194.73,312.449) 194.668,312.51 194.791,312.633 cw(c194.852,312.572) 194.913,312.633 195.189,312.357 195.226,312.32 ccw(c195.287,312.381) 195.348,312.32 195.471,312.442 ccw(c195.41,312.503) 195.471,312.565 195.434,312.602 195.158,312.878 cw(c195.219,312.939) 195.158,313 195.28,313.122 cw(c195.342,313.061) 195.403,313.122 195.679,312.846 195.716,312.809 ccw(c195.777,312.871) 195.838,312.809 195.96,312.932 ccw(c195.899,312.993) 195.96,313.054 195.924,313.091 195.648,313.367 cw(c195.709,313.428) 195.648,313.49 195.77,313.612 cw(c195.831,313.551) 195.892,313.612 196.168,313.336 196.205,313.299 ccw(c196.266,313.36) 196.328,313.299 196.45,313.421 ccw(c196.389,313.483) 196.45,313.544 196.413,313.581 196.137,313.857 cw(c196.198,313.918) 196.137,313.979 196.26,314.102 cw(c196.321,314.04) 196.382,314.102 196.658,313.826 196.695,313.789 ccw(c196.756,313.85) 196.817,313.789 196.94,313.911 ccw(c196.878,313.972) 196.94,314.033 196.903,314.07 196.627,314.346 cw(c196.688,314.408) 196.627,314.469 196.749,314.591 cw(c196.81,314.53) 196.872,314.591 197.148,314.315 197.184,314.278 ccw(c197.246,314.339) 197.307,314.278 197.429,314.401 ccw(c197.368,314.462) 197.429,314.523 197.441,314.511 cw(c197.491,314.56) 197.442,314.609 200.84,318.007 206.029,323.196 206.029,328.039 206.974,328.984 206.974,330.276 206.291,330.959 206.109,330.959 205.245,331.822 204.579,331.822 203.145,333.257 v2(202.461,333.257)
DDR4_DQ4: U1.AK20 U8.H2 | length 45.7
  L1 w0.116: U1.AK20@191.397,307.539 v2(191.8,307.136) ; v2(205.653,334.064) U8.H2@206.057,333.66
  L12 (Sign) w0.092: v2(191.8,307.136) 192.653,307.136 192.776,307.258 193.02,307.503 193.204,307.687 ccw(c193.143,307.748) 193.204,307.809 193.147,307.866 cw(c193.208,307.927) 193.147,307.988 193.27,308.111 cw(c193.331,308.049) 193.392,308.111 193.449,308.054 ccw(c193.51,308.115) 193.571,308.054 193.694,308.176 ccw(c193.632,308.237) 193.694,308.299 193.637,308.355 cw(c193.698,308.417) 193.637,308.478 193.759,308.6 cw(c193.82,308.539) 193.882,308.6 193.938,308.543 ccw(c194,308.605) 194.061,308.543 194.183,308.666 ccw(c194.122,308.727) 194.183,308.788 194.126,308.845 cw(c194.188,308.906) 194.126,308.967 194.249,309.09 cw(c194.31,309.029) 194.371,309.09 194.428,309.033 ccw(c194.489,309.094) 194.55,309.033 194.673,309.155 ccw(c194.612,309.217) 194.673,309.278 194.616,309.335 cw(c194.677,309.396) 194.616,309.457 194.738,309.579 cw(c194.8,309.518) 194.861,309.579 194.918,309.523 ccw(c194.979,309.584) 195.04,309.523 195.162,309.645 ccw(c195.101,309.706) 195.162,309.767 195.106,309.824 cw(c195.167,309.885) 195.106,309.947 195.228,310.069 cw(c195.289,310.008) 195.35,310.069 195.407,310.012 ccw(c195.468,310.073) 195.53,310.012 195.652,310.135 ccw(c195.591,310.196) 195.652,310.257 195.595,310.314 cw(c195.656,310.375) 195.595,310.436 195.718,310.559 cw(c195.779,310.497) 195.84,310.559 195.897,310.502 ccw(c195.958,310.563) 196.019,310.502 196.142,310.624 ccw(c196.08,310.685) 196.142,310.747 196.085,310.803 cw(c196.146,310.865) 196.085,310.926 196.207,311.048 cw(c196.268,310.987) 196.33,311.048 196.386,310.991 ccw(c196.448,311.053) 196.509,310.991 196.631,311.114 ccw(c196.57,311.175) 196.631,311.236 196.574,311.293 cw(c196.636,311.354) 196.574,311.415 196.697,311.538 cw(c196.758,311.477) 196.819,311.538 196.876,311.481 ccw(c196.937,311.542) 196.998,311.481 197.121,311.603 ccw(c197.06,311.665) 197.121,311.726 197.064,311.783 cw(c197.125,311.844) 197.064,311.905 197.186,312.027 cw(c197.248,311.966) 197.309,312.027 197.366,311.971 ccw(c197.427,312.032) 197.488,311.971 197.61,312.093 ccw(c197.549,312.154) 197.61,312.215 197.554,312.272 cw(c197.615,312.333) 197.554,312.395 197.676,312.517 cw(c197.737,312.456) 197.798,312.517 197.855,312.46 ccw(c197.916,312.521) 197.978,312.46 198.1,312.583 ccw(c198.039,312.644) 198.1,312.705 198.043,312.762 cw(c198.104,312.823) 198.043,312.884 198.166,313.007 cw(c198.227,312.945) 198.288,313.007 198.345,312.95 ccw(c198.406,313.011) 198.467,312.95 198.59,313.072 ccw(c198.528,313.133) 198.59,313.195 198.533,313.251 cw(c198.594,313.313) 198.533,313.374 198.655,313.496 cw(c198.716,313.435) 198.778,313.496 198.834,313.439 ccw(c198.896,313.501) 198.957,313.439 199.079,313.562 ccw(c199.018,313.623) 199.079,313.684 199.022,313.741 cw(c199.084,313.802) 199.022,313.863 199.145,313.986 cw(c199.206,313.925) 199.267,313.986 199.324,313.929 ccw(c199.385,313.99) 199.446,313.929 199.569,314.051 ccw(c199.508,314.113) 199.569,314.174 199.512,314.231 cw(c199.573,314.292) 199.512,314.353 199.634,314.475 cw(c199.696,314.414) 199.757,314.475 199.814,314.419 ccw(c199.875,314.48) 199.936,314.419 200.058,314.541 ccw(c199.997,314.602) 200.058,314.663 200.002,314.72 cw(c200.063,314.781) 200.002,314.843 200.124,314.965 cw(c200.185,314.904) 200.246,314.965 200.303,314.908 ccw(c200.364,314.969) 200.426,314.908 200.548,315.031 ccw(c200.487,315.092) 200.548,315.153 200.491,315.21 cw(c200.552,315.271) 200.491,315.332 200.614,315.455 cw(c200.675,315.393) 200.736,315.455 200.793,315.398 ccw(c200.854,315.459) 200.915,315.398 201.038,315.52 ccw(c200.976,315.581) 201.038,315.643 200.981,315.699 cw(c201.042,315.761) 200.981,315.822 201.103,315.944 cw(c201.164,315.883) 201.226,315.944 201.282,315.887 ccw(c201.344,315.949) 201.405,315.887 201.527,316.01 ccw(c201.466,316.071) 201.527,316.132 201.47,316.189 cw(c201.532,316.25) 201.47,316.311 201.593,316.434 cw(c201.654,316.373) 201.715,316.434 201.772,316.377 ccw(c201.833,316.438) 201.894,316.377 202.017,316.499 ccw(c201.956,316.561) 202.017,316.622 201.96,316.679 cw(c202.021,316.74) 201.96,316.801 202.082,316.923 cw(c202.144,316.862) 202.205,316.923 202.262,316.867 ccw(c202.323,316.928) 202.384,316.867 202.506,316.989 ccw(c202.445,317.05) 202.506,317.111 202.45,317.168 cw(c202.511,317.229) 202.45,317.291 202.572,317.413 cw(c202.633,317.352) 202.694,317.413 202.751,317.356 ccw(c202.812,317.417) 202.874,317.356 202.996,317.479 ccw(c202.935,317.54) 202.996,317.601 202.939,317.658 cw(c203,317.719) 202.939,317.78 203.062,317.903 cw(c203.123,317.841) 203.184,317.903 203.241,317.846 ccw(c203.302,317.907) 203.363,317.846 206.44,320.923 208.715,323.198 208.715,331.594 207.797,332.511 207.141,332.511 207.019,332.39 205.992,332.39 205.558,332.823 205.558,333.572 205.653,333.667 v2(205.653,334.064)
DDR4_DQ5: U1.AJ19 U8.H5 | length 46.7
  L1 w0.116: U1.AJ19@190.397,306.539 v2(190.8,306.136) ; v2(200.853,334.064) U8.H5@201.257,333.66
  L12 (Sign) w0.092: v2(190.8,306.136) 191.125,306.136 191.618,306.629 192.016,306.629 192.331,306.944 192.733,306.944 208.907,323.118 208.907,332 208.812,332.095 ccw(c208.748,332.031) 208.685,332.095 cw(c208.622,332.158) 208.558,332.095 208.369,332.285 cw(c208.432,332.348) 208.369,332.411 208.432,332.474 208.501,332.543 ccw(c208.437,332.607) 208.501,332.67 208.311,332.86 ccw(c208.247,332.797) 208.184,332.86 208.179,332.854 cw(c208.115,332.918) 208.052,332.854 207.956,332.95 207.633,333.273 207.169,333.273 207.01,333.114 207.01,332.778 206.814,332.582 206.071,332.582 205.765,332.888 205.765,333.389 205.974,333.598 205.974,334.197 205.711,334.46 201.25,334.46 v2(200.853,334.064)
DDR4_DQ6: U1.AK19 U8.J3 | length 46
  L1 w0.116: U1.AK19@191.397,306.539 v2(191.8,306.136) ; v2(204.72,334.924) 204.793,334.924 U8.J3@205.257,334.46
  L12 (Sign) w0.092: v2(191.8,306.136) 192.001,306.337 192.19,306.526 192.431,306.526 192.657,306.752 192.812,306.752 205.603,319.542 205.733,319.672 cw(c205.794,319.611) 205.855,319.672 205.977,319.55 ccw(c206.038,319.612) 206.1,319.55 206.222,319.673 ccw(c206.161,319.734) 206.222,319.795 206.1,319.917 cw(c206.161,319.978) 206.1,320.04 206.222,320.162 cw(c206.284,320.101) 206.345,320.162 206.467,320.04 ccw(c206.528,320.101) 206.589,320.04 206.712,320.162 ccw(c206.65,320.224) 206.712,320.285 206.59,320.407 cw(c206.651,320.468) 206.59,320.529 206.712,320.652 cw(c206.773,320.59) 206.834,320.652 206.956,320.53 ccw(c207.018,320.591) 207.079,320.53 207.201,320.652 ccw(c207.14,320.713) 207.201,320.774 207.079,320.896 cw(c207.14,320.958) 207.079,321.019 207.202,321.141 cw(c207.263,321.08) 207.324,321.141 207.446,321.019 ccw(c207.507,321.08) 207.568,321.019 207.691,321.142 ccw(c207.63,321.203) 207.691,321.264 207.569,321.386 cw(c207.63,321.447) 207.569,321.508 207.691,321.631 cw(c207.752,321.57) 207.814,321.631 207.936,321.509 ccw(c207.997,321.57) 208.058,321.509 208.18,321.631 ccw(c208.119,321.692) 208.18,321.754 208.058,321.876 cw(c208.12,321.937) 208.058,321.998 208.181,322.12 cw(c208.242,322.059) 208.303,322.12 208.425,321.998 ccw(c208.486,322.06) 208.548,321.998 208.67,322.121 ccw(c208.609,322.182) 208.67,322.243 208.548,322.365 cw(c208.609,322.426) 208.548,322.488 208.732,322.671 208.976,322.916 209.099,323.038 209.099,332.447 208.004,333.542 207.166,333.542 206.785,333.161 206.785,332.947 206.612,332.774 206.151,332.774 206.057,332.868 206.057,333.409 206.166,333.518 206.166,334.276 206.084,334.359 206.084,334.949 205.863,335.17 205.159,335.17 204.85,334.861 204.787,334.924 v2(204.72,334.924)
DDR4_DQ7: U1.AH19 U8.J4 | length 47.5
  L1 w0.116: v5(188.909,306.052) U1.AH19@189.397,306.539 ; U8.J4@202.06,334.46 U8.J4@202.057,334.46 v2(202.461,334.057)
  L12 (Sign) w0.092: v5(188.909,306.052) 189.436,306.052 190.332,306.948 190.335,306.948 190.335,308.067 190.69,308.423 192.116,308.423 207.358,323.664 207.358,323.837 207.358,324.097 cw(c207.444,324.097) 207.444,324.183 207.873,324.183 ccw(c207.873,324.27) 207.96,324.27 207.96,324.443 ccw(c207.873,324.443) 207.873,324.53 207.444,324.53 cw(c207.444,324.616) 207.358,324.616 207.358,324.789 cw(c207.444,324.789) 207.444,324.876 207.873,324.876 ccw(c207.873,324.962) 207.96,324.962 207.96,325.135 ccw(c207.873,325.135) 207.873,325.222 207.444,325.222 cw(c207.444,325.309) 207.358,325.309 207.358,325.482 cw(c207.444,325.482) 207.444,325.568 207.873,325.568 ccw(c207.873,325.655) 207.96,325.655 207.96,325.828 ccw(c207.873,325.828) 207.873,325.914 207.444,325.914 cw(c207.444,326.001) 207.358,326.001 207.358,326.174 cw(c207.444,326.174) 207.444,326.261 207.873,326.261 ccw(c207.873,326.347) 207.96,326.347 207.96,326.52 ccw(c207.873,326.52) 207.873,326.607 207.444,326.607 cw(c207.444,326.693) 207.358,326.693 207.358,326.866 cw(c207.444,326.866) 207.444,326.953 207.873,326.953 ccw(c207.873,327.04) 207.96,327.04 207.96,327.213 ccw(c207.873,327.213) 207.873,327.299 207.444,327.299 cw(c207.444,327.386) 207.358,327.386 207.358,327.645 207.358,327.736 207.358,330.436 206.45,331.343 206.268,331.343 205.174,332.436 205.174,332.597 204.986,332.785 204.35,332.785 204.228,332.907 204.044,333.091 cw(c204.105,333.152) 204.044,333.213 204.211,333.38 ccw(c204.15,333.442) 204.211,333.503 204.089,333.625 ccw(c204.027,333.564) 203.966,333.625 203.738,333.397 cw(c203.677,333.458) 203.616,333.397 203.493,333.519 cw(c203.554,333.581) 203.493,333.642 203.643,333.791 ccw(c203.582,333.853) 203.643,333.914 203.52,334.036 ccw(c203.459,333.975) 203.398,334.036 203.275,333.913 cw(c203.248,333.939) 203.222,333.913 203.078,334.057 v2(202.461,334.057)
DDR4_DQ8: U1.AH23 U8.A3 | length 34
  L1 w0.116: U1.AH23@189.397,310.539 v5(189.884,311.027) ; v2(204.853,327.657) U8.A3@205.257,328.06
  L12 (Sign) w0.092: v5(189.884,311.027) 190.341,311.483 192.499,311.483 192.87,311.854 193.198,312.182 cw(c193.253,312.128) 193.307,312.182 ccw(c193.385,312.26) 193.462,312.182 193.696,312.415 ccw(c193.618,312.493) 193.696,312.571 193.641,312.625 193.589,312.677 cw(c193.667,312.755) 193.589,312.833 193.822,313.066 cw(c193.9,312.988) 193.978,313.066 194.03,313.014 194.084,312.959 ccw(c194.162,313.037) 194.239,312.959 194.473,313.192 ccw(c194.395,313.27) 194.473,313.348 194.418,313.402 194.366,313.454 cw(c194.444,313.532) 194.366,313.61 194.599,313.843 cw(c194.677,313.765) 194.755,313.843 194.806,313.791 194.861,313.736 ccw(c194.939,313.814) 195.016,313.736 195.25,313.969 ccw(c195.172,314.047) 195.249,314.125 195.195,314.179 195.143,314.231 cw(c195.221,314.309) 195.143,314.387 195.376,314.62 cw(c195.454,314.542) 195.531,314.62 195.583,314.568 195.638,314.513 ccw(c195.716,314.591) 195.793,314.513 196.026,314.746 ccw(c195.949,314.824) 196.026,314.902 cw(c196.081,314.956) 196.026,315.011 196.166,315.15 197.098,315.15 204.853,322.906 204.853,323.497 204.853,323.784 ccw(c204.744,323.784) 204.744,323.894 204.388,323.894 cw(c204.388,324.004) 204.278,324.004 204.278,324.334 cw(c204.388,324.334) 204.388,324.444 204.853,324.444 205.319,324.444 ccw(c205.319,324.554) 205.429,324.554 205.429,324.883 ccw(c205.319,324.883) 205.319,324.993 204.853,324.993 204.388,324.993 cw(c204.388,325.103) 204.278,325.103 204.278,325.433 cw(c204.388,325.433) 204.388,325.543 204.853,325.543 205.319,325.543 ccw(c205.319,325.652) 205.429,325.652 205.429,325.982 ccw(c205.319,325.982) 205.319,326.092 204.853,326.092 204.388,326.092 cw(c204.388,326.202) 204.278,326.202 204.278,326.531 cw(c204.388,326.531) 204.388,326.641 204.853,326.641 205.319,326.641 ccw(c205.319,326.751) 205.429,326.751 205.429,327.081 ccw(c205.319,327.081) 205.319,327.191 204.963,327.191 cw(c204.963,327.301) 204.853,327.301 204.853,327.465 v2(204.853,327.657)
DDR4_DQ9: U1.AK23 U8.B5 | length 31.1
  L1 w0.116: U1.AK23@191.397,310.539 v5(191.884,311.027) ; v2(200.853,328.457) U8.B5@201.257,328.86
  L12 (Sign) w0.092: v5(191.884,311.027) 191.55,310.693 189.73,310.693 188.579,311.844 188.579,312.172 188.767,312.36 188.767,312.363 190.563,314.16 191.318,314.914 191.318,315.295 191.434,315.412 ccw(c191.357,315.489) 191.434,315.567 191.251,315.751 cw(c191.328,315.829) 191.251,315.906 191.484,316.139 cw(c191.562,316.062) 191.639,316.139 191.901,315.878 192.162,315.617 ccw(c192.24,315.694) 192.317,315.617 192.55,315.85 ccw(c192.473,315.927) 192.55,316.005 192.289,316.266 192.028,316.528 cw(c192.105,316.605) 192.028,316.683 192.261,316.916 cw(c192.339,316.839) 192.416,316.916 192.678,316.655 192.939,316.394 ccw(c193.017,316.471) 193.094,316.394 193.327,316.627 ccw(c193.25,316.704) 193.327,316.782 193.066,317.043 192.805,317.305 cw(c192.882,317.382) 192.805,317.46 193.038,317.693 cw(c193.115,317.616) 193.193,317.693 193.377,317.51 ccw(c193.455,317.587) 193.532,317.51 195.682,319.659 200.408,324.385 200.408,328.011 v2(200.853,328.457)
DDR4_DQ10: U1.AG24 U8.C3 | length 33.1
  L1 w0.116: U1.AG24@188.397,311.539 188.4,311.539 v5(188.9,312.039) ; v2(204.853,329.257) U8.C3@205.257,329.66
  L12 (Sign) w0.092: v5(188.9,312.039) 189.522,311.417 189.942,311.417 190.201,311.675 192.16,311.675 198.535,318.05 200.232,319.747 cw(c200.31,319.669) 200.387,319.747 200.614,319.52 ccw(c200.692,319.597) 200.77,319.52 201.003,319.753 ccw(c200.925,319.83) 201.003,319.908 200.698,320.213 cw(c200.776,320.291) 200.698,320.368 200.931,320.602 cw(c201.009,320.524) 201.086,320.602 201.391,320.297 ccw(c201.469,320.374) 201.547,320.297 201.78,320.53 ccw(c201.702,320.607) 201.78,320.685 201.475,320.99 cw(c201.553,321.068) 201.475,321.145 201.708,321.379 cw(c201.786,321.301) 201.863,321.379 202.168,321.074 ccw(c202.246,321.151) 202.324,321.074 202.557,321.307 ccw(c202.479,321.384) 202.557,321.462 202.252,321.767 cw(c202.33,321.845) 202.252,321.922 202.485,322.155 cw(c202.563,322.078) 202.64,322.155 202.945,321.85 ccw(c203.023,321.928) 203.101,321.85 203.334,322.084 ccw(c203.256,322.161) 203.334,322.239 203.029,322.544 cw(c203.107,322.622) 203.029,322.699 203.262,322.932 cw(c203.34,322.855) 203.417,322.932 203.722,322.627 ccw(c203.8,322.705) 203.878,322.627 204.111,322.861 ccw(c204.033,322.938) 204.111,323.016 203.884,323.243 cw(c203.961,323.321) 203.884,323.399 204,323.515 204,328.404 v2(204.853,329.257)
DDR4_DQ11: U1.AK24 U8.C4 | length 31.4
  L1 w0.116: U1.AK24@191.397,311.539 v5(191.884,312.027) ; U8.C4@202.057,329.66 v2(202.461,330.064)
  L12 (Sign) w0.092: v5(191.884,312.027) 192.07,312.027 203.086,323.043 203.086,324.396 203.086,324.672 cw(c203.196,324.672) 203.196,324.782 203.687,324.782 ccw(c203.687,324.892) 203.797,324.892 203.797,325.221 ccw(c203.687,325.221) 203.687,325.331 203.086,325.331 202.484,325.331 cw(c202.484,325.441) 202.374,325.441 202.374,325.771 cw(c202.484,325.771) 202.484,325.88 203.086,325.88 203.687,325.88 ccw(c203.687,325.99) 203.797,325.99 203.797,326.32 ccw(c203.687,326.32) 203.687,326.43 203.086,326.43 cw(c203.086,326.501) 203.015,326.501 203.015,326.908 cw(c203.086,326.908) 203.086,326.979 203.687,326.979 ccw(c203.687,327.089) 203.797,327.089 203.797,327.419 ccw(c203.687,327.419) 203.687,327.529 203.086,327.529 202.897,327.529 cw(c202.897,327.639) 202.787,327.639 202.787,327.968 cw(c202.897,327.968) 202.897,328.078 203.086,328.078 203.687,328.078 ccw(c203.687,328.188) 203.797,328.188 203.797,328.518 ccw(c203.687,328.518) 203.687,328.627 203.196,328.627 cw(c203.196,328.737) 203.086,328.737 203.086,328.902 202.461,329.527 v2(202.461,330.064)
DDR4_DQ12: U1.AJ26 U8.C2 | length 31.5
  L1 w0.116: U1.AJ26@190.397,313.539 v5(190.884,314.027) ; U8.C2@206.057,329.66 v2(206.461,330.064)
  L12 (Sign) w0.092: v5(190.884,314.027) 190.375,313.517 190.375,313.082 190.943,312.514 192.097,312.514 202.026,322.443 202.026,330.171 202.283,330.429 203.035,330.429 203.867,331.26 205.081,331.26 206.277,330.064 v2(206.461,330.064)
DDR4_DQ13: U1.AK25 U8.C5 | length 31.5
  L1 w0.116: U1.AK25@191.397,312.539 v5(191.884,313.027) ; v2(200.853,330.064) U8.C5@201.257,329.66
  L12 (Sign) w0.092: v5(191.884,313.027) 195.527,316.67 195.644,316.787 ccw(c195.566,316.864) 195.644,316.942 195.508,317.078 cw(c195.586,317.155) 195.508,317.233 195.741,317.466 cw(c195.819,317.388) 195.897,317.466 196.11,317.253 196.259,317.103 ccw(c196.337,317.181) 196.415,317.103 196.648,317.336 ccw(c196.57,317.414) 196.648,317.492 196.499,317.641 196.285,317.855 cw(c196.363,317.932) 196.285,318.01 196.518,318.243 cw(c196.596,318.165) 196.674,318.243 196.887,318.03 197.036,317.88 ccw(c197.114,317.958) 197.192,317.88 197.425,318.113 ccw(c197.347,318.191) 197.425,318.269 197.276,318.418 197.062,318.632 cw(c197.14,318.709) 197.062,318.787 197.295,319.02 cw(c197.373,318.942) 197.451,319.02 197.664,318.807 197.813,318.657 ccw(c197.891,318.735) 197.969,318.657 198.202,318.89 ccw(c198.124,318.968) 198.202,319.046 198.053,319.195 197.839,319.409 cw(c197.917,319.486) 197.839,319.564 198.072,319.797 cw(c198.15,319.719) 198.228,319.797 198.441,319.584 198.59,319.434 ccw(c198.668,319.512) 198.746,319.434 198.979,319.667 ccw(c198.901,319.745) 198.979,319.823 198.83,319.972 198.616,320.185 cw(c198.694,320.263) 198.616,320.341 198.849,320.574 cw(c198.927,320.496) 199.005,320.574 199.218,320.361 199.367,320.211 ccw(c199.445,320.289) 199.523,320.211 199.756,320.444 ccw(c199.678,320.522) 199.756,320.6 199.607,320.749 199.393,320.962 cw(c199.471,321.04) 199.393,321.118 199.626,321.351 cw(c199.704,321.273) 199.782,321.351 199.995,321.138 200.144,320.988 ccw(c200.222,321.066) 200.3,320.988 200.533,321.221 ccw(c200.455,321.299) 200.533,321.377 200.384,321.526 200.17,321.739 cw(c200.248,321.817) 200.17,321.895 200.403,322.128 cw(c200.481,322.05) 200.559,322.128 200.694,321.992 ccw(c200.772,322.07) 200.85,321.992 201.136,322.278 201.46,322.603 201.46,322.877 cw(c201.46,322.967) 201.37,322.967 201.37,323.337 cw(c201.46,323.337) 201.46,323.427 201.692,323.427 ccw(c201.692,323.537) 201.802,323.537 201.802,323.866 ccw(c201.692,323.866) 201.692,323.976 201.57,323.976 cw(c201.57,324.086) 201.46,324.086 201.46,326.643 201.46,329.457 v2(200.853,330.064)
DDR4_DQ14: U1.AG25 U8.D3 | length 34.1
  L1 w0.116: U1.AG25@188.397,312.539 188.403,312.539 188.9,313.036 v5(188.9,313.068) ; v2(204.853,330.864) U8.D3@205.257,330.46
  L12 (Sign) w0.092: v5(188.9,313.068) 188.359,312.527 188.359,311.737 189.631,310.465 192.16,310.465 196.554,314.858 197.279,314.858 205.811,323.391 205.811,327.506 205.245,328.072 205.245,330.472 v2(204.853,330.864)
DDR4_DQ15: U1.AH26 U8.D4 | length 32
  L1 w0.116: U1.AH26@189.397,313.539 v5(189.884,314.027) ; v2(201.653,330.864) U8.D4@202.057,330.46
  L12 (Sign) w0.092: v5(189.884,314.027) 189.884,315.174 197.57,322.859 197.878,323.167 ccw(c197.8,323.245) 197.878,323.322 197.67,323.53 cw(c197.748,323.607) 197.67,323.685 197.903,323.918 cw(c197.981,323.841) 198.059,323.918 198.344,323.633 198.629,323.348 ccw(c198.707,323.426) 198.784,323.348 199.017,323.581 ccw(c198.94,323.659) 199.017,323.737 198.732,324.022 198.447,324.307 cw(c198.525,324.384) 198.447,324.462 198.68,324.695 cw(c198.758,324.618) 198.836,324.695 199.121,324.41 199.406,324.125 ccw(c199.484,324.203) 199.561,324.125 199.794,324.358 ccw(c199.717,324.436) 199.794,324.513 199.587,324.721 cw(c199.665,324.799) 199.587,324.876 199.704,324.993 199.704,325.166 cw(c199.736,325.166) 199.736,325.199 200.106,325.199 ccw(c200.106,325.309) 200.216,325.309 200.216,325.638 ccw(c200.106,325.638) 200.106,325.748 199.704,325.748 199.22,325.748 cw(c199.22,325.858) 199.11,325.858 199.11,326.188 cw(c199.22,326.188) 199.22,326.298 199.704,326.298 200.106,326.298 ccw(c200.106,326.408) 200.216,326.408 200.216,326.737 ccw(c200.106,326.737) 200.106,326.847 199.704,326.847 199.22,326.847 cw(c199.22,326.957) 199.11,326.957 199.11,327.287 cw(c199.22,327.287) 199.22,327.397 199.704,327.397 200.106,327.397 ccw(c200.106,327.506) 200.216,327.506 200.216,327.836 ccw(c200.106,327.836) 200.106,327.946 199.813,327.946 cw(c199.813,328.056) 199.704,328.056 199.704,328.221 200.207,328.724 200.207,330.233 200.838,330.864 v2(201.653,330.864)
DDR4_DQ16: U1.AD22 U10.G2 | length 41.3
  L1 w0.116: v5(184.909,309.052) U1.AD22@185.397,309.539 ; v2(194.193,332.457) U10.G2@194.597,332.86
  L12 (Sign) w0.092: v5(184.909,309.052) 184.617,309.344 183.735,309.344 183.013,310.066 183.013,322.87 186.169,326.026 186.169,327.624 186.993,328.447 187.173,328.447 ccw(c187.173,328.743) 187.469,328.743 187.469,329.334 cw(c187.618,329.334) 187.618,329.484 187.621,329.484 ccw(c187.621,329.633) 187.77,329.633 187.77,329.833 ccw(c187.621,329.833) 187.621,329.982 187.469,329.982 187.317,329.982 cw(c187.317,330.132) 187.167,330.132 187.167,330.331 cw(c187.317,330.331) 187.317,330.481 187.469,330.481 187.621,330.481 ccw(c187.621,330.63) 187.77,330.63 187.77,330.83 ccw(c187.621,330.83) 187.621,330.979 187.618,330.979 cw(c187.618,331.129) 187.469,331.129 187.469,331.229 cw(c187.621,331.229) 187.621,331.381 187.897,331.381 cw(c187.897,331.179) 188.098,331.179 188.098,330.098 ccw(c188.48,330.098) 188.48,329.717 188.789,329.717 190.597,331.525 190.597,331.767 190.966,332.136 191.186,332.136 191.27,332.136 191.69,332.136 ccw(c191.69,332.316) 191.87,332.316 191.87,333.26 cw(c192.05,333.26) 192.05,333.44 192.29,333.44 cw(c192.29,333.26) 192.47,333.26 192.47,332.136 192.47,331.511 ccw(c192.65,331.511) 192.65,331.331 192.89,331.331 ccw(c192.89,331.511) 193.07,331.511 193.07,331.956 cw(c193.25,331.956) 193.25,332.136 193.37,332.136 193.872,332.136 v2(194.193,332.457)
DDR4_DQ17: U1.AE22 U10.F4 | length 40.2
  L1 w0.116: v5(185.909,309.052) U1.AE22@186.397,309.539 ; U10.F4@190.597,332.06 v2(191,331.657)
  L12 (Sign) w0.092: v5(185.909,309.052) 186.095,309.238 184.856,310.477 183.789,310.477 183.397,310.869 183.397,321.424 189.714,327.741 189.714,328.59 189.714,328.879 ccw(c189.64,328.879) 189.64,328.953 188.047,328.953 cw(c188.047,329.103) 187.897,329.103 187.897,329.302 cw(c188.047,329.302) 188.047,329.452 189.564,329.452 ccw(c189.564,329.601) 189.714,329.601 189.714,329.701 189.714,330.125 190.805,331.216 191.249,331.216 192.024,330.441 194.404,330.441 ccw(c194.404,330.581) 194.543,330.581 194.543,330.955 ccw(c194.409,330.955) 194.409,331.089 192.497,331.089 cw(c192.497,331.457) 192.129,331.457 ccw(c191.929,331.457) 191.929,331.657 v2(191,331.657)
DDR4_DQ18: U1.AF22 U10.H3 | length 39.4
  L1 w0.116: U1.AF22@187.397,309.539 v5(187.884,309.052) ; U10.H3@193.797,333.66 v2(194.2,333.257)
  L12 (Sign) w0.092: v5(187.884,309.052) 187.906,309.052 188.428,309.573 188.428,309.987 188.042,310.373 188.013,310.373 187.165,311.221 187.165,312.828 187.23,312.894 187.23,313.51 185.622,315.118 185.622,316.741 194.831,325.95 194.831,326.1 cw(c194.981,326.1) 194.981,326.25 195.031,326.25 ccw(c195.031,326.4) 195.181,326.4 195.181,326.7 ccw(c195.031,326.7) 195.031,326.85 194.831,326.85 194.605,326.85 cw(c194.605,327) 194.455,327 194.455,327.3 cw(c194.605,327.3) 194.605,327.45 194.831,327.45 195.031,327.45 ccw(c195.031,327.601) 195.181,327.601 195.181,327.901 ccw(c195.031,327.901) 195.031,328.051 194.831,328.051 194.605,328.051 cw(c194.605,328.201) 194.455,328.201 194.455,328.501 cw(c194.605,328.501) 194.605,328.651 194.831,328.651 195.031,328.651 ccw(c195.031,328.801) 195.181,328.801 195.181,329.101 ccw(c195.031,329.101) 195.031,329.251 194.831,329.251 194.51,329.251 cw(c194.51,329.401) 194.36,329.401 194.36,329.701 cw(c194.51,329.701) 194.51,329.851 194.685,329.851 ccw(c194.685,329.997) 194.831,329.997 194.831,331.219 194.591,331.459 194.591,331.753 195.229,332.39 195.598,332.39 ccw(c195.598,332.524) 195.732,332.524 195.732,332.699 ccw(c195.616,332.699) 195.616,332.816 192.918,332.816 cw(c192.918,332.947) 192.788,332.947 192.788,333.081 cw(c192.955,333.081) 192.955,333.248 194.2,333.248 v2(194.2,333.257)
DDR4_DQ19: U1.AG21 U10.H4 | length 38.3
  L1 w0.116: v5(187.909,308.052) U1.AG21@188.397,308.539 ; v2(190.193,333.257) U10.H4@190.597,333.66
  L12 (Sign) w0.092: v5(187.909,308.052) 188.038,308.181 188.038,308.211 188.094,308.266 188.094,308.513 188.812,309.231 188.812,310.147 188.201,310.757 188.172,310.757 187.549,311.38 187.549,312.669 187.614,312.735 187.614,314.572 188.785,315.743 188.785,317.598 196.098,324.911 196.098,333.027 195.793,333.332 195.535,333.332 195.206,333.66 193.332,333.66 192.102,333.66 cw(c192.102,333.81) 191.952,333.81 191.952,334.282 ccw(c191.802,334.282) 191.802,334.432 191.502,334.432 ccw(c191.502,334.282) 191.352,334.282 191.352,333.81 cw(c191.202,333.81) 191.202,333.66 191.052,333.66 190.649,333.257 v2(190.193,333.257)
DDR4_DQ20: U1.AD20 U10.H2 | length 41.2
  L1 w0.116: v1(184.909,307.052) U1.AD20@185.397,307.539 ; v2(194.193,334.064) U10.H2@194.597,333.66
  L12 (Sign) w0.092: v1(184.909,307.052) 185.513,307.656 188.098,307.656 188.254,307.812 188.254,308.155 188.256,308.155 188.286,308.185 188.286,308.434 189.004,309.151 189.004,310.226 188.281,310.949 188.251,310.949 187.741,311.459 187.741,312.59 187.806,312.655 187.806,314.492 189.04,315.725 189.04,317.58 197.208,325.749 197.208,325.831 197.208,326.337 ccw(c197.058,326.337) 197.058,326.487 196.817,326.487 cw(c196.817,326.637) 196.667,326.637 196.667,326.937 cw(c196.817,326.937) 196.817,327.087 197.058,327.087 ccw(c197.058,327.237) 197.208,327.237 197.208,327.537 ccw(c197.058,327.537) 197.058,327.687 196.817,327.687 cw(c196.817,327.837) 196.667,327.837 196.667,328.137 cw(c196.817,328.137) 196.817,328.287 197.058,328.287 ccw(c197.058,328.437) 197.208,328.437 197.208,328.737 ccw(c197.058,328.737) 197.058,328.887 196.817,328.887 cw(c196.817,329.038) 196.667,329.038 196.667,329.338 cw(c196.817,329.338) 196.817,329.488 197.058,329.488 ccw(c197.058,329.638) 197.208,329.638 197.208,329.938 ccw(c197.058,329.938) 197.058,330.088 196.817,330.088 cw(c196.817,330.238) 196.667,330.238 196.667,330.538 cw(c196.817,330.538) 196.817,330.688 197.058,330.688 ccw(c197.058,330.838) 197.208,330.838 197.208,331.288 197.208,331.888 197.208,332.189 195.873,333.524 195.629,333.524 195.3,333.852 194.746,333.852 194.534,334.064 v2(194.193,334.064)
DDR4_DQ21: U1.AF20 U10.H5 | length 39.1
  L1 w0.116: v5(186.909,307.052) U1.AF20@187.397,307.539 ; v2(189.393,333.257) U10.H5@189.797,333.66
  L12 (Sign) w0.092: v5(186.909,307.052) 186.656,306.799 186.385,306.799 186.24,306.654 183.747,306.654 182.982,307.42 182.982,309.705 182.821,309.866 182.821,323.125 185.852,326.156 185.852,331.058 185.958,331.164 ccw(c185.852,331.27) 185.958,331.376 185.83,331.504 cw(c185.936,331.61) 185.83,331.716 186.042,331.928 cw(c186.148,331.822) 186.254,331.928 186.488,331.694 186.762,331.421 ccw(c186.868,331.527) 186.974,331.421 187.186,331.633 ccw(c187.08,331.739) 187.186,331.845 186.913,332.119 186.639,332.392 cw(c186.746,332.498) 186.639,332.604 186.852,332.816 cw(c186.958,332.71) 187.064,332.816 187.337,332.543 187.611,332.27 ccw(c187.717,332.376) 187.823,332.27 188.035,332.482 ccw(c187.929,332.588) 188.035,332.694 187.868,332.861 cw(c187.974,332.967) 187.868,333.073 188.058,333.264 188.455,333.66 189.195,333.66 189.393,333.462 v2(189.393,333.257)
DDR4_DQ22: U1.AE20 U10.J3 | length 41
  L1 w0.116: v5(185.909,307.052) U1.AE20@186.397,307.539 ; v2(193.393,334.057) U10.J3@193.797,334.46
  L12 (Sign) w0.092: v5(185.909,307.052) 186.261,307.404 188.117,307.404 188.478,307.765 188.478,308.354 189.196,309.072 189.196,310.306 188.361,311.141 188.331,311.141 187.933,311.539 187.933,312.51 187.998,312.576 187.998,314.412 189.397,315.811 189.397,316.791 193.735,321.129 195.406,322.799 ccw(c195.299,322.905) 195.406,323.011 195.343,323.074 cw(c195.449,323.18) 195.343,323.286 195.555,323.498 cw(c195.661,323.392) 195.767,323.498 195.936,323.33 196.105,323.161 ccw(c196.211,323.267) 196.317,323.161 196.529,323.373 ccw(c196.423,323.479) 196.529,323.586 196.36,323.754 196.192,323.923 cw(c196.298,324.029) 196.192,324.135 196.404,324.347 cw(c196.51,324.241) 196.616,324.347 196.785,324.179 196.954,324.01 ccw(c197.06,324.116) 197.166,324.01 197.378,324.222 ccw(c197.272,324.328) 197.378,324.434 197.315,324.497 cw(c197.422,324.603) 197.315,324.709 197.421,324.815 197.421,332.246 195.952,333.716 195.708,333.716 195.375,334.049 195.122,334.049 194.711,334.46 193.797,334.46 v2(193.393,334.057)
DDR4_DQ23: U1.AG20 U10.J4 | length 38.7
  L1 w0.116: v5(187.909,307.052) U1.AG20@188.397,307.539 ; v2(190.193,334.057) U10.J4@190.597,334.46
  L12 (Sign) w0.092: v5(187.909,307.052) 187.308,306.451 183.642,306.451 183.23,306.863 183.23,306.899 182.79,307.34 182.79,309.626 182.629,309.786 182.629,323.307 185.59,326.267 185.59,331.501 185.587,331.503 185.587,331.717 185.59,331.72 185.59,331.906 188.144,334.46 189.789,334.46 v2(190.193,334.057)
DDR4_DQ24: U1.AG23 U10.A3 | length 27.3
  L1 w0.116: v5(187.909,310.052) U1.AG23@188.397,310.539 ; v2(193.393,327.657) U10.A3@193.797,328.06
  L12 (Sign) w0.092: v5(187.909,310.052) 187.431,310.052 186.578,310.905 186.578,313.348 185.046,314.88 185.046,317.652 191.062,323.669 191.295,323.902 cw(c191.368,323.829) 191.44,323.902 ccw(c191.58,324.043) 191.721,323.902 191.792,323.973 ccw(c191.651,324.114) 191.792,324.255 191.72,324.326 cw(c191.817,324.423) 191.72,324.519 191.88,324.679 cw(c191.976,324.583) 192.073,324.679 192.145,324.607 ccw(c192.286,324.748) 192.427,324.607 192.497,324.678 ccw(c192.356,324.819) 192.497,324.96 192.425,325.032 cw(c192.522,325.128) 192.425,325.224 192.585,325.384 cw(c192.681,325.288) 192.778,325.384 192.85,325.312 ccw(c192.991,325.453) 193.132,325.312 193.203,325.382 ccw(c193.062,325.523) 193.203,325.664 cw(c193.275,325.737) 193.203,325.809 193.307,325.913 193.393,325.999 193.393,326.263 193.393,326.311 ccw(c193.293,326.311) 193.293,326.41 193.012,326.41 cw(c193.012,326.51) 192.912,326.51 192.912,326.809 cw(c193.012,326.809) 193.012,326.909 193.393,326.909 193.955,326.909 ccw(c193.955,327.009) 194.055,327.009 194.055,327.308 ccw(c193.955,327.308) 193.955,327.408 193.493,327.408 cw(c193.493,327.507) 193.393,327.507 v2(193.393,327.657)
DDR4_DQ25: U1.AF23 U10.B5 | length 28.1
  L1 w0.116: v5(186.909,310.052) U1.AF23@187.397,310.539 ; v2(189.393,328.457) U10.B5@189.797,328.86
  L12 (Sign) w0.092: v5(186.909,310.052) 186.909,309.481 186.588,309.16 186.588,308.731 186.233,308.375 185.675,308.375 185.242,308.808 185.242,309.33 185.033,309.539 183.837,309.539 183.205,310.171 183.205,321.724 188.981,327.5 188.981,328.045 v2(189.393,328.457)
DDR4_DQ26: U1.AF25 U10.C3 | length 27.7
  L1 w0.116: v5(186.909,313.027) U1.AF25@187.397,312.539 ; v2(193.393,329.257) U10.C3@193.797,329.66
  L12 (Sign) w0.092: v5(186.909,313.027) 186.909,313.287 185.238,314.959 185.238,317.146 188.243,320.151 188.606,320.514 ccw(c188.534,320.587) 188.606,320.659 188.609,320.656 ; 188.61,320.655 cw(c188.751,320.796) 188.61,320.937 188.68,321.008 cw(c188.821,320.867) 188.962,321.008 189.031,320.939 189.145,320.825 ccw(c189.286,320.966) 189.427,320.825 189.497,320.895 ccw(c189.356,321.036) 189.497,321.177 189.383,321.292 189.315,321.36 cw(c189.456,321.501) 189.315,321.642 189.385,321.713 cw(c189.526,321.572) 189.667,321.713 189.736,321.644 189.85,321.53 ccw(c189.991,321.671) 190.132,321.53 190.203,321.6 ccw(c190.062,321.742) 190.203,321.883 190.088,321.997 190.02,322.065 cw(c190.161,322.206) 190.02,322.347 190.09,322.418 cw(c190.231,322.277) 190.372,322.418 190.441,322.349 190.555,322.235 ccw(c190.696,322.376) 190.837,322.235 190.908,322.306 ccw(c190.767,322.447) 190.908,322.588 190.794,322.702 190.725,322.771 cw(c190.866,322.912) 190.725,323.053 190.795,323.123 cw(c190.936,322.982) 191.077,323.123 191.146,323.054 191.264,322.937 ccw(c191.405,323.078) 191.546,322.937 191.616,323.007 ccw(c191.475,323.148) 191.616,323.289 cw(c191.734,323.407) 191.616,323.525 191.675,323.583 194.246,326.155 194.246,327.8 194.246,327.949 ccw(c194.147,327.949) 194.147,328.049 193.612,328.049 cw(c193.612,328.149) 193.512,328.149 193.512,328.448 cw(c193.612,328.448) 193.612,328.548 194.147,328.548 ccw(c194.147,328.647) 194.246,328.647 194.246,328.879 193.84,329.286 193.422,329.286 v2(193.393,329.257)
DDR4_DQ27: U1.AE23 U10.C4 | length 29.6
  L1 w0.116: v5(185.909,310.052) U1.AE23@186.397,310.539 ; U10.C4@190.597,329.66 v2(191,329.257)
  L12 (Sign) w0.092: v5(185.909,310.052) 185.331,310.63 185.331,312.165 185.073,312.423 184.788,312.423 184.204,313.006 184.204,319.358 184.239,319.392 184.309,319.463 ccw(c184.204,319.569) 184.309,319.674 184.158,319.826 cw(c184.264,319.931) 184.158,320.037 184.299,320.178 cw(c184.405,320.072) 184.511,320.178 184.768,319.921 184.857,319.832 ccw(c184.963,319.938) 185.069,319.832 185.21,319.973 ccw(c185.104,320.079) 185.21,320.184 185.12,320.274 184.838,320.556 cw(c184.943,320.662) 184.838,320.768 184.979,320.909 cw(c185.084,320.803) 185.19,320.909 185.473,320.626 185.562,320.537 ccw(c185.668,320.643) 185.774,320.537 185.915,320.678 ccw(c185.809,320.784) 185.915,320.89 185.825,320.979 185.543,321.262 cw(c185.649,321.367) 185.543,321.473 185.684,321.614 cw(c185.79,321.508) 185.895,321.614 186.072,321.437 ccw(c186.178,321.543) 186.284,321.437 186.938,322.091 190.525,325.679 190.592,325.746 ccw(c190.487,325.851) 190.592,325.957 190.405,326.145 cw(c190.511,326.251) 190.405,326.356 190.546,326.497 cw(c190.652,326.392) 190.757,326.497 191.051,326.204 191.183,326.072 ccw(c191.289,326.177) 191.395,326.072 191.536,326.213 ccw(c191.43,326.318) 191.536,326.424 191.509,326.451 cw(c191.615,326.557) 191.509,326.662 191.579,326.733 191.579,328.677 v2(191,329.257)
DDR4_DQ28: U1.AC22 U10.C2 | length 31.5
  L1 w0.116: v1(183.909,310.027) U1.AC22@184.397,309.539 ; v2(194.193,330.064) U10.C2@194.597,329.66
  L12 (Sign) w0.092: v1(183.909,310.027) 184.909,310.027 185.481,309.455 185.481,308.84 185.754,308.567 186.127,308.567 186.386,308.826 186.386,310.236 186.386,310.578 ccw(c186.286,310.578) 186.286,310.678 186.128,310.678 cw(c186.128,310.778) 186.028,310.778 186.028,311.077 cw(c186.128,311.077) 186.128,311.177 186.286,311.177 ccw(c186.286,311.277) 186.386,311.277 186.386,311.675 186.386,311.925 186.386,313.268 184.854,314.8 184.854,317.924 192.72,325.791 192.72,329.25 193.16,329.69 193.819,329.69 v2(194.193,330.064)
DDR4_DQ29: U1.AC23 U10.C5 | length 31.3
  L1 w0.116: v1(183.909,311.027) U1.AC23@184.397,310.539 ; U10.C5@189.797,329.66 v2(190.2,329.257)
  L12 (Sign) w0.092: v1(183.909,311.027) 184.266,311.383 184.266,312.156 183.72,312.702 183.72,320.943 183.79,321.014 ccw(c183.684,321.119) 183.79,321.225 183.746,321.269 cw(c183.852,321.375) 183.746,321.481 183.887,321.622 cw(c183.993,321.516) 184.099,321.622 184.249,321.472 184.398,321.322 ccw(c184.504,321.428) 184.61,321.322 184.751,321.463 ccw(c184.645,321.569) 184.751,321.675 184.601,321.825 184.451,321.974 cw(c184.557,322.08) 184.451,322.186 184.592,322.327 cw(c184.698,322.221) 184.804,322.327 184.954,322.177 185.103,322.028 ccw(c185.209,322.133) 185.315,322.028 185.456,322.169 ccw(c185.35,322.274) 185.456,322.38 185.306,322.53 185.157,322.679 cw(c185.262,322.785) 185.157,322.891 185.298,323.032 cw(c185.403,322.926) 185.509,323.032 185.659,322.882 185.808,322.733 ccw(c185.914,322.838) 186.02,322.733 186.161,322.874 ccw(c186.055,322.979) 186.161,323.085 186.011,323.235 185.862,323.385 cw(c185.967,323.49) 185.862,323.596 186.003,323.737 cw(c186.108,323.631) 186.214,323.737 186.364,323.587 186.514,323.438 ccw(c186.619,323.544) 186.725,323.438 186.866,323.579 ccw(c186.76,323.685) 186.866,323.79 186.716,323.94 186.567,324.09 cw(c186.673,324.195) 186.567,324.301 186.708,324.442 cw(c186.814,324.336) 186.919,324.442 187.069,324.293 187.219,324.143 ccw(c187.324,324.249) 187.43,324.143 187.571,324.284 ccw(c187.465,324.39) 187.571,324.495 187.422,324.645 187.272,324.795 cw(c187.378,324.901) 187.272,325.006 187.413,325.147 cw(c187.519,325.042) 187.625,325.147 187.774,324.998 187.924,324.848 ccw(c188.03,324.954) 188.135,324.848 188.276,324.989 ccw(c188.171,325.095) 188.276,325.201 188.127,325.35 187.977,325.5 cw(c188.083,325.606) 187.977,325.711 188.118,325.852 cw(c188.224,325.747) 188.33,325.852 188.479,325.703 188.629,325.553 ccw(c188.735,325.659) 188.84,325.553 188.982,325.694 ccw(c188.876,325.8) 188.982,325.906 188.832,326.055 188.682,326.205 cw(c188.788,326.311) 188.682,326.417 188.823,326.558 cw(c188.929,326.452) 189.035,326.558 189.079,326.514 ccw(c189.184,326.619) 189.29,326.514 190.2,327.424 190.2,327.469 v2(190.2,329.257)
DDR4_DQ30: U1.AD25 U10.D3 | length 29.3
  L1 w0.116: v5(184.909,313.027) U1.AD25@185.397,312.539 ; v2(193.393,330.057) U10.D3@193.797,330.46
  L12 (Sign) w0.092: v5(184.909,313.027) 184.998,313.027 ccw(c184.998,313.195) 185.166,313.195 185.166,313.521 cw(c185.255,313.521) 185.255,313.61 ccw(c185.255,313.711) 185.356,313.711 185.356,313.826 ccw(c185.272,313.826) 185.272,313.911 184.831,313.911 cw(c184.831,314.084) 184.658,314.084 184.658,318.524 184.683,318.549 184.725,318.591 cw(c184.795,318.52) 184.866,318.591 184.976,318.48 ccw(c185.047,318.551) 185.117,318.48 185.329,318.692 ccw(c185.258,318.762) 185.329,318.833 185.148,319.014 185.052,319.11 cw(c185.122,319.18) 185.052,319.251 185.263,319.462 cw(c185.334,319.392) 185.404,319.462 185.5,319.366 185.681,319.185 ccw(c185.752,319.256) 185.822,319.185 186.034,319.397 ccw(c185.963,319.467) 186.034,319.538 185.853,319.719 185.757,319.815 cw(c185.827,319.885) 185.757,319.956 185.968,320.167 cw(c186.039,320.097) 186.109,320.167 186.205,320.071 186.386,319.89 ccw(c186.457,319.961) 186.527,319.89 186.739,320.102 ccw(c186.668,320.172) 186.739,320.243 186.558,320.424 186.462,320.52 cw(c186.532,320.59) 186.462,320.661 186.673,320.873 cw(c186.744,320.802) 186.814,320.873 186.91,320.776 187.091,320.596 ccw(c187.162,320.666) 187.232,320.596 187.444,320.807 ccw(c187.373,320.878) 187.444,320.948 187.334,321.059 cw(c187.404,321.129) 187.334,321.2 187.439,321.305 191.955,325.821 192.174,325.821 192.176,325.823 192.176,326.107 cw(c192.276,326.107) 192.276,326.206 192.279,326.206 ccw(c192.279,326.306) 192.379,326.306 192.379,326.605 ccw(c192.279,326.605) 192.279,326.705 192.176,326.705 192.072,326.705 cw(c192.072,326.805) 191.973,326.805 191.973,327.104 cw(c192.072,327.104) 192.072,327.204 192.176,327.204 192.279,327.204 ccw(c192.279,327.303) 192.379,327.303 192.379,327.602 ccw(c192.279,327.602) 192.279,327.702 192.176,327.702 192.072,327.702 cw(c192.072,327.802) 191.973,327.802 191.973,328.101 cw(c192.072,328.101) 192.072,328.201 192.176,328.201 192.279,328.201 ccw(c192.279,328.3) 192.379,328.3 192.379,328.6 ccw(c192.279,328.6) 192.279,328.699 192.176,328.699 192.072,328.699 cw(c192.072,328.799) 191.973,328.799 191.973,329.098 cw(c192.072,329.098) 192.072,329.198 192.176,329.198 192.279,329.198 ccw(c192.279,329.298) 192.379,329.298 192.379,329.597 ccw(c192.279,329.597) 192.279,329.697 192.276,329.697 cw(c192.276,329.796) 192.176,329.796 192.176,329.946 192.287,330.057 v2(193.393,330.057)
DDR4_DQ31: U1.AC24 U10.D4 | length 30.7
  L1 w0.116: U1.AC24@184.397,311.539 v1(184.884,311.052) ; v2(190.193,330.057) U10.D4@190.597,330.46
  L12 (Sign) w0.092: v1(184.884,311.052) 184.884,311.372 184.519,311.737 184.519,312.175 183.912,312.782 183.912,320.157 184.849,321.094 185.762,322.008 ccw(c185.712,322.059) 185.762,322.11 185.763,322.109 cw(c185.869,322.214) 185.763,322.32 185.905,322.461 cw(c186.01,322.355) 186.116,322.461 186.166,322.411 186.279,322.299 ccw(c186.384,322.405) 186.49,322.299 186.631,322.44 ccw(c186.525,322.546) 186.631,322.651 186.518,322.764 186.469,322.814 cw(c186.574,322.92) 186.469,323.025 186.61,323.166 cw(c186.715,323.061) 186.821,323.166 186.871,323.117 186.984,323.004 ccw(c187.089,323.11) 187.195,323.004 187.336,323.145 ccw(c187.23,323.251) 187.336,323.356 187.224,323.469 187.174,323.519 cw(c187.28,323.625) 187.174,323.73 187.315,323.872 cw(c187.421,323.766) 187.526,323.872 187.576,323.822 187.689,323.709 ccw(c187.795,323.815) 187.9,323.709 188.041,323.85 ccw(c187.936,323.956) 188.041,324.062 187.929,324.174 187.879,324.224 cw(c187.985,324.33) 187.879,324.436 188.02,324.577 cw(c188.126,324.471) 188.231,324.577 188.281,324.527 188.394,324.414 ccw(c188.5,324.52) 188.605,324.414 188.746,324.555 ccw(c188.641,324.661) 188.746,324.767 188.634,324.879 188.584,324.929 cw(c188.69,325.035) 188.584,325.141 188.725,325.282 cw(c188.831,325.176) 188.937,325.282 188.986,325.232 189.099,325.119 ccw(c189.205,325.225) 189.311,325.119 189.452,325.26 ccw(c189.346,325.366) 189.452,325.472 189.339,325.585 189.261,325.662 cw(c189.367,325.768) 189.261,325.874 189.402,326.015 cw(c189.508,325.909) 189.614,326.015 189.691,325.937 189.804,325.824 ccw(c189.91,325.93) 190.016,325.824 190.157,325.965 ccw(c190.051,326.071) 190.157,326.177 190.044,326.29 189.931,326.402 cw(c190.037,326.508) 189.931,326.614 190.072,326.755 cw(c190.178,326.649) 190.284,326.755 190.291,326.748 ccw(c190.397,326.854) 190.502,326.748 190.573,326.818 190.573,329.438 cw(c190.751,329.438) 190.751,329.616 191.3,329.616 ccw(c191.3,329.73) 191.414,329.73 191.414,329.933 ccw(c191.173,329.933) 191.173,330.175 190.311,330.175 ccw(c190.311,330.057) v2(190.193,330.057)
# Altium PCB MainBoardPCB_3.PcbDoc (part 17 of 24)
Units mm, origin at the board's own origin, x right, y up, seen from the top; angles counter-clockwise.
Board outline 258.95 x 308.86 mm, 16 copper layers (L1, L2 (GND), L3 (Sign), L4 (GND), L5 (Sign), L6 (PWR/GND), L7(PWR/GND), L8 (Plane_GND), L9 (PWR/GND), L10 (PWR/GND), L11 (PWR/GND), L12 (Sign), L13 (GND), L14 (Sign), L15 (GND), L16), stack 2.502 mm thick; 2402 components, 1749 nets, 8407 pads, 3409 vias.
Unrouted connection lines stored in the file: 4352.

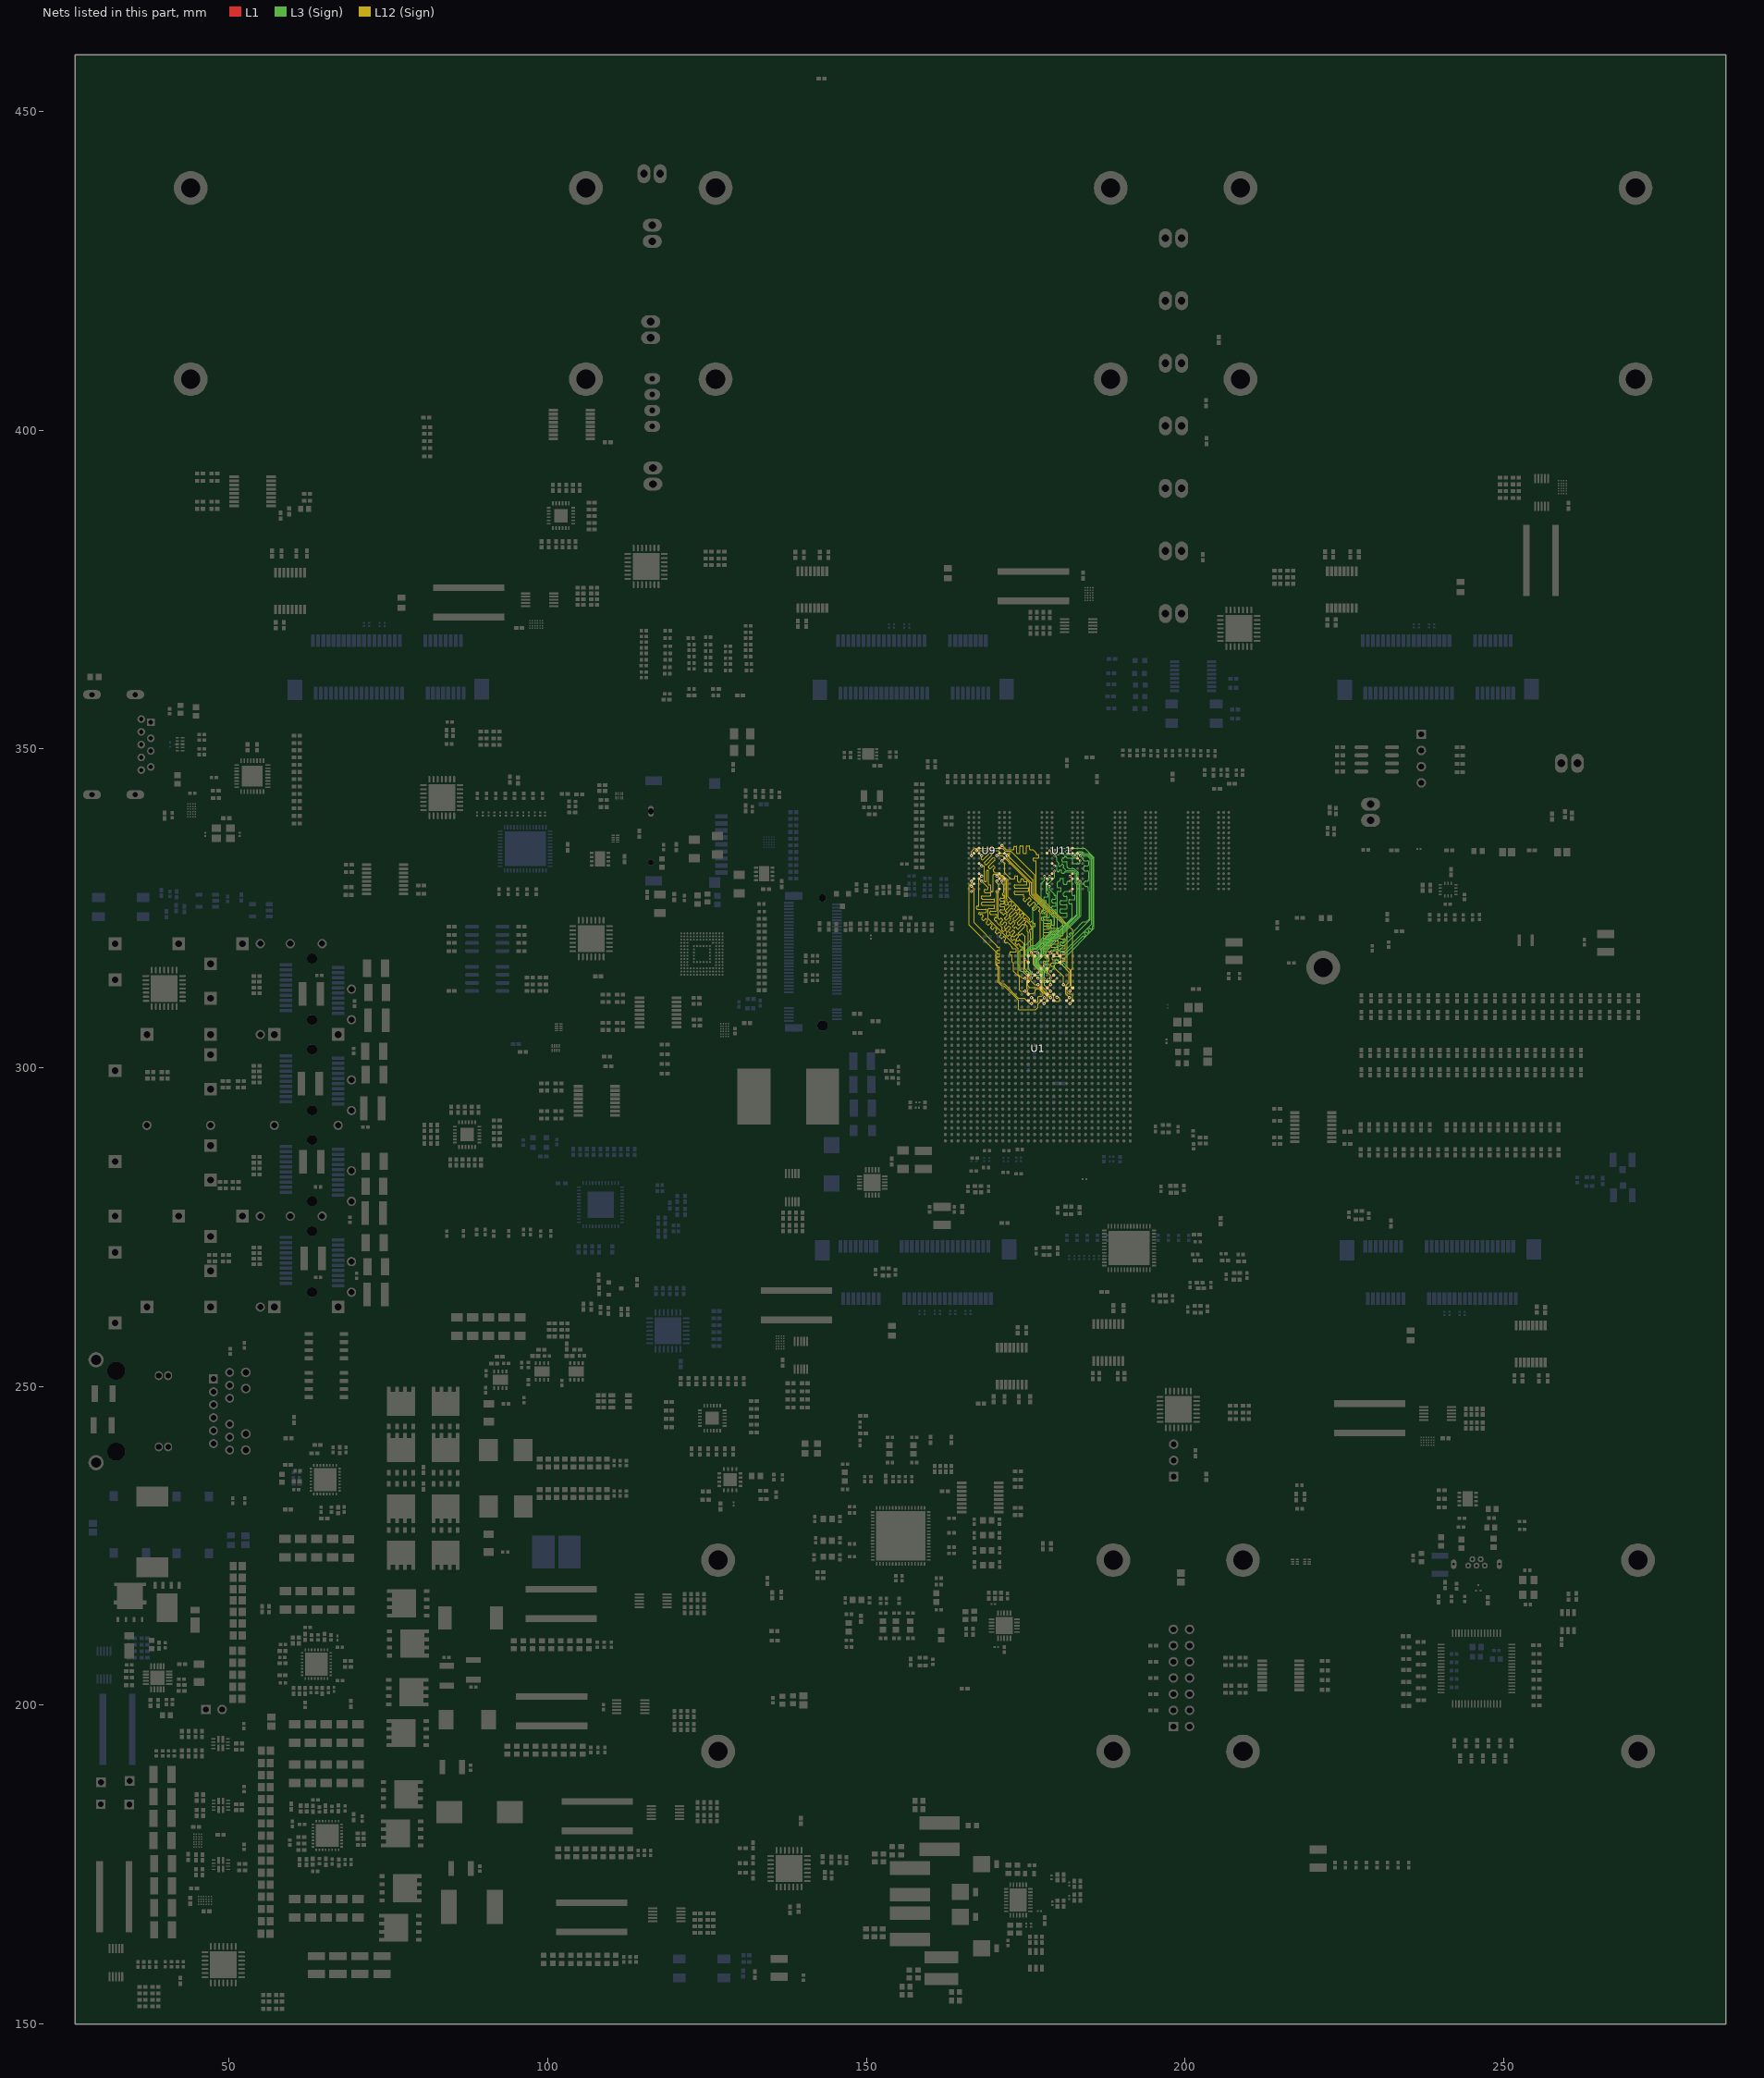
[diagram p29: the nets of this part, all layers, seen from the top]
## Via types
v1: diameter 0.5, hole 0.2, L1 to L16, tented both sides, 1267 vias
v2: diameter 0.5/0.35/0.35/0.35/0.35/0.35/0.35/0.35/0.35/0.35/0.35/0.35/0.35/0.35/0.35/0.5 (per signal layer), hole 0.15, L1 to L16, tented both sides, 463 vias
v3: diameter 0.5, hole 0.2, L1 to L16, 446 vias
v4: diameter 0.35/0/0.35 (per signal layer), hole 0.127, L1 to L3 (Sign), tented both sides, 347 vias
v5: diameter 0.5/0.35/0.35/0.35/0.35/0.35/0.35/0.35/0.35/0.35/0.35/0.35/0.35/0.35/0.35/0.5 (per signal layer), hole 0.2, L1 to L16, tented both sides, 244 vias
v6: diameter 0.8, hole 0.4, L1 to L16, tented both sides, 168 vias
v7: diameter 2.54, hole 1.02, L1 to L16, 113 vias
v8: diameter 1.4, hole 0.5, L1 to L16, tented both sides, 80 vias
v9: diameter 0.5/0/0.5 (per signal layer), hole 0.2, L14 (Sign) to L16, tented both sides, 62 vias
v10: diameter 0.35/0/0.35 (per signal layer), hole 0.127, L1 to L3 (Sign), 38 vias
v11: diameter 0.35, hole 0.127, L1 to L2 (GND), tented both sides, 36 vias
v12: diameter 0.4, hole 0.2, L1 to L16, 16 vias
v13: diameter 0.25, hole 0.2, L1 to L16, 16 vias
v14: diameter 0.35, hole 0.127, L1 to L16, tented both sides, 16 vias
v15: diameter 0.3, hole 0.2, L1 to L16, 15 vias
v16: diameter 0.45, hole 0.15, L1 to L16, 12 vias
v17: diameter 0.5/0.35/0.35/0.35/0.35/0.35/0.35/0.35/0.35/0.35/0.35/0.35/0.35/0.35/0.35/0.45 (per signal layer), hole 0.15, L1 to L16, tented both sides, 10 vias
v18: diameter 0.2/0/0.2 (per signal layer), hole 0.1, L1 to L3 (Sign), tented both sides, 9 vias
v19: diameter 0.4, hole 0.1, L1 to L16, 7 vias
v20: diameter 0.5, hole 0.2, L3 (Sign) to L6 (PWR/GND), tented both sides, 6 vias
v21: diameter 1.15, hole 1.15, L1 to L16, 5 vias
v22: diameter 1.65, hole 1.65, L1 to L16, 5 vias
v23: diameter 0.35/0/0.35 (per signal layer), hole 0.127, L14 (Sign) to L16, tented both sides, 5 vias
v24: diameter 0.5, hole 0.2, L11 (PWR/GND) to L14 (Sign), tented both sides, 4 vias
v25: diameter 0.2, hole 0.1, L1 to L16, 4 vias
v26: diameter 0.35, hole 0.127, L1 to L2 (GND), 2 vias
v27: diameter 0.4, hole 0.15, L1 to L16, 2 vias
v28: diameter 0.4, hole 0.2, L1 to L16, tented both sides, 2 vias
v29: diameter 0.5/0.35/0.35/0.35/0.35/0.35/0.35/0.35/0.35/0.35/0.35/0.35/0.35/0.35/0.35/0.5 (per signal layer), hole 0.15, L1 to L16, 2 vias
v30: diameter 0.35, hole 0.127, L3 (Sign) to L6 (PWR/GND), tented both sides, 2 vias
v31: diameter 0.5/0.35/0.35/0.35/0.35/0.35/0.35/0.35/0.35/0.35/0.35/0.35/0.35/0.35/0.35/0.5 (per signal layer), hole 0.2, L1 to L16, 1 vias
v32: diameter 0.35/0.35/0.35 (per signal layer), hole 0.127, L1 to L3 (Sign), tented both sides, 1 vias
v33: diameter 0.45/0/0.45 (per signal layer), hole 0.15, L1 to L3 (Sign), tented both sides, 1 vias
v34: diameter 0.45/0/0.45 (per signal layer), hole 0.2, L14 (Sign) to L16, tented both sides, 1 vias
v35: diameter 0.35, hole 0.127, L2 (GND) to L3 (Sign), 1 vias

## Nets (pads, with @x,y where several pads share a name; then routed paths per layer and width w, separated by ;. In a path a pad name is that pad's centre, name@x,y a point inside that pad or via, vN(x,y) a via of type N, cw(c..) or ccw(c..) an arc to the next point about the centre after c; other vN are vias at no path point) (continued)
DDR4_DQ32: U1.U24 U9.G2 | length 41.6
  L1 w0.116: v2(171.272,332.457) U9.G2@171.676,332.86 ; U1.U24@178.397,311.539 v1(178.884,312.027)
  L12 (Sign) w0.092: v2(171.272,332.457) 171.704,332.025 171.704,330.594 172.668,329.63 173.152,329.63 173.169,329.63 ccw(c173.169,329.73) 173.268,329.73 173.268,329.987 cw(c173.368,329.987) 173.368,330.087 173.667,330.087 cw(c173.667,329.987) 173.767,329.987 173.767,329.63 173.767,329.273 ccw(c173.867,329.273) 173.867,329.173 174.166,329.173 ccw(c174.166,329.273) 174.266,329.273 174.266,329.53 cw(c174.365,329.53) 174.365,329.63 174.515,329.63 174.69,329.455 174.69,329.305 ccw(c174.79,329.305) 174.79,329.206 175.101,329.206 cw(c175.101,329.106) 175.201,329.106 175.201,328.807 cw(c175.101,328.807) 175.101,328.707 174.69,328.707 173.3,328.707 ccw(c173.3,328.607) 173.2,328.607 173.2,328.308 ccw(c173.3,328.308) 173.3,328.208 174.69,328.208 175.362,328.208 cw(c175.362,328.109) 175.462,328.109 175.462,327.809 cw(c175.362,327.809) 175.362,327.71 174.69,327.71 173.297,327.71 ccw(c173.297,327.61) 173.198,327.61 173.198,327.311 ccw(c173.297,327.311) 173.297,327.211 174.618,327.211 cw(c174.618,327.139) 174.69,327.139 174.69,326.904 174.796,326.798 cw(c174.725,326.728) 174.796,326.657 174.613,326.475 ccw(c174.684,326.405) 174.613,326.334 174.825,326.123 ccw(c174.896,326.193) 174.966,326.123 175.219,326.375 175.472,326.628 cw(c175.542,326.558) 175.613,326.628 175.824,326.417 cw(c175.754,326.346) 175.824,326.276 175.571,326.023 175.319,325.77 ccw(c175.389,325.699) 175.319,325.629 175.53,325.417 ccw(c175.601,325.488) 175.671,325.417 175.924,325.67 176.177,325.923 cw(c176.247,325.852) 176.318,325.923 176.529,325.711 cw(c176.459,325.641) 176.529,325.57 176.276,325.318 176.024,325.065 ccw(c176.094,324.994) 176.024,324.924 176.235,324.712 ccw(c176.306,324.783) 176.376,324.712 176.629,324.965 176.882,325.218 cw(c176.952,325.147) 177.023,325.218 177.234,325.006 cw(c177.164,324.936) 177.234,324.865 177.052,324.683 ccw(c177.123,324.613) 177.052,324.542 177.283,324.311 177.292,324.302 177.292,319.214 177.292,318.541 ccw(c177.392,318.541) 177.392,318.442 177.445,318.442 cw(c177.445,318.342) 177.545,318.342 177.545,318.043 cw(c177.445,318.043) 177.445,317.943 177.292,317.943 177.099,317.943 ccw(c177.099,317.843) 176.999,317.843 176.999,317.544 ccw(c177.099,317.544) 177.099,317.444 177.192,317.444 cw(c177.192,317.345) 177.292,317.345 177.292,317.195 177,316.903 177,316.132 177.978,315.154 177.978,312.933 v1(178.884,312.027)
DDR4_DQ33: U1.V23 U9.F4 | length 40.2
  L1 w0.116: U9.F4@167.676,332.06 v2(168.079,331.657) ; v1(178.909,311.027) U1.V23@179.397,310.539
  L12 (Sign) w0.092: v2(168.079,331.657) 168.415,331.657 cw(c168.415,331.568) 168.504,331.568 168.504,329.324 ccw(c168.618,329.324) 168.618,329.209 168.732,329.209 ccw(c168.732,329.349) 168.872,329.349 168.872,330.848 cw(c168.974,330.848) 168.974,330.949 169.086,330.949 cw(c169.086,330.848) 169.188,330.848 169.188,328.792 ccw(c169.304,328.792) 169.304,328.676 169.398,328.676 cw(c169.398,328.542) 169.532,328.542 169.532,327.79 ccw(c169.675,327.79) 169.675,327.647 169.783,327.647 ccw(c169.783,327.762) 169.897,327.762 169.897,330.26 cw(c170.028,330.26) 170.028,330.39 170.713,330.39 171.032,330.072 171.249,330.072 171.986,329.334 171.986,326.539 172.05,326.476 cw(c171.955,326.381) 172.05,326.286 172.026,326.262 ccw(c172.121,326.167) 172.026,326.072 172.152,325.945 ccw(c172.247,326.04) 172.342,325.945 172.461,326.064 172.472,326.075 cw(c172.567,325.98) 172.662,326.075 172.789,325.948 cw(c172.694,325.853) 172.789,325.758 172.778,325.748 172.653,325.623 ccw(c172.748,325.528) 172.653,325.433 172.78,325.306 ccw(c172.875,325.401) 172.97,325.306 173.095,325.431 173.105,325.442 cw(c173.2,325.347) 173.295,325.442 173.422,325.315 cw(c173.327,325.22) 173.422,325.125 173.411,325.115 173.287,324.99 ccw(c173.382,324.895) 173.287,324.8 173.413,324.673 ccw(c173.508,324.768) 173.603,324.673 173.728,324.798 173.738,324.808 cw(c173.833,324.713) 173.928,324.808 174.055,324.682 cw(c173.96,324.587) 174.055,324.492 174.045,324.481 173.92,324.356 ccw(c174.015,324.261) 173.92,324.167 174.046,324.04 ccw(c174.141,324.135) 174.236,324.04 174.361,324.165 174.372,324.175 cw(c174.467,324.08) 174.562,324.175 174.688,324.049 cw(c174.593,323.954) 174.688,323.859 174.678,323.848 174.553,323.723 ccw(c174.648,323.628) 174.553,323.533 174.68,323.407 ccw(c174.775,323.502) 174.87,323.407 174.9,323.436 cw(c174.994,323.341) 175.089,323.436 175.244,323.281 175.244,322.923 175.778,322.389 175.778,322.233 ccw(c175.845,322.233) 175.845,322.166 cw(c175.845,322.054) 175.957,322.054 175.957,321.83 cw(c175.845,321.83) 175.845,321.718 175.778,321.718 175.711,321.718 ccw(c175.711,321.606) 175.599,321.606 175.599,321.382 ccw(c175.711,321.382) 175.711,321.27 ; 175.691,321.27 cw(c175.691,321.183) 175.778,321.183 175.778,317.947 176.211,317.514 176.211,316.273 176.251,316.233 176.251,316.067 177.402,314.915 177.402,312.612 177.664,312.35 177.664,312.272 178.104,311.832 178.104,311.704 178.561,311.247 178.581,311.247 178.801,311.027 v1(178.909,311.027)
DDR4_DQ34: U1.U25 U9.H3 | length 40.7
  L1 w0.116: v2(170.472,333.257) U9.H3@170.876,333.66 ; U1.U25@178.397,312.539 v1(178.884,313.027)
  L12 (Sign) w0.092: v2(170.472,333.257) 171.363,333.257 175.654,328.966 175.654,327.147 176.623,326.178 177.528,325.272 177.81,324.99 cw(c177.74,324.92) 177.81,324.849 177.632,324.671 ccw(c177.703,324.601) 177.632,324.53 177.844,324.319 ccw(c177.914,324.389) 177.985,324.319 178.163,324.497 cw(c178.233,324.426) 178.304,324.497 178.41,324.391 178.41,324.155 178.41,323.819 cw(c178.31,323.819) 178.31,323.719 177.9,323.719 ccw(c177.9,323.619) 177.8,323.619 177.8,323.32 ccw(c177.9,323.32) 177.9,323.221 178.41,323.221 178.919,323.221 cw(c178.919,323.121) 179.019,323.121 179.019,322.822 cw(c178.919,322.822) 178.919,322.722 178.41,322.722 177.9,322.722 ccw(c177.9,322.622) 177.8,322.622 177.8,322.323 ccw(c177.9,322.323) 177.9,322.223 178.41,322.223 178.671,322.223 cw(c178.671,322.124) 178.771,322.124 178.771,321.825 cw(c178.671,321.825) 178.671,321.725 178.41,321.725 177.9,321.725 ccw(c177.9,321.625) 177.8,321.625 177.8,321.326 ccw(c177.9,321.326) 177.9,321.226 178.41,321.226 178.671,321.226 cw(c178.671,321.126) 178.771,321.126 178.771,320.827 cw(c178.671,320.827) 178.671,320.728 178.41,320.728 177.9,320.728 ccw(c177.9,320.628) 177.8,320.628 177.8,320.329 ccw(c177.9,320.329) 177.9,320.229 178.41,320.229 178.671,320.229 cw(c178.671,320.129) 178.771,320.129 178.771,319.83 cw(c178.671,319.83) 178.671,319.73 178.41,319.73 177.9,319.73 ccw(c177.9,319.631) 177.8,319.631 177.8,319.332 ccw(c177.9,319.332) 177.9,319.232 178.41,319.232 178.671,319.232 cw(c178.671,319.132) 178.771,319.132 178.771,318.833 cw(c178.671,318.833) 178.671,318.733 178.41,318.733 177.9,318.733 ccw(c177.9,318.633) 177.8,318.633 177.8,318.334 ccw(c177.9,318.334) 177.9,318.235 178.41,318.235 178.671,318.235 cw(c178.671,318.135) 178.771,318.135 178.771,317.836 cw(c178.671,317.836) 178.671,317.736 178.41,317.736 178.089,317.736 ccw(c178.089,317.636) 177.989,317.636 177.989,317.337 ccw(c178.089,317.337) 178.089,317.237 178.41,317.237 178.551,317.237 cw(c178.551,317.138) 178.651,317.138 178.651,316.839 cw(c178.551,316.839) 178.551,316.739 178.41,316.739 177.9,316.739 ccw(c177.9,316.639) 177.8,316.639 177.8,316.34 ccw(c177.9,316.34) 177.9,316.24 178.41,316.24 178.671,316.24 cw(c178.671,316.14) 178.771,316.14 178.771,315.841 cw(c178.671,315.841) 178.671,315.742 178.41,315.742 178.2,315.742 ccw(c178.2,315.642) 178.1,315.642 178.1,315.343 ccw(c178.2,315.343) 178.2,315.243 178.31,315.243 cw(c178.31,315.143) 178.41,315.143 178.41,314.994 178.884,314.519 v1(178.884,313.027)
DDR4_DQ35: U1.V24 U9.H4 | length 39.9
  L1 w0.116: U9.H4@167.676,333.66 v2(168.079,333.257) ; U1.V24@179.397,311.539 v1(179.884,311.052)
  L12 (Sign) w0.092: v2(168.079,333.257) 168.079,332.72 168.143,332.657 ccw(c168.238,332.751) 168.333,332.657 169.354,333.678 cw(c169.449,333.583) 169.544,333.678 169.671,333.551 cw(c169.576,333.456) 169.671,333.361 168.554,332.245 168.519,332.21 ccw(c168.614,332.115) 168.519,332.02 168.646,331.893 ccw(c168.741,331.988) 168.836,331.893 168.871,331.928 169.829,332.887 cw(c169.924,332.792) 170.019,332.887 170.146,332.76 cw(c170.051,332.665) 170.146,332.57 169.188,331.612 169.165,331.589 ccw(c169.26,331.494) 169.165,331.399 169.291,331.272 ccw(c169.386,331.367) 169.481,331.272 169.504,331.295 169.819,331.61 cw(c169.914,331.515) 170.009,331.61 170.136,331.483 cw(c170.041,331.388) 170.136,331.293 169.916,331.073 ccw(c170.011,330.978) 169.916,330.883 169.989,330.81 170.217,330.582 170.793,330.582 171.112,330.263 171.328,330.263 172.178,329.413 172.178,326.83 175.565,323.444 175.611,323.398 cw(c175.547,323.334) 175.611,323.271 175.486,323.146 ccw(c175.549,323.083) 175.486,323.02 175.676,322.83 ccw(c175.739,322.893) 175.803,322.83 175.927,322.954 cw(c175.991,322.891) 176.054,322.954 176.149,322.859 176.149,322.725 ccw(c176.239,322.725) 176.239,322.636 176.415,322.636 cw(c176.415,322.546) 176.505,322.546 176.505,322.277 cw(c176.415,322.277) 176.415,322.188 176.239,322.188 ccw(c176.239,322.098) 176.149,322.098 176.149,322.047 176.149,317.848 176.403,317.594 176.403,316.352 176.451,316.304 176.451,316.138 177.594,314.995 177.594,312.715 178.296,312.013 178.296,311.783 178.65,311.429 179.197,311.429 cw(c179.197,311.233) 179.393,311.233 179.393,310.801 ccw(c179.743,310.801) 179.743,310.452 180.111,310.452 ccw(c180.111,310.718) 180.378,310.718 ccw(c180.044,310.718) 180.044,311.052 v1(179.884,311.052)
DDR4_DQ36: U1.Y25 U9.H2 | length 38.8
  L1 w0.116: U9.H2@171.676,333.66 v2(172.079,333.257) ; v1(180.909,313.027) U1.Y25@181.397,312.539
  L12 (Sign) w0.092: v2(172.079,333.257) 172.079,332.822 175.91,328.992 175.91,327.163 178.602,324.47 178.602,324.445 179.553,323.494 179.553,322.847 179.553,322.514 cw(c179.453,322.514) 179.453,322.414 179.063,322.414 ccw(c179.063,322.315) 178.963,322.315 178.963,322.016 ccw(c179.063,322.016) 179.063,321.916 179.553,321.916 180.042,321.916 cw(c180.042,321.816) 180.142,321.816 180.142,321.517 cw(c180.042,321.517) 180.042,321.417 179.553,321.417 179.063,321.417 ccw(c179.063,321.318) 178.963,321.318 178.963,321.018 ccw(c179.063,321.018) 179.063,320.919 179.553,320.919 180.042,320.919 cw(c180.042,320.819) 180.142,320.819 180.142,320.52 cw(c180.042,320.52) 180.042,320.42 179.553,320.42 179.063,320.42 ccw(c179.063,320.32) 178.963,320.32 178.963,320.021 ccw(c179.063,320.021) 179.063,319.921 179.553,319.921 180.042,319.921 cw(c180.042,319.822) 180.142,319.822 180.142,319.523 cw(c180.042,319.523) 180.042,319.423 179.553,319.423 179.063,319.423 ccw(c179.063,319.323) 178.963,319.323 178.963,319.024 ccw(c179.063,319.024) 179.063,318.924 179.553,318.924 180.042,318.924 cw(c180.042,318.825) 180.142,318.825 180.142,318.525 cw(c180.042,318.525) 180.042,318.426 179.553,318.426 179.063,318.426 ccw(c179.063,318.326) 178.963,318.326 178.963,318.027 ccw(c179.063,318.027) 179.063,317.927 179.553,317.927 180.042,317.927 cw(c180.042,317.827) 180.142,317.827 180.142,317.528 cw(c180.042,317.528) 180.042,317.428 179.553,317.428 179.288,317.428 ccw(c179.288,317.329) 179.188,317.329 179.188,317.03 ccw(c179.288,317.03) 179.288,316.93 179.553,316.93 180.042,316.93 cw(c180.042,316.83) 180.142,316.83 180.142,316.531 cw(c180.042,316.531) 180.042,316.431 179.553,316.431 179.063,316.431 ccw(c179.063,316.332) 178.963,316.332 178.963,316.032 ccw(c179.063,316.032) 179.063,315.933 179.453,315.933 cw(c179.453,315.833) 179.553,315.833 179.553,315.683 180.909,314.326 v1(180.909,313.027)
DDR4_DQ37: U1.AA23 U9.H5 | length 37.4
  L1 w0.116: v2(166.472,333.257) U9.H5@166.876,333.66 ; v1(181.909,310.052) U1.AA23@182.397,310.539
  L12 (Sign) w0.092: v2@166.472,333.257 166.472,333.934 166.998,334.46 171.343,334.46 171.78,334.023 172.683,334.023 176.451,330.255 176.451,327.244 181.47,322.224 181.47,315.824 181.985,315.309 181.985,312.941 181.508,312.464 181.508,311.839 181.781,311.566 182.172,311.566 182.397,311.341 182.397,310.539 v1(181.909,310.052)
DDR4_DQ38: U1.AA25 U9.J3 | length 38.2
  L1 w0.116: U9.J3@170.876,334.46 v2(171.279,334.864) ; v1(181.909,312.052) U1.AA25@182.397,312.539
  L12 (Sign) w0.092: v2(171.279,334.864) 171.929,334.215 172.872,334.215 173.022,334.215 ccw(c173.022,334.314) 173.122,334.314 173.122,334.619 cw(c173.221,334.619) 173.221,334.719 173.521,334.719 cw(c173.521,334.619) 173.62,334.619 173.62,334.215 173.62,333.705 ccw(c173.72,333.705) 173.72,333.605 174.019,333.605 ccw(c174.019,333.705) 174.119,333.705 174.119,334.215 174.119,334.725 cw(c174.219,334.725) 174.219,334.824 174.518,334.824 cw(c174.518,334.725) 174.617,334.725 174.617,334.215 174.617,333.705 ccw(c174.717,333.705) 174.717,333.605 175.016,333.605 ccw(c175.016,333.705) 175.116,333.705 175.116,334.215 175.116,334.725 cw(c175.216,334.725) 175.216,334.824 175.515,334.824 cw(c175.515,334.725) 175.615,334.725 175.615,334.314 ccw(c175.714,334.314) 175.714,334.215 175.844,334.215 176.122,334.215 176.643,333.694 176.643,333.544 ccw(c176.743,333.544) 176.743,333.445 176.98,333.445 cw(c176.98,333.345) 177.08,333.345 177.08,333.046 cw(c176.98,333.046) 176.98,332.946 176.643,332.946 176.306,332.946 ccw(c176.306,332.846) 176.206,332.846 176.206,332.547 ccw(c176.306,332.547) 176.306,332.448 176.543,332.448 cw(c176.543,332.348) 176.643,332.348 176.643,331.483 176.643,327.352 179.36,324.634 179.36,324.617 182.372,321.605 182.372,315.584 182.177,315.389 182.177,312.319 v1(181.909,312.052)
DDR4_DQ39: U1.Y23 U9.J4 | length 39.7
  L1 w0.116: v2(167.272,334.057) U9.J4@167.676,334.46 ; U1.Y23@181.397,310.539 v1(181.884,311.027)
  L12 (Sign) w0.092: 170.679,334.057 171.12,333.616 172.273,333.616 172.466,333.424 172.466,333.054 176.102,329.418 176.102,327.262 180.81,322.554 180.81,321.462 180.81,320.825 cw(c180.71,320.825) 180.71,320.725 180.513,320.725 ccw(c180.513,320.626) 180.414,320.626 180.414,320.327 ccw(c180.513,320.327) 180.513,320.227 180.81,320.227 181.106,320.227 cw(c181.106,320.127) 181.206,320.127 181.206,319.828 cw(c181.106,319.828) 181.106,319.728 180.81,319.728 180.513,319.728 ccw(c180.513,319.628) 180.414,319.628 180.414,319.329 ccw(c180.513,319.329) 180.513,319.23 180.81,319.23 181.106,319.23 cw(c181.106,319.13) 181.206,319.13 181.206,318.831 cw(c181.106,318.831) 181.106,318.731 180.81,318.731 180.513,318.731 ccw(c180.513,318.631) 180.414,318.631 180.414,318.332 ccw(c180.513,318.332) 180.513,318.232 180.81,318.232 181.106,318.232 cw(c181.106,318.133) 181.206,318.133 181.206,317.834 cw(c181.106,317.834) 181.106,317.734 180.81,317.734 180.513,317.734 ccw(c180.513,317.634) 180.414,317.634 180.414,317.335 ccw(c180.513,317.335) 180.513,317.235 180.81,317.235 181.106,317.235 cw(c181.106,317.135) 181.206,317.135 181.206,316.836 cw(c181.106,316.836) 181.106,316.737 180.81,316.737 180.513,316.737 ccw(c180.513,316.637) 180.414,316.637 180.414,316.338 ccw(c180.513,316.338) 180.513,316.238 180.71,316.238 cw(c180.71,316.138) 180.81,316.138 180.81,315.989 181.793,315.006 181.793,313.375 181.316,312.899 181.316,311.595 v1(181.884,311.027)
  L12 (Sign) w0.1: v2(167.272,334.057) 170.679,334.057
DDR4_DQ40: U1.P23 U9.A3 | length 31.5
  L1 w0.116: v2(170.472,327.657) U9.A3@170.876,328.06 ; U1.P23@175.397,310.539 v1(175.884,311.027)
  L12 (Sign) w0.092: v2(170.472,327.657) 170.472,325.12 170.472,325.056 170.472,324.682 cw(c170.348,324.682) 170.348,324.558 169.524,324.558 ccw(c169.524,324.433) 169.399,324.433 169.399,324.184 ccw(c169.524,324.184) 169.524,324.059 170.348,324.059 cw(c170.348,323.934) 170.472,323.934 170.472,323.685 cw(c170.348,323.685) 170.348,323.56 170.226,323.56 ccw(c170.226,323.436) 170.101,323.436 170.101,323.186 ccw(c170.226,323.186) 170.226,323.062 170.348,323.062 cw(c170.348,322.937) 170.472,322.937 170.472,322.813 170.574,322.711 171.287,321.998 cw(c171.199,321.91) 171.287,321.821 171.245,321.779 ccw(c171.333,321.691) 171.245,321.603 171.421,321.427 ccw(c171.509,321.515) 171.597,321.427 171.728,321.557 cw(c171.788,321.497) 171.847,321.557 172.08,321.324 cw(c172.02,321.264) 172.08,321.204 171.95,321.074 ccw(c172.038,320.986) 171.95,320.898 172.126,320.722 ccw(c172.214,320.81) 172.303,320.722 172.433,320.852 cw(c172.48,320.805) 172.527,320.852 172.785,320.594 cw(c172.738,320.546) 172.785,320.499 172.655,320.369 ccw(c172.743,320.281) 172.655,320.193 172.831,320.016 ccw(c172.92,320.105) 173.008,320.016 173.138,320.147 cw(c173.185,320.1) 173.232,320.147 173.491,319.889 cw(c173.443,319.841) 173.491,319.794 173.36,319.664 ccw(c173.448,319.576) 173.36,319.488 173.537,319.311 ccw(c173.625,319.399) 173.713,319.311 173.755,319.353 cw(c173.843,319.265) 173.931,319.353 174.019,319.265 174.079,319.206 174.079,319.081 ccw(c174.204,319.081) 174.204,318.956 174.401,318.956 cw(c174.401,318.832) 174.526,318.832 174.526,318.583 cw(c174.401,318.583) 174.401,318.458 174.204,318.458 ccw(c174.204,318.333) 174.079,318.333 174.079,318.072 174.079,317.675 174.076,317.672 174.076,317.406 174.079,317.403 174.079,316.675 174.076,316.672 174.076,316.406 174.079,316.403 174.079,315.675 174.076,315.672 174.076,315.406 174.079,315.403 174.079,315.303 174.23,315.152 174.484,315.152 175.362,314.274 175.362,313.919 175.158,313.716 175.158,312.338 175.305,312.191 175.305,311.875 175.524,311.656 176.073,311.656 176.076,311.658 176.234,311.658 176.488,311.912 176.488,312.191 176.72,312.423 177.048,312.423 177.28,312.191 177.28,312.113 177.718,311.675 177.718,311.406 177.508,311.196 177.032,311.196 ccw(c177.032,311.114) 176.949,311.114 176.949,310.483 cw(c176.771,310.483) 176.771,310.306 176.371,310.306 cw(c176.371,310.452) 176.225,310.452 176.225,310.686 ccw(c175.884,310.686) v1(175.884,311.027)
DDR4_DQ41: U1.R23 U9.B5 | length 27.1
  L1 w0.116: v2(166.472,328.457) U9.B5@166.876,328.86 ; v1(175.909,310.052) U1.R23@176.397,310.539
  L1 w0.25: v2(166.472,327.657) 166.876,328.06
  L12 (Sign) w0.092: v2(166.472,328.457) 166.917,328.012 166.917,322.743 167.036,322.624 170.499,319.161 170.499,319.037 ccw(c170.624,319.037) 170.624,318.912 170.813,318.912 cw(c170.813,318.787) 170.937,318.787 170.937,318.538 cw(c170.813,318.538) 170.813,318.413 170.624,318.413 ccw(c170.624,318.289) 170.499,318.289 170.499,318.039 ccw(c170.624,318.039) 170.624,317.915 170.813,317.915 cw(c170.813,317.79) 170.937,317.79 170.937,317.541 cw(c170.813,317.541) 170.813,317.416 170.624,317.416 ccw(c170.624,317.292) 170.499,317.292 170.499,317.042 ccw(c170.624,317.042) 170.624,316.918 170.813,316.918 cw(c170.813,316.793) 170.937,316.793 170.937,316.544 cw(c170.813,316.544) 170.813,316.419 170.624,316.419 ccw(c170.624,316.294) 170.499,316.294 170.499,316.167 170.912,315.754 170.912,313.477 171.233,313.157 171.601,313.157 173.828,310.93 174.719,310.93 175.597,310.052 v1(175.909,310.052)
DDR4_DQ42: U1.T23 U9.C3 | length 30.8
  L1 w0.116: v2(170.472,329.257) U9.C3@170.876,329.66 ; U1.T23@177.397,310.539 v5(177.884,310.052)
  L12 (Sign) w0.092: v2(170.472,329.257) 170.472,328.975 170.793,328.654 170.793,327.465 170.709,327.381 170.709,323.429 170.788,323.35 ccw(c170.868,323.429) 170.947,323.35 171.032,323.436 cw(c171.112,323.357) 171.191,323.436 171.349,323.278 cw(c171.27,323.198) 171.349,323.119 171.184,322.954 171.019,322.79 ccw(c171.098,322.71) 171.019,322.631 171.178,322.473 ccw(c171.257,322.552) 171.336,322.473 171.501,322.638 171.666,322.803 cw(c171.745,322.723) 171.824,322.803 171.982,322.644 cw(c171.903,322.565) 171.982,322.486 171.817,322.321 171.653,322.156 ccw(c171.732,322.077) 171.653,321.998 171.811,321.84 ccw(c171.89,321.919) 171.969,321.84 172.134,322.004 172.299,322.169 cw(c172.378,322.09) 172.457,322.169 172.616,322.011 cw(c172.536,321.932) 172.616,321.853 172.451,321.688 172.286,321.523 ccw(c172.365,321.444) 172.286,321.365 172.444,321.206 ccw(c172.523,321.286) 172.603,321.206 172.767,321.371 172.932,321.536 cw(c173.011,321.457) 173.091,321.536 173.249,321.378 cw(c173.17,321.299) 173.249,321.219 173.084,321.055 172.919,320.89 ccw(c172.998,320.811) 172.919,320.731 173.077,320.573 ccw(c173.157,320.652) 173.236,320.573 173.401,320.738 173.541,320.878 cw(c173.62,320.799) 173.699,320.878 173.858,320.72 cw(c173.779,320.641) 173.858,320.562 173.717,320.421 173.552,320.256 ccw(c173.632,320.177) 173.552,320.098 173.711,319.94 ccw(c173.79,320.019) 173.869,319.94 173.955,320.025 cw(c174.034,319.946) 174.113,320.025 174.387,319.751 174.718,319.421 174.718,315.218 175.552,314.384 175.552,314.355 175.554,314.354 175.554,313.839 175.552,313.838 175.552,313.779 175.362,313.588 175.362,312.885 175.616,312.631 177.112,312.631 177.472,312.27 177.472,312.192 177.91,311.755 177.91,311.627 178.371,311.165 178.371,310.539 v5(177.884,310.052)
DDR4_DQ43: U1.P26 U9.C4 | length 29.3
  L1 w0.116: U9.C4@167.676,329.66 v2(168.079,329.257) ; v1(174.909,314.027) U1.P26@175.397,313.539
  L12 (Sign) w0.092: v2(168.079,329.257) 169.1,328.236 169.1,328.111 cw(c168.976,328.111) 168.976,327.986 168.612,327.986 ccw(c168.612,327.862) 168.487,327.862 168.487,327.612 ccw(c168.612,327.612) 168.612,327.488 169.1,327.488 169.418,327.488 cw(c169.418,327.363) 169.543,327.363 169.543,327.114 cw(c169.418,327.114) 169.418,326.989 169.1,326.989 168.188,326.989 ccw(c168.188,326.864) 168.064,326.864 168.064,326.615 ccw(c168.188,326.615) 168.188,326.491 169.1,326.491 170.013,326.491 cw(c170.013,326.366) 170.137,326.366 170.137,326.117 cw(c170.013,326.117) 170.013,325.992 169.1,325.992 168.188,325.992 ccw(c168.188,325.867) 168.064,325.867 168.064,325.618 ccw(c168.188,325.618) 168.188,325.493 169.1,325.493 170.013,325.493 cw(c170.013,325.369) 170.137,325.369 170.137,325.119 cw(c170.013,325.119) 170.013,324.995 169.204,324.995 ccw(c169.204,324.891) 169.1,324.891 169.1,323.418 173.838,318.681 173.838,314.645 174.456,314.027 v1(174.909,314.027)
DDR4_DQ44: U1.T25 U9.C2 | length 29.8
  L1 w0.116: v2(171.272,329.257) U9.C2@171.676,329.66 ; v1(176.909,313.027) U1.T25@177.397,312.539
  L12 (Sign) w0.092: v2(171.272,329.257) 171.272,328.944 171.593,328.623 171.593,327.524 171.352,327.283 171.352,327.171 ccw(c171.464,327.171) 171.464,327.059 171.49,327.059 cw(c171.49,326.947) 171.602,326.947 171.602,326.723 cw(c171.49,326.723) 171.49,326.612 171.352,326.612 171.097,326.612 ccw(c171.097,326.5) 170.985,326.5 170.985,326.276 ccw(c171.097,326.276) 171.097,326.164 171.352,326.164 171.49,326.164 cw(c171.49,326.052) 171.602,326.052 171.602,325.828 cw(c171.49,325.828) 171.49,325.716 171.352,325.716 171.097,325.716 ccw(c171.097,325.604) 170.985,325.604 170.985,325.38 ccw(c171.097,325.38) 171.097,325.268 171.352,325.268 171.627,325.268 cw(c171.627,325.156) 171.739,325.156 171.739,324.932 cw(c171.627,324.932) 171.627,324.82 171.352,324.82 171.097,324.82 ccw(c171.097,324.708) 170.985,324.708 170.985,324.484 ccw(c171.097,324.484) 171.097,324.373 171.241,324.373 cw(c171.241,324.261) 171.352,324.261 171.352,324.193 171.352,324.136 171.432,324.057 ccw(c171.511,324.136) 171.59,324.057 171.723,324.19 cw(c171.802,324.111) 171.882,324.19 172.04,324.032 cw(c171.961,323.953) 172.04,323.874 171.827,323.661 171.7,323.534 ccw(c171.779,323.454) 171.7,323.375 171.858,323.217 ccw(c171.937,323.296) 172.016,323.217 172.144,323.345 172.317,323.518 cw(c172.396,323.438) 172.475,323.518 172.634,323.359 cw(c172.554,323.28) 172.634,323.201 172.461,323.028 172.333,322.9 ccw(c172.412,322.821) 172.333,322.742 172.491,322.584 ccw(c172.57,322.663) 172.65,322.584 172.777,322.711 172.95,322.884 cw(c173.029,322.805) 173.109,322.884 173.267,322.726 cw(c173.188,322.647) 173.267,322.568 173.094,322.395 172.966,322.267 ccw(c173.045,322.188) 172.966,322.109 173.125,321.95 ccw(c173.204,322.029) 173.283,321.95 173.332,321.999 cw(c173.411,321.92) 173.49,321.999 173.493,321.996 173.609,321.88 173.688,321.801 ccw(c173.767,321.88) 173.846,321.801 174.493,322.448 cw(c174.573,322.368) 174.652,322.448 174.81,322.289 cw(c174.731,322.21) 174.81,322.131 174.084,321.405 173.855,321.176 ccw(c173.934,321.097) 173.855,321.018 174.013,320.859 ccw(c174.093,320.938) 174.172,320.859 174.321,321.009 cw(c174.401,320.93) 174.48,321.009 174.91,320.579 174.91,315.539 175.87,314.579 175.87,313.602 176.444,313.027 v1(176.909,313.027)
DDR4_DQ45: U1.U23 U9.C5 | length 30.5
  L1 w0.116: v2(166.472,329.257) U9.C5@166.876,329.66 ; v1(177.909,311.027) U1.U23@178.397,310.539
  L12 (Sign) w0.092: v2(166.472,329.257) 166.612,329.117 166.612,329.045 166.345,328.778 166.339,328.778 166.151,328.59 166.151,322.379 170.307,318.223 170.307,316.088 170.72,315.675 170.72,313.376 171.168,312.928 171.535,312.928 173.888,310.575 173.888,309.143 176.594,309.143 176.912,309.462 176.912,310.016 177.783,310.887 178.049,310.887 v1(177.909,311.027)
DDR4_DQ46: U1.T26 U9.D3 | length 29.1
  L1 w0.116: v2(170.472,330.057) U9.D3@170.876,330.46 ; v1(176.909,314.027) U1.T26@177.397,313.539
  L12 (Sign) w0.092: v2(170.472,330.057) 170.482,330.047 170.785,330.047 170.953,329.88 171.169,329.88 171.794,329.254 171.794,325.62 171.874,325.541 ccw(c171.953,325.62) 172.032,325.541 172.101,325.609 cw(c172.18,325.53) 172.259,325.609 172.417,325.451 cw(c172.338,325.372) 172.417,325.293 172.269,325.145 171.828,324.703 ccw(c171.907,324.624) 171.828,324.545 171.986,324.386 ccw(c172.065,324.465) 172.144,324.386 172.586,324.828 172.734,324.976 cw(c172.813,324.897) 172.892,324.976 173.051,324.818 cw(c172.971,324.739) 173.051,324.659 172.903,324.511 172.403,324.012 ccw(c172.482,323.933) 172.403,323.854 172.562,323.695 ccw(c172.641,323.775) 172.72,323.695 173.219,324.195 173.367,324.343 cw(c173.446,324.264) 173.526,324.343 173.684,324.184 cw(c173.605,324.105) 173.684,324.026 173.536,323.878 173.037,323.379 ccw(c173.116,323.3) 173.037,323.22 173.195,323.062 ccw(c173.274,323.141) 173.353,323.062 173.853,323.562 174.001,323.71 cw(c174.08,323.63) 174.159,323.71 174.317,323.551 cw(c174.238,323.472) 174.317,323.393 174.169,323.245 173.67,322.746 ccw(c173.749,322.666) 173.67,322.587 173.828,322.429 ccw(c173.907,322.508) 173.986,322.429 174.486,322.928 174.7,323.142 cw(c174.779,323.063) 174.858,323.142 175.016,322.984 cw(c174.937,322.905) 175.016,322.825 174.882,322.691 ccw(c174.961,322.612) 174.882,322.532 175.235,322.179 175.248,322.166 175.248,321.379 175.397,321.23 175.397,315.539 v1(176.909,314.027)
DDR4_DQ47: U1.P24 U9.D4 | length 32.2
  L1 w0.116: U9.D4@167.676,330.46 v2(168.079,330.057) ; v1(174.909,312.027) U1.P24@175.397,311.539
  L12 (Sign) w0.092: v2(168.079,330.057) 167.676,329.653 167.676,325.704 167.676,325.501 cw(c167.551,325.501) 167.551,325.376 167.434,325.376 ccw(c167.434,325.252) 167.31,325.252 167.31,325.003 ccw(c167.434,325.003) 167.434,324.878 167.676,324.878 168.725,324.878 cw(c168.725,324.753) 168.85,324.753 168.85,324.504 cw(c168.725,324.504) 168.725,324.379 167.8,324.379 ccw(c167.8,324.255) 167.676,324.255 167.676,324.13 167.764,324.042 ccw(c167.852,324.13) 167.94,324.042 167.948,324.049 cw(c168.036,323.961) 168.124,324.049 168.3,323.873 cw(c168.212,323.785) 168.3,323.697 168.205,323.601 168.109,323.505 ccw(c168.197,323.417) 168.109,323.329 168.285,323.153 ccw(c168.373,323.241) 168.461,323.153 168.557,323.249 168.653,323.344 cw(c168.741,323.256) 168.829,323.344 169.005,323.168 cw(c168.917,323.08) 169.005,322.992 168.91,322.896 168.814,322.8 ccw(c168.902,322.712) 168.814,322.624 168.99,322.448 ccw(c169.078,322.536) 169.167,322.448 169.262,322.543 169.358,322.639 cw(c169.446,322.551) 169.534,322.639 169.71,322.463 cw(c169.622,322.375) 169.71,322.287 169.615,322.191 169.519,322.095 ccw(c169.607,322.007) 169.519,321.919 169.695,321.743 ccw(c169.784,321.831) 169.872,321.743 169.967,321.838 170.063,321.934 cw(c170.151,321.846) 170.239,321.934 170.416,321.758 cw(c170.327,321.67) 170.416,321.581 170.32,321.486 170.224,321.39 ccw(c170.312,321.302) 170.224,321.214 170.401,321.037 ccw(c170.489,321.126) 170.577,321.037 170.672,321.133 170.768,321.229 cw(c170.856,321.141) 170.944,321.229 171.121,321.053 cw(c171.033,320.964) 171.121,320.876 171.025,320.781 170.929,320.685 ccw(c171.018,320.597) 170.929,320.509 171.106,320.332 ccw(c171.194,320.421) 171.282,320.332 171.378,320.428 171.473,320.524 cw(c171.561,320.436) 171.65,320.524 171.826,320.347 cw(c171.738,320.259) 171.826,320.171 171.73,320.075 171.635,319.98 ccw(c171.723,319.892) 171.635,319.804 171.811,319.627 ccw(c171.899,319.715) 171.987,319.627 171.995,319.635 cw(c172.083,319.547) 172.171,319.635 172.344,319.461 172.892,318.913 172.892,318.789 ccw(c173.017,318.789) 173.017,318.664 173.415,318.664 cw(c173.415,318.539) 173.539,318.539 173.539,318.29 cw(c173.415,318.29) 173.415,318.165 172.892,318.165 172.648,318.165 ccw(c172.648,318.041) 172.524,318.041 172.524,317.792 ccw(c172.648,317.792) 172.648,317.667 172.768,317.667 cw(c172.768,317.542) 172.892,317.542 172.892,316.903 172.892,316.59 173.077,316.405 173.077,315.134 174.033,314.178 174.033,312.2 174.205,312.027 v1(174.909,312.027)
DDR4_DQ48: U1.U26 U11.G2 | length 29.3
  L1 w0.116: v4(177.91,314.027) U1.U26@178.397,313.539 ; U11.G2@183.136,332.86 v4(183.54,332.457)
  L3 (Sign) w0.092: v4(177.91,314.027) 177.875,314.062 177.875,315.495 177.001,316.369 177.001,316.841 178.003,317.843 178.003,318.452 183.466,323.916 183.466,328.874 183.212,329.129 183.212,330.646 182.591,331.267 181.813,331.267 cw(c181.813,331.572) 181.508,331.572 181.508,332.13 ccw(c181.318,332.13) 181.318,332.321 180.823,332.321 cw(c180.823,332.475) 180.668,332.475 180.668,332.726 cw(c180.823,332.726) 180.823,332.88 180.835,332.88 180.915,332.88 ccw(c180.915,332.999) 181.034,332.999 181.034,333.006 cw(c181.153,333.006) 181.153,333.125 181.312,333.125 cw(c181.312,333.006) 181.431,333.006 181.431,332.999 ccw(c181.55,332.999) 181.55,332.88 181.839,332.88 182.155,332.88 cw(c182.155,332.688) 182.347,332.688 182.347,332.181 ccw(c182.474,332.181) 182.474,332.054 183.403,332.054 ccw(c183.403,332.192) 183.54,332.192 v4(183.54,332.457) ; v4(183.54,332.457) v4@183.54,332.464
DDR4_DQ49: U1.V26 U11.F4 | length 28.9
  L1 w0.116: U11.F4@179.136,332.06 179.533,331.664 v4(179.533,331.662) ; U1.V26@179.397,313.539 v4(179.884,314.027)
  L3 (Sign) w0.092: v4(179.533,331.662) 179.533,331.657 179.794,331.657 cw(c179.794,331.541) 179.909,331.541 179.909,330.924 ccw(c180.062,330.924) 180.062,330.772 180.141,330.772 ccw(c180.141,330.891) 180.26,330.891 180.26,330.923 cw(c180.379,330.923) 180.379,331.042 180.538,331.042 cw(c180.538,330.923) 180.657,330.923 180.657,330.772 180.657,330.62 ccw(c180.776,330.62) 180.776,330.501 180.935,330.501 ccw(c180.935,330.62) 181.054,330.62 181.054,330.652 cw(c181.173,330.652) 181.173,330.772 181.316,330.772 182.538,330.772 182.828,330.482 182.828,328.97 183.058,328.739 183.058,324.1 179.478,320.521 179.478,320.517 178.95,319.988 178.945,319.988 177.597,318.639 177.597,317.98 176.617,317 176.617,316.138 177.491,315.264 177.491,314.333 177.397,314.239 177.397,313.814 177.775,313.436 178.435,313.436 178.676,313.677 179.535,313.677 v4(179.884,314.027)
DDR4_DQ50: U1.U28 U11.H3 | length 28.8
  L1 w0.116: U1.U28@178.397,315.539 v4(178.884,315.052) ; U11.H3@182.336,333.66 v4(182.74,333.257)
  L3 (Sign) w0.092: v4(178.884,315.052) 179.397,315.565 179.397,316.049 179.531,316.183 179.755,316.407 ccw(c179.699,316.464) 179.755,316.52 179.58,316.695 cw(c179.637,316.751) 179.58,316.807 179.749,316.975 cw(c179.805,316.919) 179.861,316.975 180.092,316.744 181.101,315.736 ccw(c181.157,315.792) 181.213,315.736 181.382,315.904 ccw(c181.325,315.96) 181.382,316.016 180.429,316.969 cw(c180.485,317.025) 180.429,317.081 180.513,317.165 180.513,318.11 180.751,318.348 181.126,318.348 185.343,322.565 185.343,332.829 184.762,333.411 184.111,333.411 183.752,333.77 183.246,333.77 182.74,333.264 v4(182.74,333.257)
DDR4_DQ51: U1.V27 U11.H4 | length 28.5
  L1 w0.116: v4(178.91,314.052) U1.V27@179.397,314.539 ; U11.H4@179.136,333.66 v4(179.54,333.257)
  L3 (Sign) w0.092: v4(178.91,314.052) 178.884,314.026 178.529,314.026 178.208,313.706 177.777,313.706 177.589,313.894 177.589,314.16 177.683,314.254 177.683,315.344 176.809,316.218 176.809,316.92 177.789,317.9 177.789,318.56 179.025,319.796 179.029,319.796 179.67,320.437 179.67,320.442 183.274,324.045 183.274,328.795 183.02,329.049 183.02,330.561 182.617,330.963 181.316,330.963 181.064,331.216 180.895,331.384 cw(c180.98,331.469) 180.895,331.553 180.968,331.625 ccw(c180.884,331.71) 180.968,331.794 180.856,331.906 ccw(c180.771,331.822) 180.687,331.906 180.53,331.749 180.434,331.653 cw(c180.35,331.738) 180.266,331.653 180.154,331.766 cw(c180.238,331.85) 180.154,331.934 180.166,331.946 ccw(c180.081,332.03) 180.166,332.114 180.109,332.17 179.87,332.41 179.87,332.926 ccw(c179.54,332.926) v4(179.54,333.257) v4@179.54,333.261
DDR4_DQ52: U1.U30 U11.H2 | length 26
  L1 w0.116: U1.U30@178.397,317.539 v4(178.884,318.027) ; U11.H2@183.136,333.66 v4(183.54,333.257)
  L3 (Sign) w0.092: v4(178.884,318.027) 179.102,318.027 179.349,318.274 179.411,318.335 ccw(c179.349,318.396) 179.411,318.457 179.401,318.467 cw(c179.462,318.528) 179.401,318.59 179.523,318.712 cw(c179.585,318.651) 179.646,318.712 179.717,318.641 179.787,318.57 ccw(c179.849,318.631) 179.91,318.57 180.032,318.693 ccw(c179.971,318.754) 180.032,318.815 179.961,318.886 179.891,318.957 cw(c179.952,319.018) 179.891,319.079 180.013,319.202 cw(c180.074,319.14) 180.135,319.202 180.206,319.131 180.277,319.06 ccw(c180.338,319.121) 180.399,319.06 180.522,319.182 ccw(c180.461,319.243) 180.522,319.305 180.451,319.375 180.38,319.446 cw(c180.441,319.508) 180.38,319.569 180.503,319.691 cw(c180.564,319.63) 180.625,319.691 180.696,319.62 180.767,319.549 ccw(c180.828,319.611) 180.889,319.549 181.011,319.672 ccw(c180.95,319.733) 181.011,319.794 180.941,319.865 180.87,319.936 cw(c180.931,319.997) 180.87,320.058 180.992,320.181 cw(c181.053,320.12) 181.115,320.181 181.185,320.11 181.256,320.039 ccw(c181.317,320.1) 181.379,320.039 181.501,320.161 ccw(c181.44,320.223) 181.501,320.284 181.43,320.355 181.359,320.426 cw(c181.421,320.487) 181.359,320.548 181.482,320.67 cw(c181.543,320.609) 181.604,320.67 181.675,320.599 181.746,320.529 ccw(c181.807,320.59) 181.868,320.529 181.991,320.651 ccw(c181.929,320.712) 181.991,320.773 181.92,320.844 181.849,320.915 cw(c181.91,320.976) 181.849,321.038 181.971,321.16 cw(c182.033,321.099) 182.094,321.16 182.165,321.089 182.235,321.018 ccw(c182.297,321.079) 182.358,321.018 182.48,321.141 ccw(c182.419,321.202) 182.48,321.263 182.471,321.273 cw(c182.532,321.334) 182.471,321.395 182.563,321.487 183.968,322.892 184.478,322.892 184.959,323.373 184.959,327.605 184.841,327.724 184.841,328.142 ccw(c184.544,328.142) 184.544,328.439 184.526,328.439 cw(c184.526,328.828) 184.136,328.828 184.136,328.933 cw(c184.468,328.933) 184.468,329.264 184.586,329.264 ccw(c184.586,329.552) 184.874,329.552 184.874,330.67 ccw(c184.64,330.67) 184.64,330.904 184.256,330.904 cw(c184.256,331.047) 184.112,331.047 184.112,331.491 cw(c184.307,331.491) 184.307,331.686 184.709,331.686 ccw(c184.709,331.864) 184.887,331.864 184.887,332.29 ccw(c184.703,332.29) 184.703,332.473 184.188,332.473 cw(c184.188,332.626) 184.036,332.626 184.036,332.761 v4(183.54,333.257)
DDR4_DQ53: U1.V30 U11.H5 | length 26.1
  L1 w0.116: U11.H5@178.336,333.66 v4(178.74,334.064) ; U1.V30@179.397,317.539 v4(179.884,318.027)
  L3 (Sign) w0.092: v4(178.74,334.064) 179.143,333.66 179.66,333.66 179.933,333.388 179.943,333.388 180.139,333.388 ccw(c180.139,333.518) 180.269,333.518 180.269,333.574 cw(c180.399,333.574) 180.399,333.704 180.79,333.704 cw(c180.79,333.574) 180.92,333.574 180.92,333.518 ccw(c181.05,333.518) 181.05,333.388 181.458,333.388 182.155,333.388 182.607,332.936 182.873,332.936 183.061,333.124 183.061,333.269 183.37,333.578 183.673,333.578 184.031,333.219 184.682,333.219 185.151,332.75 185.151,323.294 v4(179.884,318.027)
DDR4_DQ54: U1.W30 U11.J3 | length 25.7
  L1 w0.116: U1.W30@180.397,317.539 v4(180.884,318.027) ; v4(181.933,334.057) U11.J3@182.336,334.46
  L3 (Sign) w0.092: v4(180.884,318.027) 180.913,318.056 181.34,318.056 183.159,319.875 183.935,320.651 cw(c183.991,320.595) 184.048,320.651 184.083,320.615 ccw(c184.139,320.671) 184.196,320.615 184.364,320.784 ccw(c184.308,320.84) 184.364,320.896 184.272,320.988 184.219,321.04 cw(c184.276,321.097) 184.219,321.153 184.388,321.321 cw(c184.444,321.265) 184.5,321.321 184.553,321.268 184.645,321.177 ccw(c184.701,321.233) 184.757,321.177 184.925,321.345 ccw(c184.869,321.401) 184.925,321.457 184.834,321.549 184.781,321.602 cw(c184.837,321.658) 184.781,321.714 184.949,321.883 cw(c185.005,321.826) 185.062,321.883 185.114,321.83 185.206,321.738 ccw(c185.262,321.794) 185.318,321.738 185.487,321.906 ccw(c185.431,321.963) 185.487,322.019 185.451,322.054 cw(c185.507,322.111) 185.451,322.167 185.535,322.251 185.535,332.909 184.841,333.604 184.19,333.604 183.832,333.962 183.166,333.962 182.833,333.629 181.445,333.629 181.241,333.833 181.241,334.027 181.391,334.177 181.813,334.177 v4(181.933,334.057)
DDR4_DQ55: U1.W29 U11.J4 | length 26.2
  L1 w0.116: U11.J4@179.136,334.46 v4(179.54,334.057) ; U1.W29@180.403,316.535 v4(180.891,317.022)
  L3 (Sign) w0.092: v4(179.54,334.057) 179.943,334.46 184.256,334.46 185.727,332.989 185.727,321.859 v4(180.891,317.022)
DDR4_DQ56: U1.R30 U11.A3 | length 19.4
  L1 w0.116: U1.R30@176.397,317.539 v4(176.397,318.229) ; v4(181.937,327.664) 181.94,327.664 U11.A3@182.336,328.06
  L3 (Sign) w0.092: v4(176.397,318.229) 176.446,318.278 176.692,318.278 178.786,320.372 178.791,320.372 179.094,320.676 179.094,320.68 180.95,322.535 180.95,322.643 180.95,322.839 ccw(c180.819,322.839) 180.819,322.969 180.529,322.969 cw(c180.529,323.099) 180.399,323.099 180.399,323.49 cw(c180.529,323.49) 180.529,323.62 180.95,323.62 181.37,323.62 ccw(c181.37,323.75) 181.5,323.75 181.5,324.141 ccw(c181.37,324.141) 181.37,324.271 180.95,324.271 180.529,324.271 cw(c180.529,324.401) 180.399,324.401 180.399,324.792 cw(c180.529,324.792) 180.529,324.922 180.95,324.922 181.37,324.922 ccw(c181.37,325.052) 181.5,325.052 181.5,325.443 ccw(c181.37,325.443) 181.37,325.573 180.95,325.573 180.529,325.573 cw(c180.529,325.703) 180.399,325.703 180.399,326.094 cw(c180.529,326.094) 180.529,326.224 180.95,326.224 181.37,326.224 ccw(c181.37,326.354) 181.5,326.354 181.5,326.745 ccw(c181.37,326.745) 181.37,326.875 181.08,326.875 cw(c181.08,327.005) 180.95,327.005 180.95,327.393 180.95,327.406 181.208,327.664 v4(181.937,327.664)
DDR4_DQ57: U1.T30 U11.B5 | length 18.9
  L1 w0.116: v4(176.91,318.027) U1.T30@177.397,317.539 ; U11.B5@178.336,328.86 v4(178.733,328.462)
  L3 (Sign) w0.092: v4(176.91,318.027) 176.446,317.563 175.874,317.563 175.514,317.924 175.514,318.275 176.023,318.783 176.655,318.783 179.464,321.592 179.464,322.351 179.464,323.598 ccw(c179.354,323.598) 179.354,323.708 179.239,323.708 cw(c179.239,323.818) 179.129,323.818 179.129,324.147 cw(c179.239,324.147) 179.239,324.257 179.464,324.257 179.637,324.257 ccw(c179.637,324.367) 179.746,324.367 179.746,324.697 ccw(c179.637,324.697) 179.637,324.807 179.464,324.807 179.239,324.807 cw(c179.239,324.916) 179.129,324.916 179.129,325.246 cw(c179.239,325.246) 179.239,325.356 179.464,325.356 179.637,325.356 ccw(c179.637,325.466) 179.746,325.466 179.746,325.796 ccw(c179.637,325.796) 179.637,325.905 179.464,325.905 179.239,325.905 cw(c179.239,326.015) 179.129,326.015 179.129,326.345 cw(c179.239,326.345) 179.239,326.455 179.464,326.455 179.637,326.455 ccw(c179.637,326.565) 179.746,326.565 179.746,326.894 ccw(c179.637,326.894) 179.637,327.004 179.574,327.004 cw(c179.574,327.114) 179.464,327.114 179.464,327.279 178.733,328.01 v4(178.733,328.462)
DDR4_DQ58: U1.P30 U11.C3 | length 19
  L1 w0.116: U1.P30@175.397,317.539 v4(175.884,318.027) ; v4(181.937,329.264) 181.94,329.264 U11.C3@182.336,329.66
  L3 (Sign) w0.092: v4(175.884,318.027) 175.884,318.339 176.136,318.591 176.734,318.591 178.707,320.564 178.711,320.564 178.902,320.755 178.902,320.76 179.959,321.816 179.959,327.139 179.959,327.577 cw(c180.069,327.577) 180.069,327.687 180.448,327.687 ccw(c180.448,327.797) 180.558,327.797 180.558,328.126 ccw(c180.448,328.126) 180.448,328.236 180.069,328.236 cw(c180.069,328.346) 179.959,328.346 179.959,328.511 179.959,329.105 180.118,329.264 180.283,329.264 ccw(c180.283,329.374) 180.393,329.374 180.393,329.611 cw(c180.503,329.611) 180.503,329.721 180.832,329.721 cw(c180.832,329.611) 180.942,329.611 180.942,329.264 180.942,328.917 ccw(c181.052,328.917) 181.052,328.807 181.382,328.807 ccw(c181.382,328.917) 181.492,328.917 181.492,329.154 cw(c181.602,329.154) 181.602,329.264 v4(181.937,329.264)
DDR4_DQ59: U1.P29 U11.C4 | length 19.6
  L1 w0.116: v4(174.91,317.027) U1.P29@175.397,316.539 ; v4@178.74,330.057 U11.C4@179.136,329.66
  L3 (Sign) w0.092: v4(174.91,317.027) 174.884,317.052 174.884,317.556 175.119,317.791 175.119,318.469 175.828,319.178 176.506,319.178 177.825,320.497 177.825,322.77 177.825,322.987 ccw(c177.716,322.987) 177.716,323.097 177.596,323.097 cw(c177.596,323.207) 177.486,323.207 177.486,323.537 cw(c177.596,323.537) 177.596,323.647 177.825,323.647 178.055,323.647 ccw(c178.055,323.757) 178.165,323.757 178.165,324.086 ccw(c178.055,324.086) 178.055,324.196 177.825,324.196 177.596,324.196 cw(c177.596,324.306) 177.486,324.306 177.486,324.636 cw(c177.596,324.636) 177.596,324.745 177.825,324.745 178.055,324.745 ccw(c178.055,324.855) 178.165,324.855 178.165,325.185 ccw(c178.055,325.185) 178.055,325.295 177.935,325.295 cw(c177.935,325.405) 177.825,325.405 177.825,325.57 178.219,325.963 178.219,326.128 ccw(c178.109,326.128) 178.109,326.238 177.964,326.238 cw(c177.964,326.348) 177.854,326.348 177.854,326.677 cw(c177.964,326.677) 177.964,326.787 178.219,326.787 178.413,326.787 ccw(c178.413,326.897) 178.522,326.897 178.522,327.227 ccw(c178.413,327.227) 178.413,327.337 178.329,327.337 cw(c178.329,327.447) 178.219,327.447 178.219,327.749 178.219,329.136 178.74,329.656 v4@178.74,330.057
  other v4: 178.74,330.059
DDR4_DQ60: U1.T28 U11.C2 | length 20.4
  L1 w0.116: U1.T28@177.397,315.539 v4(177.884,316.027) ; U11.C2@183.136,329.66 v4(183.533,329.262) v4(183.533,329.262)
  L3 (Sign) w0.092: v4(177.884,316.027) 177.884,315.772 178.118,315.539 178.118,315.024 ccw(c178.27,315.024) 178.27,314.871 178.397,314.871 ccw(c178.397,315.024) 178.549,315.024 178.549,315.633 178.41,315.773 178.41,316.116 178.41,316.202 ccw(c178.323,316.202) 178.323,316.289 178.072,316.289 cw(c178.072,316.375) 177.985,316.375 177.985,316.548 cw(c178.072,316.548) 178.072,316.635 178.323,316.635 ccw(c178.323,316.722) 178.41,316.722 178.41,316.916 178.41,317.498 178.206,317.701 178.206,318.352 183.709,323.855 183.709,329.085 v4(183.533,329.262)
DDR4_DQ61: U1.T27 U11.C5 | length 21
  L1 w0.116: v4(176.91,315.027) U1.T27@177.397,314.539 ; v4@177.94,330.057 U11.C5@178.336,329.66
  L3 (Sign) w0.092: v4(176.91,315.027) 176.589,314.706 175.777,314.706 175.33,315.152 174.224,315.152 174.001,315.375 174.001,315.381 173.988,315.394 173.988,316.016 173.809,316.195 173.809,318.081 176.109,320.381 176.109,324.852 177.47,326.213 177.47,328.93 177.94,329.399 v4@177.94,330.057
  other v4: 177.94,330.059
DDR4_DQ62: U1.P27 U11.D3 | length 22.8
  L1 w0.116: U1.P27@175.397,314.539 v4(175.884,314.052) ; v4(181.937,330.064) 181.94,330.064 U11.D3@182.336,330.46
  L3 (Sign) w0.092: v4(175.884,314.052) 176.346,314.514 176.668,314.514 176.706,314.552 177.138,314.552 177.299,314.713 177.299,315.182 176.403,316.078 176.403,317.036 176.425,317.058 176.425,317.079 177.405,318.059 177.405,318.719 178.866,320.18 178.87,320.18 179.286,320.596 179.286,320.601 182.266,323.58 182.266,323.875 182.266,324.663 182.266,325.61 ccw(c182.136,325.61) 182.136,325.74 181.908,325.74 cw(c181.908,325.871) 181.778,325.871 181.778,326.261 cw(c181.908,326.261) 181.908,326.391 182.266,326.391 182.624,326.391 ccw(c182.624,326.522) 182.754,326.522 182.754,326.912 ccw(c182.624,326.912) 182.624,327.042 182.396,327.042 cw(c182.396,327.173) 182.266,327.173 182.266,327.368 182.266,329.735 v4(181.937,330.064)
DDR4_DQ63: U1.R27 U11.D4 | length 22.1
  L1 w0.116: v4(175.91,315.027) U1.R27@176.397,314.539 ; U11.D4@179.136,330.46 179.533,330.857 v4(179.535,330.857)
  L3 (Sign) w0.092: 175.514,315.862 175.514,315.422 v4(175.91,315.027) ; 175.514,315.863 175.514,317.577 175.311,317.779 175.311,318.389 175.908,318.986 176.586,318.986 178.714,321.115 178.714,321.279 cw(c178.824,321.279) 178.824,321.389 178.914,321.389 ccw(c178.914,321.499) 179.024,321.499 179.024,321.829 ccw(c178.914,321.829) 178.914,321.939 178.714,321.939 178.447,321.939 cw(c178.447,322.049) 178.337,322.049 178.337,322.378 cw(c178.447,322.378) 178.447,322.488 178.714,322.488 178.982,322.488 ccw(c178.982,322.598) 179.092,322.598 179.092,322.928 ccw(c178.982,322.928) 178.982,323.038 178.714,323.038 178.447,323.038 cw(c178.447,323.147) 178.337,323.147 178.337,323.477 cw(c178.447,323.477) 178.447,323.587 178.605,323.587 ccw(c178.605,323.697) 178.714,323.697 178.714,325.374 178.714,326.123 178.714,327.532 178.412,327.835 178.412,328.729 179.535,329.852 v4(179.535,330.857)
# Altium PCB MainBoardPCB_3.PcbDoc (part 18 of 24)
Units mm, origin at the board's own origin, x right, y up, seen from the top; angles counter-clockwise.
Board outline 258.95 x 308.86 mm, 16 copper layers (L1, L2 (GND), L3 (Sign), L4 (GND), L5 (Sign), L6 (PWR/GND), L7(PWR/GND), L8 (Plane_GND), L9 (PWR/GND), L10 (PWR/GND), L11 (PWR/GND), L12 (Sign), L13 (GND), L14 (Sign), L15 (GND), L16), stack 2.502 mm thick; 2402 components, 1749 nets, 8407 pads, 3409 vias.
Unrouted connection lines stored in the file: 4352.

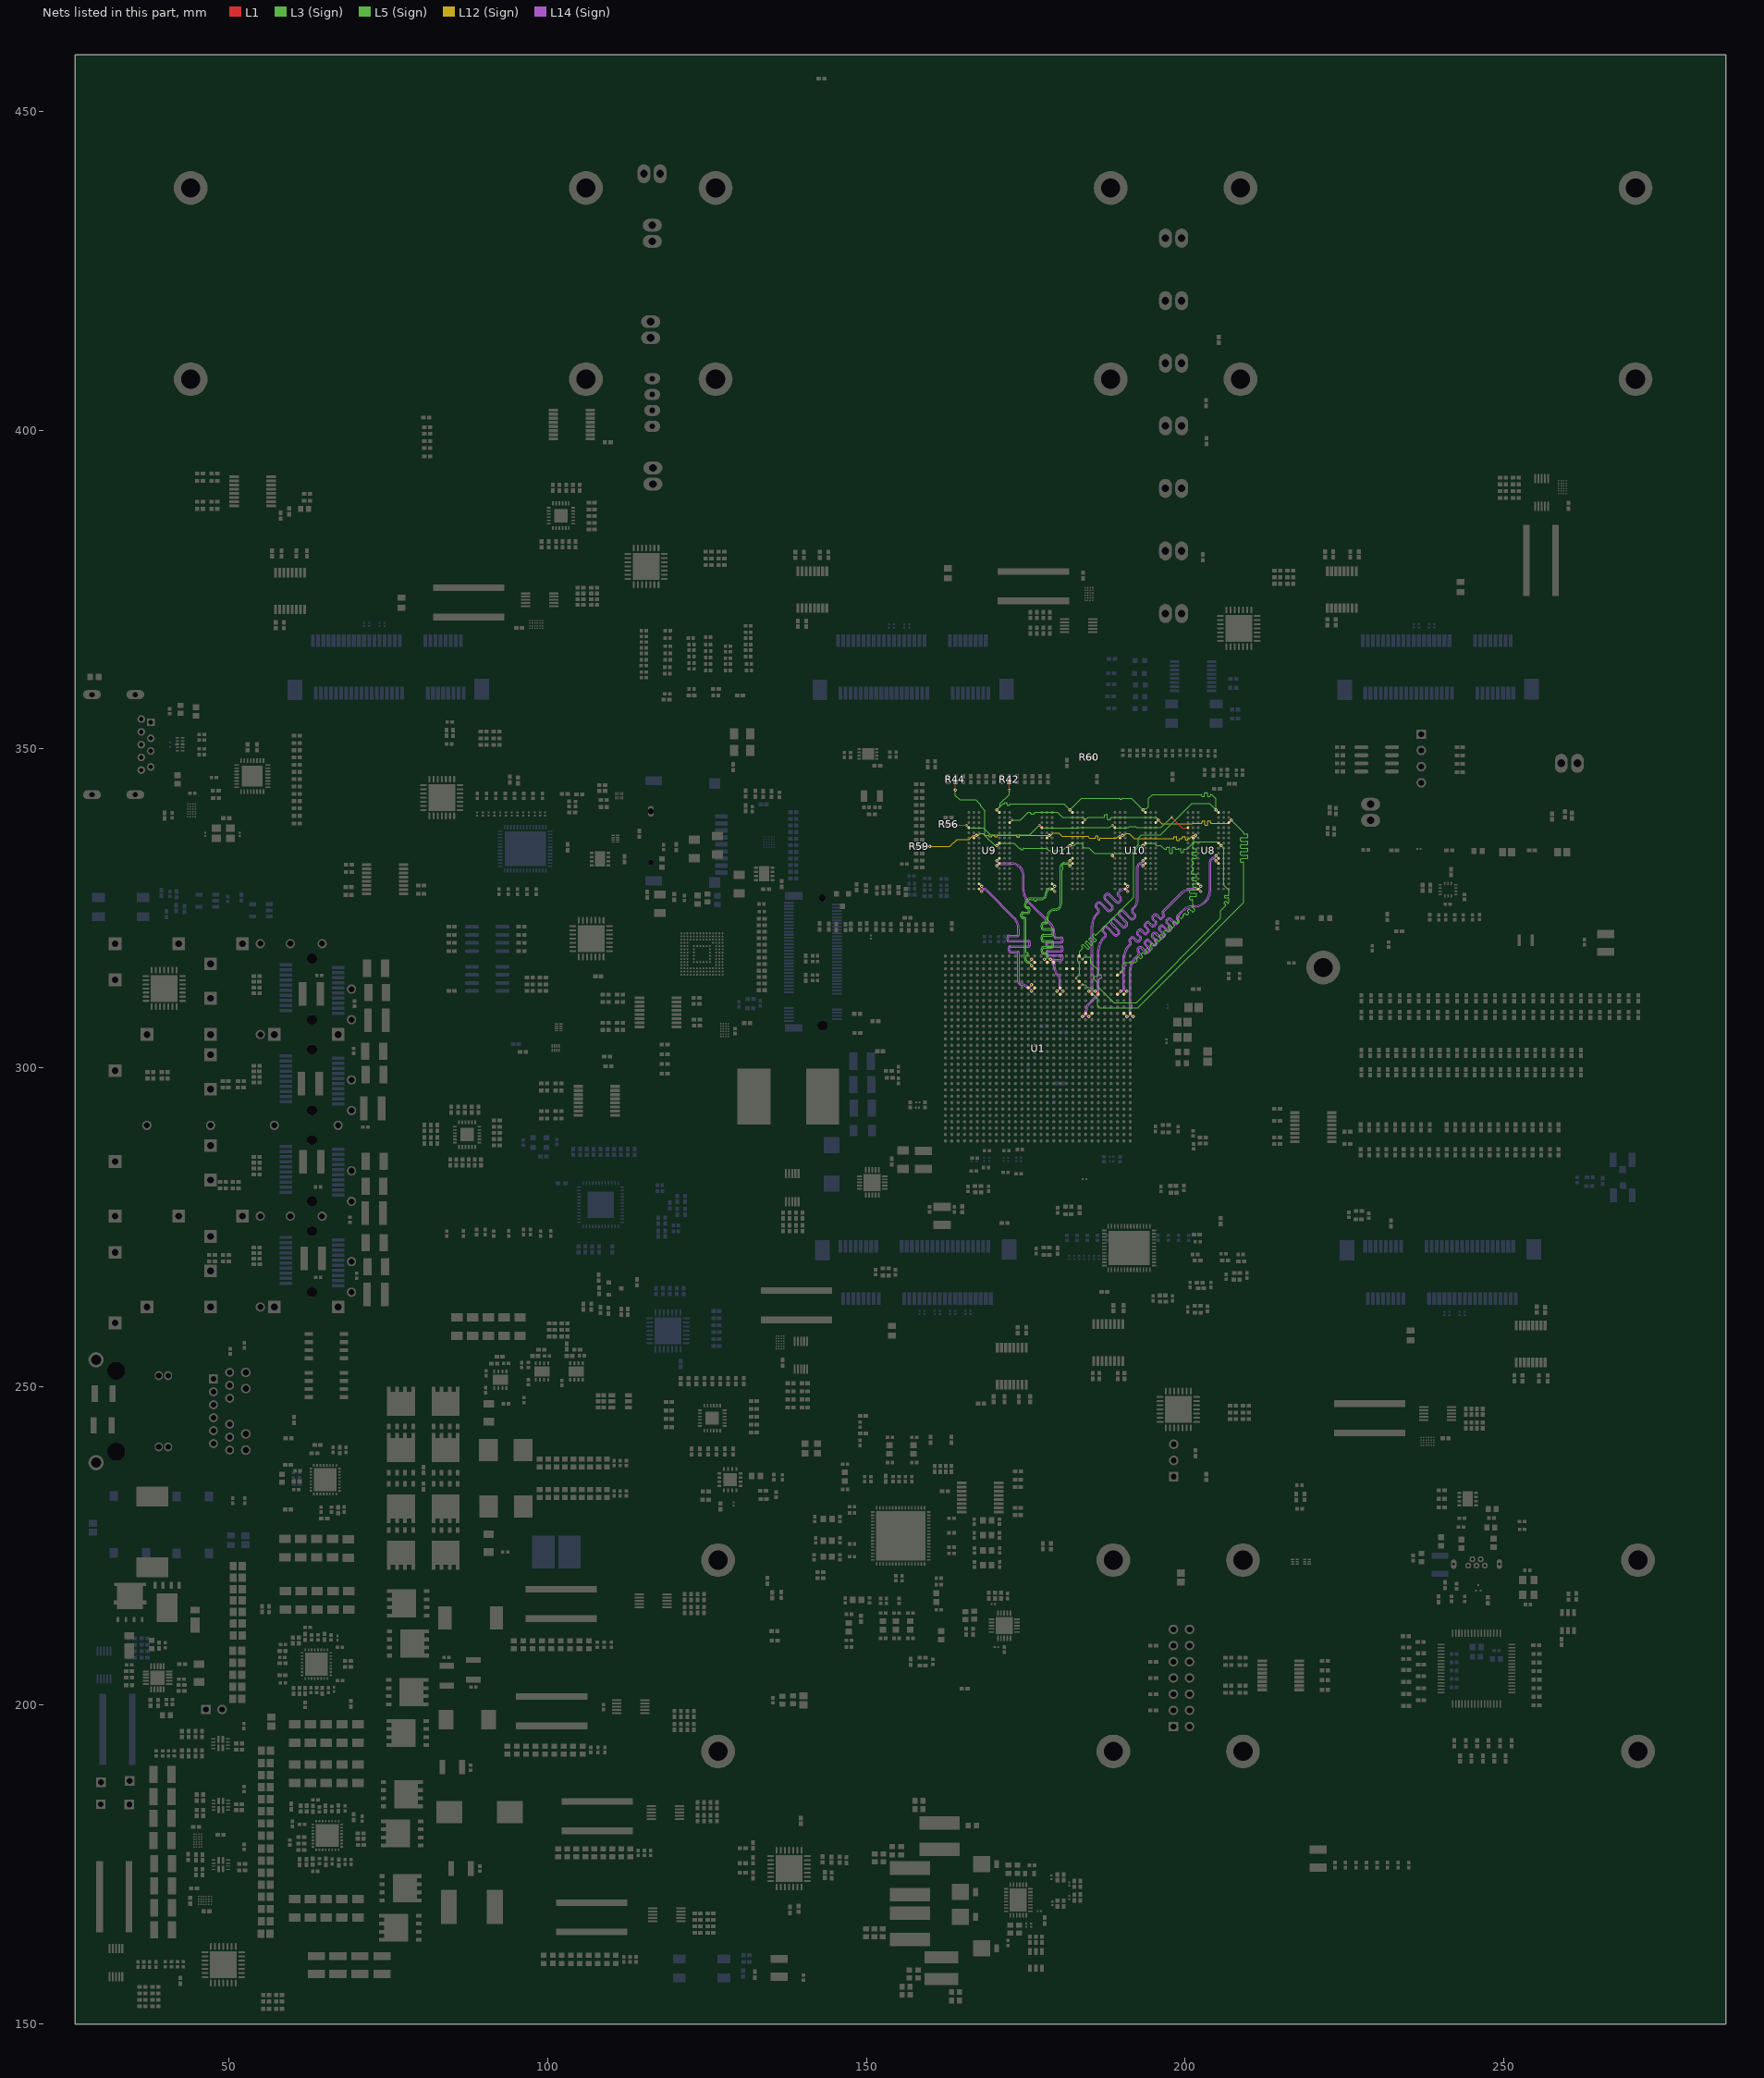
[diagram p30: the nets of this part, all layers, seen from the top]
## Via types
v1: diameter 0.5, hole 0.2, L1 to L16, tented both sides, 1267 vias
v2: diameter 0.5/0.35/0.35/0.35/0.35/0.35/0.35/0.35/0.35/0.35/0.35/0.35/0.35/0.35/0.35/0.5 (per signal layer), hole 0.15, L1 to L16, tented both sides, 463 vias
v3: diameter 0.5, hole 0.2, L1 to L16, 446 vias
v4: diameter 0.35/0/0.35 (per signal layer), hole 0.127, L1 to L3 (Sign), tented both sides, 347 vias
v5: diameter 0.5/0.35/0.35/0.35/0.35/0.35/0.35/0.35/0.35/0.35/0.35/0.35/0.35/0.35/0.35/0.5 (per signal layer), hole 0.2, L1 to L16, tented both sides, 244 vias
v6: diameter 0.8, hole 0.4, L1 to L16, tented both sides, 168 vias
v7: diameter 2.54, hole 1.02, L1 to L16, 113 vias
v8: diameter 1.4, hole 0.5, L1 to L16, tented both sides, 80 vias
v9: diameter 0.5/0/0.5 (per signal layer), hole 0.2, L14 (Sign) to L16, tented both sides, 62 vias
v10: diameter 0.35/0/0.35 (per signal layer), hole 0.127, L1 to L3 (Sign), 38 vias
v11: diameter 0.35, hole 0.127, L1 to L2 (GND), tented both sides, 36 vias
v12: diameter 0.4, hole 0.2, L1 to L16, 16 vias
v13: diameter 0.25, hole 0.2, L1 to L16, 16 vias
v14: diameter 0.35, hole 0.127, L1 to L16, tented both sides, 16 vias
v15: diameter 0.3, hole 0.2, L1 to L16, 15 vias
v16: diameter 0.45, hole 0.15, L1 to L16, 12 vias
v17: diameter 0.5/0.35/0.35/0.35/0.35/0.35/0.35/0.35/0.35/0.35/0.35/0.35/0.35/0.35/0.35/0.45 (per signal layer), hole 0.15, L1 to L16, tented both sides, 10 vias
v18: diameter 0.2/0/0.2 (per signal layer), hole 0.1, L1 to L3 (Sign), tented both sides, 9 vias
v19: diameter 0.4, hole 0.1, L1 to L16, 7 vias
v20: diameter 0.5, hole 0.2, L3 (Sign) to L6 (PWR/GND), tented both sides, 6 vias
v21: diameter 1.15, hole 1.15, L1 to L16, 5 vias
v22: diameter 1.65, hole 1.65, L1 to L16, 5 vias
v23: diameter 0.35/0/0.35 (per signal layer), hole 0.127, L14 (Sign) to L16, tented both sides, 5 vias
v24: diameter 0.5, hole 0.2, L11 (PWR/GND) to L14 (Sign), tented both sides, 4 vias
v25: diameter 0.2, hole 0.1, L1 to L16, 4 vias
v26: diameter 0.35, hole 0.127, L1 to L2 (GND), 2 vias
v27: diameter 0.4, hole 0.15, L1 to L16, 2 vias
v28: diameter 0.4, hole 0.2, L1 to L16, tented both sides, 2 vias
v29: diameter 0.5/0.35/0.35/0.35/0.35/0.35/0.35/0.35/0.35/0.35/0.35/0.35/0.35/0.35/0.35/0.5 (per signal layer), hole 0.15, L1 to L16, 2 vias
v30: diameter 0.35, hole 0.127, L3 (Sign) to L6 (PWR/GND), tented both sides, 2 vias
v31: diameter 0.5/0.35/0.35/0.35/0.35/0.35/0.35/0.35/0.35/0.35/0.35/0.35/0.35/0.35/0.35/0.5 (per signal layer), hole 0.2, L1 to L16, 1 vias
v32: diameter 0.35/0.35/0.35 (per signal layer), hole 0.127, L1 to L3 (Sign), tented both sides, 1 vias
v33: diameter 0.45/0/0.45 (per signal layer), hole 0.15, L1 to L3 (Sign), tented both sides, 1 vias
v34: diameter 0.45/0/0.45 (per signal layer), hole 0.2, L14 (Sign) to L16, tented both sides, 1 vias
v35: diameter 0.35, hole 0.127, L2 (GND) to L3 (Sign), 1 vias

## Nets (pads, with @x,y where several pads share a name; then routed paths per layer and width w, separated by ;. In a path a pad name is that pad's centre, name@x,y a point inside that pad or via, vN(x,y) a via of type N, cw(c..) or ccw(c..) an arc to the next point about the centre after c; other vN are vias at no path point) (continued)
DDR4_DQS_0_N: U1.AK21 U8.F3 | length 45.3
  L1 w0.116: U1.AK21@191.397,308.539 v5(191.884,308.052) ; v2(204.853,332.464) U8.F3@205.257,332.06
  L14 (Sign) w0.105: v5(191.884,308.052) 191.677,308.052 cw(c191.677,308.229) 191.5,308.229 191.5,309.207 191.5,309.33 cw(c191.582,309.33) 191.582,309.412 191.648,309.412 ccw(c191.648,309.494) 191.73,309.494 191.73,309.74 ccw(c191.648,309.74) 191.648,309.822 191.582,309.822 cw(c191.582,309.904) 191.5,309.904 191.5,310.363 191.5,315.274 cw(c194.04,315.274) 192.244,317.07 192.807,317.632 ccw(c192.5,317.939) 192.934,317.939 ccw(c192.5,317.939) 192.807,318.246 192.727,318.326 cw(c192.87,318.468) 192.727,318.611 192.84,318.723 cw(c192.982,318.581) 193.125,318.723 193.733,318.115 ccw(c194.04,318.422) 194.347,318.115 194.459,318.227 ccw(c194.153,318.534) 194.587,318.534 ccw(c194.153,318.534) 194.459,318.841 193.851,319.45 cw(c193.994,319.592) 193.851,319.735 193.964,319.847 cw(c194.106,319.705) 194.249,319.847 194.857,319.239 ccw(c195.164,319.546) 195.471,319.239 195.583,319.351 ccw(c195.277,319.658) 195.71,319.658 ccw(c195.277,319.658) 195.583,319.965 194.975,320.573 ; 194.975,320.859 195.088,320.971 cw(c195.23,320.828) 195.373,320.971 195.981,320.363 ccw(c196.288,320.67) 196.595,320.363 196.707,320.475 ccw(c196.4,320.782) 196.834,320.782 ccw(c196.4,320.782) 196.707,321.089 196.099,321.697 ; 194.975,320.573 cw(c195.118,320.716) 194.975,320.859 ; 196.099,321.982 196.211,322.095 cw(c196.354,321.952) 196.497,322.095 197.105,321.487 ccw(c197.412,321.793) 197.719,321.487 197.831,321.599 ccw(c197.524,321.906) 197.958,321.906 ccw(c197.524,321.906) 197.831,322.213 197.223,322.821 ; 196.099,321.697 cw(c196.242,321.84) 196.099,321.983 ; 197.223,323.106 197.335,323.219 cw(c197.478,323.076) 197.621,323.219 198.229,322.611 ccw(c198.536,322.917) 198.843,322.611 198.955,322.723 ccw(c198.648,323.03) 199.082,323.03 ccw(c198.648,323.03) 198.955,323.337 198.875,323.416 cw(c199.018,323.559) 198.876,323.701 199.652,324.478 cw(c201.448,322.682) 201.448,325.222 201.461,325.222 ccw(c201.461,327.711) 203.222,325.951 203.257,325.986 ccw(c201.301,327.942) 204.067,327.942 204.067,332.324 cw(c204.495,332.324) 204.495,332.753 204.565,332.753 cw(c204.565,332.464) v2(204.853,332.464) ; 197.223,322.821 cw(c197.366,322.964) 197.223,323.107
DDR4_DQS_0_P: U1.AJ21 U8.G3 | length 45.3
  L1 w0.116: U1.AJ21@190.397,308.539 v5(190.884,308.052) ; v2(204.853,333.264) U8.G3@205.257,332.86
  L14 (Sign) w0.105: v5(190.884,308.052) 191.091,308.052 ccw(c191.091,308.229) 191.268,308.229 191.268,315.275 cw(c194.039,315.275) 192.08,317.234 192.643,317.797 ccw(c192.5,317.939) 192.702,317.939 ccw(c192.5,317.939) 192.642,318.082 192.563,318.161 cw(c192.87,318.468) 192.563,318.775 192.675,318.887 cw(c192.982,318.581) 193.289,318.887 193.898,318.279 ccw(c194.04,318.422) 194.183,318.279 194.296,318.392 ; 194.295,318.391 ccw(c194.153,318.534) 194.354,318.534 ccw(c194.153,318.534) 194.295,318.677 ; 194.296,318.677 193.687,319.285 cw(c193.994,319.592) 193.687,319.899 193.799,320.011 cw(c194.106,319.705) 194.413,320.011 195.021,319.403 ccw(c195.164,319.546) 195.307,319.403 195.419,319.516 ; 195.419,319.515 ccw(c195.277,319.658) 195.478,319.658 ccw(c195.277,319.658) 195.419,319.801 ; 195.419,319.801 194.811,320.409 cw(c195.118,320.716) 194.811,321.023 194.923,321.135 cw(c195.23,320.828) 195.537,321.135 196.145,320.527 ccw(c196.288,320.67) 196.431,320.527 196.543,320.639 ccw(c196.4,320.782) 196.602,320.782 ccw(c196.4,320.782) 196.543,320.925 ; 196.543,320.924 195.935,321.533 cw(c196.242,321.84) 195.935,322.147 196.047,322.259 cw(c196.354,321.952) 196.661,322.259 197.269,321.651 ccw(c197.412,321.793) 197.555,321.651 197.667,321.763 ccw(c197.524,321.906) 197.726,321.906 ccw(c197.524,321.906) 197.667,322.049 197.059,322.657 cw(c197.366,322.964) 197.059,323.271 197.171,323.383 cw(c197.478,323.076) 197.785,323.383 198.393,322.775 ccw(c198.536,322.917) 198.679,322.775 198.791,322.887 ccw(c198.648,323.03) 198.85,323.03 ccw(c198.648,323.03) 198.791,323.172 198.712,323.252 cw(c199.018,323.559) 198.712,323.866 199.488,324.642 cw(c201.447,322.683) 201.447,325.454 201.46,325.454 ccw(c201.46,327.714) 203.058,326.116 203.091,326.149 ccw(c201.295,327.945) 203.835,327.945 203.835,332.324 cw(c204.495,332.324) 204.495,332.985 204.574,332.985 ccw(c204.574,333.264) v2(204.853,333.264)
DDR4_DQS_1_N: U1.AJ24 U8.A4 | length 31.6
  L1 w0.116: U1.AJ24@190.397,311.539 v5(190.884,312.027) ; U8.A4@202.057,328.06 v2(202.461,327.657)
  L14 (Sign) w0.105: v5(190.884,312.027) 190.649,312.027 cw(c190.649,312.175) 190.5,312.175 190.5,315.455 190.5,315.635 190.5,315.904 cw(c190.59,315.904) 190.59,315.994 190.676,315.994 ccw(c190.676,316.084) 190.766,316.084 190.766,316.264 ccw(c190.676,316.264) 190.676,316.354 190.59,316.354 cw(c190.59,316.444) 190.5,316.444 190.5,316.514 190.5,317.236 cw(c193.04,317.236) 191.244,319.032 191.483,319.27 ccw(c191.222,319.532) 191.591,319.532 ccw(c191.222,319.532) 191.483,319.793 191.422,319.854 cw(c191.519,319.951) 191.422,320.049 191.661,320.288 cw(c191.758,320.191) 191.856,320.288 192.336,319.807 ccw(c192.598,320.069) 192.859,319.807 193.098,320.046 ccw(c192.837,320.308) 193.207,320.308 ccw(c192.837,320.308) 193.098,320.569 192.618,321.05 cw(c192.715,321.147) 192.618,321.244 192.857,321.484 cw(c192.954,321.386) 193.052,321.484 193.532,321.003 ccw(c193.793,321.265) 194.055,321.003 194.294,321.242 ccw(c194.033,321.504) 194.402,321.504 ccw(c194.033,321.504) 194.294,321.765 193.814,322.246 cw(c193.911,322.343) 193.814,322.44 194.053,322.679 cw(c194.15,322.582) 194.247,322.679 194.728,322.199 ccw(c194.989,322.46) 195.251,322.199 195.49,322.438 ccw(c195.228,322.699) 195.598,322.699 ccw(c195.228,322.699) 195.49,322.961 195.009,323.441 cw(c195.107,323.539) 195.009,323.636 195.248,323.875 cw(c195.346,323.778) 195.443,323.875 195.923,323.395 ccw(c196.185,323.656) 196.446,323.395 196.686,323.634 ccw(c196.424,323.895) 196.794,323.895 ccw(c196.424,323.895) 196.686,324.157 196.625,324.217 cw(c196.722,324.315) 196.625,324.412 199.383,327.17 cw(c201.179,325.374) 201.179,327.914 202.203,327.914 cw(c202.203,327.657) v2(202.461,327.657)
DDR4_DQS_1_P: U1.AH24 U8.B4 | length 31.6
  L1 w0.116: U1.AH24@189.397,311.539 v5(189.884,312.027) ; U8.B4@202.057,328.86 v2(202.461,328.457)
  L14 (Sign) w0.105: v5(189.884,312.027) 190.12,312.027 ccw(c190.12,312.175) 190.268,312.175 190.268,316.514 190.268,317.236 cw(c193.039,317.236) 191.08,319.195 191.319,319.435 ccw(c191.222,319.532) 191.359,319.532 ccw(c191.222,319.532) 191.319,319.629 191.258,319.69 cw(c191.519,319.951) 191.258,320.213 191.497,320.452 cw(c191.758,320.191) 192.02,320.452 192.5,319.971 ccw(c192.598,320.069) 192.695,319.971 192.934,320.211 ccw(c192.837,320.308) 192.974,320.308 ccw(c192.837,320.308) 192.934,320.405 192.454,320.886 cw(c192.715,321.147) 192.454,321.409 192.693,321.648 cw(c192.954,321.386) 193.216,321.648 193.696,321.167 ccw(c193.793,321.265) 193.891,321.167 194.13,321.406 ccw(c194.033,321.504) 194.17,321.504 ccw(c194.033,321.504) 194.13,321.601 193.649,322.081 cw(c193.911,322.343) 193.649,322.604 193.889,322.843 cw(c194.15,322.582) 194.411,322.843 194.892,322.363 ccw(c194.989,322.46) 195.086,322.363 195.326,322.602 ccw(c195.228,322.699) 195.366,322.699 ccw(c195.228,322.699) 195.326,322.797 194.845,323.277 cw(c195.107,323.539) 194.845,323.8 195.084,324.039 cw(c195.346,323.778) 195.607,324.039 196.088,323.559 ccw(c196.185,323.656) 196.282,323.559 196.521,323.798 ccw(c196.424,323.895) 196.562,323.895 ccw(c196.424,323.895) 196.521,323.992 196.46,324.053 cw(c196.722,324.315) 196.46,324.576 199.218,327.334 ; 199.219,327.335 cw(c201.178,325.376) 201.178,328.146 202.15,328.146 ccw(c202.15,328.457) v2(202.461,328.457)
DDR4_DQS_2_N: U1.AD21 U10.F3 | length 41.3
  L1 w0.116: v1(184.909,308.052) U1.AD21@185.397,308.539 ; v2(193.393,331.657) U10.F3@193.797,332.06
  L14 (Sign) w0.105: v1(184.909,308.052) 184.784,308.052 cw(c184.784,308.242) 184.594,308.242 184.594,309.029 cw(c185.855,309.029) 184.964,309.921 186.211,311.168 ccw(c185.422,311.957) 186.538,311.957 186.538,313.271 186.538,313.527 186.538,313.882 cw(c186.694,313.882) 186.694,314.039 ccw(c186.694,314.294) 186.95,314.294 ccw(c186.694,314.294) 186.694,314.55 cw(c186.694,314.706) 186.538,314.706 186.538,315.811 186.538,318.431 cw(c189.078,318.431) 187.282,320.227 187.539,320.485 ccw(c187.204,320.82) 187.678,320.82 ccw(c187.204,320.82) 187.539,321.156 187.231,321.464 cw(c187.402,321.636) 187.231,321.807 187.357,321.934 cw(c187.529,321.762) 187.7,321.934 188.824,320.81 ccw(c189.16,321.146) 189.495,320.81 189.622,320.937 ccw(c189.287,321.272) 189.761,321.272 ccw(c189.287,321.272) 189.622,321.608 188.498,322.732 cw(c188.67,322.903) 188.498,323.075 188.625,323.201 cw(c188.797,323.03) 188.968,323.201 190.092,322.078 ccw(c190.427,322.413) 190.763,322.078 190.89,322.204 ccw(c190.554,322.54) 191.029,322.54 ccw(c190.554,322.54) 190.89,322.876 189.766,323.999 cw(c189.937,324.171) 189.766,324.342 189.893,324.469 cw(c190.064,324.298) 190.236,324.469 191.359,323.345 ccw(c191.695,323.681) 192.031,323.345 192.157,323.472 ccw(c191.822,323.808) 192.296,323.808 ccw(c191.822,323.808) 192.157,324.143 191.849,324.452 cw(c192.02,324.623) 191.849,324.794 192.032,324.977 ccw(c190.548,326.461) 192.646,326.461 192.646,331.457 cw(c193.142,331.457) 193.142,331.953 cw(c193.142,331.701) 193.393,331.701 v2(193.393,331.657)
DDR4_DQS_2_P: U1.AC21 U10.G3 | length 41.3
  L1 w0.116: v1(183.909,308.052) U1.AC21@184.397,308.539 ; v2(193.393,332.457) U10.G3@193.797,332.86
  L14 (Sign) w0.105: v1(183.909,308.052) 184.173,308.052 ccw(c184.173,308.242) 184.362,308.242 184.362,309.03 cw(c185.854,309.03) 184.799,310.084 185.978,311.264 ccw(c185.189,312.053) 186.305,312.053 186.305,318.431 cw(c189.077,318.431) 187.117,320.391 187.375,320.649 ccw(c187.204,320.82) 187.446,320.82 ccw(c187.204,320.82) 187.375,320.992 187.067,321.3 cw(c187.402,321.636) 187.067,321.971 187.193,322.098 cw(c187.529,321.762) 187.865,322.098 188.988,320.974 ccw(c189.16,321.146) 189.331,320.974 189.458,321.101 ccw(c189.287,321.272) 189.529,321.272 ccw(c189.287,321.272) 189.458,321.444 188.334,322.568 cw(c188.67,322.903) 188.334,323.239 188.461,323.366 cw(c188.797,323.03) 189.132,323.366 190.256,322.242 ccw(c190.427,322.413) 190.599,322.242 190.726,322.369 ccw(c190.554,322.54) 190.797,322.54 ccw(c190.554,322.54) 190.726,322.711 189.602,323.835 cw(c189.937,324.171) 189.602,324.506 189.728,324.633 cw(c190.064,324.298) 190.4,324.633 191.524,323.509 ccw(c191.695,323.681) 191.866,323.509 191.993,323.636 ccw(c191.822,323.808) 192.064,323.808 ccw(c191.822,323.808) 191.993,323.979 191.685,324.287 cw(c192.02,324.623) 191.685,324.959 191.867,325.141 ccw(c190.548,326.461) 192.414,326.461 192.414,331.457 cw(c193.142,331.457) 193.142,332.185 ccw(c193.142,332.436) 193.393,332.436 v2(193.393,332.457)
DDR4_DQS_3_N: U1.AE24 U10.A4 | length 28.2
  L1 w0.116: v5(185.909,312.027) U1.AE24@186.397,311.539 ; U10.A4@190.597,328.06 v2(191,327.657)
  L14 (Sign) w0.105: v5(185.909,312.027) 185.71,312.027 cw(c185.71,312.212) 185.526,312.212 185.526,313.271 185.526,313.527 185.526,313.987 cw(c185.577,313.987) 185.577,314.039 185.661,314.039 ccw(c185.661,314.09) 185.712,314.09 185.712,314.499 ccw(c185.661,314.499) 185.661,314.55 185.577,314.55 cw(c185.577,314.601) 185.526,314.601 185.526,315.519 185.526,322.262 cw(c188.066,322.262) 186.27,324.058 186.455,324.244 ccw(c186.106,324.594) 186.6,324.594 ccw(c186.106,324.594) 186.455,324.944 186.181,325.218 cw(c186.367,325.404) 186.181,325.59 186.315,325.724 cw(c186.501,325.538) 186.687,325.724 187.771,324.639 ccw(c188.121,324.989) 188.471,324.639 188.605,324.773 ccw(c188.255,325.123) 188.75,325.123 ccw(c188.255,325.123) 188.605,325.473 187.521,326.558 cw(c187.706,326.743) 187.521,326.929 187.655,327.063 cw(c187.84,326.877) 188.026,327.063 189.111,325.979 ccw(c189.46,326.329) 189.81,325.979 189.944,326.113 ccw(c189.594,326.463) 190.089,326.463 ccw(c189.594,326.463) 189.944,326.813 189.591,327.166 cw(c189.699,327.273) 189.591,327.38 189.71,327.499 cw(c190.805,326.404) 190.805,327.952 cw(c190.805,327.757) 191,327.757 v2(191,327.657)
DDR4_DQS_3_P: U1.AD24 U10.B4 | length 28.2
  L1 w0.116: v5(184.909,312.027) U1.AD24@185.397,311.539 ; U10.B4@190.597,328.86 v2(191,328.457)
  L14 (Sign) w0.105: v5(184.909,312.027) 185.109,312.027 ccw(c185.109,312.212) 185.293,312.212 185.293,322.263 cw(c188.064,322.263) 186.105,324.222 186.291,324.408 ccw(c186.106,324.594) 186.368,324.594 ccw(c186.106,324.594) 186.291,324.78 186.017,325.054 cw(c186.367,325.404) 186.017,325.754 186.151,325.888 cw(c186.501,325.538) 186.851,325.888 187.935,324.803 ccw(c188.121,324.989) 188.307,324.803 188.441,324.937 ccw(c188.255,325.123) 188.518,325.123 ccw(c188.255,325.123) 188.441,325.309 187.356,326.393 cw(c187.706,326.743) 187.356,327.093 187.49,327.227 cw(c187.84,326.877) 188.19,327.227 189.275,326.143 ccw(c189.46,326.329) 189.646,326.143 189.78,326.277 ccw(c189.594,326.463) 189.857,326.463 ccw(c189.594,326.463) 189.78,326.648 189.427,327.001 cw(c189.699,327.273) 189.427,327.544 189.547,327.664 cw(c190.804,326.407) 190.804,328.184 ; 190.805,328.184 ccw(c190.805,328.38) 191,328.38 v2(191,328.457)
DDR4_DQS_4_N: U1.W25 U9.F3 | length 39
  L1 w0.116: v2(170.472,331.657) U9.F3@170.876,332.06 ; v1(179.909,312.052) U1.W25@180.397,312.539
  L14 (Sign) w0.105: v2(170.472,331.657) cw(c170.743,331.657) 170.743,331.927 172.742,331.927 cw(c172.742,330.149) 174.52,330.149 174.52,327.92 ccw(c177.29,327.92) 175.331,325.962 177.799,323.494 178.05,323.243 cw(c177.936,323.129) 178.05,323.015 178.041,323.007 ccw(c178.155,322.893) 178.041,322.778 178.139,322.681 ccw(c178.253,322.795) 178.367,322.681 178.376,322.689 cw(c178.49,322.575) 178.604,322.689 178.653,322.64 cw(c176.857,320.844) 179.397,320.844 179.397,320.639 ccw(c179.755,320.639) 179.755,320.28 180.527,320.28 cw(c180.527,320.154) 180.654,320.154 180.654,319.946 cw(c180.527,319.946) 180.527,319.819 178.498,319.819 ccw(c178.498,319.46) 178.139,319.46 178.139,319.252 ccw(c178.498,319.252) 178.498,318.894 180.527,318.894 cw(c180.527,318.767) 180.654,318.767 180.654,318.559 cw(c180.527,318.559) 180.527,318.433 178.498,318.433 ccw(c178.498,318.074) 178.139,318.074 178.139,317.866 ccw(c178.498,317.866) 178.498,317.508 180.527,317.508 cw(c180.527,317.381) 180.654,317.381 180.654,317.173 cw(c180.527,317.173) 180.527,317.047 179.433,317.047 ccw(c179.433,316.688) 179.075,316.688 179.075,316.48 ccw(c179.433,316.48) 179.397,316.123 179.397,315.721 ccw(c181.057,315.721) 179.883,314.547 179.884,314.546 cw(c178.927,313.589) 180.281,313.589 180.281,312.423 cw(c179.909,312.423) v1(179.909,312.052)
DDR4_DQS_4_P: U1.W24 U9.G3 | length 39
  L1 w0.116: v2(170.472,332.457) U9.G3@170.876,332.86 ; U1.W24@180.397,311.539 v1(180.884,312.027)
  L14 (Sign) w0.105: v2(170.472,332.457) ccw(c170.77,332.457) 170.77,332.159 172.742,332.159 cw(c172.742,330.149) 174.752,330.149 174.752,327.921 ccw(c177.292,327.921) 175.496,326.125 178.817,322.804 cw(c176.859,320.845) 179.629,320.845 179.629,320.639 ccw(c179.755,320.639) 179.755,320.512 180.527,320.512 cw(c180.527,320.154) 180.886,320.154 180.886,319.946 cw(c180.527,319.946) 180.527,319.587 178.498,319.587 ccw(c178.498,319.46) 178.371,319.46 178.371,319.252 ccw(c178.498,319.252) 178.498,319.126 180.527,319.126 cw(c180.527,318.767) 180.886,318.767 180.886,318.559 cw(c180.527,318.559) 180.527,318.201 178.498,318.201 ccw(c178.498,318.074) 178.371,318.074 178.371,317.866 ccw(c178.498,317.866) 178.498,317.74 180.527,317.74 cw(c180.527,317.381) 180.886,317.381 180.886,317.173 cw(c180.527,317.173) 180.527,316.814 179.433,316.814 ccw(c179.433,316.688) 179.307,316.688 179.307,316.48 ccw(c179.433,316.48) 179.433,316.354 cw(c179.433,316.158) 179.629,316.158 179.629,315.723 ccw(c181.062,315.723) 180.048,314.71 180.05,314.708 cw(c178.934,313.591) 180.513,313.591 180.513,312.398 ccw(c180.884,312.398) v1(180.884,312.027)
DDR4_DQS_5_N: U1.R25 U9.A4 | length 30.4
  L1 w0.116: U9.A4@167.676,328.06 v2(168.079,327.657) ; v1(175.909,312.052) U1.R25@176.397,312.539
  L14 (Sign) w0.105: v2(168.079,327.657) cw(c168.324,327.657) 168.324,327.901 168.397,327.901 cw(c168.397,327.368) 168.774,327.745 173.027,323.493 cw(c171.231,321.697) 173.771,321.697 173.771,320.925 cw(c173.675,320.925) 173.675,320.829 172.368,320.829 ccw(c172.368,320.502) 172.041,320.502 172.041,320.079 ccw(c172.368,320.079) 172.368,319.752 175.405,319.752 cw(c175.405,319.656) 175.501,319.656 175.501,319.234 cw(c175.405,319.234) 175.405,319.138 172.592,319.138 ccw(c172.592,318.811) 172.264,318.811 172.264,318.388 ccw(c172.592,318.388) 172.592,318.061 173.675,318.061 cw(c173.675,317.965) 173.771,317.965 173.771,313.478 ccw(c174.32,313.478) 174.32,312.928 174.407,312.928 cw(c174.407,312.151) 174.956,312.7 174.958,312.699 ccw(c175.623,313.364) 175.623,312.423 175.641,312.423 cw(c175.641,312.155) 175.909,312.155 v1(175.909,312.052)
DDR4_DQS_5_P: U1.P25 U9.B4 | length 30.4
  L1 w0.116: U9.B4@167.676,328.86 v2(168.079,328.457) ; U1.P25@175.397,312.539 v1(175.884,313.027)
  L14 (Sign) w0.105: v2(168.079,328.457) 168.079,328.451 ccw(c168.397,328.451) 168.397,328.134 cw(c168.397,327.369) 168.938,327.91 173.191,323.656 cw(c171.233,321.697) 174.003,321.697 174.003,320.925 cw(c173.675,320.925) 173.675,320.597 172.368,320.597 ccw(c172.368,320.502) 172.273,320.502 172.273,320.079 ccw(c172.368,320.079) 172.368,319.984 175.405,319.984 cw(c175.405,319.656) 175.733,319.656 175.733,319.234 cw(c175.405,319.234) 175.405,318.906 172.592,318.906 ccw(c172.592,318.811) 172.496,318.811 172.496,318.388 ccw(c172.592,318.388) 172.592,318.293 173.675,318.293 cw(c173.675,317.965) 174.003,317.965 174.003,313.478 ccw(c174.32,313.478) 174.32,313.16 174.407,313.16 cw(c174.407,312.151) 175.12,312.865 ccw(c175.625,313.369) 175.625,312.655 175.641,312.655 ccw(c175.641,312.899) 175.884,312.899 v1(175.884,313.027)
DDR4_DQS_6_N: U1.V29 U11.F3 | length 26.5
  L1 w0.116: v3(178.91,317.027) U1.V29@179.397,316.539 ; v2(181.933,331.657) U11.F3@182.336,332.06
  L5 (Sign) w0.105: v3(178.91,317.027) 178.745,317.027 cw(c178.745,317.246) 178.526,317.246 178.526,317.677 ccw(c178.125,317.677) 178.125,318.077 177.815,318.077 cw(c177.815,318.245) 177.647,318.245 177.647,318.624 cw(c177.815,318.624) 177.815,318.792 179.004,318.792 ccw(c179.004,319.192) 179.404,319.192 179.404,319.571 ccw(c179.004,319.571) 179.004,319.971 177.815,319.971 cw(c177.815,320.139) 177.647,320.139 177.647,320.518 cw(c177.815,320.518) 177.815,320.686 179.004,320.686 ccw(c179.004,321.086) 179.404,321.086 179.404,321.465 ccw(c179.004,321.465) 179.004,321.865 177.815,321.865 cw(c177.815,322.033) 177.647,322.033 177.647,322.412 cw(c177.815,322.412) 177.815,322.58 178.125,322.58 ccw(c178.125,322.981) 178.526,322.981 178.526,323.632 cw(c179.565,323.632) 179.565,324.672 ccw(c179.565,325.777) 180.67,325.777 180.67,330.835 180.67,331.044 cw(c180.747,331.044) 180.747,331.121 ccw(c180.747,331.199) 180.824,331.199 180.824,331.353 ccw(c180.747,331.353) 180.747,331.43 cw(c180.747,331.507) 180.67,331.507 180.67,331.584 cw(c181.026,331.584) 181.026,331.94 181.65,331.94 cw(c181.65,331.657) v2(181.933,331.657)
DDR4_DQS_6_P: U1.U29 U11.G3 | length 26.6
  L1 w0.116: v4(177.91,317.027) U1.U29@178.397,316.539 ; v2(181.933,332.457) U11.G3@182.336,332.86
  L5 (Sign) w0.105: v4(177.91,317.027) 178.075,317.027 ccw(c178.075,317.245) 178.293,317.245 178.293,317.677 ccw(c178.125,317.677) 178.125,317.845 177.815,317.845 cw(c177.815,318.245) 177.415,318.245 177.415,318.624 cw(c177.815,318.624) 177.815,319.024 179.004,319.024 ccw(c179.004,319.192) 179.172,319.192 179.172,319.571 ccw(c179.004,319.571) 179.004,319.739 177.815,319.739 cw(c177.815,320.139) 177.415,320.139 177.415,320.518 cw(c177.815,320.518) 177.815,320.918 179.004,320.918 ccw(c179.004,321.086) 179.172,321.086 179.172,321.465 ccw(c179.004,321.465) 179.004,321.633 177.815,321.633 cw(c177.815,322.033) 177.415,322.033 177.415,322.412 cw(c177.815,322.412) 177.815,322.812 178.125,322.812 ccw(c178.125,322.981) 178.293,322.981 178.293,323.632 cw(c179.565,323.632) 179.565,324.904 ccw(c179.565,325.777) 180.438,325.777 180.438,331.584 cw(c181.026,331.584) 181.026,332.172 181.648,332.172 ccw(c181.648,332.457) v2@181.933,332.457
  other v3: 177.91,317.027
DDR4_DQS_7_N: U1.R29 U11.A4 | length 19.7
  L1 w0.116: v3(175.91,317.027) U1.R29@176.397,316.539 ; U11.A4@179.136,328.06 v2(179.54,327.657)
  L5 (Sign) w0.105: v3(175.91,317.027) 175.91,317.01 cw(c175.542,317.01) 175.542,316.643 cw(c175.542,317.128) 175.057,317.128 175.057,317.308 175.057,317.541 cw(c175.183,317.541) 175.183,317.667 175.283,317.667 ccw(c175.283,317.793) 175.409,317.793 175.409,317.901 ccw(c175.283,317.901) 175.283,318.026 175.183,318.026 cw(c175.183,318.152) 175.057,318.152 175.057,318.237 175.057,323.254 ccw(c174.663,323.254) 174.663,323.649 174.602,323.649 cw(c174.602,323.811) 174.44,323.811 174.44,324.049 cw(c174.602,324.049) 174.602,324.211 175.28,324.211 ccw(c175.28,324.605) 175.674,324.605 175.674,324.844 ccw(c175.28,324.844) 175.28,325.238 175.219,325.238 cw(c175.219,325.4) 175.057,325.4 175.057,325.688 cw(c175.781,325.688) 175.781,326.412 175.96,326.412 176.194,326.412 cw(c176.194,326.286) 176.32,326.286 ccw(c176.446,326.286) 176.446,326.16 176.553,326.16 ccw(c176.553,326.286) 176.679,326.286 cw(c176.805,326.286) 176.805,326.412 177.356,326.412 177.508,326.412 ccw(c177.508,327.225) 178.321,327.225 178.321,327.406 cw(c178.855,327.406) 178.855,327.941 179.286,327.941 cw(c179.286,327.687) 179.54,327.687 v2(179.54,327.657)
  other v4: 175.91,317.027
DDR4_DQS_7_P: U1.R28 U11.B4 | length 19.7
  L1 w0.116: v3(175.91,316.027) U1.R28@176.397,315.539 ; U11.B4@179.136,328.86 v2(179.54,328.457)
  L5 (Sign) w0.105: v3(175.91,316.027) 175.91,316.043 ccw(c175.542,316.043) 175.542,316.411 cw(c175.542,317.128) 174.825,317.128 174.825,323.254 ccw(c174.663,323.254) 174.663,323.416 174.602,323.416 cw(c174.602,323.811) 174.207,323.811 174.207,324.049 cw(c174.602,324.049) 174.602,324.443 175.28,324.443 ccw(c175.28,324.605) 175.442,324.605 175.442,324.844 ccw(c175.28,324.844) 175.28,325.006 175.219,325.006 cw(c175.219,325.4) 174.825,325.4 174.825,325.688 cw(c175.781,325.688) 175.781,326.644 177.508,326.644 ccw(c177.508,327.225) 178.089,327.225 178.089,327.406 cw(c178.855,327.406) 178.855,328.173 179.286,328.173 ccw(c179.286,328.427) 179.54,328.427 v2(179.54,328.457)
  other v4: 175.91,316.027
DDR4_DQS_8_N: U1.AA28
DDR4_DQS_8_P: U1.Y28
DDR4_DQS_ODT0: R44.1 U1.AB30 U8.K3 U9.K3 U10.K3 U11.K3 | length 107.6
  L1 w0.116: v2(170.472,334.857) U9.K3@170.876,335.26 ; v2(181.933,334.857) U11.K3@182.336,335.26 ; U1.AB30@183.397,317.539 v4(183.884,317.052) ; v2(193.393,334.857) U10.K3@193.797,335.26 ; U8.K3@205.257,335.26 v2(205.661,334.857)
  L1 w0.155: v1(163.977,343.555) R44.1@163.977,344.8
  L1 w0.25: v2(188.593,333.264) 188.997,332.86
  L5 (Sign) w0.092: 167.944,341.085 167.944,341.002 168.602,340.344 168.602,336.427 170.172,334.857 v2(170.472,334.857) 170.709,334.857 171.12,335.267 173.139,335.267 173.954,334.453 174.088,334.453 cw(c174.088,334.363) 174.178,334.363 174.178,334.334 ccw(c174.267,334.334) 174.267,334.245 174.536,334.245 ccw(c174.536,334.334) 174.626,334.334 174.626,334.363 cw(c174.715,334.363) 174.715,334.453 176.441,334.453 178.208,334.453 178.601,334.06 180.755,334.06 181.551,334.857 v2(181.933,334.857) 182.566,334.857 182.977,335.267 183.747,335.267 183.972,335.043 183.972,334.696 184.172,334.496 184.934,334.496 185.77,333.66 191.687,333.66 192.884,334.857 193.709,334.857 194.12,335.267 195.118,335.267 195.484,334.901 196.186,334.901 196.783,334.304 196.895,334.304 197.03,334.304 ccw(c197.03,334.393) 197.119,334.393 197.119,334.474 cw(c197.209,334.474) 197.209,334.564 197.477,334.564 cw(c197.477,334.474) 197.567,334.474 197.567,334.304 197.567,333.733 ccw(c197.657,333.733) 197.657,333.644 197.925,333.644 ccw(c197.925,333.733) 198.015,333.733 198.015,334.304 198.015,334.475 cw(c198.104,334.475) 198.104,334.565 198.373,334.565 cw(c198.373,334.475) 198.463,334.475 198.463,334.393 ccw(c198.552,334.393) 198.552,334.304 198.91,334.304 cw(c198.98,334.304) 198.98,334.373 199.289,334.373 cw(c199.289,334.304) 199.358,334.304 199.358,333.855 ccw(c199.448,333.855) 199.448,333.765 199.716,333.765 ccw(c199.716,333.855) 199.806,333.855 199.806,334.214 cw(c199.896,334.214) 199.896,334.304 200.29,334.304 201.429,335.442 205.075,335.442 v2(205.661,334.857)
  L5 (Sign) w0.151: v1(163.977,343.555) 163.977,342.74 164.655,342.062 167.145,342.062 167.944,341.263 167.944,341.085
  L3 (Sign) w0.092: v4(183.884,317.052) 184.243,317.411 184.979,317.411 185.205,317.185 185.205,316.482 186.422,315.264 186.422,314.708 186.421,314.706 186.418,314.706 186.066,314.354 185.884,314.354 185.696,314.166 185.696,313.9 186.28,313.315 186.28,312.749 188.799,310.23 192.379,310.23 205.605,323.456 205.605,324.666 206.306,325.367 206.366,325.428 ccw(c206.296,325.498) 206.366,325.568 206.14,325.794 cw(c206.21,325.865) 206.14,325.935 206.28,326.075 cw(c206.351,326.005) 206.421,326.075 206.647,325.849 ccw(c206.717,325.919) 206.787,325.849 206.858,325.919 206.858,326.275 206.858,326.573 ccw(c206.758,326.573) 206.758,326.672 206.306,326.672 cw(c206.306,326.771) 206.207,326.771 206.207,326.97 cw(c206.306,326.97) 206.306,327.069 206.758,327.069 ccw(c206.758,327.168) 206.858,327.168 206.858,327.466 206.858,327.665 206.858,327.863 206.055,328.665 206.055,334.462 v2(205.661,334.857)
DDR4_DQS_ODT1: U1.AC29
DDR4_PARITY: R42.1 U1.AB26 U8.T3 U9.T3 U10.T3 U11.T3 | length 98
  L1 w0.116: v2(170.472,340.464) U9.T3@170.876,340.06 ; v2(181.933,340.464) U11.T3@182.336,340.06 ; v4(182.909,314.027) U1.AB26@183.397,313.539 ; v2(193.393,340.464) U10.T3@193.797,340.06 ; v17(204.853,340.464) U8.T3@205.257,340.06
  L1 w0.155: v4(172.438,343.555) R42.1@172.438,344.799
  L5 (Sign) w0.092: v2(170.472,340.464) 171.401,341.393 171.535,341.393 ccw(c171.535,341.482) 171.625,341.482 171.625,341.494 cw(c171.714,341.494) 171.714,341.584 171.983,341.584 cw(c171.983,341.494) 172.073,341.494 172.073,341.393 172.073,341.291 ccw(c172.162,341.291) 172.162,341.202 172.431,341.202 ccw(c172.431,341.291) 172.52,341.291 172.52,341.303 cw(c172.61,341.303) 172.61,341.393 173.009,341.393 181.004,341.393 v2(181.933,340.464) 183.734,342.265 188.493,342.265 189.683,342.265 cw(c189.683,342.196) 189.752,342.196 189.752,342.188 ccw(c189.821,342.188) 189.821,342.118 190.029,342.118 ccw(c190.029,342.188) 190.098,342.188 190.098,342.196 cw(c190.168,342.196) 190.168,342.265 190.271,342.265 191.592,342.265 v2(193.393,340.464) 193.568,340.639 193.943,340.639 194.285,340.982 194.285,342.24 194.907,342.862 200.863,342.862 202.534,342.862 cw(c202.534,342.772) 202.623,342.772 202.623,342.659 ccw(c202.713,342.659) 202.713,342.57 202.982,342.57 ccw(c202.982,342.659) 203.071,342.659 203.071,342.862 203.071,343.065 cw(c203.161,343.065) 203.161,343.154 203.429,343.154 cw(c203.429,343.065) 203.519,343.065 203.519,342.862 203.519,342.659 ccw(c203.608,342.659) 203.608,342.57 203.877,342.57 ccw(c203.877,342.659) 203.967,342.659 203.967,342.772 cw(c204.056,342.772) 204.056,342.862 204.191,342.862 204.853,342.199 v17(204.853,340.464)
  L3 (Sign) w0.092: v2(170.472,340.464) 171.013,341.005 171.013,341.085 ; v4(182.909,314.027) 183.49,314.607 183.49,316.403 183.179,316.713 183.179,317.344 183.49,317.654 183.49,318.295 183.84,318.646 183.911,318.716 ccw(c183.84,318.786) 183.911,318.857 183.788,318.979 cw(c183.858,319.049) 183.788,319.119 183.929,319.26 cw(c183.999,319.189) 184.069,319.26 184.261,319.067 184.676,318.653 ccw(c184.746,318.723) 184.816,318.653 184.957,318.793 ccw(c184.886,318.863) 184.957,318.933 184.542,319.348 184.35,319.54 cw(c184.42,319.611) 184.35,319.681 184.49,319.821 cw(c184.56,319.751) 184.63,319.821 184.823,319.629 185.201,319.251 ccw(c185.271,319.321) 185.341,319.251 185.481,319.391 ccw(c185.411,319.461) 185.481,319.531 185.104,319.909 184.911,320.102 cw(c184.981,320.172) 184.911,320.242 185.051,320.383 cw(c185.122,320.312) 185.192,320.383 185.384,320.19 185.76,319.814 ccw(c185.83,319.884) 185.9,319.814 186.041,319.955 ccw(c185.971,320.025) 186.041,320.095 185.665,320.471 185.472,320.663 cw(c185.543,320.733) 185.472,320.804 185.613,320.944 cw(c185.683,320.874) 185.753,320.944 185.876,320.822 ccw(c185.946,320.892) 186.016,320.822 186.715,321.521 191.937,326.742 191.937,334.292 192.646,335.002 192.646,336.014 193.206,336.574 196.129,336.574 201.059,341.503 203.814,341.503 v17(204.853,340.464)
  L3 (Sign) w0.151: 171.013,341.085 171.013,341.464 172.428,342.879 172.428,343.545 v4(172.438,343.555)
DDR4_RAM_RST_N: R60.1 U1.AB25 U8.P1 U9.P1 U10.P1 U11.P1 | length 99.4
  L1 w0.116: U9.P1@172.476,338.46 v4(172.879,338.864) ; U1.AB25@183.397,312.539 v4(183.884,313.027) ; U11.P1@183.936,338.46 v4(184.34,338.864) ; U10.P1@195.397,338.46 v2(195.8,338.864) ; U8.P1@206.857,338.46 v2(207.261,338.864)
  L12 (Sign) w0.092: v2(195.8,338.864) 196.374,338.29 201.123,338.29 201.218,338.385 202.425,338.385 202.56,338.385 ccw(c202.56,338.475) 202.649,338.475 202.649,338.652 cw(c202.739,338.652) 202.739,338.742 203.007,338.742 cw(c203.007,338.652) 203.097,338.652 203.097,338.385 203.097,338.118 ccw(c203.187,338.118) 203.187,338.028 203.455,338.028 ccw(c203.455,338.118) 203.545,338.118 203.545,338.385 203.545,338.652 cw(c203.634,338.652) 203.634,338.742 203.903,338.742 cw(c203.903,338.652) 203.993,338.652 203.993,338.475 ccw(c204.082,338.475) 204.082,338.385 204.483,338.385 206.782,338.385 v2(207.261,338.864)
  L3 (Sign) w0.092: v4(172.879,338.864) 174.191,338.864 175.387,340.06 175.672,340.06 cw(c175.672,339.951) 175.782,339.951 175.782,339.92 ccw(c175.892,339.92) 175.892,339.81 176.222,339.81 ccw(c176.222,339.92) 176.332,339.92 176.332,339.951 cw(c176.441,339.951) 176.441,340.06 176.606,340.06 179.992,340.06 180.792,339.26 183.943,339.26 v4(184.34,338.864) 184.736,339.26 185.89,339.26 187.297,339.26 ccw(c187.297,339.35) 187.387,339.35 187.387,339.625 cw(c187.476,339.625) 187.476,339.715 187.745,339.715 cw(c187.745,339.625) 187.834,339.625 187.834,339.26 187.834,339.02 ccw(c187.924,339.02) 187.924,338.93 188.193,338.93 ccw(c188.193,339.02) 188.282,339.02 188.282,339.171 cw(c188.372,339.171) 188.372,339.26 188.506,339.26 195.404,339.26 v2(195.8,338.864) ; v4(183.884,313.027) 184.305,313.027 184.7,312.632 185.055,312.632 185.382,312.306 185.382,311.656 186.28,310.757 186.28,309.749 186.606,309.423 187.731,309.423 192.65,309.423 192.689,309.462 192.697,309.462 209.194,325.959 209.194,331.495 209.194,332.123 ccw(c209.057,332.123) 209.057,332.26 208.801,332.26 cw(c208.801,332.398) 208.663,332.398 208.663,332.672 cw(c208.801,332.672) 208.801,332.81 209.194,332.81 209.71,332.81 ccw(c209.71,332.947) 209.847,332.947 209.847,333.222 ccw(c209.71,333.222) 209.71,333.359 209.194,333.359 208.801,333.359 cw(c208.801,333.496) 208.663,333.496 208.663,333.771 cw(c208.801,333.771) 208.801,333.908 209.194,333.908 209.71,333.908 ccw(c209.71,334.046) 209.847,334.046 209.847,334.32 ccw(c209.71,334.32) 209.71,334.458 209.194,334.458 208.801,334.458 cw(c208.801,334.595) 208.663,334.595 208.663,334.87 cw(c208.801,334.87) 208.801,335.007 209.194,335.007 209.71,335.007 ccw(c209.71,335.145) 209.847,335.145 209.847,335.419 ccw(c209.71,335.419) 209.71,335.557 209.194,335.557 208.801,335.557 cw(c208.801,335.694) 208.663,335.694 208.663,335.969 cw(c208.801,335.969) 208.801,336.106 209.194,336.106 209.71,336.106 ccw(c209.71,336.243) 209.847,336.243 209.847,336.518 ccw(c209.71,336.518) 209.71,336.655 209.332,336.655 cw(c209.332,336.793) 209.194,336.793 209.194,336.93 v2(207.261,338.864)
DDR4_RAS: R59.1 U1.AH27 U8.L5 U9.L5 U10.L5 U11.L5 | length 99.3
  L1 w0.116: U9.L5@166.876,336.06 167.272,336.457 v2(167.275,336.457) ; U11.L5@178.336,336.06 178.733,336.457 v2(178.735,336.457) ; U1.AH27@189.397,314.539 v4(189.884,315.027) ; U10.L5@189.797,336.06 190.193,336.457 v2(190.195,336.457) ; U8.L5@201.257,336.06 201.653,336.457 v3(201.656,336.457)
  L1 w0.155: R59.1@158.737,334.7 v1(159.982,334.7)
  L12 (Sign) w0.092: 165.251,335.813 166.114,335.813 166.758,336.457 v2(167.275,336.457) 167.537,336.457 167.858,336.778 168.277,336.778 168.566,336.488 168.79,336.488 169.149,336.488 cw(c169.149,336.398) 169.238,336.398 169.238,336.342 ccw(c169.328,336.342) 169.328,336.252 169.596,336.252 ccw(c169.596,336.342) 169.686,336.342 169.686,336.398 cw(c169.775,336.398) 169.775,336.488 170.044,336.488 cw(c170.044,336.398) 170.134,336.398 170.134,336.342 ccw(c170.223,336.342) 170.223,336.252 170.492,336.252 ccw(c170.492,336.342) 170.582,336.342 170.582,336.398 cw(c170.671,336.398) 170.671,336.488 170.715,336.488 172.923,336.488 173.147,336.488 173.505,336.488 cw(c173.505,336.398) 173.595,336.398 173.595,336.3 ccw(c173.684,336.3) 173.684,336.211 173.953,336.211 ccw(c173.953,336.3) 174.043,336.3 174.043,336.398 cw(c174.132,336.398) 174.132,336.488 175.628,336.488 175.659,336.457 v2(178.735,336.457) 178.977,336.457 179.349,336.829 180.162,336.829 180.705,336.287 184.769,336.287 184.996,336.06 185.807,336.06 185.91,336.06 ccw(c185.91,336.13) 185.98,336.13 185.98,336.293 cw(c186.049,336.293) 186.049,336.362 186.257,336.362 cw(c186.257,336.293) 186.326,336.293 186.326,336.06 186.326,335.828 ccw(c186.395,335.828) 186.395,335.758 186.603,335.758 ccw(c186.603,335.828) 186.672,335.828 186.672,335.991 cw(c186.741,335.991) 186.741,336.06 186.868,336.06 189.282,336.06 189.679,336.457 v2(190.195,336.457) 190.458,336.457 190.779,336.778 191.197,336.778 191.487,336.488 192.022,335.953 197.764,335.953 198.156,335.953 ccw(c198.156,336.043) 198.245,336.043 198.245,336.152 cw(c198.335,336.152) 198.335,336.241 198.603,336.241 cw(c198.603,336.152) 198.693,336.152 198.693,335.953 198.693,335.754 ccw(c198.782,335.754) 198.782,335.665 199.051,335.665 ccw(c199.051,335.754) 199.141,335.754 199.141,335.864 cw(c199.23,335.864) 199.23,335.953 199.365,335.953 199.502,335.953 ccw(c199.502,336.043) 199.592,336.043 199.592,336.152 cw(c199.681,336.152) 199.681,336.241 199.95,336.241 cw(c199.95,336.152) 200.04,336.152 200.04,335.953 200.04,335.864 ccw(c200.129,335.864) 200.129,335.774 200.398,335.774 ccw(c200.398,335.864) 200.487,335.864 cw(c200.577,335.864) 200.577,335.953 200.711,335.953 201.215,336.457 v3(201.656,336.457)
  L12 (Sign) w0.151: v1(159.982,334.7) 163.09,334.7 164.203,335.813 165.251,335.813
  L3 (Sign) w0.092: v4(189.884,315.027) 190.232,315.374 190.232,316.074 190.672,316.514 190.938,316.514 192.232,316.514 192.381,316.663 192.469,316.751 ccw(c192.381,316.839) 192.469,316.928 192.438,316.959 cw(c192.526,317.047) 192.438,317.135 192.614,317.311 cw(c192.702,317.223) 192.79,317.311 192.91,317.192 192.931,317.17 ccw(c193.019,317.259) 193.107,317.17 193.284,317.347 ccw(c193.196,317.435) 193.284,317.523 193.262,317.544 193.143,317.664 cw(c193.231,317.752) 193.143,317.84 193.319,318.017 cw(c193.407,317.928) 193.495,318.017 193.615,317.897 193.639,317.873 ccw(c193.727,317.961) 193.815,317.873 193.992,318.049 ccw(c193.903,318.137) 193.992,318.225 193.967,318.25 193.848,318.369 cw(c193.936,318.457) 193.848,318.545 194.024,318.722 cw(c194.112,318.634) 194.2,318.722 194.32,318.602 194.473,318.449 ccw(c194.562,318.537) 194.65,318.449 194.826,318.625 ccw(c194.738,318.713) 194.826,318.801 194.673,318.955 194.553,319.074 cw(c194.641,319.162) 194.553,319.251 194.729,319.427 cw(c194.817,319.339) 194.906,319.427 195.025,319.307 195.098,319.235 ccw(c195.186,319.323) 195.274,319.235 195.45,319.411 ccw(c195.362,319.499) 195.45,319.587 195.378,319.66 195.258,319.779 cw(c195.346,319.868) 195.258,319.956 195.434,320.132 cw(c195.523,320.044) 195.611,320.132 195.73,320.012 195.826,319.917 ccw(c195.914,320.005) 196.002,319.917 196.179,320.093 ccw(c196.09,320.181) 196.179,320.269 196.083,320.365 195.963,320.485 cw(c196.051,320.573) 195.963,320.661 196.14,320.837 cw(c196.228,320.749) 196.316,320.837 196.435,320.718 196.589,320.564 ccw(c196.677,320.652) 196.765,320.564 196.941,320.74 ccw(c196.853,320.829) 196.941,320.917 196.788,321.07 196.668,321.19 cw(c196.757,321.278) 196.668,321.366 196.845,321.542 cw(c196.933,321.454) 197.021,321.542 197.14,321.423 197.232,321.331 ccw(c197.32,321.419) 197.408,321.331 197.585,321.508 ccw(c197.496,321.596) 197.585,321.684 197.493,321.775 197.373,321.895 cw(c197.462,321.983) 197.373,322.071 197.55,322.247 cw(c197.638,322.159) 197.726,322.247 197.846,322.128 197.961,322.013 ccw(c198.049,322.101) 198.137,322.013 198.313,322.189 ccw(c198.225,322.277) 198.313,322.365 198.198,322.48 198.079,322.6 cw(c198.167,322.688) 198.079,322.776 198.255,322.953 cw(c198.343,322.864) 198.431,322.953 198.551,322.833 198.702,322.682 ccw(c198.79,322.77) 198.878,322.682 199.054,322.858 ccw(c198.966,322.946) 199.054,323.035 198.903,323.186 198.784,323.305 cw(c198.872,323.393) 198.784,323.481 198.96,323.658 cw(c199.048,323.569) 199.136,323.658 199.256,323.538 199.341,323.453 ccw(c199.43,323.541) 199.518,323.453 199.694,323.629 ccw(c199.606,323.717) 199.694,323.805 199.697,323.802 cw(c199.785,323.891) 199.697,323.979 199.873,324.155 cw(c199.961,324.067) 200.049,324.155 200.201,324.003 ccw(c200.289,324.091) 200.377,324.003 200.554,324.179 ccw(c200.466,324.267) 200.554,324.356 200.402,324.508 cw(c200.49,324.596) 200.402,324.684 200.578,324.86 cw(c200.666,324.772) 200.754,324.86 201.149,324.465 ccw(c201.237,324.554) 201.325,324.465 201.502,324.642 ccw(c201.413,324.73) 201.502,324.818 201.107,325.213 cw(c201.195,325.301) 201.107,325.389 201.224,325.507 201.224,325.653 201.224,326.255 ccw(c201.1,326.255) 201.1,326.38 200.859,326.38 cw(c200.859,326.505) 200.734,326.505 200.734,326.754 cw(c200.859,326.754) 200.859,326.879 201.224,326.879 201.708,326.879 ccw(c201.708,327.003) 201.833,327.003 201.833,327.253 ccw(c201.708,327.253) 201.708,327.377 201.224,327.377 200.859,327.377 cw(c200.859,327.502) 200.734,327.502 200.734,327.751 cw(c200.859,327.751) 200.859,327.876 201.224,327.876 201.708,327.876 ccw(c201.708,328) 201.833,328 201.833,328.25 ccw(c201.708,328.25) 201.708,328.374 201.349,328.374 cw(c201.349,328.499) 201.224,328.499 201.224,328.748 cw(c201.349,328.748) 201.349,328.873 201.708,328.873 ccw(c201.708,328.998) 201.833,328.998 201.833,329.247 ccw(c201.708,329.247) 201.708,329.372 201.224,329.372 cw(c201.224,329.478) 201.118,329.478 201.118,329.764 cw(c201.224,329.764) 201.224,329.87 201.708,329.87 ccw(c201.708,329.995) 201.833,329.995 201.833,330.244 ccw(c201.708,330.244) 201.708,330.369 201.224,330.369 201.133,330.369 cw(c201.133,330.493) 201.009,330.493 201.009,330.743 cw(c201.133,330.743) 201.133,330.867 201.224,330.867 ccw(c201.224,330.931) 201.288,330.931 201.288,331.303 ccw(c201.224,331.303) 201.224,331.366 201.223,331.366 cw(c201.223,331.491) 201.098,331.491 201.098,331.74 cw(c201.223,331.74) 201.223,331.865 201.224,331.865 ccw(c201.224,331.969) 201.329,331.969 201.329,332.259 ccw(c201.224,332.259) 201.224,332.363 cw(c201.224,332.484) 201.103,332.484 201.103,332.741 cw(c201.224,332.741) 201.224,332.862 201.708,332.862 ccw(c201.708,332.986) 201.833,332.986 201.833,333.236 ccw(c201.708,333.236) 201.708,333.36 201.224,333.36 cw(c201.224,333.485) 201.1,333.485 201.1,333.734 cw(c201.224,333.734) 201.224,333.859 201.708,333.859 ccw(c201.708,333.984) 201.833,333.984 201.833,334.233 ccw(c201.708,334.233) 201.708,334.358 201.349,334.358 cw(c201.349,334.482) 201.224,334.482 201.224,334.607 201.224,335.03 201.371,335.177 201.371,335.877 201.656,336.162 v3(201.656,336.457)
DDR4_TEN: R56.1 U8.N6 U9.N6 U10.N6 U11.N6 | length 42.1
  L1 w0.112: 165.251,338.056 v4(165.665,338.056)
  L1 w0.116: v4(165.665,338.056) U9.N6@166.068,337.653 ; v4(177.125,338.056) U11.N6@177.529,337.653 ; v4(188.586,338.056) U10.N6@188.989,337.653 ; v4(197.878,339.319) 199.536,337.66 U8.N6@200.457,337.66
  L1 w0.155: R56.1@163.36,338.184 164.159,338.184 164.287,338.056 165.251,338.056
  L3 (Sign) w0.092: v4(165.665,338.056) 166.061,337.66 168.338,337.66 169.439,336.56 175.628,336.56 176.729,337.66
  L3 (Sign) w0.116: 176.729,337.66 v4(177.125,338.056) 177.521,337.66 183.136,337.66 183.143,337.668 188.197,337.668 v4(188.586,338.056) 188.982,337.66 190.855,337.66 190.869,337.674 191.154,337.674 191.313,337.833 192.222,337.833 192.387,337.668 196.227,337.668 v4(197.878,339.319)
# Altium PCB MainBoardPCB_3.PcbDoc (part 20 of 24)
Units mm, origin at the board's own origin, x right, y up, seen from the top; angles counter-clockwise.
Board outline 258.95 x 308.86 mm, 16 copper layers (L1, L2 (GND), L3 (Sign), L4 (GND), L5 (Sign), L6 (PWR/GND), L7(PWR/GND), L8 (Plane_GND), L9 (PWR/GND), L10 (PWR/GND), L11 (PWR/GND), L12 (Sign), L13 (GND), L14 (Sign), L15 (GND), L16), stack 2.502 mm thick; 2402 components, 1749 nets, 8407 pads, 3409 vias.
Unrouted connection lines stored in the file: 4352.

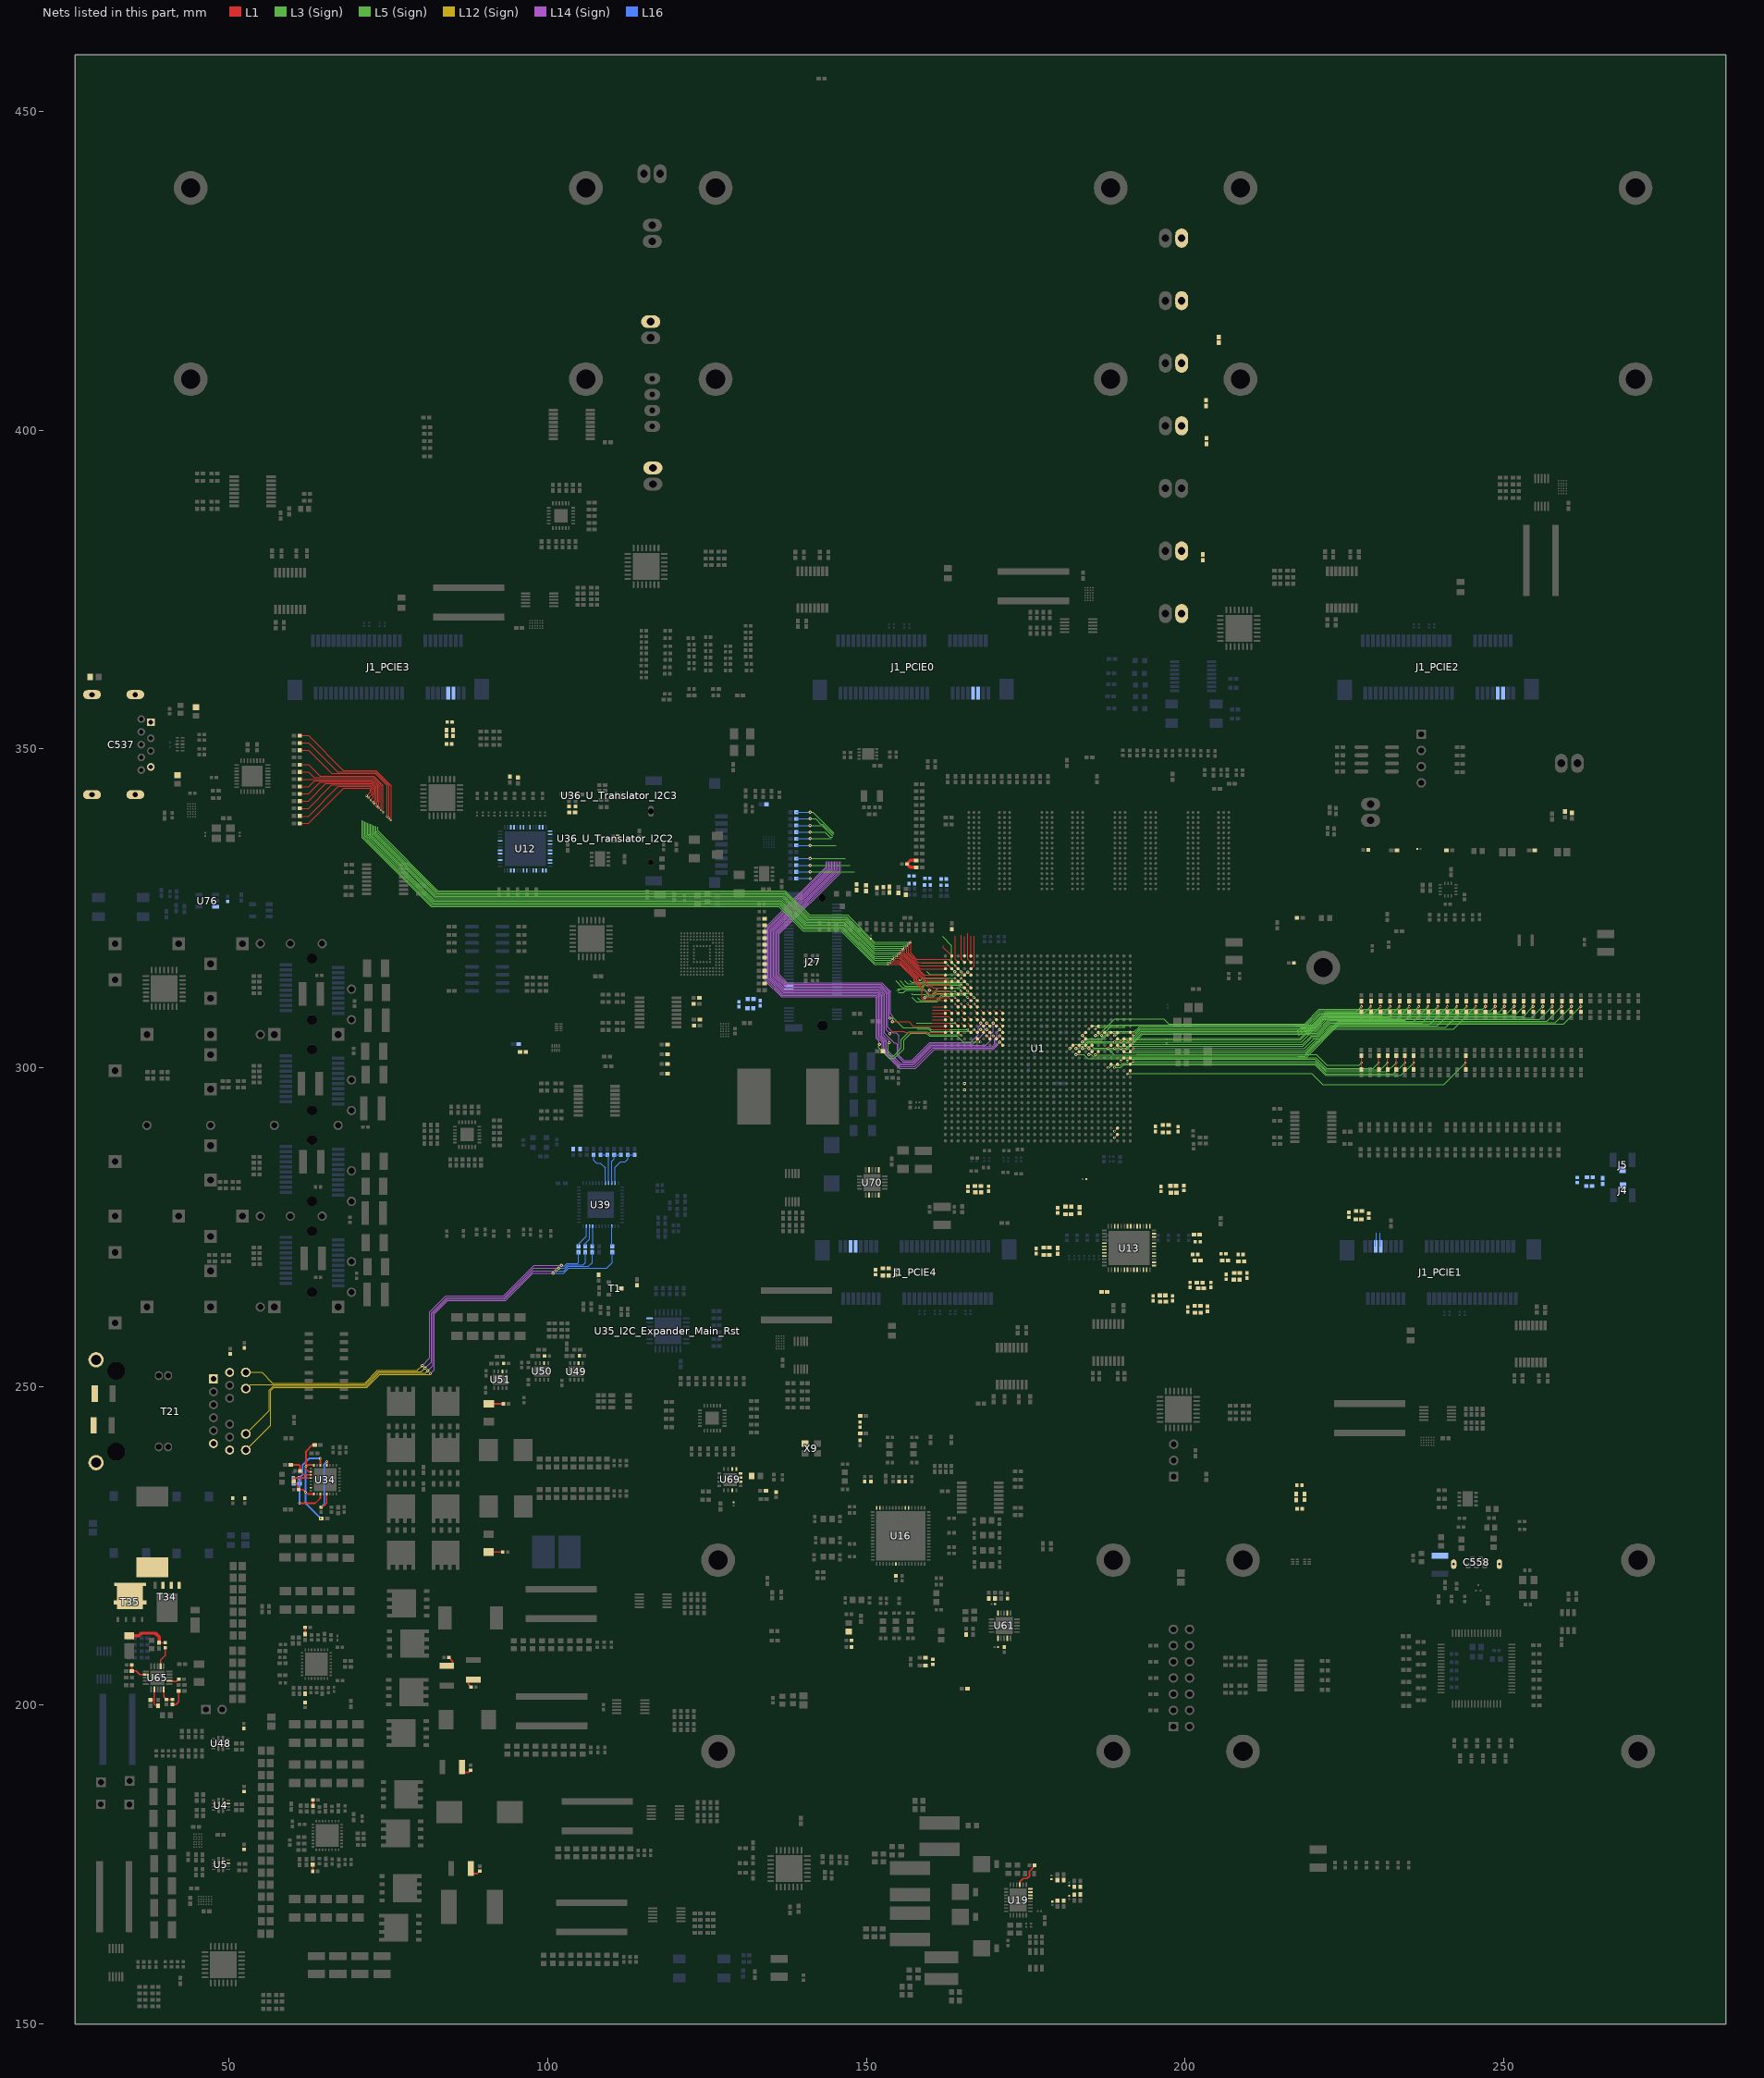
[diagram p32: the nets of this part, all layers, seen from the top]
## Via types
v1: diameter 0.5, hole 0.2, L1 to L16, tented both sides, 1267 vias
v2: diameter 0.5/0.35/0.35/0.35/0.35/0.35/0.35/0.35/0.35/0.35/0.35/0.35/0.35/0.35/0.35/0.5 (per signal layer), hole 0.15, L1 to L16, tented both sides, 463 vias
v3: diameter 0.5, hole 0.2, L1 to L16, 446 vias
v4: diameter 0.35/0/0.35 (per signal layer), hole 0.127, L1 to L3 (Sign), tented both sides, 347 vias
v5: diameter 0.5/0.35/0.35/0.35/0.35/0.35/0.35/0.35/0.35/0.35/0.35/0.35/0.35/0.35/0.35/0.5 (per signal layer), hole 0.2, L1 to L16, tented both sides, 244 vias
v6: diameter 0.8, hole 0.4, L1 to L16, tented both sides, 168 vias
v7: diameter 2.54, hole 1.02, L1 to L16, 113 vias
v8: diameter 1.4, hole 0.5, L1 to L16, tented both sides, 80 vias
v9: diameter 0.5/0/0.5 (per signal layer), hole 0.2, L14 (Sign) to L16, tented both sides, 62 vias
v10: diameter 0.35/0/0.35 (per signal layer), hole 0.127, L1 to L3 (Sign), 38 vias
v11: diameter 0.35, hole 0.127, L1 to L2 (GND), tented both sides, 36 vias
v12: diameter 0.4, hole 0.2, L1 to L16, 16 vias
v13: diameter 0.25, hole 0.2, L1 to L16, 16 vias
v14: diameter 0.35, hole 0.127, L1 to L16, tented both sides, 16 vias
v15: diameter 0.3, hole 0.2, L1 to L16, 15 vias
v16: diameter 0.45, hole 0.15, L1 to L16, 12 vias
v17: diameter 0.5/0.35/0.35/0.35/0.35/0.35/0.35/0.35/0.35/0.35/0.35/0.35/0.35/0.35/0.35/0.45 (per signal layer), hole 0.15, L1 to L16, tented both sides, 10 vias
v18: diameter 0.2/0/0.2 (per signal layer), hole 0.1, L1 to L3 (Sign), tented both sides, 9 vias
v19: diameter 0.4, hole 0.1, L1 to L16, 7 vias
v20: diameter 0.5, hole 0.2, L3 (Sign) to L6 (PWR/GND), tented both sides, 6 vias
v21: diameter 1.15, hole 1.15, L1 to L16, 5 vias
v22: diameter 1.65, hole 1.65, L1 to L16, 5 vias
v23: diameter 0.35/0/0.35 (per signal layer), hole 0.127, L14 (Sign) to L16, tented both sides, 5 vias
v24: diameter 0.5, hole 0.2, L11 (PWR/GND) to L14 (Sign), tented both sides, 4 vias
v25: diameter 0.2, hole 0.1, L1 to L16, 4 vias
v26: diameter 0.35, hole 0.127, L1 to L2 (GND), 2 vias
v27: diameter 0.4, hole 0.15, L1 to L16, 2 vias
v28: diameter 0.4, hole 0.2, L1 to L16, tented both sides, 2 vias
v29: diameter 0.5/0.35/0.35/0.35/0.35/0.35/0.35/0.35/0.35/0.35/0.35/0.35/0.35/0.35/0.35/0.5 (per signal layer), hole 0.15, L1 to L16, 2 vias
v30: diameter 0.35, hole 0.127, L3 (Sign) to L6 (PWR/GND), tented both sides, 2 vias
v31: diameter 0.5/0.35/0.35/0.35/0.35/0.35/0.35/0.35/0.35/0.35/0.35/0.35/0.35/0.35/0.35/0.5 (per signal layer), hole 0.2, L1 to L16, 1 vias
v32: diameter 0.35/0.35/0.35 (per signal layer), hole 0.127, L1 to L3 (Sign), tented both sides, 1 vias
v33: diameter 0.45/0/0.45 (per signal layer), hole 0.15, L1 to L3 (Sign), tented both sides, 1 vias
v34: diameter 0.45/0/0.45 (per signal layer), hole 0.2, L14 (Sign) to L16, tented both sides, 1 vias
v35: diameter 0.35, hole 0.127, L2 (GND) to L3 (Sign), 1 vias

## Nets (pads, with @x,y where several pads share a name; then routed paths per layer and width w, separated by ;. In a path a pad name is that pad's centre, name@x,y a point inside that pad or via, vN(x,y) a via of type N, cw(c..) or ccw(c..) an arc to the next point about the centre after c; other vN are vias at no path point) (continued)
Interrupt49: R939.2 R970.1 U1.AB15 | length 85.3
  L1 w0.116: v5@182.909,302.052 U1.AB15@183.397,302.539
  L1 w0.12: R939.2@262.116,308.751 v1(262.116,309.607) R970.1@262.116,310.463
  L5 (Sign) w0.12: v5(182.904,302.057) 184.124,302.057 184.76,301.422 217.692,301.422 217.877,301.607 218.968,301.607 224.225,306.864 259.373,306.864 v1(262.116,309.607)
Interrupt50: R941.2 R971.1 U1.AD15 | length 81.5
  L1 w0.116: v5@184.909,302.052 U1.AD15@185.397,302.539
  L1 w0.12: R941.2@260.619,308.751 v1(260.619,309.607) R971.1@260.619,310.463
  L5 (Sign) w0.12: v5(184.904,302.057) 185.267,302.057 185.623,301.701 217.576,301.701 217.702,301.827 218.877,301.827 224.134,307.084 258.096,307.084 v1(260.619,309.607)
Interrupt51: R943.2 R972.1 U1.AE15 | length 89.1
  L1 w0.116: v5(185.909,302.052) U1.AE15@186.397,302.539
  L1 w0.12: R943.2@259.122,308.751 v1(259.122,309.607) R972.1@259.122,310.463
  L5 (Sign) w0.12: v5(185.909,302.052) v5@185.915,302.047 ; 196.291,302.047 v5@185.915,302.047 ; v1(259.122,309.607) 256.819,307.304 224.043,307.304 218.785,302.047 v5@185.915,302.047
Interrupt52: R945.2 R973.1 U1.AG13 | length 51.1
  L1 w0.116: v4(187.909,300.052) U1.AG13@188.397,300.539
  L1 w0.12: R945.2@234.506,299.747 v4(234.506,300.816) R973.1@234.506,301.885
  L3 (Sign) w0.12: v4(187.909,300.052) 188.265,300.052 188.631,300.418 189.935,300.418 190.224,300.707 191.595,300.707 191.61,300.692 220.465,300.692 222.123,299.034 232.724,299.034 v4(234.506,300.816)
Interrupt53: R947.2 R974.1 U1.AH13 | length 51.5
  L1 w0.116: v4(188.909,300.052) U1.AH13@189.397,300.539
  L1 w0.12: R947.2@235.87,299.747 v4(235.87,300.816) R974.1@235.87,301.885
  L3 (Sign) w0.12: v4(188.909,300.052) 189.88,300.052 190.315,300.487 191.504,300.487 191.519,300.472 220.374,300.472 222.032,298.814 233.868,298.814 v4(235.87,300.816)
Interrupt54: R949.2 R975.1 U1.AK13 | length 45.4
  L1 w0.116: U1.AK13@191.397,300.539 v4@191.884,301.027
  L1 w0.12: R949.2@233.143,299.747 v4(233.143,300.816) R975.1@233.143,301.885
  L3 (Sign) w0.12: v4(191.878,301.027) 220.441,301.027 222.099,299.369 231.696,299.369 v4(233.143,300.816)
Interrupt55: R951.2 R976.1 U1.AK12 | length 58.1
  L1 w0.116: v4(190.909,299.052) U1.AK12@191.397,299.539
  L1 w0.12: R951.2@244.05,299.747 v4(244.05,300.816) R976.1@244.05,301.885
  L3 (Sign) w0.12: v4(190.909,299.052) 191.254,299.052 191.342,299.14 219.839,299.14 221.585,297.394 240.628,297.394 v4(244.05,300.816)
Interrupt56: R953.2 R977.1 U1.AJ14 | length 44.6
  L1 w0.116: v4(189.909,301.052) U1.AJ14@190.397,301.539
  L1 w0.12: R953.2@230.416,299.747 v4(230.416,300.816) R977.1@230.416,301.885
  L3 (Sign) w0.12: v4(189.909,301.052) 190.444,301.587 220.503,301.587 222.161,299.929 229.529,299.929 v4(230.416,300.816)
Interrupt57: R955.2 R978.1 U1.AK14 | length 45
  L1 w0.116: v4(190.909,301.052) U1.AK14@191.397,301.539
  L1 w0.12: R955.2@231.78,299.747 v4(231.78,300.816) R978.1@231.78,301.885
  L3 (Sign) w0.12: v4(190.909,301.052) 191.224,301.367 220.412,301.367 222.07,299.709 230.673,299.709 v4(231.78,300.816)
Interrupt58: R957.2 R979.1 U1.AJ15 | length 58.8
  L1 w0.116: U1.AJ15@190.397,302.539 v4(190.884,303.027)
  L1 w0.12: R957.2@244.153,308.751 v4(244.152,309.607) R979.1@244.152,310.463
  L3 (Sign) w0.12: v4(190.884,303.027) 191.169,303.027 191.529,302.666 ; 191.465,302.654 218.844,302.654 220.526,304.336 221.093,304.336 223.107,306.35 240.895,306.35 v4(244.152,309.607)
Interrupt59: R959.2 R980.1 U1.AK15 | length 55.9
  L1 w0.116: U1.AK15@191.397,302.539 v4@191.884,303.027
  L1 w0.12: R959.2@242.656,308.751 v4(242.655,309.607) R980.1@242.655,310.463
  L3 (Sign) w0.12: v4(191.878,303.027) 218.689,303.027 220.218,304.556 221.002,304.556 223.025,306.578 239.626,306.578 v4(242.655,309.607)
Interrupt60: R922.1 R981.1 U1.AC16 | length 77.6
  L1 w0.116: v5@183.909,303.052 U1.AC16@184.397,303.539
  L1 w0.12: R922.1@256.128,308.751 v1(256.128,309.607) R981.1@256.128,310.463
  L5 (Sign) w0.12: v5(183.904,303.057) 184.43,303.057 184.765,303.392 185.342,303.392 185.611,303.124 190.843,303.124 193.228,305.509 219.309,305.509 221.614,307.814 254.335,307.814 v1(256.128,309.607)
Interrupt61: R924.1 R982.1 U1.AD16 | length 78
  L1 w0.116: v5@184.909,303.052 U1.AD16@185.397,303.539
  L1 w0.12: R924.1@257.625,308.751 v1(257.625,309.607) R982.1@257.625,310.463
  L5 (Sign) w0.12: v5(184.904,303.057) 185.058,302.904 190.953,302.904 193.338,305.289 219.4,305.289 221.705,307.594 255.612,307.594 v1(257.625,309.607)
Interrupt62: R926.1 R983.1 U1.AA16 | length 76.3
  L1 w0.116: v5@181.909,303.052 U1.AA16@182.397,303.539
  L1 w0.12: R926.1@253.134,308.751 v1(253.134,309.607) R983.1@253.134,310.463
  L5 (Sign) w0.12: v5(181.904,303.057) 182.141,303.057 182.791,303.708 184.277,303.708 184.65,304.081 184.72,304.081 184.733,304.094 191.134,304.094 192.989,305.949 194.214,305.949 194.218,305.953 219.125,305.953 221.43,308.258 249.079,308.258 ; 249.079,308.254 251.781,308.254 v1(253.134,309.607)
Interrupt63: R928.1 R984.1 U1.AB16 | length 76.8
  L1 w0.116: v5@182.909,303.052 U1.AB16@183.397,303.539
  L1 w0.12: R928.1@254.631,308.751 v1(254.631,309.607) R984.1@254.631,310.463
  L5 (Sign) w0.12: v5(182.904,303.057) 183.345,303.057 183.68,303.392 184.343,303.392 184.825,303.874 191.225,303.874 193.08,305.729 219.218,305.729 221.523,308.034 253.058,308.034 v1(254.631,309.607)
Interrupt64: R930.1 R985.1 U1.AC17 | length 75.7
  L1 w0.116: v5@183.909,304.052 U1.AC17@184.397,304.539
  L1 w0.12: R930.1@251.637,308.751 v1(251.637,309.607) R985.1@251.637,310.463
  L5 (Sign) w0.12: v5(183.904,304.057) 183.92,304.057 184.163,304.301 184.629,304.301 184.642,304.314 186.947,304.314 188.118,305.486 192.215,305.486 192.898,306.169 192.948,306.169 192.964,306.184 219.029,306.184 221.334,308.49 250.508,308.49 ; 250.508,308.478 v1(251.637,309.607)
  L3 (Sign) w0.12: v5@183.909,304.052 187.18,304.052
Interrupt65: R932.1 R986.1 U1.AC18 | length 71
  L1 w0.116: v5@183.909,305.052 U1.AC18@184.397,305.539
  L1 w0.12: R932.1@250.14,308.751 v1(250.14,309.607) R986.1@250.14,310.463
  L5 (Sign) w0.12: v5(183.904,305.057) 184.441,304.521 184.537,304.521 184.551,304.534 186.856,304.534 188.027,305.706 192.123,305.706 192.806,306.389 192.825,306.389 192.85,306.413 218.934,306.413 221.239,308.718 249.251,308.718 v1(250.14,309.607)
Interrupt66: R934.1 R987.1 U1.AD19 | length 46.7
  L1 w0.116: v4(184.909,306.052) U1.AD19@185.397,306.539
  L1 w0.12: R934.1@227.686,308.751 v4(227.686,309.607) R987.1@227.686,310.463
  L3 (Sign) w0.12: v4(184.909,306.052) 184.983,306.052 185.522,306.591 186.563,306.591 186.639,306.667 189.586,306.667 189.674,306.756 220.091,306.756 222.141,308.805 226.884,308.805 v4(227.686,309.607)
Interrupt67: R936.1 R988.1 U1.AE19 | length 20.5
  L1 w0.116: v4(185.909,306.052) U1.AE19@186.397,306.539
  L1 w0.12: R936.1@229.183,308.751 v4(229.183,309.607) R988.1@229.183,310.463
  L3 (Sign) w0.12: v4(185.909,306.052) 186.156,306.299 186.682,306.299 186.771,306.387 187.048,306.387 190.578,306.387 190.662,306.471 ; 217.328,306.536 220.182,306.536 222.232,308.585 228.161,308.585 v4(229.183,309.607)
Interrupt68: R938.1 R989.1 U1.AG16 | length 40.3
  L1 w0.116: v4(187.909,303.052) U1.AG16@188.397,303.539
  L1 w0.12: R938.1@227.69,299.747 v4(227.69,300.816) R989.1@227.69,301.885
  L3 (Sign) w0.12: v4(187.909,303.052) 188.854,302.108 ; 192.397,302.108 220.605,302.108 222.263,300.45 227.323,300.45 v4(227.69,300.816)
Interrupt69: R940.1 R990.1 U1.AH16 | length 57.4
  L1 w0.116: v4(188.909,303.052) U1.AH16@189.397,303.539
  L1 w0.12: R940.1@241.159,308.751 v4(241.158,309.607) R990.1@241.158,310.463
  L3 (Sign) w0.12: v4(188.909,303.052) 189.319,303.052 189.695,303.428 218.523,303.428 219.87,304.776 220.911,304.776 222.955,306.82 238.371,306.82 v4(241.158,309.607)
Interrupt70: R942.1 R991.1 U1.AJ16 | length 61.4
  L1 w0.116: v4(189.909,303.052) U1.AJ16@190.397,303.539
  L1 w0.12: R942.1@245.649,308.751 v4(245.649,309.607) R991.1@245.649,310.463
  L3 (Sign) w0.12: v4(189.909,303.052) 190.562,302.4 218.949,302.4 220.665,304.116 221.185,304.116 223.164,306.096 242.138,306.096 v4(245.649,309.607)
Interrupt71: R944.1 R992.1 U1.AK16 | length 51
  L1 w0.116: U1.AK16@191.397,303.539 v4@191.884,304.027
  L1 w0.12: R944.1@238.165,308.751 v4(238.164,309.607) R992.1@238.164,310.463
  L3 (Sign) w0.12: v4(191.878,304.027) 218.275,304.027 219.464,305.216 220.729,305.216 222.778,307.265 235.822,307.265 v4(238.164,309.607)
Interrupt72: R946.1 R993.1 U1.AH17 | length 51
  L1 w0.116: v4(188.909,304.052) U1.AH17@189.397,304.539
  L1 w0.12: R946.1@235.171,308.751 v4(235.17,309.607) R993.1@235.17,310.463
  L3 (Sign) w0.12: v4(188.909,304.052) 189.276,304.419 190.06,304.419 190.263,304.622 218.028,304.622 219.062,305.656 220.547,305.656 222.596,307.705 233.268,307.705 v4(235.17,309.607)
Interrupt73: R948.1 R994.1 U1.AJ17 | length 51.5
  L1 w0.116: v4(189.909,304.052) U1.AJ17@190.397,304.539
  L1 w0.12: R948.1@236.668,308.751 v4(236.667,309.607) R994.1@236.667,310.463
  L3 (Sign) w0.12: v4(189.909,304.052) 190.235,304.052 190.564,304.381 190.765,304.381 190.771,304.387 218.126,304.387 219.175,305.436 220.638,305.436 222.687,307.485 234.545,307.485 v4(236.667,309.607)
Interrupt74: R950.1 R995.1 U1.AK17 | length 53.8
  L1 w0.116: v4(190.909,304.052) U1.AK17@191.397,304.539
  L1 w0.12: R950.1@239.662,308.751 v4(239.661,309.607) R995.1@239.661,310.463
  L3 (Sign) w0.12: v4(190.909,304.052) 191.209,304.052 191.604,303.657 218.428,303.657 219.767,304.996 220.82,304.996 222.87,307.045 237.099,307.045 v4(239.661,309.607)
Interrupt75: R952.1 R996.1 U1.AK18 | length 20.1
  L1 w0.116: U1.AK18@191.397,305.539 v4(191.884,305.052)
  L1 w0.12: R952.1@233.674,308.751 v4(233.674,309.607) R996.1@233.674,310.463
  L3 (Sign) w0.12: 217.85,305.052 218.674,305.876 220.456,305.876 222.505,307.925 231.991,307.925 v4(233.674,309.607)
Interrupt76: R954.1 R997.1 U1.AG18 | length 18.9
  L1 w0.116: v4(187.909,305.052) U1.AG18@188.397,305.539
  L1 w0.12: R954.1@230.68,308.751 v4(230.68,309.607) R997.1@230.68,310.463
  L3 (Sign) w0.12: v4(187.909,305.052) 188.292,305.435 189.126,305.435 189.393,305.702 ; 217.581,305.702 218.195,306.316 220.273,306.316 222.323,308.365 229.438,308.365 v4(230.68,309.607)
Interrupt77: R956.1 R998.1 U1.AH18 | length 19.4
  L1 w0.116: v4(188.909,305.052) U1.AH18@189.397,305.539
  L1 w0.12: R956.1@232.177,308.751 v4(232.177,309.607) R998.1@232.177,310.463
  L3 (Sign) w0.12: v4(188.909,305.052) 189.177,305.052 189.535,305.41 ; 217.702,305.41 218.388,306.096 220.364,306.096 222.414,308.145 230.714,308.145 v4(232.177,309.607)
Interrupt78: R958.1 R999.1 U1.AE18 | length 66.2
  L1 w0.116: v5@185.909,305.052 U1.AE18@186.397,305.539
  L1 w0.12: R958.1@247.146,308.751 v1(247.146,309.607) R999.1@247.146,310.463
  L5 (Sign) w0.12: v5(185.904,305.057) 186.389,305.057 187.244,305.913 188.989,307.657 196.672,307.657 197.46,306.87 218.745,306.87 221.05,309.175 246.714,309.175 v1(247.146,309.607)
Interrupt79: R960.1 R1000.1 U1.AF18 | length 66
  L1 w0.116: v5@186.909,305.052 U1.AF18@187.397,305.539
  L1 w0.12: R960.1@248.643,308.751 v1(248.643,309.607) R1000.1@248.643,310.463
  L5 (Sign) w0.12: v5(186.906,305.092) 186.941,305.057 188.525,306.642 218.839,306.642 221.145,308.947 247.983,308.947 v1(248.643,309.607)
JTAG_CLK: R1042.2 U39.20 | length 5.5
  L16 w0.12: R1042.2@107.214,286.337 107.214,285.495 107.632,285.077 108.269,285.077 109.049,284.297 U39.20@109.049,281.925
JTAG_TDI: R336.2 R1040.2 U39.23 | length 6.7
  L16 w0.12: U39.23@110.549,281.925 110.549,284.412 111.43,285.293 112.141,285.293 112.563,285.715 R1040.2@112.563,286.337 R336.2@113.633,286.337
JTAG_TDO: R337.2 R1043.2 U39.21 | length 5.6
  L16 w0.12: R1043.2@108.284,286.337 R337.2@109.354,286.337 109.549,286.141 U39.21@109.549,281.925
JTAG_TMS: R338.2 R1041.2 U39.22 | length 5.6
  L16 w0.12: U39.22@110.049,281.925 110.049,285.322 110.424,285.696 R1041.2@110.424,286.337 R338.2@111.494,286.337
LED_0: R329.1 U39.47 | length 3.6
  L16 w0.12: R329.1@104.826,271.994 104.826,272.339 106.049,273.562 U39.47@106.049,275.125
LED_0_RJ: R329.2 T21.17 | length 66.7
  L12 (Sign) w0.12: T21.17@52.632,252.221 55.119,252.221 56.794,250.546 71.285,250.546 73.279,252.54 79.553,252.54 v24(80.315,253.301)
  L14 (Sign) w0.12: v24(80.315,253.301) 81.496,254.483 81.496,261.659 84.035,264.198 93.063,264.198 97.889,269.024 v9(102.129,269.024)
  L16 w0.12: v9(102.129,269.024) 102.235,268.917 102.647,268.917 103.045,269.316 104.686,269.316 104.826,269.456 R329.2@104.826,271.094
LED_1: R330.1 U39.46 | length 3.4
  L16 w0.12: R330.1@105.908,271.994 105.908,272.507 106.549,273.148 U39.46@106.549,275.125
LED_1_RJ: R330.2 T21.18 | length 67.6
  L12 (Sign) w0.12: T21.18@52.632,249.681 52.672,249.681 53.317,250.326 71.406,250.326 73.4,252.32 80.181,252.32 v24(80.739,252.877)
  L14 (Sign) w0.12: v24(80.739,252.877) 81.737,253.875 81.737,261.559 84.135,263.957 93.163,263.957 97.806,268.6 v9(101.704,268.6)
  L16 w0.12: v9(101.704,268.6) 102.67,268.6 103.145,269.075 105.527,269.075 105.908,269.456 R330.2@105.908,271.094
LED_2: R331.1 U39.45 | length 3.2
  L16 w0.12: R331.1@106.991,271.994 107.049,272.052 U39.45@107.049,275.125
LED_2_RJ: R331.2 T21.19 | length 73.8
  L12 (Sign) w0.12: T21.19@52.632,242.571 56.295,246.234 56.295,249.446 56.955,250.106 71.51,250.106 73.504,252.1 80.81,252.1 v24(81.163,252.453)
  L14 (Sign) w0.12: v24(81.163,252.453) 81.966,253.255 81.966,261.465 84.229,263.728 93.258,263.728 97.705,268.176 v9(101.28,268.176)
  L16 w0.12: v9(101.28,268.176) 102.569,268.176 103.24,268.846 106.382,268.846 106.991,269.456 R331.2@106.991,271.094
LED_3: R332.2 U39.39 | length 3.2
  L16 w0.12: U39.39@110.049,275.125 110.049,272.066 R332.2@110.122,271.994
LED_3_RJ: R332.1 T21.20 | length 79.6
  L12 (Sign) w0.12: T21.20@52.632,240.031 56.515,243.914 56.515,249.354 57.046,249.886 71.631,249.886 73.625,251.88 81.438,251.88 v24(81.588,252.029)
  L14 (Sign) w0.12: v24(81.588,252.029) 82.207,252.648 82.207,261.365 84.329,263.487 93.358,263.487 97.622,267.751 v9(100.856,267.751)
  L16 w0.12: v9(100.856,267.751) 102.486,267.751 103.34,268.605 109.271,268.605 110.122,269.456 R332.1@110.122,271.094
LTC6952_0_MATCH_Out0_N: C315.1 J1_PCIE0.7 R1054.1
LTC6952_0_MATCH_Out0_P: C315.2 J1_PCIE0.5 R539.1
LTC6952_0_MATCH_Out1_N: C317.1 J1_PCIE2.7 R1056.1
LTC6952_0_MATCH_Out1_P: C317.2 J1_PCIE2.5 R1055.1
LTC6952_0_MATCH_Out2_N: C319.1 J1_PCIE3.7 R1058.1
LTC6952_0_MATCH_Out2_P: C319.2 J1_PCIE3.5 R1057.1
LTC6952_0_MATCH_Out3_N: C478.2 C530.1 U12.24
LTC6952_0_MATCH_Out3_P: C478.1 C529.1 U12.25
LTC6952_0_MATCH_Out4_N: C528.1 C594.1 U12.21
LTC6952_0_MATCH_Out4_P: C527.1 C594.2 U12.22
LTC6952_0_MATCH_Out5_N: C526.1 C599.2 U12.18
LTC6952_0_MATCH_Out5_P: C525.1 C599.1 U12.19
LTC6952_0_MATCH_Out6_N: C602.1 J27.53 R1068.1
LTC6952_0_MATCH_Out6_P: C602.2 J27.55 R1067.1
LTC6952_0_MATCH_Out7_N: C681.1 R1070.1
LTC6952_0_MATCH_Out7_P: C681.2 R1069.1
LTC6952_0_MATCH_Out8_N: R534.1 R1072.1 U13.38
LTC6952_0_MATCH_Out8_P: R534.2 R1071.1 U13.37
LTC6952_0_MATCH_Out9_N: R535.1 R1074.1 U13.48
LTC6952_0_MATCH_Out9_P: R535.2 R1073.1 U13.47
LTC6952_0_Out0_N: C54.2 R1054.2 U12.33
LTC6952_0_Out0_P: C54.1 R539.2 U12.34
LTC6952_0_Out1_N: C316.2 R1056.2 U12.30
LTC6952_0_Out1_P: C316.1 R1055.2 U12.31
LTC6952_0_Out2_N: C318.2 R1058.2 U12.27
LTC6952_0_Out2_P: C318.1 R1057.2 U12.28
LTC6952_0_Out6_N: C601.2 R1068.2 U12.15
LTC6952_0_Out6_P: C601.1 R1067.2 U12.16
LTC6952_0_Out7_N: C608.2 R1070.2 U12.12
LTC6952_0_Out7_P: C608.1 R1069.2 U12.13
LTC6952_0_Out8_N: C682.1 R1071.2 U12.9
LTC6952_0_Out8_P: C682.2 R1072.2
LTC6952_0_Out9_N: C684.1 R1073.2 U12.6
LTC6952_0_Out9_P: C684.2 R1074.2 U12.7
LTC6952_0_Out10_N: C48.1 R82.1 U12.3
LTC6952_0_Out10_P: C47.1 R82.2 U12.4
LTC6952_0_REF_N: C43.1 R78.2 U12.45
LTC6952_0_REF_P: C44.1 R78.1 U12.46
LTC6952_1_C_N: J5.2 R270.1 R1080.2
LTC6952_1_C_Out10_N: C52.2 J6.1
LTC6952_1_C_Out10_P: C51.2 J7.1
LTC6952_1_C_P: J4.2 R270.2 R1077.2
LTC6952_1_CP_Out: C46.2 R77.2 U12.43 X1.2
LTC6952_1_MATCH_Out0_N: C797.1 R1090.1
LTC6952_1_MATCH_Out0_P: C797.2 R1089.1
LTC6952_1_MATCH_Out1_N: C799.1 J1_PCIE4.7 R1092.1
LTC6952_1_MATCH_Out1_P: C799.2 J1_PCIE4.5 R1091.1
LTC6952_1_MATCH_Out2_N: C802.1 J1_PCIE1.7 R1094.1 | length 2.2
  L16 w0.081: 230.582,274.117 230.582,273.034 cw(c230.582,272.927) 230.69,272.927 J1_PCIE1.7@230.69,271.994
LTC6952_1_MATCH_Out2_P: C802.2 J1_PCIE1.5 R1093.1 | length 2.2
  L16 w0.081: J1_PCIE1.5@229.89,271.994 229.89,272.927 cw(c229.997,272.927) 229.997,273.034 229.997,274.117
LTC6952_1_MATCH_Out3_N: C690.2 R1084.1 U13.24
LTC6952_1_MATCH_Out3_P: C690.1 R1083.1 U13.25
LTC6952_1_MATCH_Out4_N: C806.1 R1098.1 U1.D9
  other v2: 165.397,296.539
LTC6952_1_MATCH_Out4_P: C806.2 R1097.1 U1.D10
  other v2: 165.397,297.539
LTC6952_1_MATCH_Out5_N: C808.1 R1101.1 U1.AH2 | length 0.7
  L1 w0.116: v4(188.909,289.052) U1.AH2@189.397,289.539
LTC6952_1_MATCH_Out5_P: C808.2 R1100.1 U1.AH3 | length 0.7
  L1 w0.116: v4(188.909,290.052) U1.AH3@189.397,290.539
LTC6952_1_MATCH_Out6_N: C812.1 R1104.1
LTC6952_1_MATCH_Out6_P: C812.2 R1103.1
LTC6952_1_MATCH_Out7_N: C814.1 R1106.1
LTC6952_1_MATCH_Out7_P: C814.2 R1105.1
LTC6952_1_MATCH_Out8_N: C816.1 R1108.1
LTC6952_1_MATCH_Out8_P: C816.2 R1107.1
LTC6952_1_MATCH_Out9_N: C818.1 R1110.1
LTC6952_1_MATCH_Out9_P: C818.2 R1109.1
LTC6952_1_Out0_N: C796.2 R1090.2 U13.33
LTC6952_1_Out0_P: C796.1 R1089.2 U13.34
LTC6952_1_Out1_N: C798.2 R1092.2 U13.30
LTC6952_1_Out1_P: C798.1 R1091.2 U13.31
LTC6952_1_Out2_N: C801.2 R1094.2 U13.27
LTC6952_1_Out2_P: C801.1 R1093.2 U13.28
LTC6952_1_Out4_N: C805.2 R1098.2 U13.21
LTC6952_1_Out4_P: C805.1 R1097.2 U13.22
LTC6952_1_Out5_N: C807.2 R1101.2 U13.18
LTC6952_1_Out5_P: C807.1 R1100.2 U13.19
LTC6952_1_Out6_N: C811.2 R1104.2 U13.15
LTC6952_1_Out6_P: C811.1 R1103.2 U13.16
LTC6952_1_Out7_N: C813.2 R1106.2 U13.12
LTC6952_1_Out7_P: C813.1 R1105.2 U13.13
LTC6952_1_Out8_N: C815.2 R1108.2 U13.9
LTC6952_1_Out8_P: C815.1 R1107.2 U13.10
LTC6952_1_Out9_N: C817.2 R1110.2 U13.6
LTC6952_1_Out9_P: C817.1 R1109.2 U13.7
LTC6952_1_Out10_N: C52.1 R536.1 U13.3
LTC6952_1_Out10_P: C51.1 R536.2 U13.4
LTC6952_1_REF_MATCH_N: C800.2 R1080.1 U13.46
LTC6952_1_REF_MATCH_P: C800.1 R1077.1 U13.45
LTC6952_1_Temp: R395.2 U12.49
LTC6952_1_VCO_N: C334.2 R80.1 R532.2 U12.38
LTC6952_1_VCO_P: R80.2 R533.1 U12.37
LTC6952_2_Temp: R398.2 U13.49
LTC6952_3_Temp: R506.2
MainExpReset: R1002.1 T1.3 U35_I2C_Expander_Main_Rst.14
MIO_0: R768.2 U1.H17 | length 0.7
  L1 w0.116: v5(168.909,305.027) U1.H17@169.397,304.539
MIO_1: R769.2 U1.A20 | length 2.1
  L1 w0.12: 160.333,307.539 U1.A20@162.397,307.539
MIO_2: R770.2 U1.B19 | length 3.3
  L1 w0.116: 162.909,307.027 U1.B19@163.397,306.539
  L1 w0.12: 160.333,307.027 162.909,307.027
MIO_3: R771.2 U1.D19 | length 0.7
  L1 w0.116: 164.909,307.027 U1.D19@165.397,306.539
MIO_4: R772.2 U1.J17 | length 0.7
  L1 w0.116: v5(169.909,305.027) U1.J17@170.397,304.539
MIO_5: R773.2 U1.C19 | length 6.8
  L1 w0.116: v4(163.909,307.027) U1.C19@164.397,306.539
  L3 (Sign) w0.12: 157.821,307.027 v4(163.909,307.027)
MIO_6: R774.2 U1.D20 | length 0.7
  L1 w0.116: 164.909,308.027 U1.D20@165.397,307.539
MIO_7: R775.2 U1.E19 | length 0.7
  L1 w0.116: 165.909,307.027 U1.E19@166.397,306.539
MIO_8: R776.2 U1.E20 | length 0.7
  L1 w0.116: 165.909,308.027 U1.E20@166.397,307.539
MIO_9: R777.2 U1.F20 | length 0.7
  L1 w0.116: 166.909,308.027 U1.F20@167.397,307.539
MIO_10: R778.2 U1.F18 | length 9.9
  L1 w0.116: v4(166.909,306.027) U1.F18@167.397,305.539
  L3 (Sign) w0.12: 158.001,306.095 159.728,306.095 160.134,305.689 166.572,305.689 v4(166.909,306.027)
MIO_11: R779.2 U1.G18 | length 0.7
  L1 w0.116: v5(167.909,306.027) U1.G18@168.397,305.539
MIO_12: R780.2 U1.H18 | length 0.7
  L1 w0.116: v5(168.909,306.027) U1.H18@169.397,305.539
MIO_13: R87.1 U1.G19 | length 76.1
  L1 w0.116: v5(167.909,307.027) U1.G19@168.397,306.539
  L5 (Sign) w0.12: v1(141.158,332.814) 146.662,332.814
  L14 (Sign) w0.12: 145.486,332.308 145.486,330.798 135.856,321.168 135.856,314.422 137.392,312.887 152.201,312.887 153.324,311.765 153.324,306.34 154.153,305.511 154.661,305.511 155.092,305.079 155.092,301.93 155.867,301.155 157.157,301.155 159.987,303.985 166.317,303.985 167.551,305.219 167.551,306.386 167.909,306.745 v5(167.909,307.027)
  L16 w0.12: R87.1@138.987,332.814 v1(141.158,332.814)
MIO_14: R88.1 U1.E18 | length 67.2
  L1 w0.116: v4(165.909,306.027) U1.E18@166.397,305.539
  L5 (Sign) w0.12: v1(141.158,330.731) 148.123,330.731
  L3 (Sign) w0.12: v1(153.733,307.784) 154.262,307.784 154.452,307.594 154.452,307.592 154.692,307.352 154.694,307.352 155.722,306.324 159.829,306.324 160.127,306.027 v4(165.909,306.027)
  L14 (Sign) w0.12: 145.706,332.308 145.706,330.707 136.076,321.077 136.076,314.513 137.483,313.107 152.293,313.107 153.544,311.856 153.544,307.974 v1(153.733,307.784)
  L16 w0.12: R88.1@138.987,330.731 v1(141.158,330.731)
MIO_15: R89.1 U1.J19 | length 78.4
  L1 w0.116: v5(169.909,307.027) U1.J19@170.397,306.539
  L5 (Sign) w0.12: v1(141.158,338.021) 143.043,338.021 144.685,336.378 144.711,336.378
  L14 (Sign) w0.12: 144.606,332.308 144.606,331.162 134.976,321.533 134.976,314.058 137.027,312.007 151.837,312.007 152.444,311.4 152.444,304.991 153.14,304.295 153.14,302.854 155.278,300.715 157.339,300.715 160.169,303.545 168.769,303.545 169.558,304.334 169.558,305.295 169.909,305.647 v5(169.909,307.027)
  L16 w0.12: R89.1@138.987,338.021 v1(141.158,338.021)
MIO_16: R90.1 U1.K17 | length 77.8
  L1 w0.116: v5(170.909,305.027) U1.K17@171.397,304.539
  L5 (Sign) w0.12: v1(141.158,335.938) 144.529,335.938
  L14 (Sign) w0.12: 144.166,332.308 144.166,331.345 134.536,321.715 134.536,313.875 136.845,311.567 151.655,311.567 152.004,311.218 152.004,304.809 152.7,304.113 152.7,302.659 155.171,300.188 157.558,300.188 160.465,303.095 169.808,303.095 170.349,303.636 170.349,304.455 170.909,305.015 v5(170.909,305.027)
  L16 w0.12: R90.1@138.987,335.938 v1(141.158,335.938)
MIO_17: R91.1 U1.C18 | length 71.3
  L1 w0.116: U1.C18@164.397,305.539 v4(164.884,305.052)
  L5 (Sign) w0.12: v1(141.158,336.979) 143.487,336.979 144.309,336.158 144.62,336.158
  L3 (Sign) w0.12: v1(153.556,303.936) 153.53,303.936 153.403,303.809 153.403,302.188 153.687,301.904 154.28,301.904 155.473,303.098 155.473,304.432 156.697,305.655 159.499,305.655 159.948,305.206 164.73,305.206 v4(164.884,305.052)
  L14 (Sign) w0.12: 144.826,332.308 144.826,331.071 135.196,321.442 135.196,314.149 137.118,312.227 151.928,312.227 152.664,311.491 152.664,305.133 153.556,304.241 v1(153.556,303.936)
  L16 w0.12: R91.1@138.987,336.979 v1(141.158,336.979)
MIO_18: R92.1 U1.K18 | length 79.4
  L1 w0.116: v5(170.909,306.027) U1.K18@171.397,305.539
  L5 (Sign) w0.12: v1(141.158,339.062) 142.027,339.062 142.848,338.241 143.134,338.241 144.777,336.598 144.802,336.598
  L14 (Sign) w0.12: 144.386,332.308 144.386,331.254 134.756,321.624 134.756,313.967 136.936,311.787 151.746,311.787 152.224,311.309 152.224,304.9 152.92,304.204 152.92,302.75 155.185,300.485 157.435,300.485 160.265,303.315 169.717,303.315 170.129,303.727 170.129,304.546 170.466,304.883 170.466,305.583 v5(170.909,306.027)
  L16 w0.12: R92.1@138.987,339.062 v1(141.158,339.062)
MIO_19: R93.1 U1.K16 | length 79.2
  L1 w0.116: v5(170.909,304.027) U1.K16@171.397,303.539
  L5 (Sign) w0.12: v1(141.158,340.103) 141.582,340.103 144.868,336.818 144.893,336.818
  L14 (Sign) w0.12: 143.946,332.308 143.946,331.436 134.316,321.806 134.316,313.784 136.754,311.347 151.564,311.347 151.784,311.127 151.784,304.718 152.48,304.022 152.48,302.568 155.144,299.903 157.676,299.903 160.647,302.875 169.899,302.875 170.569,303.545 170.569,303.687 v5(170.909,304.027)
  L16 w0.12: R93.1@138.987,340.103 v1(141.158,340.103)
MIO_20: R94.1 U1.A19 | length 56
  L1 w0.12: v1(154.064,307.226) 154.076,307.226 154.089,307.213 156.673,307.213 157.346,306.539 U1.A19@162.397,306.539
  L14 (Sign) w0.12: 145.926,332.308 145.926,330.616 136.296,320.986 136.296,314.604 137.574,313.327 152.384,313.327 153.763,311.947 153.763,308.466 154.178,308.051 154.178,307.492 154.064,307.378 v1(154.064,307.226)
  L16 w0.12: R94.1@138.987,329.689 v1(141.158,329.689) ; v1@154.064,307.175 v1(154.064,307.226)
MIO_21: R95.1 U1.H19 | length 78
  L1 w0.116: v5(168.909,307.027) U1.H19@169.397,306.539
  L5 (Sign) w0.12: v1(141.158,331.772) 147.392,331.772
  L14 (Sign) w0.12: 145.046,332.308 145.046,330.98 135.416,321.351 135.416,314.24 137.209,312.447 152.019,312.447 152.884,311.582 152.884,305.406 154.391,303.898 154.559,303.898 154.872,303.585 154.872,301.839 155.776,300.935 157.248,300.935 160.078,303.765 166.789,303.765 168.529,305.505 168.529,306.476 168.909,306.857 v5(168.909,307.027)
  L16 w0.12: R95.1@138.987,331.772 v1(141.158,331.772)
MIO_22: R96.1 U1.F17 | length 75.9
  L1 w0.116: U1.F17@167.397,304.539 v4(167.884,304.052)
  L5 (Sign) w0.12: v1(141.158,334.896) 145.202,334.896
  L3 (Sign) w0.12: v1(152.07,303.682) 151.879,303.492 151.879,303.2 153.568,301.511 154.394,301.511 155.867,302.984 155.867,304.33 156.972,305.435 159.408,305.435 159.86,304.983 164.256,304.983 165.188,304.052 v4(167.884,304.052)
  L14 (Sign) w0.12: 143.726,332.308 143.726,331.527 134.096,321.897 134.096,313.693 136.663,311.127 151.472,311.127 151.564,311.036 151.564,304.627 152.004,304.187 152.004,303.749 v1(152.07,303.682)
  L16 w0.12: R96.1@138.987,334.896 v1(141.158,334.896)
MIO_23: R781.2 U1.K19 | length 0.7
  L1 w0.116: 170.909,307.027 U1.K19@171.397,306.539
MIO_24: R782.2 U1.A18 | length 56
  L1 w0.12: v1(153.683,305.359) 154.032,305.708 155.905,305.708 156.074,305.539 U1.A18@162.397,305.539
  L14 (Sign) w0.12: 145.266,332.308 145.266,330.889 135.636,321.26 135.636,314.331 137.301,312.667 152.11,312.667 153.104,311.674 153.104,305.938 v1(153.683,305.359)
MIO_25: R783.2 U1.B18 | length 3.2
  L1 w0.116: 162.909,306.027 U1.B18@163.397,305.539
  L1 w0.12: 160.396,306.027 162.909,306.027
MIO_26: R784.2 U1.B20 | length 3.2
  L1 w0.116: 162.909,308.027 U1.B20@163.397,307.539
  L1 w0.12: 160.375,308.027 162.909,308.027
MIO_27: R785.2 U1.B21 | length 3.2
  L1 w0.116: 162.909,309.027 U1.B21@163.397,308.539
  L1 w0.12: 160.378,309.027 162.909,309.027
MIO_28: R786.2 U1.A21 | length 2.1
  L1 w0.12: 160.319,308.539 U1.A21@162.397,308.539
MIO_29: R787.2 U1.D21 | length 0.7
  L1 w0.116: 164.909,309.027 U1.D21@165.397,308.539
MIO_30: R788.2 U1.C21 | length 0.7
  L1 w0.116: 163.909,309.027 U1.C21@164.397,308.539
MIO_31: R789.2 U1.A22 | length 2
  L1 w0.12: 160.386,309.539 U1.A22@162.397,309.539
MIO_32: R790.2 U1.G20 | length 0.7
  L1 w0.116: 167.909,308.027 U1.G20@168.397,307.539
MIO_33: R791.2 U1.C22 | length 0.7
  L1 w0.116: v4(163.909,310.027) U1.C22@164.397,309.539
MIO_34: R792.2 U1.B24 | length 3.8
  L1 w0.116: 162.909,312.027 U1.B24@163.397,311.539
  L1 w0.12: v1(159.88,312.166) 160.146,312.166 160.286,312.027 162.909,312.027
MIO_35: R793.2 U1.B23 | length 4.5
  L1 w0.116: 162.909,311.027 U1.B23@163.397,310.539
  L1 w0.12: v1(159.135,311.027) 162.909,311.027
MIO_36: R794.2 U1.D22 | length 0.7
  L1 w0.116: v4(164.909,310.027) U1.D22@165.397,309.539
MIO_37: R795.2 U1.F21 | length 0.7
  L1 w0.116: 166.909,309.027 U1.F21@167.397,308.539
MIO_38: R796.2 U1.C23 | length 8.2
  L1 w0.116: v4(163.909,311.027) U1.C23@164.397,310.539
  L3 (Sign) w0.12: 157.112,311.099 157.836,310.375 161.087,310.375 161.955,311.243 163.631,311.243 163.847,311.027 v4(163.909,311.027)
MIO_39: R101.1 U1.E22 | length 0.7
  L1 w0.116: v4(165.909,310.027) U1.E22@166.397,309.539
MIO_40: R102.1 U1.C24 | length 10.4
  L1 w0.116: v4(163.909,312.027) U1.C24@164.397,311.539
  L3 (Sign) w0.12: 155.042,311.772 155.79,311.772 156.162,312.145 158.981,312.145 159.828,311.298 160.403,311.298 161.132,312.027 161.397,312.027 v4(163.909,312.027)
MIO_41: R103.1 U1.D24 | length 12.4
  L1 w0.116: v4(164.909,312.027) U1.D24@165.397,311.539
  L3 (Sign) w0.12: 154.711,312.204 155.173,312.204 154.961,312.416 159.021,312.416 159.919,311.518 160.312,311.518 161.291,312.497 161.397,312.497 164.44,312.497 v4(164.909,312.027)
MIO_42: R104.1 U1.E23 | length 9.3
  L1 w0.116: v4(165.909,311.027) U1.E23@166.397,310.539
  L3 (Sign) w0.12: 158.026,310.998 158.428,310.595 160.996,310.595 161.397,310.997 161.864,311.463 165.473,311.463 v4(165.909,311.027)
MIO_43: R797.2 U1.F22 | length 0.7
  L1 w0.116: v4(166.909,310.027) U1.F22@167.397,309.539
MIO_44: R798.2 U1.E24 | length 13
  L1 w0.116: v4(165.909,312.027) U1.E24@166.397,311.539
  L3 (Sign) w0.12: 154.584,313.677 155.625,312.636 158.884,312.636 159.216,312.969 161.397,312.969 164.501,312.969 164.574,312.895 164.574,312.888 164.771,312.692 164.777,312.692 164.871,312.598 165.338,312.598 v4(165.909,312.027)
MIO_45: R799.2 U1.F23 | length 11.3
  L1 w0.116: v4(166.909,311.027) U1.F23@167.397,310.539
  L3 (Sign) w0.12: 157.074,311.671 157.201,311.544 159.198,311.544 159.541,311.201 159.614,311.201 159.736,311.078 160.494,311.078 161.1,311.684 163.884,311.684 163.893,311.692 164.048,311.692 164.065,311.709 164.754,311.709 164.771,311.692 165.048,311.692 165.065,311.709 165.754,311.709 165.771,311.692 166.048,311.692 166.065,311.709 166.227,311.709 v4(166.909,311.027)
MIO_46: R105.1 U1.K20 | length 0.7
  L1 w0.116: 170.909,308.027 U1.K20@171.397,307.539
MIO_47: R107.1 U1.K21 | length 0.7
  L1 w0.116: 170.909,309.027 U1.K21@171.397,308.539
MIO_48: R108.1 U1.J21 | length 0.7
  L1 w0.116: 169.909,309.027 U1.J21@170.397,308.539
MIO_49: R110.1 U1.G21 | length 0.7
  L1 w0.116: 167.909,309.027 U1.G21@168.397,308.539
MIO_50: R111.1 U1.J20 | length 0.7
  L1 w0.116: 169.909,308.027 U1.J20@170.397,307.539
MIO_51: R112.1 U1.H21 | length 0.7
  L1 w0.116: 168.909,309.027 U1.H21@169.397,308.539
MIO_52: R362.1 U1.A24 | length 119.6
  L1 w0.12: R362.1@61.092,340.69 62.446,340.69 66.098,344.342 72.142,344.342 72.665,343.819 72.665,343.099 72.643,343.077 72.643,342.426 v4(72.226,342.01) ; v4(153.756,316.545) 153.773,316.528 155.201,316.528 157.675,314.054 157.675,313.616 158.338,312.952 158.359,312.952 159.772,311.539 U1.A24@162.397,311.539
  L3 (Sign) w0.12: 71.117,338.726 71.117,336.19 81.789,325.518 136.348,325.518 140.158,321.708 146.09,321.708 151.253,316.545 153.282,316.545 153.299,316.562 153.739,316.562 v4(153.756,316.545) ; v4(72.226,342.01) v4@72.243,342.026
MIO_53: R800.2 U1.B25 | length 118.5
  L1 w0.116: 162.909,313.027 U1.B25@163.397,312.539
  L1 w0.12: R800.2@61.092,339.474 62.45,339.474 67.098,344.122 72.051,344.122 72.445,343.728 72.445,343.19 72.423,343.168 72.423,342.842 v4(71.908,342.328) ; v4(154.711,317.499) 154.728,317.482 155.199,317.482 159.654,313.027 162.909,313.027
  L3 (Sign) w0.12: 71.777,338.382 71.777,336.534 71.798,336.513 71.798,336.506 71.86,336.445 71.86,336.432 71.921,336.37 71.921,336.364 71.982,336.303 71.982,336.296 72.037,336.241 72.037,336.235 72.101,336.171 72.101,336.164 72.166,336.1 72.166,336.093 82.068,326.191 136.627,326.191 140.437,322.381 146.369,322.381 151.251,317.499 154.237,317.499 154.254,317.516 154.694,317.516 v4(154.711,317.499) ; v4(71.908,342.328) v4@71.925,342.345
MIO_54: R115.1 U1.A23 | length 122.3
  L1 w0.12: R115.1@61.092,345.255 61.104,345.266 72.525,345.266 73.545,344.246 73.545,341.758 73.516,341.729 73.516,340.754 v4(73.499,340.737) ; v4(153.438,316.227) 153.455,316.21 155.208,316.21 157.455,313.963 157.455,313.525 158.712,312.268 158.712,310.858 159.03,310.539 U1.A23@162.397,310.539
  L3 (Sign) w0.12: 70.897,338.818 70.897,336.099 81.698,325.298 136.257,325.298 140.067,321.488 145.999,321.488 151.26,316.227 v4(153.438,316.227) ; v4(73.499,340.737) v4@73.516,340.754
MIO_55: R801.2 U1.B26 | length 118
  L1 w0.116: 162.503,314.027 162.99,313.539 U1.B26@163.397,313.539
  L1 w0.12: R801.2@61.093,341.831 62.45,341.831 65.18,344.562 72.233,344.562 72.885,343.91 72.885,342.032 v4(72.544,341.691) ; v4(155.347,318.136) 155.347,317.973 156.153,317.167 156.153,317.163 159.289,314.027 162.503,314.027
  L3 (Sign) w0.12: 72.217,338.199 72.217,336.717 72.257,336.677 72.257,336.67 72.321,336.605 72.321,336.592 72.386,336.528 72.386,336.521 72.45,336.457 72.45,336.45 72.477,336.424 72.477,336.417 82.254,326.64 136.813,326.64 140.623,322.83 146.555,322.83 151.25,318.136 154.873,318.136 154.89,318.153 155.33,318.153 v4(155.347,318.136) ; v4(72.544,341.691) v4@72.561,341.708
MIO_56: R116.1 U1.A25 | length 119.3
  L1 w0.12: R116.1@61.092,342.973 62.446,342.973 64.273,344.799 72.332,344.799 73.105,344.026 73.105,341.941 72.892,341.728 72.892,341.403 v4(72.863,341.373) ; v4(154.074,316.863) 154.091,316.846 155.194,316.846 157.895,314.145 157.895,313.707 158.394,313.207 159.004,313.207 159.487,312.725 160.309,312.725 160.494,312.539 U1.A25@162.397,312.539
  L3 (Sign) w0.12: 71.337,338.564 71.337,336.352 71.358,336.331 71.358,336.324 71.42,336.263 71.42,336.249 71.481,336.188 71.481,336.182 71.542,336.12 71.542,336.114 71.597,336.059 71.597,336.053 71.661,335.988 71.661,335.982 71.726,335.918 71.726,335.911 71.79,335.847 71.79,335.828 81.88,325.738 136.439,325.738 140.249,321.928 146.181,321.928 151.246,316.863 153.601,316.863 153.617,316.88 154.058,316.88 v4(154.074,316.863) ; v4(72.863,341.373) v4@72.879,341.39
MIO_57: R117.1 U1.A26 | length 117.8
  L1 w0.12: R117.1@61.092,344.114 62.45,344.114 63.382,345.046 72.434,345.046 73.325,344.155 73.325,341.85 73.198,341.722 73.198,341.072 v4(73.181,341.055) ; v4(155.029,317.817) 155.181,317.817 159.459,313.539 U1.A26@162.397,313.539
  L3 (Sign) w0.12: 71.997,338.291 71.997,336.626 72.037,336.586 72.037,336.579 72.101,336.514 72.101,336.501 72.166,336.436 72.166,336.43 72.23,336.366 72.23,336.359 72.257,336.333 72.257,336.326 72.321,336.262 72.321,336.255 82.161,326.416 136.72,326.416 140.53,322.606 146.462,322.606 151.251,317.817 154.555,317.817 154.572,317.834 155.012,317.834 v4(155.029,317.817) ; v4(73.181,341.055) v4@73.198,341.072
MIO_58: R118.1 U1.A28 | length 115
  L1 w0.12: R118.1@61.092,338.332 62.446,338.332 68.016,343.902 71.96,343.902 72.225,343.637 72.225,343.281 v4(71.59,342.646) ; v4(155.983,318.772) 156,318.755 156,317.951 158.412,315.539 U1.A28@162.397,315.539
  L3 (Sign) w0.12: v4(71.59,342.646) v4@71.607,342.663 ; 72.657,338.017 72.657,336.899 72.697,336.859 72.697,336.852 72.761,336.787 72.761,336.774 72.826,336.71 72.826,336.703 82.44,327.089 136.999,327.089 140.809,323.279 146.741,323.279 151.248,318.772 155.51,318.772 155.527,318.789 155.967,318.789 v4(155.983,318.772)
MIO_59: R119.1 U1.A27 | length 118.3
  L1 w0.12: R119.1@61.092,346.396 62.45,346.396 63.341,345.505 72.624,345.505 73.834,344.295 73.834,340.435 v4(73.817,340.419) ; v4(155.665,318.454) 155.682,318.437 155.682,317.952 159.094,314.539 U1.A27@162.397,314.539
  L3 (Sign) w0.12: 72.437,338.108 72.437,336.808 72.477,336.768 72.477,336.761 72.541,336.696 72.541,336.683 72.606,336.619 72.606,336.612 72.67,336.548 72.67,336.542 82.347,326.865 136.906,326.865 140.716,323.055 146.648,323.055 151.249,318.454 155.192,318.454 155.208,318.471 155.648,318.471 v4(155.665,318.454) ; v4(73.817,340.419) v4@73.834,340.435
MIO_60: R120.1 U1.C26 | length 123.4
  L1 w0.116: v4(163.909,314.027) U1.C26@164.397,313.539
  L1 w0.12: R120.1@61.092,347.538 62.446,347.538 64.259,345.725 72.715,345.725 74.152,344.288 74.152,340.117 v4(74.135,340.1) ; v4(154.393,317.181) 154.409,317.164 155.187,317.164 158.14,314.211 158.14,313.977 v4(158.389,313.728)
  L3 (Sign) w0.12: 71.557,338.473 71.557,336.443 71.578,336.422 71.578,336.415 71.64,336.354 71.64,336.341 71.701,336.279 71.701,336.273 71.762,336.212 71.762,336.205 71.817,336.15 71.817,336.144 71.881,336.08 71.881,336.073 71.946,336.009 71.946,336.002 72.01,335.938 72.01,335.919 81.971,325.958 136.53,325.958 140.34,322.148 146.273,322.148 151.239,317.181 153.919,317.181 153.936,317.198 154.376,317.198 v4(154.393,317.181) ; v4(158.389,313.728) 158.509,313.728 158.807,314.027 v4(163.909,314.027)
MIO_61: R121.1 U1.B29 | length 121.1
  L1 w0.116: 162.909,317.027 U1.B29@163.397,316.539
  L1 w0.12: R121.1@61.092,349.82 62.446,349.82 66.101,346.165 72.897,346.165 74.789,344.274 74.789,339.481 v4(74.772,339.464) ; v4(156.938,319.727) 156.955,319.71 156.955,317.957 157.885,317.027 162.909,317.027
  L3 (Sign) w0.12: 73.317,337.744 73.317,337.172 82.721,327.768 137.28,327.768 141.09,323.958 147.022,323.958 151.254,319.727 156.464,319.727 156.481,319.743 156.921,319.743 v4(156.938,319.727) ; v4(74.772,339.464) v4@74.789,339.481
MIO_62: R122.1 U1.B28 | length 123
  L1 w0.116: 162.909,316.027 U1.B28@163.397,315.539
  L1 w0.12: R122.1@61.092,350.961 62.45,350.961 67.026,346.385 72.988,346.385 75.107,344.267 75.107,339.163 v4(75.09,339.146) ; v4(156.302,319.09) 156.318,319.073 156.318,317.95 158.242,316.027 162.909,316.027
  L3 (Sign) w0.12: 72.877,337.926 72.877,336.99 72.917,336.95 72.917,336.943 72.981,336.879 72.981,336.865 82.533,327.314 137.092,327.314 140.902,323.504 146.834,323.504 151.248,319.09 155.828,319.09 155.845,319.107 156.285,319.107 v4(156.302,319.09) ; v4(75.09,339.146) v4@75.107,339.163
MIO_63: R802.2 U1.A29 | length 122.4
  L1 w0.12: R802.2@61.093,352.103 62.446,352.103 67.941,346.608 73.081,346.608 75.425,344.264 75.425,338.844 v4(75.408,338.828) ; v4(156.62,319.408) 156.637,319.392 156.637,317.956 158.054,316.539 U1.A29@162.397,316.539
  L3 (Sign) w0.12: 73.097,337.835 73.097,337.081 73.137,337.041 73.137,337.034 82.628,327.543 137.187,327.543 140.997,323.733 146.929,323.733 151.254,319.408 156.146,319.408 156.163,319.425 156.603,319.425 v4(156.62,319.408)
MIO_64: R803.2 U1.B30 | length 2.1
  L1 w0.116: 162.909,318.027 U1.B30@163.397,317.539
  L1 w0.12: 162.077,319.11 162.077,318.859 162.909,318.027
MIO_65: R804.2 U1.D25 | length 10.9
  L1 w0.116: v4(164.909,313.027) U1.D25@165.397,312.539
  L3 (Sign) w0.12: 155.232,313.67 156.046,312.856 158.793,312.856 159.125,313.189 164.685,313.189 164.847,313.027 v4(164.909,313.027)
MIO_66: R805.2 U1.C27 | length 6.5
  L1 w0.116: v5@163.884,315.074 v5(163.884,315.052) U1.C27@164.397,314.539
  L5 (Sign) w0.12: 158.725,316.446 162.49,316.446 v5(163.884,315.052)
MIO_67: R806.2 U1.C28 | length 6.1
  L1 w0.116: v4(163.909,316.027) U1.C28@164.397,315.539
  L3 (Sign) w0.12: 161.9,320.633 163.397,319.136 163.397,316.539 v4(163.909,316.027)
MIO_68: R807.2 U1.C29 | length 4.3
  L1 w0.116: 163.909,317.027 U1.C29@164.397,316.539
  L1 w0.12: 163.909,317.027 163.909,320.636
MIO_69: R808.2 U1.D27 | length 6.4
  L1 w0.12: v5(164.871,315.036) 164.9,315.036 U1.D27@165.397,314.539
  L5 (Sign) w0.12: 160.007,317 162.908,317 v5(164.871,315.036)
MIO_70: R809.2 U1.D26 | length 9.2
  L1 w0.116: v4(164.909,314.027) U1.D26@165.397,313.539
  L3 (Sign) w0.12: 156.769,313.728 157.104,313.393 158.707,313.393 158.945,313.631 158.953,313.639 164.522,313.639 v4(164.909,314.027)
MIO_71: R810.2 U1.D30 | length 3.1
  L1 w0.12: U1.D30@165.397,317.539 165.397,320.59
MIO_72: R811.2 U1.E27 | length 7.5
  L1 w0.116: v5(165.909,315.027) U1.E27@166.397,314.539
  L5 (Sign) w0.12: 159.463,315.112 159.971,314.604 165.487,314.604 v5(165.909,315.027)
MIO_73: R812.2 U1.E30 | length 3.1
  L1 w0.12: U1.E30@166.397,317.539 166.397,320.628
MIO_74: R813.2 U1.E29 | length 4.7
  L1 w0.116: 165.909,317.027 U1.E29@166.397,316.539
  L1 w0.12: 165.909,317.027 165.909,321.064
MIO_75: R814.2 U1.D29 | length 4.5
  L1 w0.116: 164.909,317.027 U1.D29@165.397,316.539
  L1 w0.12: 164.909,317.027 164.909,320.827
MIO_76: R815.2 U1.E28 | length 5.4
  L1 w0.12: U1.E28@166.397,315.539 166.891,316.033 166.891,320.686
MIO_77: R816.2 U1.E25 | length 11.1
  L1 w0.116: v4(165.909,313.027) U1.E25@166.397,312.539
  L3 (Sign) w0.12: 155.969,313.703 156.498,313.173 158.798,313.173 159.036,313.411 165.526,313.411 v4(165.909,313.027)
MIO_GPIO_0_12: J15.2 R780.1
MIO_GPIO_0_23: J16.2 R98.1 R781.1
MIO_GPIO_1_38: J17.2 R796.1
MIO_GPIO_2_66: J19.2 R805.1
MIO_GPIO_2_70: J20.2 R809.1
MIO_GPIO_2_73: J22.2 R812.1
MIO_GPIO_2_74: J23.2 R813.1 U36_U_Translator_I2C2.8
MIO_GPIO_2_75: J24.2 R814.1 U36_U_Translator_I2C3.8
MODE: R669.2 R670.1 U65.2 | length 3.6
  L1 w0.254: R670.1@37.668,200.838 38.26,200.838 ; U65.2@38.26,202.478 38.26,200.838 ; R669.2@38.887,199.931 38.537,199.931 38.26,200.208 38.26,200.838
NetBT1_2: BT1.2 R650.1 T22.2
NetC36_1: C36.1 R52.2 R54.2 | length 3.4
  L1 w0.5: R52.2@157.837,331.433 156.878,331.433 C36.1@156.346,331.965 156.903,332.522 R54.2@157.837,332.522
NetC45_2: C45.2 R77.1
NetC78_2: C78.2 U16.7
NetC79_2: C79.2 U16.38
NetC80_2: C80.2 U16.48
NetC91_1: C91.1 U16.39
NetC96_1: C96.1 U16.47
NetC312_2: C312.2 U4.11
NetC313_2: C313.2 U5.11
NetC314_1: C314.1 U48.11
NetC320_1: C320.1 U30.9
NetC321_1: C321.1 U30.10
NetC322_2: C322.2 U30.3 X3.1
NetC323_2: C323.2 U30.2 X3.2
NetC333_1: C333.1 R537.2
NetC334_1: C334.1 X1.10
NetC335_2: C335.2 R532.1 R533.2
NetC341_1: C341.1 J26.1
NetC351_2: C351.2 R268.2 U34.3 | length 4.2
  L1 w0.254: R268.2@59.692,237.714 60.97,237.714 61.118,237.565 61.118,236.791 C351.2@61.146,236.764 61.151,236.764 61.776,236.139 U34.3@62.822,236.139
NetC356_2: C356.2 R272.2 R277.1 R278.1 U34.2 U34.4 U34.7 U34.9 U34.32 | length 23.6
  L1 w0.254: U34.4@62.822,235.639 61.694,235.639 61.667,235.666 60.285,235.666 60.109,235.49 60.109,235.185 R272.2@60.156,235.139 60.206,235.139 60.479,234.866 60.479,234.745 60.783,234.441 60.783,233.982 60.926,233.839 C356.2@60.931,233.839 61.589,233.839 61.99,233.437 v19(62.009,233.437) 62.049,233.437 62.347,233.139 U34.9@63.322,233.139 ; U34.2@62.822,236.639 62.481,236.639 62.057,237.063 62.057,237.421 v19@62.125,237.489 ; U34.32@63.322,237.639 63.322,237.703 63.32,237.705 62.341,237.705 v19@62.125,237.489 ; R278.1@63.439,240.856 63.077,240.856 62.085,239.863 62.085,237.528 v19@62.125,237.489
  L16 w0.254: v19(62.085,237.489) 62.085,237.449 62.009,237.373 v19(62.009,233.437) 62.009,231.673 v25(64.365,229.317)
NetC357_2: C357.2 U34.13 U34.28 | length 10.4
  L1 w0.254: v25(64.511,231.163) 64.583,231.235 64.816,231.235 65.315,231.734 65.315,232.984 65.32,232.989 65.32,233.137 U34.13@65.322,233.139 ; U34.28@65.322,237.639 v19(65.322,238.22)
  L16 w0.254: v25(64.511,231.163) 64.949,231.601 64.949,237.847 v19(65.322,238.22)
NetC471_2: C471.2 T21.12
NetC472_2: C472.2 T21.6
NetC473_2: C473.2 T21.1
NetC474_2: C474.2 T21.7
NetC475_2: C475.2 T21.S1
NetC476_2: C476.2 T21.S2
NetC532_1: C532.1 U44.14
NetC533_1: C533.1 U44.15
NetC534_1: C534.1 U44.16
NetC537_1: C537.1 FB26.2
NetC537_4: C537.4 FB27.2
NetC537_Z1: C537.Z1 FB28.1
NetC549_2: C549.2 R687.1 | length 1.1
  L1 w0.254: C549.2@61.948,212.229 61.951,212.227 61.951,211.171 R687.1@61.953,211.169
NetC558_Z1: C558.Z1 C558.Z2 C672.2
NetC568_2: C568.2 FB33.1 R433.2 U60.10 U60.11 U60.12 U60.13 U60.14
NetC571_1: C571.1 U60.7
NetC573_1: C573.1 R436.1 R437.2 U61.16
NetC577_1: C577.1 R438.1 R439.2 U61.10
NetC578_2: C578.2 U61.7
NetC579_2: C579.2 U61.19
NetC581_2: C581.2 C582.2 C583.2 FB34.2 R442.2 U62.1 U62.2 U62.3
NetC584_2: C584.2 R445.2 U62.7
NetC588_1: C588.1 R543.2
NetC588_2: C588.2 C589.1 R545.2
NetC591_2: C591.2 C592.2 FB37.2 X9.4
NetC597_2: C597.2 R140.1 U65.17 | length 3.4
  L1 w0.254: C597.2@34.722,206.35 34.722,205.41 R140.1@34.747,205.384 35.433,205.384 36,204.818 U65.17@36.92,204.818
NetC603_1: C603.1 R113.1 R114.2 U19.20
NetC604_1: C604.1 U19.25 | length 4.4
  L1 w0.254: U19.25@174.078,171.85 174.08,171.852 174.08,172.319 174.58,172.819 175.206,172.819 175.603,173.217 175.603,173.963 176.22,174.58 176.22,174.765 176.363,174.908 C604.1@176.368,174.908
NetC605_1: C605.1 R212.1 R214.2 U19.21
NetC612_1: C612.1 R216.2 R218.2 U19.22
NetC616_1: C616.1 R220.1 R274.2 U19.19
NetC633_2: C633.2 R613.1 | length 2.3
  L1 w0.254: R613.1@90.765,247.284 C633.2@93.052,247.284
NetC634_2: C634.2 R615.2 U34.11 U34.30 | length 14.8
  L1 w0.254: v19(61.056,231.693) 63.519,231.693 64.315,232.489 64.315,232.984 64.32,232.989 64.32,233.137 U34.11@64.322,233.139 ; v19(64.297,238.715) 64.32,238.692 U34.30@64.322,237.639 U34.30@64.322,237.639
  L16 w0.254: v19(61.056,231.693) R615.2@61.056,234.739 61.042,234.753 61.042,235.71 C634.2@61.028,235.724 61.028,235.729 61.301,236.002 61.392,236.002 61.525,236.135 61.525,237.705 62.535,238.715 v19(64.297,238.715)
NetC635_2: C635.2 R615.1 | length 1
  L16 w0.254: C635.2@60.062,235.724 60.109,235.677 60.109,234.785 R615.1@60.156,234.739
NetC636_2: C636.2 R616.1 | length 2.2
  L1 w0.254: R616.1@90.717,224.031 C636.2@92.942,224.031
NetC637_2: C637.2 R288.1 | length 1
  L1 w0.254: 87.033,189.468 87.568,189.468 C637.2@87.909,189.81
NetC638_2: C638.2 R298.1 | length 1.1
  L1 w0.254: 88.405,173.59 88.411,173.596 88.938,173.596 C638.2@89.332,173.99
NetC643_2: C643.2 R623.1 | length 1.1
  L1 w0.254: C643.2@63.12,173.949 R623.1@63.12,175.007
NetC644_2: C644.2 R624.1 | length 1
  L1 w0.254: R624.1@63.175,184.21 C644.2@63.175,185.176
NetC645_2: C645.2 R306.1 | length 0.9
  L1 w0.254: 87.566,203.543 87.564,203.54 87.564,203.257 C645.2@87.964,202.857
NetC646_2: C646.2 R316.1 | length 1.1
  L1 w0.254: C646.2@84.502,207.488 85.052,206.938 85.052,206.654
NetC652_2: C652.2 R631.1
NetC655_1: C655.1 U49.6
NetC656_1: C656.1 U50.6
NetC657_1: C657.1 U51.6
NetC674_2: C674.2 FB45.1 R644.2 U69.10 U69.11 U69.12 U69.13 U69.14
NetC678_2: C678.2 R652.2 R654.2 T25.1 T29.3
NetC679_2: C679.2 D23.1 D24.1 J36.1
NetC680_2: C680.2 R656.1 R657.1 T30.1
NetC693_1: C693.1 L22.1 T34.1 T34.2 T34.3 T35.5 U65.12 | length 3.2
  L1 w0.254: U65.12@39.26,206.158 39.26,207.104 39.98,207.823 C693.1@39.98,209.037
NetC693_2: C693.2 D26.1 R665.1 | length 6.9
  L1 w0.254: R665.1@39.014,209.828 39.025,209.817 C693.2@39.98,209.817
  L1 w0.5: D26.1@34.353,210.921 35.856,210.921 36.25,211.315 38.427,211.315 39.014,210.728 R665.1@39.014,209.828
NetC701_1: C701.1 R667.2 | length 2.9
  L1 w0.254: C701.1@41.097,200.121 41.676,200.121 42.078,200.524 R667.2@42.078,202.265
NetC701_2: C701.2 C702.2 U65.5 | length 2.7
  L1 w0.254: U65.5@39.76,202.478 39.76,201.311 C702.2@40.17,200.901 C701.2@41.097,200.901
NetC703_2: C703.2 U65.7 | length 1.7
  L1 w0.254: U65.7@40.6,203.818 41.292,203.818 41.38,203.73 41.759,203.73 C703.2@42.127,204.097
NetC706_1: C706.1 R671.1 R672.2 U70.16
NetC710_1: C710.1 R673.1 R674.2 U70.10
NetC711_2: C711.2 U70.7
NetC712_2: C712.2 U70.19
NetC713_2: C713.2 U71.3 X1.14
NetC719_2: C719.2 U69.7
NetC724_1: C724.1 R384.1
NetC725_1: C725.1 R385.1
NetC726_1: C726.1 R484.1
NetC727_1: C727.1 R485.1
NetC790_1: C790.1 U76.3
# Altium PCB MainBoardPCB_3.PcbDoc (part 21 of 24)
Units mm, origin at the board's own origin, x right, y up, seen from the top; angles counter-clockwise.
Board outline 258.95 x 308.86 mm, 16 copper layers (L1, L2 (GND), L3 (Sign), L4 (GND), L5 (Sign), L6 (PWR/GND), L7(PWR/GND), L8 (Plane_GND), L9 (PWR/GND), L10 (PWR/GND), L11 (PWR/GND), L12 (Sign), L13 (GND), L14 (Sign), L15 (GND), L16), stack 2.502 mm thick; 2402 components, 1749 nets, 8407 pads, 3409 vias.
Unrouted connection lines stored in the file: 4352.

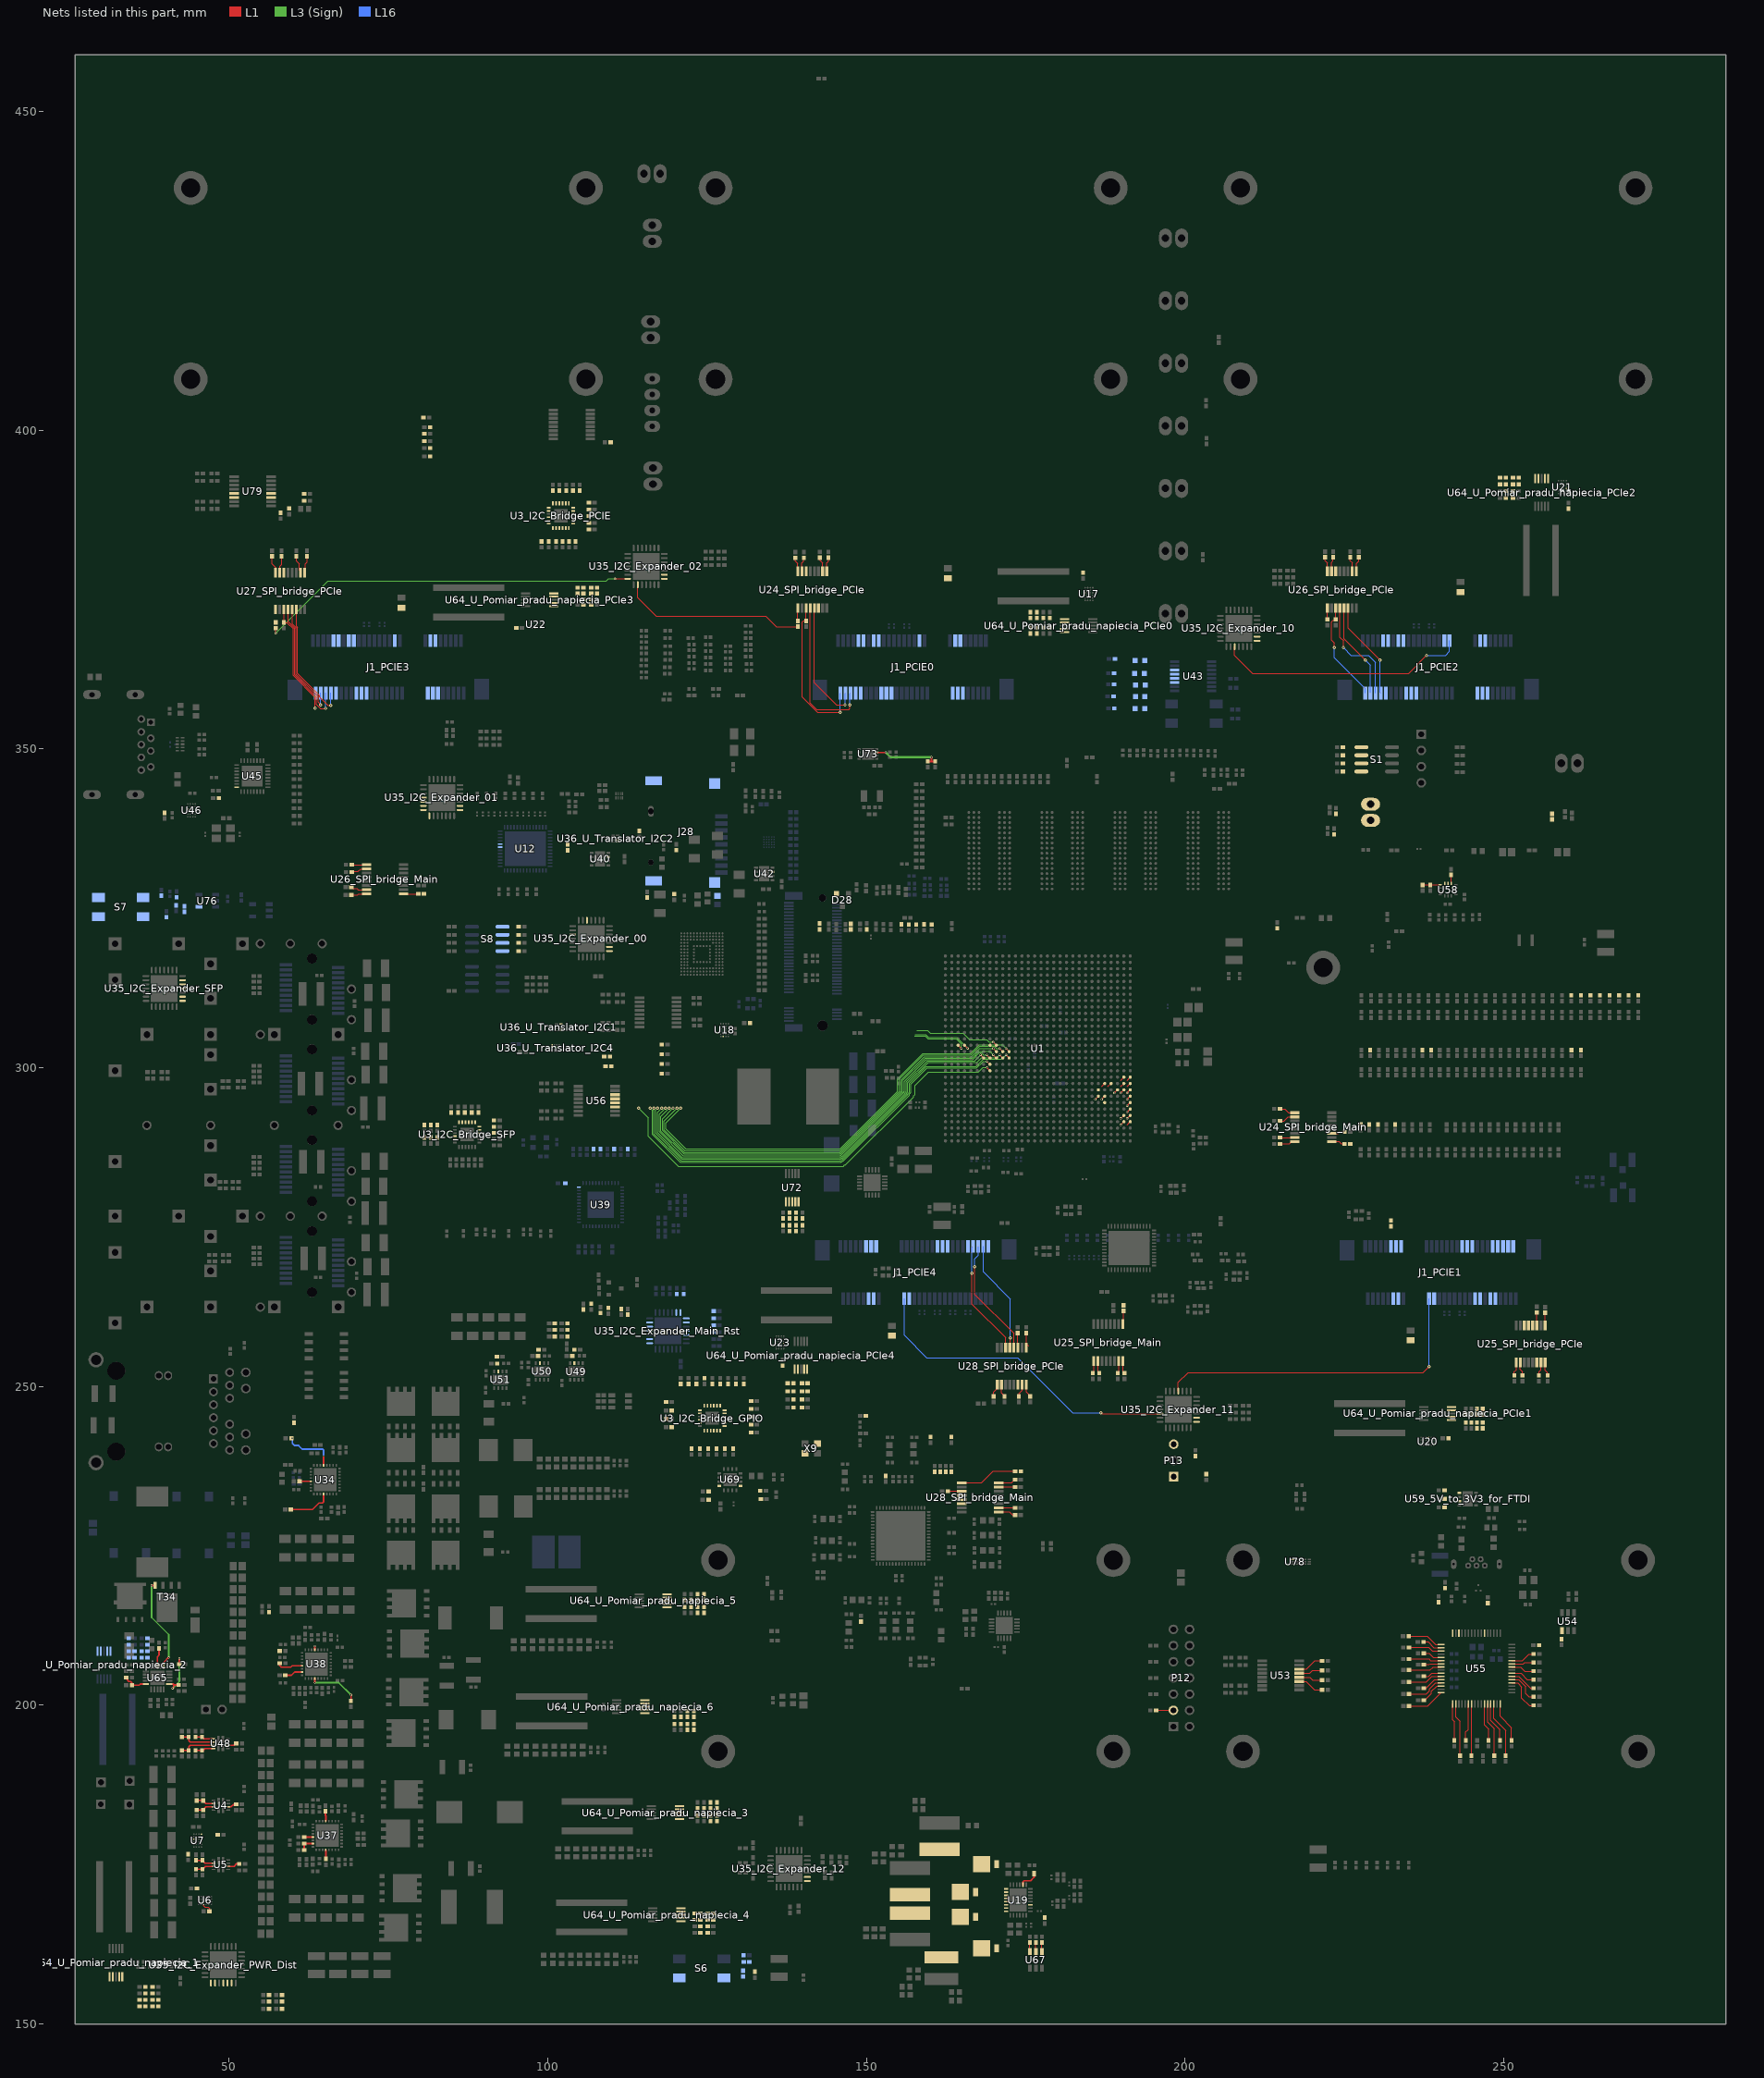
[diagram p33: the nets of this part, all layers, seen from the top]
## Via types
v1: diameter 0.5, hole 0.2, L1 to L16, tented both sides, 1267 vias
v2: diameter 0.5/0.35/0.35/0.35/0.35/0.35/0.35/0.35/0.35/0.35/0.35/0.35/0.35/0.35/0.35/0.5 (per signal layer), hole 0.15, L1 to L16, tented both sides, 463 vias
v3: diameter 0.5, hole 0.2, L1 to L16, 446 vias
v4: diameter 0.35/0/0.35 (per signal layer), hole 0.127, L1 to L3 (Sign), tented both sides, 347 vias
v5: diameter 0.5/0.35/0.35/0.35/0.35/0.35/0.35/0.35/0.35/0.35/0.35/0.35/0.35/0.35/0.35/0.5 (per signal layer), hole 0.2, L1 to L16, tented both sides, 244 vias
v6: diameter 0.8, hole 0.4, L1 to L16, tented both sides, 168 vias
v7: diameter 2.54, hole 1.02, L1 to L16, 113 vias
v8: diameter 1.4, hole 0.5, L1 to L16, tented both sides, 80 vias
v9: diameter 0.5/0/0.5 (per signal layer), hole 0.2, L14 (Sign) to L16, tented both sides, 62 vias
v10: diameter 0.35/0/0.35 (per signal layer), hole 0.127, L1 to L3 (Sign), 38 vias
v11: diameter 0.35, hole 0.127, L1 to L2 (GND), tented both sides, 36 vias
v12: diameter 0.4, hole 0.2, L1 to L16, 16 vias
v13: diameter 0.25, hole 0.2, L1 to L16, 16 vias
v14: diameter 0.35, hole 0.127, L1 to L16, tented both sides, 16 vias
v15: diameter 0.3, hole 0.2, L1 to L16, 15 vias
v16: diameter 0.45, hole 0.15, L1 to L16, 12 vias
v17: diameter 0.5/0.35/0.35/0.35/0.35/0.35/0.35/0.35/0.35/0.35/0.35/0.35/0.35/0.35/0.35/0.45 (per signal layer), hole 0.15, L1 to L16, tented both sides, 10 vias
v18: diameter 0.2/0/0.2 (per signal layer), hole 0.1, L1 to L3 (Sign), tented both sides, 9 vias
v19: diameter 0.4, hole 0.1, L1 to L16, 7 vias
v20: diameter 0.5, hole 0.2, L3 (Sign) to L6 (PWR/GND), tented both sides, 6 vias
v21: diameter 1.15, hole 1.15, L1 to L16, 5 vias
v22: diameter 1.65, hole 1.65, L1 to L16, 5 vias
v23: diameter 0.35/0/0.35 (per signal layer), hole 0.127, L14 (Sign) to L16, tented both sides, 5 vias
v24: diameter 0.5, hole 0.2, L11 (PWR/GND) to L14 (Sign), tented both sides, 4 vias
v25: diameter 0.2, hole 0.1, L1 to L16, 4 vias
v26: diameter 0.35, hole 0.127, L1 to L2 (GND), 2 vias
v27: diameter 0.4, hole 0.15, L1 to L16, 2 vias
v28: diameter 0.4, hole 0.2, L1 to L16, tented both sides, 2 vias
v29: diameter 0.5/0.35/0.35/0.35/0.35/0.35/0.35/0.35/0.35/0.35/0.35/0.35/0.35/0.35/0.35/0.5 (per signal layer), hole 0.15, L1 to L16, 2 vias
v30: diameter 0.35, hole 0.127, L3 (Sign) to L6 (PWR/GND), tented both sides, 2 vias
v31: diameter 0.5/0.35/0.35/0.35/0.35/0.35/0.35/0.35/0.35/0.35/0.35/0.35/0.35/0.35/0.35/0.5 (per signal layer), hole 0.2, L1 to L16, 1 vias
v32: diameter 0.35/0.35/0.35 (per signal layer), hole 0.127, L1 to L3 (Sign), tented both sides, 1 vias
v33: diameter 0.45/0/0.45 (per signal layer), hole 0.15, L1 to L3 (Sign), tented both sides, 1 vias
v34: diameter 0.45/0/0.45 (per signal layer), hole 0.2, L14 (Sign) to L16, tented both sides, 1 vias
v35: diameter 0.35, hole 0.127, L2 (GND) to L3 (Sign), 1 vias

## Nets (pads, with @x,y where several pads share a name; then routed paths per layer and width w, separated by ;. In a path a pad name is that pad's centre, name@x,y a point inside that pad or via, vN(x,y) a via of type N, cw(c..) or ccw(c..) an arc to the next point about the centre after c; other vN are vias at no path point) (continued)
NetD5_1: D5.1 R716.1
NetD5_2: D5.2 U43.14
NetD6_1: D6.1 R717.1
NetD6_2: D6.2 U43.13
NetD7_1: D7.1 R718.1
NetD7_2: D7.2 D9.1 U43.12
NetD8_1: D8.1 R719.1
NetD8_2: D8.2 U43.11
NetD9_2: D9.2 R720.1
NetD10_1: D10.1 R368.1
NetD10_2: D10.2 U44.12
NetD11_2: D11.2 R370.1 S4.1 S4.2 U44.7
NetD12_2: D12.2 R369.1 S3.1 S3.2 U44.6
NetD16_1: D16.1 L13.1 U19.5
NetD16_2: D16.2 U19.6
NetD17_1: D17.1 L16.1 U19.4
NetD17_2: D17.2 U19.3
NetD18_1: D18.1 L17.1 U19.2
NetD18_2: D18.2 U19.1
NetD19_1: D19.1 L18.1 U19.7
NetD19_2: D19.2 U19.8
NetD20_1: D20.1 D21.1 R647.1
NetD20_2: D20.2 T23.3
NetD21_2: D21.2 T27.3
NetD28_2: D28.2 R276.2
NetF1_PCIE0_1: F1_PCIE0.1 J1_PCIE0.20
NetF1_PCIE1_1: F1_PCIE1.1 J1_PCIE1.20
NetF1_PCIE2_1: F1_PCIE2.1 J1_PCIE2.20
NetF1_PCIE3_1: F1_PCIE3.1 J1_PCIE3.20
NetF1_PCIE4_1: F1_PCIE4.1 J1_PCIE4.20
NetFB29_2: FB29.2 J28.10 J28.11 J28.12 J28.13
NetJ1_PCIE0_11: J1_PCIE0.11 R507.2
NetJ1_PCIE0_12: J1_PCIE0.12 U1.AK10 | length 0.7
  L1 w0.116: 190.909,297.052 U1.AK10@191.397,297.539
NetJ1_PCIE0_13: J1_PCIE0.13 R558_I2C_Bridge_PCIE.1 U3_I2C_Bridge_PCIE.3
NetJ1_PCIE0_14: J1_PCIE0.14 U1.AJ10 | length 0.7
  L1 w0.116: 189.909,297.052 U1.AJ10@190.397,297.539
NetJ1_PCIE0_15: J1_PCIE0.15 R227_I2C_Bridge_PCIE.1 U3_I2C_Bridge_PCIE.4
NetJ1_PCIE0_31: J1_PCIE0.31 U1.AJ11 | length 0.7
  L1 w0.116: 189.909,298.052 U1.AJ11@190.397,298.539
NetJ1_PCIE0_33: J1_PCIE0.33 U1.AK11 | length 0.7
  L1 w0.116: 190.909,298.052 U1.AK11@191.397,298.539
NetJ1_PCIE0_36: J1_PCIE0.36
NetJ1_PCIE0_38: J1_PCIE0.38
NetJ1_PCIE0_42: J1_PCIE0.42
NetJ1_PCIE0_43: J1_PCIE0.43 R967.2
NetJ1_PCIE0_44: J1_PCIE0.44
NetJ1_PCIE0_45: J1_PCIE0.45 U24_SPI_bridge_PCIe.14
NetJ1_PCIE0_47: J1_PCIE0.47 U24_SPI_bridge_PCIe.12 | length 24.1
  L1 w0.12: U24_SPI_bridge_PCIe.12@141.182,372.107 141.182,357.23 142.189,356.222 147.251,356.222 147.423,356.394 v3(147.423,356.906)
  L16 w0.12: v3(147.423,356.906) 147.423,358.677 J1_PCIE0.47@147.537,358.792
NetJ1_PCIE0_49: J1_PCIE0.49 U24_SPI_bridge_PCIe.13 | length 19.9
  L1 w0.12: U24_SPI_bridge_PCIe.13@141.832,372.107 141.832,360.415 145.341,356.906 v3(146.648,356.906)
  L16 w0.12: v3(146.648,356.906) 146.648,358.702 J1_PCIE0.49@146.737,358.792
NetJ1_PCIE0_51: J1_PCIE0.51 R231_SPI_bridge_PCIe.1 U24_SPI_bridge_PCIe.11 | length 24.4
  L1 w0.12: U24_SPI_bridge_PCIe.11@140.532,372.107 R231_SPI_bridge_PCIe.1@140.532,370.11 140.132,370.11 139.933,369.91 139.933,358.168 142.336,355.764 v3(145.898,355.764)
  L16 w0.12: v3(145.898,355.764) 145.898,358.752 J1_PCIE0.51@145.937,358.792
NetJ1_PCIE1_11: J1_PCIE1.11 R514.2
NetJ1_PCIE1_12: J1_PCIE1.12 U1.AK8 | length 0.7
  L1 w0.116: v4(190.909,295.052) U1.AK8@191.397,295.539
NetJ1_PCIE1_13: J1_PCIE1.13 R226_I2C_Bridge_PCIE.1 U3_I2C_Bridge_PCIE.5
NetJ1_PCIE1_14: J1_PCIE1.14 U1.AK9 | length 0.7
  L1 w0.116: v4(190.909,296.052) U1.AK9@191.397,296.539
NetJ1_PCIE1_15: J1_PCIE1.15 R225_I2C_Bridge_PCIE.1 U3_I2C_Bridge_PCIE.6
NetJ1_PCIE1_18: J1_PCIE1.18 U35_I2C_Expander_11.18 | length 52.4
  L1 w0.12: U35_I2C_Expander_11.18@198.939,249.285 198.939,250.653 200.495,252.209 237.382,252.209 v3(238.29,253.117)
  L16 w0.12: v3(238.29,253.117) J1_PCIE1.18@238.29,263.794
NetJ1_PCIE1_31: J1_PCIE1.31 U1.AF10 | length 0.7
  L1 w0.116: 186.909,297.052 U1.AF10@187.397,297.539
NetJ1_PCIE1_33: J1_PCIE1.33 U1.AG10 | length 0.7
  L1 w0.116: 187.909,297.052 U1.AG10@188.397,297.539
NetJ1_PCIE1_36: J1_PCIE1.36
NetJ1_PCIE1_38: J1_PCIE1.38
NetJ1_PCIE1_42: J1_PCIE1.42
NetJ1_PCIE1_43: J1_PCIE1.43 R968.2
NetJ1_PCIE1_44: J1_PCIE1.44
NetJ1_PCIE1_45: J1_PCIE1.45 U25_SPI_bridge_PCIe.14
NetJ1_PCIE1_47: J1_PCIE1.47 U25_SPI_bridge_PCIe.12
NetJ1_PCIE1_49: J1_PCIE1.49 U25_SPI_bridge_PCIe.13
NetJ1_PCIE1_51: J1_PCIE1.51 R233_SPI_bridge_PCIe.1 U25_SPI_bridge_PCIe.11 | length 2
  L1 w0.12: U25_SPI_bridge_PCIe.11@255.191,259.567 R233_SPI_bridge_PCIe.1@255.191,261.614
NetJ1_PCIE2_11: J1_PCIE2.11 R901.2
NetJ1_PCIE2_12: J1_PCIE2.12 U1.AF7
NetJ1_PCIE2_13: J1_PCIE2.13 R224_I2C_Bridge_PCIE.1 U3_I2C_Bridge_PCIE.7
NetJ1_PCIE2_14: J1_PCIE2.14 U1.AF8 | length 0.7
  L1 w0.116: v4(186.909,295.052) U1.AF8@187.397,295.539
NetJ1_PCIE2_15: J1_PCIE2.15 R223_I2C_Bridge_PCIE.1 U3_I2C_Bridge_PCIE.8
NetJ1_PCIE2_18: J1_PCIE2.18 U35_I2C_Expander_10.3 | length 39.4
  L1 w0.12: U35_I2C_Expander_10.3@207.78,366.065 207.78,364.693 210.599,361.874 235.074,361.874 v3(237.89,364.689)
  L16 w0.12: v3(237.89,364.689) 240.875,364.689 241.49,365.304 J1_PCIE2.18@241.49,366.992
NetJ1_PCIE2_31: J1_PCIE2.31 U1.AH9 | length 0.7
  L1 w0.116: v4(188.909,296.052) U1.AH9@189.397,296.539
NetJ1_PCIE2_33: J1_PCIE2.33 U1.AJ9 | length 0.7
  L1 w0.116: v4(189.909,296.052) U1.AJ9@190.397,296.539
NetJ1_PCIE2_36: J1_PCIE2.36
NetJ1_PCIE2_38: J1_PCIE2.38
NetJ1_PCIE2_42: J1_PCIE2.42
NetJ1_PCIE2_43: J1_PCIE2.43 R969.2
NetJ1_PCIE2_44: J1_PCIE2.44
NetJ1_PCIE2_45: J1_PCIE2.45 U26_SPI_bridge_PCIe.14 | length 15.4
  L1 w0.12: U26_SPI_bridge_PCIe.14@225.59,372.107 225.59,368.937 v3(230.573,363.954)
  L16 w0.12: v3(230.573,363.954) 230.573,358.909 J1_PCIE2.45@230.69,358.792
NetJ1_PCIE2_47: J1_PCIE2.47 U26_SPI_bridge_PCIe.12 | length 17.3
  L1 w0.12: U26_SPI_bridge_PCIe.12@224.29,372.107 224.29,367.524 224.84,366.974 v3(224.84,365.89)
  L16 w0.12: v3(224.84,365.89) 226.037,364.693 228.816,364.693 229.89,363.619 J1_PCIE2.47@229.89,358.792
NetJ1_PCIE2_49: J1_PCIE2.49 U26_SPI_bridge_PCIe.13 | length 15
  L1 w0.12: U26_SPI_bridge_PCIe.13@224.94,372.107 224.94,367.304 v3(228.29,363.954)
  L16 w0.12: v3(228.29,363.954) 229.09,363.154 J1_PCIE2.49@229.09,358.792
NetJ1_PCIE2_51: J1_PCIE2.51 R236_SPI_bridge_PCIe.1 U26_SPI_bridge_PCIe.11 | length 15.9
  L1 w0.12: v3(223.44,365.89) 223.44,366.648 222.99,367.098 222.99,369.94 223.24,370.19 223.49,370.19 R236_SPI_bridge_PCIe.1@223.64,370.34 U26_SPI_bridge_PCIe.11@223.64,372.107
  L16 w0.12: v3(223.44,365.89) 223.44,364.342 228.29,359.492 J1_PCIE2.51@228.29,358.792
NetJ1_PCIE3_11: J1_PCIE3.11 R902.2
NetJ1_PCIE3_12: J1_PCIE3.12 U1.AK6 | length 0.7
  L1 w0.116: v4(190.909,293.052) U1.AK6@191.397,293.539
NetJ1_PCIE3_13: J1_PCIE3.13 R10_I2C_Bridge_PCIE.1 U3_I2C_Bridge_PCIE.10
NetJ1_PCIE3_14: J1_PCIE3.14 U1.AK7 | length 0.7
  L1 w0.116: v4(190.909,294.052) U1.AK7@191.397,294.539
NetJ1_PCIE3_15: J1_PCIE3.15 R9_I2C_Bridge_PCIE.1 U3_I2C_Bridge_PCIE.11
NetJ1_PCIE3_31: J1_PCIE3.31 U1.AE9
NetJ1_PCIE3_33: J1_PCIE3.33 U1.AE8 | length 0.7
  L1 w0.116: v4(185.909,295.052) U1.AE8@186.397,295.539
NetJ1_PCIE3_36: J1_PCIE3.36
NetJ1_PCIE3_38: J1_PCIE3.38
NetJ1_PCIE3_42: J1_PCIE3.42
NetJ1_PCIE3_43: J1_PCIE3.43 R970.2
NetJ1_PCIE3_44: J1_PCIE3.44
NetJ1_PCIE3_45: J1_PCIE3.45 U27_SPI_bridge_PCIe.14 | length 19.7
  L1 w0.12: U27_SPI_bridge_PCIe.14@60.563,372.107 U27_SPI_bridge_PCIe.14@60.563,371.89 60.563,369.274 60.706,369.132 60.706,361.819 64.179,358.346 64.179,358.172 65.494,356.857 v3(65.977,356.857)
  L16 w0.12: v3(65.977,356.857) 65.977,358.784 J1_PCIE3.45@65.985,358.792
NetJ1_PCIE3_47: J1_PCIE3.47 U27_SPI_bridge_PCIe.12 | length 21.1
  L1 w0.12: U27_SPI_bridge_PCIe.12@59.263,372.107 59.263,369.952 60.266,368.95 60.266,361.637 63.739,358.164 63.739,356.966 64.33,356.375 v3(65.164,356.375)
  L16 w0.12: v3(65.164,356.375) 65.164,358.771 J1_PCIE3.47@65.185,358.792
NetJ1_PCIE3_49: J1_PCIE3.49 U27_SPI_bridge_PCIe.13 | length 18.9
  L1 w0.12: U27_SPI_bridge_PCIe.13@59.913,372.107 59.913,369.613 60.486,369.041 60.486,361.728 63.959,358.255 63.959,357.325 v3(64.376,356.908)
  L16 w0.12: v3(64.376,356.908) 64.376,358.784 J1_PCIE3.49@64.385,358.792
NetJ1_PCIE3_51: J1_PCIE3.51 R238_SPI_bridge_PCIe.1 U27_SPI_bridge_PCIe.11 | length 20.4
  L1 w0.12: U27_SPI_bridge_PCIe.11@58.613,372.107 U27_SPI_bridge_PCIe.11@58.613,371.89 R238_SPI_bridge_PCIe.1@58.613,369.863 59.041,369.863 60.046,368.859 60.046,361.546 63.519,358.073 v3(63.519,356.425)
  L16 w0.12: v3(63.519,356.425) 63.519,358.726 J1_PCIE3.51@63.585,358.792
NetJ1_PCIE4_11: J1_PCIE4.11 R903.2
NetJ1_PCIE4_12: J1_PCIE4.12 U1.AK4 | length 0.7
  L1 w0.116: 190.909,291.052 U1.AK4@191.397,291.539
NetJ1_PCIE4_13: J1_PCIE4.13 R8_I2C_Bridge_PCIE.1 U3_I2C_Bridge_PCIE.12
NetJ1_PCIE4_14: J1_PCIE4.14 U1.AJ4 | length 0.7
  L1 w0.116: v4(189.909,291.052) U1.AJ4@190.397,291.539
NetJ1_PCIE4_15: J1_PCIE4.15 R7_I2C_Bridge_PCIE.1 U3_I2C_Bridge_PCIE.13
NetJ1_PCIE4_18: J1_PCIE4.18 U35_I2C_Expander_11.26 | length 51
  L1 w0.12: v3(186.804,245.897) 186.907,245.897 187.044,245.76 U35_I2C_Expander_11.26@195.844,245.76
  L1 w0.2: U35_I2C_Expander_11.26@195.844,245.76 U35_I2C_Expander_11.26@196.064,245.76
  L16 w0.12: J1_PCIE4.18@155.937,263.794 155.937,258.045 159.448,254.533 173.726,254.533 182.362,245.897 v3(186.804,245.897)
NetJ1_PCIE4_31: J1_PCIE4.31 U1.AJ5 | length 0.7
  L1 w0.116: v4(189.909,292.052) U1.AJ5@190.397,292.539
NetJ1_PCIE4_33: J1_PCIE4.33 U1.AK5 | length 0.7
  L1 w0.116: v4(190.909,292.052) U1.AK5@191.397,292.539
NetJ1_PCIE4_43: J1_PCIE4.43 R971.2
NetJ1_PCIE4_45: J1_PCIE4.45 U28_SPI_bridge_PCIe.14 | length 18.2
  L1 w0.12: v3(166.581,267.794) 166.581,262.942 171.848,257.675 U28_SPI_bridge_PCIe.14@171.848,256.078
  L16 w0.12: v3(166.581,267.794) 166.581,271.837 J1_PCIE4.45@166.737,271.994
NetJ1_PCIE4_47: J1_PCIE4.47 U28_SPI_bridge_PCIe.12 | length 18.7
  L1 w0.12: v3(166.991,268.808) 167.005,268.794 167.005,264.465 173.148,258.322 U28_SPI_bridge_PCIe.12@173.148,256.078
  L16 w0.12: v3(166.991,268.808) 166.967,268.832 166.967,270.004 167.537,270.574 J1_PCIE4.47@167.537,271.994
NetJ1_PCIE4_49: J1_PCIE4.49 U28_SPI_bridge_PCIe.13 | length 17.7
  L1 w0.12: U28_SPI_bridge_PCIe.13@172.498,256.078 172.587,256.168 v3(172.587,257.645)
  L16 w0.12: J1_PCIE4.49@168.337,271.994 168.337,267.998 172.587,263.748 v3(172.587,257.645)
NetJ1_PCIE4_51: J1_PCIE4.51 R240_SPI_bridge_PCIe.1 U28_SPI_bridge_PCIe.11 | length 2.3
  L1 w0.12: R240_SPI_bridge_PCIe.1@173.746,258.399 173.746,256.13 U28_SPI_bridge_PCIe.11@173.798,256.078
NetJ30_1: J30.1 R283.2
NetJ30_2: J30.2 R286.2
NetJ36_2: J36.2 R654.1
NetL15_2: L15.2 U19.24 | length 3.1
  L1 w0.254: U19.24@174.578,171.85 174.578,172.317 174.727,172.465 175.755,172.465 176.303,173.013 L15.2@176.303,173.617
NetP3_1: P3.1 U44.11
NetP4_2: P4.2 U44.10
NetP12_3: P12.3 R731.1 U78.1 | length 2.7
  L1 w0.12: R731.1@195.466,199.209 P12.3@198.171,199.209
NetP13_1: P13.1 R675.2
NetP13_3: P13.3 R737.1
NetR3_I2C_Bridge_GPIO_1: R3_I2C_Bridge_GPIO.1 U3_I2C_Bridge_GPIO.17
NetR3_I2C_Bridge_PCIE_1: R3_I2C_Bridge_PCIE.1 R203.2 R207.2 U3_I2C_Bridge_PCIE.17 U64_U_Pomiar_pradu_napiecia_PCIe3.5
NetR3_I2C_Bridge_SFP_1: R3_I2C_Bridge_SFP.1 R130.1 U3_I2C_Bridge_SFP.17 U58.13
NetR4_I2C_Bridge_GPIO_1: R4_I2C_Bridge_GPIO.1 U3_I2C_Bridge_GPIO.16
NetR4_I2C_Bridge_PCIE_1: R4_I2C_Bridge_PCIE.1 R204.2 R208.2 U3_I2C_Bridge_PCIE.16 U64_U_Pomiar_pradu_napiecia_PCIe3.4
NetR4_I2C_Bridge_SFP_1: R4_I2C_Bridge_SFP.1 R131.1 U3_I2C_Bridge_SFP.16 U58.14
NetR5_I2C_Bridge_GPIO_1: R5_I2C_Bridge_GPIO.1 U3_I2C_Bridge_GPIO.15
NetR5_I2C_Bridge_PCIE_1: R5_I2C_Bridge_PCIE.1 R176.2 R180.2 R194.2 R198.2 U3_I2C_Bridge_PCIE.15 U64_U_Pomiar_pradu_napiecia_PCIe0.5 U64_U_Pomiar_pradu_napiecia_PCIe2.5
NetR5_I2C_Bridge_SFP_1: R5_I2C_Bridge_SFP.1 U3_I2C_Bridge_SFP.15 U35_I2C_Expander_SFP.8
NetR6_I2C_Bridge_GPIO_1: R6_I2C_Bridge_GPIO.1 U3_I2C_Bridge_GPIO.14
NetR6_I2C_Bridge_PCIE_1: R6_I2C_Bridge_PCIE.1 R177.2 R181.2 R195.2 R199.2 U3_I2C_Bridge_PCIE.14 U64_U_Pomiar_pradu_napiecia_PCIe0.4 U64_U_Pomiar_pradu_napiecia_PCIe2.4
NetR6_I2C_Bridge_SFP_1: R6_I2C_Bridge_SFP.1 U3_I2C_Bridge_SFP.14 U35_I2C_Expander_SFP.9
NetR7_I2C_Bridge_GPIO_1: R7_I2C_Bridge_GPIO.1 U3_I2C_Bridge_GPIO.13
NetR7_I2C_Bridge_SFP_1: R7_I2C_Bridge_SFP.1 U3_I2C_Bridge_PCIE.19 U3_I2C_Bridge_SFP.13
NetR8_I2C_Bridge_GPIO_1: R8_I2C_Bridge_GPIO.1 U3_I2C_Bridge_GPIO.12
NetR8_I2C_Bridge_SFP_1: R8_I2C_Bridge_SFP.1 U3_I2C_Bridge_PCIE.20 U3_I2C_Bridge_SFP.12
NetR9_I2C_Bridge_GPIO_1: R9_I2C_Bridge_GPIO.1 U3_I2C_Bridge_GPIO.11 U35_I2C_Expander_10.8 U35_I2C_Expander_11.8 U35_I2C_Expander_12.8
NetR9_I2C_Bridge_SFP_1: R9_I2C_Bridge_SFP.1 R22.2 R389.2 R457.2 R465.2 R563.2 R567.2 R571.2 R575.2 R579.2 R583.2 R587.2 R591.2 R593.2 R597.2 U3_I2C_Bridge_SFP.11 U35_I2C_Expander_PWR_CLK.8 U35_I2C_Expander_PWR_Dist.8 U64_U_Pomiar_pradu_napiecia_1.5 U64_U_Pomiar_pradu_napiecia_2.5 U64_U_Pomiar_pradu_napiecia_3.5 U64_U_Pomiar_pradu_napiecia_4.5 U64_U_Pomiar_pradu_napiecia_5.5 U64_U_Pomiar_pradu_napiecia_6.5 U72.5
NetR10_I2C_Bridge_GPIO_1: R10_I2C_Bridge_GPIO.1 U3_I2C_Bridge_GPIO.10 U35_I2C_Expander_10.9 U35_I2C_Expander_11.9 U35_I2C_Expander_12.9
NetR10_I2C_Bridge_SFP_1: R10_I2C_Bridge_SFP.1 R24.2 R390.2 R459.2 R466.2 R564.2 R568.2 R572.2 R576.2 R580.2 R584.2 R588.2 R592.2 R594.2 R598.2 U3_I2C_Bridge_SFP.10 U35_I2C_Expander_PWR_CLK.9 U35_I2C_Expander_PWR_Dist.9 U64_U_Pomiar_pradu_napiecia_1.4 U64_U_Pomiar_pradu_napiecia_2.4 U64_U_Pomiar_pradu_napiecia_3.4 U64_U_Pomiar_pradu_napiecia_4.4 U64_U_Pomiar_pradu_napiecia_5.4 U64_U_Pomiar_pradu_napiecia_6.4 U72.4
NetR12_1: R12.1 R19.2 U5.5 | length 4.2
  L1 w0.2: R19.2@44.801,174.289 R12.1@45.844,174.289 45.844,174.314 46.28,174.75 U5.5@47.56,174.75 46.345,174.75
NetR14_1: R14.1 R16.1 R22.1 R24.1 U72.2
NetR15_1: R15.1 R23.2 U4.5 | length 2.9
  L1 w0.2: R23.2@44.92,183.563 R15.1@45.94,183.563 45.94,183.667 46.345,184.071 U4.5@47.56,184.071
NetR17_1: R17.1 R25.2 U4.4 | length 2.9
  L1 w0.2: R25.2@44.92,185.074 R17.1@45.94,185.074 45.94,184.98 46.349,184.571 U4.4@47.56,184.571
NetR18_2: R18.2 U4.10 | length 1.4
  L1 w0.2: U4.10@49.86,184.071 50.307,184.071 50.707,184.471 R18.2@51.11,184.471
NetR20_1: R20.1 R26.2 U5.4 | length 4.2
  L1 w0.2: R26.2@44.801,175.686 R20.1@45.822,175.686 46.258,175.25 U5.4@47.56,175.25 46.349,175.25
NetR21_2: R21.2 U5.10 | length 1.9
  L1 w0.2: U5.10@49.86,174.75 50.762,174.75 51.138,175.125 R21.2@51.6,175.125
NetR27_2: R27.2 U6.C1 | length 1.8
  L1 w0.12: U6.C1@46.01,168.789 46.01,168.554 46.246,168.319 46.704,168.319 46.939,168.084 46.939,167.985 46.94,167.984 46.94,167.714 R27.2@46.91,167.684
NetR28_1: R28.1 U7.C1
NetR75_1: R75.1 U1.H16
NetR81_1: R81.1 U1.C16 U12.48 | length 9.2
  L1 w0.116: U1.C16@164.397,303.539 v4(164.884,303.052)
  L3 (Sign) w0.12: 157.545,304.995 159.221,304.995 159.677,304.539 164.078,304.539 164.884,303.733 v4(164.884,303.052)
NetR81_2: R81.2 U1.D16 U12.47 | length 9.8
  L1 w0.116: U1.D16@165.397,303.539 v4(165.884,303.052)
  L3 (Sign) w0.12: 157.636,305.215 159.317,305.215 159.769,304.763 164.165,304.763 165.877,303.052 v4(165.884,303.052)
NetR132_2: R132.2 U28_SPI_bridge_Main.14
NetR133_2: R133.2 U28_SPI_bridge_Main.13
NetR134_2: R134.2 U28_SPI_bridge_Main.12
NetR149_1: R149.1 R159.2 U65.20 | length 3.9
  L1 w0.2: R149.1@33.873,204.343 33.947,204.269 33.947,204.06 34.27,203.737 34.548,203.737 34.773,203.513 R159.2@34.773,203.149
  L1 w0.254: R159.2@34.773,203.149 35.891,203.149 36.059,203.318 U65.20@36.92,203.318
NetR150_1: R150.1 R160.2 U65.6 | length 8.3
  L1 w0.254: U65.6@40.6,203.318 41.282,203.318 ; v4(41.123,202.654) 41.282,202.814 41.282,203.318 ; R160.2@42.078,203.203 41.397,203.203 41.282,203.318 ; R150.1@42.202,206.468 v4(42.202,207.35)
  L3 (Sign) w0.254: v4(41.123,202.654) 42.202,203.733 v4(42.202,207.35)
NetR174_1: R174.1 R175.1 R176.1 R177.1 U64_U_Pomiar_pradu_napiecia_PCIe0.2
NetR178_1: R178.1 R179.1 R180.1 R181.1 U64_U_Pomiar_pradu_napiecia_PCIe0.1
NetR182_2: R182.2 U17.C1
NetR183_1: R183.1 R184.1 R185.1 R186.1 U64_U_Pomiar_pradu_napiecia_PCIe1.2
NetR185_2: R185.2 R189.2 R213.2 R221.2 R559_I2C_Bridge_PCIE.1 U3_I2C_Bridge_PCIE.2 U64_U_Pomiar_pradu_napiecia_PCIe1.5 U64_U_Pomiar_pradu_napiecia_PCIe4.5
NetR186_2: R186.2 R190.2 R215.2 R222.2 R560_I2C_Bridge_PCIE.1 U3_I2C_Bridge_PCIE.1 U64_U_Pomiar_pradu_napiecia_PCIe1.4 U64_U_Pomiar_pradu_napiecia_PCIe4.4
NetR187_1: R187.1 R188.1 R189.1 R190.1 U64_U_Pomiar_pradu_napiecia_PCIe1.1
NetR191_2: R191.2 U20.C1
NetR192_1: R192.1 R193.1 R194.1 R195.1 U64_U_Pomiar_pradu_napiecia_PCIe2.2
NetR196_1: R196.1 R197.1 R198.1 R199.1 U64_U_Pomiar_pradu_napiecia_PCIe2.1
NetR200_2: R200.2 U21.C1
NetR201_1: R201.1 R202.1 R203.1 R204.1 U64_U_Pomiar_pradu_napiecia_PCIe3.2
NetR205_1: R205.1 R206.1 R207.1 R208.1 U64_U_Pomiar_pradu_napiecia_PCIe3.1
NetR209_2: R209.2 U22.C1
NetR210_1: R210.1 R211.1 R213.1 R215.1 U64_U_Pomiar_pradu_napiecia_PCIe4.2
NetR217_1: R217.1 R219.1 R221.1 R222.1 U64_U_Pomiar_pradu_napiecia_PCIe4.1
NetR223_I2C_Bridge_GPIO_1: R223_I2C_Bridge_GPIO.1 U3_I2C_Bridge_GPIO.8
NetR224_I2C_Bridge_GPIO_1: R224_I2C_Bridge_GPIO.1 U3_I2C_Bridge_GPIO.7
NetR225_I2C_Bridge_GPIO_1: R225_I2C_Bridge_GPIO.1 U3_I2C_Bridge_GPIO.6
NetR226_I2C_Bridge_GPIO_1: R226_I2C_Bridge_GPIO.1 U3_I2C_Bridge_GPIO.5
NetR227_I2C_Bridge_GPIO_1: R227_I2C_Bridge_GPIO.1 U3_I2C_Bridge_GPIO.4
NetR228_2: R228.2 U23.C1
NetR229_1: R229.1 R230.1 R457.1 R459.1 U64_U_Pomiar_pradu_napiecia_1.2
NetR231_SPI_bridge_Main_1: R231_SPI_bridge_Main.1 U24_SPI_bridge_Main.11 U24_SPI_bridge_PCIe.6 U25_SPI_bridge_PCIe.6 U26_SPI_bridge_PCIe.6 U27_SPI_bridge_PCIe.6 U28_SPI_bridge_PCIe.6 | length 2.1
  L1 w0.12: U24_SPI_bridge_Main.11@223.032,289.702 223.972,289.702 224.253,289.983 R231_SPI_bridge_Main.1@225.007,289.983
NetR232_SPI_bridge_Main_1: R232_SPI_bridge_Main.1 U35_I2C_Expander_01.25
NetR232_SPI_bridge_Main_2: R232_SPI_bridge_Main.2 U24_SPI_bridge_Main.9 | length 2.2
  L1 w0.12: U24_SPI_bridge_Main.9@223.032,288.402 223.078,288.448 224.134,288.448 224.514,288.068 R232_SPI_bridge_Main.2@225.007,288.068
NetR232_SPI_bridge_PCIe_1: R232_SPI_bridge_PCIe.1 U35_I2C_Expander_02.2 | length 29
  L1 w0.12: U35_I2C_Expander_02.2@114.13,375.782 114.13,373.741 116.992,370.878 134.175,370.878 135.844,369.21 R232_SPI_bridge_PCIe.1@139.232,369.21
NetR232_SPI_bridge_PCIe_2: R232_SPI_bridge_PCIe.2 U24_SPI_bridge_PCIe.9 | length 2
  L1 w0.12: R232_SPI_bridge_PCIe.2@139.232,370.11 U24_SPI_bridge_PCIe.9@139.232,372.107
NetR234_SPI_bridge_Main_1: R234_SPI_bridge_Main.1 U35_I2C_Expander_01.26
NetR234_SPI_bridge_Main_2: R234_SPI_bridge_Main.2 U25_SPI_bridge_Main.9 | length 2.1
  L1 w0.12: U25_SPI_bridge_Main.9@190.248,259.821 190.348,259.921 R234_SPI_bridge_Main.2@190.348,261.861
NetR234_SPI_bridge_PCIe_2: R234_SPI_bridge_PCIe.2 U25_SPI_bridge_PCIe.9 | length 2
  L1 w0.12: U25_SPI_bridge_PCIe.9@256.491,259.567 R234_SPI_bridge_PCIe.2@256.491,261.564
NetR235_SPI_bridge_Main_1: R235_SPI_bridge_Main.1 U26_SPI_bridge_Main.9 | length 2.3
  L1 w0.12: U26_SPI_bridge_Main.9@77.371,327.29 R235_SPI_bridge_Main.1@79.68,327.29
NetR235_SPI_bridge_Main_2: R235_SPI_bridge_Main.2 U35_I2C_Expander_01.27
NetR235_SPI_bridge_PCIe_1: R235_SPI_bridge_PCIe.1 U26_SPI_bridge_PCIe.9 | length 1.8
  L1 w0.12: R235_SPI_bridge_PCIe.1@222.34,370.34 U26_SPI_bridge_PCIe.9@222.34,372.107
NetR237_SPI_bridge_Main_1: R237_SPI_bridge_Main.1 U27_SPI_bridge_Main.9
NetR237_SPI_bridge_Main_2: R237_SPI_bridge_Main.2 U35_I2C_Expander_01.28
NetR237_SPI_bridge_PCIe_1: R237_SPI_bridge_PCIe.1 U27_SPI_bridge_PCIe.9
NetR237_SPI_bridge_PCIe_2: R237_SPI_bridge_PCIe.2 U35_I2C_Expander_02.28 | length 59.6
  L1 w0.12: v10(57.328,368.163) R237_SPI_bridge_PCIe.2@57.328,368.963 ; v10(110.553,376.707) U35_I2C_Expander_02.28@112.555,376.707
  L3 (Sign) w0.12: v10@57.313,368.162 65.508,376.357 109.166,376.357 109.516,376.707 v10(110.553,376.707)
NetR238_SPI_bridge_Main_2: R238_SPI_bridge_Main.2 U27_SPI_bridge_Main.15
NetR239_SPI_bridge_Main_1: R239_SPI_bridge_Main.1 U35_I2C_Expander_01.1
NetR239_SPI_bridge_Main_2: R239_SPI_bridge_Main.2 U28_SPI_bridge_Main.9 | length 9.1
  L1 w0.12: U28_SPI_bridge_Main.9@164.969,234.888 168.101,234.888 169.916,236.703 R239_SPI_bridge_Main.2@173.353,236.703
NetR239_SPI_bridge_PCIe_2: R239_SPI_bridge_PCIe.2 U28_SPI_bridge_PCIe.9 | length 2.1
  L1 w0.12: R239_SPI_bridge_PCIe.2@175.098,258.399 175.098,256.653 175.373,256.378
NetR240_SPI_bridge_Main_1: R240_SPI_bridge_Main.1 R912.2 U28_SPI_bridge_Main.11 | length 2.2
  L1 w0.12: R240_SPI_bridge_Main.1@162.774,233.604 164.953,233.604 U28_SPI_bridge_Main.11@164.969,233.588
NetR241_2: R241.2 R242.1 U3_I2C_Bridge_GPIO.22
NetR243_2: R243.2 R244.1 U3_I2C_Bridge_GPIO.23
NetR263_2: R263.2 U33.16
NetR264_2: R264.2 U33.13
NetR265_2: R265.2 U33.15
NetR266_1: R266.1 R267.2 S5.1 S5.2 S5.3 S5.4
NetR269_2: R269.2 U18.C1
NetR272_1: R272.1 U34.5 | length 1.8
  L1 w0.254: R272.1@61.056,235.139 U34.5@62.822,235.139
NetR281_2: R281.2 R400.1 U3_I2C_Bridge_GPIO.18
NetR284_2: R284.2 U19.17
NetR289_1: R289.1 U37.5 | length 1.4
  L1 w0.254: R289.1@61.781,179.317 U37.5@63.175,179.317
NetR293_2: R293.2 R294.2 U37.7 | length 2.4
  L1 w0.254: R294.2@61.781,177.317 R293.2@61.781,178.317 U37.7@63.175,178.317
NetR304_1: R304.1 R388.1 R389.1 R390.1 U72.1
NetR305_2: R305.2 U67.6 | length 1.4
  L1 w0.12: U67.6@175.639,161.385 R305.2@175.639,162.805
NetR307_1: R307.1 U38.5 | length 4.1
  L1 w0.254: R307.1@57.945,206.596 57.945,206.233 58.189,205.989 59.673,205.989 59.898,206.214 U38.5@61.453,206.214
NetR308_2: R308.2 U67.5 | length 1.4
  L1 w0.12: U67.5@176.589,161.385 R308.2@176.589,162.805
NetR309_2: R309.2 U67.4 | length 1.4
  L1 w0.12: U67.4@177.539,161.385 R309.2@177.539,162.805
NetR310_2: R310.2 R312.2 U38.7 | length 2.8
  L1 w0.254: R312.2@58.826,204.716 59.784,204.716 60.282,205.214 U38.7@61.453,205.214
NetR334_1: R334.1 U39.12
NetR339_1: R339.1 R341.2 U40.7
NetR342_1: R342.1 R344.2 U42.7
NetR358_1: R358.1 S1.8
NetR359_1: R359.1 S1.7
NetR360_1: R360.1 S1.6
NetR361_1: R361.1 S1.5
NetR366_2: R366.2 R498.1 R499.2 R692.2
NetR372_1: R372.1 R373.2 U44.2 U44.3
NetR379_2: R379.2 U45.24
NetR380_2: R380.2 U46.C1
NetR391_1: R391.1 R393.2 U49.7
NetR394_1: R394.1 R396.2 U50.7
NetR397_1: R397.1 R399.2 U51.7
NetR419_2: R419.2 R422.1 U54.1
NetR423_2: R423.2 U55.6
NetR424_2: R424.2 U55.14
NetR425_SPI_bridge_Main_1: R425_SPI_bridge_Main.1 U24_SPI_bridge_Main.1 | length 2.6
  L1 w0.12: R425_SPI_bridge_Main.1@214.902,293.539 215.68,293.539 216.267,292.952 U24_SPI_bridge_Main.1@217.232,292.952
NetR425_SPI_bridge_PCIe_1: R425_SPI_bridge_PCIe.1 U24_SPI_bridge_PCIe.1 | length 2.3
  L1 w0.12: U24_SPI_bridge_PCIe.1@143.782,377.907 143.757,377.932 143.757,379.157 144.057,379.457 R425_SPI_bridge_PCIe.1@144.057,380.027
NetR426_SPI_bridge_Main_2: R426_SPI_bridge_Main.2 U24_SPI_bridge_Main.7 | length 2.3
  L1 w0.12: R426_SPI_bridge_Main.2@214.902,289.052 U24_SPI_bridge_Main.7@217.232,289.052
NetR426_SPI_bridge_PCIe_2: R426_SPI_bridge_PCIe.2 U24_SPI_bridge_PCIe.7 | length 2.2
  L1 w0.12: U24_SPI_bridge_PCIe.7@139.882,377.907 139.882,379.157 140.183,379.458 R426_SPI_bridge_PCIe.2@140.183,379.977
NetR428_1: R428.1 U3_I2C_Bridge_GPIO.20 U35_I2C_Expander_Main_Rst.9 U36_U_Translator_I2C1.5 U36_U_Translator_I2C2.5
NetR429_1: R429.1 U58.12 | length 1.3
  L1 w0.12: U58.12@241.757,328.94 R429.1@241.757,330.251
NetR430_5V_to_3V3_for_FTDI_1: R430_5V_to_3V3_for_FTDI.1 R432_5V_to_3V3_for_FTDI.2 U59_5V_to_3V3_for_FTDI.7
NetR430_U_5V_to_3V31_1: R430_U_5V_to_3V31.1 R432_U_5V_to_3V31.2 U59_U_5V_to_3V31.7
NetR430_U_5V_to_3V32_1: R430_U_5V_to_3V32.1 R432_U_5V_to_3V32.2 U59_U_5V_to_3V32.7
NetR430_U_5V_to_3V33_1: R430_U_5V_to_3V33.1 R432_U_5V_to_3V33.2 U59_U_5V_to_3V33.7
NetR431_5V_to_3V3_for_FTDI_1: R431_5V_to_3V3_for_FTDI.1 U59_5V_to_3V3_for_FTDI.5
NetR433_1: R433.1 R434.2 U60.9
NetR435_1: R435.1 R668.2 U69.4
NetR443_1: R443.1 R444.2 U62.6
NetR449_2: R449.2 R450.1 U3_I2C_Bridge_PCIE.22
NetR451_2: R451.2 R452.1 U3_I2C_Bridge_PCIE.23
NetR453_2: R453.2 R454.1 U3_I2C_Bridge_PCIE.18
NetR455_2: R455.2 R456.1 U35_I2C_Expander_PWR_Dist.13
NetR458_2: R458.2 R460.1 U35_I2C_Expander_PWR_Dist.12
NetR461_1: R461.1 R463.1 R465.1 R466.1 U64_U_Pomiar_pradu_napiecia_1.1
NetR462_2: R462.2 R464.1 U35_I2C_Expander_PWR_Dist.11
NetR467_1: R467.1 R468.1 R593.1 R594.1 U64_U_Pomiar_pradu_napiecia_2.2
NetR469_2: R469.2 R470.1 U3_I2C_Bridge_SFP.22
NetR471_2: R471.2 R472.1 U3_I2C_Bridge_SFP.23
NetR473_2: R473.2 R474.1 U3_I2C_Bridge_SFP.18
NetR475_2: R475.2 R476.1 U35_I2C_Expander_SFP.13
NetR477_2: R477.2 R478.1 U35_I2C_Expander_SFP.12
NetR479_2: R479.2 R480.1 U35_I2C_Expander_SFP.11
NetR481_2: R481.2 U27_SPI_bridge_Main.13
NetR488_1: R488.1 T36.3 U32.2
NetR499_1: R499.1 U35_I2C_Expander_00.24
NetR507_1: R507.1 U1.H13 | length 66.7
  L1 w0.116: v4(168.909,301.027) U1.H13@169.397,300.539
  L3 (Sign) w0.12: v1(116.061,293.675) 116.455,293.281 116.455,289.536 120.804,285.188 145.899,285.188 145.907,285.196 145.998,285.196 146.03,285.228 146.068,285.228 146.117,285.278 146.171,285.278 146.288,285.394 146.325,285.394 146.357,285.426 146.41,285.426 146.433,285.448 146.499,285.448 156.729,295.679 156.729,295.745 156.751,295.767 156.751,295.82 156.783,295.852 156.783,295.89 156.9,296.006 156.9,296.06 156.949,296.109 156.949,296.147 156.981,296.179 156.981,296.27 156.99,296.279 156.99,297.471 159.494,299.974 167.31,299.974 168.363,301.027 v4(168.909,301.027)
NetR514_1: R514.1 U1.H12 | length 68.1
  L1 w0.116: v4(168.909,300.027) U1.H12@169.397,299.539
  L3 (Sign) w0.12: v1(114.261,293.675) 115.795,292.141 115.795,289.263 120.531,284.528 146.172,284.528 146.18,284.536 146.271,284.536 146.304,284.568 146.395,284.568 146.561,284.734 146.652,284.734 146.706,284.788 146.772,284.788 157.389,295.405 157.389,295.471 157.443,295.525 157.443,295.616 157.609,295.782 157.609,295.874 157.641,295.906 157.641,295.997 157.65,296.005 157.65,297.197 159.767,299.314 167.583,299.314 168.296,300.027 v4(168.909,300.027)
NetR540_1: R540.1 U35_I2C_Expander_00.19
NetR543_1: R543.1 X9.3
NetR544_1: R544.1 X9.1
NetR558_I2C_Bridge_GPIO_1: R558_I2C_Bridge_GPIO.1 U3_I2C_Bridge_GPIO.3
NetR559_I2C_Bridge_GPIO_1: R559_I2C_Bridge_GPIO.1 U3_I2C_Bridge_GPIO.2 U35_I2C_Expander_00.8 U35_I2C_Expander_01.8 U35_I2C_Expander_02.8
NetR560_I2C_Bridge_GPIO_1: R560_I2C_Bridge_GPIO.1 U3_I2C_Bridge_GPIO.1 U35_I2C_Expander_00.9 U35_I2C_Expander_01.9 U35_I2C_Expander_02.9
NetR561_1: R561.1 R562.1 R563.1 R564.1 U64_U_Pomiar_pradu_napiecia_3.2
NetR565_1: R565.1 R566.1 R567.1 R568.1 U64_U_Pomiar_pradu_napiecia_3.1
NetR569_1: R569.1 R570.1 R571.1 R572.1 U64_U_Pomiar_pradu_napiecia_4.2
NetR573_1: R573.1 R574.1 R575.1 R576.1 U64_U_Pomiar_pradu_napiecia_4.1
NetR577_1: R577.1 R578.1 R579.1 R580.1 U64_U_Pomiar_pradu_napiecia_5.2
NetR581_1: R581.1 R582.1 R583.1 R584.1 U64_U_Pomiar_pradu_napiecia_5.1
NetR585_1: R585.1 R586.1 R587.1 R588.1 U64_U_Pomiar_pradu_napiecia_6.2
NetR589_1: R589.1 R590.1 R591.1 R592.1 U64_U_Pomiar_pradu_napiecia_6.1
NetR595_1: R595.1 R596.1 R597.1 R598.1 U64_U_Pomiar_pradu_napiecia_2.1
NetR599_1: R599.1 U3_I2C_Bridge_GPIO.19 U35_I2C_Expander_Main_Rst.8 U36_U_Translator_I2C1.6 U36_U_Translator_I2C2.6
NetR600_1: R600.1 R601.2 U58.1 | length 2.7
  L1 w0.12: R600.1@237.279,328.69 R601.2@238.465,328.69 U58.1@240.007,328.69
NetR602_SPI_bridge_Main_1: R602_SPI_bridge_Main.1 U24_SPI_bridge_Main.2 | length 2.6
  L1 w0.12: R602_SPI_bridge_Main.1@214.902,291.652 215.491,291.652 216.141,292.302 U24_SPI_bridge_Main.2@217.232,292.302
NetR602_SPI_bridge_PCIe_1: R602_SPI_bridge_PCIe.1 U24_SPI_bridge_PCIe.2 | length 2.3
  L1 w0.12: R602_SPI_bridge_PCIe.1@142.687,380.027 142.687,379.602 143.132,379.157 U24_SPI_bridge_PCIe.2@143.132,377.907
NetR603_SPI_bridge_Main_2: R603_SPI_bridge_Main.2 U24_SPI_bridge_Main.8 | length 2.5
  L1 w0.12: R603_SPI_bridge_Main.2@214.902,288.068 216.373,288.068 216.707,288.402 U24_SPI_bridge_Main.8@217.232,288.402
NetR603_SPI_bridge_PCIe_2: R603_SPI_bridge_PCIe.2 U24_SPI_bridge_PCIe.8 | length 2.2
  L1 w0.12: R603_SPI_bridge_PCIe.2@138.857,379.977 138.857,379.457 139.232,379.082 U24_SPI_bridge_PCIe.8@139.232,377.907
NetR604_SPI_bridge_Main_1: R604_SPI_bridge_Main.1 U25_SPI_bridge_Main.1 | length 2
  L1 w0.12: R604_SPI_bridge_Main.1@185.538,252.123 185.698,252.284 U25_SPI_bridge_Main.1@185.698,254.021
NetR604_SPI_bridge_PCIe_1: R604_SPI_bridge_PCIe.1 U25_SPI_bridge_PCIe.1 | length 2.2
  L1 w0.12: R604_SPI_bridge_PCIe.1@251.666,251.739 251.666,252.314 251.993,252.641 251.993,253.715 U25_SPI_bridge_PCIe.1@251.941,253.767
NetR605_SPI_bridge_Main_2: R605_SPI_bridge_Main.2 U25_SPI_bridge_Main.7 | length 2
  L1 w0.12: R605_SPI_bridge_Main.2@189.416,252.123 189.598,252.306 U25_SPI_bridge_Main.7@189.598,254.021
NetR605_SPI_bridge_PCIe_2: R605_SPI_bridge_PCIe.2 U25_SPI_bridge_PCIe.7 | length 2.2
  L1 w0.12: R605_SPI_bridge_PCIe.2@255.537,251.739 255.537,252.337 255.841,252.641 U25_SPI_bridge_PCIe.7@255.841,253.767
NetR606_SPI_bridge_Main_1: R606_SPI_bridge_Main.1 U25_SPI_bridge_Main.2 | length 2
  L1 w0.12: U25_SPI_bridge_Main.2@186.348,254.021 186.348,252.323 R606_SPI_bridge_Main.1@186.548,252.123
NetR606_SPI_bridge_PCIe_1: R606_SPI_bridge_PCIe.1 U25_SPI_bridge_PCIe.2 | length 2.2
  L1 w0.12: U25_SPI_bridge_PCIe.2@252.591,253.767 252.591,252.69 252.94,252.341 R606_SPI_bridge_PCIe.1@252.94,251.739
NetR612_1: R612.1 U34.29 | length 8.5
  L1 w0.254: U34.29@64.822,237.639 64.822,237.71 64.831,237.72 v25(64.831,239.097)
  L16 w0.254: v25(59.917,241.89) 59.917,241.114 60.285,240.746 60.915,240.746 61.483,240.178 64.683,240.178 64.831,240.029 v25(64.831,239.097)
NetR614_1: R614.1 U34.12 | length 6.9
  L1 w0.254: R614.1@59.692,230.712 63.088,230.712 64.11,231.734 64.666,231.734 64.815,231.882 64.815,232.984 64.82,232.989 64.82,233.137 U34.12@64.822,233.139
NetR621_1: R621.1 U37.29 | length 1.6
  L1 w0.254: R621.1@65.137,183.369 65.116,183.348 65.116,182.714 65.175,182.655 U37.29@65.175,181.817
NetR622_1: R622.1 U37.12 | length 1.4
  L1 w0.254: R622.1@65.175,175.893 U37.12@65.175,177.317
NetR628_1: R628.1 U38.12 | length 8.1
  L1 w0.254: v4(63.453,203.556) U38.12@63.453,204.214 ; R628.1@69.132,200.683 v4(69.132,201.631)
  L3 (Sign) w0.254: v4(63.453,203.556) 67.207,203.556 v4@69.138,201.625
NetR644_1: R644.1 R645.2 U69.9
NetR648_1: R648.1 T25.3
NetR649_2: R649.2 T26.3
NetR650_2: R650.2 T23.1 T24.3
NetR651_1: R651.1 T27.1 T28.3
NetR653_2: R653.2 T30.3
NetR655_1: R655.1 T29.1
NetR657_2: R657.2 T31.3
NetR658_1: R658.1 T31.1
NetR665_2: R665.2 U65.13 | length 2.9
  L1 w0.254: U65.13@38.76,206.158 38.76,207.602 39.014,207.856 R665.2@39.014,208.928
NetR677_1: R677.1 R682.2 U48.6 | length 2.9
  L1 w0.2: R677.1@44.716,192.933 R682.2@45.775,192.933 45.914,192.933 46.214,193.233 U48.6@47.527,193.233
NetR678_1: R678.1 R683.2 U48.5 | length 5.6
  L1 w0.2: R683.2@42.6,192.933 R678.1@43.658,192.933 43.658,193.501 43.89,193.733 U48.5@47.527,193.733
NetR679_1: R679.1 R684.2 U48.3 | length 2.9
  L1 w0.2: R684.2@44.716,195.033 R679.1@45.775,195.033 46.075,194.733 U48.3@47.527,194.733
NetR680_1: R680.1 R685.2 U48.4 | length 5.6
  L1 w0.2: R685.2@42.6,195.033 R680.1@43.658,195.033 43.658,194.466 43.89,194.233 U48.4@47.527,194.233
NetR681_2: R681.2 U48.10 | length 1.4
  L1 w0.2: U48.10@49.827,193.733 50.729,193.733 R681.2@51.105,194.109
NetR686_1: R686.1 U38.29 | length 0.6
  L1 w0.254: U38.29@63.453,208.714 v4@63.453,209.276
  other v4: 63.449,209.276
NetR689_2: R689.2 R690.2 U73.7 | length 10.7
  L1 w0.2: U73.7@151.644,349.484 153.033,349.484 v4(153.035,349.482)
  L1 w0.3: R690.2@159.652,348.062 160.213,348.062 ; v4(160.213,348.729) 160.213,348.062 ; R689.2@160.795,348.062 160.213,348.062
  L3 (Sign) w0.2: v4(153.035,349.482) v4@153.035,349.491
  L3 (Sign) w0.3: v4@153.035,349.491 153.797,348.729 v4(160.213,348.729)
NetR692_1: R692.1 S6.3 S6.4
NetR710_1: R710.1 R711.1 R712.2
NetR711_2: R711.2 U76.4
NetR713_1: R713.1 S7.1 S7.2
NetR714_2: R714.2 S7.3 S7.4
NetR738_2: R738.2 R739.2 U35_I2C_Expander_PWR_CLK.13
NetR740_2: R740.2 R741.2 U35_I2C_Expander_PWR_CLK.12
NetR742_2: R742.2 R743.2 U35_I2C_Expander_PWR_CLK.11
NetR749_1: R749.1 U35_I2C_Expander_Main_Rst.20
NetR750_1: R750.1 U35_I2C_Expander_Main_Rst.21
NetR751_1: R751.1 U35_I2C_Expander_Main_Rst.22
NetR752_1: R752.1 U35_I2C_Expander_Main_Rst.23
NetR753_1: R753.1 U3_I2C_Bridge_PCIE.24 U35_I2C_Expander_Main_Rst.25
NetR754_1: R754.1 U35_I2C_Expander_Main_Rst.26 U35_I2C_Expander_PWR_CLK.14
NetR758_2: R758.2 R759.1 U35_I2C_Expander_Main_Rst.13
NetR760_2: R760.2 R761.1 U35_I2C_Expander_Main_Rst.12
NetR762_2: R762.2 R763.1 U35_I2C_Expander_Main_Rst.11
NetR768_1: R768.1
NetR769_1: R769.1
NetR770_1: R770.1
NetR771_1: R771.1
NetR860_2: R860.2 U64_U_Pomiar_pradu_napiecia_3.3
NetR862_2: R862.2 U64_U_Pomiar_pradu_napiecia_4.3
NetR863_2: R863.2 U64_U_Pomiar_pradu_napiecia_5.3
NetR864_2: R864.2 U64_U_Pomiar_pradu_napiecia_6.3
NetR865_2: R865.2 U18.A3
NetR866_2: R866.2 U72.3
NetR887_SPI_bridge_Main_2: R887_SPI_bridge_Main.2 U25_SPI_bridge_Main.8 | length 2
  L1 w0.12: 190.248,252.872 U25_SPI_bridge_Main.8@190.248,254.021 ; 190.248,252.872 190.248,252.363 R887_SPI_bridge_Main.2@190.488,252.123
NetR887_SPI_bridge_PCIe_2: R887_SPI_bridge_PCIe.2 U25_SPI_bridge_PCIe.8 | length 2.2
  L1 w0.12: U25_SPI_bridge_PCIe.8@256.491,253.767 256.491,252.564 256.891,252.164 R887_SPI_bridge_PCIe.2@256.891,251.739
NetR888_SPI_bridge_Main_1: R888_SPI_bridge_Main.1 U26_SPI_bridge_Main.1 | length 2.5
  L1 w0.12: R888_SPI_bridge_Main.1@69.068,331.84 U26_SPI_bridge_Main.1@71.57,331.84
NetR888_SPI_bridge_PCIe_1: R888_SPI_bridge_PCIe.1 U26_SPI_bridge_PCIe.1 | length 2.3
  L1 w0.12: U26_SPI_bridge_PCIe.1@226.89,377.907 226.89,379.096 227.265,379.471 R888_SPI_bridge_PCIe.1@227.265,380.08
NetR889_SPI_bridge_Main_2: R889_SPI_bridge_Main.2 U26_SPI_bridge_Main.7 | length 2.5
  L1 w0.12: R889_SPI_bridge_Main.2@69.204,328.34 69.444,328.1 70.107,328.1 70.267,327.94 U26_SPI_bridge_Main.7@71.57,327.94
NetR889_SPI_bridge_PCIe_2: R889_SPI_bridge_PCIe.2 U26_SPI_bridge_PCIe.7 | length 2.3
  L1 w0.12: U26_SPI_bridge_PCIe.7@222.99,377.907 222.99,379.296 223.24,379.546 R889_SPI_bridge_PCIe.2@223.24,380.08
NetR890_SPI_bridge_Main_1: R890_SPI_bridge_Main.1 U26_SPI_bridge_Main.2 | length 2.5
  L1 w0.12: R890_SPI_bridge_Main.1@69.254,330.703 69.354,330.803 70.267,330.803 70.667,331.203 71.558,331.203 U26_SPI_bridge_Main.2@71.57,331.19
NetR890_SPI_bridge_PCIe_1: R890_SPI_bridge_PCIe.1 U26_SPI_bridge_PCIe.2 | length 2.3
  L1 w0.12: R890_SPI_bridge_PCIe.1@225.92,380.08 225.92,379.546 226.24,379.226 U26_SPI_bridge_PCIe.2@226.24,377.907
NetR891_SPI_bridge_Main_2: R891_SPI_bridge_Main.2 U26_SPI_bridge_Main.8 | length 2.4
  L1 w0.12: R891_SPI_bridge_Main.2@69.204,327.115 70.143,327.115 70.317,327.29 U26_SPI_bridge_Main.8@71.57,327.29
NetR891_SPI_bridge_PCIe_2: R891_SPI_bridge_PCIe.2 U26_SPI_bridge_PCIe.8 | length 2.3
  L1 w0.12: R891_SPI_bridge_PCIe.2@221.965,380.08 221.965,379.546 222.34,379.171 U26_SPI_bridge_PCIe.8@222.34,377.907
NetR892_SPI_bridge_Main_1: R892_SPI_bridge_Main.1 U27_SPI_bridge_Main.1
NetR892_SPI_bridge_PCIe_1: R892_SPI_bridge_PCIe.1 U27_SPI_bridge_PCIe.1 | length 2.5
  L1 w0.12: U27_SPI_bridge_PCIe.1@61.863,377.907 61.938,377.982 61.938,379.027 62.238,379.327 R892_SPI_bridge_PCIe.1@62.238,380.232
NetR893_SPI_bridge_Main_2: R893_SPI_bridge_Main.2 U27_SPI_bridge_Main.7
NetR893_SPI_bridge_PCIe_2: R893_SPI_bridge_PCIe.2 U27_SPI_bridge_PCIe.7 | length 2.4
  L1 w0.12: U27_SPI_bridge_PCIe.7@57.963,377.907 57.963,378.717 58.229,378.983 R893_SPI_bridge_PCIe.2@58.229,380.232
NetR894_SPI_bridge_Main_1: R894_SPI_bridge_Main.1 U27_SPI_bridge_Main.2
NetR894_SPI_bridge_PCIe_1: R894_SPI_bridge_PCIe.1 U27_SPI_bridge_PCIe.2 | length 2.6
  L1 w0.12: R894_SPI_bridge_PCIe.1@60.563,380.233 60.563,379.512 61.048,379.027 61.048,378.072 U27_SPI_bridge_PCIe.2@61.213,377.907
NetR895_SPI_bridge_Main_2: R895_SPI_bridge_Main.2 U27_SPI_bridge_Main.8
NetR895_SPI_bridge_PCIe_2: R895_SPI_bridge_PCIe.2 U27_SPI_bridge_PCIe.8 | length 2.6
  L1 w0.12: R895_SPI_bridge_PCIe.2@56.733,380.232 56.733,379.012 57.313,378.432 U27_SPI_bridge_PCIe.8@57.313,377.907
NetR896_SPI_bridge_Main_1: R896_SPI_bridge_Main.1 U28_SPI_bridge_Main.1 | length 2.8
  L1 w0.12: U28_SPI_bridge_Main.1@170.769,230.338 172.416,230.338 172.905,229.85 R896_SPI_bridge_Main.1@173.33,229.85
NetR896_SPI_bridge_PCIe_1: R896_SPI_bridge_PCIe.1 U28_SPI_bridge_PCIe.1 | length 2.1
  L1 w0.12: R896_SPI_bridge_PCIe.1@169.964,248.456 169.964,249.17 170.548,249.753 U28_SPI_bridge_PCIe.1@170.548,250.278
NetR897_SPI_bridge_Main_2: R897_SPI_bridge_Main.2 U28_SPI_bridge_Main.7 | length 2.6
  L1 w0.12: U28_SPI_bridge_Main.7@170.769,234.238 R897_SPI_bridge_Main.2@173.33,234.238
NetR897_SPI_bridge_PCIe_2: R897_SPI_bridge_PCIe.2 U28_SPI_bridge_PCIe.7 | length 2
  L1 w0.12: R897_SPI_bridge_PCIe.2@173.938,248.456 173.938,248.911 174.448,249.421 U28_SPI_bridge_PCIe.7@174.448,250.278
NetR898_SPI_bridge_Main_1: R898_SPI_bridge_Main.1 U28_SPI_bridge_Main.2 | length 2.6
  L1 w0.12: U28_SPI_bridge_Main.2@170.769,230.988 R898_SPI_bridge_Main.1@173.33,230.988
NetR898_SPI_bridge_PCIe_1: R898_SPI_bridge_PCIe.1 U28_SPI_bridge_PCIe.2 | length 2
  L1 w0.12: U28_SPI_bridge_PCIe.2@171.198,250.278 171.198,248.981 171.673,248.506 R898_SPI_bridge_PCIe.1@171.673,248.456
NetR899_SPI_bridge_Main_2: R899_SPI_bridge_Main.2 U28_SPI_bridge_Main.8 | length 2.8
  L1 w0.12: U28_SPI_bridge_Main.8@170.769,234.888 172.791,234.888 173.28,235.377 R899_SPI_bridge_Main.2@173.33,235.377
NetR899_SPI_bridge_PCIe_2: R899_SPI_bridge_PCIe.2 U28_SPI_bridge_PCIe.8 | length 2.1
  L1 w0.12: U28_SPI_bridge_PCIe.8@175.098,250.278 175.098,249.114 175.706,248.506 R899_SPI_bridge_PCIe.2@175.706,248.456
NetR901_1: R901.1 U1.H14 | length 65.6
  L1 w0.116: v4(168.909,302.027) U1.H14@169.397,301.539
  L3 (Sign) w0.12: v1(118.461,293.675) 117.493,292.706 117.493,289.966 121.234,286.225 145.874,286.225 145.923,286.274 145.961,286.274 145.992,286.306 146.046,286.306 146.068,286.328 146.134,286.328 155.849,296.043 155.849,296.109 155.871,296.132 155.871,296.185 155.903,296.216 155.903,296.254 155.952,296.304 155.952,297.9 159.371,301.319 166.699,301.319 167.742,302.362 168.048,302.362 168.383,302.027 v4(168.909,302.027)
NetR902_1: R902.1 U1.G14 | length 64.7
  L1 w0.116: v4(167.909,302.027) U1.G14@168.397,301.539
  L3 (Sign) w0.12: v1(117.861,293.675) 117.205,293.019 117.205,289.847 121.115,285.938 145.897,285.938 146.014,286.054 146.052,286.054 146.083,286.086 146.137,286.086 146.159,286.108 146.225,286.108 156.069,295.952 156.069,296.018 156.091,296.04 156.091,296.094 156.123,296.125 156.123,296.163 156.24,296.28 156.24,297.781 159.558,301.099 166.982,301.099 v4(167.909,302.027)
NetR913_1: R913.1 U1.L15 | length 67.6
  L1 w0.116: v4(171.909,303.027) U1.L15@172.397,302.539
  L3 (Sign) w0.12: v1(120.861,293.675) 118.567,291.381 118.567,290.411 121.679,287.299 145.861,287.299 154.878,296.316 154.878,298.223 158.859,302.204 166.327,302.204 167.705,303.582 170.139,303.582 170.14,303.581 171.355,303.581 v4(171.909,303.027)
NetR914_1: R914.1 U1.L14 | length 69.5
  L1 w0.116: v4(171.909,302.027) U1.L14@172.397,301.539
  L3 (Sign) w0.12: v1(116.661,293.675) 116.684,293.653 116.684,289.631 120.898,285.416 145.907,285.416 145.939,285.448 145.977,285.448 146.026,285.498 146.08,285.498 146.196,285.614 146.234,285.614 146.266,285.646 146.319,285.646 146.341,285.668 146.408,285.668 156.509,295.77 156.509,295.836 156.531,295.858 156.531,295.912 156.563,295.943 156.563,295.981 156.68,296.098 156.68,296.151 156.729,296.2 156.729,296.238 156.761,296.27 156.761,297.565 159.399,300.203 167.216,300.203 168.397,301.384 171.266,301.384 v4(171.909,302.027)
NetR915_1: R915.1 U1.K15 | length 67
  L1 w0.116: v4(170.909,303.027) U1.K15@171.397,302.539
  L3 (Sign) w0.12: v1(120.261,293.675) 118.256,291.67 118.256,290.282 121.55,286.988 145.861,286.988 155.189,296.316 155.189,298.216 158.953,301.981 166.427,301.981 167.808,303.362 170.048,303.362 170.383,303.027 v4(170.909,303.027)
NetR916_1: R916.1 U1.K14 | length 68.1
  L1 w0.116: v4(170.909,302.027) U1.K14@171.397,301.539
  L3 (Sign) w0.12: v1(117.261,293.675) 116.936,293.349 116.936,289.735 121.003,285.668 145.886,285.668 145.935,285.718 145.989,285.718 146.105,285.834 146.143,285.834 146.174,285.866 146.228,285.866 146.25,285.888 146.316,285.888 156.289,295.861 156.289,295.927 156.311,295.949 156.311,296.003 156.343,296.034 156.343,296.072 156.46,296.189 156.46,296.242 156.509,296.291 156.509,297.67 159.715,300.876 167.373,300.876 168.097,301.6 168.302,301.6 168.306,301.604 170.486,301.604 v4(170.909,302.027)
NetR917_1: R917.1 U1.J15 | length 66
  L1 w0.116: v4(169.909,303.027) U1.J15@170.397,302.539
  L3 (Sign) w0.12: v1(119.661,293.675) 118.014,292.027 118.014,290.182 121.449,286.746 145.863,286.746 145.886,286.768 145.952,286.768 155.409,296.225 155.409,296.291 155.431,296.314 155.431,298.116 159.076,301.761 166.518,301.761 167.784,303.027 v4(169.909,303.027)
NetR918_1: R918.1 U1.J14 | length 66.4
  L1 w0.116: v4(169.909,302.027) U1.J14@170.397,301.539
  L3 (Sign) w0.12: v1(119.061,293.675) 117.762,292.376 117.762,290.077 121.345,286.494 145.87,286.494 145.901,286.526 145.954,286.526 145.977,286.548 146.043,286.548 155.629,296.134 155.629,296.2 155.651,296.223 155.651,296.276 155.683,296.308 155.683,298.012 159.21,301.539 166.608,301.539 167.651,302.582 169.354,302.582 v4(169.909,302.027)
NetR918_2: R918.2 U36_U_Translator_I2C4.8
NetR919_1: R919.1 U1.J16 | length 13.5
  L1 w0.116: v4(169.909,304.027) U1.J16@170.397,303.539
  L3 (Sign) w0.12: 157.91,305.875 159.59,305.875 160.031,305.435 165.151,305.435 166.192,304.394 168.884,304.394 169.251,304.027 v4(169.909,304.027)
NetR919_2: R919.2 U36_U_Translator_I2C1.8
NetR961_2: R961.2
NetR962_2: R962.2
NetR963_2: R963.2
NetR964_2: R964.2
NetR965_2: R965.2
NetR966_2: R966.2
NetR1004_1: R1004.1 U55.28 | length 3.3
  L1 w0.12: R1004.1@237.471,202.666 237.807,202.666 239.157,204.016 U55.28@240.17,204.016
NetR1005_1: R1005.1 U55.29 | length 5.9
  L1 w0.12: R1005.1@235.16,201.769 237.824,201.769 238.341,202.286 238.341,202.578 239.279,203.516 U55.29@240.17,203.516
NetR1006_1: R1006.1 U55.30 | length 3.8
  L1 w0.12: R1006.1@237.471,200.787 237.592,200.787 238.684,201.879 238.684,202.194 239.505,203.016 U55.30@240.17,203.016
NetR1007_1: R1007.1 U55.32 | length 5.9
  L1 w0.12: R1007.1@235.16,199.885 238.039,199.885 U55.32@240.17,202.016
NetR1008_1: R1008.1 U55.33 | length 5.8
  L1 w0.12: U55.33@241.97,200.216 241.97,197.714 242.252,197.431 R1008.1@242.252,194.487
NetR1009_1: R1009.1 U55.34 | length 8.4
  L1 w0.12: U55.34@242.47,200.216 242.47,198.151 243.154,197.466 R1009.1@243.154,192.101
NetR1012_1: R1012.1 U55.43 | length 6
  L1 w0.12: U55.43@246.97,200.216 246.97,196.946 247.632,196.284 R1012.1@247.632,194.487
NetR1013_1: R1013.1 U55.44 | length 8.5
  L1 w0.12: U55.44@247.47,200.216 247.47,197.348 248.517,196.301 R1013.1@248.517,192.101
NetR1014_1: R1014.1 U55.45 | length 6.3
  L1 w0.12: U55.45@247.97,200.216 247.97,197.667 249.425,196.211 R1014.1@249.425,194.487
NetR1015_1: R1015.1 U55.46 | length 8.9
  L1 w0.12: U55.46@248.47,200.216 248.47,197.897 250.304,196.063 R1015.1@250.304,192.101
NetR1016_1: R1016.1 U55.53 | length 5.2
  L1 w0.12: U55.53@251.27,204.016 252.384,204.016 253.454,202.946 253.454,201.867 253.991,201.329 R1016.1@254.693,201.329
NetR1017_1: R1017.1 U55.54 | length 4.2
  L1 w0.12: U55.54@251.27,204.516 252.394,204.516 254.239,202.671 R1017.1@254.693,202.671
NetR1018_1: R1018.1 U55.55 | length 3.8
  L1 w0.12: U55.55@251.27,205.016 252.691,205.016 253.693,204.013 R1018.1@254.693,204.013
NetR1019_1: R1019.1 U55.57 | length 3.7
  L1 w0.12: U55.57@251.27,206.016 252.657,206.016 253.318,205.355 R1019.1@254.693,205.355
NetR1020_1: R1020.1 U55.58 | length 3.5
  L1 w0.12: U55.58@251.27,206.516 253.123,206.516 253.304,206.697 R1020.1@254.693,206.697
NetR1021_1: R1021.1 U55.59 | length 3.8
  L1 w0.12: U55.59@251.27,207.016 252.938,207.016 253.961,208.039 R1021.1@254.693,208.039
NetR1022_1: R1022.1 U79.5
NetR1023_1: R1023.1 U79.12
NetR1024_1: R1024.1 U79.6
NetR1025_1: R1025.1 U79.11
NetR1026_1: R1026.1 U53.14 | length 4.1
  L1 w0.12: U53.14@217.924,205.683 219.072,205.683 220.372,206.983 R1026.1@221.513,206.983
NetR1027_1: R1027.1 U53.13 | length 3.8
  L1 w0.12: U53.13@217.924,205.033 219.594,205.033 220.028,205.466 R1027.1@221.513,205.466
NetR1028_1: R1028.1 U53.12 | length 3.8
  L1 w0.12: U53.12@217.924,204.383 219.591,204.383 220.024,203.95 R1028.1@221.513,203.95
NetR1029_1: R1029.1 U53.11 | length 4.1
  L1 w0.12: U53.11@217.924,203.733 219.034,203.733 220.334,202.433 R1029.1@221.513,202.433
NetR1030_1: R1030.1 U55.16
NetR1031_1: R1031.1 U55.17 | length 5.6
  L1 w0.12: R1031.1@235.097,210.844 237.999,210.844 239.328,209.516 U55.17@240.17,209.516
NetR1032_1: R1032.1 U55.18 | length 3.1
  L1 w0.12: R1032.1@237.433,209.955 238.113,209.955 239.053,209.016 U55.18@240.17,209.016
NetR1033_1: R1033.1 U55.19 | length 5.3
  L1 w0.12: R1033.1@235.122,209.066 238.24,209.066 238.791,208.516 U55.19@240.17,208.516
NetR1034_1: R1034.1 U55.21 | length 3
  L1 w0.12: R1034.1@237.459,208.152 238.275,208.152 238.911,207.516 U55.21@240.17,207.516
NetR1035_1: R1035.1 U55.22 | length 5.1
  L1 w0.12: R1035.1@235.135,207.263 238.266,207.263 238.513,207.016 U55.22@240.17,207.016
NetR1036_1: R1036.1 U55.23 | length 2.8
  L1 w0.12: R1036.1@237.471,206.387 238.289,206.387 238.418,206.516 U55.23@240.17,206.516
NetR1037_1: R1037.1 U55.24 | length 5.2
  L1 w0.12: R1037.1@235.16,205.536 238.454,205.536 238.934,206.016 U55.24@240.17,206.016
NetR1038_1: R1038.1 U55.26 | length 2.9
  L1 w0.12: R1038.1@237.471,204.545 238.226,204.545 238.696,205.016 U55.26@240.17,205.016
NetR1039_1: R1039.1 U55.27 | length 5.4
  L1 w0.12: R1039.1@235.16,203.652 237.828,203.652 238.692,204.516 U55.27@240.17,204.516
NetR1040_1: R1040.1 U56.14
NetR1041_1: R1041.1 U56.13
NetR1042_1: R1042.1 U56.12
NetR1043_1: R1043.1 U56.11
NetR1044_1: R1044.1 U55.38 | length 5.9
  L1 w0.12: R1044.1@244.046,194.487 244.046,195.793 244.47,196.217 U55.38@244.47,200.216
NetR1045_1: R1045.1 U55.39 | length 8.1
  L1 w0.12: R1045.1@244.942,192.101 244.97,192.129 U55.39@244.97,200.216
NetR1046_1: R1046.1 U55.48 | length 6.5
  L1 w0.12: U55.48@249.47,200.216 249.47,198.264 251.219,196.515 R1046.1@251.219,194.487
NetR1047_1: R1047.1 U55.52 | length 5.9
  L1 w0.12: U55.52@251.27,203.516 252.198,203.516 252.832,202.882 252.832,201.153 253.997,199.987 R1047.1@254.693,199.987
NetR1048_2: R1048.2 S8.8
NetR1049_2: R1049.2 S8.7
NetR1050_2: R1050.2 S8.6
NetR1051_2: R1051.2 S8.5
NetR1052_1: R1052.1 U6.A4
NetR1053_1: R1053.1 U7.A4
NetT22_3: T22.3 T23.2
NetT34_4: T34.4 U65.11 | length 14.6
  L1 w0.254: v4(37.846,218.796) 37.85,218.791 T34.4@38.377,218.791 ; U65.11@39.76,206.158 39.76,206.746 v4@40.514,207.5
  L3 (Sign) w0.254: v4(37.846,218.796) 37.846,213.779 40.526,211.099 v4(40.526,207.488)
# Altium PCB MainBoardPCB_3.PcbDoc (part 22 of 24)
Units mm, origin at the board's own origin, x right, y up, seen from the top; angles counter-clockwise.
Board outline 258.95 x 308.86 mm, 16 copper layers (L1, L2 (GND), L3 (Sign), L4 (GND), L5 (Sign), L6 (PWR/GND), L7(PWR/GND), L8 (Plane_GND), L9 (PWR/GND), L10 (PWR/GND), L11 (PWR/GND), L12 (Sign), L13 (GND), L14 (Sign), L15 (GND), L16), stack 2.502 mm thick; 2402 components, 1749 nets, 8407 pads, 3409 vias.
Unrouted connection lines stored in the file: 4352.

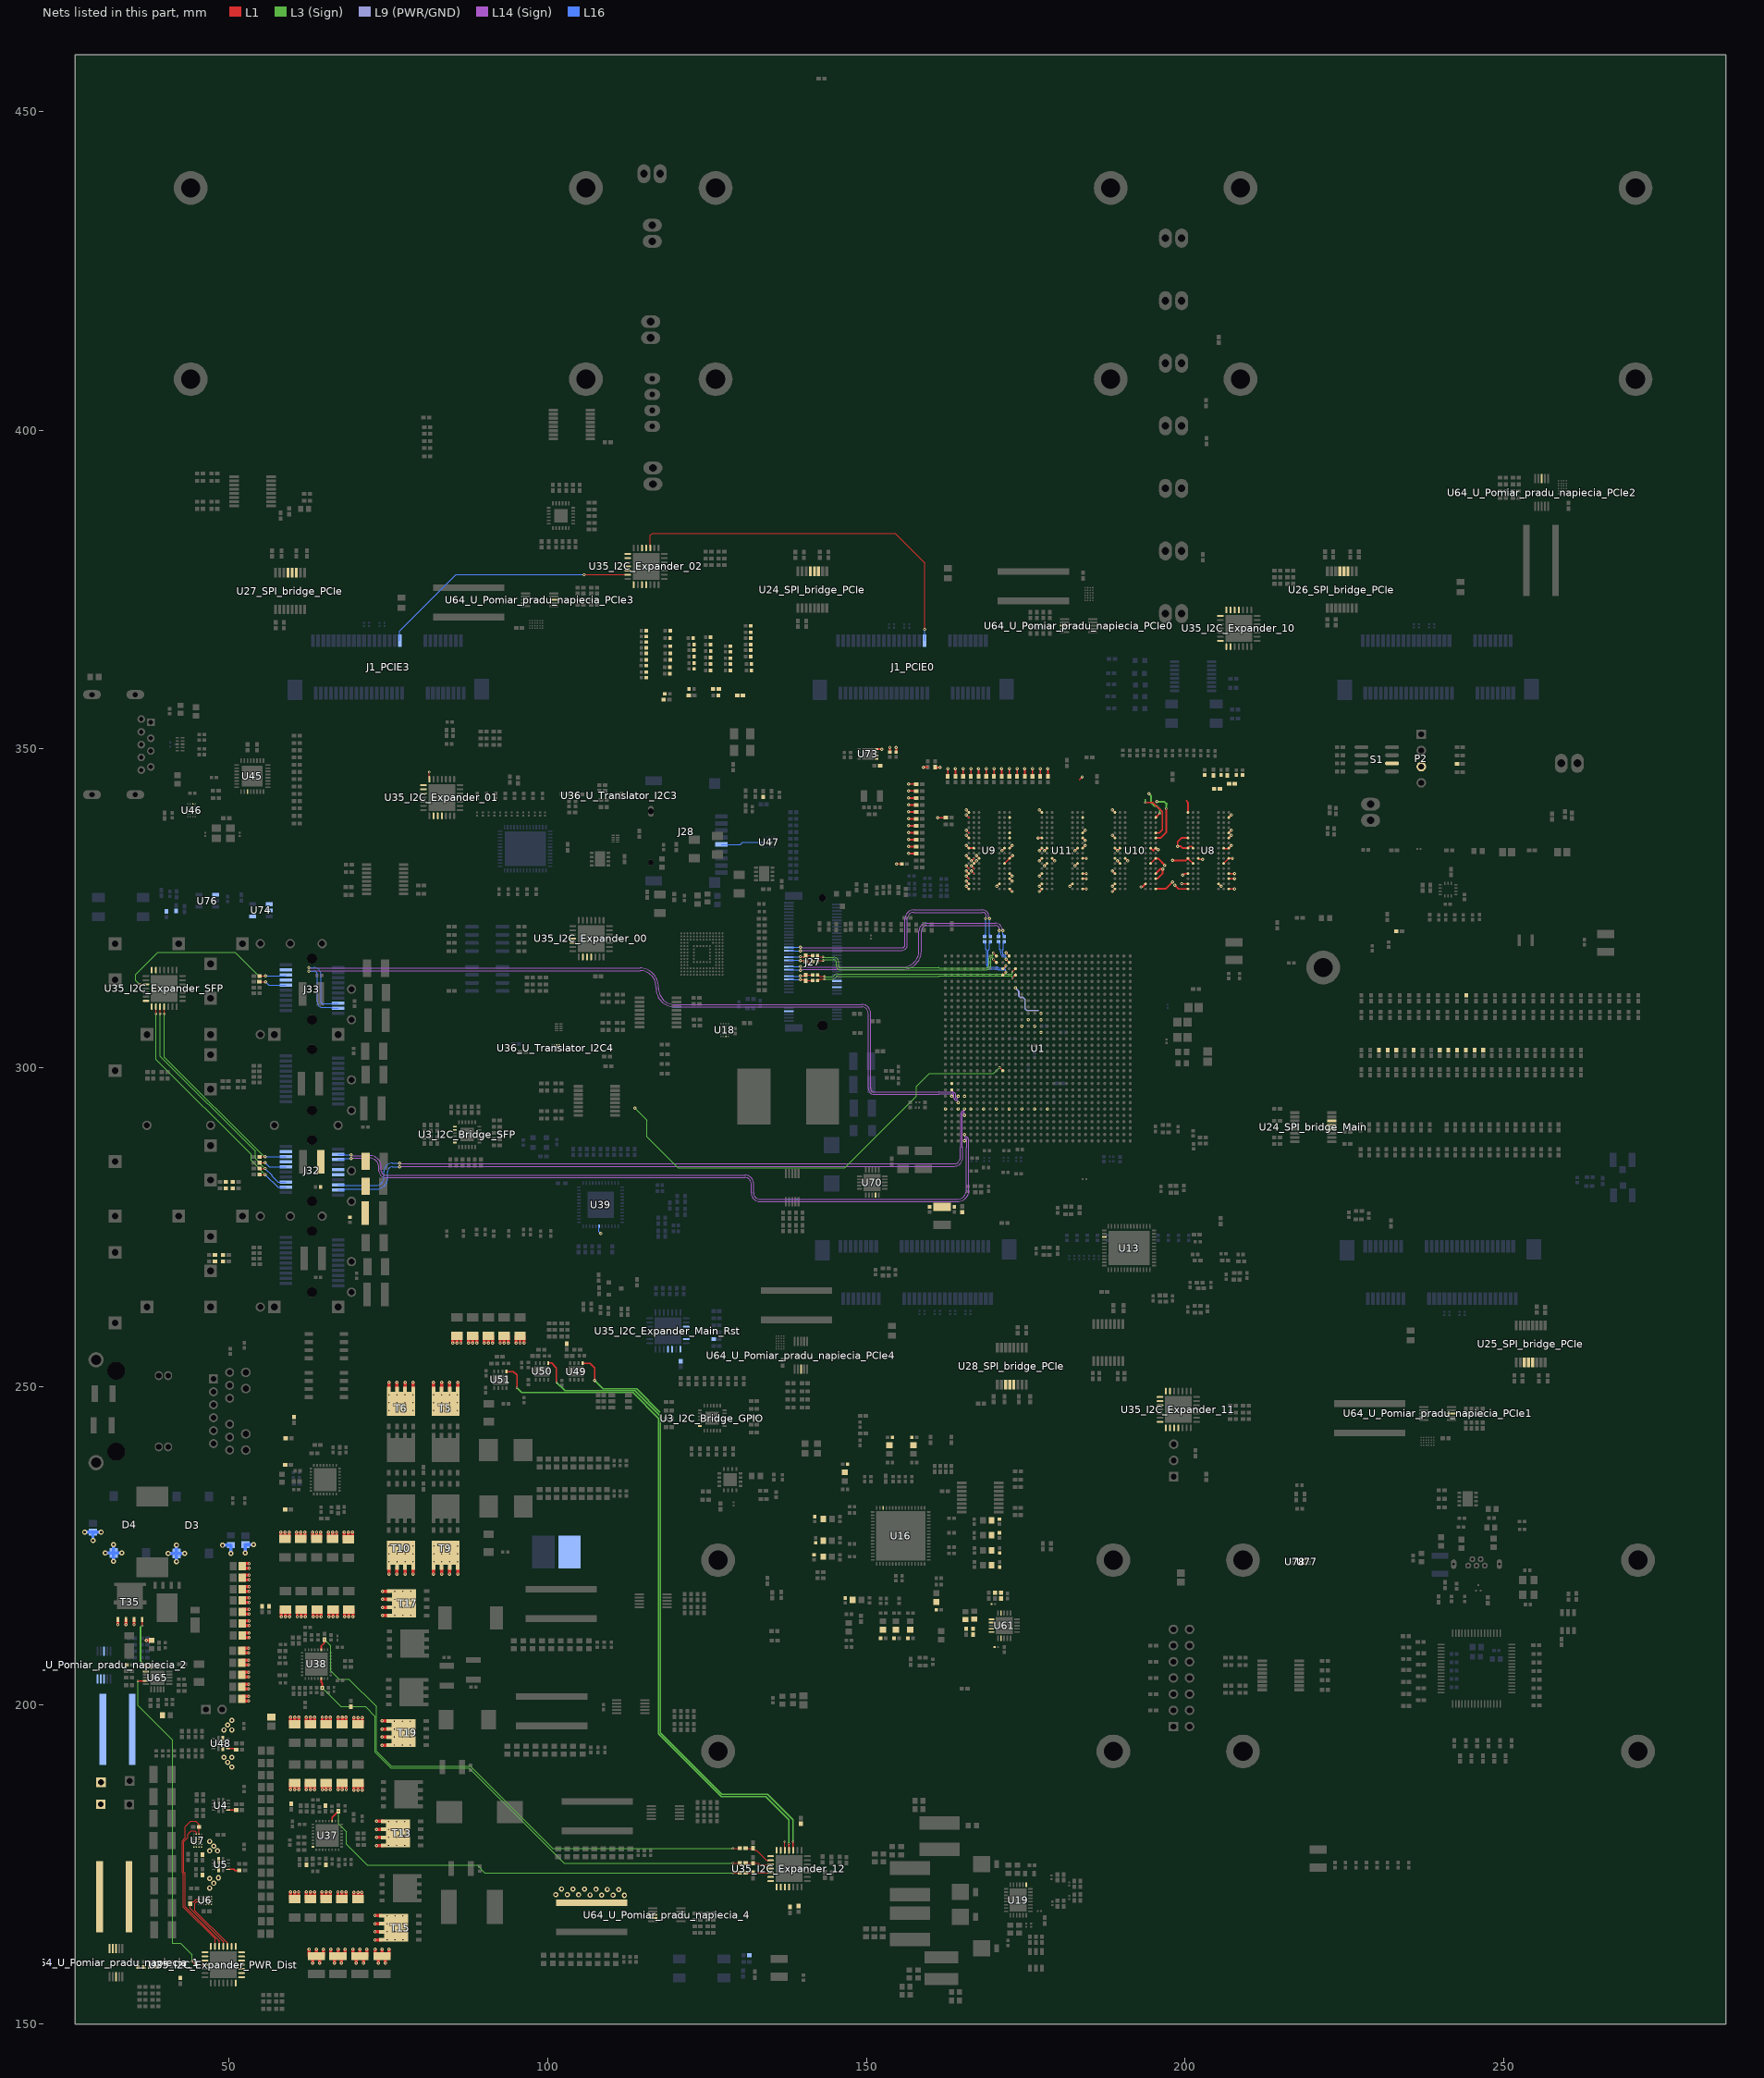
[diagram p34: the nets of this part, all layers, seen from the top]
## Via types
v1: diameter 0.5, hole 0.2, L1 to L16, tented both sides, 1267 vias
v2: diameter 0.5/0.35/0.35/0.35/0.35/0.35/0.35/0.35/0.35/0.35/0.35/0.35/0.35/0.35/0.35/0.5 (per signal layer), hole 0.15, L1 to L16, tented both sides, 463 vias
v3: diameter 0.5, hole 0.2, L1 to L16, 446 vias
v4: diameter 0.35/0/0.35 (per signal layer), hole 0.127, L1 to L3 (Sign), tented both sides, 347 vias
v5: diameter 0.5/0.35/0.35/0.35/0.35/0.35/0.35/0.35/0.35/0.35/0.35/0.35/0.35/0.35/0.35/0.5 (per signal layer), hole 0.2, L1 to L16, tented both sides, 244 vias
v6: diameter 0.8, hole 0.4, L1 to L16, tented both sides, 168 vias
v7: diameter 2.54, hole 1.02, L1 to L16, 113 vias
v8: diameter 1.4, hole 0.5, L1 to L16, tented both sides, 80 vias
v9: diameter 0.5/0/0.5 (per signal layer), hole 0.2, L14 (Sign) to L16, tented both sides, 62 vias
v10: diameter 0.35/0/0.35 (per signal layer), hole 0.127, L1 to L3 (Sign), 38 vias
v11: diameter 0.35, hole 0.127, L1 to L2 (GND), tented both sides, 36 vias
v12: diameter 0.4, hole 0.2, L1 to L16, 16 vias
v13: diameter 0.25, hole 0.2, L1 to L16, 16 vias
v14: diameter 0.35, hole 0.127, L1 to L16, tented both sides, 16 vias
v15: diameter 0.3, hole 0.2, L1 to L16, 15 vias
v16: diameter 0.45, hole 0.15, L1 to L16, 12 vias
v17: diameter 0.5/0.35/0.35/0.35/0.35/0.35/0.35/0.35/0.35/0.35/0.35/0.35/0.35/0.35/0.35/0.45 (per signal layer), hole 0.15, L1 to L16, tented both sides, 10 vias
v18: diameter 0.2/0/0.2 (per signal layer), hole 0.1, L1 to L3 (Sign), tented both sides, 9 vias
v19: diameter 0.4, hole 0.1, L1 to L16, 7 vias
v20: diameter 0.5, hole 0.2, L3 (Sign) to L6 (PWR/GND), tented both sides, 6 vias
v21: diameter 1.15, hole 1.15, L1 to L16, 5 vias
v22: diameter 1.65, hole 1.65, L1 to L16, 5 vias
v23: diameter 0.35/0/0.35 (per signal layer), hole 0.127, L14 (Sign) to L16, tented both sides, 5 vias
v24: diameter 0.5, hole 0.2, L11 (PWR/GND) to L14 (Sign), tented both sides, 4 vias
v25: diameter 0.2, hole 0.1, L1 to L16, 4 vias
v26: diameter 0.35, hole 0.127, L1 to L2 (GND), 2 vias
v27: diameter 0.4, hole 0.15, L1 to L16, 2 vias
v28: diameter 0.4, hole 0.2, L1 to L16, tented both sides, 2 vias
v29: diameter 0.5/0.35/0.35/0.35/0.35/0.35/0.35/0.35/0.35/0.35/0.35/0.35/0.35/0.35/0.35/0.5 (per signal layer), hole 0.15, L1 to L16, 2 vias
v30: diameter 0.35, hole 0.127, L3 (Sign) to L6 (PWR/GND), tented both sides, 2 vias
v31: diameter 0.5/0.35/0.35/0.35/0.35/0.35/0.35/0.35/0.35/0.35/0.35/0.35/0.35/0.35/0.35/0.5 (per signal layer), hole 0.2, L1 to L16, 1 vias
v32: diameter 0.35/0.35/0.35 (per signal layer), hole 0.127, L1 to L3 (Sign), tented both sides, 1 vias
v33: diameter 0.45/0/0.45 (per signal layer), hole 0.15, L1 to L3 (Sign), tented both sides, 1 vias
v34: diameter 0.45/0/0.45 (per signal layer), hole 0.2, L14 (Sign) to L16, tented both sides, 1 vias
v35: diameter 0.35, hole 0.127, L2 (GND) to L3 (Sign), 1 vias

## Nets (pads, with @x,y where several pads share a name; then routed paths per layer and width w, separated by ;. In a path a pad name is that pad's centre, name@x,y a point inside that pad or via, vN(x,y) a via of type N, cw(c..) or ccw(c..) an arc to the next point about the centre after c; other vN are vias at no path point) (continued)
NetT35_4: T35.4 U65.15 | length 8.6
  L1 w0.254: v4(36.36,212.471) T35.4@36.36,213.464 ; v4(36.71,206.368) 36.92,206.158 U65.15@37.76,206.158
  L3 (Sign) w0.254: v4(36.36,212.471) 36.093,212.204 36.093,206.985 v4(36.71,206.368)
NetTP7_I2C_Bridge_GPIO_1: U3_I2C_Bridge_GPIO.24 U35_I2C_Expander_Main_Rst.3
NetU1_B9: U1.B9
NetU1_B10: U1.B10
NetU3_I2C_Bridge_SFP_19: U3_I2C_Bridge_SFP.19 U36_U_Translator_I2C3.6 U36_U_Translator_I2C4.6
NetU3_I2C_Bridge_SFP_20: U3_I2C_Bridge_SFP.20 U36_U_Translator_I2C3.5 U36_U_Translator_I2C4.5
NetU13_43: U13.43
NetU24_SPI_bridge_Main_12: U24_SPI_bridge_Main.12 U24_SPI_bridge_PCIe.5 U25_SPI_bridge_PCIe.5 U26_SPI_bridge_PCIe.5 U27_SPI_bridge_PCIe.5 U28_SPI_bridge_PCIe.5
NetU24_SPI_bridge_Main_13: U24_SPI_bridge_Main.13 U24_SPI_bridge_PCIe.4 U25_SPI_bridge_PCIe.4 U26_SPI_bridge_PCIe.4 U27_SPI_bridge_PCIe.4 U28_SPI_bridge_PCIe.4
NetU24_SPI_bridge_Main_14: U24_SPI_bridge_Main.14 U24_SPI_bridge_PCIe.3 U25_SPI_bridge_PCIe.3 U26_SPI_bridge_PCIe.3 U27_SPI_bridge_PCIe.3 U28_SPI_bridge_PCIe.3
NetU35_I2C_Expander_00_3: U35_I2C_Expander_00.3
NetU35_I2C_Expander_00_4: U35_I2C_Expander_00.4
NetU35_I2C_Expander_00_25: U35_I2C_Expander_00.25
NetU35_I2C_Expander_00_26: U35_I2C_Expander_00.26
NetU35_I2C_Expander_01_2: U35_I2C_Expander_01.2
NetU35_I2C_Expander_01_3: U35_I2C_Expander_01.3
NetU35_I2C_Expander_01_4: U35_I2C_Expander_01.4
NetU35_I2C_Expander_01_21: U35_I2C_Expander_01.21 | length 1.1
  L1 w0.12: U35_I2C_Expander_01.21@81.419,345.272 v10(81.419,346.376)
NetU35_I2C_Expander_01_22: U35_I2C_Expander_01.22 U46.A3
NetU35_I2C_Expander_01_23: U35_I2C_Expander_01.23
NetU35_I2C_Expander_01_24: U35_I2C_Expander_01.24
NetU35_I2C_Expander_02_1: U35_I2C_Expander_02.1
NetU35_I2C_Expander_02_3: U35_I2C_Expander_02.3
NetU35_I2C_Expander_02_4: U35_I2C_Expander_02.4
NetU35_I2C_Expander_02_18: U35_I2C_Expander_02.18
NetU35_I2C_Expander_02_19: U35_I2C_Expander_02.19
NetU35_I2C_Expander_02_22: U35_I2C_Expander_02.22
NetU35_I2C_Expander_02_23: U35_I2C_Expander_02.23
NetU35_I2C_Expander_02_25: U35_I2C_Expander_02.25
NetU35_I2C_Expander_02_26: U35_I2C_Expander_02.26
NetU35_I2C_Expander_10_1: U35_I2C_Expander_10.1
NetU35_I2C_Expander_10_2: U35_I2C_Expander_10.2
NetU35_I2C_Expander_10_18: U35_I2C_Expander_10.18
NetU35_I2C_Expander_10_19: U35_I2C_Expander_10.19
NetU35_I2C_Expander_10_20: U35_I2C_Expander_10.20
NetU35_I2C_Expander_10_21: U35_I2C_Expander_10.21
NetU35_I2C_Expander_10_22: U35_I2C_Expander_10.22
NetU35_I2C_Expander_10_28: U35_I2C_Expander_10.28
NetU35_I2C_Expander_11_1: U35_I2C_Expander_11.1
NetU35_I2C_Expander_11_2: U35_I2C_Expander_11.2
NetU35_I2C_Expander_11_3: U35_I2C_Expander_11.3
NetU35_I2C_Expander_11_4: U35_I2C_Expander_11.4
NetU35_I2C_Expander_11_20: U35_I2C_Expander_11.20
NetU35_I2C_Expander_11_21: U35_I2C_Expander_11.21
NetU35_I2C_Expander_11_22: U35_I2C_Expander_11.22
NetU35_I2C_Expander_11_23: U35_I2C_Expander_11.23
NetU35_I2C_Expander_11_24: U35_I2C_Expander_11.24
NetU35_I2C_Expander_11_28: U35_I2C_Expander_11.28
NetU35_I2C_Expander_12_1: U35_I2C_Expander_12.1
NetU35_I2C_Expander_12_2: U35_I2C_Expander_12.2
NetU35_I2C_Expander_12_3: U35_I2C_Expander_12.3
NetU35_I2C_Expander_12_20: U35_I2C_Expander_12.20
NetU35_I2C_Expander_12_21: U35_I2C_Expander_12.21
NetU35_I2C_Expander_12_22: U35_I2C_Expander_12.22
NetU35_I2C_Expander_12_25: U35_I2C_Expander_12.25
NetU35_I2C_Expander_12_27: U35_I2C_Expander_12.27
NetU35_I2C_Expander_12_28: U35_I2C_Expander_12.28
NetU35_I2C_Expander_Main_Rst_4: U35_I2C_Expander_Main_Rst.4
NetU35_I2C_Expander_Main_Rst_24: U35_I2C_Expander_Main_Rst.24
NetU35_I2C_Expander_PWR_CLK_2: U35_I2C_Expander_PWR_CLK.2
NetU35_I2C_Expander_PWR_CLK_3: U35_I2C_Expander_PWR_CLK.3
NetU35_I2C_Expander_PWR_CLK_4: U35_I2C_Expander_PWR_CLK.4
NetU35_I2C_Expander_PWR_Dist_1: U35_I2C_Expander_PWR_Dist.1
NetU35_I2C_Expander_PWR_Dist_2: U35_I2C_Expander_PWR_Dist.2
NetU35_I2C_Expander_PWR_Dist_3: U35_I2C_Expander_PWR_Dist.3
NetU35_I2C_Expander_PWR_Dist_17: U35_I2C_Expander_PWR_Dist.17
NetU35_I2C_Expander_PWR_Dist_18: U35_I2C_Expander_PWR_Dist.18
NetU35_I2C_Expander_PWR_Dist_28: U35_I2C_Expander_PWR_Dist.28
NetU35_I2C_Expander_SFP_1: U35_I2C_Expander_SFP.1
NetU35_I2C_Expander_SFP_20: U35_I2C_Expander_SFP.20
NetU35_I2C_Expander_SFP_21: U35_I2C_Expander_SFP.21
NetU35_I2C_Expander_SFP_28: U35_I2C_Expander_SFP.28
NVME_C_RX_1_N: C718.1 U1.K28 | length 7.8
  L1 w0.116: U1.K28@171.397,315.539 v5(171.884,316.027)
  L16 w0.063: 169.287,318.539 ccw(c169.287,318.381) 169.128,318.381 169.128,316.088 ccw(c169.418,316.088) 169.418,315.798 170.389,315.798 cw(c170.389,315.322) 170.726,315.659 171.679,315.659 ccw(c171.679,315.864) 171.884,315.864 v5(171.884,316.027)
  L16 w0.081: 169.287,318.539 169.287,319.483 ccw(c169.287,319.647) 169.451,319.647 C718.1@169.451,319.799
NVME_C_RX_1_P: C717.1 U1.K27 | length 8.2
  L1 w0.116: U1.K27@171.397,314.539 v5(171.884,315.027)
  L16 w0.063: 168.706,318.539 cw(c168.706,318.381) 168.865,318.381 168.865,316.088 ccw(c169.418,316.088) 169.418,315.535 170.379,315.535 cw(c170.379,315.296) 170.547,315.465 ccw(c170.716,315.633) 170.716,315.395 171.679,315.395 cw(c171.679,315.189) 171.884,315.189 v5(171.884,315.027)
  L16 w0.081: C717.1@168.542,319.799 168.542,319.647 ccw(c168.706,319.647) 168.706,319.483 168.706,318.539
NVME_C_RX_O_N: C677.1 U1.M28 | length 31.9
  L1 w0.081: C677.1@142.334,314.574 142.41,314.574 cw(c142.41,314.334) 142.65,314.334 v4(143.446,314.334)
  L1 w0.116: v4(172.909,315.052) U1.M28@173.397,315.539
  L3 (Sign) w0.076: 161.397,314.742 161.397,314.69 172.733,314.69 ccw(c172.733,314.867) 172.909,314.867 v4(172.909,315.052)
  L3 (Sign) w0.08: v4(143.446,314.334) ccw(c143.482,314.334) 143.482,314.298 144.463,314.298 ccw(c144.463,314.959) 144.931,314.492 144.932,314.493 cw(c145.532,313.892) 145.532,314.742 161.397,314.742
NVME_C_RX_O_P: C653.1 U1.M27 | length 31.9
  L1 w0.081: C653.1@142.334,313.674 142.44,313.674 ccw(c142.44,313.884) 142.65,313.884 v4(143.446,313.884)
  L1 w0.116: v4(172.909,314.052) U1.M27@173.397,314.539
  L3 (Sign) w0.076: 161.397,314.362 161.397,314.414 172.733,314.414 cw(c172.733,314.237) 172.909,314.237 v4(172.909,314.052)
  L3 (Sign) w0.08: v4(143.446,313.884) cw(c143.482,313.884) 143.482,313.919 144.464,313.919 ccw(c144.464,314.957) 145.198,314.223 ; 145.199,314.223 cw(c145.534,313.889) 145.534,314.362 161.397,314.362
NVME_C_TX_1_N: C716.1 U1.J30 | length 31.6
  L1 w0.081: C716.1@142.334,317.575 142.494,317.415 v4(143.18,317.415)
  L1 w0.116: v4(169.909,318.027) U1.J30@170.397,317.539
  L3 (Sign) w0.076: 161.345,315.723 cw(c161.345,315.671) 161.397,315.671 168.859,315.671 ccw(c168.859,316.056) 169.244,316.056 169.244,317.14 cw(c169.718,317.14) 169.718,317.614 169.727,317.614 ccw(c169.727,317.797) 169.909,317.797 v4(169.909,318.027)
  L3 (Sign) w0.08: 161.345,315.723 145.922,315.723 cw(c145.922,315.963) 145.682,315.963 145.682,316.521 ccw(c144.888,316.521) 144.888,317.314 v4@143.28,317.314 ; v4@143.28,317.314 cw(c143.28,317.415) v4(143.18,317.415) ccw(c143.28,317.415) v4@143.28,317.314
NVME_C_TX_1_P: C715.1 U1.J29 | length 31.5
  L1 w0.081: C715.1@142.334,316.674 142.494,316.834 v4(143.18,316.834)
  L1 w0.116: v4(169.909,317.027) U1.J29@170.397,316.539
  L3 (Sign) w0.076: 161.345,315.343 ccw(c161.345,315.396) 161.397,315.396 168.859,315.396 ccw(c168.859,316.056) 169.52,316.056 169.52,317.14 cw(c169.718,317.14) 169.718,317.339 169.727,317.339 cw(c169.727,317.156) 169.909,317.156 v4(169.909,317.027)
  L3 (Sign) w0.08: 161.345,315.343 145.922,315.343 cw(c145.922,315.963) 145.302,315.963 145.302,316.521 ccw(c144.888,316.521) 144.888,316.935 v4@143.28,316.935 ; v4@143.28,316.935 ccw(c143.28,316.834) v4(143.18,316.834) cw(c143.28,316.834) v4@143.28,316.935
NVME_C_TX_O_N: C651.1 U1.L30 | length 3.8
  L1 w0.116: v1(171.909,318.027) U1.L30@172.397,317.539
  L16 w0.063: 171.471,318.539 171.425,318.539 ccw(c171.425,318.427) 171.312,318.427 171.312,318.12 ccw(c171.78,318.12) 171.78,317.652 ccw(c171.78,317.782) 171.909,317.782 v1(171.909,318.027)
  L16 w0.081: 171.471,318.539 171.471,319.483 ccw(c171.471,319.647) 171.635,319.647 C651.1@171.635,319.799
NVME_C_TX_O_P: C649.1 U1.L29 | length 4.2
  L1 w0.116: v1(171.909,317.027) U1.L29@172.397,316.539
  L16 w0.063: 170.89,318.539 170.937,318.539 cw(c170.937,318.427) 171.049,318.427 171.049,318.12 ccw(c171.78,318.12) 171.78,317.389 cw(c171.78,317.26) 171.909,317.26 v1(171.909,317.027)
  L16 w0.081: C649.1@170.726,319.799 170.726,319.647 ccw(c170.89,319.647) 170.89,319.483 170.89,318.539
NVMe_Rx_0_N: C677.2 J27.47 R541.2 | length 3.8
  L1 w0.081: v1(139.624,314.424) 140.121,314.424 cw(c140.271,314.424) 140.271,314.574 R541.2@140.462,314.574 C677.2@141.554,314.574
  L16 w0.081: J27.47@137.843,314.374 139.574,314.374 ccw(c139.574,314.424) v1(139.624,314.424)
NVMe_Rx_0_P: C653.2 J27.49 R541.1 | length 3.8
  L1 w0.081: v1(139.624,313.824) 140.121,313.824 ccw(c140.271,313.824) 140.271,313.674 R541.1@140.462,313.674 C653.2@141.554,313.674
  L16 w0.081: J27.49@137.843,313.874 139.574,313.874 cw(c139.574,313.824) v1(139.624,313.824)
NVMe_Rx_1_N: C716.2 J27.35 R542.2 | length 3.8
  L1 w0.081: v1(139.636,317.425) 140.312,317.425 R542.2@140.462,317.575 C716.2@141.554,317.575
  L16 w0.081: J27.35@137.843,317.374 139.586,317.374 v1(139.636,317.425)
NVMe_Rx_1_P: C715.2 J27.37 R542.1 | length 3.8
  L1 w0.081: v1(139.636,316.825) 140.312,316.825 R542.1@140.462,316.674 C715.2@141.554,316.674
  L16 w0.081: J27.37@137.843,316.874 139.587,316.874 v1(139.636,316.825)
NVMe_Tx_0_N: C651.2 J27.41 | length 40.7
  L14 (Sign) w0.08: v9(139.636,315.908) ccw(c139.747,315.908) 139.747,315.798 155.703,315.798 ccw(c155.703,318.338) 158.243,318.338 158.243,321.462 cw(c159.46,321.462) 159.46,322.68 170.243,322.68 cw(c170.243,321.601) 171.322,321.601 ccw(c171.371,321.601) 171.371,321.551 v9(171.432,321.551)
  L16 w0.08: v9@139.602,315.874 ccw(c139.602,315.908) v9(139.636,315.908) ; 171.432,320.894 v9(171.432,321.551)
  L16 w0.081: J27.41@137.843,315.874 v9@139.602,315.874 ; 171.432,320.894 cw(c171.432,320.691) 171.635,320.691 C651.2@171.635,320.579
NVMe_Tx_0_P: C649.2 J27.43 | length 40
  L14 (Sign) w0.08: v9(139.636,315.308) cw(c139.747,315.308) 139.747,315.418 155.703,315.418 ccw(c155.703,318.338) 158.623,318.338 158.623,321.462 cw(c159.46,321.462) 159.46,322.3 170.243,322.3 cw(c170.243,321.601) 170.942,321.601 cw(c170.892,321.601) 170.892,321.551 v9(170.832,321.551)
  L16 w0.08: v9@139.571,315.374 cw(c139.571,315.308) v9(139.636,315.308) ; 170.726,320.894 ccw(c170.726,321) 170.832,321 v9(170.832,321.551)
  L16 w0.081: J27.43@137.843,315.374 v9@139.571,315.374 ; C649.2@170.726,320.579 170.726,320.894
NVMe_Tx_1_N: C718.2 J27.29 | length 40.5
  L14 (Sign) w0.08: v9(139.636,318.924) ccw(c139.747,318.924) 139.747,318.814 155.588,318.814 ccw(c155.588,319.272) 156.046,319.272 156.046,323.393 cw(c157.416,323.393) 157.416,324.763 168.237,324.763 cw(c168.237,323.814) 169.186,323.814 169.186,323.541 ccw(c169.296,323.541) v9(169.296,323.431)
  L16 w0.081: J27.29@137.843,318.874 138.618,318.874 ccw(c138.618,318.914) 138.659,318.914 139.636,318.914 v9(139.636,318.924) ; v9(169.296,323.431) 169.287,323.431 169.287,320.894 cw(c169.287,320.73) 169.451,320.73 C718.2@169.451,320.579
NVMe_Tx_1_P: C717.2 J27.31 | length 39.9
  L14 (Sign) w0.08: v9(139.636,318.324) cw(c139.747,318.324) 139.747,318.434 155.588,318.434 ccw(c155.588,319.272) 156.426,319.272 156.426,323.393 cw(c157.416,323.393) 157.416,324.383 168.237,324.383 cw(c168.237,323.814) 168.806,323.814 168.806,323.541 cw(c168.696,323.541) v9(168.696,323.431)
  L16 w0.081: J27.31@137.843,318.374 138.618,318.374 cw(c138.618,318.333) 138.659,318.333 139.636,318.333 v9(139.636,318.324) ; C717.2@168.542,320.579 168.542,320.73 cw(c168.706,320.73) 168.706,320.894 168.706,323.431 v9(168.696,323.431)
OSC_500Out: C333.2 X2.10
Osc_in_Si53323_2_N: C343.2 R259.2 R261.2 R489.1 U32.6
Osc_in_Si53323_2_P: C342.2 R260.2 R262.2 R489.2 U32.7
OSC_Out_DIV_N: C343.1 R258.1 U33.11
OSC_Out_DIV_P: C342.1 R256.2 U33.10
P4HS_PowerAlert_Pcie0: R530.2 U64_U_Pomiar_pradu_napiecia_PCIe0.3
P4HS_PowerAlert_Pcie1: R547.2 U64_U_Pomiar_pradu_napiecia_PCIe1.3
P4HS_PowerAlert_Pcie2: R550.2 U64_U_Pomiar_pradu_napiecia_PCIe2.3
P4HS_PowerAlert_Pcie3: R553.2 U64_U_Pomiar_pradu_napiecia_PCIe3.3
P4HS_PowerAlert_Pcie4: R556.2 U64_U_Pomiar_pradu_napiecia_PCIe4.3
PCIe_Reset: R788.1
PCIE_Resets: J27.50 U35_I2C_Expander_00.2
PCIE_Resets_0: J1_PCIE0.18 U35_I2C_Expander_02.17 | length 59.3
  L1 w0.12: U35_I2C_Expander_02.17@116.08,381.532 116.103,381.556 116.103,383.527 116.434,383.857 154.483,383.857 159.162,379.178 v3(159.162,368.785)
  L16 w0.12: J1_PCIE0.18@159.137,366.992 159.162,367.017 v3(159.162,368.785)
PCIE_Resets_3: J1_PCIE3.18 U35_I2C_Expander_02.27 | length 41
  L1 w0.12: v3(105.702,377.342) 105.71,377.35 112.547,377.35 U35_I2C_Expander_02.27@112.555,377.357
  L16 w0.12: J1_PCIE3.18@76.785,366.992 76.785,368.513 85.614,377.342 v3(105.702,377.342)
PDN: R498.2 U16.46
PEDET: J27.61
PEwake: J27.54
PG1_1: R295.2 R835.1 U37.27 | length 71.3
  L1 w0.12: v10(129.057,173.721) R835.1@130.157,173.721
  L1 w0.254: U37.27@66.175,181.817 66.175,182.406 v10(67.169,183.4)
  L3 (Sign) w0.12: v10(67.169,183.4) 67.169,181.39 68.437,180.123 68.437,178.175 71.7,174.912 88.932,174.912 90.123,173.721 v10(129.057,173.721)
PG1_2: R313.2 R838.1 U38.27 | length 87
  L1 w0.12: v10(129.057,177.521) 130.107,177.521 R838.1@130.157,177.571
  L1 w0.254: U38.27@64.453,208.714 64.453,209.276 64.953,209.776 v10(64.953,210.304)
  L3 (Sign) w0.12: v10(64.953,210.304) 65.953,209.304 65.953,205.434 67.264,204.124 68.786,204.124 73.127,199.782 73.127,192.758 75.426,190.46 87.857,190.46 100.796,177.521 v10(129.057,177.521)
PG1_TPS7A8801: R440.1 U35_I2C_Expander_PWR_CLK.28 U61.17
PG2_2: R314.2 R836.1 U38.14 | length 81.8
  L1 w0.12: v10(129.057,175.235) 130.143,175.235 R836.1@130.157,175.221
  L1 w0.254: U38.14@64.453,204.214 64.455,204.212 64.455,203.6 64.623,203.432 v10(64.623,202.723)
  L3 (Sign) w0.12: v10(64.623,202.723) 67.565,199.782 71.377,199.782 72.907,198.252 72.907,192.667 75.375,190.2 87.649,190.2 102.614,175.235 v10(129.057,175.235)
PG2_TPS7A8801: R441.1 U35_I2C_Expander_PWR_CLK.1 U61.9
PG2_TPS7A8801_0V9: R676.1 U37.8 U70.9 U73.5
PG_1V0@1.5A: R827.2 U35_I2C_Expander_12.18 U51.5 | length 108.4
  L1 w0.2: U51.5@93.544,252.363 94.613,252.363 95.148,251.828 v10(95.148,249.784) ; v10(137.833,178.308) 137.846,178.295 137.846,177.259 U35_I2C_Expander_12.18@137.858,177.246
  L3 (Sign) w0.2: v10(95.148,249.784) 95.893,249.039 113.368,249.039 117.398,245.009 117.398,195.534 127.231,185.701 134.208,185.701 137.833,182.076 v10(137.833,178.308)
PG_1V8@1.5A: R826.2 U35_I2C_Expander_12.17 U50.5 | length 103.3
  L1 w0.2: U50.5@100.076,253.671 100.647,253.671 101.381,252.938 v10(101.381,250.685) ; U35_I2C_Expander_12.17@138.508,177.246 v10(138.508,178.603)
  L3 (Sign) w0.2: v10(101.381,250.685) 102.726,249.339 113.691,249.339 117.698,245.332 117.698,195.658 127.308,186.048 134.519,186.048 138.508,182.058 v10(138.508,178.603)
PG_2V5@1.5A: R392.1 U18.A2 U49.5 | length 16.4
  L1 w0.2: U49.5@105.47,253.648 106.618,253.648 107.378,252.889 v3(107.378,250.953)
  L3 (Sign) w0.2: v3(107.378,250.953) 108.693,249.639 113.937,249.639 117.602,245.974
PG_3V3@14A_EXP: R835.2 R837.1 U35_I2C_Expander_12.26 | length 4
  L1 w0.12: R835.2@131.057,173.721 132.145,173.721 R837.1@132.195,173.771 132.245,173.721 U35_I2C_Expander_12.26@134.983,173.721
PG_5V@10A_EXP: R836.2 R839.1 U35_I2C_Expander_12.24 | length 4
  L1 w0.12: R836.2@131.057,175.221 R839.1@132.195,175.221 132.209,175.235 133.058,175.235 133.272,175.021 U35_I2C_Expander_12.24@134.983,175.021
PG_12@8A_EXP: R838.2 R840.1 U35_I2C_Expander_12.23 | length 4.7
  L1 w0.12: R838.2@131.057,177.571 132.145,177.571 132.435,177.281 132.726,177.281 134.336,175.671 U35_I2C_Expander_12.23@134.983,175.671
PG_48_20V: R828.2 U35_I2C_Expander_PWR_Dist.4 U65.19 | length 51.8
  L1 w0.12: v10(44.183,159.841) 44.195,159.841 44.733,159.303 U35_I2C_Expander_PWR_Dist.4@46.218,159.303
  L1 w0.254: v4(35.671,203.818) U65.19@36.92,203.818
  L3 (Sign) w0.12: v4(35.671,203.818) 35.671,199.936 41.048,194.559 41.048,162.712 42.367,162.712 44.183,160.896 v10(44.183,159.841)
PG_DCDC_Low_curr: R825.2 U19.23 U35_I2C_Expander_12.4
PG_LT3042: R442.1 U35_I2C_Expander_PWR_CLK.25 U62.4
PG_PS_LTC6952_1: R431_U_5V_to_3V33.1 U35_I2C_Expander_PWR_CLK.17 U59_U_5V_to_3V33.5
PG_PS_LTC6952_2: R431_U_5V_to_3V32.1 U35_I2C_Expander_PWR_CLK.21 U59_U_5V_to_3V32.5
PG_PS_LTC6952_3: R431_U_5V_to_3V31.1 U35_I2C_Expander_PWR_CLK.23 U59_U_5V_to_3V31.5
PG_VTT_RAM: R691.2 U35_I2C_Expander_12.19 U73.6 | length 1.4
  L1 w0.12: v10(137.208,178.596) 137.208,177.274 U35_I2C_Expander_12.19@137.222,177.26
  L1 w0.2: U35_I2C_Expander_12.19@137.208,177.246 U35_I2C_Expander_12.19@137.222,177.26 ; R691.2@152.142,347.358 R691.2@152.192,347.308
PGND: C595.1 C596.1 C597.1 C598.1 C694.1 C695.1 C696.1 C697.1 C698.1 C699.1 C700.1 C704.2 D3.2 D4.2 R324.1 R764.2 T35.1 T35.2 T35.3 U65.16 | length 33.5
  L1 w0.5: v1(32.55,212.65) T35.1@32.55,213.464 ; v1(33.82,212.65) T35.2@33.82,213.464 ; v1(35.09,212.65) T35.3@35.09,213.464 ; v1(37.032,210.162) C598.1@37.846,210.162 ; C699.1@51.994,200.664 v1(53.081,200.664) ; C699.1@51.994,201.387 v1(53.081,201.387) ; C696.1@51.994,202.554 v1(53.081,202.554) ; C696.1@51.994,203.278 v1(53.081,203.278) ; C697.1@51.994,204.444 v1(53.081,204.444) ; C697.1@51.994,205.168 v1(53.081,205.168) ; C695.1@51.994,206.335 v1(53.081,206.335) ; C695.1@51.994,207.059 v1(53.081,207.059) ; C698.1@51.994,208.225 v1(53.081,208.225) ; C698.1@51.994,208.949 v1(53.081,208.949)
  L16 w0.5: v6(27.345,227.151) C595.1@28.639,227.151 ; v6(28.639,225.857) C595.1@28.639,227.151 ; v6(29.932,227.151) C595.1@28.639,227.151 ; v6(30.586,223.896) D4.2@31.88,223.896 ; v6(31.88,222.602) D4.2@31.88,223.896 ; v6(31.88,225.19) D4.2@31.88,223.896 ; v6(33.174,223.896) D4.2@31.88,223.896 ; v6(40.454,223.832) D3.2@41.748,223.832 ; v6(41.748,222.539) D3.2@41.748,223.832 ; v6(41.748,225.126) D3.2@41.748,223.832 ; v6(43.041,223.832) D3.2@41.748,223.832 ; v6(48.998,225.107) R324.1@50.292,225.107 v6(50.292,223.813) ; v6(52.54,223.901) C596.1@52.54,225.195 v6(53.834,225.195)
PMU_GPI: J14.7 R784.1
PMU_GPI_1: J14.6 R785.1
PMU_GPI_2: J14.5 R786.1
PMU_GPI_3: J14.4 R787.1
PMU_GPI_5: J14.2 R789.1
PMU_GPO_0: J18.7 R790.1
PMU_GPO_1: J18.6 R791.1
PMU_GPO_2: J18.5 R792.1
PMU_GPO_3: J18.4 R793.1
PMU_GPO_4: J18.3 R794.1
PMU_GPO_5: J18.2 R795.1
Power1_In: P8.1 R448_U_Pomiar_pradu_napiecia_1.1 U64_U_Pomiar_pradu_napiecia_1.10
Power1_In_CM: R12.2 R448_U_Pomiar_pradu_napiecia_1.2 U5.7 U6.C3 U6.D3 U6.D4 U6.E3 U6.E4 U6.F3 U6.F4 U64_U_Pomiar_pradu_napiecia_1.8 U64_U_Pomiar_pradu_napiecia_1.9
  other v6: 46.94,171.336 47.599,172.073 46.939,172.838 48.314,172.942
  other v12: 48.36,174.6
Power2_In: P10.1 R448_U_Pomiar_pradu_napiecia_2.1 U64_U_Pomiar_pradu_napiecia_2.10
Power2_In_CM: R20.2 R448_U_Pomiar_pradu_napiecia_2.2 U5.2 U7.C3 U7.D3 U7.D4 U7.E3 U7.E4 U7.F3 U7.F4 U64_U_Pomiar_pradu_napiecia_2.8 U64_U_Pomiar_pradu_napiecia_2.9
  other v6: 46.939,177.161 48.188,177.161 47.599,177.926 46.94,178.663
  other v12: 48.36,175.4
Power4Charging: U6.C2 U6.D1 U6.D2 U6.E1 U6.E2 U6.F1 U6.F2 U7.C2 U7.D1 U7.D2 U7.E1 U7.E2 U7.F1 U7.F2
Power_3.3_1: C99.2 C100.2 C103.2 C104.2 C107.2 C124.2 C141.2 C145.2 C162.2 C179.2 C572.2 C573.2 FB8.1 FB9.1 FB10.1 FB11.1 FB12.1 FB14.1 FB16.1 FB18.1 FB20.1 FB22.1 R436.2 R440.2 U61.14 U61.15
Power_3.3_2: C108.2 C125.2 C142.2 C146.2 C163.2 C576.2 C577.2 FB13.1 FB15.1 FB17.1 FB19.1 FB21.1 R438.2 R441.2 U61.11 U61.12
Power_MUX_Status0: R630.2 U5.9 U35_I2C_Expander_PWR_Dist.19 | length 1.8
  L1 w0.2: U5.9@49.86,174.25 50.769,174.25 50.927,174.091 R630.2@51.6,174.091
Power_MUX_Status1: R11.1 U4.9 U35_I2C_Expander_PWR_Dist.20 | length 1.3
  L1 w0.2: U4.9@49.86,183.571 51.101,183.571 R11.1@51.11,183.563
Power_MUX_Status2: R13.2 U35_I2C_Expander_PWR_Dist.21 U48.9 | length 1.1
  L1 w0.2: U48.9@49.827,193.233 50.736,193.233 R13.2@50.895,193.075
PS_MODE1: P2.3 R350.1 S1.2 U1.R19 U74.2
  other v5: 176.397,306.539
PS_POR: P3.2 R355.2 U1.N19 U74.1 U76.1 U77.6
  other v5: 174.397,306.539
PS_Reset: P4.1 R354.1 U1.P20 U77.4 U78.6
  other v5: 175.397,307.539
PWR_ExtIO_INT0: R977.2 U35_I2C_Expander_PWR_Dist.16
PWR_ExtIO_INT1: R976.2 U35_I2C_Expander_PWR_Dist.15
PWR_ExtIO_INT2: R978.2 U35_I2C_Expander_PWR_CLK.15
PWR_ExtIO_INT3: R979.2 U35_I2C_Expander_PWR_CLK.16
PWR_ExtIO_nReset: R755.1 U35_I2C_Expander_Main_Rst.27 U35_I2C_Expander_PWR_Dist.14
PWR_OUT_20V: C347.2 C348.2 C352.2 C353.2 C371.2 C372.2 C373.2 C374.2 C375.2 C376.2 C391.1 C392.2 C396.2 C397.1 C400.2 C401.2 C402.2 C403.2 C404.2 C405.2 C432.1 C433.2 C437.2 C438.1 C441.2 C442.2 C443.2 C444.2 C445.2 C446.2 C766.1 C767.1 C768.1 C769.1 C770.2 C771.2 C772.2 C773.2 C774.2 C775.2 C776.2 C777.2 C778.2 C779.2 C780.2 C781.2 R266.2 R268.1 R285.1 R303.1 R612.2 R614.2 R621.2 R622.2 R628.2 R686.2 T5.5 T5.6 T5.7 T5.8 T6.5 T6.6 T6.7 T6.8 T9.5 T9.6 T9.7 T9.8 T10.5 T10.6 T10.7 T10.8 T13.5 T13.6 T13.7 T13.8 T15.5 T15.6 T15.7 T15.8 T17.5 T17.6 T17.7 T17.8 T19.5 T19.6 T19.7 T19.8 U48.1 U48.8 | length 169.6
  L1 w0.5: C780.2@52.066,210.593 v1(53.153,210.593) ; C780.2@52.066,211.317 v1(53.153,211.317) ; C779.2@52.066,212.488 v1(53.153,212.488) ; C779.2@52.066,213.212 v1(53.153,213.212) ; C778.2@52.066,214.297 v1(53.153,214.297) ; C778.2@52.066,215.021 v1(53.153,215.021) ; C777.2@52.067,216.111 v1(53.154,216.111) ; C777.2@52.066,216.835 v1(53.153,216.835) ; C776.2@52.066,217.856 v1(53.153,217.856) ; C776.2@52.066,218.58 v1(53.153,218.58) ; C775.2@52.066,219.678 v1(53.153,219.678) ; C775.2@52.066,220.402 v1(53.153,220.402) ; C774.2@52.066,221.492 v1(53.153,221.492) ; C774.2@52.066,222.216 v1(53.153,222.216) ; C392.2@58.13,226.088 v1(58.13,227.175) ; v1(58.214,213.896) C397.1@58.214,214.983 ; C392.2@58.776,226.088 v1(58.776,227.175) ; v1(58.852,213.896) C397.1@58.852,214.983 ; C392.2@59.413,226.088 v1(59.413,227.175) ; v1(59.497,213.896) C397.1@59.497,214.983 ; C433.2@59.63,169.623 v1(59.63,170.71) ; C353.2@59.645,197.03 v1(59.645,198.117) ; v1(59.653,186.744) C438.1@59.653,187.831 ; C433.2@60.276,169.623 v1(60.276,170.71) ; v1(60.29,186.744) C438.1@60.29,187.831 ; C353.2@60.29,197.03 v1(60.29,198.117) ; C391.1@60.612,226.088 v1(60.612,227.175) ; v1(60.696,213.896) C396.2@60.696,214.983 ; C433.2@60.913,169.623 v1(60.913,170.71) ; C353.2@60.928,197.03 v1(60.928,198.117) ; v1(60.935,186.744) C438.1@60.935,187.831 ; C391.1@61.258,226.088 v1(61.258,227.175) ; v1(61.334,213.896) C396.2@61.334,214.983 ; C391.1@61.895,226.088 v1(61.895,227.175) ; v1(61.979,213.896) C396.2@61.979,214.983 ; C432.1@62.112,169.623 v1(62.112,170.71) ; C352.2@62.127,197.03 v1(62.127,198.117) ; v1(62.135,186.744) C437.2@62.135,187.831 ; C769.1@62.575,160.649 v1(62.575,161.736) ; C432.1@62.758,169.623 v1(62.758,170.71) ; v1(62.772,186.744) C437.2@62.772,187.831 ; C352.2@62.772,197.03 v1(62.772,198.117) ; C405.2@63.094,226.087 v1(63.094,227.174) ; v1(63.124,159.562) C769.1@63.124,160.649 ; v1(63.179,213.896) C402.2@63.179,214.983 ; C432.1@63.395,169.623 v1(63.395,170.71) ; C352.2@63.41,197.03 v1(63.41,198.117) ; v1(63.417,186.744) C437.2@63.417,187.831 ; C769.1@63.68,160.649 v1(63.68,161.736) ; C405.2@63.74,226.087 v1(63.74,227.174) ; v1(63.816,213.896) C402.2@63.816,214.983 ; v1(64.229,159.562) C769.1@64.229,160.649 ; C405.2@64.377,226.087 v1(64.377,227.174) ; v1(64.461,213.896) C402.2@64.461,214.983 ; C446.2@64.594,169.623 v1(64.594,170.71) ; C374.2@64.609,197.03 v1(64.609,198.117) ; v1(64.617,186.744) C443.2@64.617,187.831 ; C769.1@64.777,160.649 v1(64.777,161.736) ; C446.2@65.24,169.623 v1(65.24,170.71) ; v1(65.254,186.744) C443.2@65.254,187.831 ; C374.2@65.254,197.03 v1(65.254,198.117) ; C404.2@65.576,226.087 v1(65.576,227.174) ; v1(65.661,213.896) C401.2@65.661,214.983 ; C446.2@65.877,169.623 v1(65.877,170.71) ; C374.2@65.892,197.03 v1(65.892,198.117) ; v1(65.899,186.744) C443.2@65.899,187.831 ; C768.1@65.979,160.649 v1(65.979,161.736) ; C404.2@66.222,226.087 v1(66.222,227.174) ; v1(66.298,213.896) C401.2@66.298,214.983 ; v1(66.527,159.563) C768.1@66.527,160.649 ; C404.2@66.859,226.087 v1(66.859,227.174) ; v1(66.943,213.896) C401.2@66.943,214.983 ; C445.2@67.076,169.623 v1(67.076,170.71) ; C768.1@67.084,160.649 v1(67.084,161.736) ; C371.2@67.091,197.03 v1(67.091,198.117) ; v1(67.099,186.744) C442.2@67.099,187.831 ; v1(67.632,159.563) C768.1@67.632,160.649 ; C445.2@67.722,169.623 v1(67.722,170.71) ; v1(67.736,186.744) C442.2@67.736,187.831 ; C371.2@67.736,197.03 v1(67.736,198.117) ; C403.2@68.058,226.057 v1(68.058,227.144) ; v1(68.143,213.866) C400.2@68.143,214.953 ; C768.1@68.181,160.649 v1(68.181,161.736) ; C445.2@68.359,169.623 v1(68.359,170.71) ; C371.2@68.374,197.03 v1(68.374,198.117) ; v1(68.382,186.744) C442.2@68.382,187.831 ; C403.2@68.704,226.057 v1(68.704,227.144) ; v1(68.78,213.866) C400.2@68.78,214.953 ; C403.2@69.341,226.057 v1(69.341,227.144) ; C767.1@69.419,160.65 v1(69.419,161.737) ; v1(69.425,213.866) C400.2@69.425,214.953 ; C444.2@69.558,169.592 v1(69.558,170.679) ; C376.2@69.573,196.999 v1(69.573,198.086) ; v1(69.581,186.713) C441.2@69.581,187.8 ; v1(69.967,159.563) C767.1@69.967,160.65 ; C444.2@70.204,169.592 v1(70.204,170.679) ; v1(70.218,186.713) C441.2@70.218,187.8 ; C376.2@70.218,196.999 v1(70.218,198.086) ; C767.1@70.524,160.65 v1(70.524,161.737) ; C444.2@70.841,169.592 v1(70.841,170.679) ; C376.2@70.856,196.999 v1(70.856,198.086) ; v1(70.864,186.713) C441.2@70.864,187.8 ; v1(71.072,159.563) C767.1@71.072,160.65 ; C767.1@71.621,160.65 v1(71.621,161.737) ; v1(72.877,163.201) T15.8@73.964,163.201 ; v1(72.877,164.471) T15.7@73.964,164.471 ; v1(72.877,165.741) T15.6@73.964,165.741 ; v1(72.877,167.011) T15.5@73.964,167.011 ; C766.1@72.887,160.649 v1(72.887,161.736) ; v1(73.13,178.003) T13.8@74.217,178.003 ; v1(73.13,179.273) T13.7@74.217,179.273 ; v1(73.13,180.543) T13.6@74.217,180.543 ; v1(73.13,181.813) T13.5@74.217,181.813 ; v1(73.435,159.562) C766.1@73.435,160.649 ; C766.1@73.992,160.649 v1(73.992,161.736) ; v1(74.017,193.746) T19.8@75.104,193.746 ; v1(74.017,195.016) T19.7@75.104,195.016 ; v1(74.017,196.286) T19.6@75.104,196.286 ; v1(74.017,197.556) T19.5@75.104,197.556 ; v1(74.086,214.079) T17.8@75.173,214.079 ; v1(74.086,215.349) T17.7@75.173,215.349 ; v1(74.086,216.619) T17.6@75.173,216.619 ; v1(74.086,217.889) T17.5@75.173,217.889 ; v1(74.54,159.562) C766.1@74.54,160.649 ; T6.8@75.072,249.548 v1(75.072,250.635) ; v1(75.078,220.589) T10.5@75.078,221.676 ; C766.1@75.088,160.649 v1(75.088,161.736) ; T6.7@76.342,249.548 v1(76.342,250.635) ; v1(76.348,220.589) T10.6@76.348,221.676 ; T6.6@77.612,249.548 v1(77.612,250.635) ; v1(77.618,220.589) T10.7@77.618,221.676 ; T6.5@78.882,249.548 v1(78.882,250.635) ; v1(78.888,220.589) T10.8@78.888,221.676 ; v1(82.072,220.589) T9.5@82.072,221.676 ; T5.8@82.072,249.548 v1(82.072,250.635) ; v1(83.342,220.589) T9.6@83.342,221.676 ; T5.7@83.342,249.548 v1(83.342,250.635) ; v1(84.612,220.589) T9.7@84.612,221.676 ; T5.6@84.612,249.548 v1(84.612,250.635) ; v1(85.091,256.835) C348.2@85.091,257.922 ; v1(85.728,256.835) C348.2@85.728,257.922 ; v1(85.882,220.589) T9.8@85.882,221.676 ; T5.5@85.882,249.548 v1(85.882,250.635) ; v1(86.374,256.835) C348.2@86.374,257.922 ; v1(87.573,256.835) C347.2@87.573,257.922 ; v1(88.21,256.835) C347.2@88.21,257.922 ; v1(88.856,256.835) C347.2@88.856,257.922 ; v1(90.055,256.835) C372.2@90.055,257.922 ; v1(90.692,256.835) C372.2@90.692,257.922 ; v1(91.338,256.835) C372.2@91.338,257.922 ; v1(92.537,256.835) C375.2@92.537,257.922 ; v1(93.174,256.835) C375.2@93.174,257.922 ; v1(93.82,256.835) C375.2@93.82,257.922 ; v1(95.019,256.804) C373.2@95.019,257.891 ; v1(95.656,256.804) C373.2@95.656,257.891 ; v1(96.302,256.804) C373.2@96.302,257.891
  other v1: 74.782,163.22 76.034,163.22 77.285,163.22 74.782,164.471 76.034,164.471 77.285,164.471 74.782,165.723 76.034,165.723 77.285,165.723 74.782,166.975 76.034,166.975 77.285,166.975 75.035,178.022 76.287,178.022 77.539,178.022 75.035,179.273 76.287,179.273 77.539,179.273 75.035,180.525 76.287,180.525 77.539,180.525 75.035,181.777 76.287,181.777 77.539,181.777 75.922,193.764 77.173,193.764 78.425,193.764 75.922,195.016 77.173,195.016 78.425,195.016 75.922,196.267 77.173,196.267 78.425,196.267 75.922,197.519 77.173,197.519 78.425,197.519 75.991,214.097 77.243,214.097 78.495,214.097 75.991,215.349 77.243,215.349 78.495,215.349 75.991,216.6 77.243,216.6 78.495,216.6 75.991,217.852 77.243,217.852 78.495,217.852 75.114,222.494 76.366,222.494 77.618,222.494 78.869,222.494 82.108,222.494 83.36,222.494 84.612,222.494 85.863,222.494 75.114,223.745 76.366,223.745 77.618,223.745 78.869,223.745 82.108,223.745 83.36,223.745 84.612,223.745 85.863,223.745 75.114,224.997 76.366,224.997 77.618,224.997 78.869,224.997 82.108,224.997 83.36,224.997 84.612,224.997 85.863,224.997 75.09,246.226 76.342,246.226 77.593,246.226 78.845,246.226 82.09,246.226 83.342,246.226 84.593,246.226 85.845,246.226 75.09,247.478 76.342,247.478 77.593,247.478 78.845,247.478 82.09,247.478 83.342,247.478 84.593,247.478 85.845,247.478 75.09,248.73 76.342,248.73 77.593,248.73 78.845,248.73 82.09,248.73 83.342,248.73 84.593,248.73 85.845,248.73
  other v6: 50.447,190.32 49.788,191.057 49.2,191.821 50.448,191.822 49.2,196.145 50.448,196.145 49.788,196.91 50.447,197.647
  other v12: 49.027,193.583 49.027,194.383
PWR_PowerAlert0: R974.2 U35_I2C_Expander_PWR_Dist.22 U64_U_Pomiar_pradu_napiecia_1.3
PWR_PowerAlert1: R975.2 U35_I2C_Expander_PWR_Dist.23 U64_U_Pomiar_pradu_napiecia_2.3
PWR_Switch1_En: U6.A2 U35_I2C_Expander_PWR_Dist.24 | length 9.5
  L1 w0.12: U6.A2@45.21,169.189 44.91,169.189 44.66,168.939 44.66,167.785 49.709,162.737 49.709,162.212 U35_I2C_Expander_PWR_Dist.24@49.743,162.178
PWR_Switch1_Flag: R29.1 U6.A3 U35_I2C_Expander_PWR_Dist.25 | length 10.5
  L1 w0.12: U6.A3@45.21,169.589 44.86,169.589 44.459,169.188 44.144,169.188 43.904,168.948 R29.1@43.904,168.898 43.904,168.084 49.093,162.894 U35_I2C_Expander_PWR_Dist.25@49.093,162.178
PWR_Switch2_En: U7.A2 U35_I2C_Expander_PWR_Dist.26 | length 22.2
  L1 w0.12: U7.A2@44.875,179.775 44.875,180.078 44.629,180.325 44.08,180.325 43.555,179.8 43.555,179.312 42.879,178.636 42.879,173.855 43.129,173.606 43.129,168.38 48.443,163.066 U35_I2C_Expander_PWR_Dist.26@48.443,162.178
PWR_Switch2_Flag: R30.1 U7.A3 U35_I2C_Expander_PWR_Dist.27 | length 25.3
  L1 w0.12: U7.A3@45.275,179.775 45.275,180.894 R30.1@45.281,180.9 45.281,181.293 44.783,181.791 43.944,181.791 43.116,180.963 43.116,179.184 42.659,178.727 42.659,173.764 42.83,173.594 42.83,168.368 47.793,163.405 U35_I2C_Expander_PWR_Dist.27@47.793,162.178
RAM_DDR4_VTT: C722.2 C723.2 R31.2 R32.2 R33.2 R34.2 R35.2 R36.2 R37.2 R38.2 R39.2 R40.2 R41.2 R42.2 R43.2 R44.2 R45.2 R46.2 R47.2 R48.2 R49.2 R50.2 R51.2 R53.2 R55.2 R57.2 R59.2 R689.1 U73.8 | length 34.8
  L1 w0.25: v1(156.593,333.611) R46.2@157.837,333.611 ; v1(156.593,334.7) R59.2@157.837,334.7 ; v1(156.593,335.789) R51.2@157.837,335.789 ; v1(156.593,336.878) R57.2@157.837,336.878 ; v1(156.593,337.967) R37.2@157.837,337.967 ; v1(156.593,339.056) R34.2@157.837,339.055 ; v1(156.593,340.144) R33.2@157.837,340.144 ; v1(156.593,341.233) R41.2@157.837,341.233 ; v1(156.593,342.322) R48.2@157.837,342.322 ; v1(156.593,343.411) R45.2@157.837,343.411 ; v1(156.593,344.5) R53.2@157.837,344.5 ; R38.2@162.769,345.7 v1(162.769,346.944) ; R44.2@163.977,345.7 v1(163.977,346.944) ; R55.2@165.186,345.7 v1(165.186,346.944) ; R40.2@166.395,345.7 v1(166.395,346.944) ; R36.2@167.603,345.7 v1(167.603,346.944) ; R49.2@168.812,345.7 v1(168.812,346.944) ; R32.2@170.02,345.7 v1(170.02,346.944) ; R39.2@171.229,345.7 v1(171.229,346.944) ; R42.2@172.438,345.7 v1(172.438,346.944) ; R35.2@173.646,345.7 v1(173.646,346.944) ; R31.2@174.855,345.7 v1(174.855,346.944) ; R50.2@176.063,345.7 v1(176.063,346.944) ; R47.2@177.272,345.7 v1(177.272,346.944) ; R43.2@178.481,345.7 v1(178.481,346.944)
  L1 w0.3: U73.8@151.644,349.985 v1(152.387,349.985) ; C722.2@153.683,349.532 v1(153.683,350.275) ; C723.2@154.673,349.532 v1(154.673,350.275) ; v1(158.909,347.162) 159.652,347.162 ; R689.1@160.795,347.112 v1(161.538,347.112)
RAM_Vcc1V2: C36.2 C220.1 C222.1 C223.2 C224.2 C225.2 C226.2 C227.2 C228.2 C229.2 C230.2 C231.2 C232.2 C233.2 C234.2 C235.2 C236.2 C237.2 C238.2 C239.2 C240.2 C241.2 C242.2 C244.1 C246.1 C247.2 C248.2 C249.2 C250.2 C251.2 C252.2 C253.2 C254.2 C255.2 C256.2 C257.2 C258.2 C259.2 C260.2 C261.2 C262.2 C263.2 C264.2 C265.2 C266.2 C741.2 C760.1 C761.2 R58.2 R165.2 R166.2 R169.2 R171.2 R297.2 R448_U_Pomiar_pradu_napiecia_4.2 R695.1 U1.A6 U1.B8 U1.C6 U1.D8 U1.E6 U1.G6 U1.J6 U1.L6 U1.M25 U1.N6 U1.R6 U1.T18 U1.T20 U1.T21 U1.U6 U8.A1 U8.A6 U8.B3 U8.B6 U8.C1 U8.D1 U8.D6 U8.F2 U8.F5 U8.G1 U8.G4 U8.G6 U8.J1 U8.J2 U8.J5 U8.J6 U8.L1 U8.L6 U8.R1 U8.T6 U9.A1 U9.A6 U9.B3 U9.B6 U9.C1 U9.D1 U9.D6 U9.F2 U9.F5 U9.G1 U9.G4 U9.G6 U9.J1 U9.J2 U9.J5 U9.J6 U9.L1 U9.L6 U9.R1 U9.T6 U10.A1 U10.A6 U10.B3 U10.B6 U10.C1 U10.D1 U10.D6 U10.F2 U10.F5 U10.G1 U10.G4 U10.G6 U10.J1 U10.J2 U10.J5 U10.J6 U10.L1 U10.L6 U10.R1 U10.T6 U11.A1 U11.A6 U11.B3 U11.B6 U11.C1 U11.D1 U11.D6 U11.F2 U11.F5 U11.G1 U11.G4 U11.G6 U11.J1 U11.J2 U11.J5 U11.J6 U11.L1 U11.L6 U11.R1 U11.T6 U64_U_Pomiar_pradu_napiecia_4.8 U64_U_Pomiar_pradu_napiecia_4.9 | length 89
  L1 w0.2: v2(189.4,334.057) v2@189.4,334.064 ; v1(198.412,328.613) 198.964,328.06 U8.A6@200.457,328.06 ; v1(199.479,328.887) 200.43,328.887 U8.B6@200.457,328.86 ; v1(199.657,330.225) 199.892,330.46 U8.D6@200.457,330.46 ; U8.G4@202.057,332.86 202.215,332.702 v2(202.757,332.702) ; U8.J2@206.057,334.46 206.18,334.337 206.734,334.337 U8.J1@206.857,334.46 v2(207.261,334.864) ; U8.A1@206.857,328.06 v2(207.785,328.06) ; U8.C1@206.857,329.66 v2(207.785,329.66) ; U8.D1@206.857,330.46 v2(207.785,330.46) ; U8.G1@206.857,332.86 v2(207.428,332.86) ; U8.L1@206.857,336.06 v2(207.261,336.464) ; U8.R1@206.857,339.26 v2(207.261,339.664)
  L1 w0.25: v1(154.724,331.965) C36.2@155.566,331.965 ; v1(161.216,339.242) R58.2@162.46,339.242 ; v2(165.672,328.464) U9.A6@166.076,328.06 ; v2(165.672,329.264) U9.B6@166.076,328.86 ; v2(165.672,330.064) 166.076,329.66 ; v2(165.672,330.864) U9.D6@166.076,330.46 ; v2(165.672,331.664) 166.076,331.26 ; v2(165.672,333.264) U9.G6@166.076,332.86 ; v2(165.672,334.864) U9.J6@166.076,334.46 U9.J5@166.876,334.46 ; v2(165.672,336.464) U9.L6@166.076,336.06 ; v2(165.672,337.264) 166.076,336.86 ; v2(165.672,339.664) 166.076,339.26 ; v2(165.672,340.464) U9.T6@166.076,340.06 ; v2(166.472,330.864) 166.876,330.46 ; v2(166.472,331.664) 166.876,331.26 ; v2(166.472,332.457) 166.876,332.86 ; U9.F5@166.876,332.06 v2(167.279,332.464) ; v2(167.272,333.264) U9.G4@167.676,332.86 ; v2(170.472,328.457) U9.B3@170.876,328.86 ; v2(171.272,334.057) U9.J2@171.676,334.46 ; U9.F2@171.676,332.06 172.876,333.261 v2(172.923,333.261) ; U9.A1@172.476,328.06 v2(172.879,327.657) ; U9.C1@172.476,329.66 v2(172.879,329.257) ; U9.D1@172.476,330.46 v2(172.879,330.057) ; U9.J1@172.476,334.46 v2(172.879,334.864) ; v2(176.95,336.055) U11.L6@177.521,336.055 ; v2(177.133,327.657) U11.A6@177.536,328.06 ; v2(177.133,328.457) U11.B6@177.536,328.86 ; v2(177.133,330.057) U11.D6@177.536,330.46 ; v2(177.133,332.457) U11.G6@177.536,332.86 ; v2(177.133,334.057) U11.J6@177.536,334.46 ; v2(177.133,340.464) U11.T6@177.536,340.06 ; v2(177.933,331.657) U11.F5@178.336,332.06 ; v2(177.933,334.057) U11.J5@178.336,334.46 ; U11.G4@179.136,332.86 v2(179.54,332.457) ; v2(181.933,328.457) U11.B3@182.336,328.86 ; v2(182.733,331.657) U11.F2@183.136,332.06 ; v2(182.733,334.057) U11.J2@183.136,334.46 ; 183.451,345.211 v2(183.855,345.615) ; U11.A1@183.936,328.06 v2(184.507,328.06) ; U11.C1@183.936,329.66 v2(184.507,329.66) ; U11.D1@183.936,330.46 v2(184.507,330.46) ; U11.G1@183.936,332.86 v2(184.507,332.86) ; U11.J1@183.936,334.46 v2(184.34,334.864) ; U11.L1@183.936,336.06 v2(184.34,335.657) ; v2(188.593,327.657) U10.A6@188.997,328.06 ; v2(188.593,328.457) U10.B6@188.997,328.86 ; v2(188.593,330.864) U10.D6@188.997,330.46 ; v2(188.593,336.464) U10.L6@188.997,336.06 ; v2(188.593,340.464) U10.T6@188.997,340.06 ; U10.J6@188.997,334.46 v2(189.4,334.057) ; v2(189.393,332.464) U10.F5@189.797,332.06 ; v2@189.4,334.064 U10.J5@189.797,334.46 ; U10.G4@190.597,332.86 v2(191,332.457) ; U10.F2@194.597,332.06 U10.G1@195.397,332.86 ; U8.B3@205.257,328.86 v2(205.661,328.457)
  L1 w0.254: v1(198.031,332.524) 200.121,332.524 U8.G6@200.457,332.86 U8.F5@201.257,332.06 ; 200.203,341.884 200.457,341.63 U8.T6@200.457,340.06 ; U8.L6@200.457,336.06 199.439,336.06 198.847,335.469 v1(198.847,334.75) 199.326,334.75 199.615,334.46 U8.J6@200.457,334.46 200.727,334.73 200.987,334.73 U8.J5@201.257,334.46 ; U8.F2@206.057,332.06 U8.G1@206.857,332.86
  L1 w0.3: v1(193.116,328.384) 193.32,328.384 U10.B3@193.797,328.86 ; U10.J2@194.597,334.46 195.008,334.049 U10.J1@195.397,334.46 195.644,334.213 v1(195.77,334.213) ; U10.A1@195.397,328.06 196.956,328.06 v1(198.022,329.127) ; U10.C1@195.397,329.66 195.643,329.66 196.494,330.512 v1(196.494,331.178) 196.114,331.178 U10.D1@195.397,330.46 ; U10.G1@195.397,332.86 195.441,332.816 195.791,332.816 196.812,331.795 v1(196.812,331.762) ; U10.L1@195.397,336.06 196.172,336.06 197.039,336.927 v4(197.039,340.639) ; U10.R1@195.397,339.26 195.988,339.852 v4(196.026,339.852)
  L9 (PWR/GND) w0.254: v5(173.397,312.539) 173.901,312.035 173.901,311.315 174.18,311.036 174.587,311.036 174.892,310.731 174.892,309.26 175.173,308.978 176.958,308.978
  L3 (Sign) w0.3: v1(194.323,342.976) 194.694,342.605 194.694,341.572 195.22,341.046 195.567,341.046 196.026,340.587 v4@196.026,339.831 ; v1(195.568,341.757) 196.748,341.757 197.104,341.401 197.039,341.336 v4(197.039,340.639)
  L16 w0.2: v1@199.452,328.887 v1(199.479,328.887)
  L16 w0.254: v1(198.847,334.75) v1@198.897,334.75
  L16 w0.3: v1@193.116,328.325 v1(193.116,328.384)
  other v2: 162.397,293.539 164.397,293.539 166.397,293.539 168.397,293.539 170.397,293.539 172.397,293.539 174.397,293.539 176.397,293.539 178.397,293.539 163.397,295.539 165.397,295.539
  other v5: 177.397,305.539 177.397,307.539 177.397,308.539
  other v6: 112.047,170.186 110.249,170.206 108.45,170.226 104.854,170.267 106.652,170.246 103.056,170.287 101.258,170.307 111.158,171.095 109.36,171.115 105.763,171.156 107.561,171.135 103.965,171.176 102.167,171.196
RAM_VrefA: C221.1 R166.1 R168.1 U8.M1 | length 0.6
  L1 w0.2: U8.M1@206.857,336.86 v2(207.261,337.264)
RAM_VrefB: C243.1 R169.1 R170.1 U10.M1 | length 7.8
  L1 w0.2: v4(193.786,341.617) 194.952,341.617 196.417,340.153 196.417,337.357 195.92,336.86 U10.M1@195.397,336.86
  L3 (Sign) w0.2: v4(193.786,341.617) 193.786,342.141
RAM_VrefC: C219.1 R165.1 R167.1 U9.M1
RAM_VrefD: C245.1 R171.1 R172.1 U11.M1 | length 0.6
  L1 w0.25: U11.M1@183.936,336.86 v2(184.34,337.264)
RefClk_Si53323_N: R253.1 R255.2 U31.7
RefClk_Si53323_P: C341.2 R252.1 R254.2 U31.6
RESET_N: R712.1 R713.2 U39.43 | length 1.2
  L16 w0.12: U39.43@108.049,275.125 108.049,274.309 v1(108.344,274.015)
RESETB: U45.27 U74.4
RST_brigde: R757.1 U3_I2C_Bridge_SFP.24 U35_I2C_Expander_Main_Rst.1
SD_Card_CLK: J28.5 U47.C5 | length 6.8
  L16 w0.098: J28.5@127.237,335.032 130.228,335.032 130.6,335.404 U47.C5@133.927,335.404
SD_Card_en: R382.1 U47.C2
Sel_CLK_R: R900.1 U1.K12 | length 70.7
  L1 w0.116: v4(170.909,300.027) U1.K12@171.397,299.539
  L3 (Sign) w0.12: v1(113.661,293.675) 115.575,291.761 115.575,289.172 120.439,284.308 146.603,284.308 157.87,295.575 157.87,297.106 159.858,299.094 169.977,299.094 v4(170.909,300.027)
SetClk_Si53323_2: R900.2 T36.1
SFP0_ABS: J32.6 R65.1 | length 4.4
  L1 w0.12: R65.1@54.779,285.118 v3(55.639,285.118)
  L16 w0.12: v3(55.639,285.118) 56.31,284.447 J32.6@58.904,284.447
SFP0_LOS: J32.8 R66.1 U35_I2C_Expander_SFP.4 | length 34.3
  L1 w0.12: U35_I2C_Expander_SFP.4@39.827,309.578 39.84,309.566 39.84,308.496 v10(39.853,308.483) ; R66.1@54.779,286.047 v3(55.639,286.047)
  L3 (Sign) w0.12: v10(39.853,308.483) 39.853,301.672 55.405,286.119 55.566,286.119 v3(55.639,286.047)
  L16 w0.12: v3(55.639,286.047) J32.8@58.904,286.047
SFP0_RS0: J32.7 R72.1 R74.2
SFP0_RS1: J32.9 R71.1 R73.2
SFP0_Rx_N: J32.19 U1.D5 | length 109
  L14 (Sign) w0.076: 165.112,287.487 ccw(c165.059,287.487) 165.059,287.539 165.059,292.771 cw(c165.24,292.771) 165.24,292.951 cw(c165.24,292.794) 165.397,292.794 v2(165.397,292.539)
  L14 (Sign) w0.08: v9(76.759,284.447) cw(c76.869,284.447) 76.869,284.557 163.792,284.557 ccw(c163.792,285.877) 165.112,285.877 165.112,287.487
  L16 w0.081: J32.19@67.104,280.847 68.038,280.847 ccw(c68.038,280.954) 68.145,280.954 73.081,280.954 ccw(c73.081,282.765) 74.893,282.765 74.893,283.732 cw(c75.616,283.732) 75.616,284.455 76.759,284.455 v9(76.759,284.447)
SFP0_Rx_P: J32.18 U1.D6 | length 108.8
  L14 (Sign) w0.076: 164.732,287.487 cw(c164.784,287.487) 164.784,287.539 164.784,292.771 cw(c165.24,292.771) 165.24,293.227 ccw(c165.24,293.384) 165.397,293.384 v2(165.397,293.539)
  L14 (Sign) w0.08: v9(76.759,285.047) ccw(c76.869,285.047) 76.869,284.937 163.792,284.937 ccw(c163.792,285.877) 164.732,285.877 164.732,287.487
  L16 w0.081: J32.18@67.104,281.647 68.038,281.647 cw(c68.038,281.539) 68.145,281.539 73.081,281.539 ccw(c73.081,282.765) 74.308,282.765 74.308,283.732 cw(c75.616,283.732) 75.616,285.04 76.759,285.04 v9(76.759,285.047)
SFP0_Tx_N: J32.12 U1.D1 | length 113
  L14 (Sign) w0.076: v2(165.397,288.539) 165.397,288.754 cw(c165.544,288.754) 165.544,288.902 165.568,288.902 cw(c165.568,288.722) 165.748,288.722 165.748,287.539 ccw(c165.748,287.487) 165.696,287.487
  L14 (Sign) w0.08: v9(69.139,286.347) ccw(c69.249,286.347) 69.249,286.237 72.056,286.237 cw(c72.056,284.404) 73.889,284.404 73.889,283.844 ccw(c74.562,283.844) 74.562,283.171 130.962,283.171 cw(c130.962,281.825) 132.309,281.825 132.309,280.365 ccw(c133.274,280.365) 133.274,279.4 164.313,279.4 ccw(c164.313,280.783) 165.696,280.783 165.696,287.487
  L16 w0.081: J32.12@67.104,286.447 68.038,286.447 cw(c68.038,286.339) 68.145,286.339 69.139,286.339 v9(69.139,286.347)
SFP0_Tx_P: J32.13 U1.D2 | length 114
  L14 (Sign) w0.076: v2(165.397,289.539) 165.397,289.325 ccw(c165.544,289.325) 165.544,289.177 165.568,289.177 cw(c165.568,288.722) 166.023,288.722 166.023,287.539 cw(c166.023,287.487) 166.075,287.487
  L14 (Sign) w0.08: v9(69.139,285.747) cw(c69.249,285.747) 69.249,285.857 72.056,285.857 cw(c72.056,284.404) 73.509,284.404 73.509,283.844 ccw(c74.562,283.844) 74.562,282.791 130.962,282.791 cw(c130.962,281.825) 131.929,281.825 131.929,280.365 ccw(c133.274,280.365) 133.274,279.02 164.313,279.02 ccw(c164.313,280.783) 166.075,280.783 166.075,287.487
  L16 w0.081: J32.13@67.104,285.647 68.038,285.647 ccw(c68.038,285.754) 68.145,285.754 69.139,285.754 v9(69.139,285.747)
SFP0_TxDis: J32.3 R68.1 U35_I2C_Expander_SFP.3 | length 37.3
  L1 w0.12: v10(39.177,308.496) U35_I2C_Expander_SFP.3@39.177,309.578 ; R68.1@54.779,284.205 v3(55.639,284.205)
  L3 (Sign) w0.12: v10(39.177,308.496) 39.177,301.825 54.097,286.905 54.097,285.747 v3(55.639,284.205)
  L16 w0.12: v3(55.639,284.205) 56.718,283.126 56.718,282.997 57.668,282.047 J32.3@58.904,282.047
SFP0_TxF: J32.2 R67.1 U35_I2C_Expander_SFP.2 | length 38.4
  L1 w0.12: v10(38.527,308.483) U35_I2C_Expander_SFP.2@38.527,309.578 ; R67.1@54.779,283.247 54.794,283.261 v3(55.639,283.261)
  L3 (Sign) w0.12: v10(38.527,308.483) 38.527,301.317 53.451,286.393 53.451,285.448 v3(55.639,283.261)
  L16 w0.12: v3(55.639,283.261) 57.653,281.247 J32.2@58.904,281.247
SFP0_VccR: C37.2 C38.1 J32.15 L1.2
SFP0_VccT: C39.2 C40.1 J32.16 L2.2
SFP1_ABS: J33.6 R135.1 | length 4.4
  L1 w0.12: R135.1@54.767,313.497 v3(55.702,313.497)
  L16 w0.12: v3(55.702,313.497) 56.252,312.947 J33.6@58.904,312.947
SFP1_LOS: J33.8 R136.1 U35_I2C_Expander_SFP.24 | length 30.3
  L1 w0.12: v10(35.903,313.131) 35.917,313.117 36.938,313.117 U35_I2C_Expander_SFP.24@36.952,313.103 ; R136.1@54.776,314.403 v3(55.702,314.403)
  L3 (Sign) w0.12: v10(35.903,313.131) 35.348,313.686 35.348,314.633 38.824,318.11 50.96,318.11 54.666,314.403 v3(55.702,314.403)
  L16 w0.12: v3(55.702,314.403) 58.761,314.403 J33.8@58.904,314.547
SFP1_RS0: J33.7 R142.1 R144.2
SFP1_RS1: J33.9 R141.1 R143.2
SFP1_Rx_N: J33.19 U1.C7 | length 129
  L14 (Sign) w0.076: 161.345,295.858 ccw(c161.345,295.91) 161.397,295.91 163.512,295.91 cw(c163.512,295.678) 163.745,295.678 163.745,295.266 ccw(c164.109,295.266) 164.109,294.902 cw(c164.109,294.614) 164.397,294.614 v2(164.397,294.539)
  L14 (Sign) w0.08: v9(62.509,315.141) cw(c62.619,315.141) 62.619,315.251 114.452,315.251 cw(c114.452,312.711) 116.992,312.711 116.992,312.477 ccw(c119.912,312.477) 119.912,309.557 148.438,309.557 149.282,309.557 cw(c149.282,308.559) 150.279,308.559 150.279,296.761 ccw(c151.182,296.761) 151.182,295.858 153.379,295.858 161.345,295.858
  L16 w0.081: v9(62.509,315.141) 62.509,315.15 63.335,315.15 cw(c63.335,314.639) 63.846,314.639 63.846,310.325 ccw(c64.714,310.325) 64.714,309.456 66.064,309.456 ccw(c66.173,309.456) 66.173,309.347 J33.19@67.104,309.347
SFP1_Rx_P: J33.18 U1.C8 | length 129
  L14 (Sign) w0.076: 161.345,296.238 cw(c161.345,296.186) 161.397,296.186 163.512,296.186 cw(c163.512,295.678) 164.02,295.678 164.02,295.266 ccw(c164.109,295.266) 164.109,295.177 ccw(c164.109,295.465) 164.397,295.465 v2(164.397,295.539)
  L14 (Sign) w0.08: v9(62.509,315.741) ccw(c62.619,315.741) 62.619,315.631 114.452,315.631 cw(c114.452,312.711) 117.372,312.711 117.372,312.477 ccw(c119.912,312.477) 119.912,309.937 148.438,309.937 149.282,309.937 cw(c149.282,308.559) 150.659,308.559 150.659,296.761 ccw(c151.182,296.761) 151.182,296.238 153.379,296.238 161.345,296.238
  L16 w0.081: v9(62.509,315.741) 62.509,315.732 63.335,315.732 cw(c63.335,314.639) 64.427,314.639 64.427,310.325 ccw(c64.714,310.325) 64.714,310.037 66.064,310.037 cw(c66.173,310.037) 66.173,310.147 J33.18@67.104,310.147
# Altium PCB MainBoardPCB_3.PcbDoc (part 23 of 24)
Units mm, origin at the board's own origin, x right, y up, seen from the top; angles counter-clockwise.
Board outline 258.95 x 308.86 mm, 16 copper layers (L1, L2 (GND), L3 (Sign), L4 (GND), L5 (Sign), L6 (PWR/GND), L7(PWR/GND), L8 (Plane_GND), L9 (PWR/GND), L10 (PWR/GND), L11 (PWR/GND), L12 (Sign), L13 (GND), L14 (Sign), L15 (GND), L16), stack 2.502 mm thick; 2402 components, 1749 nets, 8407 pads, 3409 vias.
Unrouted connection lines stored in the file: 4352.

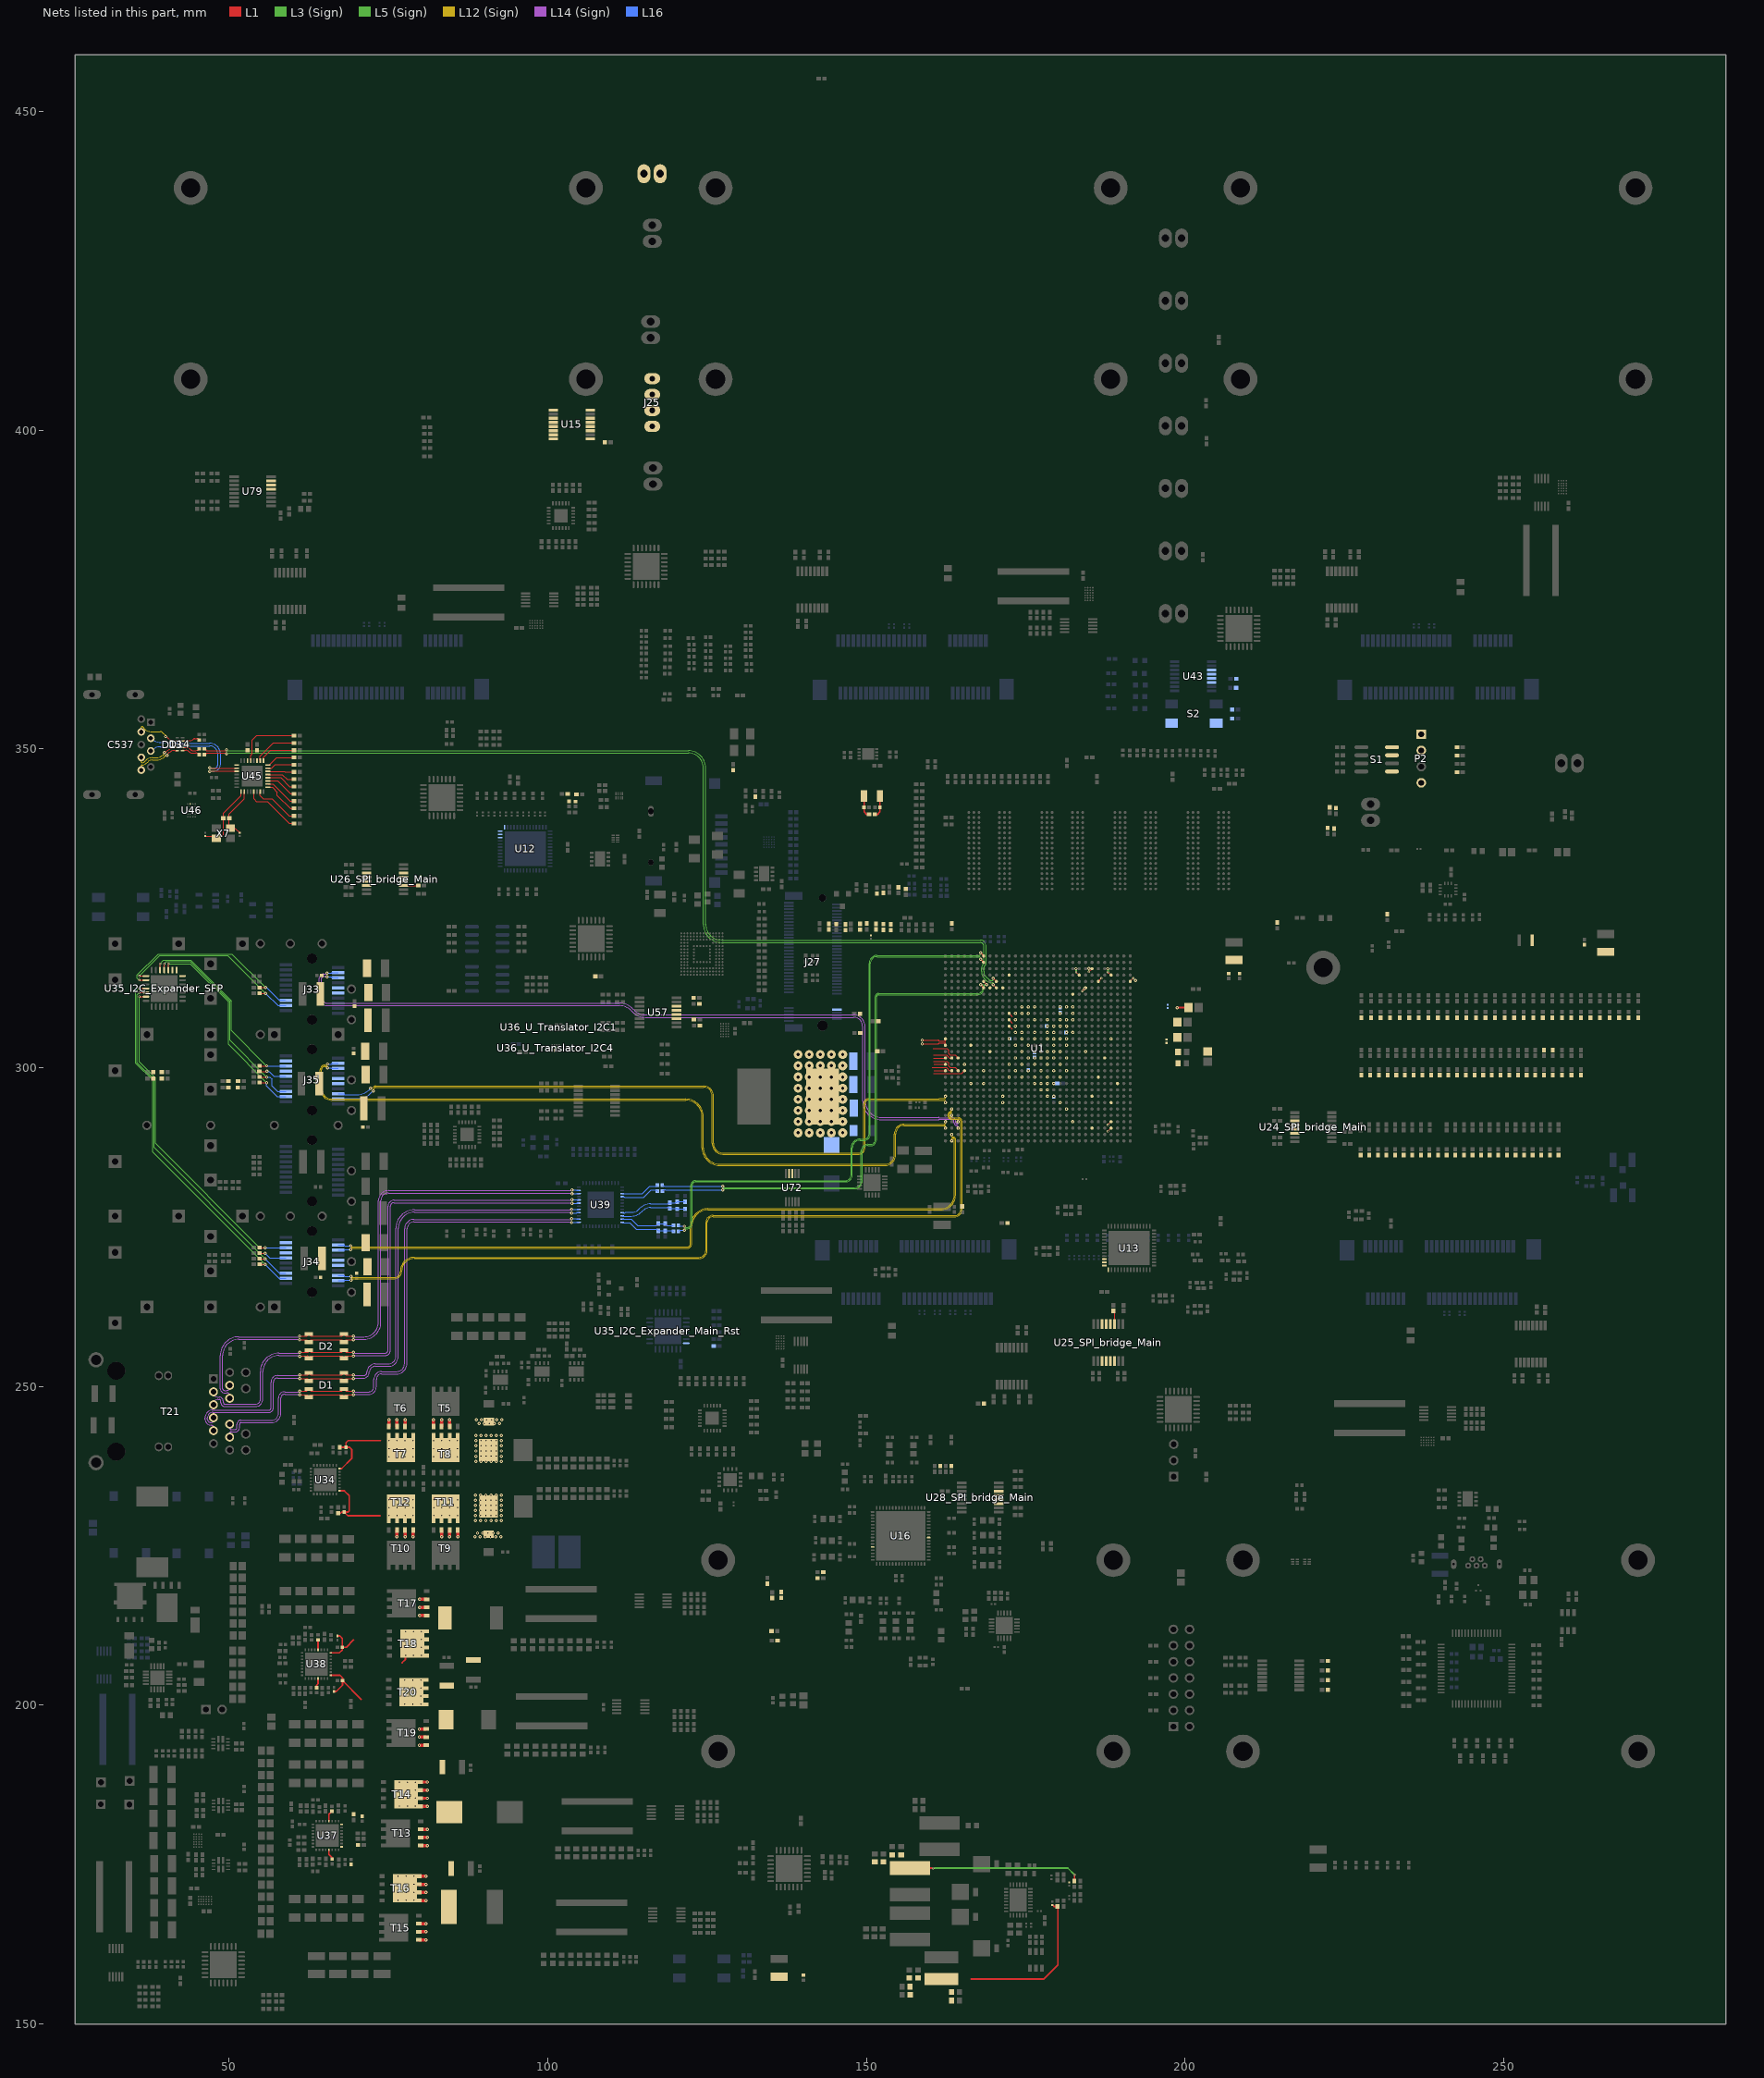
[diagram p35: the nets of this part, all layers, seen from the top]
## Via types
v1: diameter 0.5, hole 0.2, L1 to L16, tented both sides, 1267 vias
v2: diameter 0.5/0.35/0.35/0.35/0.35/0.35/0.35/0.35/0.35/0.35/0.35/0.35/0.35/0.35/0.35/0.5 (per signal layer), hole 0.15, L1 to L16, tented both sides, 463 vias
v3: diameter 0.5, hole 0.2, L1 to L16, 446 vias
v4: diameter 0.35/0/0.35 (per signal layer), hole 0.127, L1 to L3 (Sign), tented both sides, 347 vias
v5: diameter 0.5/0.35/0.35/0.35/0.35/0.35/0.35/0.35/0.35/0.35/0.35/0.35/0.35/0.35/0.35/0.5 (per signal layer), hole 0.2, L1 to L16, tented both sides, 244 vias
v6: diameter 0.8, hole 0.4, L1 to L16, tented both sides, 168 vias
v7: diameter 2.54, hole 1.02, L1 to L16, 113 vias
v8: diameter 1.4, hole 0.5, L1 to L16, tented both sides, 80 vias
v9: diameter 0.5/0/0.5 (per signal layer), hole 0.2, L14 (Sign) to L16, tented both sides, 62 vias
v10: diameter 0.35/0/0.35 (per signal layer), hole 0.127, L1 to L3 (Sign), 38 vias
v11: diameter 0.35, hole 0.127, L1 to L2 (GND), tented both sides, 36 vias
v12: diameter 0.4, hole 0.2, L1 to L16, 16 vias
v13: diameter 0.25, hole 0.2, L1 to L16, 16 vias
v14: diameter 0.35, hole 0.127, L1 to L16, tented both sides, 16 vias
v15: diameter 0.3, hole 0.2, L1 to L16, 15 vias
v16: diameter 0.45, hole 0.15, L1 to L16, 12 vias
v17: diameter 0.5/0.35/0.35/0.35/0.35/0.35/0.35/0.35/0.35/0.35/0.35/0.35/0.35/0.35/0.35/0.45 (per signal layer), hole 0.15, L1 to L16, tented both sides, 10 vias
v18: diameter 0.2/0/0.2 (per signal layer), hole 0.1, L1 to L3 (Sign), tented both sides, 9 vias
v19: diameter 0.4, hole 0.1, L1 to L16, 7 vias
v20: diameter 0.5, hole 0.2, L3 (Sign) to L6 (PWR/GND), tented both sides, 6 vias
v21: diameter 1.15, hole 1.15, L1 to L16, 5 vias
v22: diameter 1.65, hole 1.65, L1 to L16, 5 vias
v23: diameter 0.35/0/0.35 (per signal layer), hole 0.127, L14 (Sign) to L16, tented both sides, 5 vias
v24: diameter 0.5, hole 0.2, L11 (PWR/GND) to L14 (Sign), tented both sides, 4 vias
v25: diameter 0.2, hole 0.1, L1 to L16, 4 vias
v26: diameter 0.35, hole 0.127, L1 to L2 (GND), 2 vias
v27: diameter 0.4, hole 0.15, L1 to L16, 2 vias
v28: diameter 0.4, hole 0.2, L1 to L16, tented both sides, 2 vias
v29: diameter 0.5/0.35/0.35/0.35/0.35/0.35/0.35/0.35/0.35/0.35/0.35/0.35/0.35/0.35/0.35/0.5 (per signal layer), hole 0.15, L1 to L16, 2 vias
v30: diameter 0.35, hole 0.127, L3 (Sign) to L6 (PWR/GND), tented both sides, 2 vias
v31: diameter 0.5/0.35/0.35/0.35/0.35/0.35/0.35/0.35/0.35/0.35/0.35/0.35/0.35/0.35/0.35/0.5 (per signal layer), hole 0.2, L1 to L16, 1 vias
v32: diameter 0.35/0.35/0.35 (per signal layer), hole 0.127, L1 to L3 (Sign), tented both sides, 1 vias
v33: diameter 0.45/0/0.45 (per signal layer), hole 0.15, L1 to L3 (Sign), tented both sides, 1 vias
v34: diameter 0.45/0/0.45 (per signal layer), hole 0.2, L14 (Sign) to L16, tented both sides, 1 vias
v35: diameter 0.35, hole 0.127, L2 (GND) to L3 (Sign), 1 vias

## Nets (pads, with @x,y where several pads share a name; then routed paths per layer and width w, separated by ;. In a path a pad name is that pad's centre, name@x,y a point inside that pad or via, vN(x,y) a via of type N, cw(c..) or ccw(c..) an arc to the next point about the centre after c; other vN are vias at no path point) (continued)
SFP1_Tx_N: J33.12 U1.C3 | length 123.1
  L14 (Sign) w0.076: 161.345,291.845 ccw(c161.345,291.897) 161.397,291.897 163.402,291.897 cw(c163.402,291.554) 163.745,291.554 163.745,291.431 ccw(c164.274,291.431) 164.274,290.902 cw(c164.274,290.779) 164.397,290.779 v2(164.397,290.539)
  L14 (Sign) w0.08: v9(65.354,314.847) cw(c65.244,314.847) 65.244,314.737 64.859,314.737 ccw(c64.859,314.026) 64.149,314.026 64.149,311.074 ccw(c65.481,311.074) 65.481,309.741 111.278,309.741 cw(c111.278,307.201) 113.074,308.998 113.312,308.76 ccw(c115.329,310.777) 115.329,307.924 147.968,307.924 cw(c147.968,306.475) 149.417,306.475 149.417,294.765 ccw(c152.337,294.765) 152.337,291.845 161.345,291.845
  L16 w0.081: v9(65.354,314.847) 65.354,314.837 66.064,314.837 cw(c66.173,314.837) 66.173,314.947 J33.12@67.104,314.947
SFP1_Tx_P: J33.13 U1.C4 | length 121.9
  L14 (Sign) w0.076: 161.345,292.225 cw(c161.345,292.172) 161.397,292.172 163.402,292.172 cw(c163.402,291.554) 164.02,291.554 164.02,291.431 ccw(c164.274,291.431) 164.274,291.177 ccw(c164.274,291.3) 164.397,291.3 v2(164.397,291.539)
  L14 (Sign) w0.08: v9(65.354,314.247) ccw(c65.244,314.247) 65.244,314.357 64.859,314.357 ccw(c64.859,314.026) 64.529,314.026 64.529,311.074 ccw(c65.481,311.074) 65.481,310.121 111.279,310.121 cw(c111.279,307.203) 113.342,309.267 113.578,309.031 ccw(c115.333,310.786) 115.333,308.304 147.968,308.304 cw(c147.968,306.475) 149.796,306.475 149.796,294.765 ccw(c152.337,294.765) 152.337,292.225 161.345,292.225
  L16 w0.081: v9(65.354,314.247) 65.354,314.256 66.064,314.256 ccw(c66.173,314.256) 66.173,314.147 J33.13@67.104,314.147
SFP1_TxDis: J33.3 R138.1 U35_I2C_Expander_SFP.23 | length 30.6
  L1 w0.12: v10(35.903,313.747) 35.906,313.75 36.949,313.75 U35_I2C_Expander_SFP.23@36.952,313.753 ; R138.1@54.779,312.59 v3(55.702,312.59)
  L3 (Sign) w0.12: v10(35.903,313.747) 35.568,314.082 35.568,314.542 38.882,317.857 50.436,317.857 v3(55.702,312.59)
  L16 w0.12: v3(55.702,312.59) 55.775,312.517 55.948,312.517 57.795,310.671 58.78,310.671 J33.3@58.904,310.547
SFP1_TxF: J33.2 R137.1 U35_I2C_Expander_SFP.22 | length 29.6
  L1 w0.12: v10(35.903,314.403) U35_I2C_Expander_SFP.22@36.952,314.403 ; R137.1@54.779,311.684 v3(55.702,311.684)
  L3 (Sign) w0.12: v10(35.903,314.403) 39.114,317.614 49.772,317.614 v3(55.702,311.684)
  L16 w0.12: v3(55.702,311.684) 55.712,311.684 57.655,309.741 58.899,309.741 J33.2@58.904,309.747
SFP1_VccR: C207.2 C208.1 J33.15 L3.2
SFP1_VccT: C209.2 C210.1 J33.16 L4.2
SFP2_ABS: J34.6 R145.1 | length 4.4
  L1 w0.12: R145.1@54.794,270.912 v3(55.639,270.912)
  L16 w0.12: v3(55.639,270.912) 56.355,270.197 J34.6@58.904,270.197
SFP2_LOS: J34.8 R146.1 U35_I2C_Expander_SFP.27 | length 53.2
  L1 w0.12: v10(35.903,311.153) U35_I2C_Expander_SFP.27@36.952,311.153 ; R146.1@54.794,271.797 v3(55.639,271.797)
  L3 (Sign) w0.12: v10(35.903,311.153) 35.903,300.893 38.433,298.362 38.433,288.166 54.803,271.797 v3(55.639,271.797)
  L16 w0.12: v3(55.639,271.797) J34.8@58.904,271.797
SFP2_RS0: J34.7 R152.1 R154.2
SFP2_RS1: J34.9 R151.1 R153.2
SFP2_Rx_N: J34.19 U1.B5 | length 123.6
  L12 (Sign) w0.073: v1(69.113,266.697) cw(c69.314,266.697) 69.314,266.897 75.876,266.897 ccw(c75.876,268.097) 77.076,268.097 cw(c79.048,268.097) 79.048,270.069 123.698,270.069 ccw(c123.698,271.39) 125.019,271.39 125.019,275.73 cw(c125.924,275.73) 125.924,276.635 163.855,276.635 ccw(c163.855,277.787) 165.008,277.787 165.008,287.539 165.008,291.579 ccw(c164.424,291.579) 164.424,292.163 163.258,292.163 cw(c163.258,292.417) 163.005,292.417 163.005,292.647 cw(c163.297,292.647) 163.297,292.939 cw(c163.297,292.839) 163.397,292.839 v2(163.397,292.539)
  L16 w0.081: J34.19@67.104,266.597 68.045,266.597 ccw(c68.045,266.697) 68.145,266.697 v1(69.113,266.697)
SFP2_Rx_P: J34.18 U1.B6 | length 123.6
  L12 (Sign) w0.073: v1(69.113,267.297) ccw(c69.314,267.297) 69.314,267.096 75.876,267.096 ccw(c75.876,268.097) 76.877,268.097 cw(c79.048,268.097) 79.048,270.269 123.698,270.269 ccw(c123.698,271.39) 124.819,271.39 124.819,275.73 cw(c125.924,275.73) 125.924,276.835 163.855,276.835 ccw(c163.855,277.787) 164.808,277.787 164.808,287.539 164.808,291.579 ccw(c164.424,291.579) 164.424,291.964 163.258,291.964 cw(c163.258,292.417) 162.805,292.417 162.805,292.647 cw(c163.297,292.647) 163.297,293.139 ccw(c163.297,293.24) 163.397,293.24 v2(163.397,293.539)
  L16 w0.081: J34.18@67.104,267.397 68.045,267.397 cw(c68.045,267.297) 68.145,267.297 v1(69.113,267.297)
SFP2_Tx_N: J34.12 U1.B1 | length 112.3
  L12 (Sign) w0.073: v1(69.101,272.097) ccw(c69.301,272.097) 69.301,271.896 121.907,271.896 ccw(c121.907,272.395) 122.406,272.395 122.406,275.162 cw(c125.146,275.162) 125.146,277.901 161.684,277.901 ccw(c161.684,280.01) 163.792,280.01 163.792,287.539 163.792,288.724 ccw(c163.576,288.724) 163.576,288.939 163.51,288.939 ccw(c163.51,288.826) 163.397,288.826 v2(163.397,288.539)
  L16 w0.081: J34.12@67.104,272.197 68.038,272.197 cw(c68.038,272.089) 68.145,272.089 69.101,272.089 v1(69.101,272.097)
SFP2_Tx_P: J34.13 U1.B2 | length 112.9
  L12 (Sign) w0.073: v1(69.101,271.497) cw(c69.301,271.497) 69.301,271.697 121.907,271.697 ccw(c121.907,272.395) 122.606,272.395 122.606,275.162 cw(c125.146,275.162) 125.146,277.702 161.684,277.702 ccw(c161.684,280.01) 163.992,280.01 163.992,287.539 163.992,288.724 ccw(c163.576,288.724) 163.576,289.139 163.51,289.139 cw(c163.51,289.252) 163.397,289.252 v2(163.397,289.539)
  L16 w0.081: J34.13@67.104,271.397 68.038,271.397 ccw(c68.038,271.504) 68.145,271.504 69.101,271.504 v1(69.101,271.497)
SFP2_TxDis: J34.3 R148.1 U35_I2C_Expander_SFP.26 | length 56.3
  L1 w0.12: v10(35.903,311.79) 35.909,311.797 36.946,311.797 U35_I2C_Expander_SFP.26@36.952,311.803 ; R148.1@54.794,270.046 v3(55.639,270.046)
  L3 (Sign) w0.12: v10(35.903,311.79) 35.568,311.455 35.568,300.807 38.213,298.161 38.213,287.472 v3(55.639,270.046)
  L16 w0.12: v3(55.639,270.046) 57.888,267.797 J34.3@58.904,267.797
SFP2_TxF: J34.2 R147.1 U35_I2C_Expander_SFP.25 | length 58.1
  L1 w0.12: v10(35.903,312.517) 35.935,312.485 36.92,312.485 U35_I2C_Expander_SFP.25@36.952,312.453 ; R147.1@54.798,269.173 v3(55.639,269.173)
  L3 (Sign) w0.12: v10(35.903,312.517) 35.348,311.962 35.348,300.716 37.993,298.07 37.993,286.818 v3(55.639,269.173)
  L16 w0.12: v3(55.639,269.173) 57.815,266.997 J34.2@58.904,266.997
SFP2_VccR: C211.2 C212.1 J34.15 L5.2
SFP2_VccT: C213.2 C214.1 J34.16 L6.2
SFP3_ABS: J35.6 R155.1 | length 4.5
  L1 w0.12: R155.1@54.767,299.431 55.905,299.431 v3(55.927,299.453)
  L16 w0.12: v3(55.927,299.453) 55.949,299.431 56.298,299.431 57.033,298.697 J35.6@58.904,298.697
SFP3_LOS: J35.8 R156.1 U35_I2C_Expander_SFP.19 | length 31.6
  L1 w0.12: U35_I2C_Expander_SFP.19@39.177,315.328 v10(39.177,316.297) ; R156.1@54.776,300.308 v3(55.905,300.308)
  L3 (Sign) w0.12: v10(39.177,316.297) 39.732,316.852 43.998,316.852 50.344,310.506 50.344,305.87 v3(55.905,300.308)
  L16 w0.12: v3(55.905,300.308) 58.892,300.308 J35.8@58.904,300.297
SFP3_RS0: J35.7 R162.1 R164.2
SFP3_RS1: J35.9 R161.1 R163.2
SFP3_Rx_N: J35.19 U1.A7 | length 113.4
  L12 (Sign) w0.073: v1(72.612,296.361) cw(c73.296,296.361) 72.812,296.844 cw(c73.015,296.642) 73.015,296.928 74.282,296.928 124.496,296.928 cw(c124.496,295.631) 125.793,295.631 125.793,288.154 ccw(c127.495,288.154) 127.495,286.452 148.831,286.452 ccw(c148.831,287.388) 149.767,287.388 149.767,294.373 cw(c150.326,294.373) 150.326,294.932 161.397,294.932 ccw(c161.435,294.932) 161.435,294.894
  L12 (Sign) w0.076: 161.435,294.894 162.255,294.894 cw(c162.255,294.752) 162.397,294.752 v2(162.397,294.539)
  L16 w0.081: J35.19@67.104,295.097 68.037,295.097 ccw(c68.037,295.204) 68.145,295.204 70.152,295.204 ccw(c70.152,298.326) 72.359,296.118 72.602,296.361 v1(72.612,296.361)
SFP3_Rx_P: J35.18 U1.A8 | length 113.1
  L12 (Sign) w0.073: v1(72.188,296.785) ccw(c72.188,297.469) 72.671,296.985 72.673,296.987 cw(c73.013,296.646) 73.013,297.127 74.282,297.127 124.496,297.127 cw(c124.496,295.631) 125.993,295.631 125.993,288.154 ccw(c127.495,288.154) 127.495,286.652 148.831,286.652 ccw(c148.831,287.388) 149.568,287.388 149.568,294.373 cw(c150.326,294.373) 150.326,295.132 161.397,295.132 cw(c161.435,295.132) 161.435,295.17
  L12 (Sign) w0.076: 161.435,295.17 162.255,295.17 ccw(c162.255,295.311) 162.397,295.311 v2(162.397,295.539)
  L16 w0.081: J35.18@67.104,295.897 68.037,295.897 cw(c68.037,295.789) 68.145,295.789 70.15,295.789 ccw(c70.15,298.329) 71.946,296.533 72.188,296.775 v1(72.188,296.785)
SFP3_Tx_N: J35.12 U1.A3 | length 118.7
  L12 (Sign) w0.073: v1(65.443,300.597) cw(c65.243,300.597) 65.243,300.396 64.986,300.396 ccw(c64.986,299.702) 64.291,299.702 64.291,296.777 ccw(c66.171,296.777) 66.171,294.897 121.679,294.897 cw(c121.679,292.357) 124.219,292.357 124.219,287.439 ccw(c126.958,287.439) 126.958,284.7 152.984,284.7 ccw(c152.984,286.296) 154.581,286.296 154.581,289.633 cw(c155.892,289.633) 155.892,290.944 161.397,290.944 162.204,290.944 cw(c162.204,290.752) 162.397,290.752 v2(162.397,290.539)
  L16 w0.081: v1(65.443,300.597) 65.443,300.589 66.064,300.589 cw(c66.171,300.589) 66.171,300.697 J35.12@67.104,300.697
SFP3_Tx_P: J35.13 U1.A4 | length 118.1
  L12 (Sign) w0.073: v1(65.443,299.997) ccw(c65.243,299.997) 65.243,300.197 64.986,300.197 ccw(c64.986,299.702) 64.491,299.702 64.491,296.777 ccw(c66.171,296.777) 66.171,295.097 121.679,295.097 cw(c121.679,292.357) 124.418,292.357 124.418,287.439 ccw(c126.958,287.439) 126.958,284.899 152.984,284.899 ccw(c152.984,286.296) 154.381,286.296 154.381,289.633 cw(c155.892,289.633) 155.892,291.144 161.397,291.144 162.204,291.144 ccw(c162.204,291.337) 162.397,291.337 v2(162.397,291.539)
  L16 w0.081: v1(65.443,299.997) 65.443,300.004 66.064,300.004 ccw(c66.171,300.004) 66.171,299.897 J35.13@67.104,299.897
SFP3_TxDis: J35.3 R158.1 U35_I2C_Expander_SFP.18 | length 33.9
  L1 w0.12: U35_I2C_Expander_SFP.18@39.827,315.328 v10(39.827,316.297) ; R158.1@54.779,298.554 v3(55.905,298.554)
  L3 (Sign) w0.12: v10(39.827,316.297) 40.162,316.632 43.907,316.632 50.124,310.415 50.124,304.336 v3(55.905,298.554)
  L16 w0.12: v3(55.905,298.554) 56.398,298.554 56.718,298.234 56.718,297.155 57.594,296.278 58.886,296.278 J35.3@58.904,296.297
SFP3_TxF: J35.2 R157.1 U35_I2C_Expander_SFP.17 | length 33.3
  L1 w0.12: U35_I2C_Expander_SFP.17@40.477,315.328 v10(40.477,316.297) ; R157.1@54.779,297.677 v3(55.905,297.677)
  L3 (Sign) w0.12: v10(40.477,316.297) 43.931,316.297 49.904,310.324 49.904,303.678 v3(55.905,297.677)
  L16 w0.12: v3(55.905,297.677) 55.905,297.16 57.569,295.497 J35.2@58.904,295.497
SFP3_VccR: C215.2 C216.1 J35.15 L7.2
SFP3_VccT: C217.2 C218.1 J35.16 L8.2
SFP_INT0: R854.2 U35_I2C_Expander_SFP.16
SFP_INT1: R857.2 U35_I2C_Expander_SFP.15
SFP_IO_nReset: R756.1 U35_I2C_Expander_Main_Rst.28 U35_I2C_Expander_SFP.14
SGMI_C_Rx_N: C484.1 U1.G26 | length 81.8
  L1 w0.116: U1.G26@168.397,313.539 v5(168.884,313.052)
  L5 (Sign) w0.073: v1(127.483,280.827) cw(c127.683,280.827) 127.683,281.027 148.16,281.027 ccw(c148.16,282.232) 149.365,282.232 149.365,286.931 cw(c150.219,286.931) 150.219,287.786 150.673,287.786 ccw(c150.673,288.713) 151.6,288.713 151.6,311.154 cw(c151.914,311.154) 151.914,311.467 161.397,311.467 167.411,311.467 ccw(c167.411,312.556) 168.5,312.556 168.5,312.941 cw(c168.612,312.941) 168.612,313.052 v5(168.884,313.052)
  L16 w0.081: C484.1@117.996,280.645 cw(c118.454,280.186) 118.454,280.835 127.483,280.835 v1(127.483,280.827)
SGMI_C_Rx_P: C483.1 U1.G25 | length 81.5
  L1 w0.116: v5(167.909,313.027) U1.G25@168.397,312.539
  L5 (Sign) w0.073: v1(127.483,281.427) ccw(c127.683,281.427) 127.683,281.227 148.16,281.227 ccw(c148.16,282.232) 149.165,282.232 149.165,286.931 cw(c150.219,286.931) 150.219,287.985 150.673,287.985 ccw(c150.673,288.713) 151.4,288.713 151.4,311.154 cw(c151.914,311.154) 151.914,311.667 161.397,311.667 167.411,311.667 ccw(c167.411,312.556) 168.3,312.556 168.3,312.941 ccw(c168.214,312.941) 168.214,313.027 v5(167.909,313.027)
  L16 w0.081: C483.1@117.974,281.61 ccw(c118.432,282.068) 118.432,281.42 127.483,281.42 v1(127.483,281.427)
SGMI_C_Tx_N: C482.1 U1.G29 | length 88.8
  L1 w0.116: v5(167.909,317.027) U1.G29@168.397,316.539
  L5 (Sign) w0.073: v1(121.437,274.543) cw(c121.638,274.543) 121.638,274.743 121.832,274.743 ccw(c121.832,275.577) 122.666,275.577 122.666,281.593 cw(c123.177,281.593) 123.177,282.105 146.732,282.105 ccw(c146.732,283.172) 147.799,283.172 147.799,287.435 cw(c148.984,287.435) 148.984,288.62 149.653,288.62 ccw(c149.653,289.585) 150.618,289.585 150.618,316.357 cw(c151.688,316.357) 151.688,317.427 167.627,317.427 cw(c167.627,317.145) 167.909,317.145 v5(167.909,317.027)
  L16 w0.081: C482.1@120.503,274.345 120.701,274.543 v1(121.437,274.543) v1@121.437,274.55
SGMI_C_Tx_P: C479.1 U1.G30 | length 88.8
  L1 w0.116: v5(167.909,318.027) U1.G30@168.397,317.539
  L5 (Sign) w0.073: v1(121.437,275.143) ccw(c121.638,275.143) 121.638,274.943 121.832,274.943 ccw(c121.832,275.577) 122.466,275.577 122.466,281.593 cw(c123.177,281.593) 123.177,282.305 146.732,282.305 ccw(c146.732,283.172) 147.599,283.172 147.599,287.435 cw(c148.984,287.435) 148.984,288.82 149.653,288.82 ccw(c149.653,289.585) 150.419,289.585 150.419,316.357 cw(c151.689,316.357) 151.689,317.627 167.627,317.627 ccw(c167.627,317.909) 167.909,317.909 v5(167.909,318.027)
  L16 w0.081: C479.1@120.503,275.285 120.645,275.143 v1(121.437,275.143) v1@121.437,275.136
SGMI_CLK_Out_N: R320.1 R321.1 R326.2 U39.34 | length 10.3
  L16 w0.081: U39.34@111.699,276.775 111.742,276.732 113.101,276.732 ccw(c113.101,279.104) 114.778,277.427 114.922,277.571 cw(c116.178,276.316) 116.178,278.091 118.759,278.091 cw(c118.759,277.554) R321.1@119.139,277.934 120.131,277.934 cw(c120.131,277.649) R320.1@120.332,277.851 R326.2@121.539,277.851
SGMI_CLK_Out_P: R319.1 R321.2 R325.2 U39.33 | length 10.4
  L16 w0.081: U39.33@111.699,277.275 111.786,277.189 112.113,277.189 112.242,277.318 113.099,277.318 ccw(c113.099,279.11) 114.366,277.843 114.509,277.985 cw(c116.178,276.316) 116.178,278.677 118.759,278.677 ccw(c118.759,279.214) R321.2@119.139,278.834 119.964,278.834 ccw(c119.964,279.356) R319.1@120.332,278.987 R325.2@121.539,278.987
SGMI_Rx_N: C484.2 U39.28 | length 6.1
  L16 w0.081: U39.28@111.699,279.775 112.007,279.775 112.078,279.705 115.088,279.705 116.218,280.835 117.026,280.835 C484.2@117.216,280.645
SGMI_Rx_P: C483.2 U39.27 | length 6
  L16 w0.081: U39.27@111.699,280.275 112.062,280.275 112.078,280.29 114.846,280.29 115.975,281.42 117.004,281.42 C483.2@117.194,281.61
SGMI_Tx_N: C482.2 R323.1 R328.2 U39.36 | length 8.7
  L16 w0.081: U39.36@111.699,275.775 111.699,275.69 112.892,275.69 113.895,274.687 117.074,274.687 R323.1@117.334,274.427 R328.2@118.427,274.427 119.641,274.427 C482.2@119.723,274.345
SGMI_Tx_P: C479.2 R322.1 R327.2 U39.35 | length 8.7
  L16 w0.081: U39.35@111.699,276.275 113.135,276.275 114.137,275.272 117.035,275.272 R322.1@117.334,275.572 R327.2@118.427,275.572 118.714,275.285 C479.2@119.723,275.285
Si53323_1_Q1_N: C330.1 R249.1 U31.9
Si53323_1_Q1_P: C325.1 R246.2 U31.10
Si53323_1_Q2_LVDS_N: C725.2 R386.2 R387.2 U1.AG3 | length 0.7
  L1 w0.116: v4(187.909,290.052) U1.AG3@188.397,290.539
Si53323_1_Q2_LVDS_P: C724.2 U1.AG4 | length 0.7
  L1 w0.116: v4(187.909,291.052) U1.AG4@188.397,291.539
Si53323_1_Q2_N: R301.1 R385.2 U31.12
Si53323_1_Q2_P: R291.1 R384.2 U31.11
Si53323_2_CLK1_N: C330.2 R245.2 R248.2 R251.2 U32.4
Si53323_2_CLK1_P: C325.2 R245.1 R247.2 R250.2 U32.3
Si53323_2_Q1_N: C44.2 R79.2 U32.10
Si53323_2_Q1_P: C43.2 R76.1 U32.9
Si53323_2_Q2_LVDS_N: C727.2 R486.2 R487.2 U1.A16 | length 4.1
  L1 w0.063: 161.236,303.747 ccw(c161.236,303.908) 161.397,303.908 162.31,303.908 cw(c162.31,303.821) 162.397,303.821 U1.A16@162.397,303.539
  L1 w0.081: v1(158.763,303.739) 158.763,303.747 161.236,303.747
Si53323_2_Q2_LVDS_P: C726.2 U1.A17 | length 4.1
  L1 w0.063: 161.236,304.332 cw(c161.236,304.171) 161.397,304.171 162.31,304.171 ccw(c162.31,304.258) 162.397,304.258 U1.A17@162.397,304.539
  L1 w0.081: v1(158.763,304.339) 158.763,304.332 161.236,304.332
Si53323_2_Q2_N: R483.1 R485.2 U32.12
Si53323_2_Q2_P: R482.1 R484.2 U32.11
SPI1_CLK: J25.1 R803.1 U15.14 U24_SPI_bridge_Main.3 U25_SPI_bridge_Main.3 U26_SPI_bridge_Main.3 U27_SPI_bridge_Main.3 U28_SPI_bridge_Main.3
SPI1_CS: J25.4 R123.1 R124.1 R806.1 U15.11 U24_SPI_bridge_Main.6 U25_SPI_bridge_Main.6 U26_SPI_bridge_Main.6 U27_SPI_bridge_Main.6 U28_SPI_bridge_Main.6
SPI1_MISO: J25.3 R807.1 U15.13 U24_SPI_bridge_Main.4 U25_SPI_bridge_Main.4 U26_SPI_bridge_Main.4 U27_SPI_bridge_Main.4 U28_SPI_bridge_Main.4
SPI1_MOSI: J25.2 R808.1 U15.12 U24_SPI_bridge_Main.5 U25_SPI_bridge_Main.5 U26_SPI_bridge_Main.5 U27_SPI_bridge_Main.5 U28_SPI_bridge_Main.5
SPI_05028_CS: R2.1 R129.1 R912.1 U16.24
SPI_05028_MISO: R1.1 R128.2 R133.1 U16.60
SPI_6952_0_CLK: U12.50 U26_SPI_bridge_Main.14
SPI_6952_0_CS: R236_SPI_bridge_Main.1 U12.1 U26_SPI_bridge_Main.11 | length 2.3
  L1 w0.12: U26_SPI_bridge_Main.11@77.371,328.59 R236_SPI_bridge_Main.1@79.68,328.59
SPI_6952_0_MISO: U12.51 U26_SPI_bridge_Main.13
SPI_6952_0_MOSI: U12.52 U26_SPI_bridge_Main.12
SPI_6952_1_CLK: U13.50 U25_SPI_bridge_Main.14
SPI_6952_1_CS: R233_SPI_bridge_Main.1 U13.1 U25_SPI_bridge_Main.11 | length 2.1
  L1 w0.12: R233_SPI_bridge_Main.1@188.754,261.861 188.948,261.668 U25_SPI_bridge_Main.11@188.948,259.821
SPI_6952_1_MISO: U13.51 U25_SPI_bridge_Main.13
SPI_6952_1_MOSI: U13.52 U25_SPI_bridge_Main.12
SPI_DAC_CS: R238_SPI_bridge_Main.1 U27_SPI_bridge_Main.11 U30.14
SPI_FPGA_CLK: R905.2 U15.3
SPI_FPGA_CLK_R: R905.1 U1.C14 | length 4.9
  L1 w0.116: 163.909,302.027 U1.C14@164.397,301.539
  L1 w0.12: 160.449,303.035 162.617,303.035 162.902,302.75 162.902,302.235 163.111,302.027 163.909,302.027
SPI_FPGA_CS: R365.2 R908.2 U15.6
SPI_FPGA_CS_R: R908.1 U1.A13 | length 1.8
  L1 w0.12: 160.611,300.539 U1.A13@162.397,300.539
SPI_FPGA_MISO: R906.2 U15.4
SPI_FPGA_MISO_R: R906.1 U1.B14 | length 3.1
  L1 w0.116: 162.552,302.027 163.039,301.539 U1.B14@163.397,301.539
  L1 w0.12: 160.533,302.027 162.552,302.027
SPI_FPGA_MOSI: R907.2 U15.5
SPI_FPGA_MOSI_R: R907.1 U1.A14 | length 1.8
  L1 w0.12: 160.569,301.539 U1.A14@162.397,301.539
SPI_FPGA_nOE: R75.2 U15.9
SPI_FPGA_OE_R: R903.1 U1.D12 | length 5
  L1 w0.12: 160.54,299.097 164.954,299.097 U1.D12@165.397,299.539
SS1_1: C639.2 U37.28 | length 1.7
  L1 w0.254: U37.28@65.675,181.817 65.675,182.903 C639.2@66.141,183.369
SS1_2: C647.2 U38.28 | length 1.6
  L1 w0.254: U38.28@63.953,208.714 C647.2@63.953,210.264
SS2_1: C640.2 U37.13 | length 1.6
  L1 w0.254: U37.13@65.675,177.317 65.675,176.584 66.161,176.097 C640.2@66.161,175.893
SS2_2: C648.2 U38.13 | length 1.5
  L1 w0.254: C648.2@63.741,202.763 63.741,203.154 63.953,203.366 U38.13@63.953,204.214
SUSCLK: J27.60
SW1: C346.2 L9.1 R610.2 R613.2 T5.1 T5.2 T5.3 T6.1 T6.2 T6.3 T7.5 T7.6 T7.7 T7.8 T8.5 T8.6 T8.7 T8.8 U34.24 | length 18.8
  L1 w0.254: U34.24@67.322,237.139 67.657,237.139 69.236,238.718 69.236,240.156 68.922,240.47 C346.2@68.336,240.47 ; R610.2@67.378,240.47 C346.2@68.336,240.47 ; 73.8,241.529 68.669,241.529 68.336,241.196 C346.2@68.336,240.47
  L1 w0.5: T6.1@75.072,243.723 v1(75.072,244.81) ; T6.2@76.342,243.723 v1(76.342,244.81) ; T6.3@77.612,243.723 v1(77.612,244.81) ; T5.1@82.072,243.723 v1(82.072,244.81) ; T5.2@83.342,243.723 v1(83.342,244.81) ; T5.3@84.612,243.723 v1(84.612,244.81)
  other v1: 88.711,238.28 89.517,238.28 90.322,238.28 91.128,238.28 91.934,238.28 92.74,238.28 75.09,238.992 76.342,238.992 77.593,238.992 78.845,238.992 82.09,238.992 83.342,238.992 84.593,238.992 85.845,238.992 88.711,239.086 89.517,239.086 90.322,239.086 91.128,239.086 91.934,239.086 92.74,239.086 88.711,239.892 89.517,239.892 90.322,239.892 91.128,239.892 91.934,239.892 92.74,239.892 75.09,240.244 76.342,240.244 77.593,240.244 78.845,240.244 82.09,240.244 83.342,240.244 84.593,240.244 85.845,240.244 88.711,240.697 89.517,240.697 90.322,240.697 91.128,240.697 91.934,240.697 92.74,240.697 75.09,241.496 76.342,241.496 77.593,241.496 78.845,241.496 82.09,241.496 83.342,241.496 84.593,241.496 85.845,241.496 88.711,241.503 89.517,241.503 90.322,241.503 91.128,241.503 91.934,241.503 92.74,241.503 88.711,242.309 89.517,242.309 90.322,242.309 91.128,242.309 91.934,242.309 92.74,242.309 89.212,244.228 90.018,244.228 90.823,244.228 91.629,244.228 92.435,244.228 88.788,244.811 89.594,244.811 90.4,244.811 91.206,244.811 92.011,244.811 92.817,244.811
SW1_1: C390.2 L11.1 R288.2 R619.2 T13.1 T13.2 T13.3 T14.5 T14.6 T14.7 T14.8 U37.24 | length 7.6
  L1 w0.5: T14.5@80.039,184.15 v1(81.126,184.15) ; T14.6@80.039,185.42 v1(81.126,185.42) ; T14.7@80.039,186.69 v1(81.126,186.69) ; T14.8@80.039,187.96 v1(81.126,187.96) ; T13.1@80.042,178.003 v1(81.129,178.003) ; T13.2@80.042,179.273 v1(81.129,179.273) ; T13.3@80.042,180.543 v1(81.129,180.543)
  other v1: 76.718,184.187 77.97,184.187 79.221,184.187 76.718,185.438 77.97,185.438 79.221,185.438 76.718,186.69 77.97,186.69 79.221,186.69 76.718,187.942 77.97,187.942 79.221,187.942
SW1_2: C431.2 L19.1 R306.2 R625.1 T17.1 T17.2 T17.3 T18.5 T18.6 T18.7 T18.8 U38.24 | length 11.2
  L1 w0.254: U38.24@65.953,208.214 67.293,208.214 67.758,208.68 C431.2@67.758,209.091 ; R625.1@67.001,210.879 67.377,210.879 67.781,210.475 C431.2@67.781,209.114 68.392,209.114 69.532,210.254 ; 77.166,206.68 77.677,207.192 77.677,207.477
  L1 w0.5: v1(79.911,214.079) T17.1@80.998,214.079 ; v1(79.911,215.349) T17.2@80.998,215.349 ; v1(79.911,216.619) T17.3@80.998,216.619
  other v1: 77.677,207.834 78.929,207.834 80.18,207.834 77.677,209.086 78.929,209.086 80.18,209.086 77.677,210.337 78.929,210.337 80.18,210.337 77.677,211.589 78.929,211.589 80.18,211.589
SW2: C350.2 L10.1 R611.2 R616.2 T9.1 T9.2 T9.3 T10.1 T10.2 T10.3 T11.5 T11.6 T11.7 T11.8 T12.5 T12.6 T12.7 T12.8 U34.17 | length 18.5
  L1 w0.254: R611.2@67.113,230.147 67.513,230.147 67.688,230.322 C350.2@68.072,230.322 ; U34.17@67.322,233.639 68.085,233.639 68.854,232.87 68.854,230.471 68.705,230.322 C350.2@68.072,230.322 ; C350.2@68.072,230.317 C350.2@68.072,230.322 ; 73.69,229.73 68.663,229.73 C350.2@68.072,230.322
  L1 w0.5: v1(76.348,226.414) T10.3@76.348,227.501 ; v1(77.618,226.414) T10.2@77.618,227.501 ; v1(78.888,226.414) T10.1@78.888,227.501 ; v1(83.342,226.414) T9.3@83.342,227.501 ; v1(84.612,226.414) T9.2@84.612,227.501 ; v1(85.882,226.414) T9.1@85.882,227.501
  other v1: 88.597,226.45 89.402,226.45 90.208,226.45 91.014,226.45 91.82,226.45 92.625,226.45 88.979,227.033 89.785,227.033 90.59,227.033 91.396,227.033 92.202,227.033 88.674,228.952 89.48,228.952 90.286,228.952 91.091,228.952 91.897,228.952 92.703,228.952 75.108,229.757 76.36,229.757 77.612,229.757 78.863,229.757 82.108,229.757 83.36,229.757 84.612,229.757 85.863,229.757 88.674,229.758 89.48,229.758 90.286,229.758 91.091,229.758 91.897,229.758 92.703,229.758 88.674,230.564 89.48,230.564 90.286,230.564 91.091,230.564 91.897,230.564 92.703,230.564 75.108,231.008 76.36,231.008 77.612,231.008 78.863,231.008 82.108,231.008 83.36,231.008 84.612,231.008 85.863,231.008 88.674,231.369 89.48,231.369 90.286,231.369 91.091,231.369 91.897,231.369 92.703,231.369 88.674,232.175 89.48,232.175 90.286,232.175 91.091,232.175 91.897,232.175 92.703,232.175 75.108,232.26 76.36,232.26 77.612,232.26 78.863,232.26 82.108,232.26 83.36,232.26 84.612,232.26 85.863,232.26 88.674,232.981 89.48,232.981 90.286,232.981 91.091,232.981 91.897,232.981 92.703,232.981
SW2_1: C394.2 L12.1 R298.2 R620.2 T15.1 T15.2 T15.3 T16.5 T16.6 T16.7 T16.8 U37.17 | length 7.6
  L1 w0.5: T15.1@79.789,163.201 v1(80.876,163.201) ; T15.2@79.789,164.471 v1(80.876,164.471) ; T15.3@79.789,165.741 v1(80.876,165.741) ; T16.5@79.835,169.38 v1(80.922,169.38) ; T16.6@79.835,170.65 v1(80.922,170.65) ; T16.7@79.835,171.92 v1(80.922,171.92) ; T16.8@79.835,173.19 v1(80.922,173.19)
  other v1: 76.514,169.417 77.766,169.417 79.017,169.417 76.514,170.668 77.766,170.668 79.017,170.668 76.514,171.92 77.766,171.92 79.017,171.92 76.514,173.172 77.766,173.172 79.017,173.172
SW2_2: C435.2 L20.1 R302.1 R316.2 T19.1 T19.2 T19.3 T20.5 T20.6 T20.7 T20.8 U38.17 | length 12.3
  L1 w0.254: U38.17@65.953,204.714 67.394,204.714 67.796,204.312 C435.2@67.796,203.864 ; R302.1@66.453,202.163 66.794,202.163 67.796,203.166 C435.2@67.796,203.864 ; 70.746,200.92 C435.2@67.796,203.864
  L1 w0.5: v1(79.842,193.746) T19.1@80.929,193.746 ; v1(79.842,195.016) T19.2@80.929,195.016 ; v1(79.842,196.286) T19.3@80.929,196.286
  other v1: 77.578,200.189 78.83,200.189 80.081,200.189 77.578,201.44 78.83,201.44 80.081,201.44 77.578,202.692 78.83,202.692 80.081,202.692 77.578,203.944 78.83,203.944 80.081,203.944
SYNC_WR_R: R904.1 U1.C12 | length 4.8
  L1 w0.116: 163.909,300.027 U1.C12@164.397,299.539
  L1 w0.12: 160.503,301.028 162.635,301.028 162.902,300.761 162.902,300.254 163.129,300.027 163.909,300.027
TD_A_N: D1.2 D1.7 T21.10 U39.2 | length 86
  L1 w0.081: v1(61.087,249.283) 61.094,249.276 62.186,249.276 D1.7@62.528,249.618 62.87,249.276 67.686,249.276 D1.2@68.028,249.618 68.37,249.276 69.493,249.276 v1(69.5,249.283)
  L14 (Sign) w0.08: T21.10@50.092,244.096 50.092,243.509 ccw(c50.33,243.509) 50.33,243.271 50.968,243.271 ccw(c50.968,243.561) 51.257,243.561 51.257,244.093 cw(c51.892,244.093) 51.892,244.728 56.717,244.728 ccw(c56.717,245.745) 57.734,245.745 57.734,248.166 cw(c58.742,248.166) 58.742,249.173 60.977,249.173 v1(61.087,249.283) ; v1(69.5,249.283) ccw(c69.61,249.283) 69.61,249.173 71.959,249.173 ccw(c71.959,249.936) 72.721,249.936 72.721,251.117 cw(c73.968,251.117) 73.968,252.363 76.314,252.363 ccw(c76.314,253.584) 77.535,253.584 77.535,274.714 cw(c79.036,274.714) 79.036,276.215 103.662,276.215 ccw(c103.662,276.325) v9(103.772,276.325)
  L16 w0.081: v9(103.772,276.325) 103.772,276.318 104.559,276.318 ccw(c104.602,276.318) 104.602,276.275 U39.2@104.899,276.275
TD_A_P: D1.1 D1.8 T21.11 U39.1 | length 86
  L1 w0.081: v1(61.087,248.684) 61.094,248.691 62.186,248.691 D1.8@62.528,248.349 62.87,248.691 67.686,248.691 D1.1@68.028,248.349 68.37,248.691 69.493,248.691 v1(69.5,248.684)
  L14 (Sign) w0.08: T21.11@50.092,242.066 50.092,242.653 cw(c50.33,242.653) 50.33,242.891 50.968,242.891 ccw(c50.968,243.561) 51.637,243.561 51.637,244.093 cw(c51.892,244.093) 51.892,244.348 56.717,244.348 ccw(c56.717,245.745) 58.114,245.745 58.114,248.166 cw(c58.742,248.166) 58.742,248.794 60.977,248.794 v1(61.087,248.684) ; v1(69.5,248.684) cw(c69.61,248.684) 69.61,248.794 71.959,248.794 ccw(c71.959,249.936) 73.101,249.936 73.101,251.117 cw(c73.968,251.117) 73.968,251.984 76.314,251.984 ccw(c76.314,253.584) 77.915,253.584 77.915,274.714 cw(c79.036,274.714) 79.036,275.835 103.662,275.835 cw(c103.662,275.725) v9(103.772,275.725)
  L16 w0.081: v9(103.772,275.725) 103.772,275.732 104.559,275.732 cw(c104.602,275.732) 104.602,275.775 U39.1@104.899,275.775
TD_B_N: D1.4 D1.5 T21.5 U39.5 | length 91.3
  L1 w0.081: v1(61.087,251.823) 61.087,251.816 62.186,251.816 ccw(c62.186,252.118) 62.487,252.118 D1.5@62.528,252.159 62.87,251.816 67.686,251.816 D1.4@68.028,252.159 68.37,251.816 69.493,251.816 v1(69.5,251.823)
  L14 (Sign) w0.08: T21.5@47.552,243.081 47.552,243.566 ccw(c47.168,243.566) 47.168,243.95 cw(c47.168,244.889) 46.229,244.889 46.229,245.11 cw(c47.42,245.11) 47.42,246.301 56.208,246.301 ccw(c56.208,246.661) 56.567,246.661 56.567,250.685 cw(c57.595,250.685) 57.595,251.713 60.977,251.713 ccw(c60.977,251.823) v1(61.087,251.823) ; v1(69.5,251.823) ccw(c69.61,251.823) 69.61,251.713 71.107,251.713 ccw(c71.107,252.235) 71.628,252.235 cw(c72.948,252.235) 72.948,253.554 75.005,253.554 ccw(c75.005,254.711) 76.162,254.711 76.162,274.795 cw(c79.082,274.795) 79.082,277.715 103.662,277.715 ccw(c103.662,277.825) v9(103.772,277.825)
  L16 w0.081: v9(103.772,277.825) 103.772,277.818 104.559,277.818 ccw(c104.602,277.818) 104.602,277.775 U39.5@104.899,277.775
TD_B_P: D1.3 D1.6 T21.4 U39.4 | length 90
  L1 w0.081: v1(61.087,251.224) 61.087,251.231 62.186,251.231 cw(c62.186,250.929) 62.487,250.929 D1.6@62.528,250.888 62.87,251.231 67.686,251.231 D1.3@68.028,250.888 68.37,251.231 69.493,251.231 v1(69.5,251.224)
  L14 (Sign) w0.08: T21.4@47.552,245.111 47.552,244.714 cw(c47.168,244.714) 47.168,244.33 cw(c47.168,244.889) 46.609,244.889 46.609,245.11 cw(c47.436,245.11) 47.436,245.937 56.223,245.937 ccw(c56.223,246.661) 56.947,246.661 56.947,250.685 cw(c57.595,250.685) 57.595,251.334 60.977,251.334 cw(c60.977,251.224) v1(61.087,251.224) ; v1(69.5,251.224) cw(c69.61,251.224) 69.61,251.334 71.107,251.334 ccw(c71.107,252.235) 72.008,252.235 cw(c72.948,252.235) 72.948,253.174 75.005,253.174 ccw(c75.005,254.711) 76.542,254.711 76.542,274.795 cw(c79.082,274.795) 79.082,277.335 103.662,277.335 cw(c103.662,277.225) v9(103.772,277.225)
  L16 w0.081: v9(103.772,277.225) 103.772,277.232 104.559,277.232 cw(c104.602,277.232) 104.602,277.275 U39.4@104.899,277.275
TD_C_N: D2.2 D2.7 T21.2 U39.8 | length 89.2
  L1 w0.081: v1@61.087,255.359 62.243,255.359 ccw(c62.243,255.604) 62.487,255.604 cw(c62.626,255.604) D2.7@62.528,255.702 62.87,255.359 67.686,255.359 D2.2@68.028,255.702 68.37,255.359 69.493,255.359 v1(69.5,255.367)
  L14 (Sign) w0.08: T21.2@47.552,249.171 47.552,249.066 ccw(c48.273,249.066) 48.273,248.346 48.439,248.346 cw(c48.439,247.688) 49.097,247.688 49.097,247.495 ccw(c49.336,247.495) 49.336,247.256 54.178,247.256 ccw(c54.178,247.98) 54.902,247.98 54.902,252.324 cw(c57.822,252.324) 57.822,255.243 60.977,255.243 ccw(c60.977,255.354) v1(61.087,255.354) ; v1(69.5,255.367) ccw(c69.61,255.367) 69.61,255.257 74.511,255.257 ccw(c74.511,255.677) 74.931,255.677 74.931,278.282 cw(c75.864,278.282) 75.864,279.215 103.674,279.215 ccw(c103.674,279.325) v9(103.784,279.325)
  L16 w0.081: v9(103.784,279.325) 103.784,279.318 104.559,279.318 ccw(c104.602,279.318) 104.602,279.275 U39.8@104.899,279.275
TD_C_P: D2.1 D2.8 T21.3 U39.7 | length 89.2
  L1 w0.081: v1(61.087,254.754) cw(c61.108,254.754) 61.108,254.774 62.243,254.774 cw(c62.243,254.53) 62.487,254.53 ccw(c62.626,254.53) D2.8@62.528,254.432 62.87,254.774 67.686,254.774 D2.1@68.028,254.432 68.37,254.774 69.493,254.774 v1(69.5,254.767)
  L14 (Sign) w0.08: T21.3@47.552,247.141 47.552,247.246 cw(c48.273,247.246) 48.273,247.966 48.439,247.966 cw(c48.439,247.688) 48.717,247.688 48.717,247.495 ccw(c49.336,247.495) 49.336,246.876 54.178,246.876 ccw(c54.178,247.98) 55.282,247.98 55.282,252.324 cw(c57.822,252.324) 57.822,254.864 60.977,254.864 cw(c60.977,254.754) v1(61.087,254.754) ; v1(69.5,254.767) cw(c69.61,254.767) 69.61,254.877 74.511,254.877 ccw(c74.511,255.677) 75.311,255.677 75.311,278.282 cw(c75.864,278.282) 75.864,278.835 103.674,278.835 cw(c103.674,278.725) v9(103.784,278.725)
  L16 w0.081: v9(103.784,278.725) 103.784,278.732 104.559,278.732 cw(c104.602,278.732) 104.602,278.775 U39.7@104.899,278.775
TD_D_N: D2.4 D2.5 T21.9 U39.11 | length 87.7
  L1 w0.081: v1(61.056,257.907) 61.063,257.899 62.186,257.899 D2.5@62.528,258.242 62.87,257.899 67.686,257.899 D2.4@68.028,258.242 68.37,257.899 69.493,257.899 v1(69.5,257.907)
  L14 (Sign) w0.08: T21.9@50.092,248.156 50.092,248.575 ccw(c49.657,248.575) 49.657,249.01 49.276,249.01 cw(c49.276,249.671) 48.615,249.671 48.615,254.877 cw(c51.535,254.877) 51.535,257.797 60.946,257.797 v1(61.056,257.907) ; v1(69.5,257.907) 69.61,257.797 71.158,257.797 ccw(c71.158,260.071) 73.431,260.071 73.431,279.171 cw(c74.992,279.171) 74.992,280.732 103.692,280.732 ccw(c103.692,280.825) v9(103.784,280.825)
  L16 w0.081: v9(103.784,280.825) 103.784,280.818 104.559,280.818 ccw(c104.602,280.818) 104.602,280.775 U39.11@104.899,280.775
TD_D_P: D2.3 D2.6 T21.8 U39.10 | length 86.5
  L1 w0.081: v1(61.056,257.307) 61.063,257.314 62.186,257.314 D2.6@62.528,256.972 62.87,257.314 67.686,257.314 D2.3@68.028,256.972 68.37,257.314 69.493,257.314 v1(69.5,257.307)
  L14 (Sign) w0.08: T21.8@50.092,250.186 50.092,249.825 cw(c49.657,249.825) 49.657,249.39 49.276,249.39 cw(c49.276,249.671) 48.995,249.671 48.995,254.877 cw(c51.535,254.877) 51.535,257.417 60.946,257.417 v1(61.056,257.307) ; v1(69.5,257.307) 69.61,257.417 71.158,257.417 ccw(c71.158,260.071) 73.811,260.071 73.811,279.171 cw(c74.992,279.171) 74.992,280.352 103.657,280.352 cw(c103.657,280.225) v9(103.784,280.225)
  L16 w0.081: v9(103.784,280.225) 103.784,280.232 104.559,280.232 cw(c104.602,280.232) 104.602,280.275 U39.10@104.899,280.275
TTC_0: R810.1
TTC_3: R804.1
uart0_RxD: R779.1 U57.12
uart0_TxD: R778.1 U57.11
uart1_RxD: R776.1 U57.13
uart1_TxD: R777.1 U57.14
uart_FPGA_RxD_R: R909.1 U1.B12 | length 3.3
  L1 w0.116: 162.543,300.027 163.031,299.539 U1.B12@163.397,299.539
  L1 w0.12: 160.337,300.027 162.543,300.027
uart_FPGA_TxD_R: R910.1 U1.A12 | length 1.8
  L1 w0.12: 160.574,299.539 U1.A12@162.397,299.539
US2_FTDI_UART1_RXD: R910.2 U79.13
US2_FTDI_UART1_TXD: R909.2 U79.14
US+_DxN: R279.1 R286.1 U1.V15
  other v5: 179.397,302.539
US+_DxP: R282.1 R283.1 U1.V14
  other v5: 179.397,301.539
US+_GND_PS_ADC: C627.1 C628.1 FB39.2 U1.W21
  other v5: 180.397,308.539
US+_GNDADC: C629.1 C630.1 FB41.2 U1.R14 U1.U14 U1.U15
  other v5: 176.397,301.539 178.397,301.539 178.397,302.539
US+_MGTRref: R173.1 U1.K7
  other v2: 171.397,294.539
US+_MGTRref_K8: R695.2 U1.K8
  other v2: 171.397,295.539
US+_MGTVccAux: C605.2 C606.2 C607.2 C610.2 C611.2 C756.2 C759.2 L16.2 R212.2 R363.1 R364.1 R365.1 R515.1 R522.1 R523.2 R531.1 R546.2 R548.1 R549.2 R551.1 R552.2 R554.1 R555.2 R557.1 R607.2 R659.1 R660.2 R661.1 R662.2 R663.1 R664.2 R735.1 R736.2 R765.1 R766.2 R817.1 R818.2 R820.1 R821.2 R823.1 R824.2 R847.1 R848.2 R849.1 R850.2 R852.1 R853.2 R855.1 R856.2 R858.1 R859.2 R861.2 R921.1 R922.2 R923.1 R924.2 R925.1 R926.2 R927.1 R928.2 R929.1 R930.2 R931.1 R932.2 R933.1 R934.2 R935.1 R936.2 R937.1 R938.2 R939.1 R940.2 R941.1 R942.2 R943.1 R944.2 R945.1 R946.2 R947.1 R948.2 R949.1 R950.2 R951.1 R952.2 R953.1 R954.2 R955.1 R956.2 R957.1 R958.2 R959.1 R960.2 U1.AA4 U1.AC15 U1.AD3 U1.AD8 U1.AE11 U1.AF14 U1.AG7 U1.AG17 U1.AH10 U1.D13 U1.E10 U1.E16 U1.G10 U1.G12 U1.H15 U1.H25 U1.K25 U1.L27 U15.1 U15.7 U15.8 U15.16 U36_U_Translator_I2C1.2 U36_U_Translator_I2C4.2 U79.15 | length 27.3
  L1 w0.254: L16.2@156.819,174.442 156.835,174.458 v10(160.468,174.458) ; R212.2@182.642,172.415 v10(182.642,173.417)
  L3 (Sign) w0.254: v10(160.468,174.458) 181.602,174.458 v10(182.642,173.417)
  other v2: 166.397,297.539 168.397,297.539
  other v5: 182.397,291.539 168.397,299.539 165.397,300.539 184.397,302.539 188.397,304.539
US+_POR_OVE: R693.1 U1.Y6
  other v5: 181.397,293.539
US+_Pudc_B: R694.2 R696.1 U1.W7
  other v5: 180.397,294.539
US+_Vcc_PS_ADC: C627.2 C628.2 FB38.2 U1.W22 | length 1.8
  L1 w0.254: v1(198.768,309.397) 198.819,309.448 FB38.2@200.559,309.448
  other v5: 180.397,309.539
US+_Vcc_PS_Batt: B1.1 C747.1 C748.2 R276.1 U1.U20
  other v5: 178.397,307.539
US+_Vcc_PS_DDR_504: C616.2 C617.2 C618.2 C619.2 C620.2 C621.2 C622.2 C753.1 C754.2 C755.2 L18.2 R220.2 U1.AA24 U1.AB27 U1.AC25 U1.AD28 U1.AE26 U1.AG27 U1.AK26 | length 31.4
  L1 w0.116: v4(182.909,315.027) U1.AB27@183.397,314.539 ; v4(183.91,312.052) U1.AC25@184.397,312.539 ; v4(184.91,315.052) U1.AD28@185.397,315.539 ; U1.AE26@186.397,313.539 v4(186.884,314.027) ; v4(187.909,315.027) U1.AG27@188.397,314.539 ; U1.AK26@191.397,313.539 v4(191.884,314.027)
  L1 w0.254: 166.401,157.07 177.861,157.07 180.059,159.268 180.059,168.365 R220.2@179.984,168.44 179.434,168.44 179.184,168.69 C616.2@179.174,168.69
  L3 (Sign) w0.254: v4(182.909,315.027) v20@182.909,315.531 ; v4(183.91,312.052) v20@184.266,312.408 ; v4(184.91,315.052) v20@184.91,315.556 ; v20(187.897,315.544) 187.909,315.531 v4(187.909,315.027) ; v4(191.884,314.027) v20@192.241,313.671
  other v20: 184.266,312.427 192.259,313.67 182.897,315.544 184.897,315.569
US+_Vcc_PS_DDR_PLL: C631.2 C632.2 FB42.2 U1.U18 U1.U19
  other v5: 178.397,305.539 178.397,306.539
US+_Vcc_PS_IntFp: C738.1 C739.1 C740.2 C744.2 C745.2 C751.1 C752.2 C762.1 C763.2 R271.2 R617.2 U1.AA18 U1.AA20 U1.AA21 U1.AA22 U1.L11 U1.L13 U1.L17 U1.M12 U1.M14 U1.M16 U1.M18 U1.N11 U1.N13 U1.N15 U1.N17 U1.P12 U1.P14 U1.P16 U1.R10 U1.R11 U1.R13 U1.R17 U1.T9 U1.T10 U1.T12 U1.T16 U1.U8 U1.U9 U1.U10 U1.U11 U1.U13 U1.U17 U1.V8 U1.V10 U1.V12 U1.V16 U1.V17 U1.V18 U1.V19 U1.W11 U1.W13 U1.W15 U1.W17 U1.W19 U1.W20 U1.Y12 U1.Y14 U1.Y16 U1.Y17 U1.Y18 U1.Y19 U1.Y20 U1.Y22 U72.8 U72.9
  other v2: 178.397,295.539 179.397,295.539 177.397,296.539 178.397,296.539 176.397,297.539 177.397,297.539 178.397,297.539 179.397,297.539 172.397,298.539 174.397,298.539 176.397,298.539 178.397,298.539
  other v5: 180.397,298.539 173.397,299.539 175.397,299.539 177.397,299.539 179.397,299.539 181.397,299.539 172.397,300.539 174.397,300.539 176.397,300.539 178.397,300.539 180.397,300.539 173.397,301.539 175.397,301.539 181.397,301.539 174.397,302.539 180.397,302.539 173.397,303.539 175.397,303.539 177.397,303.539 179.397,303.539 181.397,303.539 172.397,304.539 174.397,304.539 176.397,304.539 178.397,304.539 179.397,304.539 180.397,304.539 181.397,304.539 173.397,305.539 179.397,305.539 181.397,305.539 182.397,305.539 179.397,306.539 180.397,306.539 181.397,306.539 180.397,307.539 181.397,307.539 182.397,307.539 182.397,308.539 181.397,309.539 182.397,309.539
  other v8: 142.777,289.801 144.53,289.801 146.282,289.801 139.272,289.801 141.025,289.801 139.272,291.554 141.025,291.554 142.777,291.554 144.53,291.554 146.282,291.554 142.777,293.306 144.53,293.306 146.282,293.306 139.272,293.306 141.025,293.306 139.272,295.059 141.025,295.059 142.777,295.059 144.53,295.059 146.282,295.059 142.777,296.812 144.53,296.812 146.282,296.812 139.272,296.812 141.025,296.812 139.272,298.564 141.025,298.564 142.777,298.564 144.53,298.564 146.282,298.564 142.777,300.317 144.53,300.317 146.282,300.317 139.272,300.317 141.025,300.317 139.272,302.07 141.025,302.07 142.777,302.069 144.53,302.069 146.282,302.069
US+_Vcc_PS_IntFpDDR: C764.1 C765.2
US+_VccADC: C629.2 C630.2 FB40.2 U1.R15
  other v5: 176.397,302.539
US+_VN: J29.1 U1.T15
  other v5: 177.397,302.539
US+_VP: J29.2 U1.T14
  other v5: 177.397,301.539
US_PADI: C535.2 R374.1 U1.M21 X5.1 | length 3.5
  L1 w0.2: X5.1@149.646,342.666 X5.1@149.626,342.646 C535.2@149.626,340.855 149.626,340.138 150.001,339.763 R374.1@150.426,339.763
  other v5: 173.397,308.539
US_PADO: C536.2 R374.2 U1.N21 X5.2 | length 3.5
  L1 w0.2: R374.2@151.326,339.763 151.751,339.763 152.126,340.138 C536.2@152.126,340.855 X5.2@152.126,342.646
  other v5: 174.397,308.539
US_PS_DONE: R357.1 U1.N22 U43.6
  other v5: 174.397,309.539
US_PS_Err_Out: U1.R22 U43.3
  other v5: 176.397,309.539
US_PS_Err_Status: U1.R20 U43.4
  other v5: 176.397,307.539
US_PS_Init_B: R353.2 U1.N18 U43.5
  other v5: 174.397,305.539
US_PS_JTAG_TCK: R346.2 R1028.2 U1.L19 | length 0.7
  L1 w0.116: U1.L19@172.397,306.539 172.884,306.052
US_PS_JTAG_TDI: R347.2 R1026.2 U1.L20 | length 0.7
  L1 w0.116: U1.L20@172.397,307.539 172.884,307.052
US_PS_JTAG_TDO: R1029.2 U1.M20
  other v5: 173.397,307.539
US_PS_JTAG_TMS: R348.2 R1027.2 U1.L21 | length 0.7
  L1 w0.116: U1.L21@172.397,308.539 172.884,308.052
US_PS_Mode0: P2.4 R349.1 S1.1 U1.R18
  other v5: 176.397,305.539
US_PS_Mode2: P2.2 R351.1 S1.3 U1.P21
  other v5: 175.397,308.539
US_PS_Mode3: P2.1 R352.1 S1.4 U1.P22
  other v5: 175.397,309.539
US_PS_Prog_B: R356.2 R367.1 S2.1 S2.2 U1.M19
  other v5: 173.397,306.539
US_PS_Ref_Clk: R375.2 U1.P19
  other v5: 175.397,306.539
USB2_CLK: R362.2 U45.1 | length 5.8
  L1 w0.12: U45.1@56.09,344.002 56.81,344.002 57.563,343.249 57.563,342.742 59.615,340.69 R362.2@60.193,340.69
USB2_D0: R116.2 U45.3 | length 4.9
  L1 w0.12: U45.3@56.09,345.002 57.626,345.002 59.655,342.973 R116.2@60.193,342.973
USB2_D1: R117.2 U45.4 | length 4.7
  L1 w0.12: U45.4@56.09,345.502 58.129,345.502 59.517,344.114 R117.2@60.193,344.114
USB2_D2: R115.2 U45.5 | length 4.4
  L1 w0.12: U45.5@56.09,346.002 58.366,346.002 59.113,345.255 R115.2@60.193,345.255
USB2_D3: R119.2 U45.6 | length 4.1
  L1 w0.12: U45.6@56.09,346.502 58.691,346.502 58.797,346.396 R119.2@60.193,346.396
USB2_D4: R120.2 U45.7 | length 4.3
  L1 w0.12: U45.7@56.09,347.002 56.693,347.002 57.228,347.538 R120.2@60.193,347.538
USB2_D5: R121.2 U45.9 | length 5.7
  L1 w0.12: U45.9@55.39,348.202 55.39,348.669 56.541,349.82 R121.2@60.193,349.82
USB2_D6: R122.2 U45.10 | length 6.8
  L1 w0.12: U45.10@54.89,348.202 54.89,348.882 56.969,350.961 R122.2@60.193,350.961
USB2_D7: R802.1 U45.13 | length 10.1
  L1 w0.12: U45.13@53.39,348.202 53.39,348.995 53.657,349.263 53.657,351.409 54.351,352.103 R802.1@60.193,352.103
USB2_DIR: R800.1 U45.31 | length 7.1
  L1 w0.12: U45.31@54.89,343.302 54.89,342.694 55.352,342.231 56.726,342.231 59.436,339.522 R800.1@60.104,339.522
USB2_NXT: R801.1 U45.2 | length 5.2
  L1 w0.12: U45.2@56.09,344.502 56.922,344.502 59.593,341.831 R801.1@60.193,341.831
USB2_STP: R118.2 U45.29 | length 9
  L1 w0.12: U45.29@53.89,343.302 53.89,342.198 54.305,341.782 55.994,341.782 59.444,338.332 R118.2@60.193,338.332
USB_D_N: C537.2 D13.2 U45.19 | length 20.5
  L1 w0.1: v1(46.977,346.452) cw(c47.072,346.452) 47.072,346.547 50.765,346.547 ccw(c50.81,346.547) 50.81,346.502 U45.19@51.19,346.502
  L16 w0.1: C537.2@37.721,351.698 ccw(c39.29,353.267) 39.29,351.048 D13.2@40.723,351.048 40.868,350.903 41.273,350.903 41.273,350.91 41.361,350.998 41.785,350.998 41.873,350.91 41.873,350.903 46.939,350.903 cw(c46.939,349.184) 48.657,349.184 48.657,347.586 cw(c47.618,347.586) 47.618,346.547 47.072,346.547 ccw(c47.072,346.452) v1(46.977,346.452)
USB_D_P: C537.3 D13.1 U45.18 | length 19.2
  L1 w0.1: v1(46.977,347.052) ccw(c47.072,347.052) 47.072,346.957 50.765,346.957 cw(c50.81,346.957) 50.81,347.002 U45.18@51.19,347.002
  L16 w0.1: C537.3@37.721,349.698 cw(c39.29,348.129) 39.29,350.348 D13.1@40.723,350.348 40.868,350.493 41.273,350.493 41.273,350.486 41.361,350.398 41.785,350.398 41.873,350.486 41.873,350.493 46.939,350.493 cw(c46.939,349.184) 48.247,349.184 48.247,347.586 cw(c47.618,347.586) 47.618,346.957 47.072,346.957 cw(c47.072,347.052) v1(46.977,347.052)
USB_En_Vout: U45.17 U46.A2
USB_OSC_IN: C736.2 R491.1 U45.26 X7.1 | length 8.5
  L1 w0.12: C736.2@51.651,336.873 50.946,337.579 X7.1@50.211,337.579 50.011,337.779 R491.1@50.011,339.152 50.011,339.787 52.39,342.166 U45.26@52.39,343.302
USB_OSC_Out: C737.2 R491.2 U45.25 X7.3 | length 11.1
  L1 w0.12: C737.2@46.241,336.354 47.636,336.354 X7.3@48.011,335.979 48.476,335.979 49.111,336.613 R491.2@49.111,339.152 49.111,339.941 51.89,342.72 U45.25@51.89,343.302
USB_RS0: R376.1 U45.8 | length 4.6
  L1 w0.12: U45.8@56.09,347.502 56.317,347.502 57.484,348.67 R376.1@60.193,348.67
USB_RS1: R377.1 U45.11
USB_RS2: R378.1 U45.14
USB_RX_C_N: C537.5 C543.2 D14.1 D14.10 | length 10
  L1 w0.1: v1(40.276,349.009) cw(c40.6,349.009) 40.371,349.238 40.45,349.317 cw(c41.522,348.244) 41.522,349.761 D14.10@41.874,349.761 ; D14.1@42.708,349.761 cw(c42.817,349.653) 42.817,349.806 43.256,349.806 cw(c43.256,349.207) 43.68,349.631 43.744,349.567 ccw(c44.245,350.068) 44.245,349.359 44.806,349.359 cw(c44.806,348.679) 45.286,349.16 C543.2@45.33,349.116
  L12 (Sign) w0.1: C537.5@36.22,346.698 36.22,347.364 cw(c36.373,347.364) 36.373,347.517 36.375,347.517 ccw(c36.375,348.459) 37.04,347.793 37.205,347.957 cw(c37.935,347.227) 37.935,348.259 38.429,348.259 ccw(c38.429,350.504) 40.016,348.917 40.017,348.918 cw(c40.237,348.698) 40.237,349.009 v1(40.276,349.009)
USB_RX_C_P: C537.6 C542.2 D14.2 D14.9 | length 10
  L1 w0.1: v1(39.852,349.433) ccw(c39.852,349.757) 40.081,349.528 40.161,349.608 cw(c41.738,348.03) 41.738,350.261 D14.9@41.874,350.261 ; D14.2@42.709,350.261 ccw(c42.817,350.37) 42.817,350.216 43.258,350.216 cw(c43.258,349.211) 43.969,349.922 44.032,349.858 ccw(c44.247,350.073) 44.247,349.769 44.806,349.769 ccw(c44.806,350.449) 45.286,349.968 C542.2@45.33,350.012
  L12 (Sign) w0.1: C537.6@36.22,348.698 36.22,348.031 ccw(c36.373,348.031) 36.373,347.879 ccw(c36.373,348.463) 36.786,348.05 36.951,348.215 cw(c37.932,347.234) 37.932,348.622 38.427,348.622 ccw(c38.427,350.507) 39.76,349.174 ccw(c39.54,349.394) 39.852,349.394 v1(39.852,349.433)
USB_RX_N: C543.1 U1.J25 | length 158.3
  L1 w0.1: C543.1@46.11,349.116 46.192,349.116 ccw(c46.192,349.359) 46.435,349.359 49.499,349.359 cw(c49.499,349.264) v1(49.593,349.264)
  L1 w0.116: v5(169.909,313.027) U1.J25@170.397,312.539
  L5 (Sign) w0.1: v1(49.593,349.264) cw(c49.712,349.264) 49.712,349.383 122.066,349.383 cw(c122.066,347.052) 124.396,347.052 124.396,322.567 ccw(c127.299,322.567) 127.299,319.665 167.85,319.665 cw(c167.85,319.087) 168.427,319.087 168.427,316.531 cw(c167.987,316.531) 168.298,316.219 ccw(c168.892,315.626) 168.052,315.626 168.052,315.11 ccw(c169.605,315.11) 168.507,314.012 168.886,313.633 ccw(c169.58,314.327) 169.58,313.346 169.761,313.346 cw(c169.761,313.197) 169.909,313.197 v5(169.909,313.027)
USB_RX_P: C542.1 U1.J26 | length 158.3
  L1 w0.1: C542.1@46.11,350.012 46.192,350.012 cw(c46.192,349.769) 46.435,349.769 49.499,349.769 ccw(c49.499,349.864) v1(49.593,349.864)
  L1 w0.116: v5(169.909,314.027) U1.J26@170.397,313.539
  L5 (Sign) w0.1: v1(49.593,349.864) ccw(c49.712,349.864) 49.712,349.745 122.066,349.745 cw(c122.066,347.052) 124.759,347.052 124.759,322.567 ccw(c127.299,322.567) 127.299,320.027 167.85,320.027 cw(c167.85,319.087) 168.79,319.087 168.79,316.531 cw(c167.987,316.531) 168.554,315.963 ccw(c168.892,315.626) 168.415,315.626 168.415,315.112 ccw(c169.61,315.112) 168.765,314.267 169.141,313.891 ccw(c169.583,314.334) 169.583,313.708 169.761,313.708 ccw(c169.761,313.857) 169.909,313.857 v5(169.909,314.027)
USB_TX_C_N: C537.8 C541.2 D14.4 D14.7 | length 10.1
  L1 w0.1: v1(40.042,351.954) cw(c40.042,351.629) 40.271,351.859 40.348,351.782 ccw(c41.604,353.038) 41.604,351.261 D14.7@41.874,351.261 ; D14.4@42.708,351.261 42.996,351.261 ccw(c42.996,351.306) 43.041,351.306 43.828,351.306 ccw(c43.828,352.131) 44.411,351.548 ; 44.412,351.549 cw(c44.629,351.331) 44.629,351.639 44.92,351.639 cw(c44.92,351.234) 45.206,351.52 C541.2@45.33,351.396
  L12 (Sign) w0.1: C537.8@36.22,352.698 36.22,353.39 cw(c36.347,353.39) 36.347,353.517 cw(c36.347,353.423) 36.413,353.489 36.755,353.147 ccw(c37.718,354.11) 37.718,352.749 39.191,352.749 cw(c39.191,352.207) 39.573,352.59 40.042,352.122 v1(40.042,351.954)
